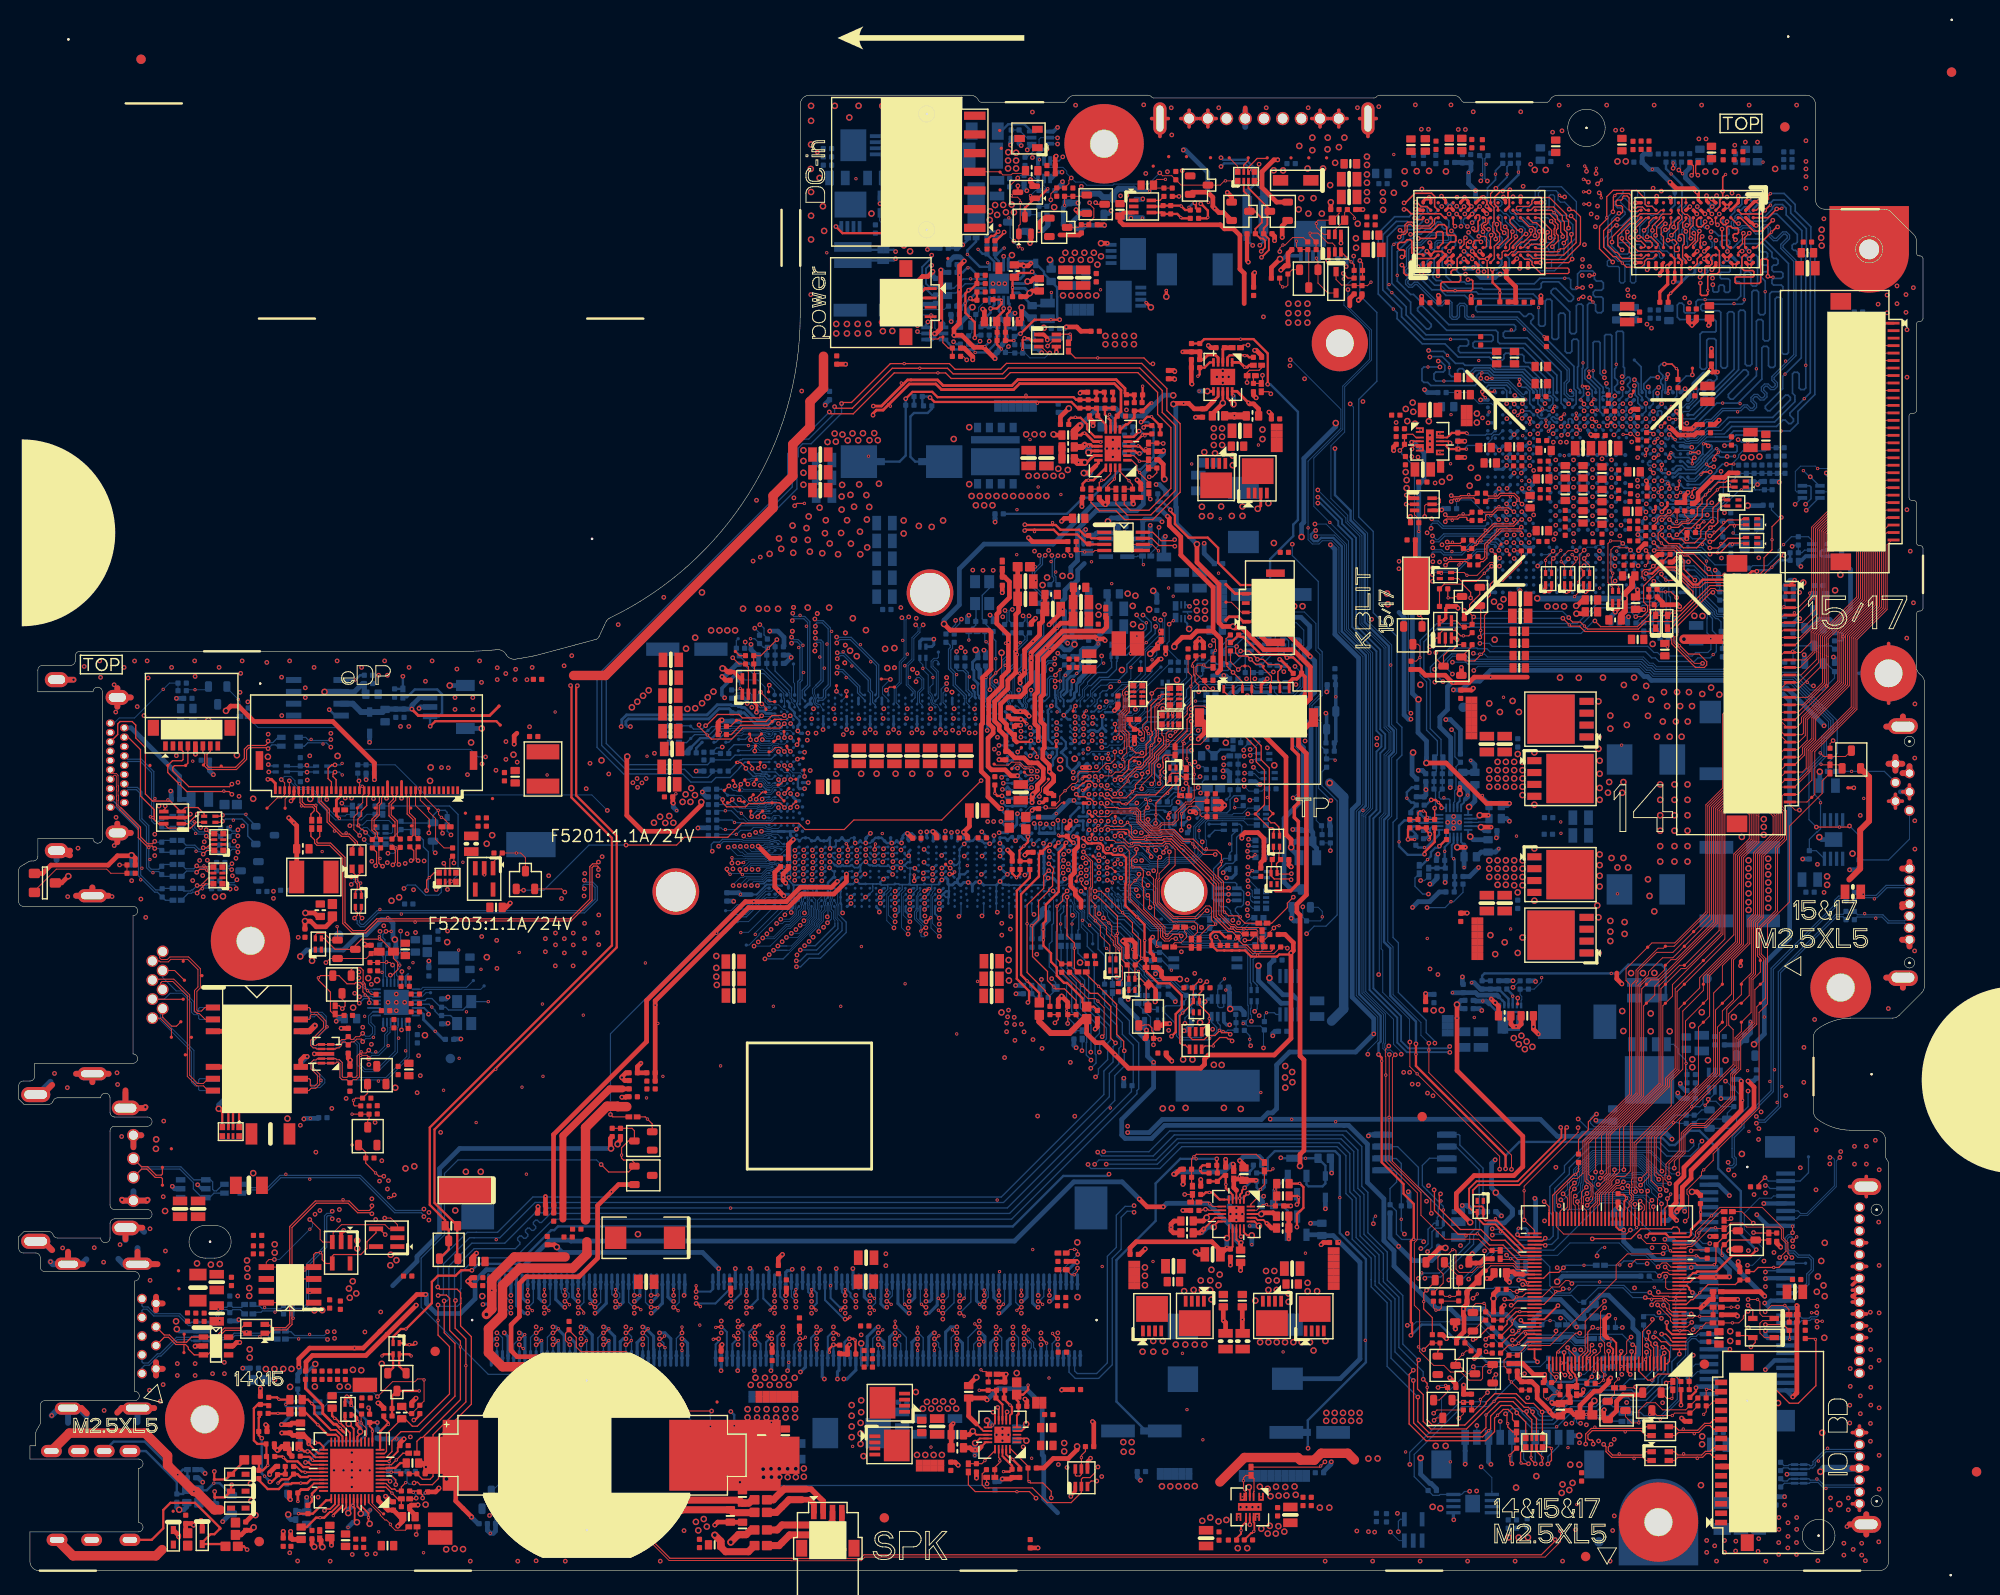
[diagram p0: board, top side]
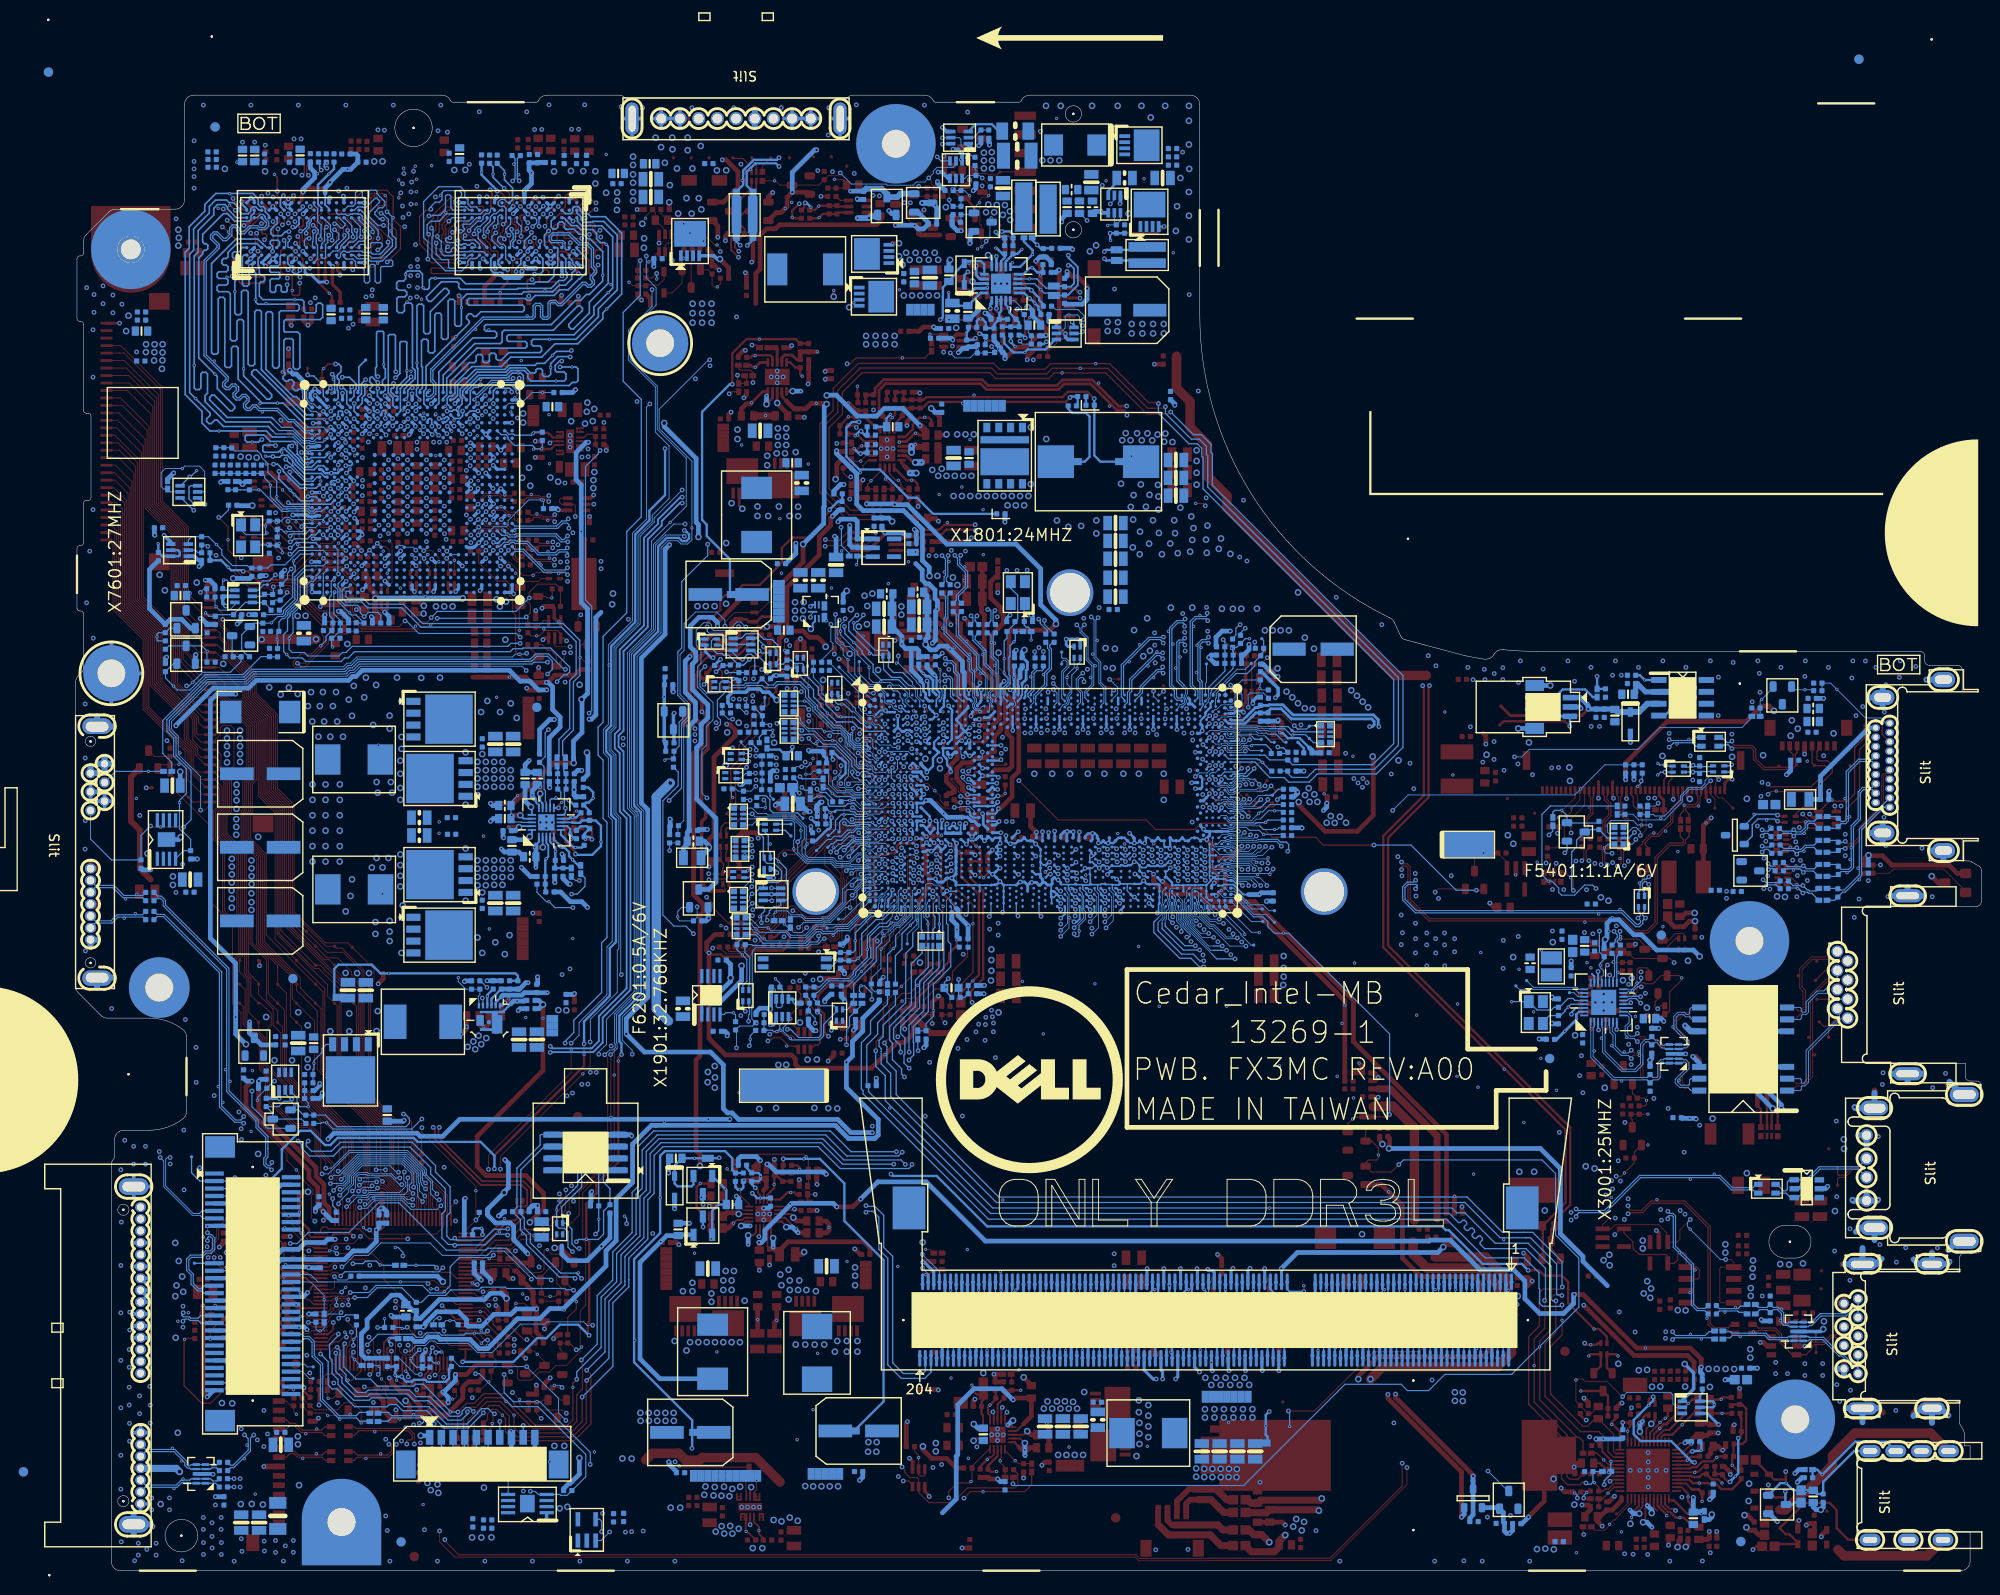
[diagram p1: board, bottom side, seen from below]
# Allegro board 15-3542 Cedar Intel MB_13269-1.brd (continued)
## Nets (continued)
HDMI_DATA0#_R_C: HDMI1.9 R5403.2 R5416.1
HDMI_DATA0_R: C5405.2 R5404.1 RN5403.8(B)
HDMI_DATA0_R_C: HDMI1.7 R5404.2 R5416.2
HDMI_DATA1: C5406.1 CPU1.C58
HDMI_DATA1#: C5409.1 CPU1.B58
HDMI_DATA1#_R: C5409.2 R5407.1 RN5402.5(B)
HDMI_DATA1#_R_C: HDMI1.6 R5407.2 R5417.1
HDMI_DATA1_R: C5406.2 R5408.1 RN5402.6(B)
HDMI_DATA1_R_C: HDMI1.4 R5408.2 R5417.2
HDMI_DATA2: C5408.1 CPU1.C55
HDMI_DATA2#: C5407.1 CPU1.C54
HDMI_DATA2#_R: C5407.2 R5405.1 RN5402.7(B)
HDMI_DATA2#_R_C: HDMI1.3 R5405.2 R5415.1
HDMI_DATA2_R: C5408.2 R5406.1 RN5402.8(B)
HDMI_DATA2_R_C: HDMI1.1 R5406.2 R5415.2
HDMI_HPD_B: Q5401.B R5411.2
HDMI_HPD_E: Q5401.E R5412.1 R5419.2
HDMI_PCH_DET: CPU1.C8 R5419.1
HDMI_PLL_GND: Q5403.D R5418.2 RN5402.1(A) RN5402.2(A) RN5402.3(A) RN5402.4(A) RN5403.1(A) RN5403.2(A) RN5403.3(A) RN5403.4(A)
HPD_HDMI_CON: HDMI1.19 R5410.1 R5411.1
HSIO_OUT: R2114.1 U2101.5 U2101.6 U2101.7
HSIOPC: CPU1.Y2 R2007.1 R2123.1
HSIOPC_R: R2123.2 U2101.9
HVM_CLK: CPU1.R20 TP620.1
HVM_CLK#: CPU1.P20 TP619.1
I2C0_SCL: CPU1.F3 RN2007.2(A)
I2C0_SDA: CPU1.F2 RN2007.1(A)
I2C1_SCL: CPU1.F1 EC6203.1 Q6204.1 RN2008.2(A) RN6203.2(A)
I2C1_SCL_R: AFTP6237.1 Q6204.6 R6204.2 RN6203.3(B) RN6204.4(B) TPAD1.6
I2C1_SDA: CPU1.G4 EC6204.1 Q6204.4 RN2008.1(A) RN6203.1(A)
I2C1_SDA_R: AFTP6240.1 Q6204.3 R6210.2 RN6203.4(B) RN6204.3(B) TPAD1.7
I2CA_SCL: GPU1.B7 RN7603.3(B)
I2CA_SDA: GPU1.A7 RN7603.4(B)
I2CB_SCL: GPU1.C9 RN7605.3(B)
I2CB_SDA: GPU1.C8 RN7605.4(B)
I2CC_SCL: GPU1.A9 RN7604.3(B)
I2CC_SDA: GPU1.B9 RN7604.4(B)
IFPAB_IOVDD: GPU1.W6 GPU1.Y6 RN7402.3(B)
IFPAB_PLLVDD: GPU1.V7 GPU1.W7 RN7402.4(B)
IFPC_IOVDD: GPU1.R6 RN7401.3(B)
IFPC_PLLVDD: GPU1.R7 GPU1.T7 RN7401.4(B)
IFPD_IOVDD: GPU1.P6 RN7404.3(B)
IFPD_PLLVDD: GPU1.M7 GPU1.N7 RN7404.4(B)
IFPEF_IOVDD: GPU1.H6 GPU1.J6 RN7403.3(B)
IFPEF_PLLVDD: GPU1.J7 GPU1.K7 RN7403.4(B)
IMVP_PWRGD: KBC24.107 PR4628.2 R713.1 R4622.2
IMVP_PWRGD_R: CPU1.C59 EC702.1 R710.2 R712.1 R713.2
INT_SERIRQ: CPU1.T4 KBC24.125 RN2002.6(B)
INT_TP#: AFTP6241.1 R1512.1 R2030.1 R2031.1 R2448.1 R2453.1 R6203.1 TPAD1.4
INT_TP#_GPIO8: CPU1.AU2 R2015.2 R2031.2
INT_TP#_GPIO46: CPU1.AG3 R2010.2 R2030.2
INT_TP#_GPIO55: CPU1.U7 R1512.2
INT_TP#_KBC: KBC24.121 R2448.2
ISOLATE#: LOM30.20 R3014.2 R3015.1
ISUM_R_C: PC4707.2 PC4708.2 PC4709.1 PC4710.1 PG4702.1 PR4704.2 PR4705.1 PR4708.2
ISUM_R_R: PC4709.2 PR4706.1
JACK_PLUG: C2902.1 HPMIC1.5 Q2901.G R2905.1 R2923.1
JACK_PLUG_DET: HPMIC1.6 R2914.2 R2916.1
JDREF: HDA27.15 R2707.1
JGND: AFTP3803.1 AFTP3806.1 DCIN1.5 DCIN1.6 DCIN1.7 EC4201.2 EC4202.2 EL4203.1
KB_BL_CTRL: KBC24.22 Q6202.G R6208.1
KB_BL_CTRL#: AFTP6247.1 KBLIT1.4 Q6202.D
KB_DET#: AFTP6202.1 CPU1.K2 KB1.30 KB2.30 RN2002.5(B)
KB_LED_BL_DET: CPU1.J1 R6206.1 R6207.1
KB_LED_DET_C: AFTP6246.1 C6203.1 KBLIT1.2 R6206.2
KBC_BEEP: KBC24.118 RN2701.1(A)
KBC_BEEP_R: D2701.1 RN2701.4(B)
KBC_DPWROK: EC1705.1 KBC24.81 R1718.2 R1725.2
KBC_ON#_GATE: C2417.1 Q2402.G Q2403.G R2433.2
KBC_ON#_GATE_L: R2431.1 R2432.2 R2433.1
KBC_PWRBTN#: R2427.1 R6102.1
KBC_PWRBTN#_C: AFTP6801.1 EC6104.1 R6102.2 SW1.4
KBC_VCORF: C2416.1 KBC24.44
KCOL0: AFTP6207.1 KB1.13 KB2.13 KBC24.53
KCOL1: AFTP6206.1 KB1.15 KB2.15 KBC24.52
KCOL2: AFTP6226.1 KB1.14 KB2.14 KBC24.51
KCOL3: AFTP6208.1 KB1.16 KB2.16 KBC24.50
KCOL4: AFTP6224.1 KB1.20 KB2.20 KBC24.49
KCOL5: AFTP6215.1 KB1.21 KB2.21 KBC24.48
KCOL6: AFTP6223.1 KB1.18 KB2.18 KBC24.47
KCOL7: AFTP6213.1 KB1.19 KB2.19 KBC24.43
KCOL8: AFTP6231.1 KB1.17 KB2.17 KBC24.42
KCOL9: AFTP6219.1 KB1.7 KB2.7 KBC24.41
KCOL10: AFTP6232.1 KB1.5 KB2.5 KBC24.40
KCOL11: AFTP6220.1 KB1.6 KB2.6 KBC24.39
KCOL12: AFTP6233.1 KB1.12 KB2.12 KBC24.38
KCOL13: AFTP6203.1 KB1.9 KB2.9 KBC24.37
KCOL14: AFTP6216.1 KB1.8 KB2.8 KBC24.36
KCOL15: AFTP6229.1 KB1.10 KB2.10 KBC24.35
KCOL16: AFTP6225.1 KB1.11 KB2.11 KBC24.34
KROW0: AFTP6228.1 KB1.22 KB2.22 KBC24.54
KROW1: AFTP6227.1 KB1.24 KB2.24 KBC24.55
KROW2: AFTP6218.1 KB1.26 KB2.26 KBC24.56
KROW3: AFTP6234.1 KB1.23 KB2.23 KBC24.57
KROW4: AFTP6230.1 KB1.27 KB2.27 KBC24.58
KROW5: AFTP6214.1 KB1.25 KB2.25 KBC24.59
KROW6: AFTP6222.1 KB1.28 KB2.28 KBC24.60
KROW7: AFTP6221.1 KB1.29 KB2.29 KBC24.61
L_BKLT_CTRL: CPU1.B8 R5206.1
L_BKLT_EN: CPU1.A9 R2444.1
L_BKLT_EN_EC: KBC24.9 R2444.2 R2447.1
LAN_ENABLE_R_C: Q3001.D R3021.2 R3022.1
LAN_MDI0N: EC3102.2 LOM30.2 U3101.2 U3101.9 XF3101.11
LAN_MDI0P: EC3101.2 LOM30.1 U3101.1 U3101.10 XF3101.12
LAN_MDI1N: EC3104.2 LOM30.5 U3101.5 U3101.6 XF3101.7
LAN_MDI1P: EC3103.2 LOM30.4 U3101.4 U3101.7 XF3101.8
LAN_MDI2N: EC3106.2 LOM30.7 U3102.2 U3102.9 XF3102.8
LAN_MDI2P: EC3105.2 LOM30.6 U3102.1 U3102.10 XF3102.7
LAN_MDI3N: EC3108.2 LOM30.10 U3102.5 U3102.6 XF3102.12
LAN_MDI3P: EC3107.2 LOM30.9 U3102.4 U3102.7 XF3102.11
LAN_TXN_C_PCH_RXN4: C3016.1 LOM30.18
LAN_TXP_C_PCH_RXP4: C3014.1 LOM30.17
LANXIN: C3001.1 LOM30.28 X3001.1
LANXOUT: C3011.1 LOM30.29 X3001.3
LCD_BRIGHTNESS: AFTP5203.1 LCD1.20 RN5201.2(A)
LCD_TST: R2417.1 RN5201.8(B)
LCD_TST_C: AFTP5207.1 LCD1.10 RN5201.1(A)
LCD_TST_EN: D5201.2 KBC24.28 R2417.2
LCDVDD: R5211.2 U5201.3
LCDVDD_EN: D5201.3 R5202.2 U5201.1
LCDVDD_LCD: AFTP5202.1 C5201.1 C5206.2 LCD1.4 LCD1.5 LCD1.6 LCD1.7 R5211.1
LDO1_CAP: C2702.2 HDA27.27 R2711.2
LDO2_CAP: C2712.2 HDA27.39
LDO3_CAP: C2718.1 HDA27.7
LED0: LOM30.27 TP3003.1
LED1: LOM30.26 TP3002.1
LED2: LOM30.25 TP3001.1
LID_CLOSE#: C6401.1 D2401.K D2402.K KBC24.17 LIDSW1.3 R2421.1 R6401.1
LINE1-L_C: C2907.2 R2922.1
LINE1-L_R: C2908.2 R2921.1
LINE1_L: C2907.1 HDA27.22
LINE1_R: C2908.1 HDA27.21
LINE1_VREFO_L: HDA27.31 R2912.1
LINE1_VREFO_R: HDA27.30 R2913.1
LOM_TCT: C3106.1 XF3101.9 XF3101.10 XF3102.9 XF3102.10
LPC_AD0: KBC24.126 RN1806.5(B) RN6501.1(A)
LPC_AD1: KBC24.127 RN1806.7(B) RN6501.2(A)
LPC_AD2: KBC24.128 RN1806.8(B) RN6501.3(A)
LPC_AD3: KBC24.1 RN1806.6(B) RN6501.4(A)
LPC_FRAME#: KBC24.3 R1801.1 R6501.1
LPC_FRAME#_DEBUG: DB1.6 R6501.2
LPC_LAD0_PCH: CPU1.AU14 RN1806.4(A)
LPC_LAD0_R: DB1.2 RN6501.8(B)
LPC_LAD1_PCH: CPU1.AW12 RN1806.2(A)
LPC_LAD1_R: DB1.3 RN6501.7(B)
LPC_LAD2_PCH: CPU1.AY12 RN1806.1(A)
LPC_LAD2_R: DB1.4 RN6501.6(B)
LPC_LAD3_PCH: CPU1.AW11 RN1806.3(A)
LPC_LAD3_R: DB1.5 RN6501.5(B)
LPC_LFRAME#_PCH: CPU1.AV12 R1801.2
LPSS_GSPI0_MOSI_BBS0_R: CPU1.L8 R2012.2
LPSS_SDIO_D0_CMNHDR: CPU1.D3 R2011.2
M_A_A0: CPU1.AU36 DM1.98
M_A_A1: CPU1.AY37 DM1.97
M_A_A2: CPU1.AR38 DM1.96
M_A_A3: CPU1.AP36 DM1.95
M_A_A4: CPU1.AU39 DM1.92
M_A_A5: CPU1.AR36 DM1.91
M_A_A6: CPU1.AV40 DM1.90
M_A_A7: CPU1.AW39 DM1.86
M_A_A8: CPU1.AY39 DM1.89
M_A_A9: CPU1.AU40 DM1.85
M_A_A10: CPU1.AP35 DM1.107
M_A_A11: CPU1.AW41 DM1.84
M_A_A12: CPU1.AU41 DM1.83
M_A_A13: CPU1.AR35 DM1.119
M_A_A14: CPU1.AV42 DM1.80
M_A_A15: CPU1.AU42 DM1.78
M_A_B_DIMM_ODT: Q1202.S R1206.1 R1207.1
M_A_BS0: CPU1.AU35 DM1.109
M_A_BS1: CPU1.AV35 DM1.108
M_A_BS2: CPU1.AY41 DM1.79
M_A_CAS#: CPU1.AU34 DM1.115
M_A_DIMA_CKE0: CPU1.AU43 DM1.73
M_A_DIMA_CKE1: CPU1.AW43 DM1.74
M_A_DIMA_CLK_DDR0: CPU1.AV37 DM1.101
M_A_DIMA_CLK_DDR1: CPU1.AY36 DM1.102
M_A_DIMA_CLK_DDR#0: CPU1.AU37 DM1.103
M_A_DIMA_CLK_DDR#1: CPU1.AW36 DM1.104
M_A_DIMA_CS#0: CPU1.AP33 DM1.114
M_A_DIMA_CS#1: CPU1.AR32 DM1.121
M_A_DIMA_ODT0: DM1.116 R1206.2
M_A_DIMA_ODT1: DM1.120 R1207.2
M_A_DQ0: CPU1.AH63 DM1.129
M_A_DQ1: CPU1.AH62 DM1.131
M_A_DQ2: CPU1.AK63 DM1.141
M_A_DQ3: CPU1.AK62 DM1.140
M_A_DQ4: CPU1.AH61 DM1.132
M_A_DQ5: CPU1.AH60 DM1.130
M_A_DQ6: CPU1.AK61 DM1.143
M_A_DQ7: CPU1.AK60 DM1.142
M_A_DQ8: CPU1.AM63 DM1.7
M_A_DQ9: CPU1.AM62 DM1.4
M_A_DQ10: CPU1.AP63 DM1.17
M_A_DQ11: CPU1.AP62 DM1.18
M_A_DQ12: CPU1.AM61 DM1.6
M_A_DQ13: CPU1.AM60 DM1.5
M_A_DQ14: CPU1.AP61 DM1.15
M_A_DQ15: CPU1.AP60 DM1.16
M_A_DQ16: CPU1.AP58 DM1.159
M_A_DQ17: CPU1.AR58 DM1.157
M_A_DQ18: CPU1.AM57 DM1.146
M_A_DQ19: CPU1.AK57 DM1.148
M_A_DQ20: CPU1.AL58 DM1.149
M_A_DQ21: CPU1.AK58 DM1.147
M_A_DQ22: CPU1.AR57 DM1.158
M_A_DQ23: CPU1.AN57 DM1.160
M_A_DQ24: CPU1.AP55 DM1.24
M_A_DQ25: CPU1.AR55 DM1.22
M_A_DQ26: CPU1.AM54 DM1.36
M_A_DQ27: CPU1.AK54 DM1.34
M_A_DQ28: CPU1.AL55 DM1.23
M_A_DQ29: CPU1.AK55 DM1.21
M_A_DQ30: CPU1.AR54 DM1.33
M_A_DQ31: CPU1.AN54 DM1.35
M_A_DQ32: CPU1.AY58 DM1.166
M_A_DQ33: CPU1.AW58 DM1.165
M_A_DQ34: CPU1.AY56 DM1.175
M_A_DQ35: CPU1.AW56 DM1.174
M_A_DQ36: CPU1.AV58 DM1.163
M_A_DQ37: CPU1.AU58 DM1.164
M_A_DQ38: CPU1.AV56 DM1.177
M_A_DQ39: CPU1.AU56 DM1.176
M_A_DQ40: CPU1.AY54 DM1.42
M_A_DQ41: CPU1.AW54 DM1.41
M_A_DQ42: CPU1.AY52 DM1.50
M_A_DQ43: CPU1.AW52 DM1.51
M_A_DQ44: CPU1.AV54 DM1.39
M_A_DQ45: CPU1.AU54 DM1.40
M_A_DQ46: CPU1.AV52 DM1.52
M_A_DQ47: CPU1.AU52 DM1.53
M_A_DQ48: CPU1.AK40 DM1.69
M_A_DQ49: CPU1.AK42 DM1.67
M_A_DQ50: CPU1.AM43 DM1.59
M_A_DQ51: CPU1.AM45 DM1.57
M_A_DQ52: CPU1.AK45 DM1.56
M_A_DQ53: CPU1.AK43 DM1.58
M_A_DQ54: CPU1.AM40 DM1.68
M_A_DQ55: CPU1.AM42 DM1.70
M_A_DQ56: CPU1.AM46 DM1.192
M_A_DQ57: CPU1.AK46 DM1.194
M_A_DQ58: CPU1.AM49 DM1.183
M_A_DQ59: CPU1.AK49 DM1.182
M_A_DQ60: CPU1.AM48 DM1.191
M_A_DQ61: CPU1.AK48 DM1.193
M_A_DQ62: CPU1.AM51 DM1.181
M_A_DQ63: CPU1.AK51 DM1.180
M_A_DQS0: CPU1.AJ62 DM1.137
M_A_DQS1: CPU1.AN61 DM1.12
M_A_DQS2: CPU1.AN58 DM1.154
M_A_DQS3: CPU1.AN55 DM1.29
M_A_DQS4: CPU1.AW57 DM1.171
M_A_DQS5: CPU1.AW53 DM1.47
M_A_DQS6: CPU1.AL42 DM1.64
M_A_DQS7: CPU1.AL49 DM1.188
M_A_DQS#0: CPU1.AJ61 DM1.135
M_A_DQS#1: CPU1.AN62 DM1.10
M_A_DQS#2: CPU1.AM58 DM1.152
M_A_DQS#3: CPU1.AM55 DM1.27
M_A_DQS#4: CPU1.AV57 DM1.169
M_A_DQS#5: CPU1.AV53 DM1.45
M_A_DQS#6: CPU1.AL43 DM1.62
M_A_DQS#7: CPU1.AL48 DM1.186
M_A_RAS#: CPU1.AY34 DM1.110
M_A_WE#: CPU1.AW34 DM1.113
M_VREF_CA_DIMMA: C1201.1 C1202.1 C1218.1 DM1.126 R3703.1 R3704.2 R3706.2 R3708.1
M_VREF_DQ_DIMMA: C1204.1 C1205.1 C1206.1 DM1.1 R3701.2 R3702.2 R3709.1 R3710.2
MCP_GPIO11: CPU1.AN2 RN1809.5(B)
MCP_GPIO12: CPU1.AM7 RN1701.4(B)
MCP_GPIO13: CPU1.AT3 R2020.2
MCP_GPIO14: CPU1.AH4 R2016.2
MCP_GPIO15: CPU1.AD6 R2014.2
MCP_GPIO26: CPU1.AN3 R2009.2
MCP_GPIO27: CPU1.AN5 RN2006.3(B)
MCP_GPIO28: CPU1.AD7 R2017.2
MCP_GPIO36: CPU1.V6 RN1902.4(A)
MCP_GPIO44: CPU1.AK4 R2002.2
MCP_GPIO56: CPU1.AG6 R2004.2
MCP_GPIO57: CPU1.AP1 R2022.2
MCP_GPIO58: CPU1.AL4 R2001.2
MCP_GPIO73: CPU1.AU4 RN1601.6(B)
MCP_GPIO76: CPU1.P1 RN1801.8(B)
MCP_R: R2001.1 R2002.1 R2004.1 R2009.1 R2013.1 R2016.1 R2017.1 R2020.1 R2022.1
MCP_TESTLOW1: CPU1.C35 RN1803.4(B)
MCP_TESTLOW2: CPU1.C34 RN1803.3(B)
MCP_TESTLOW3: CPU1.AK8 RN1804.3(B)
MCP_TESTLOW4: CPU1.AL8 RN1804.4(B)
MCT: C3101.1 RN3101.5(B) RN3101.6(B) RN3101.7(B) RN3101.8(B)
MCT0: RN3101.1(A) XF3102.3
MCT1: RN3101.2(A) XF3102.4
MCT2: RN3101.3(A) XF3101.4
MCT3: RN3101.4(A) XF3101.3
MDO0+: AFTP3107.1 RJ45.1 XF3101.1
MDO0-: AFTP3102.1 RJ45.2 XF3101.2
MDO1+: AFTP3101.1 RJ45.3 XF3101.5
MDO1-: AFTP3106.1 RJ45.6 XF3101.6
MDO2+: AFTP3103.1 RJ45.4 XF3102.6
MDO2-: AFTP3104.1 RJ45.5 XF3102.5
MDO3+: AFTP3105.1 RJ45.7 XF3102.2
MDO3-: AFTP3108.1 RJ45.8 XF3102.1
ME_UNLOCK: KBC24.23 R1909.1
MIC2_VREFO: HDA27.29 RN2901.1(A) RN2901.2(A)
MIC_CAP: C2713.1 HDA27.19
MIC_GND: LCD1.26 R5201.1
MODEL_ID_DET: C2403.2 KBC24.94 R2405.2 R2407.1 R2445.2 R2446.2
MPWROK: CPU1.AB5 R1707.2
MUTE_CTRL: C2901.1 R2917.2 R2918.2 U2901.2
N12P_JTAG_TCK: GPU1.AE5 RN7602.4(B)
N12P_JTAG_TDI: GPU1.AE6 TP7605.1
N12P_JTAG_TDO: GPU1.AF6 TP7601.1
N12P_JTAG_TMS: GPU1.AD6 TP7602.1
N12P_JTAG_TRST: GPU1.AG4 RN7602.3(B)
N12P_XTAL_OUTBUFF: GPU1.C10 R7602.1 R7617.2
NCT7718_DXN: C2606.2 C2607.2 Q2603.E THM26.3
NCT7718_DXP: C2606.1 C2607.1 Q2603.B Q2603.C THM26.2
ODD_PWR_5V: C5610.1 ODD1.2 ODD1.3 R5603.2 U5601.6 U5601.7 U5601.8
OVER_CURRENT_P8#: D7602.K KBC24.95
OVERT#: C7609.1 Q7602.4 R7613.2 R7645.2 R7652.1
OVERT_GPU#: GPU1.A6 R7652.2
P2800_VGA_DXN: GPU1.E12 TP7603.1
P2800_VGA_DXP: GPU1.F12 TP7604.1
P_H_S#: Q7602.3 R7653.1
PANEL_SIZE_ID: CPU1.J2 R5208.2 R5209.1 R5210.2
PANEL_SIZE_ID_CONN: LCD1.22 R5210.1
PBAT_PRES1#: AFTP3902.1 BAT1.5 RN4301.8(B)
PBAT_SMBCLK1: AFTP3904.1 BAT1.3 RN4301.6(B)
PBAT_SMBDAT1: AFTP3903.1 BAT1.4 RN4301.7(B)
PCB_VER_AD: C2402.2 KBC24.98 R2404.2 R2406.1
PCH_DPWROK: CPU1.AV5 R1704.1 R1718.1
PCH_HDMI_CLK: CPU1.B9 Q5402.4 RN1501.4(B)
PCH_HDMI_DATA: CPU1.C9 Q5402.1 RN1501.3(B)
PCH_INTVRMEN: CPU1.AV7 R1903.2 R1913.2
PCH_JTAG_TCK: CPU1.AE62 R1920.2
PCH_JTAG_TDI: CPU1.AD61 R1916.1
PCH_JTAG_TDO: CPU1.AE61 R1917.1
PCH_JTAG_TMS: CPU1.AD62 R1918.1
PCH_JTAG_TRST#: CPU1.AU62 TP1901.1
PCH_OPIRCOMP: CPU1.AW15 R2003.1
PCH_PWROK: EC1704.1 KBC24.100 Q2602.G Q3601.3 R1706.1
PCH_SLP_S0#: CPU1.AF3 TP1706.1
PCH_SLP_WLAN#: CPU1.AM5 TP1705.1
PCH_SMBCLK: DM1.202 EC6206.1 Q1801.4 R6204.1 RN1810.3(B) RN9601.2(A)
PCH_SMBDATA: DM1.200 EC6205.1 Q1801.1 R6210.1 RN1810.4(B) RN9601.1(A)
PCH_SPI_CLK: CPU1.AA3 R1806.2
PCH_SPI_CS0#: CPU1.Y7 R1807.2
PCH_SPI_DQ2: CPU1.Y6 R1811.2 RN1802.3(B)
PCH_SPI_DQ3: CPU1.AF1 R1812.2 RN1802.4(B)
PCH_SPI_SI: CPU1.AA2 R1808.2
PCH_SPI_SO: CPU1.AA4 R1809.2
PCH_THERMTRIP: CPU1.D60 R2018.2 R2027.1
PCH_VCCDSW_R: C2114.1 R2110.2
PCH_WAKE#: CPU1.AJ5 R1703.2 R1705.1
PCI_PLTRST#: CPU1.AG7 R1713.2
PCI_PME#: CPU1.AD4 TP1501.1
PCIE_CLK_XDP_N: CPU1.B35 TP9651.1
PCIE_CLK_XDP_P: CPU1.A35 TP9652.1
PCIE_PRX_LANTX_N4: C3016.2 CPU1.F13
PCIE_PRX_LANTX_P4: C3014.2 CPU1.G13
PCIE_PRX_WLANTX_N3: CPU1.G11 WLAN1.23
PCIE_PRX_WLANTX_P3: CPU1.F11 WLAN1.25
PCIE_PTX_LANRX_N4: C1603.2 CPU1.B29
PCIE_PTX_LANRX_N4_C: C1603.1 LOM30.14
PCIE_PTX_LANRX_P4: C1604.2 CPU1.A29
PCIE_PTX_LANRX_P4_C: C1604.1 LOM30.13
PCIE_PTX_WLANRX_N3: C1601.2 CPU1.C29
PCIE_PTX_WLANRX_N3_C: C1601.1 WLAN1.31
PCIE_PTX_WLANRX_P3: C1602.2 CPU1.B30
PCIE_PTX_WLANRX_P3_C: C1602.1 WLAN1.33
PCIE_RCOMP: CPU1.A27 R1601.2
PCIE_WAKE#: KBC24.113 LOM30.21 R1705.2 R3033.1
PD4403_A: PD4404.A PQ4409.B
PD4403_K: PD4404.K PR4468.2 PR4471.1
PECI: C2422.1 KBC24.13 R2429.1
PEG_CLKREQ#: CPU1.U5 Q7301.D R7305.1 RN1801.7(B)
PEX_TERMP: GPU1.AF25 R7301.1
PEXTSTCLK_OUT: GPU1.AF22 R7307.1
PEXTSTCLK_OUT#: GPU1.AE22 R7307.2
PHASE1G: PG4701.1 PR4702.1
PHASE_R_R: PR4703.2 PR4704.1
PIRQA#: CPU1.U6 RN2011.7(B)
PIRQB#: CPU1.P4 RN1505.5(B)
PIRQC#: CPU1.N4 RN1505.8(B)
PIRQD#: CPU1.N2 RN1505.7(B)
PLT_RST#: C1701.1 EC1703.1 Q3003.E R1713.1 R1715.1 R2416.2 R3016.1 R3606.1 R5212.2 R6502.1 R9602.2 U7301.2 WLAN1.22
PLT_RST#_DEBUG: DB1.7 R6502.2
PLT_RST#_EC: C2415.2 KBC24.7 R2416.1
PLT_RST#_LAN: LOM30.19 Q3003.C R3016.2 RN3001.3(B)
PM_CLKRUN#: CPU1.V5 R1709.1 R1714.1
PM_CLKRUN#_EC: KBC24.8 R1709.2
PM_LAN_ENABLE: KBC24.119 Q3001.G R3023.1
PM_LAN_ENABLE_R: C3015.2 Q3004.G R3022.2
PM_PCH_PWROK: CPU1.AY7 R1706.2 R1707.1 RN1703.3(B)
PM_PWRBTN#: CPU1.AL7 KBC24.117 R9603.1
PM_RSMRST#: CPU1.AW6 Q1701.3 R1702.1 R1704.2 RN1703.4(B)
PM_SLP_A#: CPU1.AL5 TP1704.1
PM_SLP_LAN#: CPU1.AJ7 TP1707.1
PM_SLP_S3#: CPU1.AT4 KBC24.64 PR4819.1 PR5110.1 Q3601.2 R3609.1 R4910.2
PM_SLP_S4#: CPU1.AJ6 KBC24.21 PR4907.1
PM_SLP_S5#: CPU1.AP5 TP1703.1
PM_SLP_SUS#: CPU1.AP4 KBC24.108 R1729.2 R3802.1
PM_SUS_STAT#: CPU1.AG4 R1724.2 TP1702.1
PM_SUSACK#: KBC24.91 RN1702.2(A)
PM_SUSACK#_R: CPU1.AK2 R1708.2 RN1702.3(B)
PM_SUSWARN#: KBC24.79 RN1702.1(A)
PM_SUSWARN#_R: CPU1.AV4 R1708.1 RN1601.5(B) RN1702.4(B)
PQ3802_1: PQ4202.B PR4202.1 PR4209.2
PQ3808D: PC4208.2 PQ4208.D
PQ3808G: PC4209.1 PQ4208.G PR4215.1
PQ3809_D: PQ4206.3 PR4214.2
PQ4008_2: PC4425.1 PQ4408.2 PR4437.2
PQ4008_6: PQ4408.6 PR4426.1
PQ4203_5: PC4210.1 PQ4203.5 PR4218.1
PQ4405_2: PQ4410.2 PR4475.2 PR4476.2
PQ4405_3: PQ4410.3 PR4466.1
PQ4405_5: PC4434.1 PQ4410.5 PR4470.2
PQ4405_6: PC4434.2 PQ4410.6 PR4473.1
PQ4406_D: PQ4414.D PR4465.2
PQ4406_G: PC4433.2 PQ4414.G PR4474.1
PQ4408_C: PQ4409.C PR4464.1 PR4475.1
PQ4408_E: PQ4409.E PR4467.1 PR4469.2
PR4601_1: PR4901.2 PR4906.1
PR4605_2: PC4919.1 PR4905.2
PROC_OPI_COMP: CPU1.AY15 R602.1
PROC_OPI_COMP3: CPU1.Y22 R606.1
PROCHOT_EC: KBC24.24 Q2401.G R2438.1 R2442.1
PS_ID: PQ4201.S PR4205.1 PR4206.2
PS_ID_R: AFTP3802.1 DCIN1.4 PR4217.1
PS_ID_R2: PD4204.1 PD4204.2 PQ4201.D PR4206.1 PR4209.1 PR4217.2
PS_S3CNTRL: Q3601.5 Q3601.6 R3607.2
PSID_DISABLE#_R_C: PQ4201.G PQ4202.C PR4203.2
PSID_EC: KBC24.99 PD4203.3 PR4204.2 PR4205.2
PSL_IN1#: KBC24.73 R2430.2
PSL_IN2#: KBC24.93 R2425.1 R2427.2
PSL_OUT#: KBC24.74 R2432.1
PU4401_4: PC4424.2 PR4410.2 PR4454.2 PU4407.4
PU4401_5: PC4424.1 PR4410.1 PR4448.2 PU4407.5
PU4401_6: PR4446.2 PU4407.6
PU5102_PG: PU5102.2 TP5101.1
PURE_HW_SHUTDOWN#: C2610.1 C7610.1 D3602.3 Q2404.B Q2602.D Q3602.C R2424.1 R2439.2 R2612.1 R7653.2
PWR_1D05V_BOOT: PR4820.1 PU4806.10
PWR_1D05V_BOOT_R: PC4822.2 PR4820.2
PWR_1D05V_CCM: PR4824.1 PU4806.5
PWR_1D05V_EN: PC4821.1 PR4819.2 PU4806.3
PWR_1D5V_EN: PR5110.2 PU5101.3
PWR_1D05V_FB: PC4823.2 PR4822.2 PR4823.1 PU4806.4
PWR_1D05V_LGATE: PU4805.4 PU4806.6
PWR_1D05V_PHASE: PC4822.1 PL4801.1 PR4837.1 PU4805.5 PU4805.6 PU4805.7 PU4805.8 PU4806.8 PU4808.1 PU4808.2 PU4808.3
PWR_1D05V_PWR: PC4823.1 PG4832.1 PR4822.1
PWR_1D05V_PWRGD: PR4821.1 PU4806.1
PWR_1D05V_SNUB: PC4838.1 PR4837.2
PWR_1D05V_TRIP: PR4817.2 PU4806.2
PWR_1D05V_UGATE: PU4806.9 PU4808.4
PWR_1D35V_DRVH: PU4901.14 PU4902.4
PWR_1D35V_DRVL: PU4901.11 PU4903.4
PWR_1D35V_EN: PC4906.1 PR4907.2 PU4901.16
PWR_1D35V_MODE: PR4908.2 PU4901.19
PWR_1D35V_REFIN: PC4902.1 PR4901.1 PR4903.2 PU4901.8
PWR_1D35V_SW: PC4919.2 PL4902.1 PR4912.1 PU4901.13 PU4902.1 PU4902.2 PU4902.3 PU4903.5 PU4903.6 PU4903.7 PU4903.8
PWR_1D35V_TRIP: PR4902.1 PU4901.18
PWR_1D35V_VBST: PR4905.1 PU4901.15
PWR_1D35V_VDDQS: PG4907.1 PU4901.9
PWR_1D35V_VREF: PC4903.1 PR4903.1 PU4901.6
PWR_1D35V_VTTREF: PC4918.1 PR4911.1 PU4901.5
PWR_3D3V_CS2: PR4517.1 PU4503.5
PWR_3D3V_DRVH2: PU4503.10 PU4504.4
PWR_3D3V_DRVL2: PU4503.11 PU4505.4
PWR_3D3V_EN2: PR4506.2 PU4503.6
PWR_3D3V_FB2: PC4523.2 PR4512.2 PR4523.1 PU4503.4
PWR_3D3V_FB2_R: PC4523.1 PR4535.2
PWR_3D3V_LL2: PC4535.2 PL4502.2 PR4533.1 PU4503.8 PU4504.1 PU4504.2 PU4504.3 PU4505.5 PU4505.6 PU4505.7 PU4505.8
PWR_3D3V_SNUB: PC4520.1 PR4533.2
PWR_3D3V_VBST2: PR4528.2 PU4503.9
PWR_3D3V_VBST2_1: PC4535.1 PR4528.1
PWR_5V_CS1: PR4531.1 PU4503.1
PWR_5V_DRVH1: PU4501.4 PU4503.16
PWR_5V_DRVL1: PU4502.4 PU4503.15
PWR_5V_EN1: PR4504.2 PU4503.20
PWR_5V_EN1_R: PR4501.2 PR4504.1 PR4507.2 PR4530.1
PWR_5V_FB1: PC4522.2 PR4526.1 PR4527.2 PU4503.2
PWR_5V_FB1_R: PC4522.1 PR4525.2
PWR_5V_LL1: PC4516.2 PL4501.1 PR4529.1 PU4501.1 PU4501.2 PU4501.3 PU4502.5 PU4502.6 PU4502.7 PU4502.8 PU4503.18
PWR_5V_SNUB: PC4536.1 PR4529.2
PWR_5V_VBST1: PR4524.1 PU4503.17
PWR_5V_VBST1_1: PC4516.1 PR4524.2
PWR_5V_VCLK: PC4514.1 PC4521.1 PC4532.1 PU4503.19
PWR_5V_VO1: PG4532.2 PR4525.1 PR4527.1 PU4503.14
PWR_CHG_ACDET: PC4412.1 PR4407.2 PR4431.1 PU4404.6
PWR_CHG_ACN: PC4402.2 PC4403.1 PG4403.2 PR4406.1 PU4404.1
PWR_CHG_ACOK: PQ4402.2 PQ4408.3 PR4419.2 PR4428.2 PR4436.1 PR4476.1
PWR_CHG_ACP: PC4402.1 PC4404.1 PG4402.2 PR4406.2 PU4404.2
PWR_CHG_AD_OFF: KBC24.11 PQ4206.5 PR4210.1
PWR_CHG_AD_OFF_R: PQ4203.6 PQ4204.B PR4210.2 PR4211.1
PWR_CHG_BAT_SCL: PG4407.1 PU4404.9
PWR_CHG_BAT_SDA: PG4408.1 PU4404.8
PWR_CHG_BTST: PR4409.1 PU4404.17
PWR_CHG_BTST_R: PC4411.1 PD4401.K PR4409.2
PWR_CHG_CMPIN: PR4411.2 PR4413.1 PR4414.2 PR4427.2 PR4429.1 PU4404.4
PWR_CHG_CMPIN_R: PQ4407.3 PR4429.2
PWR_CHG_CMPIN_RR: PQ4407.6 PR4427.1
PWR_CHG_CMPOUT: PR4414.1 PR4430.2 PR4432.1 PR4437.1 PR4438.1 PU4404.3
PWR_CHG_CSON_1: PC4421.2 PC4423.1 PG4410.1 PR4420.2
PWR_CHG_CSOP_1: PC4420.1 PC4421.1 PG4409.1 PR4421.2
PWR_CHG_HIDRV: PC4413.2 PU4404.18 PU4405.4
PWR_CHG_IFAULT: PR4418.2 PU4404.11
PWR_CHG_ILIM: PR4417.2 PR4423.1 PU4404.10
PWR_CHG_IOUT: PC4422.1 PR4411.1 PR4422.1 PR4424.1 PU4404.7
PWR_CHG_LODRV: PU4404.15 PU4406.4
PWR_CHG_PHASE: PC4411.2 PC4413.1 PL4401.1 PU4404.19 PU4405.1 PU4405.2 PU4405.3 PU4406.5 PU4406.6 PU4406.7 PU4406.8
PWR_CHG_REGN: PC4407.1 PD4401.A PR4425.1 PR4428.1 PR4430.1 PU4404.16
PWR_CHG_SRN: PR4420.1 PU4404.12
PWR_CHG_SRP: PR4421.1 PU4404.13
PWR_CHG_VCC: PC4010.1 PR4408.2 PU4404.20
PWR_DCBATOUT_1D05V: PC4814.1 PC4825.1 PC4826.1 PG4827.1 PG4834.1 PG4837.1 PG4838.1 PU4808.5 PU4808.6 PU4808.7 PU4808.8
PWR_DCBATOUT_3D3V: PC4509.1 PC4525.1 PC4528.1 PG4521.1 PG4524.1 PG4525.1 PG4531.1 PU4504.5 PU4504.6 PU4504.7 PU4504.8
PWR_DCBATOUT_5V: PC4527.1 PC4529.1 PC4530.1 PG4518.1 PG4520.1 PG4534.1 PG4536.1 PG4542.1 PG4543.1 PU4501.5 PU4501.6 PU4501.7 PU4501.8
PWR_DCBATOUT_VCCCORE: PC4701.1 PC4702.1 PC4703.1 PC4704.1 PG4703.2 PG4704.2 PG4705.2 PG4706.2 PG4707.2 PG4708.2 PU4701.2 PU4701.3 PU4701.4 PU4701.10
PWR_DCBATOUT_VGA_CORE1: PC8208.1 PC8209.1 PC8210.1 PC8214.1 PC8220.2 PG8207.2 PG8208.2 PG8209.2 PG8210.2 PG8211.2 PG8212.2 PU8202.5 PU8202.6 PU8202.7 PU8202.8 PU8204.5 PU8204.6 PU8204.7 PU8204.8
PWR_DCBATOUT_VGA_CORE2: PC8212.1 PC8213.1 PC8215.1 PC8221.2 PC8224.1 PG8201.2 PG8202.2 PG8203.2 PG8204.2 PG8205.2 PG8206.2 PU8206.5 PU8206.6 PU8206.7 PU8206.8 PU8208.5 PU8208.6 PU8208.7 PU8208.8
PWR_DCBATOUT_VRAM_PWR: PC5113.1 PC5115.1 PG5101.2 PG5102.2 PG5103.2 PU5102.8
PWR_DEBUG: CPU1.H59 R705.2 R9604.1
PWR_LEVEL: D7601.A D7602.A GPU1.D7 R7605.2
PWR_VCC_ALERT#: PR4601.2 PR4618.1 PU4601.19
PWR_VCC_BOOT: PR4701.1 PU4601.13
PWR_VCC_BOOT_RC: PC4706.1 PR4701.2
PWR_VCC_COMP: PC4610.1 PR4613.1 PU4601.6
PWR_VCC_COMP_RC: PC4611.1 PR4613.2
PWR_VCC_EN: PR4621.1 PU4601.1
PWR_VCC_FB: PR4603.1 PR4606.1 PU4601.7
PWR_VCC_FB_RC: PC4601.1 PR4606.2
PWR_VCC_IMON: PC4609.2 PR4610.2 PU4601.3
PWR_VCC_ISUMN: PR4705.2 PR4706.2 PU4601.9
PWR_VCC_ISUMP: PC4707.1 PC4708.1 PR4702.2 PR4703.1 PR4707.1 PR4708.1 PU4601.10
PWR_VCC_LG: PU4601.16 PU4701.8
PWR_VCC_NTC: PR4615.2 PU4601.5
PWR_VCC_NTC_R: PR4615.1 PR4617.1 PR4622.1
PWR_VCC_PHASE: PC4706.2 PG4701.2 PL4701.1 PU4601.15 PU4701.9
PWR_VCC_POK: PR4628.1 PU4601.2
PWR_VCC_PRGM1: PR4614.2 PU4601.17
PWR_VCC_PRGM2: PR4607.2 PU4601.11
PWR_VCC_SCLK: PR4616.1 PR4620.1 PU4601.20
PWR_VCC_SDA: PR4619.1 PR4630.1 PU4601.18
PWR_VCC_UG: PU4601.14 PU4701.1
PWR_VCC_VRHOT#: PR4624.1 PU4601.4
PWR_VGA_CORE_BOOT1: PR8210.1 PU8201.1
PWR_VGA_CORE_BOOT1_1: PC8211.1 PR8210.2
PWR_VGA_CORE_BOOT2: PR8211.1 PU8201.15
PWR_VGA_CORE_BOOT2_1: PC8216.1 PR8211.2
PWR_VGA_CORE_EN: PC8225.2 PR8256.2 PR8260.2 PU8201.3
PWR_VGA_CORE_LGATE1: PR8224.1 PU8201.19 PU8203.4 PU8205.4
PWR_VGA_CORE_LGATE2: PU8201.17 PU8207.4 PU8209.4
PWR_VGA_CORE_PHASE1: PC8211.2 PL8201.1 PR8216.1 PU8201.20 PU8202.1 PU8202.2 PU8202.3 PU8203.5 PU8203.6 PU8203.7 PU8203.8 PU8204.1 PU8204.2 PU8204.3 PU8205.5 PU8205.6 PU8205.7 PU8205.8
PWR_VGA_CORE_PHASE2: PC8216.2 PL8202.1 PR8215.1 PU8201.16 PU8206.1 PU8206.2 PU8206.3 PU8207.5 PU8207.6 PU8207.7 PU8207.8 PU8208.1 PU8208.2 PU8208.3 PU8209.5 PU8209.6 PU8209.7 PU8209.8
PWR_VGA_CORE_PSI: PC8226.2 PR8257.2 PR8258.2 PR8259.1 PU8201.4
PWR_VGA_CORE_REFADJ: PR8222.1 PU8201.6
PWR_VGA_CORE_REFIN: PC8204.1 PR8208.1 PR8209.1 PU8201.7
PWR_VGA_CORE_RGND: PC8201.1 PC8204.2 PC8217.1 PC8219.2 PC8223.2 PR8209.2 PR8213.1 PR8220.1 PU8201.10
PWR_VGA_CORE_SS: PC8205.1 PU8201.11
PWR_VGA_CORE_TON: PR8201.2 PU8201.9
PWR_VGA_CORE_TON_1: PC8202.2 PR8201.1 PR8202.2
PWR_VGA_CORE_UGATE1: PU8201.2 PU8202.4 PU8204.4
PWR_VGA_CORE_UGATE2: PU8201.14 PU8206.4 PU8208.4
PWR_VGA_CORE_VID: PC8203.2 PR8207.2 PU8201.5
PWR_VGA_CORE_VREF: PC8201.2 PR8206.1 PU8201.8
PWR_VGA_CORE_VSNS: PC8219.1 PC8222.1 PR8212.2 PR8221.1 PU8201.12
PWR_VGA_SNUB1: PC8206.1 PR8216.2
PWR_VGA_SNUB2: PC8218.1 PR8215.2
PWR_VRAM_PWR_EN: PR5104.1 PR5114.1 PU5102.1
PWR_VRAM_PWR_ILIM: PR5111.1 PU5102.3
Q402_1: Q3003.B RN3001.4(B)
Q6203_S: C6204.2 Q6203.S R6209.2 R6212.2 R6213.2
Q6204_G: Q6204.2 Q6204.5 R6216.2 R6217.2
Q7601_G: Q7601.2 Q7601.5 R7624.1
REFIN_VREF: PC8223.1 PR8206.2 PR8208.2 PR8222.2
REGOUT: C3002.1 L3001.1 LOM30.24 R3001.1
RING2: EC2905.1 HDA27.17 R2906.2 RN2901.4(B)
RING2_R: ED2903.2 HPMIC1.3 R2906.1
ROM_CS#: GPU1.D12 R7626.1
ROM_SCLK: GPU1.C12 R7608.2 R7614.1 R7616.1
ROM_SI: GPU1.B12 R7618.1 R7619.2 R7638.2 R7639.2 R7640.1 R7641.1 R7642.1
ROM_SO: GPU1.A12 R7611.2 R7620.1 R7651.1
RSET: LOM30.31 R3032.2
RSMRST#_KBC: KBC24.15 R1702.2
RSVDA51: CPU1.A51 TP606.1
RSVDAU63: CPU1.AU63 TP602.1
RSVDAV63: CPU1.AV63 TP601.1
RSVDB51: CPU1.B51 TP607.1
RSVDC62: CPU1.C62 TP604.1
RSVDC63: CPU1.C63 TP603.1
RSVDL60: CPU1.L60 TP608.1
RSVDN59: CPU1.N59 TP704.1
RSVDN61: CPU1.N61 TP705.1
RSVDP60: CPU1.P60 TP702.1
RSVDP61: CPU1.P61 TP703.1
RT8812_PVCC: PC8207.1 PR8223.2 PU8201.18
RTC_AUX_S5: C1120.1 C1121.1 C1122.1 C2503.1 CPU1.AG10 D2501.3 R1720.2 R1901.1 R1903.1 R2428.2 RN1901.1(A) RN1901.2(A)
RTC_DET#: CPU1.AD5 Q2505.D RN2012.6(B)
RTC_PWR: D2501.2 Q2505.G R2502.1 R2504.1
RTC_RST#: C1901.1 CPU1.AU7 G1901.2 Q1901.D RN1901.3(B)
RTC_X1: C1903.2 CPU1.AW5 R1915.1 X1901.1
RTC_X2: C1904.2 CPU1.AY5 R1915.2 X1901.4
RTCRST_ON: KBC24.120 Q1901.G R1902.1
S5_ENABLE: KBC24.14 Q2403.D R2436.2 R3603.2
SA0_DIMA: DM1.197 R1201.1
SA1_DIMA: DM1.201 R1202.1
SATA3_PRX_HDDTX_N0: C5616.1 CPU1.J5
SATA3_PRX_HDDTX_P0: C5615.1 CPU1.H5
SATA3_PTX_HDDRX_N0: C5603.2 CPU1.B15
SATA3_PTX_HDDRX_P0: C5602.2 CPU1.A15
SATA_IREF: CPU1.A12 R1904.1
SATA_LED#: CPU1.U3 R1905.2
SATA_ODD_DA#: CPU1.T3 R5602.2 RN2002.7(B)
SATA_ODD_DA#_C: ODD1.4 R5602.1
SATA_ODD_PRSNT#: CPU1.U1 ODD1.1 R5604.1 RN1902.1(A)
SATA_ODD_PWRGT: CPU1.N6 R5607.2 U5601.4
SATA_PRX_ODDTX_N2: C5607.2 CPU1.J8
SATA_PRX_ODDTX_P2: C5608.2 CPU1.H8
SATA_PTX_ODDRX_N2: C5611.2 CPU1.A17
SATA_PTX_ODDRX_P2: C5612.2 CPU1.B17
SATA_RCOMP: CPU1.C12 R1906.1
SATA_RXN0_R: C5616.2 HDD1.S5 U5602.4 U5602.7
SATA_RXN2_R: C5607.1 ODD1.S5
SATA_RXP0_R: C5615.2 HDD1.S6 U5602.5 U5602.6
SATA_RXP2_R: C5608.1 ODD1.S6
SATA_TXN0_R: C5603.1 HDD1.S3 U5602.2 U5602.9
SATA_TXN2_R: C5611.1 ODD1.S3
SATA_TXP0_R: C5602.1 HDD1.S2 U5602.1 U5602.10
SATA_TXP2_R: C5612.1 ODD1.S2
SLEEVE: EC2906.1 HDA27.18 R2911.2 RN2901.3(B) U2901.3
SLEEVE_CTRL: R2915.2 U2901.5 U2901.6
SLEEVE_R: ED2905.2 HPMIC1.4 R2911.1
SM_DRAMRST#: CPU1.AV15 R404.1 R410.2
SM_INTRUDER#: CPU1.AU6 R1901.2
SM_RCOMP_0: CPU1.AU60 R407.2
SM_RCOMP_1: CPU1.AV60 R408.2
SM_RCOMP_2: CPU1.AU61 R409.2
SMB_CLK: CPU1.AP2 Q1801.3 RN1811.3(B)
SMB_DATA: CPU1.AH1 Q1801.6 RN1811.4(B)
SMBC_THERM_NV: GPU1.D9 Q7601.1 RN7601.2(A)
SMBD_THERM_NV: GPU1.D8 Q7601.4 RN7601.1(A)
SML0_CLK: CPU1.AN1 RN1807.5(B)
SML0_DATA: CPU1.AK1 RN1807.6(B)
SML1_CLK: CPU1.AU3 KBC24.67 Q2601.3 Q7601.6 RN1807.8(B)
SML1_DATA: CPU1.AH3 KBC24.68 Q2601.6 Q7601.3 RN1807.7(B)
SP_PLLVDD: C7601.1 C7602.1 C7603.1 C7604.1 GPU1.M6 GPU1.N6 L7602.2
SPI_CLK_R: EC2503.1 R1806.1 R2420.1 SKT25.6 SPI25.6
SPI_CS0#_R: R1807.1 R2419.1 R2501.1 SKT25.1 SPI25.1
SPI_HOLD#: R1812.1 RN2501.2(A) SKT25.7 SPI25.7
SPI_SI_R: EC2501.1 R1808.1 R2422.1 SKT25.5 SPI25.5
SPI_SO_R: EC2502.1 R1809.1 R2423.1 SKT25.2 SPI25.2
SPI_WP#: R1811.1 RN2501.1(A) SKT25.3 SPI25.3
SRTC_RST#: C1902.1 CPU1.AV6 RN1901.4(B)
STRAP0: GPU1.D1 R7621.1 R7625.2 R7646.2
STRAP1: GPU1.D2 R7622.1 R7635.2
STRAP2: GPU1.E4 R7606.2 R7637.1
STRAP3: GPU1.E3 R7609.1 R7615.2
STRAP4: GPU1.D3 R7632.1 R7634.2
STRAP_REF0_GND_N9: GPU1.F6 R7607.2
SUS_CLK: R1710.2 R2441.2
SUS_CLK_PCH: CPU1.AE6 EC1701.2 R1710.1
SUSCLK_KBC: KBC24.77 R2441.1
SYS_PEX_RST_MON#: D7301.2 R7304.2 R7306.1 R7313.1 R7629.2 U7301.4
SYS_PEX_RST_MON_GPU#: GPU1.E9 R7629.1 R7643.1
SYS_PWROK: CPU1.AG2 EC1702.1 KBC24.84 R1717.1 R9605.1
T_CRIT#: R2601.1 R2604.2 THM26.4
TD_IREF: CPU1.B12 R603.2
TESTMODE: GPU1.AD9 R7302.1
THERM_SYS_SHDN#: Q2602.S R2601.2 R2602.1
THM_SML1_CLK: C2608.1 Q2601.4 RN2602.4(B) THM26.8
THM_SML1_DATA: C2609.1 Q2601.1 RN2602.3(B) THM26.7
TOUCH_PANEL_INTR#: D2401.A R2411.1 R2443.1 R5205.2
TOUCH_PANEL_INTR_KBC#: KBC24.124 R2411.2
TP_CL_CLK: CPU1.AF2 TP1801.1
TP_CL_DATA: CPU1.AD2 TP1802.1
TP_CL_RST#: CPU1.AF4 TP1803.1
TP_DC_TEST_A4: CPU1.A4 TP2202.1
TP_DC_TEST_A60: CPU1.A60 TP2203.1
TP_DC_TEST_A62: CPU1.A62 TP2205.1
TP_DC_TEST_AV1: CPU1.AV1 TP2206.1
TP_DC_TEST_AW1: CPU1.AW1 TP2207.1
TP_DC_TEST_AW63: CPU1.AW63 TP2208.1
TP_DC_TEST_AY60: CPU1.AY60 TP2201.1
TP_DC_TEST_B2: CPU1.B2 TP2204.1
TP_HDA_DOCK_EN#: CPU1.AW10 TP1902.1
TP_LID_CLOSE#: AFTP6242.1 D2402.A R2450.1 R6215.1 TPAD1.3
TP_LID_CLOSE#_KBC: KBC24.26 R2450.2
TP_M_A_DIMA_ODT0: CPU1.AP32 TP501.1
TP_ON#: KBC24.33 R2452.1 R6214.1
TP_ON#_GATE: C6204.1 Q6203.G R6214.2
TP_RESET: AFTP5214.1 C5214.1 LCD1.38 R5212.1
TP_RS: AFTP5209.1 C5208.1 LCD1.37 R5205.1
TP_V1.05S_APLLOPI: CPU1.AC20 TP2105.1
TP_V1.05S_AXCK_DCB: CPU1.M20 TP2104.1
TP_V1.05S_SSCF100: CPU1.K18 TP2103.1
TP_V1.05S_SSCFF: CPU1.V21 TP2101.1
TP_VCCAPLLOPI_VAL: CPU1.Y20 TP2102.1
TP_VCCIO_OUT: CPU1.A59 TP701.1
TP_VDD: AFTP6239.1 C6201.1 Q6203.D R6203.2 R6209.1 R6211.1 R6215.2 RN6201.1(A) RN6201.2(A) RN6204.1(A) RN6204.2(A) TPAD1.8
TPAN_VDD: F5203.2 LCD1.40 R5232.1
TPAN_VDD_F: F5203.1 R5230.2 R5231.2 R5232.2
TPCLK: EC6201.1 KBC24.72 RN6201.4(B) RN6202.1(A)
TPCLK_C: AFTP6238.1 RN6202.4(B) TPAD1.1
TPDATA: EC6202.1 KBC24.71 RN6201.3(B) RN6202.2(A)
TPDATA_C: AFTP6236.1 RN6202.3(B) TPAD1.2
TPS51216_PHS_SET: PC4922.1 PR4912.2
USB3_PRX_CTX_N0: CPU1.G20 R3411.2
USB3_PRX_CTX_N0_C: R3411.1 U3402.1 U3402.10 USB1.5
USB3_PRX_CTX_P0: CPU1.H20 R3410.2
USB3_PRX_CTX_P0_C: R3410.1 U3402.2 U3402.9 USB1.6
USB3_PTX_CRX_N0: C3403.1 CPU1.C33
USB3_PTX_CRX_N0_C: C3402.1 R3409.1 U3402.4 U3402.7 USB1.8
USB3_PTX_CRX_N0_R: C3403.2 R3409.2
USB3_PTX_CRX_P0: C3404.1 CPU1.B34
USB3_PTX_CRX_P0_C: C3401.1 R3408.1 U3402.5 U3402.6 USB1.9
USB3_PTX_CRX_P0_R: C3404.2 R3408.2
USB20_VCCA: AFTP6205.1 C3406.1 C3503.1 C3506.1 C3509.1 C3514.1 TC3502.1 U3401.5 U3502.6 U3503.1 USB2.1
USB20_VCCB: C3515.1 C3516.1 C3517.1 C3518.1 CON1.1 CON1.2 CON1.3 CON1.4 R3502.1 TC6301.1 U3501.6 U3501.7 U3501.8 U3505.1
USB30_VCCC: AFTP6210.1 C3405.1 C3507.1 C3508.1 C3512.1 C3513.1 R3501.1 TC3501.1 U3403.5 U3502.7 U3504.1 USB1.1
USB_CAMERA: AFTP5226.1 CCD1.7 TR5208.2
USB_CAMERA#: AFTP5225.1 CCD1.6 TR5208.3
USB_CAMERA_EDP: LCD1.31 TR5209.2
USB_CAMERA_EDP#: LCD1.30 TR5209.3
USB_COMP: CPU1.AJ10 CPU1.AJ11 R1602.1
USB_OC#0_1: CPU1.AL3 RN1809.7(B) U3502.5 U3502.8 U3503.3 U3504.3
USB_OC#2_3: CPU1.AT1 RN1601.8(B) U3501.5 U3505.3
USB_OC#4_5: CPU1.AH2 RN2012.7(B)
USB_OC#6_7: CPU1.AV3 RN1601.7(B)
USB_PN0: CPU1.AN8 TR3404.4
USB_PN0_C: AFTP6211.1 TR3404.3 U3403.1 USB1.2
USB_PN1: CPU1.AR7 TR3401.1
USB_PN1_R: AFTP6204.1 TR3401.2 U3401.1 USB2.2
USB_PN2: CPU1.AR8 TR6301.4
USB_PN2_IOBD1: CON1.8 TR6301.3
USB_PN3: CPU1.AR10 TP1601.1
USB_PN4: CPU1.AM15 RN5205.3(B) RN5206.4(B)
USB_PN4_CAM#: RN5205.2(A) TR5208.4
USB_PN4_EDP: RN5206.1(A) TR5209.4
USB_PN5: CPU1.AM13 R5802.2
USB_PN5_R: R5802.1 WLAN1.36
USB_PN6: CPU1.AP11 R5203.2
USB_PN6_TPNL: LCD1.34 R5203.1
USB_PN7: CPU1.AR13 TR6302.4
USB_PN7_IOBD1: CON1.11 TR6302.3
USB_PP0: CPU1.AM8 TR3404.1
USB_PP0_C: AFTP6212.1 TR3404.2 U3403.3 USB1.3
USB_PP1: CPU1.AT7 TR3401.4
USB_PP1_R: AFTP6209.1 TR3401.3 U3401.3 USB2.3
USB_PP2: CPU1.AP8 TR6301.1
USB_PP2_IOBD1: CON1.9 TR6301.2
USB_PP3: CPU1.AT10 TP1602.1
USB_PP4: CPU1.AL15 RN5205.4(B) RN5206.3(B)
USB_PP4_CAM: RN5205.1(A) TR5208.1
USB_PP4_EDP: RN5206.2(A) TR5209.1
USB_PP5: CPU1.AN13 R5803.2
USB_PP5_R: R5803.1 WLAN1.38
USB_PP6: CPU1.AN11 R5204.2
USB_PP6_TPNL: LCD1.35 R5204.1
USB_PP7: CPU1.AP13 TR6302.1
USB_PP7_IOBD1: CON1.12 TR6302.2
USB_PWR_EN#: KBC24.83 R2412.1 U3501.4 U3502.3 U3502.4 U3503.4 U3504.4 U3505.4
VD1_EN#: KBC24.66 R2449.2
VD_IN1: C2612.1 C2613.1 KBC24.104 R2608.2 R2609.2 R2610.1
VD_IN1_C: C2612.2 C2613.2 R2610.2 R2611.1
VD_OUT1#: KBC24.110 R2602.2 R2607.2 R2612.2
VGA_CORE: C7701.1 C7702.1 C7708.1 C7709.1 C7710.1 C7711.1 C7712.1 C7713.1 C7714.1 C7717.1 C7719.1 C7720.1 C7721.1 C7722.1 C7723.1 C7724.1 C7725.1 C7726.1 C7730.1 C7731.1 C7732.1 C7733.1 GPU1.K10 GPU1.K12 GPU1.K14 GPU1.K16 GPU1.K18 GPU1.L11 GPU1.L13 GPU1.L15 GPU1.L17 GPU1.M10 GPU1.M12 GPU1.M14 GPU1.M16 GPU1.M18 GPU1.N11 GPU1.N13 GPU1.N15 GPU1.N17 GPU1.P10 GPU1.P12 GPU1.P14 GPU1.P16 GPU1.P18 GPU1.R11 GPU1.R13 GPU1.R15 GPU1.R17 GPU1.T10 GPU1.T12 GPU1.T14 GPU1.T16 GPU1.T18 GPU1.U11 GPU1.U13 GPU1.U15 GPU1.U17 GPU1.V10 GPU1.V12 GPU1.V14 GPU1.V16 GPU1.V18 PL8201.2 PL8202.2 PR8212.1 PR8317.1 PT8206.1 PT8207.1 PT8208.1
VGA_CORE_DISCHG: PQ8307.D PR8317.2
VGA_CORE_PSI: GPU1.B4 PR8257.1
VGA_CORE_VID: GPU1.E7 PR8207.1
VGACORE_GND_SENSE_1: GPU1.F1 PR8220.2
VGACORE_VDD_SENSE_1: GPU1.F2 PR8221.2
VIDEO_CLK_XTAL_SS: GPU1.A10 R7601.1
VIDEO_THERM_OVERT#: Q7602.6 TP7606.1
VR_SVID_ALERT#: PR4618.2 R701.1 R703.2
VRAM_PWR_BS: PR5102.1 PU5102.6
VRAM_PWR_BS_R: PC5110.1 PR5102.2
VRAM_PWR_BYP: PR5112.2 PU5102.7
VRAM_PWR_FB: PC5111.2 PR5103.1 PR5113.2 PU5102.4
VRAM_PWR_FBH: PC5111.1 PG5104.1 PR5113.1
VRAM_PWR_LDO: PC5112.1 PU5102.5
VRAM_PWR_PH: PC5110.2 PL5101.1 PU5102.10
VTT_CT_3VC_1: C8305.1 U8301.10
VTT_CT_105VC_2: C8316.1 U8301.12
WHITE_LED_BAT: EC6103.1 Q6103.C R6101.2
WIFI_RF_EN: KBC24.82 WLAN1.20
WLAN_ACT: C5807.1 TP5801.1 WLAN1.3
WLAN_PLT_RST#: CPU1.AT5 RN2012.5(B)
XCLK_BIASREF: CPU1.C26 R1803.1
XDP_BPM0: CPU1.J60 TP9612.1
XDP_BPM1: CPU1.H60 TP9613.1
XDP_BPM2: CPU1.H61 TP9614.1
XDP_BPM3: CPU1.H62 TP9615.1
XDP_BPM4: CPU1.K59 TP9616.1
XDP_BPM5: CPU1.H63 TP9617.1
XDP_BPM6: CPU1.K60 TP9618.1
XDP_BPM7: CPU1.J61 TP9619.1
XDP_DBRESET#: C9602.1 CPU1.AC3 EC1706.1 R1701.2 TP9653.1
XDP_PRDY#: CPU1.J62 TP9602.1
XDP_PREQ#: CPU1.K62 TP9601.1
XDP_PWR_DEBUG: R9604.2 TP9647.1
XDP_RST: R9602.1 TP9654.1
XDP_SMBCLK: RN9601.3(B) TP9649.1
XDP_SMBDAT: RN9601.4(B) TP9646.1
XDP_SYS_PWROK: R9605.2 TP9644.1
XDP_TCK_JTAGX: CPU1.AE63 R1919.1
XDP_TCLK: CPU1.E60 R406.1 TP9650.1
XDP_TDI: CPU1.F63 RN401.2(A) TP9623.1
XDP_TDO: CPU1.F62 RN401.4(A) TP9624.1
XDP_TMS: CPU1.E61 RN401.1(A) TP9611.1
XDP_TRST#: CPU1.E59 R402.1 TP9621.1
XTAL24_IN: CPU1.A25 R1802.1 R1810.1
XTAL24_IN_R: C1801.2 R1810.2 X1801.1
XTAL24_OUT: C1802.2 CPU1.B25 R1802.2 X1801.3

Pads without a net: CCD1 2; CON1 6; CPU1 A5 A6 A8 A31 A33 A37 A41 A49 A53 AA23 AA59 AB21 AB23 AC2 AC4 AC58 AC59 AD23 AD59 AD60 AE59 AE60 AF20 AG58 AK18 AK20 AK21 AK22 AK25 AK26 AK28 AK29 AK32 AK33 AK35 AK36 AK38 AL1 AL11 AL18 AL21 AL25 AL28 AL32 AL35 AL38 AM10 AM11 AM18 AM20 AM21 AM22 AM25 AM26 AM28 AM29 AM32 AM33 AM35 AM36 AM38 AN10 AN18 AN20 AN21 AN22 AN25 AN26 AN28 AN29 AN38 AP7 AP18 AP21 AP25 AP28 AP40 AP42 AP45 AP46 AP51 AR18 AR20 AR21 AR22 AR25 AR26 AR28 AR29 AR40 AR42 AR45 AR46 AT2 AU10 AU12 AU15 AU17 AU19 AU21 AU23 AU25 AU27 AU29 AU31 AU44 AU46 AU47 AU49 AU50 AV2 AV10 AV17 AV18 AV19 AV21 AV22 AV23 AV25 AV26 AV27 AV29 AV30 AV31 AV44 AV47 AV50 AV62 AW14 AW17 AW18 AW19 AW21 AW22 AW23 AW25 AW26 AW27 AW29 AW30 AW31 AW46 AW49 AY8 AY14 AY17 AY19 AY21 AY23 AY25 AY27 AY29 AY31 AY42 AY43 AY46 AY47 AY49 B5 B6 B14 B31 B33 B37 B41 B49 B50 B53 B54 C3 C4 C5 C15 C17 C30 C31 C42 C43 C46 C47 C49 C50 C51 C53 D1 D9 D15 D17 D58 D61 E1 E2 E4 E5 E13 E15 E18 F4 F5 F15 F17 F18 F22 G1 G2 G15 G17 H6 H18 H22 J3 J6 J20 J21 J58 K4 K10 K21 L2 L4 L5 L6 L11 L59 M21 N5 N7 N23 N58 N60 R6 R7 R23 T23 T59 U10 U59 V59 W23 Y1 Y4; D3602 2; DM1 77 122 125 198; GPU1 AA1 AA2 AA3 AA4 AA5 AA6 AB1 AB2 AB3 AB4 AB5 AB6 AB13 AB15 AB16 AB18 AB19 AB21 AC3 AC4 AC13 AC14 AC15 AC16 AC17 AC18 AC19 AC20 AC21 AD1 AD2 AD3 AD4 AD5 AD7 AD10 AD14 AD17 AD20 AD23 AE1 AE2 AE3 AE4 AE10 AE12 AE13 AE15 AE16 AE18 AE19 AE21 AE23 AE24 AF2 AF3 AF4 AF10 AF12 AF13 AF15 AF16 AF18 AF19 AF21 AF24 AG3 AG12 AG13 AG15 AG16 AG18 AG19 AG21 AG22 AG24 AG25 B2 B3 B6 B19 C1 C2 C3 C7 C18 D4 D5 D6 D10 D16 D17 D18 E6 E10 F4 F5 F7 F9 F10 F11 G1 G2 G3 G4 G5 G6 G7 H3 H4 J1 J2 J3 J4 J5 K1 K2 K3 K4 K5 K6 L3 L4 M1 M2 M3 M4 M5 N1 N2 N3 N4 N5 P3 P4 R1 R2 R3 R4 R5 T1 T2 T3 T4 T5 T6 T24 U3 U4 U6 U24 V1 V2 V3 V4 V5 V6 V24 V25 W1 W2 W3 W4 W5 Y3 Y4; HDA27 14 16 23 24; HDD1 P1 P2 P3 P11 P13 P14 P15; HDMI1 13 14; KB1 2 3; KB2 2 3; KBLIT1 3; LCD1 3 33 39; PU5101 4; RN401 3 6; RN1801 5; RN1902 2; RN4301 4 5; RN5201 4 5; RN5203 4 5; SW1 3; U701 1; U3401 4 6; U3403 4 6; U3801 5; U5601 5; VRAM1 J1 J9 L1 L9 M7; VRAM2 J1 J9 L1 L9 M7; VRAM3 J1 J9 L1 L9 M7; VRAM4 J1 J9 L1 L9 M7; WLAN1 1 6 8 10 12 14 16 28 30 32 42 45 47 48; X1801 2 4; X1901 2 3; X3001 2 4

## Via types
v1: diameter 0.508, hole 0.254, TOP to BOTTOM, 3129 vias
v2: diameter 0.356, hole 0.178, TOP to BOTTOM, 1161 vias
v3: diameter 0.711, hole 0.406, TOP to BOTTOM, 978 vias

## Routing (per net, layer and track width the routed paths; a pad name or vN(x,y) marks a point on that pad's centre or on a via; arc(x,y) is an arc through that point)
3V3_AON_S0: length 63.6
  TOP w0.356: R7312.1 152.65,102.98 152.65,101.95 152.36,101.65 U7301.5
  TOP w0.508: v1(177.33,108.34) 176.93,107.94 R7606.1 ; R7617.1 179.27,114.22 179.64,114.59 179.64,115.34 v2(181.02,116.72) 181.29,116.99 182.47,116.99 182.96,117.48 183.93,117.48 ; v1(177.67,103.17) 177.47,103.37 R7605.1 175.82,103.64 R7631.1 ; v1(153.96,103) 153.77,103.19 R7312.1 ; v1(154.32,96.66) 154.32,96.2 154.32,96.19 Q7301.G
  TOP w1.016: v3(178.13,99.69) 183.92,99.69 v3(183.94,99.66)
  L3 w0.508: v1(150.95,73.47) 150.67,73.19 149.15,73.19 147.6,74.74 147.6,82.27 151.5,86.17 151.5,89.93 v1(152.65,91.08) 154.32,92.75 v1(154.32,96.66)
  BOTTOM w0.305: v1(174.06,113.3) 174.06,113.33 173.71,113.68 GPU1.G12 ; v1(174.01,112.64) 173.71,112.34 GPU1.G10
  BOTTOM w0.381: Q7602.2 188.04,104.27 R7612.2 188.11,103.54 v1(187.8,103.23)
  BOTTOM w0.508: R7643.2 181.82,106.73 v1(181.47,107.07) ; R7615.1 186.55,113.98 v3(184.95,113.98) ; v1(193.36,117.47) 194.01,116.82 R7624.2 ; PR8258.1 151.71,74.08 151.1,73.47 v1(150.95,73.47) ; v1(152.65,91.08) 153.14,91.08 154.22,90.01 PR8203.1 ; v1(186.56,101.31) 186.15,101.72 186.15,102.21 R7645.1
  vias: v1(151.51,116.4) v1(161.57,110.83) v1(161.57,110.03) v3(152.23,116.54) v3(153.07,116.98) v3(157.88,99.63)
3V5V_CT1: length 3
  TOP w0.203: C3602.1 131.83,4.02 131.93,4.02 v2(132.12,4.21) 132.17,4.27 132.17,5.12 132.09,5.21 U3601.12
3V5V_CT2: length 2.9
  TOP w0.203: U3601.10 131.29,5.23 130.75,4.7 v2(130.75,4.29) 130.75,3.95 130.28,3.48 C3601.1
3V5V_S0_ON: length 5.5
  TOP w0.127: U3601.3 132.09,8.42 132.13,8.46 132.13,9.88 R3609.2 131.26,10.19 131.02,9.95 131.02,9.64 v2(131.01,9.63) 131.02,9.62 131.02,8.64 131.29,8.37 U3601.5
3V_5V_EN: length 46.4
  TOP w0.127: PR4506.1 125.55,39.63 PR4507.1 v1(124.72,40.26) ; D3602.1 151.8,23.5 152.03,23.74 R3602.1 R3603.1 151.02,24.37 v1(150.29,23.64)
  L4 w0.127: v1(124.72,40.26) 125.63,41.17 125.63,42.18 127.97,44.52 130.68,44.52 131.14,44.06 131.14,42.74 133.94,39.94 138.78,39.94 139.41,39.31 139.82,39.31 140.91,38.22 140.91,35.59 142.78,33.71 150.29,26.21 v1(150.29,23.64)
  BOTTOM w0.127: v1(150.29,23.64) 150.04,23.64 v2(149.73,23.94)
3V_5V_POK: length 29.4
  TOP w0.127: PU4503.7 127.31,38.57 127.2,38.68 v1(126.95,38.68) 126.69,38.68 126.57,38.55 PR4534.2
  L3 w0.127: v1(126.95,38.68) 125.29,38.68 124.72,38.1 124.34,38.1 124.33,38.09 124.05,38.09 123.71,38.43 123.71,40.15 124.34,40.77 124.72,40.77 125.36,41.41 125.36,47.64 131.78,54.06 v1(131.78,56.18)
  BOTTOM w0.127: R1728.2 131.68,57.25 v2(131.68,56.86) 131.68,56.28 v1(131.78,56.18)
3V_5V_POK#: length 4.8
  BOTTOM w0.127: v2(128.98,63.34) 128.51,62.87 R1726.1 128.26,62.2 Q1701.5 128.26,60.43 128.43,60.26 128.77,60.26 128.91,60.39 Q1701.6
3V_5V_POK_C: length 5
  BOTTOM w0.127: R1727.2 130.21,59.5 R1729.1 130.22,58.63 R1728.1 129.89,57.82 129.86,57.85 129.33,57.85 129.19,57.7 v2(128.83,57.7) 128.53,58 128.53,58.36 128.26,58.63 Q1701.2
3V_FEEDBACK: length 38.6
  TOP w0.254: v1(128.15,44.07) PR4535.1 128.22,43.31 PR4512.1
  BOTTOM w0.254: v1(128.15,44.07) 125.95,44.07 ; 125.95,44.07 124.24,44.07 121.61,41.44 121.61,37.43 117.42,33.24 117.42,18.1 120.29,15.23 PG4535.2 ; 125.95,44.07 v2(125.95,44.07)
5V_HDMI_R_S0:
  vias: v2(21.94,83.43)
5V_HDMI_S0: length 11.8
  BOTTOM w0.508: HDMI1.18 12.02,90.2 17.21,85.02 v2(17.21,84.22) C5401.1 F5401.2
5V_PWR: length 25.9
  BOTTOM w0.508: PD4503.1 139.3,35.95 PC4515.1 140.61,35.86 v2(141.26,35.21) 143.47,33 143.47,22.66 141.35,20.54 PL4501.2
5V_PWR_2: length 120.8
  TOP w0.203: v1(130.76,35.12) 130.56,35.12 130.25,35.43 PU4503.13
  TOP w0.508: v1(119.87,39.77) 120.71,38.94 v1(122.43,38.94) ; v1(29.96,21.79) 29.96,22.67 31.12,23.82 v2(35.92,23.82) 36.86,23.82 38.65,25.62 42.59,29.56 v1(43.53,29.56) ; v1(130.76,35.12) 130.71,35.07 PC4524.1
  BOTTOM w0.508: v1(43.53,29.56) 43.62,29.56 43.62,28.58 44.68,27.52 47.23,27.52 48.82,29.11 48.82,31 50.02,32.2 53.62,32.2 56.79,35.37 58.97,35.37 59.07,35.27 106.52,35.27 112.86,41.61 118.04,41.61 v1(119.87,39.77) ; v1(122.43,38.94) 122.8,39.31 127.23,39.31 130.12,36.42 130.12,35.49 130.49,35.12 v1(130.76,35.12) ; v1(29.96,21.79) 30.05,21.7 30.05,21.23 29.85,21.03 R2915.1
5V_S0: length 268.9
  TOP w0.203: v1(148.99,120.76) 149.1,120.86 U8301.4
  TOP w0.305: PC4604.1 113.63,121.53 113.83,121.73 v2(114,121.73) 114.08,121.73 114.98,120.83 PU4601.12
  TOP w0.381: 196.14,31.29 HDD1.P9 196.14,30.59 ; 196.14,28.75 HDD1.P7 196.14,29.44 ; 196.14,30.02 HDD1.P8 196.14,29.32
  TOP w0.508: v1(134.21,90.59) 134.14,90.52 133.84,90.52 133.3,89.98 133.3,89.34 135.56,87.07 135.56,78.79 136.11,78.24 v3(136.11,77.41) ; R5230.1 33.55,69.61 32.84,68.91 31.82,68.91 31.21,69.51 v3(30.62,69.51) 30.62,68.68 EC9724.1 ; v1(159.46,82.11) 157.01,82.11 152.69,86.43 v3(150.57,86.43)
  TOP w0.635: Q6201.E 197.93,84.95 197.93,80.22 196.97,79.26 196.97,75.12 195.82,73.97
  TOP w0.762: v1(113.52,122.54) 112.91,121.93 PC4604.1
  L3 w0.508: v3(193.44,74.3) 194.28,75.14 194.28,79.98 193.98,80.28 193.98,87.52 193.11,88.39 v1(193.11,90.42) ; v1(153.46,94.26) 153.46,93.18 150.7,90.41 150.7,86.56 v3(150.57,86.43) ; v1(121.67,116.24) 121.67,117.29 123.63,119.25 123.63,122.34 122.41,123.57 122.41,125.05 123.13,125.78 v3(123.5,125.78) 123.5,126.03 124.91,127.45 124.91,128.89 126.5,130.47 130.67,130.47 131.26,129.89 133.9,129.89 135.47,128.31 137.69,128.31 146.75,119.24 148.1,119.24 148.4,119.54 148.4,120.3 148.85,120.76 v1(148.99,120.76) ; v3(149.73,93.24) 149.65,93.16 146.99,93.16 144.83,91 138.35,91 138.09,91.26 135.84,91.26 135.71,91.38 135,91.38 v1(134.21,90.59)
  L3 w0.762: v3(32.71,94.05) 30.93,92.27 27.66,92.27 26.9,91.51 25.93,91.51 24.65,90.23 24.65,83.06 25.08,82.63 v3(25.08,82.61)
  BOTTOM w0.381: 196.14,30.02 HDD1.P8 196.14,29.32 ; 196.14,28.75 HDD1.P7 196.14,29.44 ; 196.14,30.59 HDD1.P9 196.14,31.29
  BOTTOM w0.508: F6201.1 136.95,76.4 136.12,77.23 136.12,77.4 v3(136.11,77.41) 136.12,77.42 136.12,77.59 136.6,78.07 R6205.1 ; v1(193.11,90.42) 193.11,90.47 189.14,94.45 185.35,94.45 184.53,95.28 174.65,95.28 174.24,95.69 173.86,95.69 173.19,96.36 157.45,96.36 156.28,95.19 155.27,95.19 154.34,94.26 v1(153.46,94.26) ; v1(121.67,116.24) 122.02,116.24 122.73,115.54 R6216.1 ; v3(123.5,125.78) 123.47,125.8 122.48,125.8 120.23,123.56 118.16,123.56 117.35,124.38 115.36,124.38 v1(113.52,122.54) ; v1(148.99,120.76) 149.21,120.76 150.31,119.65 150.31,116.75 149.76,116.19 149.76,103.6 149.08,102.92 149.08,93.88 v3(149.73,93.24) 149.68,93.18 149.68,89.69 150.59,88.78 150.59,87 150.57,86.97 150.57,86.44 v3(150.57,86.43) ; EC9721.1 v1(188.89,7.91) ; v1(159.46,82.11) 159.23,81.88 PR8223.1
  BOTTOM w0.559: 34.49,94.05 35.91,94.05 36.8,94.94 C2605.1 36.97,93.96 C2611.1
  BOTTOM w0.635: v3(32.71,94.05) 34.49,94.05
  vias: v1(193.11,72.59) v3(24.71,23.69) v3(24.71,22.8) v3(45.73,2.28) v3(46.64,2.36) v3(47.53,2.31) v3(72.44,5.22) v3(72.69,4.31) v3(73.28,5.53) v3(73.61,4.72) v3(132.92,4.49) v3(133.6,3.97) v3(133.83,4.79) v3(134.47,3.97) v3(134.75,4.76) v3(135.38,4.18) v3(165.05,8.32) v3(165.14,9.24) v3(165.86,8.63) v3(166.21,9.39) v3(192.34,29.85) v3(192.45,31.48) v3(193.06,30.53) v3(193.18,29.37) v3(193.44,73.39)
5V_S5: length 265.7
  TOP w0.203: U3601.4 131.69,8.84 v3(131.59,8.94) ; PU4901.12 103.2,14.95 102.99,15.15 102.99,15.16 102.46,15.69
  TOP w0.305: 127.83,125.19 128.3,125.66 PU4806.7
  TOP w0.508: Q6104.E 173.47,18.81 171.6,18.81 170.92,18.13 170.92,17.11 Q6103.E 169.74,16.16 169.54,16.36 169.54,17.15 v1(169.59,17.21) ; R1208.1 63.29,46.26 63.29,45.25 v3(63.36,45.18) ; v3(137.06,43.31) 137.06,44.55 137.48,44.97 137.48,54.66 137.06,55.08 137.06,70.15 136.72,70.49 136.72,71.31 137.74,72.33 137.74,87.44 136.9,88.28 136.9,90.54 137.51,91.15 137.51,92.68 138.16,93.33 138.16,96.71 136.31,98.56 133.18,98.56 130.85,100.89 130.05,100.89 v3(129.9,101.04) 128.8,101.04 128.39,101.44 128.39,105.55 126.03,107.92 v3(126.03,109.85) ; v1(103.58,18.28) 103.38,18.48 PC4901.1 101.62,16.54 102.46,15.69 ; v3(123.52,124.85) 123.6,124.92 v2(124.61,124.92) 125.15,124.92 125.75,124.33 PC4815.1 126.97,124.33 127.83,125.19
  L3 w0.508: 153.95,14.34 153.95,15.38 151.14,18.18 151.14,24.7 145.95,29.89 145.95,32.72 145.19,33.48 145.19,35.76 143.25,37.7 143.25,40.64 141.07,42.82 140.59,43.31 v3(137.06,43.31) ; v1(169.59,17.21) 168.74,17.21 168.56,17.04 163.95,17.04 163.62,17.37 163.47,17.37 163.14,17.7 158.76,17.7 157.73,16.67 157.73,15.84 157.86,15.72 157.86,15.01 156.62,13.76 155.9,13.76 ; v3(129.9,101.04) 129.84,100.98 125.4,100.98 v3(125.19,100.78)
  L4 w0.508: v3(123.52,124.85) 122.52,124.85 121.66,125.7 121.66,128.42 122.08,128.83 122.08,129.19 123.3,130.41 125.31,130.41 130.5,135.59 130.5,143.06 128.8,144.75 124.25,144.75 122.31,146.69 120.36,146.69 v1(120.24,146.8)
  BOTTOM w0.203: v3(125.19,100.78) 125,100.97 125,101.36 124.75,101.61 U2101.1
  BOTTOM w0.508: v1(120.24,146.8) 120.18,146.74 PR4203.1 ; v3(126.03,109.85) 123.83,112.05 123.83,113.8 123.77,113.85 123.77,124.59 v3(123.52,124.85) ; 40,30.5 42.61,33.1 42.61,33.63 45.02,36.04 45.02,43.03 47.17,45.18 v3(63.36,45.18) ; v1(103.58,18.28) 104.78,19.48 107.74,19.48 109.49,17.73 109.49,12.4 109.65,12.24 109.65,7.67 111.12,6.2
  vias: v3(35.33,30.19) v3(35.41,29.2) v3(35.73,30.97) v3(36.11,29.67) v3(132.76,8.98) v3(133.6,8.75) v3(133.91,7.97) v3(134.49,8.98) v3(134.77,8.02) v3(135.48,8.96) v3(135.61,8.05) v3(136.47,9.01) v3(136.6,8.12) v3(151.24,6.83) v3(152.07,6.67)
15V_PWR: length 8.6
  BOTTOM w0.254: PG4530.2 136.52,44.14 v2(137.65,44.14) PC4533.1 139.77,43.35 PD4501.K 139.77,41.43 139.47,41.13 137.96,41.13 137.75,41.34 PD4502.2
15V_S5: length 171.1
  TOP w0.508: v1(143.3,135.98) 143.3,135.95 143.69,136.34 PR4471.2
  L3 w0.508: v1(177.73,52.14) 178.15,51.72 178.15,50.69 177.88,50.42 177.88,47.8 176.85,46.77 v1(176.85,46.18)
  L4 w0.508: v1(135,44.19) 135.33,44.52 135.33,46.87 v1(133.87,48.33) ; v1(143.3,135.98) 143.39,135.9 143.39,127.35 144.66,126.08 144.66,105.67 144.98,105.35 144.98,103.82 146.56,102.24 146.56,100.64 146.89,100.31 146.89,96.09 148.16,94.82 148.16,86.68 146.94,85.46 146.94,66.18 150.59,62.53 153.34,62.53 154.89,60.98 154.89,58.46 155.49,57.86 155.49,54.33 156.81,53.01 171.44,53.01 172.31,52.14 v1(177.73,52.14)
  BOTTOM w0.254: v1(135,44.19) 135.05,44.14 PG4530.1
  BOTTOM w0.457: PR8310.2 178.38,51.38 178.38,51.38 178.28,51.38 177.73,51.92 v1(177.73,52.14)
  BOTTOM w0.508: v1(133.87,48.33) 133.9,48.3 v2(136.17,48.3) 162.76,48.3 164.58,46.48 166.98,46.48 167.32,46.82 176.21,46.82 v1(176.85,46.18)
+3V_1D5V_AVDD: length 2.2
  TOP w0.203: HDA27.40 34.63,6.95 34.59,6.9
  TOP w0.254: 34.59,6.9 33.65,5.96 v2(33.65,5.89)
+3V_AVDD: length 40.3
  TOP w0.203: C2719.1 40.54,13.15 40.54,12.75 39.53,11.74 HDA27.9
  TOP w0.254: R2918.1 42.91,16.65 42.38,16.12 v1(42.26,16.12)
  TOP w0.508: C2719.1 40.78,13.65 v1(41.22,14.1) ; v1(40.55,4.76) 41.08,5.3 C2716.1 40.79,5.77 C2717.1 39.49,6.48 38.48,7.49 38.48,7.85
  L3 w0.508: v1(42.26,16.12) 41.22,15.08 v1(41.22,14.1) 38.79,11.67 38.79,9.46 40.55,7.7 v1(40.55,4.76) 40.07,4.76 36.68,8.15 32.31,8.15 v1(32.03,7.87) 30.83,7.87 v1(30.8,7.84)
  BOTTOM w0.508: v1(30.8,7.84) C2701.1 30.12,6.27 30.04,6.36 R2701.2 ; v1(41.22,14.1) v2(40.44,14.1) 38.46,14.1 R2722.1
+5V_AVDD: length 12.7
  TOP w0.203: HDA27.26 32.06,12.54 v2(31.03,13.56)
  TOP w0.508: v2(31.03,13.56) 31.03,13.97 30.52,14.48 C2711.1 29.3,14.48 C2710.1 v1(28.14,14.74)
  L4 w0.508: v1(27.41,20.42) 27.41,15.35 28.02,14.74 v1(28.14,14.74)
  BOTTOM w0.508: R2703.1 27.39,20.44 v1(27.41,20.42)
+5V_KB_BL: length 34.3
  TOP w0.305: 132.64,101.82 132.11,101.82 131.84,101.55 KBLIT1.1 131,101.55 130.47,102.08 129.47,102.08 129.13,101.74 AFTP6248.1
  TOP w0.508: v1(138.15,97.83) 135.72,100.26 134.06,100.26 133.69,100.63 133.69,101.34 133.22,101.82 132.64,101.82
  BOTTOM w0.508: F6201.2 138.83,77.31 138.43,77.72 R6205.2 138.43,79 C6202.1 138.23,79.24 138.23,90.36 137.55,91.05 137.55,92.92 138.63,94 138.63,97.35 v1(138.15,97.83)
+5V_MINI_DEBUG: length 11.1
  TOP w0.508: v1(189.77,18.6) 190.2,19.03 R5801.2 190.25,26.63 R5805.2 190.25,28.33 v2(190.19,28.39)
  BOTTOM w0.457: WLAN1.51 189.06,19.3 v1(189.77,18.6)
+5V_PVDD: length 2.1
  TOP w0.203: 37.03,7.06 HDA27.46 ; HDA27.41 35.03,6.77 34.67,6.41
  vias: v2(38.5,4.16) v2(43.3,1.92)
+V1.05A_AOSCSUS: length 1.2
  TOP w0.381: TP2109.1 114.48,82.14 v1(114.49,82.14)
  BOTTOM w0.254: CPU1.AB8 114.31,81.96 v1(114.49,82.14)
+V1.05A_SUS_PCH: length 2
  TOP w0.254: v1(114.5,81.18) 114.5,81.06 TP2106.1
  BOTTOM w0.254: v1(114.5,81.18) 114.5,81.18 114.31,80.99 CPU1.AD8 CPU1.AD10
+V1.05A_USB2SUS: length 1.1
  TOP w0.254: v1(111.22,77.91) 110.85,77.54 TP2108.1
  BOTTOM w0.254: CPU1.AH13 111.6,78.24 111.27,77.91 v1(111.22,77.91)
+V1.05A_VCCUSB3SUS: length 1.2
  TOP w0.254: TP2107.1 110.98,88.73 v1(111.01,88.76)
  BOTTOM w0.254: CPU1.J13 111.28,88.49 v1(111.01,88.76)
+V1.05DX_MODPHY_PCH:
  vias: v1(114.4,87.95) v2(113.87,87.49) v2(117.73,95.14) v3(112.95,86.9) v3(118.01,96.39)
+V1.05S_AIDLE: length 27.8
  TOP w0.508: v3(121.04,98.12) 121.67,98.75 C2105.1 121.8,99.15 R2105.2 ; v1(114.55,85.95) v2(113.77,85.95)
  L3 w0.508: v1(114.55,85.95) 114.39,86.11 112.56,86.11 112.14,86.53 112.14,87.04 111.66,87.52 111.22,87.52 110.34,88.4 110.34,91.45 111.12,92.23 111.12,93 112.45,94.32 112.78,94.32 113.5,95.04 113.5,95.62 115.05,97.17 115.05,98.16 115.44,98.55 116.35,98.55 116.63,98.26 120.89,98.26 v3(121.04,98.12)
  BOTTOM w0.254: CPU1.P9 113.86,86.06 114.23,86.42 CPU1.N8 114.55,86.18 v1(114.55,85.95)
+V1.05S_APLLOPI: length 32.7
  TOP w0.508: v1(108.4,82.21) 108.4,82.83 108.46,82.89 v1(108.46,83.06) 108.56,83.17 108.6,83.17 108.97,83.54 108.97,84.06 109.58,84.67 109.58,84.87 109.59,84.89 109.59,85.83 108.98,86.44 108.35,86.44 108.35,86.45 108.06,86.45 107.52,86.98 106.56,86.98 105.87,87.67 C1109.1 105.59,89.26 104.89,89.97 104.89,90.42 104.39,90.92 104.39,92.99 105.8,94.4 105.8,95.27 106.65,96.12 v2(106.65,98.37) 106.65,102.32 106.94,102.61 106.94,103.92 C1110.1 C1124.1 R1102.2
  BOTTOM w0.203: v1(108.46,83.06) 108.43,83.04 CPU1.W21 ; CPU1.AA21 108.38,82.22 v1(108.4,82.21)
+V1.05S_ASATA3PLL: length 16.3
  BOTTOM w0.305: CPU1.B11 112.56,93.07 112.92,93.43 112.92,93.89 113.15,94.12 113.15,94.87 113.28,95 113.28,95.04 113.46,95.22
  BOTTOM w0.508: R1906.2 R1904.2 113.66,98.46 113.88,98.68 C1105.1 ; L1102.2 116.53,104.43 C1107.1 C1106.1 115.47,99.97 v2(115.47,99.18) 115.47,99.08 115.07,98.68 C1105.1 ; 113.46,95.22 113.46,95.39 114.45,96.38 C1105.1
+V1.05S_AUSB3PLL: length 33.4
  L4 w0.508: v3(112.94,99.13) 112.94,99.01 112.48,98.56 111.85,98.56 111.27,99.13 109.13,99.13 107.6,99.13 107.59,99.14 102.98,99.14 102.93,99.09 102.92,99.09 v3(102.36,98.53)
  BOTTOM w0.203: CPU1.B27 102.71,93.41 102.71,93.64 102.59,93.76 102.59,94.81 102.62,94.84
  BOTTOM w0.254: 108.77,94.65 108.77,93.63 108.42,93.27 108.22,93.27 CPU1.B18
  BOTTOM w0.305: R1601.1 102.52,97.71 102.04,97.23 102.04,96.46 102.17,96.33 102.17,95.37 102.62,94.93 102.62,94.84
  BOTTOM w0.508: v3(102.36,98.53) 102.59,98.3 R1601.1 ; 108.77,94.65 108.77,96.06 108.81,96.1 108.81,96.13 108.97,96.29 108.97,97.28 110.29,98.6 v2(110.31,98.6) 110.66,98.95 111.46,98.95 111.86,98.54 112.39,98.54 112.84,98.99 112.84,99.02 v3(112.94,99.13) 112.9,99.13 112.9,99.67 C1103.1 112.68,101.15 C1104.1 C1123.1 112.77,104.36 L1101.2
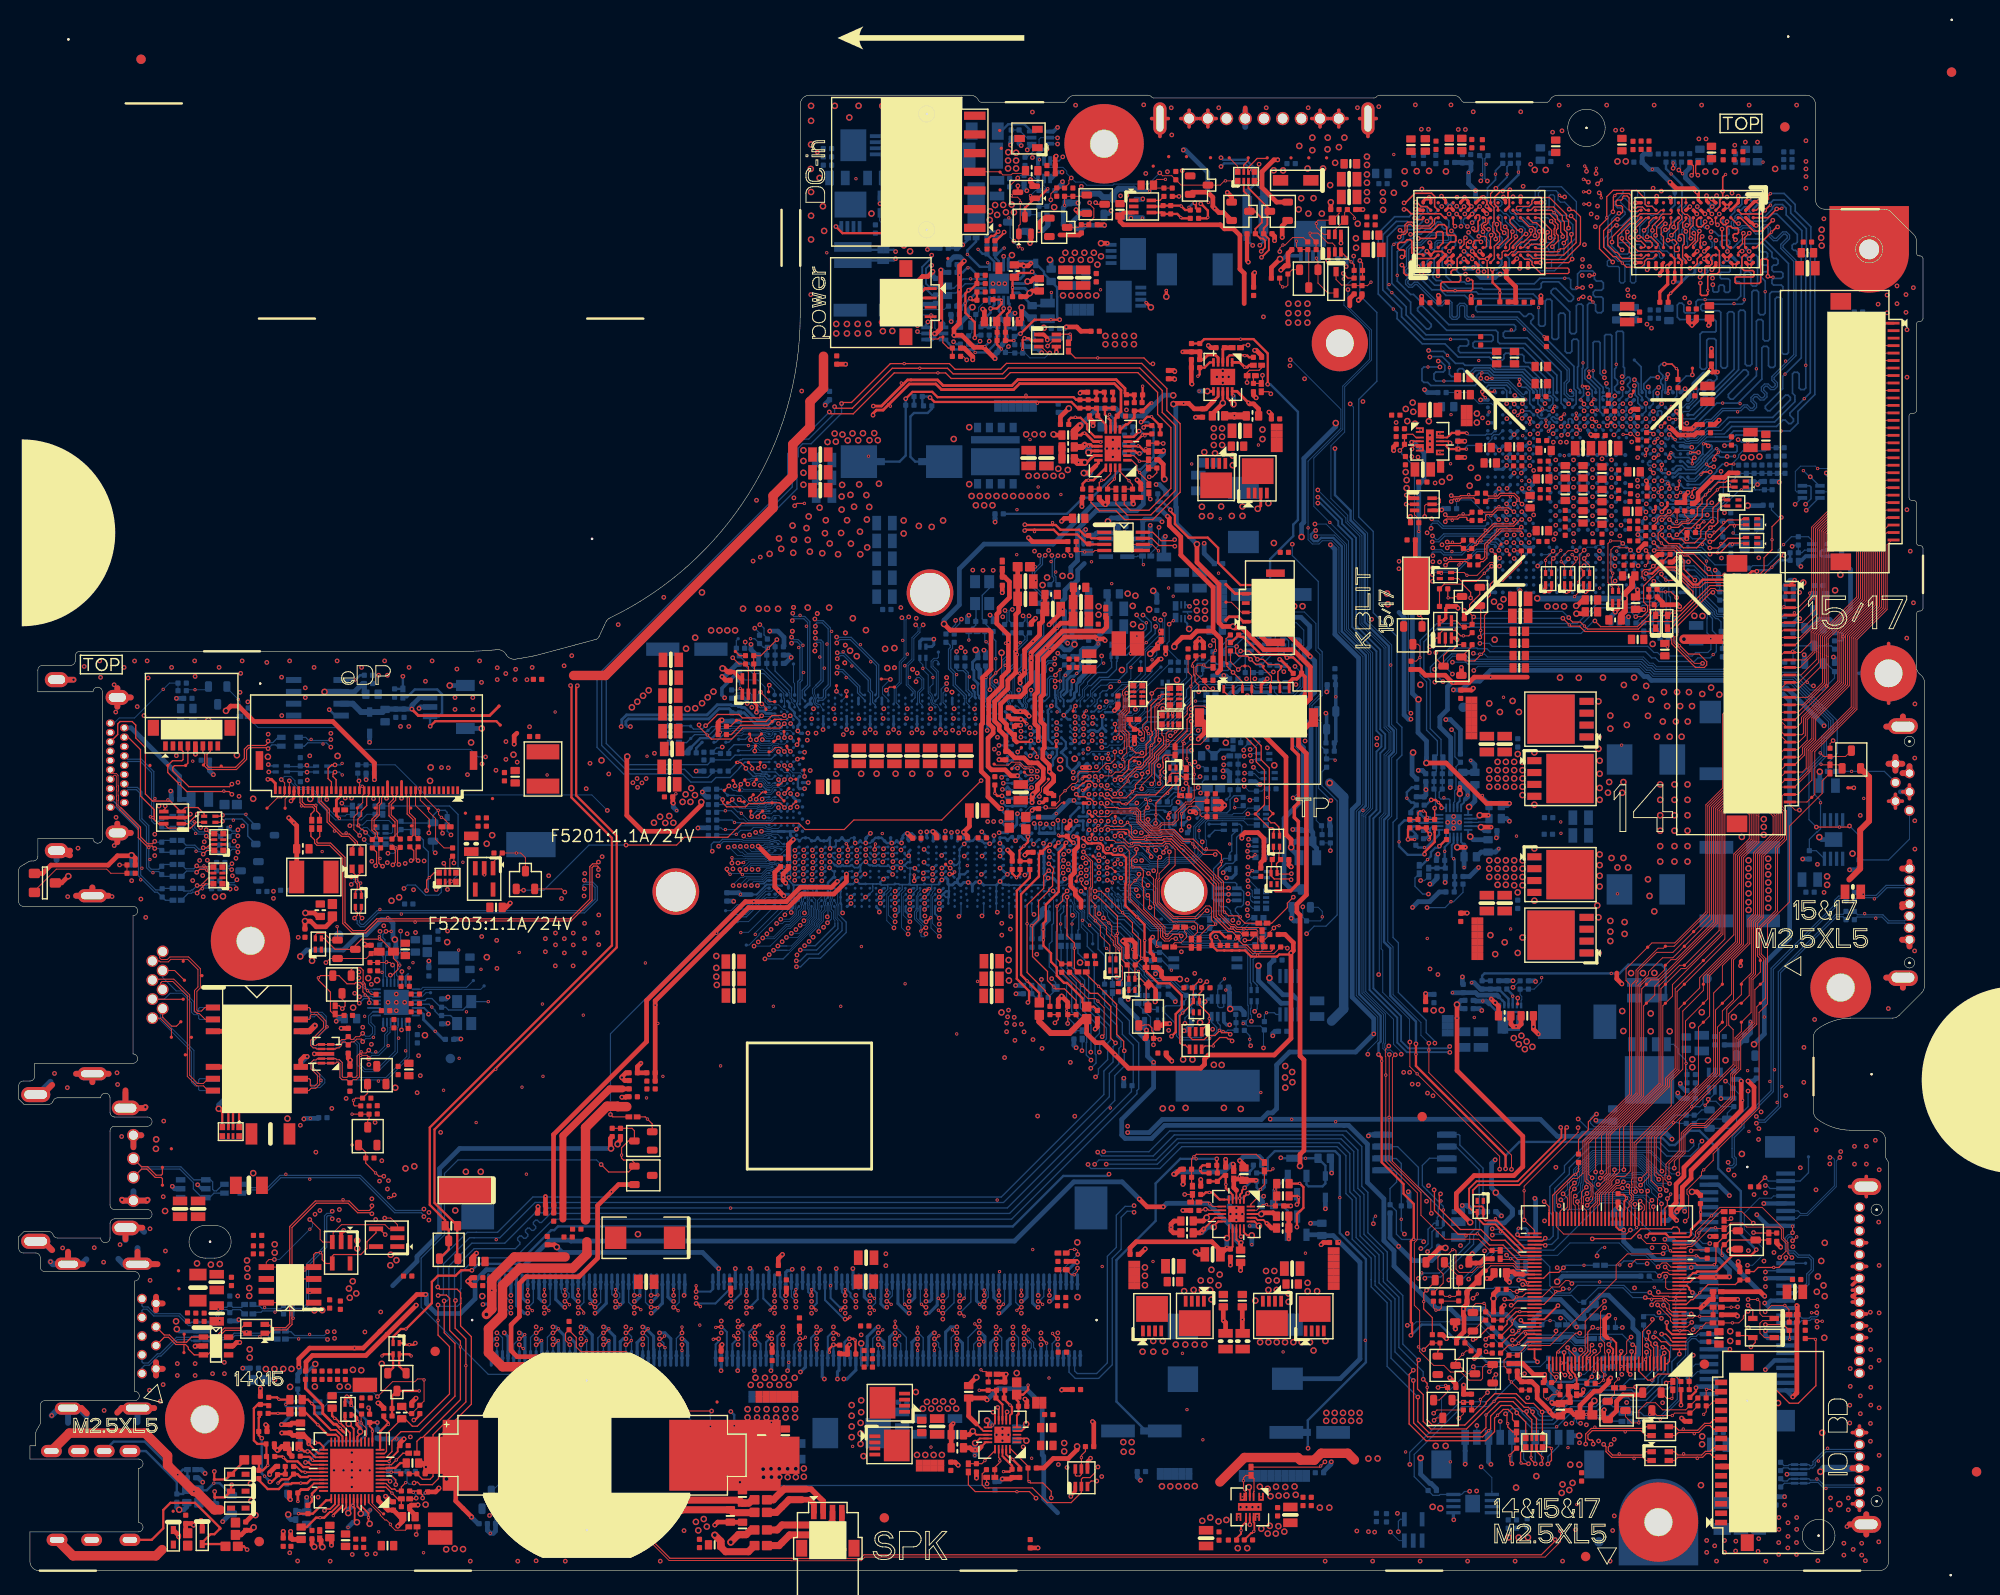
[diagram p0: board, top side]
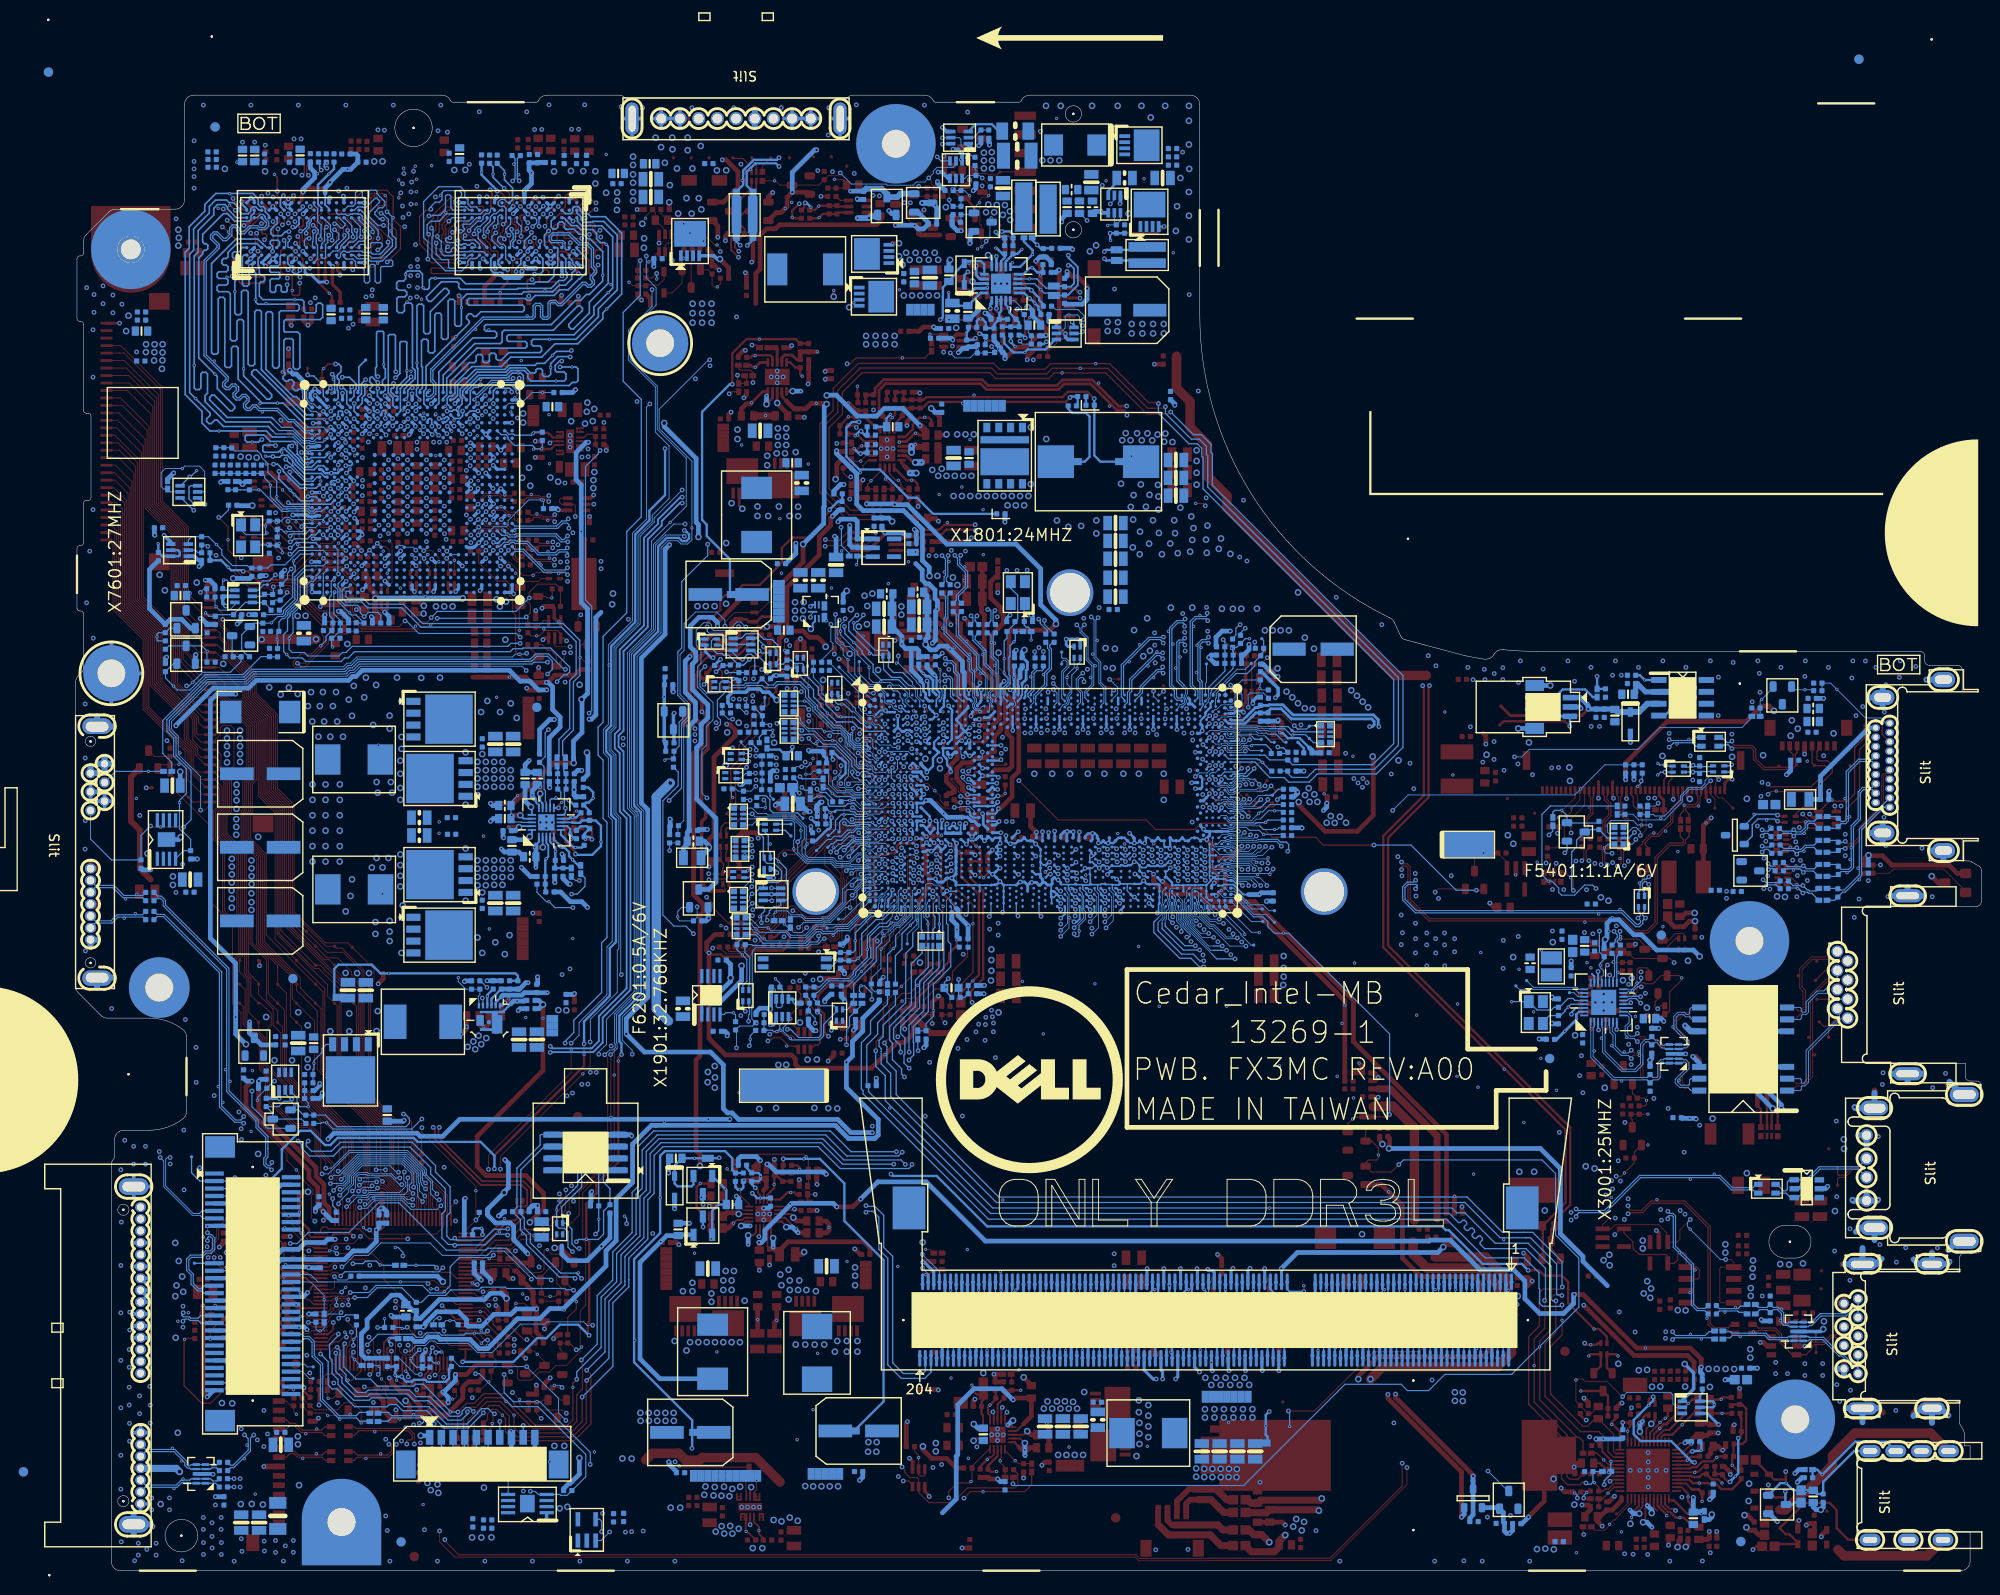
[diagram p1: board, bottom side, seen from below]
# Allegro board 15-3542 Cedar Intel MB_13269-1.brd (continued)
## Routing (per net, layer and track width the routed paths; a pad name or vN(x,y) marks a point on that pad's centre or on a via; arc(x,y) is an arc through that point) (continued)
+V1.05S_AXCK_DCB: length 24.8
  TOP w0.254: v1(108.28,88.82) 108.15,88.7 106.83,88.7 106.8,88.67 106.76,88.67
  TOP w0.508: L1103.2 112.8,105.2 C1125.1 C1112.1 112.35,101.4 111.47,101.4 108.3,98.23 v2(108.3,97.4) 108.3,95.14 107.66,94.5 107.66,94.04 107.13,93.52 105.82,93.52 105.03,92.72 105.03,91.19 105.67,90.55 105.67,90.14 106.35,89.46 C1111.1 106.51,88.92 106.76,88.67
  BOTTOM w0.305: CPU1.J18 108.61,88.49 v1(108.28,88.82) 108.2,88.74 CPU1.K19
+V1.05S_AXCK_LCPLL: length 18.2
  TOP w0.508: L1104.2 C1114.1 109.52,102.66 109.52,101.61 109.22,101.31 C1113.1 109.2,100.13 107.59,98.53 v2(107.59,96.38) 107.59,96.01 107.11,95.53 v1(107.11,95)
  L4 w0.508: v1(107.11,95) 103.61,98.51 v1(103.24,98.51)
  BOTTOM w0.229: v1(107.11,95) 107.11,94.82 107.44,94.49 107.44,94.06 107.37,93.99 CPU1.A20
  BOTTOM w0.508: v1(103.24,98.51) 103.42,98.33 R1803.2
+V1.05S_CORE_PCH: length 4.2
  BOTTOM w0.254: CPU1.H15 110.72,89.14 v1(111.02,89.45)
  BOTTOM w0.305: v1(114.53,80.24) 114.31,80.02 CPU1.AE8 ; v1(106.84,81.01) 106.76,80.93 106.76,79.85 CPU1.AF22 ; CPU1.H11 112.83,88.8 v1(112.96,88.8) 112.66,88.49 CPU1.J11
  vias: v2(111.07,91.9) v2(116.05,97.12) v3(111.4,86.74) v3(111.39,85.86)
+V1.05S_SSCF100: length 19.9
  TOP w0.508: R2117.2 116.37,102.02 C2137.1 116.37,100.97 115.95,100.55 111.65,100.55 v2(109.85,98.76) 108.99,97.89 108.99,94.03 108.69,93.73 108.69,90.62 109.06,90.25 v1(109.06,88.82)
  BOTTOM w0.254: v1(109.06,88.82) 109.3,88.82 CPU1.J17
+V1.05S_SSCFF: length 28.6
  TOP w0.508: v1(106.84,85.07) 106.15,85.07 105.52,85.7 104.06,85.7 103.69,86.07 103.69,89.09 104.23,89.63 104.23,90.18 103.76,90.66 103.76,93.25 105.17,94.66 105.17,95.62 105.87,96.32 v2(105.87,99.33) 105.87,100.13 104.62,101.37 104.62,102.34 104.87,102.59 104.87,103.02 105.98,104.13 105.98,105.82 105.46,106.34 C2138.1 105.21,106.35 R2118.2
  BOTTOM w0.254: CPU1.R21 107.21,85.44 v1(106.84,85.07) 106.85,85.07 107.21,84.71 CPU1.T21
+V3.3A_1.5A_HDA: length 19.8
  TOP w0.254: R2108.2 109.17,61.82 v2(107.86,63.12) 107.22,63.76 107.22,72.39 109.13,74.3 109.13,76.62 C2116.1 109.42,76.88 110.03,77.5 110.12,77.5 v1(110.31,77.69)
  BOTTOM w0.254: v1(110.31,77.69) 110.8,78.19 CPU1.AH14
+V3.3A_DSW_P: length 61.8
  TOP w0.254: v1(107.95,60.81) 108.07,60.94 108.07,62.02 106.76,63.33 106.76,72.76 108.16,74.16 C2101.1 ; v1(123.31,57.19) 123.76,57.64 123.76,59.57 124.41,60.21 124.41,61.57 123.12,62.86 121.9,62.86 120.59,64.17 R2101.2 120.59,65.39 C2136.1 120.42,65.6 120.42,69.15 v2(119.62,69.95) 119.6,69.95 118.38,71.17 118.38,73.52 118.45,73.59 118.45,76.28 118.13,76.6 117.04,76.6 116.86,76.78 116.27,76.78 115.99,77.06 115.99,77.56 115.71,77.84 114.81,77.84 114.78,77.82 114.35,77.82 114.04,78.12 114.04,78.13 113.9,78.27 v1(113.9,78.39)
  L4 w0.254: v1(123.31,57.19) 122.85,57.19 122.67,57.37 121.83,57.37 121.8,57.33 120.94,57.33 120.85,57.24 120.43,57.24 120.13,57.54 120.13,57.64 119.46,58.31 117.07,58.31 114.56,60.81 v1(107.95,60.81)
  BOTTOM w0.254: v1(113.9,78.39) 113.85,78.34 113.34,78.34 CPU1.AH10
+V3.3A_PSUS: length 30.5
  TOP w0.508: v1(125.29,81.22) 125.78,81.22 v2(125.93,81.07)
  L3 w0.203: 113.93,81.67 116.99,81.67 117.4,81.26 116.86,80.73 114.31,80.73 113.93,81.1 113.93,81.67
  L3 w0.508: v1(125.29,81.22) 125.19,81.32 121.99,81.32 121.7,81.03 118.23,81.03 118,81.26 117.4,81.26 ; v1(112.88,82.43) 113.17,82.43 113.93,81.67
  BOTTOM w0.254: CPU1.AC9 CPU1.AA9
  BOTTOM w0.305: v1(112.88,82.43) 113.17,82.14 CPU1.AA9
  BOTTOM w0.356: CPU1.AE21 107.31,79.79 CPU1.AE20 108.02,80.19 108.45,80.62 108.95,80.62
  BOTTOM w0.508: R1103.2 127.2,83.1 127.05,82.95 127.05,82.81 C1108.1 125.46,81.22 v1(125.29,81.22) ; v1(112.88,82.43) 112.4,82.43 110.6,80.62 108.95,80.62
+V3.3S_1.8S_LPSS_SDIO: length 14
  TOP w0.254: v1(114.52,84.98) 113.99,84.98 113.75,84.74 v2(113.75,84.73) ; R2103.1 118.84,90.55 C2104.1 119.68,90.05 119.98,89.75 v1(119.98,89.57)
  L4 w0.254: v1(119.98,89.57) 120.35,89.57 120.73,89.19 120.73,88.75 120.38,88.41 120.09,88.41 118.56,86.88 118.56,86.07 118.1,85.61 116.86,85.61 116.68,85.43 116.18,85.43 116.09,85.52 115.49,85.52 115.47,85.5 114.94,85.5 114.52,85.08 v1(114.52,84.98)
  BOTTOM w0.254: CPU1.T9 113.87,85 114.47,85 114.49,84.98 v1(114.52,84.98) 114.52,84.73 CPU1.U8
+V3.3S_PCORE: length 21.2
  TOP w0.254: v1(114.48,84.04) 113.96,83.51 v2(113.8,83.51)
  L3 w0.203: v1(114.48,84.04) 114.66,83.87 114.66,83.82 114.94,83.55 115.35,83.55 115.36,83.55 116.93,83.55
  L3 w0.254: v1(127.18,88.13) 126.95,88.36 124.25,88.36 123.93,88.04 122.17,88.04 119.95,85.83 119.59,85.83 119.04,85.27 119.04,84.51 118.26,83.73 117.11,83.73 116.93,83.55
  BOTTOM w0.254: v1(127.18,88.13) 127.18,87.89 C2123.1 128.52,87.87 129.75,87.87 R2112.2 ; v1(114.48,84.04) 114.48,83.74 CPU1.V8 114.23,83.57 113.86,83.2 CPU1.W9
+VCCIOA_OUT: length 2.8
  TOP w0.305: v1(107.2,91.12) 107.36,91.12 v2(107.84,90.64)
  TOP w0.508: v1(107.2,91.12) 107.17,91.14 106.17,91.14 R801.1
  BOTTOM w0.305: CPU1.E20 107.3,91.1 107.28,91.12 v1(107.2,91.12)
+VCCRTCEXT: length 13.9
  TOP w0.254: v2(123.14,81.12) 122.98,80.96 v1(122.98,80.59)
  L3 w0.203: 117.02,79.57 116.84,79.75 115.37,79.75 115.17,79.96 v1(115.17,80.23)
  L3 w0.254: 117.02,79.57 118.22,79.57 118.33,79.68 120.24,79.68 120.51,79.41 122.22,79.41 122.98,80.17 v1(122.98,80.59)
  BOTTOM w0.254: v1(122.98,80.59) 123.07,80.5 123.07,79.56 123.28,79.35 123.4,79.35 124.67,78.08 C2110.1 ; v1(115.17,80.23) 115.17,79.97 CPU1.AE7
GND: length 1554.7
  TOP w0.152: v1(112.8,83.72) 113.26,83.72 113.81,84.27 113.94,84.27 114.17,84.5 114.69,84.5 v1(115.15,84.04) ; v1(115.14,82.14) 114.66,82.62 114.32,82.62 114.12,82.82 113.4,82.82 v1(113.13,83.09)
  TOP w0.203: v1(105.72,16.99) 105.63,16.9 PU4901.7 ; HDA27.4 39.56,9.74 v1(39.72,9.57) ; PU4901.4 107.26,14.95 107.77,15.45 v3(107.77,15.69) ; v1(104.21,16.96) 104.43,16.74 PU4901.10 ; v1(179.04,29.76) 178.7,30.1 178.7,30.26 178.46,30.5 KBC24.18 ; v1(153.11,120.69) 152.93,120.86 U8301.11 ; v1(160.68,26.8) 160.98,26.5 KBC24.89 ; KBC24.5 176.85,25.3 176.28,25.87 v1(176.28,26.56) ; KBC24.116 171.29,23.06 171.43,23.2 171.43,23.46 v1(171.41,23.47) ; v1(160.45,31.11) 160.47,31.13 161.05,31.13 161.28,30.9 KBC24.78 ; KBC24.45 171.29,38.7 v1(171.21,38.79) ; U3601.11 v1(131.69,4.92)
  TOP w0.254: EC6103.2 179.42,19.2 v1(179.42,19.58) ; PR4617.2 120.52,122.54 120.33,122.36 v1(120.33,122.35)
  TOP w0.305: v1(78.92,91.86) 78.92,92.05 78.96,92.09 78.96,92.61 78.7,92.87 U701.3 ; SW1.1 96.95,137.2 96.57,136.82 v1(96.42,136.82) ; SW1.2 96.43,136.2 v1(96.41,136.18) ; v1(153.08,145.99) 153.04,145.99 VRAM4.D8 ; v1(29.13,82.38) 29.44,82.68 29.44,83.39 29.45,83.4 LCD1.36 ; TPAD1.5 132.9,94.79 v1(133.55,95.45) ; v1(134.87,97.53) 134.92,97.48 135.01,97.48 135.93,96.56 135.93,96.43 R6211.2 ; RN7404.2 168.04,105.07 167.74,104.77 v1(167.6,104.77) 167.39,104.98 RN7404.1 ; 40.95,84.46 LCD1.13 v1(40.95,82.66) ; v1(163.19,104.78) 163.2,104.77 163.78,104.77 163.97,104.97 RN7402.2 ; AFTP6245.1 v1(196.3,83.78) ; 121.61,62.14 121.61,62.24 G1901.1 ; v1(154.67,146.95) 155.04,146.58 VRAM4.G9 155.04,146.35 v1(155.4,145.99) 155.04,145.63 VRAM4.G8 ; KB1.1 189.46,105.46 189.97,105.97 v1(189.97,105.99) ; KB2.1 v1(199.14,133.5) ; LCD1.29 v1(32.95,82.54) ; RN7401.2 166.01,104.97 165.81,104.77 v1(165.55,104.77) 165.36,104.97 RN7401.1 ; 39.45,84.44 LCD1.16 39.45,82.76 v1(39.35,82.66) ; v1(37.95,82.62) 37.95,82.62 LCD1.19
  TOP w0.356: v1(156.28,141.19) 156.64,140.83 VRAM4.J2 ; v1(172.95,139.97) 172.95,139.96 172.93,139.94 172.91,139.94 172.96,139.99 VRAM1.T9 ; VRAM4.E1 153.42,139.99 v1(153.04,140.38) ; VRAM1.M9 176.35,139.6 v1(176.35,139.56) 176.35,139.07 176.39,139.03 176.39,137.67 175.55,136.83 R7808.1 ; VRAM4.T1 v1(162.77,139.99) ; VRAM1.T1 v1(172.95,146.39) ; v1(184.18,64.73) 184.18,65.21 AFTP6201.1 ; VRAM1.A9 185.53,139.99 v1(185.14,139.6) 184.75,139.99 VRAM1.B9 ; VRAM4.M1 159.04,139.51 v1(158.92,139.4) ; v1(153.86,99.63) 153.68,99.81 U7301.3 ; VRAM1.M1 176.74,146.83 v1(176.65,146.92) ; v1(150.93,142.12) 151.04,142.01 VRAM4.B3 ; VRAM4.P9 160.64,147.03 v1(160.65,147.04) ; VRAM4.T9 162.82,146.39 v1(162.86,146.43) ; v1(158.8,147.01) 158.8,146.91 158.92,146.79 158.92,146.77 159.04,146.65 VRAM4.M9 ; v1(153.08,145.99) 153.44,145.63 VRAM4.E8 ; VRAM1.G8 180.71,140.79 180.31,140.39 v1(180.3,140.39) 180.32,140.37 180.33,140.37 180.71,139.99 VRAM1.G9 ; v1(160.56,139.37) 160.64,139.45 VRAM4.P1 ; v1(153.04,140.38) 152.65,139.99 VRAM4.D1 ; v1(153.04,140.38) 153.44,140.78 VRAM4.E2 ; v1(179.55,141.2) 179.14,140.79 VRAM1.J8 ; VRAM1.E1 182.75,145.98 v1(182.75,145.98) ; VRAM1.P1 175.21,146.46 v1(175.21,147.09) ; VRAM4.B9 151.04,146.77 v1(150.87,146.94) 150.74,146.81 150.52,146.81 150.24,146.54 VRAM4.A9 ; VRAM1.B3 185.27,144.26 185.37,144.26 185.67,143.96 v1(185.85,143.96) ; VRAM4.F9 154.24,146.45 154.67,146.87 v1(154.67,146.95) ; v1(182.75,145.98) 182.36,145.59 VRAM1.E2 ; v1(182.75,145.98) 183.14,146.37 VRAM1.D1 ; v1(180.54,147.15) 180.54,147.06 180.55,147.06 180.55,146.58 VRAM1.G1 ; v1(157.03,145.21) 156.65,145.59 156.64,145.59 VRAM4.J8 ; VRAM1.J2 179.14,145.58 179.5,145.21 v1(179.5,145.19) ; RN7403.1 170.49,102.88 v1(170.79,102.58) 171.14,102.93 RN7403.2 ; v1(181.11,139.22) 181.11,139.22 181.54,139.65 VRAM1.F9 ; v1(163.19,104.78) 163.19,105.02 163.32,105.15 RN7402.1 ; VRAM1.P9 v1(175.14,139.39) ; THM26.5 119.03,109.18 117.27,110.94 v1(117.27,111.12) ; VRAM1.D8 183.14,140.78 v1(182.73,140.36) 182.34,140.75 VRAM1.E8 ; VRAM1.B1 184.74,146.56 v1(185.09,146.91) ; VRAM4.B1 150.84,139.79 v1(150.84,139.42) ; v1(154.6,140.39) 154.63,140.39 155.03,139.99 VRAM4.G1
  TOP w0.381: 125.2,154.51 BAT1.9 ; BAT1.9 124.31,155.4 ; BAT1.9 125.2,156.29 ; BAT1.9 126.09,155.4 ; BAT1.10 145.21,155.4 ; BAT1.10 144.32,153.48 ; BAT1.10 143.44,155.4 ; BAT1.8 127.2,156.29 ; BAT1.8 128.09,155.4 ; BAT1.8 126.31,155.4 ; BAT1.8 127.2,154.51 ; 196.14,24.94 HDD1.P4 197.66,24.94 ; HDD1.S7 197.66,14.78 ; HDD1.S7 196.14,14.78 ; HDD1.S7 196.9,15.47 ; 197.66,27.48 HDD1.P6 196.14,27.48 ; v1(112.54,7.94) 112.54,8.04 113.02,8.52 Q3601.1 ; 200.02,92.84 S1.1 200.02,99.22 ; C2128.2 109.58,82.21 v1(109.17,82.21) ; 195.85,41.11 HDD1.24 ; HDD1.24 197.63,40.03 ; HDD1.24 197.63,42.19 ; 197.66,32.56 HDD1.P10 196.14,32.56 ; 197.66,26.21 HDD1.P5 196.14,26.21 ; 196.14,7.16 HDD1.S1 196.9,6.46 ; v1(114.65,12.03) 114.32,11.7 Q3601.4 ; 121.19,155.4 BAT1.11 ; BAT1.11 122.96,155.4 ; BAT1.11 122.07,153.48 ; PQ8305.4 152.17,113.47 v1(152.22,113.53) ; C1116.2 108.59,81.54 v1(108.4,81.36) ; PQ4410.1 140.14,140.33 v1(140.03,140.23) ; v1(121.3,67.8) 121.05,67.55 121.05,66.18 121.32,65.91 121.37,65.91 121.37,65.54 C2136.2 ; v1(167.36,19.37) 167.36,19.07 167.12,18.83 R2435.1 ; 196.14,35.1 HDD1.P12 197.66,35.1
  TOP w0.406: v1(31.62,55.31) 31.63,55.31 U3102.8 ; PQ4410.4 v1(141.44,142.07) ; v1(148.43,115.11) 148.77,114.77 PQ8305.1 ; v1(111,130.41) PQ4408.4 ; PQ4408.1 109.64,132.29 110.02,131.91 v1(110.02,131.71) ; v1(34.76,36.4) 34.49,36.14 U3504.2
  TOP w0.457: EC4302.2 131.39,142.08 131.39,142.08 131.39,140.18 v1(131.53,140.04) ; C1102.2 121.99,97.56 v1(122.2,97.56) ; C2105.2 v1(122.69,98.09)
  TOP w0.508: EC3107.1 35.25,54.84 v1(35.46,54.63) 35.43,54.61 EC3106.1 ; PC4604.2 110.77,121.53 v3(110.69,121.61) ; v1(158.88,28.38) 158.65,28.14 C2418.2 ; v1(173.28,109.16) 173.28,109.25 173.9,109.87 C7728.2 ; C1113.2 108.31,101.47 v1(108.76,101.92) ; R2026.2 128.58,81.5 v1(128.99,81.92) 128.58,82.32 R1511.2 ; v1(134.34,142.33) 134.34,142.79 EC4301.2 ; v1(104.87,86.79) 104.88,86.78 C1109.2 ; v1(173.16,104.97) 173.17,104.95 173.17,104.43 C7719.2 ; 121.61,62.14 121.61,60.93 v1(121.56,60.88) ; C2109.2 115.39,58.6 115.37,58.58 115.37,58.18 v1(115.15,57.96) ; C1111.2 106.64,90.48 v1(107.17,90.48) ; v1(105.2,104.67) 105.21,104.68 C2138.2 ; PR4817.1 132.96,130.02 132.38,130.6 v1(132.2,130.6) ; R7637.2 175.39,108.76 175.19,108.57 175.13,108.57 174.92,108.36 v1(174.92,108.34) ; R3605.2 154.56,18.89 C3604.2 v1(154.56,19.86) ; C2718.2 43.13,11.52 v1(43.55,11.09) 43.55,10.71 43.48,10.63 EC2709.2 ; PQ4204.E 108.28,142.2 108.16,142.08 v1(108.19,142.05) ; v1(105.79,77.12) 106.27,76.64 C2114.2 ; C1206.2 48.43,31.36 v1(48.04,30.97) 48.51,30.51 C1204.2 ; C2116.2 107.92,76.88 v1(107.63,76.59) ; C7820.2 160.12,135.78 ; 160.12,135.78 160.12,137.41 159.11,138.41 159.11,139.18 159.02,139.27 159.02,139.3 v1(158.92,139.4) ; 160.12,135.78 R7912.1 ; v1(124.53,41.34) 124.57,41.38 PR4530.2 ; EC3108.1 v1(34.49,58.04) ; PC4815.2 125.91,123.44 v1(125.89,123.42) ; v3(166.63,102.42) 167.38,102.42 C7603.2 ; v1(132.2,138.9) 132.09,138.79 EC9701.2 ; C7501.2 172.6,124.28 172.41,124.09 v1(172.41,124.06) ; v1(83.55,25.45) 83.51,25.49 C1220.2 ; v1(125.5,126.99) 125.44,127.06 PR4824.2 PR4823.2 ; v1(117.22,92.05) 117.57,92.4 117.57,92.5 117.59,92.52 C1101.2 ; v1(107.64,18.36) 107.83,18.17 PC4918.2 ; v1(183.93,33.07) 183.93,32.71 184.11,32.52 C2422.2 ; v1(52.58,71.44) 52.12,70.98 C5204.2 ; R3709.2 64.84,52.45 v1(64.52,52.77) 64.52,52.84 64.96,53.28 R3707.2 ; C2104.2 119.35,88.5 v1(119.36,88.48) ; ED2903.1 17.12,3.77 v1(17.12,3.62) ; C2401.2 v1(183.87,29.03) ; v1(82.85,78.24) 82.33,77.71 R407.1 ; C2416.2 171.08,38.92 v1(171.21,38.79) ; v1(79.1,77.53) 80.39,76.24 R408.1 ; v1(123.34,54.53) 122.74,55.13 C1120.2 ; C8316.2 v1(154.68,120.87) ; v3(102.44,20.69) 101.62,19.87 PC4901.2 ; C702.2 75.62,95.29 v1(75.23,95.67) ; EC9714.2 149.4,105.2 SPR3.1 ; v1(177.87,16.32) 178.22,15.98 EC6105.2 ; v1(155.59,94.44) 155.59,94.43 155.4,94.24 EC9711.2 ; v1(102.45,9.91) 102.45,10.05 102.44,10.05 PC4906.2 ; v1(123.11,58.54) 122.47,58.54 122.29,58.35 Q1901.S ; LIDSW1.1 4.58,73.6 v3(5.31,74.32) ; C1115.2 101.7,79.66 v1(101.07,79.03) 101.5,78.6 C1018.2 ; C2717.2 39.84,7.37 v1(39.25,7.96) ; PC4902.2 PC4903.2 105.48,20.9 v1(105.61,21.02) PR4906.2 ; EC9709.2 111.61,19.38 v1(111.57,19.34) ; R1204.2 64.37,46.08 64.06,45.76 v3(64.06,45.64) ; C2601.2 111.86,112.62 v1(111.55,112.31) ; KBLIT1.5 133.56,99.35 132.93,99.98 v1(132.93,101.03) ; v3(112.33,124.38) 111.43,123.48 PR4607.1 ; v1(153.69,25.87) 153.65,25.92 Q2404.C ; v3(125.92,34.1) 126.17,33.85 PC4519.2 ; EC1801.2 111.2,61.13 v1(111.56,61.49) 111.68,61.37 111.68,61.36 112.21,60.83 EC1802.2 ; v1(137.59,90.11) 138.5,91.03 TPAD1.10 ; C7515.2 v1(155.37,136.41) ; v1(181.88,123.12) 181.43,122.66 R7507.1 ; C1211.2 80.59,24.14 v1(80.55,24.18) ; C2411.2 157.82,31.64 157.44,31.27 v1(157.05,31.27) ; C7829.2 v1(162.83,136.43) ; D4301.1 135.15,143.91 135.15,142.69 v1(135.15,142.69) ; C2704.1 28.97,7.7 v1(29.06,7.61) ; v3(152.61,34.54) 152,34.54 150.53,33.08 Q2403.S ; v1(181.07,130.78) 181.07,130.78 R7506.2 ; v1(48.97,33.98) 48.56,33.57 C1205.2 ; C8305.2 v1(154.68,119.14) ; v1(102.05,129.59) 102.05,129.92 101.13,130.84 EC6104.2 ; PC4606.2 120.03,116.33 v1(119.63,116.73) ; R3711.2 55.55,38.33 v1(55.55,38.96) ; EC9704.2 139.55,35.12 v1(139.32,34.89) ; v1(180.77,133.27) 180.85,133.35 C7916.2 ; C7910.2 v1(150.07,136.38) ; C1114.2 111.45,102.47 v1(110.22,101.23) ; C2421.2 188.05,35.04 v1(188.47,34.62) ; EC9710.2 119.92,33.85 v1(120.5,34.44) ; v1(152.72,24.83) 152.3,25.26 R3602.2 ; C2716.2 42.4,5.95 41.82,6.53 EC2701.2 41.98,7.02 42.68,7.02 v1(42.71,7.04) ; v1(133.74,123.98) 134,123.72 EC9713.2 ; EC9706.2 v1(88.45,129.11) ; C7921.2 151.92,136.41 v1(151.86,136.47) ; C6201.2 132.87,75.76 EC6201.2 133.2,78.35 132.56,78.99 131.16,78.99 130.83,78.66 v1(130.83,78.39) ; v1(42.5,18.46) 42.04,18 C2901.2 ; v1(113.1,145.64) 113.1,145.6 113.46,145.25 PQ4414.S ; v1(75.23,24.18) 75.13,24.08 C1222.2 ; v1(114.92,122.54) 114.92,122.95 114.54,123.33 PR4707.2 ; v1(82.05,29.46) 82.12,29.53 C1210.2 ; v3(166.6,103.26) 166.69,103.26 167.32,103.88 C7604.2 ; v1(112.06,133.1) 113.17,133.1 113.63,132.64 EC9740.2 ; PC4524.2 130.71,32.15 v1(130.7,32.15) ; C1020.2 95.58,78.39 v1(95.07,78.9) ; v1(53,88.46) 53,89.34 AFTP2803.1 ; EC9712.2 154.26,70.38 v1(154.94,70.38) ; v1(130.6,43.88) 131.06,43.43 PC4526.2 ; v1(38.43,17.94) 38.55,17.94 39.05,17.43 R2717.2 ; EC9702.2 v1(150.5,61.75) ; PC4531.2 v1(129.61,32.71) ; C1017.2 98.2,78.69 v1(97.79,79.1) ; v1(183.85,27.25) 183.72,27.38 R2447.2 ; R7628.1 178.21,114.31 R7602.2 178.21,115.04 v1(178.56,115.39) ; EC2902.2 76.14,5.18 EC2904.2 74.77,5.2 v1(74.46,4.89) ; R1509.1 126.73,99.32 v1(126.31,99.74) 125.92,99.34 EC1501.2 ; v1(112.46,80.24) 112.46,79.79 R1602.2 ; v1(136.12,75.33) 136.07,75.33 135.87,75.53 EC6202.2 ; C2723.1 44.59,8.43 44.94,8.79 v1(44.94,8.84) ; EC1703.2 37.12,66.93 v1(37,67.05) ; v1(64.52,50.67) 64.93,50.67 64.97,50.72 R3703.2 ; AFTP6235.1 170.94,63.34 v1(171.48,62.8) ; ED2902.1 19.63,5.25 v1(19.5,5.38) ; BAT1.6 131.2,156.55 ; R2442.2 v1(180.89,35.77) ; v1(100.49,11.28) 100.16,11.62 EC9703.2 ; v1(18.87,24.01) 18.89,24.01 18.92,24.05 U3403.2 ; PC4710.2 113.63,126.12 v1(113.54,126.02) ; v1(75.23,91.03) 75.08,91.03 74.81,90.76 R406.2 R402.2 ; v1(155.7,22.72) 156.24,23.27 C2610.2 ; v1(105.22,9.81) 106.1,9.81 PR4902.2 106.26,9.98 PR4908.1 ; C7913.2 179.45,133.75 v1(178.98,133.29) 178.61,133.66 C7922.2 ; R1902.2 120.64,57.09 v1(120.64,57.84) ; PR4464.2 135.77,140.97 135.77,139.67 PR4467.2 135.48,139.65 v1(135.01,139.18) ; PR4614.1 113.73,114.78 v1(113.73,113.89) ; PD4203.1 109.67,144.74 109.12,144.19 v1(109.12,143.4) ; R7601.2 178.43,111.07 v1(178.43,110.43) ; D4303.1 129.74,147.02 129.28,147.47 v1(129.28,147.48) ; PR4470.1 v1(143.79,145.67) ; v1(123.66,127.5) 123.6,127.55 EC9742.2 ; C1221.2 76.17,30.21 v1(76.17,29.46) ; EC9708.2 v1(109.03,2.44) ; C1902.2 118.56,66.92 v1(118.1,67.38) 118.22,67.49 119.06,67.49 119.43,67.12 C1901.2 ; v1(81.69,33.84) 81.26,33.4 C1213.2 ; PC4521.2 v1(136.07,39.03) ; PC4821.2 127.48,130.88 v1(127.25,131.11) ; PR4523.2 v1(129.11,44.01) ; R7306.2 v1(154.63,102.74) ; PR4517.2 v1(126.44,41.85) ; Q2401.S 183.09,34.4 182.93,34.24 v1(182.92,34.24) ; v1(126.17,88.99) 126.82,89.64 126.82,90.78 TPAD1.9
  TOP w0.61: CON1.7 v1(183.7,11.15)
  TOP w0.635: v1(13.79,39.69) 13.7,39.6 USB2.4 11.15,39.6 v1(11.05,39.7) ; 200.75,85.61 ODD1.6 ; ODD1.6 200.01,86.35 ; ODD1.6 200.75,87.09 ; ODD1.6 201.49,86.35 ; 196.14,10.97 HDD1.S4 197.66,10.97 ; RJ45.9 9.62,53.18 ; RJ45.9 7.88,52.29 ; RJ45.9 6.14,53.18 ; HDMI1.20 11.99,78.95 ; HDMI1.20 10.55,77.96 ; HDMI1.20 10.55,79.94 ; 6.14,72.23 RJ45.10 ; RJ45.10 9.62,72.23 ; RJ45.10 7.88,73.11 ; HDMI1.21 10.55,94.44 ; HDMI1.21 11.99,93.45 ; HDMI1.21 10.55,92.46 ; 202.25,66.81 ODD1.S1 201.46,67.52 ; 14.69,20.89 USB1.4 ; USB1.4 14.69,22.31 ; USB1.4 15.4,21.6 ; 5.49,77.05 HDMI1.22 5.49,76.55 ; 202.25,86.09 ODD1.5 201.51,85.35 ; 197.63,3.88 HDD1.23 ; HDD1.23 197.63,6.04 ; HDD1.23 195.85,4.96 ; USB2.7 2.64,35.25 3.58,34.31 ; 6.87,32.8 USB1.12 5.28,34.13 ; 11.42,51.39 USB2.6 13.44,49.5 v1(13.55,49.61) ; USB1.13 6.72,17.4 7.29,16.83 ; 201.55,62.39 ODD1.15 199.77,63.47 ; 202.25,75.85 ODD1.S7 201.46,75.14 ; 10.54,16.91 11.03,17.4 USB1.11 14.49,17.4 ; 201.46,70.97 ODD1.S4 201.46,71.33 ; 199.77,90.33 ODD1.14 201.55,91.41 ; 11.42,35.47 USB2.5 13.23,36.7 ; USB2.8 2.54,50.95 3.58,51.99 ; HDMI1.23 v1(5.87,95.35) ; 12.71,34.14 USB1.10 14.85,32.8
  L3 w0.127: v1(170.74,122.49) 170.52,122.49 170.04,122.01 167.96,122.01 v1(167.5,122.47) ; v1(83.99,76.47) 84.41,76.9 84.41,77.62 84.39,77.64
  L3 w0.203: v1(82.85,78.24) 83.79,78.24 84.39,77.64
  L3 w0.305: v1(167.5,122.47) 167.5,121.77 165.81,120.08 163.4,120.08 162.77,120.72 161.64,120.72 v1(161.62,120.69)
  L3 w0.381: BAT1.10 145.21,155.4 ; BAT1.10 144.32,153.48 ; BAT1.10 143.44,155.4 ; HDD1.S7 197.66,14.78 ; HDD1.S7 196.9,15.47 ; HDD1.S7 196.14,14.78 ; BAT1.8 127.2,156.29 ; BAT1.8 127.2,154.51 ; BAT1.8 128.09,155.4 ; BAT1.8 126.31,155.4 ; 124.31,155.4 BAT1.9 ; BAT1.9 125.2,156.29 ; BAT1.9 125.2,154.51 ; BAT1.9 126.09,155.4 ; 122.96,155.4 BAT1.11 121.19,155.4 ; 197.66,32.56 HDD1.P10 196.14,32.56 ; S1.1 201.89,96.03 ; S1.1 198.15,96.03 ; S1.1 200.02,94.16 ; S1.1 200.02,97.9 ; 195.89,41.11 HDD1.24 ; HDD1.24 197.63,42.15 ; HDD1.24 197.63,40.06 ; S2.1 143.19,131.36 ; S2.1 141.32,129.49 ; S2.1 139.45,131.36 ; S2.1 141.32,133.23 ; 196.14,7.16 HDD1.S1 196.9,6.46 ; 197.66,24.94 HDD1.P4 196.14,24.94 ; 197.66,27.48 HDD1.P6 196.14,27.48 ; 197.66,26.21 HDD1.P5 196.14,26.21 ; 197.66,35.1 HDD1.P12 196.14,35.1
  L3 w0.635: RJ45.10 7.88,73.11 ; RJ45.10 9.62,72.23 ; RJ45.10 6.14,72.23 ; HDMI1.11 10.47,86.7 ; 201.46,71.33 ODD1.S4 201.46,70.97 ; 10.36,33.44 11,32.8 USB1.10 ; 199.81,90.33 ODD1.14 201.55,91.41 ; 201.51,85.35 ODD1.5 ; ODD1.5 202.25,84.61 ; ODD1.5 202.25,86.09 ; USB1.12 5.28,33.9 ; USB1.12 3.66,32.8 v1(3.4,33.06) ; USB1.12 6.69,32.8 7.41,33.52 ; 5.64,16.24 5.28,16.6 USB1.13 6.64,17.4 7.41,16.63 ; USB2.4 12.27,40.76 ; USB2.4 13.7,39.6 v1(13.79,39.69) ; USB2.4 11.15,39.6 v1(11.05,39.7) ; HDMI1.17 10.49,89.7 ; 201.46,75.14 ODD1.S7 202.25,75.85 ; 13.41,36.16 12.87,36.7 USB2.5 11.42,35.42 ; 3.73,52.14 2.54,50.95 USB2.8 ; 201.55,62.39 ODD1.15 199.81,63.47 ; USB1.11 11.11,17.4 10.69,16.98 ; USB1.11 14.8,17.4 ; USB1.11 12.71,16.06 ; USB1.10 14.85,32.8 ; USB1.10 12.71,34.83 ; HDMI1.5 10.5,83.7 ; USB1.4 14.69,22.31 ; USB1.4 14.69,20.89 ; USB1.4 15.4,21.6 ; 4.05,76.06 HDMI1.22 5.49,77.05 ; USB1.7 14.18,25.1 ; ODD1.6 200.75,87.09 ; ODD1.6 200.01,86.35 ; ODD1.6 200.75,85.61 ; ODD1.6 201.49,86.35 ; 10.55,92.46 HDMI1.21 ; HDMI1.21 11.99,93.45 ; HDMI1.21 10.55,94.44 ; HDMI1.20 10.55,79.94 ; HDMI1.20 10.55,77.96 ; HDMI1.20 11.99,78.95 ; 131.2,154.51 BAT1.6 131.2,156.29 ; 195.89,4.96 HDD1.23 ; HDD1.23 197.63,3.91 ; HDD1.23 197.63,6 ; 201.46,67.52 ODD1.S1 202.25,66.81 ; 7.88,52.29 RJ45.9 ; RJ45.9 6.14,53.18 ; RJ45.9 9.62,53.18 ; 10.65,85.2 HDMI1.8 11.95,85.2 ; HDMI1.2 11.95,82.2 ; HDMI1.2 11.3,81.63 ; HDMI1.2 10.65,82.2 ; 11.42,51.34 USB2.6 13.44,49.5 v1(13.55,49.61) ; USB2.7 2.43,35.25 3.5,34.18 ; 196.14,10.97 HDD1.S4 197.66,10.97 ; HDMI1.23 v1(5.87,95.35)
  L4 w0.152: v1(115.14,82.14) 115.13,82.14 114.68,82.6 113.62,82.6 v1(113.13,83.09)
  L4 w0.203: v1(83.99,76.47) 84.4,76.06 84.4,74.97 83.95,74.52 v1(83.92,74.52)
  L4 w0.381: 197.66,35.1 HDD1.P12 196.14,35.1 ; 197.66,26.21 HDD1.P5 196.14,26.21 ; 144.32,153.48 BAT1.10 ; BAT1.10 145.21,155.4 ; BAT1.10 143.44,155.4 ; 196.14,7.16 HDD1.S1 196.9,6.46 ; 196.14,24.94 HDD1.P4 197.66,24.94 ; HDD1.S7 196.9,15.47 ; HDD1.S7 196.14,14.78 ; HDD1.S7 197.66,14.78 ; 122.07,153.48 BAT1.11 ; BAT1.11 122.96,155.4 ; BAT1.11 121.19,155.4 ; 126.31,155.4 BAT1.8 ; BAT1.8 127.2,154.51 ; BAT1.8 127.2,156.29 ; BAT1.8 128.09,155.4 ; 196.14,27.48 HDD1.P6 197.66,27.48 ; 196.14,32.56 HDD1.P10 197.66,32.56 ; BAT1.9 125.2,156.29 ; BAT1.9 126.09,155.4 ; BAT1.9 125.2,154.51 ; BAT1.9 124.31,155.4 ; 197.63,40.06 HDD1.24 ; HDD1.24 195.89,41.11 ; HDD1.24 197.63,42.15
  L4 w0.635: 14.88,33.34 14.34,32.8 USB1.10 ; HDMI1.17 10.48,89.7 ; 10.65,85.2 HDMI1.8 11.95,85.2 ; 5.28,33.65 USB1.12 6.77,32.8 7.34,33.37 ; 5.49,77.05 HDMI1.22 4.05,76.06 ; 10.55,92.46 HDMI1.21 ; HDMI1.21 11.99,93.45 ; HDMI1.21 10.55,94.44 ; USB1.11 12.71,16.03 ; USB1.11 10.85,17.4 ; USB1.11 14.52,17.4 ; HDMI1.20 11.99,78.95 ; HDMI1.20 10.55,79.94 ; HDMI1.20 10.55,77.96 ; 7.29,16.58 6.47,17.4 USB1.13 5.28,16.2 ; RJ45.10 7.88,73.11 ; RJ45.10 9.62,72.23 ; RJ45.10 6.14,72.23 ; 10.61,33.42 11.23,32.8 USB1.10 ; 3.68,34.15 2.59,35.25 USB2.7 ; HDMI1.5 10.45,83.7 ; USB2.4 11.15,39.6 v1(11.05,39.7) ; USB2.4 12.27,40.81 ; USB2.4 13.7,39.6 v1(13.79,39.69) ; HDMI1.23 v1(5.87,95.35) ; USB2.8 2.09,50.95 3.48,52.34 ; 196.14,10.97 HDD1.S4 197.66,10.97 ; 13.18,36.49 12.97,36.7 USB2.5 11.42,35.48 ; 7.88,52.29 RJ45.9 ; RJ45.9 6.14,53.18 ; RJ45.9 9.62,53.18 ; 131.2,154.51 BAT1.6 131.2,156.29 ; HDMI1.2 11.95,82.2 ; HDMI1.2 10.65,82.2 ; HDMI1.2 11.3,81.63 ; 14.69,20.89 USB1.4 ; USB1.4 14.69,22.31 ; USB1.4 15.4,21.6 ; USB1.7 14.26,25.1 ; v1(13.55,49.61) 13.44,49.5 USB2.6 11.42,51.37 11.58,51.53 ; USB1.10 12.71,34.3 ; HDD1.23 197.63,6 ; HDD1.23 197.63,3.91 ; HDD1.23 195.89,4.96 ; HDMI1.11 10.44,86.7
  BOTTOM w0.102: CPU1.AN63 80.56,75.3 79.35,75.3 v1(79.09,75.04) ; CPU1.AJ63 79.77,77.76 79.63,77.61 79.18,77.61 v1(79.1,77.53)
  BOTTOM w0.127: v1(103.04,70.07) 103.23,70.26 CPU1.AY26 ; 91.35,73.5 91.35,73.19 91.36,73.17 91.36,72.75 CPU1.AV46 ; 94.54,73.42 94.51,73.39 94.51,72.89 94.2,72.58 94.2,72.44 CPU1.AV41 ; CPU1.AY18 108.36,70.47 v1(108.6,70.23) ; CPU1.AR39 CPU1.AP39 95.35,75.18 95.08,75.18 CPU1.AN40 ; CPU1.AV39 95.72,72.54 96.09,72.91 96.09,72.92 96.1,72.93 96.1,73.17 96.11,73.18 96.11,73.41 ; v1(112.72,70.13) 112.52,70.34 CPU1.AY11 ; v1(110.65,72.74) 110.63,72.72 109.68,72.72 CPU1.AV16 ; CPU1.AY22 105.93,71.41 105.93,70.2 v1(106.12,70.01) ; 97.66,73.43 97.66,73.43 97.66,72.87 97.42,72.62 97.42,72.51 CPU1.AV36 ; CPU1.AH49 89.36,78.43 89.05,78.43 CPU1.AJ50 ; CPU1.AY57 84.13,70.47 v1(84.05,70.39) ; CPU1.AY30 100.79,70.25 v1(100.57,70.03) ; CPU1.AV43 92.57,72.54 92.94,72.91 92.94,72.93 92.95,72.94 92.95,73.17 92.96,73.18 92.96,73.43 ; v1(104.68,70.46) 104.58,70.57 CPU1.AY24 ; CPU1.AY53 86.56,71.26 86.57,71.26 86.57,70.05 v1(86.49,69.97)
  BOTTOM w0.152: v1(79.45,79.13) 79.46,79.11 CPU1.AG63
  BOTTOM w0.178: v1(93.74,72.08) 93.39,71.74 CPU1.AW42 ; CPU1.AL36 97.23,76.8 v1(96.84,77.19) ; v1(79.52,82.57) 79.52,82.58 79.7,82.76 80.23,82.76 80.26,82.79 CPU1.Y63 ; CPU1.AU22 106.34,73.36 106.35,73.38 106.64,73.38 106.66,73.36 CPU1.AU20 ; CPU1.AT46 90.59,73.5 91.38,73.5 91.39,73.49 91.76,73.49 91.76,73.5 92.15,73.5 CPU1.AT43 92.27,73.39 92.92,73.39 92.96,73.43 93.67,73.43 CPU1.AT42 93.74,73.5 94.12,73.5 94.2,73.42 95.23,73.42 CPU1.AT40 ; CPU1.AN39 95.35,76.34 95.22,76.47 95.22,76.48 v1(95.2,76.51) 95.17,76.48 ; v1(108.56,77.75) 108.56,77.78 108.36,77.97 CPU1.AH19 108.27,78.24 108.14,78.11 107.77,78.11 107.65,78.24 CPU1.AH20 ; v1(89.59,74.5) 89.6,74.52 89.65,74.52 89.97,74.85 CPU1.AP48 ; v1(101.14,77.77) 100.63,77.27 CPU1.AL31 CPU1.AM31 CPU1.AN31 ; v1(116.46,72.84) 116.57,72.73 116.57,72.2 116.92,71.85 CPU1.AW4 ; CPU1.AU59 82.48,73.77 82.48,73.78 82.4,73.86 82.4,74.17 82.39,74.17 v1(82.39,74.18) 82.56,74.34 82.56,74.8 82.54,74.81 CPU1.AN60 82.54,75.74 82.56,75.76 82.56,76.04 82.54,76.06 CPU1.AL60 ; CPU1.AU59 CPU1.AV59 CPU1.AW59 82.57,71.74 82.57,71.74 ; CPU1.AU59 82.9,73.37 83.3,73.37 83.31,73.38 84.11,73.38 CPU1.AU57 84.14,73.37 84.54,73.37 84.56,73.38 84.84,73.38 84.86,73.37 85.34,73.37 CPU1.AU55 ; CPU1.D8 115.04,91.93 115.48,92.38 ; v1(86.74,76.52) 86.84,76.52 87.13,76.81 87.3,76.81 CPU1.AL52 ; CPU1.AY24 CPU1.AW24 CPU1.AV24 CPU1.AU24 104.56,73.38 103.24,73.38 CPU1.AU26 ; CPU1.AU55 85.83,73.36 85.85,73.38 86.14,73.38 86.15,73.36 CPU1.AU53 ; CPU1.AU55 CPU1.AV55 ; v1(82.85,78.24) 82.89,78.27 83.34,78.27 CPU1.AJ58 83.52,78.1 83.85,78.43 84.16,78.43 CPU1.AH57 84.17,78.43 84.49,78.43 CPU1.AJ56 ; CPU1.AL33 98.99,76.8 v1(98.73,76.54) ; CPU1.AM23 105.28,76.15 104.96,76.46 v1(104.96,76.47) ; CPU1.AT40 95.31,74.48 CPU1.AR39 ; CPU1.AT40 95.42,73.38 96.08,73.38 96.11,73.41 96.8,73.41 CPU1.AT37 96.95,73.43 98.39,73.43 CPU1.AT35 ; CPU1.AN31 100.31,75.5 CPU1.AN32 ; CPU1.AN31 CPU1.AP31 CPU1.AR31 ; CPU1.AJ25 104.32,78.09 104.03,77.8 v1(103.86,77.8) ; CPU1.AJ47 90.02,78.1 ; 90.02,78.1 90.02,78.1 ; 90.02,78.1 90.02,78.09 90.24,77.87 v1(90.6,77.87) 91.09,77.87 CPU1.AJ45 ; CPU1.AN49 89.4,75.24 89.78,75.24 CPU1.AN48 90.4,75.86 v1(90.62,75.86) ; CPU1.AL60 CPU1.AL61 ; CPU1.AL60 82.57,76.57 82.57,77.73 CPU1.AJ60 ; v1(86.73,75.21) 87.1,74.85 CPU1.AP52 87.23,74.77 87.23,74.29 87.31,74.22 CPU1.AR52 ; v1(86.79,77.28) 86.95,77.45 CPU1.AK52 87.42,77.56 CPU1.AJ52 ; CPU1.AV20 CPU1.AU20 ; CPU1.AU20 107.14,73.37 107.63,73.37 107.65,73.38 108.34,73.38 CPU1.AU18 108.38,73.38 109.65,73.38 CPU1.AU16 ; v1(90.59,72.08) 90.57,72.07 90.57,72.06 90.25,71.74 90.18,71.74 CPU1.AW47 ; v1(79.71,80.66) 79.77,80.6 80.2,80.6 CPU1.AD63 ; CPU1.AT61 81.84,74.02 CPU1.AT62 80.87,74.02 80.72,73.87 CPU1.AT63 80.06,73.87 79.72,73.53 79.23,73.53 v1(79.02,73.32) ; v1(82.54,86.18) 82.87,85.86 CPU1.P59 ; v1(94.35,75.18) 94.35,75.19 94.05,75.5 CPU1.AN42 93.8,75.5 v1(93.52,75.22) 93.28,75.22 CPU1.AN43 92.88,75.38 92.13,75.38 CPU1.AN45 ; CPU1.AV39 95.42,72.09 95.31,72.09 v1(95.3,72.09) ; CPU1.AU33 99.49,73.36 CPU1.AV33 ; CPU1.AV36 97,72.09 96.93,72.09 96.91,72.07 v1(96.9,72.07) ; CPU1.AN36 97.18,75.5 96.86,75.82 v1(96.84,75.82) ; CPU1.AV34 99.2,72.06 CPU1.AW33 CPU1.AY33 ; v1(88.13,70.39) 88,70.52 88,71.32 CPU1.AY51 CPU1.AW51 CPU1.AV51 CPU1.AU51
  BOTTOM w0.203: v1(117.9,83.12) 117.59,83.43 CPU1.V3 ; v1(117.22,92.05) 117.26,92.05 117.27,92.06 117.79,92.06 118.21,91.64 CPU1.D2 ; v1(85.87,74.54) 85.9,74.54 85.94,74.58 85.95,74.58 86.22,74.85 CPU1.AP54 ; CPU1.AL57 84.31,76.8 v1(83.99,76.47) ; CPU1.AW60 82.33,71.74 82.57,71.74 ; CPU1.AE5 116.26,79.85 116.54,80.13 v1(116.54,80.21) ; 95.17,76.48 94.96,76.48 94.76,76.68 CPU1.AL40 ; v1(119.55,85.06) 119.48,85 118.9,85 CPU1.T1 ; v1(79.54,88.94) 79.55,88.94 79.71,88.78 CPU1.J63 ; v1(94.35,75.18) 94.38,75.18 94.7,75.5 CPU1.AN40 95.09,75.82 CPU1.AN39 ; CPU1.AY4 116.92,71.13 CPU1.AW4 ; v1(117.89,77.13) 117.59,77.43 CPU1.AK3 ; CPU1.AT43 92.16,73.7 92.47,74.01 v1(92.5,74.01) 92.69,74.2 CPU1.AR43 ; CPU1.AP48 CPU1.AN48 ; 115.48,92.38 115.53,92.43 v1(115.62,92.43) ; v1(85.89,76.47) 86.22,76.8 CPU1.AL54 ; v1(105.14,84.9) 105.22,84.9 105.39,85.07 106.28,85.07 CPU1.R22 ; CPU1.AL46 91.36,76.53 v1(91.55,76.53) 91.75,76.53 CPU1.AL45 ; v1(82.63,70.44) 82.63,70.71 82.81,70.89 CPU1.AY59 ; CPU1.AP3 117.9,74.24 v1(117.9,74.13) ; CPU1.AN45 91.82,75.5 91.74,75.42 91.36,75.42 91.29,75.5 CPU1.AN46 90.97,75.5 90.62,75.85 v1(90.62,75.86) ; GPU1.AF8 158.19,110.43 158.64,109.98 159.09,109.98 v1(159.16,110.05) ; v1(105.32,84.27) 106.27,84.27 CPU1.U22 ; v1(86.76,75.85) 86.78,75.84 86.97,75.84 CPU1.AN52 87.42,75.5 87.55,75.37 87.93,75.37 88.06,75.5 CPU1.AN51 88.15,75.5 88.25,75.39 88.5,75.39 88.51,75.39 88.88,75.39 88.99,75.5 CPU1.AN49 ; v1(95.86,75.17) 95.87,75.17 96.19,74.85 CPU1.AP38 ; v1(119.55,72.87) 119.36,73.06 CPU1.AU1 ; CPU1.D62 80.87,91.73 80.51,91.73 80.5,91.74 CPU1.D63 ; CPU1.F58 83.52,90.98 83.2,91.29 82.99,91.5 CPU1.D59 82.99,91.77 ; CPU1.AP57 84.31,74.85 83.99,74.53 83.92,74.53 v1(83.92,74.52) ; U2101.8 125.08,103.36 v1(125.24,103.2) ; v1(86.74,76.52) 86.79,76.47 86.99,76.47 CPU1.AM52 ; v1(87.74,76.47) 88.07,76.8 CPU1.AL51
  BOTTOM w0.229: CPU1.J22 105.48,88.32 105.48,88.32 v1(104.86,88.32) ; CPU1.AU51 88.02,73.47 CPU1.AT49 89.23,73.47 v1(89.6,73.84) 89.94,73.49 CPU1.AT46 ; CPU1.M22 106.28,86.7 105.95,86.7 105.95,86.7 105.61,86.7 105.61,86.7 104.96,86.7 v1(104.87,86.79) ; v1(89.59,74.5) 89.28,74.2 CPU1.AR49 ; v1(102.11,94.58) 102.11,94.19 102.26,94.03 102.26,93.49 CPU1.A28 ; CPU1.AD21 107.89,80.6 108.19,80.9 108.19,81.14 v1(108.4,81.36) ; CPU1.H13 112.01,88.67 CPU1.K12 ; CPU1.AB20 CPU1.AB22 105.61,81.82 105.37,82.06 105.37,82.08 v1(105.2,82.25)
  BOTTOM w0.254: 88.57,91.44 CPU1.D50 CPU1.F50 88.57,90.01 v1(88.57,90.01) ; VRAM3.B3 151.02,144.79 v1(150.64,144.41) ; CPU1.G3 117.89,89.23 117.89,89.12 v1(117.9,89.12) ; v1(105.76,74.52) 105.56,74.72 105.5,74.72 CPU1.AP23 105.03,75.18 v1(104.97,75.18) 104.98,75.19 104.98,75.2 105.28,75.5 CPU1.AN23 ; v1(105.76,74.52) 105.86,74.52 CPU1.AP22 ; v1(105.76,74.52) 105.69,74.52 CPU1.AR23 104.97,73.8 v1(104.97,73.76) ; CPU1.AJ52 87.42,78.1 87.75,78.1 CPU1.AH51 88.39,78.1 88.71,78.1 CPU1.AJ50 ; CPU1.AH17 109.08,78.24 108.6,77.75 108.56,77.75 v1(108.56,77.75) ; v1(101.1,90.01) 101.11,90.01 CPU1.F30 CPU1.D30 101.11,91.44 ; CPU1.AH16 109.62,77.86 v1(109.62,77.84) ; v1(117.22,92.05) 117.21,92.05 117.03,91.87 CPU1.D5 ; v1(81.27,87.66) 81.27,87.54 CPU1.L61 ; CPU1.AG61 CPU1.AG60 ; 86.11,78.1 CPU1.AJ54 ; 86.11,78.1 85.79,78.1 CPU1.AH55 85.15,78.1 84.82,78.1 CPU1.AJ56 ; 86.11,78.1 86.45,78.1 CPU1.AH53 86.77,77.3 v1(86.79,77.28) ; CPU1.AV46 90.7,72.09 90.59,72.09 v1(90.59,72.08) ; 82.99,91.77 82.99,91.84 82.43,92.4 82.43,92.85 CPU1.B60 ; v1(84.06,83.69) 83.52,83.69 CPU1.V58 83.35,83.85 83.35,84.82 CPU1.T58 ; 98.6,91.44 CPU1.D34 CPU1.F34 98.6,90.01 v1(98.6,90.01) ; 86.06,91.44 CPU1.D54 CPU1.F54 86.06,90.04 v1(86.04,90.01) ; CPU1.AM1 119.45,76 v1(119.48,75.98) ; CPU1.AU22 105.9,73.39 105.57,73.39 105.54,73.42 105.31,73.42 v1(104.97,73.76) ; v1(111.87,74.04) 112.58,74.04 112.61,74.01 CPU1.AR11 ; v1(115.14,82.14) 114.96,81.96 CPU1.AB7 ; CPU1.P22 106.83,85.88 v1(106.83,85.89) 107.21,86.26 CPU1.N21 ; v1(112.8,83.72) 113.12,84.05 113.86,84.05 CPU1.U9 ; GPU1.B17 177.56,117.87 177.14,117.45 v1(176.5,117.45) 175.83,117.45 175.41,117.87 GPU1.E17 ; v1(91.08,90.01) 91.08,90.01 CPU1.F46 CPU1.D46 91.08,91.44 ; v1(95.07,78.9) 95.55,78.9 95.87,78.58 CPU1.AH38 ; v1(95.07,78.9) 94.82,78.9 94.57,78.65 CPU1.AH40 94.43,78.29 v1(94.43,77.88) 94.14,77.88 CPU1.AJ41 93.69,77.87 v1(93.39,77.87) ; v1(95.07,78.9) 95.07,78.25 CPU1.AJ39 ; v1(99.68,75.82) 99.75,75.82 100.07,75.5 CPU1.AN32 ; CPU1.AV41 93.85,72.09 93.75,72.09 v1(93.74,72.08) ; v1(104.97,73.76) 104.58,73.37 CPU1.AU24 ; v1(182.75,145.98) 182.75,145.98 VRAM2.D8 ; CPU1.J59 82.87,88.86 v1(82.56,89.16) ; v1(178.44,122.8) 178.42,122.82 177.86,122.82 177.84,122.84 GPU1.B23 ; CPU1.AY6 115.52,70.36 v1(115.57,70.31) ; CPU1.AH42 93.27,77.98 v1(93.39,77.87) ; CPU1.Y59 82.57,83.05 82.57,83.16 v1(82.57,83.16) ; 110.39,79.43 v1(109.92,79.91) ; 93.59,91.44 CPU1.D42 CPU1.F42 93.59,90.01 v1(93.58,90.01) ; CPU1.G8 114.48,89.8 114.65,89.97 115.05,89.97 115.23,89.8 CPU1.G6 115.43,89.8 115.9,90.26 v1(115.9,91.45) ; CPU1.AP39 95.86,75.17 v1(95.86,75.17) ; CPU1.AA1 119.44,82 v1(119.6,82.15) ; CPU1.G18 109.12,90.24 109.12,90.49 109.62,91 CPU1.E17 ; CPU1.G18 108.25,90.21 v1(108.2,90.21) ; CPU1.G18 108.8,89.8 109.45,89.14 CPU1.H17 ; CPU1.G18 108.36,89.49 v1(108.27,89.49) ; CPU1.AN35 98.13,75.5 97.81,75.17 v1(97.76,75.17) ; CPU1.L13 112.13,86.97 112.13,86.12 v1(112.8,85.45) ; v1(107.63,76.59) 107.84,76.8 CPU1.AL20 ; CPU1.C11 112.54,92.31 CPU1.D12 112.16,91.92 v1(111.78,91.54) 112.23,91.1 CPU1.E11 ; CPU1.AH49 89.37,77.98 v1(89.48,77.87) 89.79,77.87 90.02,78.1 ; v1(84.06,87.59) 83.52,87.59 CPU1.L58 ; CPU1.AC61 81.27,81.55 v1(81.27,81.67) ; v1(95.3,72.09) 95.24,72.09 CPU1.AW40 ; CPU1.AF11 112.84,79.33 CPU1.AG11 112.02,79.33 CPU1.AF12 ; CPU1.AF11 112.46,79.81 v1(112.46,80.24) 112.48,80.26 112.48,80.73 CPU1.AB10 ; CPU1.AF11 113.16,79.75 113.33,79.75 113.33,79.76 CPU1.AE10 ; CPU1.AL39 95.35,77.1 95.2,76.94 v1(95.2,76.51) ; v1(106.97,94.26) 106.98,94.25 106.98,93.14 CPU1.B20 107.04,92.97 107.38,92.62 CPU1.C20 ; CPU1.R10 113.42,85.29 112.95,84.82 112.87,84.82 112.86,84.82 v1(112.81,84.82) ; CPU1.AL29 101.21,76.47 v1(101.14,76.47) ; CPU1.AR31 101.17,74.52 101.5,74.85 CPU1.AP29 ; v1(119.36,88.48) 119.32,88.43 119.32,88.43 118.89,88.01 CPU1.K1 ; CPU1.AH30 v1(101.07,79.03) ; v1(104.53,95.19) 104.92,94.8 104.92,93.44 CPU1.A24 ; CPU1.AR33 99.16,74.2 98.88,73.92 v1(98.74,73.92) 98.46,73.63 CPU1.AT35 ; CPU1.AG1 119.4,79 v1(119.45,79.05) ; CPU1.Y10 113.42,82.8 v1(113.13,83.09) 113.42,83.39 CPU1.V10 ; v1(93.39,77.87) 92.85,77.87 CPU1.AJ43 92.29,78.43 CPU1.AH44 91.64,78.43 CPU1.AJ45 ; CPU1.AH22 106.19,78.57 CPU1.AJ23 105.51,78.43 104.98,78.43 CPU1.AH24 104.95,78.4 v1(104.95,77.84) 104.97,77.84 CPU1.AK23 105.03,77.12 ; v1(96.9,72.07) 96.8,72.07 CPU1.AW37 ; v1(103.86,77.8) 103.81,77.84 103.28,77.84 CPU1.AJ27 102.7,78.1 CPU1.AH28 102.05,78.1 CPU1.AJ29 101.47,78.1 v1(101.14,77.77) ; v1(102.97,74.52) 103.11,74.52 CPU1.AP26 ; v1(116.43,74.6) 116.42,74.6 116.15,74.34 CPU1.AR5 ; VRAM1.B1 184.74,146.62 185.02,146.91 v1(185.09,146.91) 185.09,146.84 VRAM2.A9 ; CPU1.AG62 CPU1.AG63 ; v1(111.16,80.3) 111.16,80.27 111.21,80.22 CPU1.AF14 ; v1(108.29,94.24) 108.29,94.23 CPU1.A18 ; CPU1.L7 115.26,87.08 v1(115.26,86.96) ; v1(112.77,95.21) 112.64,95.08 112.64,94.33 112.53,94.22 CPU1.A11 ; v1(107.62,74.44) 107.67,74.49 107.74,74.49 CPU1.AP20 ; CPU1.AW35 98.39,72.09 v1(98.46,72.09) 98.48,72.11 98.59,72.11 CPU1.AV34 99.2,72.71 CPU1.AV33 99.49,72.11 CPU1.AW33 ; 103.62,91.44 CPU1.D26 CPU1.F26 103.62,90.01 103.6,89.99 v1(103.6,89.91) ; v1(91.11,78.91) 90.67,78.47 CPU1.AH46 ; v1(115.15,84.04) 115.14,84.03 115.14,83.75 CPU1.V7 ; CPU1.AV43 92.29,72.11 92.23,72.11 92.18,72.06 v1(92.16,72.06) 92.01,71.9 91.97,71.9 91.8,71.74 CPU1.AW44 ; v1(108.34,83.81) 108.31,83.81 108.08,83.58 107.85,83.58 CPU1.W20 ; v1(110.86,94.57) CPU1.A14 110.89,93.69 110.89,93.41 110.97,93.33 110.97,92.81 110.97,92.81 CPU1.C14 111.37,92.11 CPU1.D14 ; v1(104.95,77.12) 105.03,77.12 ; 105.03,77.12 105.05,77.12 CPU1.AL23 ; v1(104.32,78.66) CPU1.AJ25 ; v1(103.05,76.47) 103.37,76.8 CPU1.AL26 ; CPU1.AJ14 110.8,77.45 CPU1.AL13 111.32,77.29 CPU1.AJ13 111.62,77.57 112.08,77.1 112.17,77.1 112.26,77 v1(112.32,77) ; CPU1.AR52 87.13,74.2 86.56,73.63 CPU1.AU53 ; CPU1.AP10 113.37,75.12 113.37,75.13 113.56,75.32 v1(113.63,75.32) ; CPU1.AW50 88.65,71.74 88.82,71.91 88.84,71.91 v1(89.01,72.08) 89.19,72.26 89.22,72.26 89.35,72.39 CPU1.AV49 ; v1(96.09,90.01) 96.09,90.01 CPU1.F38 CPU1.D38 96.09,91.44 ; CPU1.L18 108.3,87.2 v1(108.21,87.2) 108.03,87.2 CPU1.L20
  BOTTOM w0.279: CPU1.B56 84.66,92.89 84.66,93.23 CPU1.A56 ; CPU1.B24 CPU1.A24 ; CPU1.B48 CPU1.A48 ; CPU1.A32 CPU1.B32 ; CPU1.A44 CPU1.B44
  BOTTOM w0.305: GPU1.E22 175.35,121.99 175.74,121.6 v1(175.74,121.6) ; CPU1.Y59 83.23,82.38 CPU1.AA58 ; v1(109.92,79.91) 109.92,79.74 109.61,79.43 CPU1.AF17 ; v1(175.74,114.97) 175.74,114.98 175.35,115.37 GPU1.E14 ; v1(158.8,147.01) 158.8,146.91 159.04,146.67 VRAM4.M9 ; 100.4,73.64 100.68,73.36 CPU1.AU30 101.09,73.65 v1(101.57,73.65) 101.72,73.65 CPU1.AU28 ; 100.4,73.64 100.4,73.96 100.63,74.19 CPU1.AR31 ; 100.4,73.64 100.15,73.64 99.89,73.38 CPU1.AU33 99.39,73.52 99.39,73.98 CPU1.AR33 ; VRAM1.T9 172.97,139.99 v1(172.95,139.97) ; CPU1.C25 103.86,92.74 CPU1.B26 ; CPU1.U61 81.56,84.25 81.27,84.53 v1(81.27,84.66) ; CPU1.AV8 113.96,72.39 v1(113.63,72.72) ; v1(97.79,79.1) 97.82,79.07 CPU1.AJ35 ; v1(97.79,79.1) 98.09,79.1 98.47,78.72 CPU1.AH34 ; v1(97.79,79.1) 97.76,79.08 v1(97.13,79.08) 97.13,78.47 CPU1.AH36 ; GPU1.AC8 160.35,110.38 v1(160.73,110) ; CPU1.AG61 CPU1.AG62 ; v1(105.36,140.66) 105.35,140.65 PU4404.14 ; VRAM1.T1 v1(172.95,146.39) ; CPU1.AH20 107.2,78.59 CPU1.AG21 106.94,78.42 v1(106.63,78.11) 106.29,78.45 CPU1.AH22 ; CPU1.AN17 109.67,75.83 109.67,75.19 109.67,75.18 CPU1.AP17 CPU1.AR17 109.71,74.53 v1(110.12,74.11) ; EC6206.2 135.49,96.91 v1(134.87,97.53) ; v1(160.56,139.37) 160.65,139.46 160.65,139.98 VRAM4.P1 ; RN1803.2 97.68,98.89 97.89,99.09 v1(97.89,99.69) ; DM1.133 92.25,29.1 92.23,29.08 92.23,28.54 92.58,28.19 v1(92.85,28.19) ; GPU1.B14 v1(178.56,115.39) ; CPU1.W22 106.19,83.44 CPU1.V23 105.52,83.59 105.24,83.59 v1(105.22,83.61) ; v1(116.33,93.01) 116.39,93.06 CPU1.B4 ; CPU1.AU26 102.89,73.7 v1(102.79,73.7) 102.35,73.7 CPU1.AU28 ; CPU1.AL22 106.09,76.8 105.79,77.1 v1(105.79,77.12) ; 115.9,90.26 116.29,89.87 CPU1.G5 ; v1(110.65,72.74) 111,72.39 CPU1.AV14 ; CPU1.AE58 83.52,79.68 v1(83.18,79.35) 82.95,79.11 CPU1.AG60 82.54,78.69 82.85,78.38 v1(82.85,78.24) ; v1(163.27,124.9) 162.89,125.28 GPU1.Y26 ; CPU1.F61 81.57,90.26 81.26,90.56 v1(81.26,90.66) ; GPU1.U23 165.37,122.87 164.99,122.49 164.99,122.44 v1(164.99,122.44) ; CPU1.AG23 105.78,78.98 104.88,78.98 v1(104.88,78.98) ; CPU1.AU16 109.67,73.66 v1(110.12,74.11) ; GPU1.AF17 GPU1.AE17 ; v1(82.39,74.18) 82.39,74.18 81.99,74.18 CPU1.AT61 ; 136.6,61.28 136.87,61.01 U3801.1 ; v1(110.12,74.11) 110.65,74.11 CPU1.AR15 111.08,73.69 111.31,73.69 CPU1.AT13 111.62,73.69 111.87,73.94 v1(111.87,74.04) ; v1(115.56,75.31) 115.48,75.31 CPU1.AN7 ; VRAM4.G1 155.01,139.99 154.61,140.39 v1(154.6,140.39) ; CPU1.D21 106.15,91.29 CPU1.D23 ; v1(78.92,91.86) 79.05,92 79.68,92 79.94,91.74 CPU1.D63 ; v1(108.32,84.71) 108.18,84.71 108.02,84.54 108,84.54 107.72,84.26 CPU1.U20 ; R603.1 111.5,97.83 v1(111.14,98.18) ; CPU1.AU28 CPU1.AV28 ; VRAM3.G8 155.04,140.83 154.7,141.17 154.62,141.17 v1(154.6,141.19) ; v1(150.84,139.42) 151.04,139.62 VRAM4.B1 ; EC6205.2 133.11,95.45 v1(133.55,95.45) ; CPU1.B56 84.45,92.74 CPU1.C57 ; v1(153.04,140.38) 153.04,140.39 VRAM4.E2 ; v1(159.2,115.81) 159.55,116.16 GPU1.AD15 ; v1(109.62,77.84) 109.62,77.82 109.67,77.76 109.67,77.14 ; v1(155.4,145.99) 155.04,146.35 VRAM4.G9 ; CPU1.AH46 90.6,78.36 v1(90.6,77.87) ; CPU1.E17 108.79,91.93 CPU1.D18 108.39,92.34 CPU1.C18 ; v1(108.62,79.97) 108.77,79.81 CPU1.AF18 ; v1(117.91,80.12) 117.91,80.21 117.59,80.53 CPU1.AD3 ; CPU1.AL23 105.04,76.47 v1(104.96,76.47) ; GPU1.AE20 158.75,120.29 v1(158.37,119.91) 157.95,120.32 GPU1.AF20 ; CPU1.AL10 112.92,76.94 112.76,77.1 112.41,77.1 v1(112.32,77) ; CPU1.K12 111.97,88.01 CPU1.L13 ; v1(117.89,86.12) 117.75,86.27 117.75,86.37 CPU1.N3 ; GPU1.A2 v1(178.55,104.73) ; CPU1.F58 83.34,90.41 v1(83.34,89.87) 83.59,89.61 CPU1.H57 ; CPU1.AH32 v1(99.77,79) ; v1(162.77,139.99) VRAM4.T1 ; CPU1.AF15 110.39,79.43 ; v1(113.89,88.72) 113.66,88.72 CPU1.J10
  BOTTOM w0.33: v1(66.75,26.09) 66.92,26.09 67.91,25.09 67.91,23.71 67.95,23.67 DM1.60 ; DM1.172 103.95,24.38 104.39,24.82 v1(104.55,24.82) ; v1(71.17,29.46) 71.25,29.54 DM1.71 ; DM1.127 90.45,29.29 90.91,28.82 v1(91.05,28.82) ; DM1.38 61.35,25.24 60.5,26.09 v1(60.15,26.09) ; DM1.161 v1(100.65,29.46) ; DM1.170 103.35,25.05 102.95,25.45 v1(102.75,25.45) ; DM1.13 53.85,29.22 54.24,28.82 v1(54.45,28.82) ; DM1.25 57.45,29.03 58.29,28.19 v1(58.42,28.19) ; v1(97.05,28.82) 97.46,28.82 97.67,29.03 97.67,29.69 97.65,29.7 DM1.151 ; DM1.179 106.05,28.55 105.06,27.55 v1(104.85,27.55) ; v1(100.35,26.09) 99.7,26.09 99.15,25.53 DM1.156 ; DM1.65 69.45,29.29 69.91,28.82 v1(70.05,28.82) ; v1(63.85,28.19) 64.11,28.19 64.65,28.73 DM1.49 ; DM1.128 90.75,24.01 90.76,24.01 90.76,24.11 90.76,24.12 90.76,25.04 91.81,26.09 v1(91.95,26.09) ; DM1.134 92.55,24.45 92.18,24.82 v1(91.95,24.82) ; CPU1.AN17 CPU1.AM17 CPU1.AL17 109.67,77.14 ; v1(51.15,24.82) 50.92,24.82 50.55,24.45 DM1.2 ; DM1.153 98.25,28.42 97.39,27.55 v1(97.05,27.55) ; DM1.32 59.55,24.36 59.55,24.36 59.1,24.82 v1(58.95,24.82) ; DM1.3 50.85,29.15 50.23,28.54 49.7,28.54 v1(49.66,28.49) ; v1(62.55,24.82) 62.74,24.82 63.15,24.4 DM1.44 ; DM1.46 63.75,25.06 62.73,26.09 v1(62.55,26.09) ; DM1.48 64.35,24.5 64.67,24.82 v1(64.95,24.82) ; DM1.61 68.25,29.29 67.79,28.82 v1(67.65,28.82) ; DM1.9 v1(52.65,29.46) ; DM1.155 v1(98.85,29.46) ; DM1.136 93.15,24.99 93.61,25.45 v1(93.75,25.45) ; v1(61.65,27.55) 61.74,27.64 61.89,27.64 62.85,28.61 DM1.43 ; v1(57.15,24.82) 57.29,24.82 57.75,24.36 DM1.26 ; DM1.54 66.15,24.41 66.55,24.82 v1(66.75,24.82) ; DM1.167 102.45,28.88 103.05,28.28 103.19,28.28 v1(103.27,28.19) ; DM1.66 69.75,22.72 69.75,24.83 69.13,25.45 v1(68.55,25.45) ; v1(19.14,41.3) 19.57,40.87 U3401.2 ; v1(100.35,24.82) 100.49,24.82 100.95,24.35 DM1.162 ; v1(54.45,27.55) 54.07,27.55 53.25,28.38 DM1.11 ; v1(70.95,24.82) 71.04,24.73 71.18,24.73 71.55,24.35 DM1.72 ; v1(107.25,28.82) 107.39,28.82 107.85,29.29 DM1.185 ; DM1.195 110.85,29.29 110.39,28.82 v1(110.25,28.82) ; DM1.145 95.85,29.21 95.46,28.82 v1(95.25,28.82) ; v1(97.95,25.45) 97.8,25.45 97.35,25.01 DM1.150 ; v1(57.15,26.09) 57.44,26.09 58.35,25.18 DM1.28 ; v1(56.23,28.82) 55.98,28.82 55.65,29.15 DM1.19 ; DM1.178 105.75,24.55 106.01,24.82 v1(106.35,24.82) ; v1(107.54,24.18) 107.55,24.17 107.55,24.11 107.51,24.08 107.51,23.52 107.55,23.49 DM1.184 ; DM1.37 61.05,29.15 61.38,28.82 v1(61.65,28.82) ; DM1.8 52.35,25.04 51.94,25.44 v1(51.94,25.46) ; v1(59.85,28.82) 59.71,28.82 59.25,29.29 DM1.31 ; DM1.139 94.05,28.6 95.09,27.55 v1(95.25,27.55) ; DM1.144 95.55,24.44 95.55,24.44 95.92,24.82 v1(96.15,24.82) ; DM1.189 v1(109.05,29.46) ; DM1.190 v1(109.35,24.18) ; v1(53.55,25.45) 53.71,25.45 54.15,25.01 DM1.14 ; DM1.196 v1(111.15,24.18) ; DM1.20 55.95,24.41 55.54,24.82 v1(55.35,24.82) ; DM1.63 68.85,28.62 67.79,27.55 v1(67.65,27.55) ; DM1.55 66.45,29.29 65.99,28.82 v1(65.85,28.82) ; DM1.138 v1(93.75,24.18) ; v1(104.85,28.82) 104.76,28.91 104.62,28.91 104.3,29.23 104.3,29.93 104.25,29.98 DM1.173 ; DM1.168 v1(102.75,24.18) ; DM1.187 108.45,28.65 108.91,28.19 v1(109.05,28.19)
  BOTTOM w0.356: v1(126.91,60.9) 127.18,61.17 Q1701.4 ; v1(165.8,124.87) 165.8,124.89 165.39,125.29 GPU1.U26 ; VRAM3.A9 149.79,139.54 v1(149.67,139.54) ; GPU1.AC2 160.41,105.48 160.41,105.06 v1(160.59,104.88) ; v1(170.74,122.49) 170.74,122.5 170.5,122.74 170.48,122.74 GPU1.L23 ; GPU1.AF1 157.15,104.69 ; 157.15,104.69 GPU1.AG2 ; 157.15,104.69 v1(157,104.54) ; GPU1.AD21 159.57,121.19 v1(159.97,121.58) ; v1(161.62,120.69) 161.54,120.69 161.2,120.35 GPU1.AB20 ; v1(180.62,112.98) 180.62,112.98 179.12,112.98 178.98,112.84 178.96,112.84 178.93,112.82 178.17,112.82 178.08,112.91 GPU1.B11 ; v1(162.86,146.43) 162.82,146.39 VRAM4.T9 ; v1(181.15,145.98) 180.74,146.39 VRAM1.G1 ; v1(181.15,145.98) 181.15,146 VRAM2.F9 ; v1(181.15,145.98) 181.13,145.98 VRAM2.G8 ; GPU1.AD22 159.56,121.99 v1(159.97,121.58) ; v1(176.35,139.56) 176.74,139.95 VRAM1.M9 ; GPU1.AG26 v1(156.37,125.29) ; VRAM1.P1 175.14,147.03 v1(175.21,147.09) ; GPU1.AD18 159.52,118.71 159.15,119.07 v1(159.15,119.12) 159.15,119.2 159.47,119.51 GPU1.AD19 ; C1802.1 104.25,101.92 v1(103.9,102.27) ; GPU1.P26 167.85,125.86 167.86,125.87 v1(167.86,125.95) ; v1(159.15,112.46) 159.15,112.51 158.76,112.91 GPU1.AE11 ; v1(162.48,107.51) 162.86,107.89 GPU1.Y5 ; GPU1.AC5 160.35,107.94 v1(159.97,108.32) ; v1(178.55,104.73) 178.51,104.69 GPU1.B1 ; VRAM4.B9 151.04,146.77 v1(150.87,146.94) ; v1(176.65,146.92) 176.74,146.83 VRAM1.M1 ; CPU1.R8 CPU1.R10 ; v1(182.73,140.36) 183.1,139.99 VRAM2.D1 ; v1(182.73,140.36) 182.34,140.75 VRAM1.E8 ; v1(182.73,140.36) 182.71,140.36 VRAM2.E1 ; v1(178.96,120.22) 178.92,120.26 178.17,120.26 178.05,120.38 177.79,120.38 177.77,120.35 GPU1.B20 ; v1(165.55,104.77) 165.55,104.9 165.37,105.08 GPU1.U2 ; v1(175.73,119.96) 175.72,119.97 175.72,119.98 GPU1.E20 ; GPU1.H2 172.81,105.31 v1(173.16,104.97) ; GPU1.L2 170.34,105.49 v1(170.76,105.91) ; GPU1.AF14 157.95,115.4 158.34,115.79 v1(158.37,115.79) 158.75,115.41 GPU1.AE14 ; v1(97.89,99.69) 96.64,99.69 96.39,99.43 RN1803.1 ; GPU1.E8 174.92,110.86 v1(174.87,110.86) ; v1(174.9,105.89) 174.9,105.89 GPU1.E2 ; VRAM1.J2 179.5,145.23 v1(179.5,145.19) ; VRAM1.J8 179.55,141.2 v1(179.55,141.2) ; v1(160.8,115.82) 160.8,115.61 161.03,115.39 GPU1.AB14 ; GPU1.P2 167.85,105.02 v1(167.6,104.77) ; Q1701.1 128.91,58.72 129.21,58.42 v1(129.53,58.42) ; GPU1.AD13 159.51,114.55 159.15,114.19 v1(159.15,114.17) 159.55,113.77 GPU1.AD12 ; v1(159.97,121.58) 159.99,121.61 159.99,121.63 GPU1.AC22 ; v1(174.92,108.34) 174.97,108.34 175.3,108.01 GPU1.E5 ; v1(180.3,140.39) 180.7,139.99 VRAM1.G9 ; v1(160.65,147.04) 160.64,147.03 VRAM4.P9 ; CPU1.N10 113.42,86.28 112.8,85.66 v1(112.8,85.45) ; GPU1.U5 v1(165.76,108.28) ; v1(182.75,145.98) 182.36,145.59 VRAM1.E2 ; VRAM4.E8 153.08,145.95 v1(153.08,145.99) ; v1(170.71,124.89) 170.69,124.87 170.67,124.87 170.33,124.53 GPU1.L25 ; U3501.1 153.46,5.49 v1(153.5,5.45) ; VRAM1.B9 184.75,139.99 v1(185.14,139.6) ; v3(31.72,22.12) 30.78,21.17 30.78,19.44 31.97,18.24 U2901.1 ; v1(159.17,118.29) 158.81,117.92 158.8,117.92 GPU1.AE17 ; VRAM3.D1 152.68,146.39 v1(153.08,145.99) ; GPU1.B5 177.78,107.97 v1(178.6,107.97) ; GPU1.AA7 161.95,109.49 161.29,109.49 GPU1.AB7 161.14,109.59 v1(160.73,110) ; v1(160.03,125.76) 160.4,125.39 GPU1.AC26 ; GPU1.E25 175.34,124.49 v1(175.74,124.88) ; v1(173.23,107.54) 172.88,107.89 GPU1.H5 ; VRAM3.F9 154.26,139.99 154.6,140.33 v1(154.6,140.39) ; GPU1.E11 175.32,112.88 175.3,112.88 174.97,112.55 174.97,112.54 v1(174.91,112.48) ; VRAM2.B3 184.74,141.57 184.88,141.43 184.88,141.41 v1(185.1,141.19) ; GPU1.AB17 161.13,117.87 v1(160.73,117.47) ; v1(156.28,141.19) 156.28,141.15 VRAM4.J2 ; CPU1.L15 110.58,87.42 v1(110.27,87.12) 109.82,87.57 CPU1.L17 ; v1(153.08,145.99) 153.08,146.03 VRAM3.E1 ; v1(160.82,123.32) 161.19,123.69 GPU1.AB24 ; GPU1.AF23 v1(157.17,122.84) ; VRAM4.J8 156.64,145.59 156.65,145.59 v1(157.03,145.21) ; GPU1.P23 167.84,122.89 167.51,122.56 167.51,122.48 v1(167.5,122.47) ; v1(153.04,140.38) 152.64,140.77 VRAM3.D8 ; GPU1.Y23 162.89,122.89 v1(162.48,122.48) ; GPU1.AD16 159.55,117.05 v1(159.97,117.47) ; v1(160.78,113.33) 161.19,112.92 GPU1.AB11 ; v1(158.41,108.37) 157.98,107.94 GPU1.AF5 ; v1(173.16,122.47) 173.14,122.49 173.14,122.53 172.81,122.85 GPU1.H23 ; VRAM4.M1 159.04,139.51 v1(158.92,139.4) ; v1(158.31,112.49) 157.95,112.85 GPU1.AF11 ; GPU1.B27 177.79,126.09 178.19,126.49 v1(178.25,126.49) 178.55,126.19 178.55,126.19 178.75,125.98 178.75,125.54 178.55,125.34 GPU1.A26 ; v1(163.19,104.78) 162.89,105.08 GPU1.Y2 ; GPU1.P5 167.78,107.89 v1(167.43,107.54) ; GPU1.L5 170.36,107.89 v1(170.74,107.51) ; VRAM1.P9 v1(175.14,139.39) ; v1(172.41,124.06) 172.41,124.07 172.81,124.47 GPU1.H25 ; v1(178.43,110.43) GPU1.B8
  BOTTOM w0.381: R8305.2 182.11,50.55 v1(182.08,50.52) PQ8304.1 ; 197.66,35.1 HDD1.P12 196.14,35.1 ; 195.85,41.11 HDD1.24 ; HDD1.24 197.63,42.19 ; HDD1.24 197.63,40.03 ; BAT1.9 125.2,156.29 ; BAT1.9 126.09,155.4 ; BAT1.9 125.2,154.51 ; BAT1.9 124.31,155.4 ; HDD1.S7 197.66,14.78 ; HDD1.S7 196.9,15.47 ; HDD1.S7 196.14,14.78 ; 197.66,26.21 HDD1.P5 196.14,26.21 ; v1(166.42,23.66) 166.42,23.43 166.77,23.07 R2611.2 ; R1913.1 117.84,63.12 v1(117.45,63.52) ; 127.2,154.51 BAT1.8 ; BAT1.8 127.2,156.29 ; BAT1.8 126.31,155.4 ; BAT1.8 128.09,155.4 ; 122.07,153.48 BAT1.11 ; BAT1.11 122.96,155.4 ; BAT1.11 121.19,155.4 ; 196.83,96.03 S1.1 ; S1.1 200.02,92.84 ; S1.1 200.02,99.22 ; 197.66,32.56 HDD1.P10 196.14,32.56 ; v1(189.14,10.31) 189.18,10.36 U5602.3 U5602.8 ; 197.66,27.48 HDD1.P6 196.14,27.48 ; 197.66,24.94 HDD1.P4 196.14,24.94 ; U3402.8 U3402.3 17.17,25.6 v3(16.91,25.85) ; C2110.2 125.19,79.15 v1(125.19,79.64) ; 196.9,6.46 HDD1.S1 196.14,7.16 ; PQ4402.1 92.08,146.35 v1(92.13,146.3) ; 143.44,155.4 BAT1.10 ; BAT1.10 145.21,155.4 ; BAT1.10 144.32,153.48 ; EC1502.2 129.17,95.8 v1(128.9,95.8) 127.81,95.8 127.73,95.72 EC6204.2
  BOTTOM w0.406: PQ4203.1 109.02,151.66 109.46,152.1 109.81,152.1 109.83,152.12 v1(109.99,152.12) ; PQ4203.4 110.48,148.99 111.15,149.66 v1(111.6,149.66) ; U3101.3 31.62,55.31 v1(31.62,55.31) ; v1(94.18,145.46) 94.03,145.31 PQ4402.4 ; R7518.2 190.71,108.12 191.15,108.56 Q7603.1 ; Q7603.4 193.67,110.09 v1(194.38,110.79) ; PQ4206.1 108.35,152.57 107.88,152.1 v1(107.88,152.04) ; v1(111.12,154.45) 110.68,154.01 PQ4206.4
  BOTTOM w0.457: WLAN1.43 187.82,22.5 v1(186.83,21.52) ; v1(178.91,32.44) 178.96,32.5 WLAN1.18 ; v1(183.04,23.7) 183.04,23.7 WLAN1.40 ; v1(179.09,25.8) 179.4,26.1 WLAN1.34 ; WLAN1.15 187.11,36.9 v1(185.92,38.1) ; v1(182.99,40.14) 181.83,41.3 WLAN1.4 ; WLAN1.9 186.68,39.3 v1(186.67,39.29) ; v1(186.84,31.24) 186.9,31.3 WLAN1.21 ; WLAN1.35 186.87,25.7 v1(186.84,25.67) 186.84,25.16 187.1,24.9 WLAN1.37 ; v1(179.42,19.58) 179.54,19.7 WLAN1.50 ; WLAN1.29 187.31,28.1 v1(186.76,28.64) 187.14,28.64 187.4,28.9 WLAN1.27 ; WLAN1.26 179.49,29.3 v1(179.04,29.76)
  BOTTOM w0.508: R6207.2 140.31,79.66 C6203.2 140.24,80.42 v1(140.26,80.43) ; R1920.1 72.69,79.5 v1(72.66,79.47) ; PC4518.2 139.58,10.61 140.36,11.39 140.36,11.6 v1(140.41,11.65) ; PC4202.2 98.37,144.67 v1(98.37,144.34) ; v1(177.17,102.3) 177.22,102.25 R7632.2 ; v1(75.23,95.67) 75.48,95.67 76.82,97.02 R405.2 ; v1(124.01,82.25) 124.17,82.25 124.57,81.85 C9602.2 124.52,81.5 EC1706.2 ; v1(42.82,92.27) 42.98,92.43 FAN1.2 ; PC8207.2 159.18,80.48 v1(159.46,80.21) ; v1(75.23,91.03) 75.23,90.92 75.24,90.91 PR4604.2 R901.2 ; PU5101.2 120.17,109.47 PC5119.2 120.79,109.53 121.04,109.78 v1(121.04,111.87) ; EC2503.2 155.33,38.71 155.04,39 154.95,39 154.87,39.08 v1(154.42,39.08) 154.42,39.06 154.44,39.04 C2502.2 ; EC1705.2 126.74,60.74 v1(126.91,60.9) ; R7301.2 150.68,126.08 v1(150.38,126.38) ; v1(133.17,40.07) 132.92,39.82 PC4534.2 ; C2408.2 170.56,38.41 170.94,38.79 v1(171.21,38.79) 171.39,38.6 C2409.2 ; C3005.2 34.25,59.08 v1(33.97,58.79) ; DB1.8 157.22,11.64 v1(157.48,11.38) ; v1(109.42,130.35) 108.96,130.81 PC4425.2 108.36,130.99 107.59,130.99 PR4436.2 ; v1(76.47,71.63) 76.45,71.66 R409.1 ; R5604.2 196.68,75 v1(195.84,75) ; v1(106.58,134.57) 106.41,134.57 105.93,134.09 PR4432.2 ; C3802.2 133.79,64.88 v3(133.79,63.43) 133.79,63.08 135.23,61.63 136.25,61.63 136.6,61.28 ; R7610.2 v1(185.32,102.31) ; EC1901.1 118.2,52.69 v1(118.21,52.7) ; EC2502.2 148.78,39.44 148.72,39.51 148.72,40.48 v1(148.64,40.56) ; v1(189.97,105.99) 189.49,105.99 188.94,105.44 C7610.2 ; C2407.2 C2406.2 161.2,31.82 160.66,31.28 160.62,31.28 v1(160.45,31.11) ; DB1.10 154.72,12.83 154.72,12.82 v1(154.72,11.4) ; C5401.2 16.32,83.37 v1(16.25,83.43) ; R709.2 81.99,97.1 v1(82.62,97.73) 82.37,97.99 EC701.2 ; PC4515.2 v1(138.19,37.18) ; v1(168.7,48.2) 168.81,48.1 PC8303.2 ; v1(112.06,133.1) 111.9,132.94 PR4405.2 ; EC9737.2 23.97,21.67 v1(23.97,21.67) ; v1(151.81,76.69) 151.7,76.57 151.7,76.2 151.65,76.15 PC8226.1 ; PR8224.2 158.13,78.49 v1(158.06,78.43) ; v1(130.25,38.8) 129.7,38.8 PR4531.2 ; v1(178.91,32.44) 178.89,32.42 C2410.2 ; PR8213.2 150.15,85.65 v1(149.71,85.65) ; v1(20.83,85.18) 20.41,85.6 R5207.2 ; v3(112.33,124.38) 111.9,123.96 EC9705.2 ; EC1707.2 132.27,84.42 132.55,84.14 v1(132.79,84.14) ; FAN1.5 v3(49.53,90.13) ; v1(121.3,67.8) 121.3,67.5 121.75,67.05 C1903.1 ; v1(110.02,131.71) 110.21,131.89 EC9747.1 ; PR4216.2 110.1,145 PC4209.2 110.1,143.97 109.53,143.4 v1(109.12,143.4) ; v1(45.92,61.38) 45.72,61.19 C3001.2 ; v1(175.73,102.67) 175.5,102.67 174.64,101.81 R7621.2 ; v1(136.28,79.32) 137.22,79.32 C6202.2 ; C3011.2 45.81,58.52 45.87,58.58 v1(45.92,58.58) ; EC9749.1 150.58,61.67 v1(150.5,61.75) ; v1(111.65,148.64) 111.65,148.49 PR4218.2 ; C3801.2 134.39,57.73 134.15,57.49 v1(134.15,57.24) ; C2415.1 178.9,27.46 v1(178.91,27.47) ; EC9745.2 28.67,7.99 v1(29.06,7.61) ; v1(178.2,38.46) 178.2,38.75 C5804.2 ; C1904.1 121.61,64.04 v1(121.61,63.87) ; D2601.A 37.54,88.66 v1(37.53,88.66) ; EC9717.2 86.27,124.85 v1(86.27,124.73) ; PC4824.2 126.81,108.86 v1(126.81,109.94) ; R7609.2 170.32,102.11 v1(170.79,102.58) ; PR4526.2 132.96,44.06 132.7,44.32 131.04,44.32 v1(130.6,43.88) ; v1(144.37,46.52) 144.5,46.65 SKT25.4 ; C1108.2 128.84,82.07 v1(128.99,81.92) ; v1(172.2,102.07) 172.1,101.97 R7622.2 ; v3(110.31,140.28) 110.44,140.15 PC4407.2 ; v1(156.16,75.25) 155.19,74.29 PC8225.1 ; EC3106.1 35.43,54.61 v1(35.46,54.63) 35.25,54.84 EC3107.1 ; R6208.2 136.4,69.54 v1(136.12,69.82) 136.2,69.9 Q6202.S ; PD4501.A v1(139.77,38.73) ; PQ4202.E 116.25,145.25 116.56,145.25 v1(116.85,145.54) ; v1(140.44,42.56) 140.43,42.56 140.43,44.01 PC4533.2 ; R5209.2 v1(37.16,84.65) ; PC8202.1 150.33,82.82 PC8205.2 150.53,83.01 v1(150.53,83.58) 150.53,84.44 PC8217.2 ; C3402.2 23.4,26.73 v1(23.54,26.87) ; v1(124.66,57.79) 124.86,57.79 125.46,58.39 R1725.1 ; v1(104.44,112.22) 104.44,112.59 104.43,112.6 PR4622.2 ; PC5112.2 154.43,62.83 v1(154.43,63.54) ; PQ4208.S 108.16,142.93 108.16,142.08 v1(108.19,142.05) ; EC9733.2 104.93,9.53 v1(105.22,9.81) ; v1(107.24,152.51) 107,152.74 PR4213.2 ; v1(156.5,59.95) 156.3,60.14 PC5109.2 ; R604.2 73.43,83.63 v1(73.13,83.33) 73.13,83.22 73.54,82.81 R605.2 ; v1(94.18,145.46) 94.87,145.46 PR4208.2 ; v1(190.99,98.02) 190.99,98.01 191.04,97.95 Q8301.S ; v1(101.63,102.24) 101.48,102.09 C1801.1 ; v1(190.63,107.46) 190.37,107.73 R7518.2 ; R3032.1 46.57,56.9 v1(47.3,56.9) ; PR8259.2 152.6,73.68 v1(152.58,73.65) ; PC8222.2 153.17,83.84 v1(153.13,83.8) ; v1(159.84,63.13) PR5111.2 PR5103.2 ; R7614.2 186.32,116.56 v1(185.99,116.23) 185.68,116.55 R7616.2 ; v1(190.51,101.89) 190.37,101.89 189.78,101.31 C8311.2 189.78,101.25 C7609.2 ; R2449.1 162.27,39.76 v1(162.18,39.84) ; v1(158.61,37.97) 158.5,37.97 158.05,38.42 EC2501.2 ; R712.2 EC702.2 78.92,97.99 78.33,98.57 v1(78.33,99.13) ; PC4904.2 107.34,15.26 v3(107.77,15.69) ; EC3108.1 v1(34.49,58.04) ; EC9748.2 v1(142,139.56) ; PC4517.2 119.64,10.01 v1(119.99,9.67) ; EC9735.2 v1(16.87,93.35) ; C3002.2 v1(43.87,65.25) ; C2602.2 117.6,111.44 v1(117.27,111.12) 117.21,111.05 115.38,111.05 115.37,111.04 115.29,111.04 115.05,110.8 PC5120.2 ; R8301.2 194.23,97.65 v1(194.11,97.77) ; FAN1.4 v3(46.11,94.73) ; C2142.2 122.5,110.54 v1(122.65,110.69) ; v1(128.83,85.6) 129.3,85.6 C1701.2 129.53,84.52 R1715.2 ; v3(102.02,135.21) 101.87,135.21 101.5,134.84 101.5,134.68 101.48,134.66 PR4433.2 101.48,134.28 100.63,133.43 PC4401.2 ; v3(192.66,85.5) C5610.2 ; R7627.2 184.05,106.49 v1(183.47,106.49) ; R7302.2 152.35,113.65 v1(152.22,113.53) ; R1721.2 121.95,61.42 121.61,61.09 121.61,60.93 v1(121.56,60.88) ; v1(120.64,57.84) 120.42,58.06 EC1704.2 ; v1(162.25,63.05) 162.18,63.12 PR5104.2 ; v3(192.61,78.5) 192.86,78.24 U5601.9
  BOTTOM w0.635: USB1.10 11.23,32.8 10.67,33.37 ; USB1.10 12.71,34.52 ; USB1.10 14.64,32.8 ; 7.88,52.29 RJ45.9 ; RJ45.9 9.62,53.18 ; RJ45.9 6.14,53.18 ; 202.25,86.09 ODD1.5 201.51,85.35 ; 11.42,35.38 USB2.5 12.97,36.7 13.41,36.26 ; 201.55,62.39 ODD1.15 199.77,63.47 ; ODD1.6 201.49,86.35 ; ODD1.6 200.75,87.09 ; ODD1.6 200.01,86.35 ; ODD1.6 200.75,85.61 ; USB2.4 13.7,39.6 v1(13.79,39.69) ; USB2.4 12.27,40.6 ; USB2.4 11.15,39.6 v1(11.05,39.7) ; 10.55,92.46 HDMI1.21 ; HDMI1.21 10.55,94.44 ; HDMI1.21 11.99,93.45 ; 195.85,4.96 HDD1.23 ; HDD1.23 197.63,3.88 ; HDD1.23 197.63,6.04 ; 3.5,34.31 2.56,35.25 USB2.7 ; 4.05,76.06 HDMI1.22 5.49,77.05 ; USB1.12 3.66,32.8 v1(3.4,33.06) ; USB1.12 6.72,32.8 7.24,33.32 ; USB1.12 5.28,33.98 ; USB1.11 12.71,15.88 ; USB1.11 14.47,17.4 ; USB1.11 10.93,17.4 ; 15.4,21.6 USB1.4 14.69,20.89 ; 7.26,16.55 6.41,17.4 USB1.13 ; USB1.13 5.28,15.82 ; USB1.13 4.32,17.4 v1(3.53,16.6) ; HDMI1.20 11.99,78.95 ; HDMI1.20 10.55,77.96 ; HDMI1.20 10.55,79.94 ; RJ45.10 9.62,72.23 ; RJ45.10 7.88,73.11 ; RJ45.10 6.14,72.23 ; 201.55,91.41 ODD1.14 199.77,90.33 ; 201.46,67.52 ODD1.S1 202.25,66.81 ; 3.4,52.32 2.04,50.95 USB2.8 ; 131.2,156.29 BAT1.6 131.2,154.51 ; HDMI1.23 v1(5.87,95.35) ; 11.42,51.14 USB2.6 13.44,49.5 v1(13.55,49.61)
  BOTTOM w0.762: v3(192.72,10.59) 193.08,10.95 196.88,10.95 HDD1.S4
  vias: v1(3.83,53.22) v1(4.7,34.54) v1(5.24,72.13) v1(5.2,51.69) v1(6.34,77.32) v1(7.01,96.77) v1(8.08,34.56) v1(8.66,97.36) v1(8.76,95.6) v1(9.08,33.02) v1(9.14,17.14) v1(9.99,72.14) v1(10.21,94.81) v1(10.22,77.6) v1(10.38,91.89) v1(10.41,80.62) v1(10.51,53.28) v1(10.58,52.03) v1(10.84,34.89) v1(11.01,46.46) v1(11.28,96.66) v1(12.08,73.84) v1(12.39,97.35) v1(12.68,92.46) v1(13.07,71.88) v1(13.4,91.51) v1(13.59,69.91) v1(13.74,97.36) v1(13.85,95.53) v1(14.04,36.59) v1(13.99,19.31) v1(14.05,31.07) v1(14.55,78.81) v1(14.55,76.52) v1(15.01,81.83) v1(15.14,18.12) v1(15.51,48.12) v1(15.46,40.02) v1(15.45,19.91) v1(15.69,34.21) v1(16.36,96.66) v1(16.86,87.22) v1(16.97,22.16) v1(16.97,20.89) v1(18.61,73.85) v1(18.82,97.36) v1(18.87,95.7) v1(18.87,22.16) v1(18.87,20.89) v1(19.35,76.01) v1(19.46,79.53) v1(19.68,74.39) v1(19.74,72.13) v1(19.85,78) v1(20.18,76.03) v1(20.73,21.08) v1(21.44,96.66) v1(21.99,22.29) v1(22,21.08) v1(22.61,72.94) v1(22.86,74.36) v1(23.04,78.07) v1(23.24,76.24) v1(23.43,29.39) v1(23.45,84.36) v1(23.57,82.87) v1(23.75,96.03) v1(23.67,94) v1(23.9,97.36) v1(23.95,79.7) v1(24.51,92.98) v1(26.54,97.2) v1(26.68,89.52) v1(27.25,72.71) v1(27.25,71.95) v1(28.12,95.62) v1(28.14,91.51) v1(28.98,97.36) v1(28.99,1.92) v1(29.83,1.04) v1(29.9,67.78) v1(30.66,94.48) v1(30.66,93.44) v1(30.87,84.61) v1(31.13,87.2) v1(31.6,96.66) v1(33.32,1.02) v1(33.39,89.61) v1(33.5,49.47) v1(33.73,10.74) v1(33.76,25.57) v1(33.79,24.86) v1(34.06,97.36) v1(34.22,37.5) v1(34.3,38.65) v1(34.74,10.74) v1(34.93,82.68) v1(35.02,50.54) v1(35.6,82.68) v1(35.63,12.64) v1(35.63,11.63) v1(35.63,10.74) v1(35.63,9.97) v1(35.63,8.96) v1(35.68,1.73) v1(35.94,61.79) v1(36.4,64.08) v1(36.52,10.74) v1(36.68,96.66) v1(36.8,58.16) v1(37.03,25.54) v1(37.24,1.76) v1(37.46,54.16) v1(37.54,10.74) v1(37.73,56.33) v1(37.77,75.92) v1(37.78,39.8) v1(38.12,47.97) v1(38.18,37.58) v1(38.15,1.81) v1(38.5,95.83) v1(38.84,43.88) v1(39.05,69.02) v1(39.14,97.36) v1(39.44,95.83) v1(39.43,75.77) v1(39.5,60.82) v1(40.39,61.71) v1(40.39,60.82) v1(40.39,59.93) v1(40.84,90.35) v1(41.34,75.69) v1(41.28,60.82) v1(41.55,68.16) v1(41.73,90.35) v1(41.76,96.66) v1(41.9,14.31) v1(42.23,72.87) v1(42.44,68.3) v1(42.62,51.15) v1(42.77,55.11) v1(42.96,52.98) v1(43.37,75.95) v1(43.51,95.18) v1(43.88,38.34) v1(43.87,37.53) v1(44.22,97.36) v1(44.67,72.89) v1(45.86,72.91) v1(45.87,68.45) v1(46.67,93.44) v1(46.67,92.17) v1(46.87,96.49) v1(48.01,85.18) v1(48.31,1.02) v1(48.58,93.44) v1(48.58,92.17) v1(49.3,97.36) v1(49.5,95.06) v1(49.53,67.86) v1(50.37,5.91) v1(51.05,85.66) v1(51.13,67.45) v1(51.19,96.63) v1(51.19,95.36) v1(51.15,64.46) v1(52.1,96) v1(52.12,88.73) v1(52.11,86.82) v1(52.65,28.19) v1(52.83,5.73) v1(53.09,95.36) v1(53.16,96.46) v1(53.32,86.53) v1(53.39,1.02) v1(54.37,95.35) v1(54.64,90.31) v1(54.92,96.66) v1(55.35,26.09) v1(55.34,1.06) v1(56.23,27.55) v1(56.33,67.63) v1(56.33,66.24) v1(57.42,68.24) v1(57.42,66.97) v1(57.4,64.73) v1(58.34,96.84) v1(58.37,67.63) v1(58.37,66.11) v1(58.47,1.02) v1(59.16,97.92) v1(59.32,68.24) v1(59.32,66.97) v1(59.3,64.73) v1(59.85,27.55) v1(60.15,24.82) v1(60.47,72.2) v1(60.53,69.28) v1(60.53,67.63) v1(60.53,66.11) v1(60.55,74.61) v1(60.7,83.68) v1(61.11,86.4) v1(61.92,68.27) v1(61.97,74.37) v1(62.05,70.17) v1(62.05,67) v1(62.41,76.41) v1(63.12,85.26) v1(64.13,101.24) v1(64.95,26.09) v1(65.7,84.32) v1(65.85,27.55) v1(66.14,84.77) v1(66.2,83.83) v1(66.67,84.31) v1(67.12,84.77) v1(68.63,1.02) v1(69,104.17) v1(71.17,4.28) v1(72.46,29.23) v1(75.15,26.72) v1(75.15,25.45) v1(76.17,28.19) v1(76.4,75.1) v1(76.95,26.72) v1(76.95,25.45) v1(76.95,24.18) v1(77.15,9.47) v1(77.85,28.82) v1(77.85,27.55) v1(78.75,25.45) v1(78.75,24.18) v1(78.92,114.56) v1(79.11,67.28) v1(79.76,86.07) v1(80.28,65.93) v1(80.48,68.63) v1(80.55,25.45) v1(80.85,28.82) v1(80.85,27.55) v1(81.66,67.31) v1(81.75,26.09) v1(81.75,24.82) v1(82.05,28.19) v1(82.75,100.54) v1(82.89,103.09) v1(83.14,68.61) v1(83.13,28.19) v1(83.25,65.89) v1(83.75,126.24) v1(84.54,67.34) v1(84.73,136.56) v1(84.81,28.82) v1(84.81,27.55) v1(84.86,2.28) v1(85.02,92.24) v1(85.21,100.43) v1(85.16,98.43) v1(85.43,151.81) v1(85.42,102.43) v1(85.35,26.09) v1(85.35,24.82) v1(86.1,68.86) v1(87.17,92.22) v1(87.15,26.09) v1(87.15,24.82) v1(88.31,2.23) v1(88.43,100.36) v1(88.42,99.04) v1(88.36,97.15) v1(88.41,28.82) v1(88.41,27.55) v1(89.55,29.46) v1(89.55,28.19) v1(90.12,25.24) v1(91.05,27.55) v1(92.54,92.24) v1(92.76,33.91) v1(92.76,32.64) v1(93.67,96.63) v1(93.72,70.74) v1(94.36,103.07) v1(95.04,92.24) v1(95.15,68.76) v1(95.62,96.47) v1(96.01,101.92) v1(96.93,70.06) v1(97.55,92.24) v1(98.47,69.19) v1(98.85,28.19) v1(98.85,26.92) v1(99.26,95.57) v1(99.83,94.02) v1(100.06,92.24) v1(100.65,28.19) v1(100.8,98.79) v1(102.05,107.08) v1(102.25,92.22) v1(102.75,26.72) v1(103.15,107.05) v1(104.24,107.05) v1(104.55,26.09) v1(104.59,14.55) v1(105.16,69.28) v1(105.16,68.01) v1(105.23,15.18) v1(105.23,14.55) v1(105.23,13.91) v1(105.26,102.08) v1(105.46,54.91) v1(105.67,58.61) v1(105.67,57.68) v1(105.78,59.27) v1(105.88,59.98) v1(105.86,14.55) v1(106.07,68.66) v1(106.35,26.09) v1(106.49,59.22) v1(106.53,58.45) v1(106.56,56.76) v1(107.25,58.49) v1(107.25,27.55) v1(107.54,57.66) v1(107.54,26.09) v1(108.44,156.09) v1(108.5,56.84) v1(108.66,109.11) v1(108.9,65.96) v1(108.99,48.65) v1(109.35,25.45) v1(109.46,55.89) v1(110.18,109.19) v1(111.15,25.45) v1(111.8,108.61) v1(112.49,54.4) v1(113.05,156.83) v1(113.67,148.14) v1(116.41,120.08) v1(117.04,121.02) v1(117.04,120.08) v1(117.04,119.19) v1(117.68,120.08) v1(117.86,147.13) v1(118.53,147.17) v1(118.49,124.22) v1(120.34,156.87) v1(120.56,149.52) v1(122.87,149.71) v1(123.01,57.83) v1(123.28,156.55) v1(123.34,153.65) v1(124.37,66.23) v1(124.46,149.83) v1(124.97,63.21) v1(125.81,86.54) v1(125.8,63.93) v1(127.45,99) v1(128.17,127.75) v1(128.36,156.55) v1(128.8,128.39) v1(128.8,127.75) v1(128.8,127.12) v1(129.44,127.75) v1(129.61,38.17) v1(130.25,38.17) v1(130.25,37.53) v1(130.7,6.8) v1(130.88,38.17) v1(131.33,6.8) v1(131.97,6.8) v1(132.08,90.39) v1(132.6,6.8) v1(133.44,156.55) v1(137.93,156.55) v1(139.75,1.02) v1(143.2,156.56) v1(144.83,1.02) v1(145.48,156.67) v1(147.34,122.88) v1(147.64,107.22) v1(147.66,108.02) v1(149.4,156.86) v1(149.91,1.02) v1(150.03,154.25) v1(150.65,111.07) v1(150.8,154.25) v1(150.95,121.5) v1(150.95,120.86) v1(150.95,120.23) v1(151.23,105.88) v1(151.26,107.98) v1(151.98,107.95) v1(152.25,109.79) v1(152.85,80.08) v1(153.21,156.86) v1(153.49,80.71) v1(153.49,80.08) v1(153.49,79.44) v1(153.99,154.23) v1(154.12,80.08) v1(154.75,154.23) v1(154.99,1.02) v1(155.59,156.12) v1(155.95,8.53) v1(160.07,1.02) v1(160.67,156.12) v1(164.08,153.94) v1(164.22,110.36) v1(164.41,118.87) v1(164.42,116.96) v1(164.4,112.91) v1(164.78,156.84) v1(165.08,154.09) v1(165.15,1.02) v1(165.5,15.71) v1(166.32,118.87) v1(166.32,116.83) v1(166.32,114.8) v1(166.32,112.9) v1(166.32,110.99) v1(166.32,110.13) v1(166.53,4.39) v1(166.96,13.68) v1(167.69,15.61) v1(168.35,118.87) v1(168.35,116.96) v1(168.35,114.93) v1(168.35,112.9) v1(168.35,110.99) v1(168.99,13.88) v1(169.86,156.84) v1(170.23,1.02) v1(170.38,118.87) v1(170.38,116.96) v1(170.38,114.93) v1(170.38,112.9) v1(170.38,110.99) v1(170.5,4.3) v1(170.67,14.06) v1(170.67,5.86) v1(170.81,154.15) v1(171.4,111.88) v1(171.51,154.19) v1(174.1,114.17) v1(174.17,133.39) v1(174.66,132.97) v1(174.94,156.84) v1(179.72,153.22) v1(180.02,156.84) v1(180.49,153.22) v1(180.56,3.23) v1(180.56,1.96) v1(181.41,2.66) v1(181.61,1.03) v1(182.14,108.37) v1(182.46,113.21) v1(182.47,3.23) v1(182.47,1.96) v1(183.32,14.63) v1(183.49,42.33) v1(183.56,152.55) v1(183.7,17.15) v1(183.71,13.28) v1(183.68,3.16) v1(183.65,2.11) v1(184.41,13.99) v1(184.69,152.88) v1(185.1,156.84) v1(185.62,40.25) v1(185.99,152.88) v1(186.13,108.39) v1(186.14,47.3) v1(186.1,46.14) v1(186.13,15.18) v1(186.12,3.42) v1(186.05,2.07) v1(186.25,9.85) v1(186.25,8.95) v1(186.38,49.1) v1(186.84,30.4) v1(186.89,1.02) v1(188.28,5.69) v1(188.28,4.42) v1(188.26,3.01) v1(188.26,1.74) v1(188.89,7.03) v1(189.24,2.43) v1(189.26,5.13) v1(189.26,3.67) v1(189.78,34.67) v1(190.18,156.84) v1(190.19,5.69) v1(190.19,4.42) v1(190.17,3.01) v1(190.17,1.74) v1(190.57,43.12) v1(190.95,52.26) v1(190.96,56) v1(191.17,153.03) v1(191.18,150.82) v1(191.18,150.01) v1(191.18,149.19) v1(191.17,147.95) v1(192.1,58.98) v1(192.27,47.16) v1(192.25,40.76) v1(192.41,75.59) v1(192.35,28.3) v1(192.36,26.06) v1(192.45,1.07) v1(193.1,144.67) v1(193.73,43.53) v1(193.81,7.78) v1(193.81,6.51) v1(194.9,44.85) v1(195.23,2.94) v1(195.23,1.67) v1(195.57,4.72) v1(195.71,7.78) v1(195.71,6.51) v1(195.92,21.63) v1(195.92,19.73) v1(195.86,17.71) v1(195.86,15.81) v1(196.23,2.28) v1(196.37,45.41) v1(196.37,43.51) v1(196.99,80.83) v1(197,18.7) v1(197,16.8) v1(197.14,2.94) v1(197.14,1.67) v1(197.32,130.43) v1(197.53,1.07) v1(197.64,45.41) v1(197.64,43.51) v1(198.06,27.66) v1(198.06,25.76) v1(198.11,23.67) v1(198.11,21.77) v1(198.11,19.63) v1(198.11,17.72) v1(198.08,15.76) v1(198.08,13.85) v1(198.6,46.06) v1(198.89,135.53) v1(199.01,42.9) v1(198.96,37.3) v1(199,32.67) v1(199,27.59) v1(199,22.51) v1(199,17.43) v1(199,12.35) v1(199.01,8.73) v1(198.96,3.09) v1(199.85,136.51) v1(199.85,134.61) v1(199.99,60.16) v1(200.92,137.49) v1(200.92,135.59) v1(201.88,136.57) v1(201.88,134.66) v1(201.98,132.8) v1(201.98,127.72) v1(201.98,113.54) v1(201.96,99.8) v1(202.34,109.1) v1(202.66,137.3) v1(202.68,103.58) v1(202.83,92.75) v1(202.82,86.96) v1(202.82,80.26) v1(202.83,77.22) v1(202.8,66.33) v2(35.67,45.56) v2(45.44,51.41) v2(47.9,59.81) v2(48.93,47.96) v2(49.82,74.46) v2(51.03,53.66) v2(53.54,66.16) v2(53.84,51.74) v2(54.31,42.43) v2(56.03,60.64) v2(56.08,52.9) v2(56.52,85.16) v2(57.38,91.89) v2(60.39,59.45) v2(67.04,65.03) v2(68.37,58.56) v2(68.91,52.9) v2(80.72,60.4) v2(87.93,60.4) v2(94.82,62.81) v2(102.56,63.06) v2(104.92,32) v2(106.78,113.55) v2(108.47,34.37) v2(109.06,115.97) v2(111.48,115.17) v2(115.73,120.76) v2(123.3,64.27) v2(129.12,62.14) v2(130.98,58.56) v2(148.35,12.71) v2(153.14,11.65) v2(160.21,78.61) v2(164.51,15.4) v2(165.72,13.17) v2(185.08,47) v3(15.66,38.49) v3(16.83,26.68) v3(19.07,32.88) v3(19.63,90.11) v3(20.27,91) v3(20.39,89.35) v3(20.56,32.75) v3(21.51,32.81) v3(24.84,9.31) v3(24.89,7.46) v3(25.08,42.54) v3(26.66,87.1) v3(27.38,34.93) v3(27.38,34.04) v3(28.75,48.39) v3(31.63,27.86) v3(32.47,27.88) v3(34.11,87.19) v3(35.75,21.49) v3(36.64,21.45) v3(43.53,7.07) v3(44,84.52) v3(44.07,85.96) v3(45.76,9.82) v3(46.7,38.55) v3(47.83,42.69) v3(48.39,88.63) v3(49.42,42.69) v3(50.06,77.79) v3(50.65,78.71) v3(52.92,87.32) v3(65.59,92.39) v3(66.17,93) v3(66.24,36.01) v3(66.78,93.63) v3(67.39,94.21) v3(67.95,80.04) v3(68.61,80.69) v3(69.17,80.02) v3(69.59,80.76) v3(70.02,80.04) v3(74.62,65.78) v3(74.62,64.51) v3(74.62,63.57) v3(74.67,62.68) v3(79.63,10.86) v3(79.67,10) v3(80.47,10.9) v3(80.52,10.02) v3(81.36,10.9) v3(81.36,10.01) v3(82.25,10.9) v3(82.25,10.01) v3(83.12,10.91) v3(83.12,10.02) v3(83.94,119.9) v3(83.94,118.76) v3(83.94,117.49) v3(83.94,116.22) v3(83.99,10.94) v3(83.99,10.05) v3(84.73,150.01) v3(84.76,156.76) v3(84.76,155.16) v3(84.76,152.62) v3(84.76,147.54) v3(84.76,145) v3(84.76,142.46) v3(85.67,149.04) v3(86.03,146.02) v3(86.15,143.37) v3(87.3,156.76) v3(87.45,85.29) v3(87.45,82.49) v3(88.85,155.52) v3(89.84,156.76) v3(90.12,85.29) v3(91.77,85.29) v3(92.38,156.76) v3(92.35,133.61) v3(92.44,132.65) v3(93.47,133.64) v3(93.45,132.66) v3(93.8,85.29) v3(94.69,141.83) v3(94.66,112.39) v3(94.66,110.99) v3(95.12,156.76) v3(95.35,141.19) v3(95.58,85.29) v3(96.29,111.8) v3(96.72,17.34) v3(97.15,18.07) v3(97.48,85.29) v3(97.61,17.34) v3(97.66,111.7) v3(98.03,18.13) v3(98.47,156.76) v3(98.5,17.34) v3(98.63,150.92) v3(98.88,112.39) v3(98.88,18.11) v3(99.39,85.29) v3(99.39,17.34) v3(99.56,150.92) v3(99.89,18.11) v3(100.05,156.76) v3(100.28,17.34) v3(100.44,150.93) v3(101.29,85.29) v3(101.93,115) v3(102.39,114.01) v3(102.82,115) v3(103.27,114.01) v3(103.71,115) v3(104.16,114.01) v3(104.59,115) v3(105.12,59.74) v3(105.48,115) v3(105.89,66.49) v3(105.89,65.35) v3(105.89,64.2) v3(105.93,63.16) v3(106.37,115) v3(107.26,115) v3(108.02,117.16) v3(108.15,115) v3(108.91,117.16) v3(109.04,115) v3(109.52,105.48) v3(109.8,117.16) v3(109.93,115) v3(110.01,106.29) v3(110.69,117.16) v3(111.2,117.92) v3(111.58,140.28) v3(111.58,117.16) v3(111.83,13.66) v3(111.83,12.77) v3(111.96,141.04) v3(112.21,117.8) v3(112.6,140.28) v3(112.98,141.04) v3(113.24,35.14) v3(113.53,65.08) v3(113.61,140.28) v3(113.99,141.04) v3(114.63,140.28) v3(115.01,141.04) v3(115.39,139.77) v3(115.52,103.19) v3(115.52,102.3) v3(115.77,140.66) v3(118.16,13.76) v3(118.19,12.73) v3(119.05,13.76) v3(119.08,12.73) v3(119.16,103.24) v3(120.92,102.87) v3(122.38,49.46) v3(123.34,49.5) v3(124.82,49.52) v3(125.68,30.04) v3(126.44,31.06) v3(126.57,30.04) v3(127.45,31.06) v3(127.45,30.04) v3(127.58,32.2) v3(127.58,29.02) v3(127.84,122.24) v3(127.84,121.35) v3(127.84,120.46) v3(127.84,54.14) v3(127.96,119.58) v3(128.34,30.55) v3(128.47,31.69) v3(128.72,122.24) v3(128.72,121.35) v3(128.72,120.46) v3(128.68,54.12) v3(128.85,119.58) v3(128.92,49.52) v3(129.87,119.32) v3(129.87,118.31) v3(130.4,2.41) v3(131.41,2.41) v3(133.42,32.07) v3(133.68,31.06) v3(133.68,30.04) v3(134.25,149.86) v3(134.26,109.97) v3(134.27,103.48) v3(134.31,32.07) v3(134.57,31.06) v3(134.57,30.04) v3(135.25,149.85) v3(135.5,103.21) v3(135.84,29.66) v3(135.84,28.77) v3(136.44,103.21) v3(137.33,103.21) v3(139.18,6.74) v3(139.88,16.88) v3(139.86,16.04) v3(140.19,6.74) v3(140.75,16.04) v3(140.77,16.88) v3(141.63,16.04) v3(141.66,16.88) v3(142.55,16.88) v3(142.52,16.04) v3(143.04,142.59) v3(143.06,141.57) v3(143.23,144.14) v3(143.44,16.88) v3(143.41,16.04) v3(144.22,151.33) v3(144.22,150.44) v3(144.22,149.42) v3(144.22,148.53) v3(144.22,147.52) v3(144.22,146.63) v3(148.37,124.32) v3(148.36,117.57) v3(148.46,116.71) v3(148.46,115.85) v3(149.11,125) v3(149.17,124.02) v3(150.84,123.01) v3(151.57,13.35) v3(152.64,13.35) v3(155.21,116.11) v3(157.3,85.67) v3(157.3,84.78) v3(157.3,83.89) v3(157.3,76.01) v3(157.3,75.13) v3(157.3,74.24) v3(157.81,103.7) v3(158.19,86.56) v3(158.19,85.67) v3(158.19,84.78) v3(158.19,83.89) v3(158.19,76.01) v3(158.19,75.13) v3(158.19,74.24) v3(158.19,73.4) v3(158.46,103.18) v3(158.82,103.95) v3(159.08,86.56) v3(159.08,85.67) v3(159.08,84.78) v3(159.08,83.89) v3(159.08,76.01) v3(159.08,75.13) v3(159.08,74.24) v3(159.08,73.4) v3(159.37,3.56) v3(159.92,56.99) v3(159.97,86.56) v3(159.97,85.67) v3(159.97,84.78) v3(159.97,83.89) v3(159.97,76.01) v3(159.97,75.13) v3(159.97,74.24) v3(159.97,73.35) v3(160.17,8.89) v3(160.35,87.39) v3(160.35,72.59) v3(160.45,3.55) v3(160.46,56.34) v3(160.74,57.25) v3(160.86,86.56) v3(160.86,85.67) v3(160.86,84.78) v3(160.86,83.89) v3(160.86,83) v3(160.86,76.01) v3(160.86,75.13) v3(160.86,74.24) v3(160.86,73.35) v3(161.11,55.81) v3(161.3,56.63) v3(161.44,3.55) v3(161.92,56.06) v3(162.34,10.12) v3(165.97,11.35) v3(166.94,11.34) v3(172.47,63.95) v3(173.74,63.95) v3(174.78,99.17) v3(174.97,63.96) v3(179.02,54.72) v3(179.02,53.88) v3(180.69,54.63) v3(182.57,54.63) v3(183.07,25.62) v3(184.32,78.52) v3(184.32,44.6) v3(184.49,119.12) v3(184.46,19.98) v3(185.04,76.01) v3(185.03,75.16) v3(185.03,74.32) v3(185.01,73.47) v3(185.04,72.49) v3(185.04,71.54) v3(185.04,70.71) v3(185.33,119.15) v3(186.2,119.22) v3(186.26,89.91) v3(186.26,89.07) v3(186.26,88.23) v3(186.26,87.39) v3(186.26,86.56) v3(186.64,84.12) v3(186.64,83.28) v3(186.64,82.44) v3(186.64,81.53) v3(186.67,80.43) v3(186.67,79.59) v3(186.67,78.75) v3(187.13,76.19) v3(187.13,75.35) v3(187.13,74.51) v3(187.14,73.65) v3(187.14,71.92) v3(187.14,70.96) v3(187.1,17.91) v3(187.17,72.79) v3(187.65,89.91) v3(187.65,89.07) v3(187.65,88.23) v3(187.65,87.39) v3(187.65,86.5) v3(187.88,150.01) v3(188.19,17.94) v3(192.8,142.64) v3(192.81,33.14) v3(192.86,143.5) v3(192.86,141.8) v3(192.92,14.76) v3(193.14,24.93) v3(193.19,35.09) v3(194.3,104.91) v3(194.75,7.13) v3(194.86,106.58) v3(196.16,76.74) v3(198.19,134.31) v3(198.45,132.66)
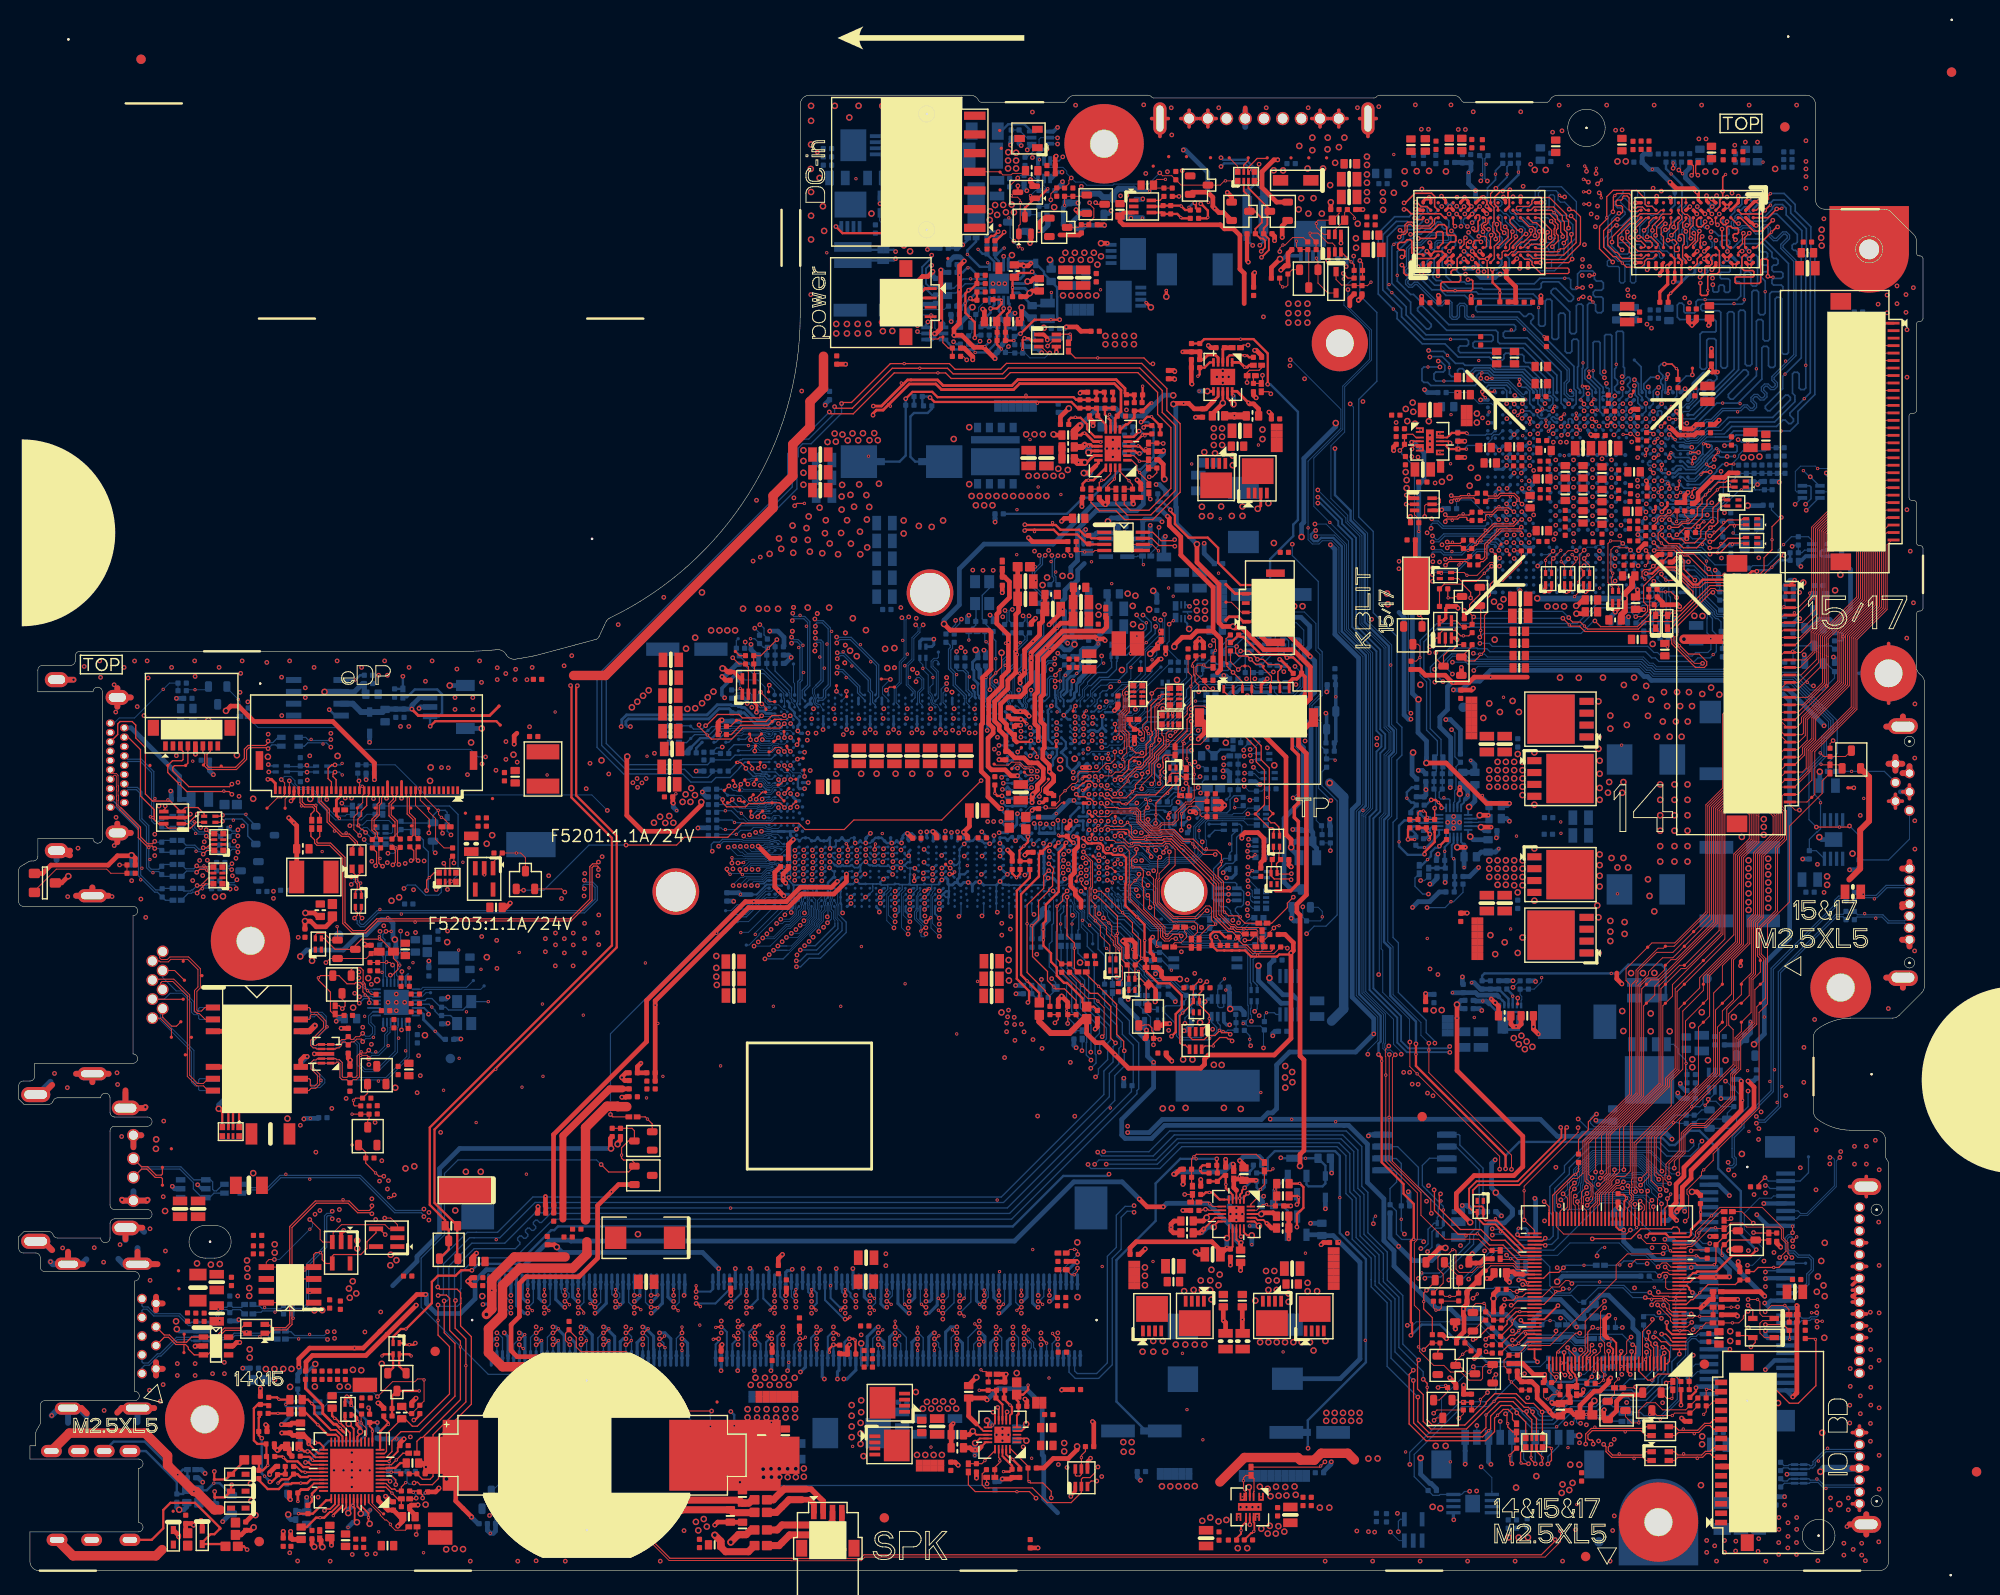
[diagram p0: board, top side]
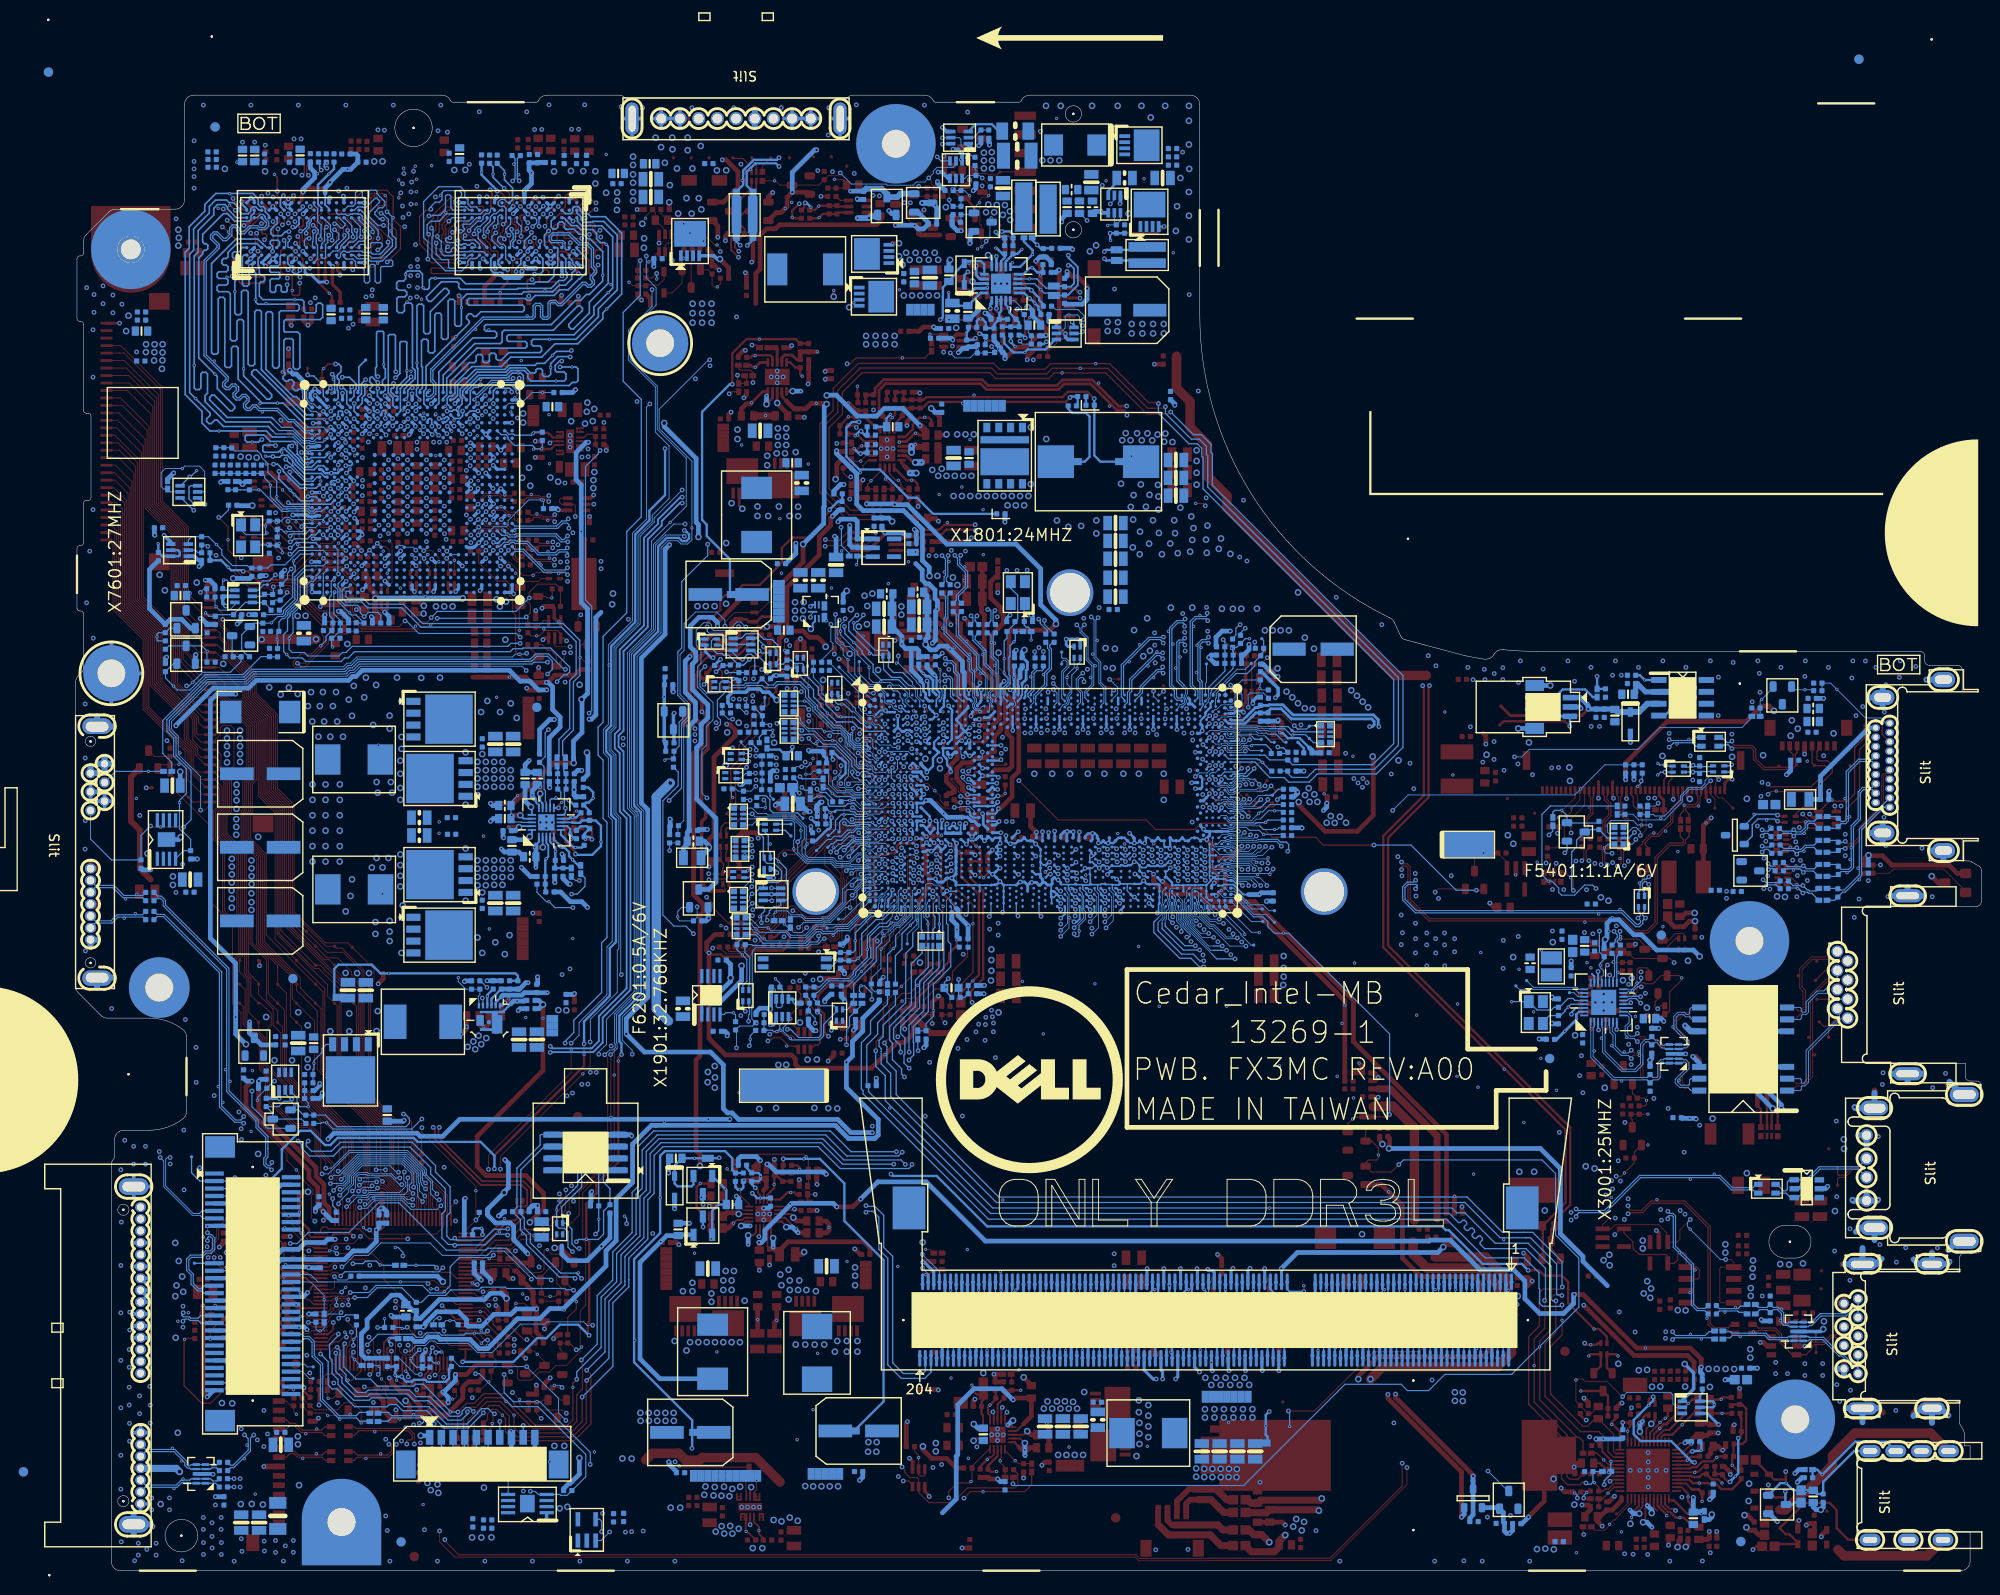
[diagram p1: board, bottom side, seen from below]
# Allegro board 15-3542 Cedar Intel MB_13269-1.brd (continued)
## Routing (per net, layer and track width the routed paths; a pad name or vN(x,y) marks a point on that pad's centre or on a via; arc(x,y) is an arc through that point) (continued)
V3D3_STB: length 8.7
  TOP w0.203: 34.77,14.85 35.03,14.59 HDA27.20
  TOP w0.305: R2712.1 30.67,19.51 32.52,17.66 32.52,16.85 33.7,15.67 33.95,15.67 v2(34.4,15.23) 34.77,14.85
VBAT: length 22.8
  TOP w0.203: v1(166.01,20.72) 166.01,20.98 165.83,21.16 165.83,21.19 165.69,21.33 KBC24.102
  TOP w0.508: R2445.1 160.29,20.7 R2405.1 R2446.1 161.86,20.22 162.43,19.65 R2404.1 162.43,18.43 163.77,17.1 v2(163.77,16.98) 164.19,16.56 C2405.1 165.48,17.13 C2404.1 166.41,16.68 R2402.1 167.01,17.69 168.55,19.22 169.15,19.22 170.09,20.16 170.09,20.42 v1(170.29,20.62)
  L3 w0.508: v1(166.01,20.72) 166.36,20.37 167.24,20.37 167.64,20.77 167.64,21.01 168.05,21.42 169.49,21.42 v1(170.29,20.62)
VCC1R05VIDEO_PEX_PLLVDD: length 1.8
  BOTTOM w0.356: 161.98,116.23 161.97,116.23 v1(161.57,116.63) ; 161.98,116.23 v1(161.57,115.82) 161.99,115.39 GPU1.AA14 ; 161.98,116.23 GPU1.AA15
  vias: v2(160.78,116.65)
VCC_CORE: length 2.4
  BOTTOM w0.254: CPU1.F59 82.87,90.36 82.57,90.66 v1(82.57,90.66)
  BOTTOM w0.305: v1(84.46,84.32) 84.45,84.34 CPU1.U57
  BOTTOM w0.381: v1(77.92,92.8) 77.92,93.05 77.49,93.48 R702.1
  vias: v1(83.28,83.06) v1(83.26,81.73) v1(84.43,89.63) v1(84.35,88.88) v1(84.41,80.11) v1(84.66,85.63) v1(84.83,91.16) v1(85.29,89.63) v1(87.3,91.15) v1(88.21,89.47) v1(89.14,89.66) v1(89.86,91.18) v1(90.52,89.66) v1(91.64,89.66) v1(92.47,91.19) v1(93.02,89.66) v1(94.15,89.66) v1(94.98,91.19) v1(95.53,89.66) v1(96.66,89.66) v1(97.48,91.19) v1(98.04,89.66) v1(99.17,89.66) v1(99.9,89.95) v1(99.99,91.19) v1(100.55,89.66) v1(101.67,89.66) v1(102.32,91.17) v1(102.31,89.66) v1(104.36,87.92) v1(104.7,89.19) v1(104.83,87.47) v2(70.3,83.14) v2(83.89,99.03) v2(90.9,119.27) v3(71.01,82.27) v3(71.34,83.08) v3(71.38,98.68) v3(71.52,92.23) v3(71.94,83.74) v3(71.85,82.27) v3(72.34,83) v3(72.36,99.85) v3(72.36,92.29) v3(73.09,92.83) v3(73.7,93.46) v3(74.07,100.63) v3(74.32,94.07) v3(74.96,100.63) v3(75.79,100.63) v3(76.63,100.63) v3(77.48,102.95) v3(79.16,102.94) v3(80.06,102.94) v3(80.33,108.81) v3(81.23,102.94) v3(81.33,110.46) v3(81.56,109.35) v3(82.78,111.84) v3(82.85,108.92) v3(82.93,110.34) v3(84.27,111.57) v3(84.4,110.3) v3(84.4,103.07) v3(84.5,112.82) v3(84.63,109.05) v3(85.67,113.76) v3(85.95,108.89) v3(86.24,111.03) v3(86.33,112.41) v3(86.52,120.78) v3(86.69,103.07) v3(86.76,109.93) v3(87.28,121.69) v3(87.41,120.82) v3(87.65,108.77) v3(88.03,114.95) v3(88.03,113.55) v3(87.97,111.05) v3(88.11,121.59) v3(88.08,116.2) v3(88.6,112.41) v3(88.68,120.95) v3(88.93,98.45) v3(88.97,115.13) v3(89.02,109.91) v3(89.19,121.71) v3(89.23,101.92) v3(89.35,113.86) v3(89.64,97.86) v3(89.8,120.96) v3(89.9,116.25) v3(89.99,111.19) v3(90.02,108.77) v3(90.31,121.72) v3(90.62,100.65) v3(90.68,115.1) v3(90.73,112.49) v3(90.76,109.51) v3(91.01,120.97) v3(90.98,113.83) v3(91.51,121.73) v3(91.89,120.97) v3(92.02,116.32) v3(92.68,98.65) v3(92.91,96.59) v3(93.67,98.73)
VCC_SENSE: length 98.2
  TOP w0.305: 94.58,126.93 v2(94.41,127.09) ; 94.58,126.93 95.08,127.43 95.44,127.43 98.28,127.43 98.88,126.83 106.24,126.83 106.87,127.46 117.39,127.46 118.34,126.51 118.34,126.01 PC4613.2 118.53,125.83 PC4601.2 119.33,125.83 PR4603.2 ; 94.58,126.93 92.28,124.63 v1(91.41,124.63)
  L3 w0.305: v1(91.41,124.63) 90.3,124.63 88.74,123.07 84.36,123.07 82.3,121.01 82.3,116.4 64.42,98.52 64.42,90.35 v1(64.44,90.33)
  BOTTOM w0.254: CPU1.E63 80.2,91.01 79,91.01 78.61,91.4
  BOTTOM w0.305: 78.61,91.4 77.64,92.37 77.34,92.37 R702.2 76.26,92.59 76.18,92.67 74.72,92.67 73.63,91.58 65.02,91.58 64.51,91.07 64.51,90.4 v1(64.44,90.33)
VCCST_PWRGD_XDP: length 1.3
  TOP w0.14: R9601.2 77.1,97.92 TP9648.1
VDD10: length 4.7
  BOTTOM w0.203: LOM30.3 40.99,58 40.94,57.96 v1(40.94,57.87) ; v1(43.85,59.55) 43.85,59.73 43.36,60.22 LOM30.30 ; v1(40.99,64.12) LOM30.22 ; v1(39.01,57.91) 39.01,58.02 38.99,58.03 LOM30.8
  vias: v2(41.76,64.51) v2(42.85,58.26) v3(50.08,65.66)
VDDREG: length 1.1
  BOTTOM w0.203: 41.66,63.87 41.39,63.6 LOM30.23
  vias: v2(42.17,65.07)
VSS_SENSE: length 100.6
  TOP w0.305: 93.07,124.8 95.26,127 98.1,127 98.7,126.4 106.42,126.4 107.05,127.03 117.21,127.03 117.91,126.33 117.91,124.07 117.51,123.67 PC4612.1 117.29,123.33 PU4601.8 ; 93.07,124.8 v2(93.24,124.63) ; 93.07,124.8 92.46,124.2 91.74,124.2 91.38,123.84 v1(91.38,123.66)
  L3 w0.305: v1(91.38,123.66) 91.38,123.91 91.09,124.2 90.48,124.2 88.92,122.64 88.69,122.64 84.54,122.64 82.73,120.83 82.73,116.22 64.86,98.34 64.86,90.68 65.21,90.33 v1(65.43,90.33)
  BOTTOM w0.254: CPU1.E62 80.55,90.66 80.36,90.66 80.35,90.65 78.75,90.65 78.05,91.35
  BOTTOM w0.305: v1(65.43,90.33) 65.14,90.33 64.94,90.52 64.94,90.89 65.2,91.15 73.81,91.15 74.9,92.24 76,92.24 76.29,91.95 PR4604.1 R901.1 77.6,91.8 78.05,91.35
0D675V_S0:
  vias: v2(110.21,20.62) v3(112.37,24.29) v3(113.26,29.28)
1D05S_VCCST: length 145.2
  TOP w0.508: v3(65.1,87.13) 65.05,87.08 65.05,80.83 66.75,79.12 70.19,79.12 73.01,81.94 v3(73.01,82.26) ; v3(98.98,101.31) 99.64,100.65 103.78,100.65 104.01,100.43 104.01,96.46 103.11,95.56 103.11,90.67 102.96,90.52 102.96,85.54 103.68,84.83 103.68,82.83 104.96,81.56 v1(105.14,81.56) ; PR4630.2 115.58,114.66 116.04,114.21 116.11,114.21 v1(116.24,114.09) 116.47,114.32 PR4601.1 ; PC4606.1 PR4620.2 119.18,114.82 119.18,114.22 v1(119.24,114.16)
  L3 w0.508: v1(80.34,100.55) 80.13,100.34 80.13,98.03 v1(75.51,93.41) ; v1(105.14,81.56) 104.95,81.56 103.15,83.36 96.93,83.36 94.99,81.41 84.49,81.41 83.52,82.38 81.15,82.38 80.28,83.25 75.03,83.25 74.04,82.26 v3(73.01,82.26) ; v1(68,87.48) 70.07,87.48 71.3,86.25 71.78,86.25 v1(72.46,85.57)
  L4 w0.508: v1(75.51,93.41) 75.51,92.98 75.32,92.78 75.32,92.3 74.33,91.31 74.33,90.38 73.74,89.79 70.46,89.79 68.18,87.51 68.04,87.51 v1(68,87.48)
  BOTTOM w0.203: CPU1.AC22 105.46,81.01 105.26,81.21 105.26,81.39 105.14,81.51 v1(105.14,81.56) ; v1(105.06,80.18) 105.08,80.21 106.27,80.21 CPU1.AE22
  BOTTOM w0.305: CPU1.AE23 105.45,79.79 v1(105.06,80.18)
  BOTTOM w0.381: v1(75.51,93.41) 75.22,93.71 75.22,94.43 77,96.21 R2018.1
  BOTTOM w0.508: v3(98.98,101.31) 98.98,101.73 100.62,103.36 100.62,107.21 103.26,109.86 110.65,109.86 114.88,114.09 v1(116.24,114.09) 116.29,114.09 116.37,114.16 v1(119.24,114.16) ; v1(80.34,100.55) 81.2,100.55 81.86,99.89 81.86,98.94 R706.1 ; R703.1 v1(72.46,85.57)
  vias: v2(67.21,87.16)
1D05V_HSIO:
  vias: v2(120.62,101.44) v3(118.62,104.56) v3(119.2,101.29) v3(119.45,104.34) v3(120.07,101.03)
1D05V_PWR:
  vias: v2(128.34,106.75)
1D5V_PWR:
  vias: v2(114.75,107.97)
1D05V_S0: length 179.1
  TOP w0.508: v1(122.46,119.85) 122.38,119.78 PR4602.1 ; R2401.1 186.29,29.86 v1(186.76,29.38) ; R3608.1 153.73,19.98 v1(153.08,20.63)
  L3 w0.508: v1(176.09,35.47) 176.09,35.83 173.93,37.98 172.9,37.98 172.03,38.85 172.03,38.86 169.95,40.94 169.95,45.73 167.44,48.23 167.44,48.6 166.88,49.17 166.41,49.17 164.61,50.98 160.16,50.98 155.81,55.32 155.81,56.82 154.76,57.88 154.76,60.72 152.83,62.64 151.38,62.64 148.08,65.94 148.08,70.84 144.15,74.78 144.15,85.21 148.79,89.86 148.79,91 v1(148.92,91.13) ; v1(186.76,29.38) 187.04,29.38 187.53,28.9 187.53,23.21 185.46,21.14 185.46,19.93 184.82,19.29 184.79,19.29 184.58,19.25 184.57,19.24 184.31,19.24 183.55,18.48 178.73,18.48 178.6,18.61 172.67,18.61 172.16,19.12 169.42,19.12 169.26,19.27 168.51,19.27 168.16,19.27 167.62,18.74 165.38,18.74 164.61,19.5 159.16,19.5 158.73,19.93 156.47,19.93 155.77,20.63 v1(153.08,20.63)
  BOTTOM w0.203: v1(111.83,80.24) 111.62,80.03 CPU1.AG13 ; v1(110.64,79.92) 110.8,79.76 CPU1.AG14 ; CPU1.AG17 109.18,79.86 v1(109.28,79.95)
  BOTTOM w0.381: CPU1.AG14 CPU1.AG16 CPU1.AG17
  BOTTOM w0.508: v3(112.5,106.45) 112.54,106.49 112.54,107.38 113.26,108.09 113.26,111.44 113.87,112.05 113.88,112.05 115.28,113.45 119.61,113.45 120.3,114.14 120.3,117.31 120.34,117.36 120.34,117.45 122.45,119.55 122.45,119.84 v1(122.46,119.85) ; v1(176.09,35.47) 176.88,35.47 177.23,35.12 179.27,35.12 180.01,34.38 181.71,34.38 186.71,29.38 v1(186.76,29.38) ; v1(148.92,91.13) 148.65,91.13 148.19,91.59 148.19,102.01 147.65,102.56 ; v3(121.36,104.86) 121.75,104.47 C2135.1
  vias: v1(110.44,96.45) v2(106.75,108.73) v2(116.91,105.63) v2(123.49,104.28) v3(111.66,106.46) v3(125.96,103.65) v3(126.02,102.76) v3(126.05,101.9) v3(126.9,103.64) v3(126.9,102.72) v3(126.9,101.89) v3(146.37,104.57) v3(146.45,103.42) v3(148.53,123.02) v3(149.36,122.75)
1D5V_S0: length 198.7
  TOP w0.508: R2705.1 32.35,3.26 32.35,2.67 v3(32.49,2.52)
  L3 w0.508: v3(73.09,104.69) 69.44,101.04 69.44,92.51 64.36,87.43 64.36,85.52 56.69,77.85 v1(56.69,74.37) ; v1(110.46,92.55) 110.46,93.24 112.12,94.89 112.12,99.16 v1(112.2,99.25)
  L4 w0.508: v3(32.49,2.52) 32.49,2.78 33.63,3.92 33.63,6.84 34.58,7.79 35.58,7.79 36.22,8.43 36.43,8.43 39.1,11.09 39.1,20.58 36.77,22.91 32.07,22.91 30.1,24.88 30.1,24.89 30,24.99 30,37.35 30.48,37.83 33.88,41.23 33.88,42.05 39.66,47.84 40.46,47.84 52.24,59.62 52.24,69.92 v1(56.69,74.37) ; v3(73.09,104.69) 74.09,104.69 75.41,106.01 93.58,106.01 96.02,108.45 99.92,108.45 100.73,109.26 107.67,109.26 108.28,109.87 112.53,109.87 114.08,111.42 v1(114.13,111.42)
  BOTTOM w0.254: v1(110.46,92.55) 110.33,92.41 110.33,92.33 110.08,92.09 110.08,91.77 110.13,91.73 110.13,88.95 CPU1.J15
  BOTTOM w0.508: 113.91,109.84 113.91,111.2 v1(114.13,111.42) ; 113.99,107.78 113.28,107.08 113.28,106.02 112.86,105.61 112.58,105.61 111.91,104.94 111.91,104.03 111.66,103.78 v2(111.66,102.89) 111.86,102.68 111.86,99.59 v1(112.2,99.25)
1D05V_VGA_EN: length 104.9
  TOP w0.127: U8301.3 149.47,121.26 149.12,121.61 148.48,121.61 C8309.2 148.23,120.54 PR8301.2 148.23,120.38 v1(147.74,119.88)
  L3 w0.127: v1(148.92,91.76) 148.66,91.76 147.85,90.95 147.85,89.81 143.7,85.66 143.7,74.41 145.59,72.52 145.59,64.89 146.15,64.33 146.15,62.31 149.24,59.21 150.36,59.21 150.88,58.7 152.87,58.7 155.37,56.2 155.37,55.13 159.97,50.53 164.35,50.53 166.54,48.34 v1(166.81,48.34)
  BOTTOM w0.127: v1(148.92,91.76) 148.64,92.04 148.64,103.21 149.31,103.88 149.31,118.15 147.93,119.53 147.93,119.69 v1(147.74,119.88) ; R8313.2 177.62,47.87 177.53,47.95 v2(177,47.95) 176.3,47.26 167.89,47.26 v1(166.81,48.34)
1D05V_VGA_OUT2:
  vias: v2(153.21,123.72)
1D05V_VGA_S0: length 28
  TOP w0.508: PR8316.1 148.86,112.16 v1(148.86,112.81)
  TOP w0.635: L7601.1 172.58,106.15 172.58,105.34 171.78,104.54 v3(171.78,104.03) 171.8,104 171.8,102.68 171.42,102.3 L7602.1
  L4 w0.508: v3(155.34,118.03) 155.34,119.45 154.99,119.8 152.93,119.8 149.64,116.51 149.64,114.81 149.55,114.72 149.55,113.5 v1(148.86,112.81)
  BOTTOM w0.635: v3(162.43,104.06) 162.46,104.03 v3(171.78,104.03)
  vias: v1(156.58,123.36) v1(159.17,124.9) v1(159.16,124.09) v1(159.18,123.28) v1(159.99,124.05) v1(160.83,122.42) v1(161.62,120.01) v1(161.59,119.09) v1(161.64,118.25) v1(161.62,112.52) v1(161.67,121.63) v1(162.05,117.75) v1(162.05,112.98) v2(156.18,129.51) v2(157.29,124) v2(160.88,121.45) v3(155.98,123.84) v3(155.98,122.86) v3(156.08,116.96)
1D05V_VGA_S0_DISCHG: length 2.4
  TOP w0.102: v2(149.77,111.22) PR8316.2 149.75,112.16 149.75,112.57 149.31,113.01 PQ8305.3
1D05V_VTT_PWRGD: length 137.9
  TOP w0.127: U701.2 78.05,96.72 R707.1 77.04,97.03 v1(76.38,97.7) ; v1(83,113.96) 83.26,114.22 v2(84.05,114.22) ; PR4821.2 132.95,128.73 132.68,128.46 131.66,128.46 131.4,128.21 R3611.1 131.39,127.87 v1(131.39,127.14)
  L3 w0.127: v1(76.38,97.7) 76.15,97.7 73.46,100.39 73.46,101.54 76.27,104.36 76.27,107.41 82.83,113.96 v1(83,113.96)
  L4 w0.127: v1(83,113.96) 83.49,114.45 83.49,115.05 83.32,115.21 83.32,121.06 85.66,123.4 85.66,135.03 87.03,136.4 92.95,136.4 93.17,136.62 93.17,138.61 91.77,140.01 91.77,146.03 91.69,146.11 91.69,148.73 96.08,153.13 97.35,153.13 98.69,154.47 102.07,154.47 103.42,153.13 109.86,153.13 110.89,152.09 111.86,152.09 114.96,148.99 120.8,148.99 124.58,145.2 129.18,145.2 130.94,143.45 130.94,132.74 132.7,130.98 132.7,129.76 131.62,128.68 131.62,127.37 v1(131.39,127.14)
1D35V_ENABLE: length 5.8
  BOTTOM w0.127: R8314.2 179.34,52.2 PR8310.1 179.35,51.37 PR8312.1 179.35,50.44 178.95,50.04 v2(178.95,49.65) 179.83,49.65 180.16,49.98 180.16,50.61 180.78,51.23 PQ8304.3
1D35V_ENABLE_RC: length 5.4
  BOTTOM w0.127: PQ8308.4 177.02,56.33 177.49,55.86 177.49,55.44 178.36,54.58 v2(178.36,54.29) 178.36,53.71 178.46,53.61 PC8302.1 R8314.1
1D35V_PWR: length 37.4
  TOP w0.203: PU4901.2 107.55,14.15 v3(107.79,13.91)
  L4 w1.524: 83.46,17.28 85.02,18.85 85.02,21.52 86.05,22.55 107.39,22.55 109.04,20.9 109.04,14.93 108.79,14.67
  vias: v1(107.45,13.25) v2(80.52,15.87) v3(77.97,17.28) v3(77.97,16.39) v3(78.98,17.28) v3(78.98,16.39) v3(80,17.28) v3(80,16.39) v3(81.01,17.28) v3(81.01,16.39) v3(82.03,17.28) v3(82.03,16.39) v3(83.05,17.28) v3(83.05,16.39)
1D35V_S3: length 59.4
  TOP w0.508: R3701.1 57.31,34.88 v3(57.56,34.64)
  BOTTOM w0.203: CPU1.AY35 98.04,70.96 98.01,70.93 98.01,70.29 v1(98.47,69.84) ; v1(95.32,70.08) 94.86,70.55 94.86,71.05 CPU1.AY40
  BOTTOM w0.254: CPU1.AR48 90.39,74.55 v1(90.53,74.55) ; v1(103.02,79.08) 103.02,79.08 CPU1.AH26 ; v1(92.06,70.48) 92.06,70.7 91.75,71.01 CPU1.AY44 ; CPU1.AY50 88.66,71.09 88.98,71.4 v1(89.02,71.4) ; v1(98.74,75.2) 98.87,75.2 CPU1.AN33 ; v1(96.47,79.05) 96.52,79 CPU1.AJ37 ; CPU1.AJ33 v1(99.12,79.14) ; v1(100.42,79.08) CPU1.AJ31
  BOTTOM w0.305: v1(93.48,74.51) 93.15,74.85 CPU1.AP43
  BOTTOM w0.33: v1(78.22,32.36) 78.45,32.13 DM1.87 ; DM1.81 76.65,32.32 v1(76.65,32.33) ; v1(78.69,21.4) 78.75,21.47 DM1.88 ; DM1.111 85.65,32.3 v1(85.67,32.33) ; DM1.117 v1(87.45,32.33) ; DM1.112 85.95,20.74 v1(86.18,20.52) ; DM1.106 84.15,21.79 v1(83.62,21.26) ; v1(74.88,32.33) 74.85,32.3 DM1.75 ; v1(87.58,20.52) 87.58,21.28 87.75,21.45 DM1.118 ; v1(82.74,32.25) 82.73,32.25 82.59,32.11 82.23,32.11 82.05,31.93 DM1.99 ; v1(75.13,21.4) 75.15,21.42 75.15,22.06 75.15,22.07 DM1.76 ; v1(80.46,21.4) 80.55,21.49 DM1.94 ; v1(83.89,32.33) 83.85,32.28 DM1.105 ; v1(89.23,32.33) 89.25,32.3 DM1.123 ; DM1.82 76.95,21.45 v1(76.91,21.4) ; DM1.93 80.25,32.13 v1(80.04,32.34) ; v1(82.24,21.4) 82.35,21.51 DM1.100 ; DM1.124 89.55,21.47 88.59,20.52 v1(88.26,20.52)
  BOTTOM w0.508: v1(113.11,55.97) 113.11,55.99 112.87,56.22 R410.1 ; v1(74.88,32.33) 73.15,34.05 58.14,34.05 v3(57.56,34.64)
  vias: v2(72.85,26.28) v2(75.08,54.02) v2(76.15,38.8) v2(82.37,22.29) v2(86.84,30.5) v2(90.14,66.79) v2(92.38,78.88) v2(100.34,57.44) v2(101.47,75.46) v2(104.67,39.67) v2(116.76,49.52) v2(132.87,51.17) v3(78.31,19.88) v3(78.81,20.64) v3(79.32,19.88) v3(79.83,20.64) v3(80.34,19.88) v3(80.85,20.64) v3(81.35,19.88) v3(81.86,20.64) v3(82.37,19.88) v3(83,20.64) v3(135.48,54) v3(135.45,52.78) v3(135.48,51.69) v3(136.22,53.37) v3(136.24,52.27)
1D35V_VGA_EN: length 52.9
  TOP w0.127: v1(180.72,50.44) 180.72,50.14 v2(180.39,49.8)
  L3 w0.127: v1(180.72,50.44) 180.72,49.4 176.86,45.53 172.27,45.53 171.09,46.71 171.09,47.8 168.47,50.42 166.8,50.42 165.09,52.13 164.89,52.13 164.89,52.13 160.64,52.13 156.97,55.8 156.97,57.3 155.91,58.35 155.91,60.8 157.53,62.43 v1(159.84,62.43)
  BOTTOM w0.127: PR5114.2 160.54,63.12 v1(159.84,62.43) ; R8312.2 179.69,48.33 D8301.3 182.76,48.96 R8305.1 182.13,49.66 181.56,50.23 180.93,50.23 v1(180.72,50.44) 180.8,50.44 181.43,51.07 PQ8304.2
1D35V_VGA_EN#:
  vias: v2(184.94,53.51)
1D35V_VGA_S0: length 58
  TOP w0.152: 157.13,138.36 157.18,138.42 157.18,139.26 157.07,139.37 v1(157.07,140.39)
  TOP w0.203: VRAM4.B2 151.43,141.18 152.25,141.18 VRAM4.D2 ; v1(157.07,140.39) 156.24,140.39 VRAM4.H2 ; v1(156.67,146.97) 157.05,146.59 v1(157.05,146)
  TOP w0.305: v1(152.19,147.1) 152.64,146.65 VRAM4.D9 ; v1(155.48,141.19) 155.84,140.82 VRAM4.H2 ; VRAM1.C9 183.9,139.99 v1(183.53,139.62) ; VRAM1.C1 VRAM1.D2
  TOP w0.356: VRAM1.F1 181.51,146.39 v1(181.09,146.8) ; v1(156.67,146.97) 156.45,146.97 155.87,146.39 VRAM4.H9 ; VRAM1.B2 VRAM1.A1 185.67,146.52 v1(186.12,146.52) ; VRAM4.N1 159.84,139.99 v1(160.26,140.4) ; VRAM4.K2 157.44,140.76 v1(157.07,140.39) ; v1(151.82,138.57) 151.82,139.14 151.84,139.15 VRAM4.C1 152.21,140.36 152.21,140.4 152.25,140.4 VRAM4.D2 ; v1(178.72,140.4) 178.72,140.41 VRAM1.K8 ; VRAM4.G7 155.43,145.18 v1(155.47,145.18) ; VRAM4.K8 157.44,145.61 v1(157.05,146) ; v1(183.53,139.62) 183.16,139.99 VRAM1.D9 ; VRAM1.N9 175.79,139.84 175.79,139.11 175.56,138.88 v1(175.56,138.65) ; VRAM1.K2 178.35,145.59 178.73,145.97 v1(178.76,145.97) ; VRAM1.G7 180.34,141.19 v1(180.3,141.19) ; VRAM1.R9 174.34,139.37 v1(174.19,139.22) ; VRAM1.H2 180.34,145.19 v1(180.38,145.19) ; VRAM4.B2 v1(150.63,141.2) ; v1(150.06,138.8) 150.24,138.98 VRAM4.A1 ; v1(161.44,139.46) VRAM4.R1 ; VRAM1.A8 185.51,140.79 v1(185.11,140.39) ; v1(149.41,145.69) 149.78,145.69 149.88,145.59 VRAM4.A8 ; v1(183.94,147.09) VRAM1.C1
  L3 w0.356: v1(178.72,140.4) 178.98,140.67 179.78,140.67 v1(180.3,141.19)
  L3 w0.381: v1(155.48,141.19) 155.48,141.18 155.49,141.18 156.02,140.66 156.02,140.61 156.02,140.61 156.02,140.16 156.02,140.15 156.02,139.86 ; 156.02,139.86 v1(155.61,139.44) ; 156.02,139.86 156.54,139.86 v1(157.07,140.39)
  L4 w0.356: v1(157.05,146) 156.5,145.46 155.75,145.46 v1(155.47,145.18)
  L4 w0.508: v1(150.63,141.2) 150.1,140.67 149.52,140.67 148.86,140.01 148.86,139.29 149.34,138.8 v1(150.06,138.8)
  BOTTOM w0.254: VRAM2.A8 185.54,145.72 186.11,146.29 186.11,146.52 v1(186.12,146.52)
  BOTTOM w0.305: 183.92,139.99 183.9,139.99 v1(183.53,139.62) ; 183.92,139.99 VRAM1.C9 ; 183.92,139.99 183.55,140.36 ; GPU1.E26 175.3,126 v1(175.3,126) ; v1(169.95,123.3) 169.95,123.33 170.31,123.69 GPU1.L24 ; VRAM3.G7 155.23,141.59 155.46,141.36 155.46,141.2 v1(155.48,141.19) ; VRAM3.H9 155.84,139.68 v1(155.61,139.44) ; v1(157.07,140.39) 157.07,140.42 VRAM4.K2 ; v1(160.26,140.4) 160.25,140.4 VRAM4.N1
  BOTTOM w0.356: v1(150.63,141.2) 150.63,141.14 150.28,140.79 VRAM3.A8 ; v1(157.05,146) 157.05,145.98 VRAM4.K8 ; v1(155.47,145.18) 155.47,145.22 VRAM3.H2 ; GPU1.E23 174.9,122.44 v1(174.9,122.37) ; VRAM2.A1 185.14,140.39 v1(185.11,140.39) 184.74,140.76 VRAM2.B2 ; GPU1.H24 172.81,123.64 172.44,123.27 v1(172.42,123.27) ; 183.55,140.36 183.14,140.77 VRAM2.D2 ; GPU1.H26 172.78,125.29 v1(172.4,124.91) ; VRAM3.D9 152.65,139.99 v1(153.04,139.59) VRAM3.E9 ; GPU1.L26 170.33,125.31 170.48,125.46 170.48,125.48 170.72,125.72 v1(170.73,125.72) ; v1(178.22,125.76) 177.75,125.29 GPU1.B26 GPU1.C25 ; VRAM4.C1 151.84,139.15 151.82,139.14 v1(151.82,138.57) ; v1(161.44,139.46) VRAM4.R1
  BOTTOM w0.508: v1(154.64,139.39) 155.55,139.39 v1(155.61,139.44) ; EC9727.1 195.42,110.86 v1(195.37,110.81)
  vias: v1(150.1,147.87) v1(152.22,145.99) v1(153.85,146.97) v1(159.84,147.03) v1(160.92,148.15) v1(161.73,150.51) v1(164.16,120.77) v1(164.92,120.77) v1(165.55,120.77) v1(167.33,120.77) v1(170.25,120.77) v1(172.11,137.08) v1(172.16,136.44) v1(172.54,120.8) v1(172.78,136.31) v1(173.17,119.12) v1(173.15,116.69) v1(173.18,116.03) v1(173.17,115.06) v1(174.83,147.95) v1(175.71,147.64) v1(178.22,136.21) v1(178.73,135.7) v1(181.18,138.32) v1(182.72,147) v1(183.27,147.42) v2(146.58,137.63) v2(147.09,151.55) v2(159.66,132.78) v2(165.76,150.36) v2(165.99,126.31) v2(183.48,135.6) v2(184.13,124.9) v2(186.59,150.74) v3(145.92,147.49) v3(145.93,146.6) v3(145.94,145.62) v3(147.1,147.45) v3(148.24,148.45) v3(148.26,149.76) v3(149.54,149.77) v3(150.86,149.8) v3(152.67,149.74) v3(162.17,149.91) v3(163.34,149.9) v3(171.02,150.82) v3(171.52,59.89) v3(171.64,57.75) v3(171.9,150.82) v3(174.57,59.63) v3(174.57,57.73) v3(176.6,57.73) v3(179.02,58.36) v3(180.03,59.76) v3(180.41,149.73) v3(181.49,149.72) v3(183.46,59.25) v3(183.58,149.75) v3(194.55,131.25) v3(194.55,130.37) v3(194.56,129.53) v3(194.61,128.62) v3(195.4,131.24) v3(195.43,130.4) v3(195.45,129.51) v3(196.31,131.25) v3(196.33,130.41)
1D35V_VTT_PWRGD: length 217.9
  TOP w0.127: R3610.1 133.71,126.17 v1(133.94,125.94) ; PU4901.20 106.15,13 107.96,11.18 PR4904.2 107.96,9.66 v2(108.08,9.54) 108.23,9.39 109.55,9.39 110.45,8.49 v1(110.45,7.79)
  L3 w0.127: v1(148.78,53.33) 148.78,52.51 148.61,52.34 148.61,48.75 153.26,44.1 153.26,42.68 158.42,37.53 159.41,37.53 162.41,34.53 162.41,34.45 163.39,33.48 165.14,33.48 166.43,32.19 166.7,31.92 171.18,31.92 v1(172.84,30.26)
  L4 w0.127: v1(148.78,53.33) 149.9,54.45 149.9,56.57 144.6,61.87 144.6,86.33 146.1,87.83 146.1,94.09 144.92,95.27 144.92,99.5 144.59,99.83 144.59,100.67 142.94,102.32 142.94,104.55 139.18,108.31 139.18,110.26 139.71,110.78 139.71,112.67 137.2,115.18 137.2,122.69 v1(133.94,125.94) ; v1(110.45,7.79) 110.45,7.47 111.79,6.13 125.34,6.13 125.83,6.62 126.58,6.62 127.21,7.25 132.8,7.25 133.49,6.56 138.21,6.56 138.56,6.2 143.28,6.2 144.86,7.78 148.1,7.78 152.34,7.78 154.17,5.95 154.96,5.95 164.72,5.95 164.98,6.21 166.86,8.08 170.07,8.08 175.1,13.11 175.1,21.53 176.46,22.89 176.46,25.32 175.19,26.59 175.19,27.07 174.69,27.58 174.58,27.58 172.98,29.17 172.98,30.12 v1(172.84,30.26)
3D3V_AUX_KBC: length 384.7
  TOP w0.305: R2453.2 v1(177.81,17.72)
  TOP w0.508: R2418.2 157.76,27.92 157.75,27.93 v3(157.75,29.13) 157.75,29.62 R2414.2 ; v3(168.55,18.18) 168.55,18.18 168.13,17.75 168.13,16.88 R2402.2 ; D4302.2 125.53,147.52 v1(127.19,147.52) 127.74,146.97 127.74,145.99 v2(127.94,145.79) 128.39,145.33 128.9,145.33 D4303.2 ; v1(155.49,33.92) 155.12,33.55 Q2402.D 155.19,32.92 155.85,32.92 155.86,32.92 156.33,32.92 156.79,33.38 R2413.2 ; v1(97.79,139.03) 97.25,138.5 96.69,138.5 95.65,137.46 v1(95.65,137.2) ; D4301.2 134.56,146.46 133,148.02 133,149.71 134.26,150.98 v1(134.67,150.98) ; v1(184.99,52.39) 185.62,51.76 185.62,49.58 178.89,42.85 178.89,41.98 177.95,41.04 177.95,39.11 177.37,38.53 v1(177.37,38.42)
  L3 w0.305: v3(168.55,18.18) 170.68,18.18 171.77,17.1 177.19,17.1 v1(177.81,17.72)
  L3 w0.508: v1(155.49,33.92) 155.31,33.74 155.31,32.99 156.12,32.17 156.12,31.15 157.39,29.89 157.75,29.52 v3(157.75,29.13) ; v3(168.55,18.18) 168.17,17.8 165.1,17.8 164.26,18.64 161.55,18.64 v1(161.41,18.51) ; v1(157.93,43.97) 157.29,43.97 152.78,48.48 152.78,51.17 150.31,53.64 150.31,53.96 146.82,57.45 v1(144.95,57.45) ; v1(97.79,139.03) 97.31,139.03 97.02,139.31 97.02,141.21 v1(97.2,141.39) 99.5,143.69 99.5,143.73 103.75,147.98 106.21,147.98 107.27,146.92 108.15,146.92 108.5,147.26 108.5,147.81 111.18,150.49 116.2,150.49 116.37,150.67 118.17,150.67 119.26,151.76 124.31,151.76 v1(124.58,152.04) 125.45,152.04 125.65,152.24 133.42,152.24 v1(134.67,150.98)
  L4 w0.508: v1(157.93,43.97) 161.02,43.97 163.4,41.6 164.83,41.6 165.83,40.59 165.83,39.5 166.86,38.47 170.34,38.47 170.84,37.96 176.92,37.96 v1(177.37,38.42) ; v1(134.67,150.98) 133.98,150.98 133.28,150.28 133.28,148.06 138.35,142.98 138.35,136.15 138.93,135.58 138.93,133.59 138.18,132.84 138.18,129.46 140.06,127.58 140.06,122.14 141.42,120.77 141.42,120.36 141.43,120.35 141.43,119.82 141.42,119.82 141.42,110.9 v1(140.31,109.79) ; v3(157.75,29.13) 157.75,26.84 158.65,25.95 158.65,21.28 v1(161.41,18.51) ; v1(118.62,46.88) 118.18,46.88 117.84,47.23 112.19,47.23 110.44,48.98 110.44,56.38 106,60.83 106,61.99 106.63,62.63 v1(106.64,62.63)
  BOTTOM w0.508: v3(157.75,29.13) 158.31,29.69 159.45,29.69 160.12,29.02 164.92,29.02 166.96,26.99 R2434.1 167.41,27 R2436.1 167.76,27.84 168.4,28.47 R2403.2 168.52,28.81 169.19,29.48 170.05,29.48 172.67,26.87 172.67,25.98 173.28,25.37 173.28,23.16 172.86,22.74 R2607.1 ; v1(155.49,33.92) 155.6,34.03 155.6,34.04 156.99,35.43 156.99,36.85 157.36,37.22 158.18,37.22 158.19,37.21 158.92,37.21 159.78,38.06 R2426.2 159.78,38.69 v3(158,40.46) 158,40.53 157.55,40.98 157.55,43.59 v1(157.93,43.97) ; v1(127.19,147.52) 127.19,149.64 124.79,152.04 124.59,152.04 v1(124.58,152.04) ; v1(177.37,38.42) 176.42,37.47 R2452.2 ; PR4415.1 97.79,138.57 v1(97.79,139.03) ; PR8314.1 185.56,52.39 v1(184.99,52.39) ; v1(118.62,46.88) 120.92,46.88 122.33,48.29 132.93,48.29 133.63,48.99 134.11,48.99 134.56,49.44 134.56,54.12 135.94,55.5 143,55.5 v1(144.95,57.45) 144.95,59.07 142.64,61.38 142.64,81.45 143.33,82.13 143.33,97.67 140.79,100.21 140.79,109.31 v1(140.31,109.79) ; R2608.1 v1(106.64,62.63) ; v1(95.65,137.2) 95.65,136.04 95.76,135.94 96.17,135.53 97.96,135.53 PR4412.1 ; PR4439.1 97.33,141.52 v1(97.2,141.39)
3D3V_AUX_KBC_VCC: length 64.1
  TOP w0.203: v1(164.65,28.37) 163.18,26.9 KBC24.88 ; KBC24.19 178.79,30.9 179.24,31.35 179.84,31.35 179.89,31.39 ; KBC24.46 170.89,36.77 171.21,36.45 v1(171.68,36.45) ; 160.93,31.7 KBC24.76 ; 169.92,24.93 170.05,24.81 170.46,24.81 170.88,24.38 170.88,22.99 170.89,22.98 KBC24.115
  TOP w0.508: 169.92,24.93 169.64,25.22 169.64,26.86 v1(170.1,27.32) ; 179.89,31.39 181.51,31.39 v2(181.56,31.44) v1(182.99,31.44) ; 160.93,31.7 160.89,31.74 160.11,31.74 159.86,31.99 159.26,31.99 C2411.1 159.14,31.2 v1(159.46,30.88)
  L3 w0.508: v1(170.1,27.32) 170.05,27.37 169.31,27.37 168.32,28.37 v1(164.65,28.37) 161.17,31.84 160.03,31.84 159.46,31.27 v1(159.46,30.88)
  L4 w0.508: v1(170.1,27.32) 170.36,27.58 170.36,35.13 v1(171.68,36.45)
  BOTTOM w0.508: v1(159.46,30.88) 159.46,31.19 160.31,32.04 C2406.1 C2407.1 ; C2408.1 171.39,37.19 C2409.1 171.39,36.74 v1(171.68,36.45) 171.68,35.23 172.68,34.23 174.15,34.23 175.09,33.29 177.63,33.29 C2410.1 177.65,33.31 181.86,33.31 182.99,32.17 v1(182.99,31.44) ; v1(170.1,27.32) 169.93,27.15 R2403.1
3D3V_AUX_S5: length 461.1
  TOP w0.102: 156.92,32.09 157.46,32.63 159.85,32.63 160.26,32.22 161.16,32.22 161.29,32.1 KBC24.75
  TOP w0.508: PR4532.2 129.97,43.43 v1(129.89,43.5) ; v1(63.48,18.86) 63.47,18.85 63.47,18.45 55.6,10.57 v1(55.6,5.73) ; R2439.1 153.81,24.77 154.6,25.56 154.6,27.28 154.53,27.35 v1(154.53,28.01) 154.53,28.16 154.92,28.55 R2431.2 154.92,29.7 C2417.2 154.91,29.89 Q2402.S 156.1,31.47 156.73,32.09 156.92,32.09 ; v1(104.43,129.71) 103.23,130.91 102.18,130.91 100.88,132.21 v1(100.05,132.21) 100.05,132.91 100.63,133.49 100.63,136.95 100.64,136.96 v2(100.64,138.65) 100.64,139.65 v1(101.14,140.15) ; PR4501.1 124.25,42.97 123.72,42.43 v1(123.55,42.43) ; v1(184.25,52.39) 184.25,49.27 178.13,43.15 178.13,42.2 177.29,41.36 177.29,39.38 176.74,38.83 176.74,38.1 v1(177.34,37.49) ; v1(114.87,15.95) 115,15.82 R3607.1
  L3 w0.508: v1(114.87,15.95) 114.87,19.24 116.7,21.07 116.7,37.6 121.53,42.43 v1(123.55,42.43) 123.41,42.58 123.41,47.57 ; v1(104.43,129.71) 105.04,129.1 111.51,129.1 111.6,129.19 115.21,129.19 116.3,128.1 121.35,128.1 125.67,132.43 132.03,132.43 132.48,131.97 133.61,131.97 134.76,130.83 138.12,130.83 143.79,125.16 v1(143.79,125.12) ; 123.41,47.57 v1(118.62,47.57) ; 123.41,47.57 123.41,47.92 124.08,48.59 124.08,50.11 126.92,52.95 126.92,55.75 128.34,57.18 128.34,58.41 129.59,59.65 v3(129.59,60.11)
  L4 w0.508: v1(184.25,52.39) 183.26,51.4 179.01,51.4 177.87,50.26 171.87,50.26 170.64,51.48 156.18,51.48 153.96,53.7 153.96,56.31 147.25,63.02 147.25,64.27 146.28,65.24 146.28,85.95 147.52,87.19 147.52,94.56 146.25,95.83 146.25,100.05 145.92,100.38 145.92,101.98 144.34,103.56 144.34,105.09 143.79,105.64 v1(143.79,125.12) ; v1(154.53,28.01) 149.12,28.01 141.35,35.77 141.35,38.49 140.05,39.8 139.55,39.8 138.86,40.49 134.02,40.49 131.58,42.92 131.58,44.24 130.86,44.96 126.25,44.96 123.72,42.43 v1(123.55,42.43) ; v1(63.48,18.86) 66.89,18.86 69.76,15.99 72.82,15.99 78.79,10.02 78.79,9.52 79.78,8.54 103.92,8.54 104.57,9.19 104.57,10.43 106.17,12.03 113.39,12.03 114.87,13.51 v1(114.87,15.95) ; v1(118.62,47.57) 118.24,47.95 112.38,47.95 111.08,49.25 111.08,56.65 106.68,61.05 v1(106.68,61.74) ; v1(166.64,26.08) 167.55,26.99 167.55,32.36 166.95,32.96 166.95,35.63 168.65,37.33 177.18,37.33 v1(177.34,37.49)
  BOTTOM w0.508: R1726.2 129.49,62.37 129.49,61.87 129.52,61.84 129.52,60.19 v3(129.59,60.11) 129.68,60.11 129.76,60.19 130.66,60.19 131.07,59.77 R1727.1 ; v1(123.55,42.43) 123.79,42.67 128.91,42.67 129.74,43.5 v1(129.89,43.5) ; R2434.2 166.66,26.1 v1(166.64,26.08) 166.46,26.26 166.46,26.46 165.21,27.71 162.87,27.71 162.04,26.87 R2425.2 161.87,26.16 160.37,26.16 159.1,27.43 157.29,27.43 156.72,28.01 v1(154.53,28.01) ; D2501.1 55.31,6.02 v1(55.6,5.73) ; v1(100.05,132.21) 100.11,132.15 PR4434.1 ; PR4417.1 99.49,140.07 100.02,140.59 PR4435.1 100.7,140.59 v1(101.14,140.15) ; PR8313.1 184.29,52.35 v1(184.25,52.39) 184.06,52.58 PR8311.1 ; R2609.1 v1(106.68,61.74) ; PR4438.2 105.61,131.64 105.24,131.27 105.24,131.17 104.87,130.81 104.87,130.59 PR4419.1 104.43,130.14 104.43,129.79 v1(104.43,129.71)
3D3V_CAMERA_S0: length 33.3
  TOP w0.305: LCD1.32 31.45,82.8 31.24,82.59 v3(31.18,82.59)
  L3 w1.016: v3(23.34,87.27) 23.34,92.5 22.07,93.77 18.97,93.77 15.81,90.6 v3(15.81,89.6)
  L4 w0.762: v3(31.18,82.59) 31.16,82.61 30.47,82.61 29.8,83.29 27.57,83.29 25.68,81.4 22.57,81.4 21.69,82.29 21.69,84.85 23.34,86.5 v3(23.34,87.27)
3D3V_LAN_S5: length 1
  BOTTOM w0.203: 37.35,60.22 LOM30.11
  vias: v2(37.01,59.33) v2(47.06,66.41) v2(47.11,54.83) v3(31.38,65.27) v3(35.77,60.25) v3(43.45,57.3) v3(45.84,67.26)
3D3V_PWR:
  vias: v2(126.67,14.01)
3D3V_PWR_2: length 4.8
  TOP w0.203: 130.25,40.71 PU4503.3
  TOP w0.508: v2(132.35,41.77) PC4526.1 130.92,41.91 PR4532.1 129.97,41 130.25,40.72 130.25,40.71
3D3V_S0: length 267.9
  TOP w0.305: Q5402.5 Q5402.2 17.98,80.59 v1(18.36,80.97)
  TOP w0.508: PR4904.1 109.65,10.99 110.67,12.01 112.27,12.01 113.21,12.95 v3(113.21,13.3) ; R2710.1 31.37,2.79 v3(31.61,2.55) ; R4622.1 121.94,118.89 122.43,118.4 122.43,116.94 v3(122.56,116.81) ; v3(123.61,98.87) 123.61,99.05 124.45,99.89 125.37,99.89 126.03,100.55 127.76,100.55 ; R5231.1 31.98,70.02 31.61,70.39 v3(30.67,70.39) ; R2012.1 110.46,83.19 110.09,83.19 C2128.1 109.88,83.65 110.7,84.47 110.7,85.06 v1(110.25,85.51) 110.25,85.51 110.25,86.21 109.55,86.91 109.55,87.89 109.71,88.05 109.71,90.5 109.32,90.89 109.32,93.47 109.62,93.77 109.62,97.63 111.91,99.92 115.16,99.92 v2(115.36,99.71) 116.04,99.71 v1(116.21,99.55) ; v1(108.02,110.53) 108.43,110.13 R2604.1 ; v3(22.17,92.02) 22.68,92.52 23.52,92.52 25.17,90.87 33.6,90.87 38.05,86.43 v1(38.05,84.65) ; C1203.1 113.14,33.1 v1(113.23,33.01) ; 128.22,96.08 128.57,96.44 128.57,99.74 127.76,100.55 ; v3(178.98,40.54) 179.52,40.54 R2415.2 ; 127.76,100.55 127.76,105.23 124.31,108.69 124.31,110.63 123.07,111.86 123.07,112.65 v1(122.89,112.83) ; R3601.1 132.08,125.8 v1(132.36,125.52)
  L3 w0.508: v1(116.21,99.55) 122.94,99.55 v3(123.61,98.87) ; v1(149.02,119.22) 148.33,118.53 146.53,118.53 140.09,124.97 134,124.97 133.45,125.52 v1(132.36,125.52) ; v3(22.17,92.02) 19.38,92.02 18.9,91.53 18.9,89.81 19.61,89.09 19.61,86.53 18.36,85.29 v1(18.36,80.97) ; v3(122.56,116.81) 122.33,116.58 122.33,115.65 123.81,114.17 123.81,113.81 123.83,113.8 123.83,113.27 123.46,112.9 122.96,112.9 v1(122.89,112.83) 122.67,113.05 121.11,113.05 120.01,111.96 117.96,111.96 117.63,112.29 v3(116.51,112.29) 113.61,112.29 112.96,111.64 109.13,111.64 v1(108.02,110.53)
  L3 w1.27: 128.34,6.67 128.34,9.31 126.13,11.52 117.01,11.52 115.36,13.17 113.34,13.17 v3(113.21,13.3)
  L4 w0.508: v1(19.68,9.47) 21.13,9.47 22.38,8.22 26.62,8.22 v3(28.83,6.01)
  L4 w0.762: 38.94,72.33 38.64,72.62 31.45,72.62 30.78,71.95 30.78,70.5 v3(30.67,70.39) ; v3(38.83,22.14) 39.9,21.07 39.9,10.82 36.75,7.67 36.53,7.67 35.89,7.03 34.9,7.03 34.39,6.52 34.39,2.48 33.69,1.78 32.97,1.78 32.85,1.66 32.13,1.66 31.61,2.18 v3(31.61,2.55) 31.61,3.23 v3(28.83,6.01)
  BOTTOM w0.254: v1(110.25,85.51) 110.25,85.83 110.63,86.21 110.63,86.79 110.75,86.92 110.75,86.96 111.05,87.26 CPU1.K14 111.05,88.02 110.1,88.02 CPU1.K16 ; v1(125.17,80.52) 125.17,80.46 124.79,80.08 124.65,80.08 R1701.1
  BOTTOM w0.33: DM1.199 112.05,31.98 113.08,33.01 v1(113.23,33.01)
  BOTTOM w0.356: Q1801.5 v1(129.41,72.38) Q1801.2 ; RN1810.1 130.19,74.57 129.77,74.14 v1(129.19,74.14) ; RN1810.2 129.24,75.1 v1(128.84,74.7)
  BOTTOM w0.381: R2005.1 123.52,86.94 123.84,87.25 R2006.1 ; v3(128.85,93.17) 129.7,94.02 130.33,94.02 130.66,94.35 131.82,94.35 132.16,94.02 133.58,94.02 134.07,93.52 134.07,92.88 R2023.1
  BOTTOM w0.508: v1(139.91,94.05) 139.96,94.1 R6212.1 ; v3(166.93,14.44) 166.15,14.44 DB1.1 ; R7650.2 195.94,107.13 195.94,102.95 C8301.1 193.71,101.81 192.5,101.81 191.55,100.86 Q8302.S ; v3(28.83,6.01) 28.83,5.75 29.11,5.47 R2701.1 ; R5208.1 v1(38.05,84.65) ; R2006.1 123.96,87.7 125.35,87.7 v1(125.45,87.8) ; R2603.1 C2602.1 116.88,112.65 v3(116.51,112.29) ; R2914.1 19.2,9.95 v1(19.68,9.47) ; R5607.1 v1(190.83,76.16) ; v1(122.89,112.83) 122.19,113.53 R6217.1
  vias: v1(37.72,62.75) v1(128.84,90.67) v1(149.68,119.17) v3(26.44,21.58) v3(27.35,21.58) v3(28.3,21.59) v3(29.18,21.59) v3(37.39,63.41) v3(38.33,63.19) v3(39.88,71.7) v3(40.69,72.06) v3(123.9,95.32) v3(124.55,54.71) v3(125.56,54.7) v3(126.36,58.67) v3(126.61,5.34) v3(127.45,5.68) v3(128.34,5.28) v3(129.13,88.61) v3(129.18,5.43) v3(149.93,94.81) v3(179.95,9.15) v3(180.08,14.37) v3(180.07,13.53) v3(183.07,24.58) v3(188.06,97.05)
3D3V_S5: length 504.1
  TOP w0.406: C702.1 76.49,96.18 77.22,95.45 U701.5
  TOP w0.508: PR4473.2 140.35,146.44 v3(140.35,146.44) ; v3(124.2,63.31) 124.15,63.36 122.49,63.36 122.24,63.62 122.24,64.13 121.81,64.56 R2101.1 ; R2712.2 30.68,21.37 30.73,21.42 30.73,22.34 31.42,23.03 37.14,23.03 39.41,25.3 39.41,25.3 42.52,28.4 v1(42.52,28.41) ; v3(153.85,60.58) v2(153.85,59.12) 153.85,53.52 160.89,46.48 160.89,43.24 159.94,42.29 155.69,42.29 153.78,40.38 153.78,38.75 v3(155.26,37.28) ; PR4204.1 113.45,142.94 111.38,142.94 ; v3(75.28,96.56) 75.44,96.56 75.82,96.18 C702.1 ; R6401.2 12.47,76.25 12.16,76.56 v3(12.06,76.56) 12.01,76.5 10.57,76.5 9.57,75.51 3.45,75.51 2.56,74.62 LIDSW1.2 ; PR4534.1 v1(124.53,38.55)
  TOP w1.016: 142.87,11.85 142.16,12.56 139.32,12.56 138.59,11.83 137.1,11.83 136.82,12.11 131.11,12.11 128.5,9.49
  L3 w0.508: v1(122.6,85.46) 122.8,85.26 122.8,83.83 122.03,83.05 118.95,83.05 118.23,82.34 117.42,82.34 117.27,82.49 ; v3(155.26,37.28) 155.26,37.03 157.26,35.03 158.93,35.03 163.03,30.92 v3(164.57,30.92) ; v3(62.34,86.72) 62.34,86.24 46.73,70.63 41.95,70.63 40.15,68.83 40.15,67.62 v3(40.24,67.54) 40.24,67.31 42.91,64.64 42.91,57.84 40.24,55.18 40.24,51.73 v3(40.28,51.68) ; v3(130.72,49.41) 129.88,50.26 128.61,50.26 127.12,48.77 127.12,41.63 124.53,39.05 v1(124.53,38.55)
  L3 w0.762: v3(110.76,145.92) 111.77,145.92 113.13,147.28 114.14,147.28 115.19,148.33 117.09,148.33 117.27,148.51 120.62,148.51 121.16,147.97 123.13,147.97 124.2,149.04 133.38,149.04 134.01,148.4 138.03,148.4 138.27,148.4 140.23,146.44 v3(140.35,146.44)
  L3 w1.016: v3(140.23,84.29) 138.34,86.19 v3(134.31,86.19) ; v3(130.72,49.41) 131.95,48.19 131.95,45.72 136.27,41.4 138.36,41.4 140.68,39.08 140.68,37.52 v1(142.11,36.09) 143.39,34.82 143.39,32.73 144.15,31.97 144.15,22.91 144.55,22.51 145.51,21.55 145.51,12.16 v3(145.36,12.01)
  L4 w0.508: v1(107.84,147.68) 109.6,145.92 v3(110.76,145.92) ; v3(75.28,96.56) 75.06,96.34 74.46,96.34 71.99,93.87 70.94,93.87 65.83,88.76 64.38,88.76 v3(62.34,86.72) ; v3(124.2,63.31) 122.78,63.31 122.24,63.85 122.24,64.13 122.24,64.13 122.24,66.24 122.86,66.87 124.85,66.87 124.9,66.82 131.34,66.82 131.75,66.41 131.75,65.6 v3(132.61,64.74) ; v1(122.3,112.25) 122.43,112.13 123.51,112.13 125.26,110.38 125.26,109.38 125.52,109.11 134.54,109.11 136.05,110.62 v3(137.22,110.62) ; v1(142.11,36.09) 142.35,35.86 146.45,35.86 v1(147.6,34.7) ; v1(122.6,85.46) 123.29,85.46 124.99,87.16 125.71,87.16 125.89,87.34 127.28,87.34 127.81,87.87 127.81,89.7 128.06,89.96 128.06,90.79 128.58,91.31 129.83,91.31 130.01,91.13 132.53,91.13 v3(132.92,90.75) ; v3(12.06,76.56) 12.08,76.57 13.19,76.57 18.71,71.06 24.5,71.06 29.83,65.73 v3(30.12,65.73) ; v3(145.36,12.01) 146.41,12.01 146.66,12.26 149.76,12.26 v3(149.96,12.06)
  L4 w0.762: v3(140.88,122.81) 140.89,122.82 140.89,127.83 138.94,129.78 138.94,132.53 140.32,133.91 140.32,135.26 139.11,136.47 139.11,140.86 140.35,142.1 v3(140.35,146.44)
  L4 w2.032: 51.45,20.32 44.9,26.87 44.07,26.87 v1(42.52,28.41) 41.95,28.98 41.95,41.34
  BOTTOM w0.254: CPU1.Y8 114.48,82.79 114.48,83.09 v1(114.49,83.09)
  BOTTOM w0.508: R2421.2 165.16,31.52 v3(164.57,30.92) ; v3(30.12,65.73) 30.81,66.42 34.72,66.42 36.35,68.05 37.16,68.05 38.78,69.67 39.65,69.67 40.04,69.28 40.04,67.74 v3(40.24,67.54) 40.34,67.43 R3033.2 ; R2412.2 151.65,8.77 151.08,9.34 150.95,9.34 149.96,10.33 v3(149.96,12.06) ; v3(12.06,76.56) 12.08,76.55 C6402.1 ; PR5112.1 154.3,61.03 v3(153.85,60.58) 154.29,60.14 PC5109.1 ; R2501.2 146.69,35.62 v1(147.6,34.7) 149.13,33.18 151.13,33.18 151.84,33.9 151.84,34.76 ; v3(137.22,110.62) 137.22,111.94 137.47,112.18 137.47,119.02 140.88,122.44 v3(140.88,122.81) ; v1(107.84,147.68) 107.54,147.98 PR4211.2 ; v3(132.61,64.74) 132.61,63.14 135.03,60.72 136.05,60.72 ; v1(122.3,112.25) 122.03,112.53 120.48,112.53 120.23,112.28 PC5119.1 120.23,110.42 PU5101.1
  BOTTOM w1.016: v3(140.23,84.29) 141.73,82.8 141.73,60.11 140.43,58.82
  vias: v3(41.37,43.04) v3(42.31,43.27) v3(55.47,19.07) v3(55.47,18.15) v3(56.31,19.1) v3(56.31,18.18) v3(122.29,9.03) v3(123.18,9.03) v3(124.07,9.03) v3(124.96,9.03) v3(125.8,9.05) v3(144.37,11.99)
3D3V_S5_PCH: length 67.8
  TOP w0.254: v1(136.09,66.11) 135.92,65.94 134.83,65.94 134.61,65.72 131.84,65.72 131.18,66.38 130.58,66.38 130.58,66.37 129.81,66.37 129.81,66.38 129.72,66.38 129.72,66.37 128.95,66.37 128.94,66.38 128.17,66.38 R2015.1 127.63,67.51 127.46,67.68 127.46,68.06 127.76,68.36 128.47,68.36 129.03,67.8 R2010.1
  TOP w0.508: R2013.2 135.46,68.09 136.34,67.2 136.34,66.36 v1(136.09,66.11) 136.09,56.96 134.31,55.19 127.27,55.19 126.85,54.76 126.85,54.18 126.43,53.77 118.71,53.77 v2(117.27,55.21) 115.98,56.51 115.22,56.51 114.23,57.49 114.23,59.02 R2102.2
  TOP w0.635: R2108.1 109.17,58.75 110.38,57.54 112.4,57.54 113.9,59.03 R2102.2
  L4 w0.508: v1(128.85,84.93) 129.32,84.93 129.97,85.58 129.97,88.78 130.91,89.72 v3(134.15,89.72)
3D3V_VGA_OUT1:
  vias: v2(153.16,118.46)
3D3V_VGA_S0: length 167.5
  TOP w0.508: v1(147.09,119.88) 147.06,119.91 147.06,120.25 PR8301.1
  L3 w0.508: v1(186.72,93.81) 186.72,95.55 180.82,101.45 180.82,102.34
  L4 w0.508: v1(147.09,119.88) 147.05,119.85 146.73,119.85 145.34,118.46 145.34,106.65 147.19,104.79 147.19,100.91 147.52,100.58 147.52,96.35 148.79,95.08 148.79,92.9 149.89,91.81 149.89,87.25 147.57,84.93 147.57,72.51 v1(149.1,70.99) 149.1,64.94 150.87,63.16 153.6,63.16 155.52,61.24 155.52,58.72 156.12,58.12 156.12,54.6 157.08,53.64 171.7,53.64 172.45,52.9 182.19,52.9 v3(185.62,56.33)
  BOTTOM w0.356: GPU1.G8 173.63,110.43 v1(173.19,110.87) 173.19,111.01 173.45,111.27 GPU1.G9
  BOTTOM w0.508: R7608.1 188.24,116.57 v1(188.33,116.48) ; v3(185.62,56.33) 186.72,57.43 v2(186.72,59.25) 186.72,64.98 189.43,67.68 189.43,93.12 188.73,93.81 v1(186.72,93.81) ; v3(186.99,106.18) 185.22,106.18 R7647.2 ; PR8256.1 151.96,72.63 150.92,71.59 149.7,71.59 v1(149.1,70.99)
  vias: v3(179.25,102.18) v3(180.11,102.17) v3(190.89,105.75)
27MHZ_IN: length 11.8
  BOTTOM w0.102: GPU1.C11 177.39,112.47 180.74,112.47 180.99,112.72 181.47,112.72 181.86,112.32 R7603.1 C7607.2 183.27,112.32 183.51,112.09 183.51,111.05 ; X7601.1 186.15,111.39 185.62,110.86 183.59,110.86 183.51,110.94 183.51,111.05 ; 183.51,111.05 v2(183.38,111.05)
27MHZ_OUT: length 5.8
  BOTTOM w0.102: R7604.2 182.27,110.64 R7603.2 181.82,111.44 181.53,111.14 v2(181.35,111.14) 181.3,111.19 179.62,111.19 179.16,111.65 178.17,111.65 GPU1.B10
27MHZ_OUT_R: length 3.5
  BOTTOM w0.14: X7601.3 184.43,109.77 C7608.2 183.09,109.73 R7604.1 181.73,109.17 v2(181.73,108.93)
+0D675V_DDR_P:
  vias: v2(108.35,12.03)
+1.05M_ASW: length 2.3
  BOTTOM w0.254: CPU1.AF9 CPU1.AE9
  BOTTOM w0.305: v1(113.1,80.24) 113.11,80.23 CPU1.AE9 ; v1(114.5,79.28) 114.31,79.08 CPU1.AG8
  vias: v1(103.65,80.17) v1(104.29,80.17) v2(110.99,81.02)
+3.3A_DSW_PRTCSUS: length 22.5
  TOP w0.254: v1(112.02,77.89) 111.87,77.74 111.87,77.48 111.24,76.86 111.24,72.65 109.86,71.27 109.86,69.52 109.61,69.27 v2(109.61,67.51) 109.61,66.88 110.42,66.07 110.42,65.17 111.04,64.56 111.04,63.67 111.8,62.9 112.14,62.9 113.09,61.95 113.09,61.95 113.79,61.25 113.79,60.81 R2102.1 114.98,60.36 C2109.1
  BOTTOM w0.254: v1(112.02,77.89) 112.03,77.91 112.1,77.91 CPU1.AH11
+DC_IN: length 14.9
  TOP w0.508: PQ4205.E 108.23,148.61 v1(108.23,148.85)
  L3 w0.508: v1(100.66,154.03) 102.12,152.57 v1(106.09,152.57) 106.09,152.61 106.79,153.31 107.68,153.31 109.07,151.92 109.07,150.98 109.06,150.97 109.06,150.58 108.23,149.75 v1(108.23,148.85)
  BOTTOM w0.508: PR4212.1 106.17,152.87 106.09,152.79 v1(106.09,152.57)
  vias: v2(98.91,155.41)
+DC_IN_C:
  vias: v2(105.92,144.77) v2(106.18,147.16) v3(103.91,145.47) v3(103.87,144.55) v3(104.44,146.14) v3(104.66,145.09) v3(105.31,146.16) v3(105.6,145.37) v3(106.22,146.19) v3(106.46,145.37)
+PCH_VCCDSW: length 5.2
  TOP w0.254: v1(107.96,78.55) 107.96,77.98 v2(107.52,77.55) 107.05,77.07 107.05,75.99 R2110.1 108.15,75.93 C2101.2
  BOTTOM w0.254: CPU1.AG19 108,78.55 v1(107.96,78.55) 107.92,78.55 CPU1.AG20
+PWR_SRC_1D35V:
  vias: v2(97.58,13.23) v3(96.09,12.39) v3(96.97,12.39) v3(97.86,12.39) v3(98.75,12.39)
+RTC_VCC: length 8.6
  TOP w0.508: RTC1.1 46.25,11.04 46.75,10.54 46.75,7.45 AFTP2502.1 48.44,5.77 v1(48.44,5.73)
  BOTTOM w0.508: R2502.2 49.14,5.03 v1(48.44,5.73)
+V_SM_VREF_CNT: length 35.9
  TOP w0.508: v1(88.54,74.54) 88.54,73.76 87.19,72.41 83.74,72.41 82.29,70.96 78.06,70.96 68.08,60.98 v2(68.08,60.52) C3701.1 R3708.2
  BOTTOM w0.127: v1(88.54,74.54) 88.54,74.54 88.54,74.58 88.81,74.85 CPU1.AP49
+V_VREF_PATH1: length 1.8
  TOP w0.508: v2(56.35,40.05) C3702.2 56.37,39.11 R3711.1
+V_VREF_PATH3: length 2.2
  TOP w0.508: v2(66.56,54.31) 66.18,53.93 R3707.1 C3701.2
+VCHGR_R: length 13.3
  TOP w0.254: v1(126.44,146.28) 126.57,146.15 126.6,146.15 127.2,145.56 v2(127.2,144.82) 127.1,144.72 PR4454.1
  L3 w0.254: v1(126.44,146.28) 126.6,146.28 127.01,145.87 131.1,145.87 132.52,144.45 132.52,142.08 v1(132.76,141.84)
  BOTTOM w0.254: v1(132.76,141.84) 133.17,142.25 PG4405.1
AC_IN#: length 160
  TOP w0.102: v1(146.62,55.23) 146.6,55.22 146.6,48.53 v2(146.59,48.51) 146.59,43.88 149.99,40.48 149.99,38.05 152.57,35.47 156.17,35.47 157.37,34.27 R2413.1 158.47,34.27 R2430.1 ; v1(110.06,131.06) 110.64,131.64 PQ4408.5
  L3 w0.102: v1(102.83,131.58) 102.83,131.66 103.16,131.99 103.32,131.99 103.55,132.22 104.08,132.22 104.3,131.99 105.86,131.99 106.79,131.06 v1(110.06,131.06) 111.13,132.14 113.17,132.14 116.22,129.09 120.1,129.09 125.19,134.18 v1(133.14,134.18)
  L4 w0.102: v1(133.14,134.18) 133.11,134.14 133.11,131.78 133.55,131.34 133.55,129.31 132.58,128.34 132.58,127.28 133.51,126.36 133.51,125.76 133.83,125.44 133.91,125.44 136.95,122.39 136.95,115.08 139.46,112.57 139.46,111.41 v1(138.74,110.69)
  BOTTOM w0.102: v1(102.83,131.58) 102.83,131.53 102.56,131.26 PR4425.2 PR4434.2 101.95,132.49 PC4401.1 102.37,133.71 PR4433.1 102.69,134.75 102.69,135.18 103.44,135.94 PU4404.5 ; v1(146.62,55.23) 146.58,55.23 145.92,55.89 145.92,56.44 145.99,56.51 145.99,59.51 143.69,61.81 143.69,80.81 143.69,81.02 144.4,81.73 144.4,98.08 141.83,100.64 141.83,109.74 140.74,110.83 138.88,110.83 v1(138.74,110.69)
AC_IN#_G: length 2.5
  BOTTOM w0.127: PQ4206.2 107.83,153.36 PR4213.1 PR4212.2
AC_IN_KBC#: length 158.3
  TOP w0.102: KBC24.65 162.15,36.42 v1(161.03,37.53) v2(161.03,40.66) 161.03,41.14 166.8,46.91 v1(166.8,47.41)
  L3 w0.102: v1(145.47,63.79) 145.47,62.35 149.06,58.77 150.18,58.77 150.69,58.26 152.68,58.26 154.93,56.01 154.93,54.95 159.79,50.09 164.16,50.09 166.57,47.68 166.57,47.64 v1(166.8,47.41)
  L4 w0.102: v1(138.97,115.65) 138.97,117.37 138.43,117.91 138.43,125.11 134.77,128.76 134.77,131.84 134.57,132.05 134.57,136.64 134.25,136.96 134.25,139.96 134.16,140.05 134.16,141.32 133.3,142.18 133.3,144.68 130.01,147.97 127.88,147.97 127.53,148.33 126.85,148.33 126.5,147.97 125.23,147.97 123.05,150.15 114.25,150.15 111.72,152.67 v1(111.12,152.67)
  BOTTOM w0.102: v1(138.97,115.65) 141.96,112.65 141.96,112.19 143.46,110.7 143.46,101.31 146.05,98.73 146.05,90.22 146.58,89.69 146.58,87.85 146.05,87.32 146.05,81.08 145.54,80.57 145.54,63.86 v1(145.47,63.79) ; PQ4206.6 111.09,152.71 v1(111.12,152.67) ; v1(161.03,37.53) 160.67,37.9 R2426.1
AC_PRESENT: length 176.1
  TOP w0.102: v1(180.12,97.1) 179.26,97.1 177.06,99.3 177.06,99.95 176.73,100.28 175.68,100.28 D7601.K ; v1(169.64,28.14) 169.21,27.7 169.21,24.81 169.64,24.38 169.64,24.06 169.64,24.05 169.64,23.32 169.69,23.26 KBC24.112
  L3 w0.102: v1(169.64,28.14) 166.01,31.77 164.3,31.77 163.34,32.73 162.19,32.73 156.81,38.11 156.49,38.11 152.54,42.06 152.54,43.8 142.4,53.94 142.4,70.74 137.71,75.43 137.71,79.31 134.21,82.81 133.06,82.81 131.77,84.09 131.77,84.7 v1(131.12,85.35) ; v1(155.6,98.18) 154.93,98.18 153.54,96.79 153.15,96.79 152.85,97.1 150.66,97.1 149.49,95.93 143.72,95.93 143.11,95.32 136.47,95.32 135.78,94.62 134.89,94.62 133.55,93.29 v1(133.5,93.29)
  L4 w0.102: v1(113.89,77.56) 114.14,77.81 116.05,77.81 116.12,77.74 118.22,77.74 118.81,78.33 120.29,78.33 121.3,79.35 122.51,79.35 125.07,81.91 127.1,81.91 127.63,82.44 129.48,82.44 130.43,83.39 131.15,83.39 131.52,83.76 131.52,84.95 v1(131.12,85.35) 131.54,85.77 131.54,86.33 131.29,86.58 131.07,86.58 130.4,87.25 130.4,88.08 131.51,89.18 134.37,89.18 134.68,89.49 134.68,91.17 133.5,92.35 v1(133.5,93.29)
  BOTTOM w0.102: CPU1.AJ8 114.18,77.85 v1(113.89,77.56) ; RN1701.3 132.73,84.76 132.17,85.31 EC1707.1 131.24,85.31 131.2,85.35 v1(131.12,85.35) ; v1(180.12,97.1) 179.75,96.73 175.21,96.73 174.83,97.12 174.45,97.12 173.78,97.78 157.11,97.78 156.8,98.09 v2(156.28,98.09) 155.84,98.09 155.75,98.18 v1(155.6,98.18)
AD+: length 93.2
  TOP w0.508: PR4469.1 134,139.44 v3(134.92,140.37)
  L3 w0.762: v3(91.22,145.23) 91.22,140.42 93.14,138.5 95.85,138.5 98.07,136.29 98.07,136.26 99.75,134.58 v1(99.75,133.67) 100.01,133.41 108.13,133.41 108.37,133.16 109.49,133.16 v3(109.65,133)
  L4 w0.508: v3(91.22,145.23) 91.06,145.39 91.06,148.94 95.82,153.7 97.11,153.7 98.46,155.04 102.31,155.04 103.65,153.7 108.52,153.7 109.9,155.08 111.39,155.08 111.73,154.74 118.07,154.74 121.9,150.91 124.12,150.91 124.41,150.62 125.68,150.62 127.21,149.09 127.84,149.09 128.2,148.73 130.99,148.73 135.79,143.93 135.79,141.16 135.16,140.53 135.08,140.53 v3(134.92,140.37)
  BOTTOM w0.381: v3(134.92,140.37) 135.21,140.37 135.56,140.72 PU4403.4
  BOTTOM w0.508: v1(99.75,133.67) 99.75,134.39 PR4407.1
  vias: v2(89.56,148.96)
AD+_G_1: length 3.8
  BOTTOM w0.102: PR4401.1 92.73,144.23 PQ4402.5 ; PR4401.1 92.08,144.47 PQ4402.6 ; PR4401.1 93.38,144.02 v2(93.44,143.96)
AD+_G_2: length 9
  TOP w0.254: v1(93.19,143.13) 88.12,143.13 v1(87.41,143.84)
  BOTTOM w0.254: PR4403.2 PR4401.2 v1(93.19,143.13) 93.19,142.42 v2(93.14,142.37) ; PU4402.4 v1(87.41,143.84)
AD+_TO_SYS: length 3.1
  BOTTOM w0.254: PG4402.1 89.53,141.36 PR4402.1
  vias: v2(86.43,141.04)
AD_IA: length 228.3
  TOP w0.102: KBC24.97 163.69,21.32 164.3,20.71 v1(164.48,20.71) 164.48,20.34 164.26,20.13 C2414.2
  L3 w0.102: v1(147.88,55.26) 148.59,54.56 149.1,54.56 149.88,53.79 149.88,53.46 152.35,50.99 152.35,48.09 162.36,38.08 162.36,38.07 162.99,37.43 v1(163.21,37.43) ; v1(96.04,133.88) 95.21,133.88 89.28,139.81 89.28,145.38 89.28,145.84 95.03,151.59 96.01,151.59 99.77,155.35 108.42,155.35 108.89,154.88 112.72,154.88 113.61,155.77 117.4,155.77 119.96,153.21 123.78,153.21 124.15,153.59 125.3,153.59 125.3,153.59 134.16,153.59 135.08,152.67 136.01,152.67 138.83,149.85 138.87,149.85 139.34,149.38 140.74,149.38 142.06,148.06 142.06,145.69 142.06,145.69 142.06,143.91 142.5,143.47 142.5,141.08 142.8,140.78 v1(142.8,140.68)
  L4 w0.102: v1(164.48,20.71) 164.53,20.77 164.53,24.45 165.22,25.13 165.22,25.63 164.48,26.36 164.48,27.52 165.07,28.11 165.07,28.22 165.67,28.82 165.67,32.66 165.09,33.23 165.09,35.55 v1(163.21,37.43)
  BOTTOM w0.102: v1(147.88,55.26) 147.88,55.51 147.06,56.34 147.06,59.01 144.09,61.98 144.09,80.59 144.09,80.85 144.83,81.58 144.83,98.22 142.24,100.81 142.24,110.19 v2(140.25,112.18) 138.53,113.9 138.53,119.06 141.63,122.15 141.63,126.76 144.51,129.64 144.51,132.68 141.76,135.43 141.76,137.31 142.8,138.36 v1(142.8,140.68) ; PR4422.2 99.36,135.32 99,134.96 96.62,134.96 95.98,134.32 95.98,133.93 v1(96.04,133.88)
AD_IA_HW: length 177
  TOP w0.102: KBC24.105 166.89,22.87 167.12,23.09 167.14,23.09 167.56,23.51 167.56,26.68 169.62,28.74 v1(169.62,28.85)
  L3 w0.102: v1(144.31,55.26) 144.31,52.71 153.02,44 153.02,42.58 162.39,33.22 165.05,33.22 169.37,28.9 169.56,28.9 v1(169.62,28.85) ; v1(136.01,129.58) 135.57,129.58 134.96,130.19 134.49,130.19 133.35,131.34 132.22,131.34 131.76,131.79 125.94,131.79 121.62,127.47 121.54,127.47 121.01,127.47 115.96,127.47 114.88,128.56 111.93,128.56 111.71,128.34 99.08,128.34 96.14,131.28 v1(96.14,132.61)
  BOTTOM w0.102: v1(144.31,55.26) 144.31,55.69 145.38,56.76 145.38,59.25 143.08,61.56 143.08,81.27 143.79,81.98 143.79,97.82 141.22,100.39 141.22,109.49 140.49,110.22 139.44,110.22 139.09,109.87 138.38,109.87 137.92,110.33 v2(137.92,111.6) 137.92,118.73 141.43,122.24 141.43,124.28 136.23,129.48 136.12,129.48 v1(136.01,129.58) ; PQ4407.5 96.34,132.4 v1(96.14,132.61)
AD_IA_HW2: length 176.1
  TOP w0.102: KBC24.25 177.64,33.29 172.98,33.29 v1(172.37,32.69)
  L3 w0.102: v1(96.14,133.24) 95.7,132.81 95.7,131.43 99,128.13 111.8,128.13 112.02,128.35 114.79,128.35 115.88,127.27 120.92,127.27 120.93,127.27 121.28,127.27 121.28,127.27 121.45,127.27 121.62,127.27 121.7,127.27 126.02,131.59 131.68,131.59 132.14,131.13 133.27,131.13 134.41,129.99 134.87,129.99 135.81,129.05 135.88,129.05 v1(135.98,128.95) ; v1(172.37,32.69) 166.6,32.69 165.37,33.92 163.57,33.92 162.86,34.64 162.86,34.71 158.51,39.06 157.97,39.06 153.98,43.04 153.98,44.37 149.94,48.41 149.94,51.8 v1(149.69,52.05)
  L4 w0.102: v1(135.98,128.95) 135.98,128.13 138.83,125.28 138.83,118.07 140.1,116.8 140.1,116.62 140.17,116.56 140.17,110.62 139.62,110.07 139.62,108.49 143.38,104.74 143.38,102.51 145.03,100.86 145.03,100.01 145.36,99.68 145.36,95.46 146.56,94.27 146.56,87.66 145.04,86.14 145.04,62.06 150.35,56.75 150.35,53.07 150.34,53.06 150.34,52.7 v1(149.69,52.05)
  BOTTOM w0.102: v1(96.14,133.24) 96.24,133.24 96.47,133.47 96.47,134.18 96.67,134.38 v2(97.59,134.38) 97.84,134.38 98,134.22 98,132.98 98.58,132.4 PQ4407.2
AD_OFF_L: length 4.3
  TOP w0.254: PQ4204.C 107.63,145.82 PQ4205.B 109.06,146.86 v2(110.08,147.89)
AD_OFF_R: length 14.2
  TOP w0.254: v1(106.88,148.2) 106.87,148.19 PQ4205.C
  L3 w0.254: v1(106.88,148.2) 106.47,148.61 106.39,148.61 105.93,149.07 94.85,149.07 v1(94.03,148.25)
  vias: v2(93.62,148.73)
ALERT#: length 5.4
  TOP w0.102: v1(118.26,111.12) 118.26,110.76 119.19,109.83 THM26.6 121.23,109.83 v2(121.92,109.14)
  BOTTOM w0.102: R2603.2 118.44,111.29 v1(118.26,111.12)
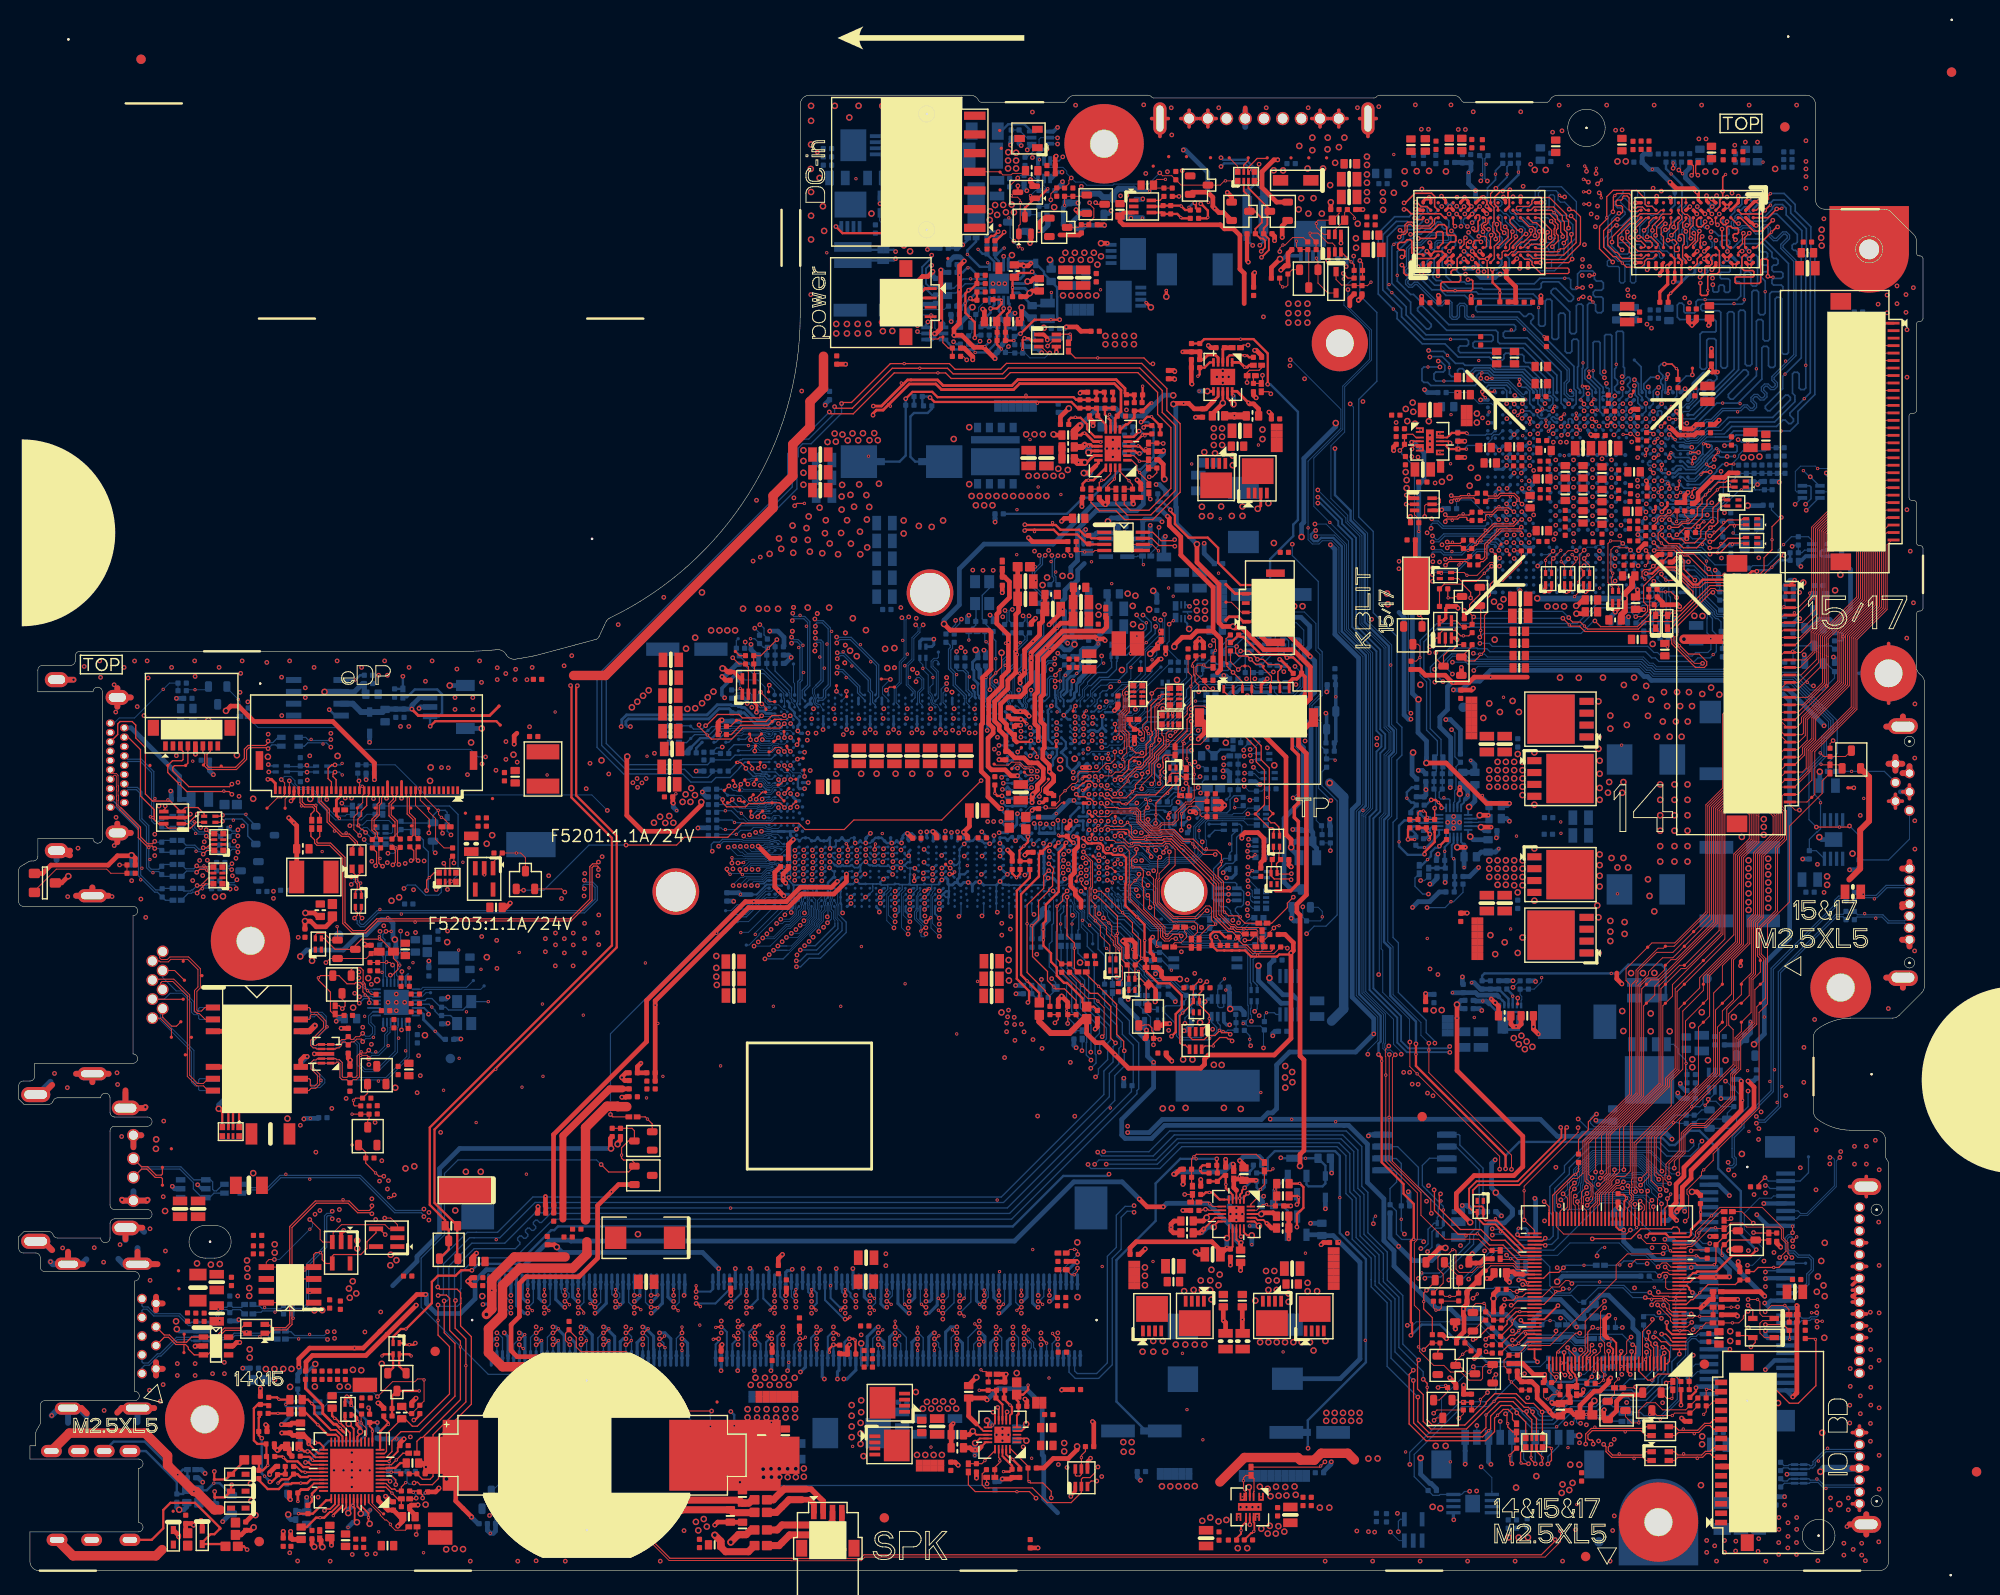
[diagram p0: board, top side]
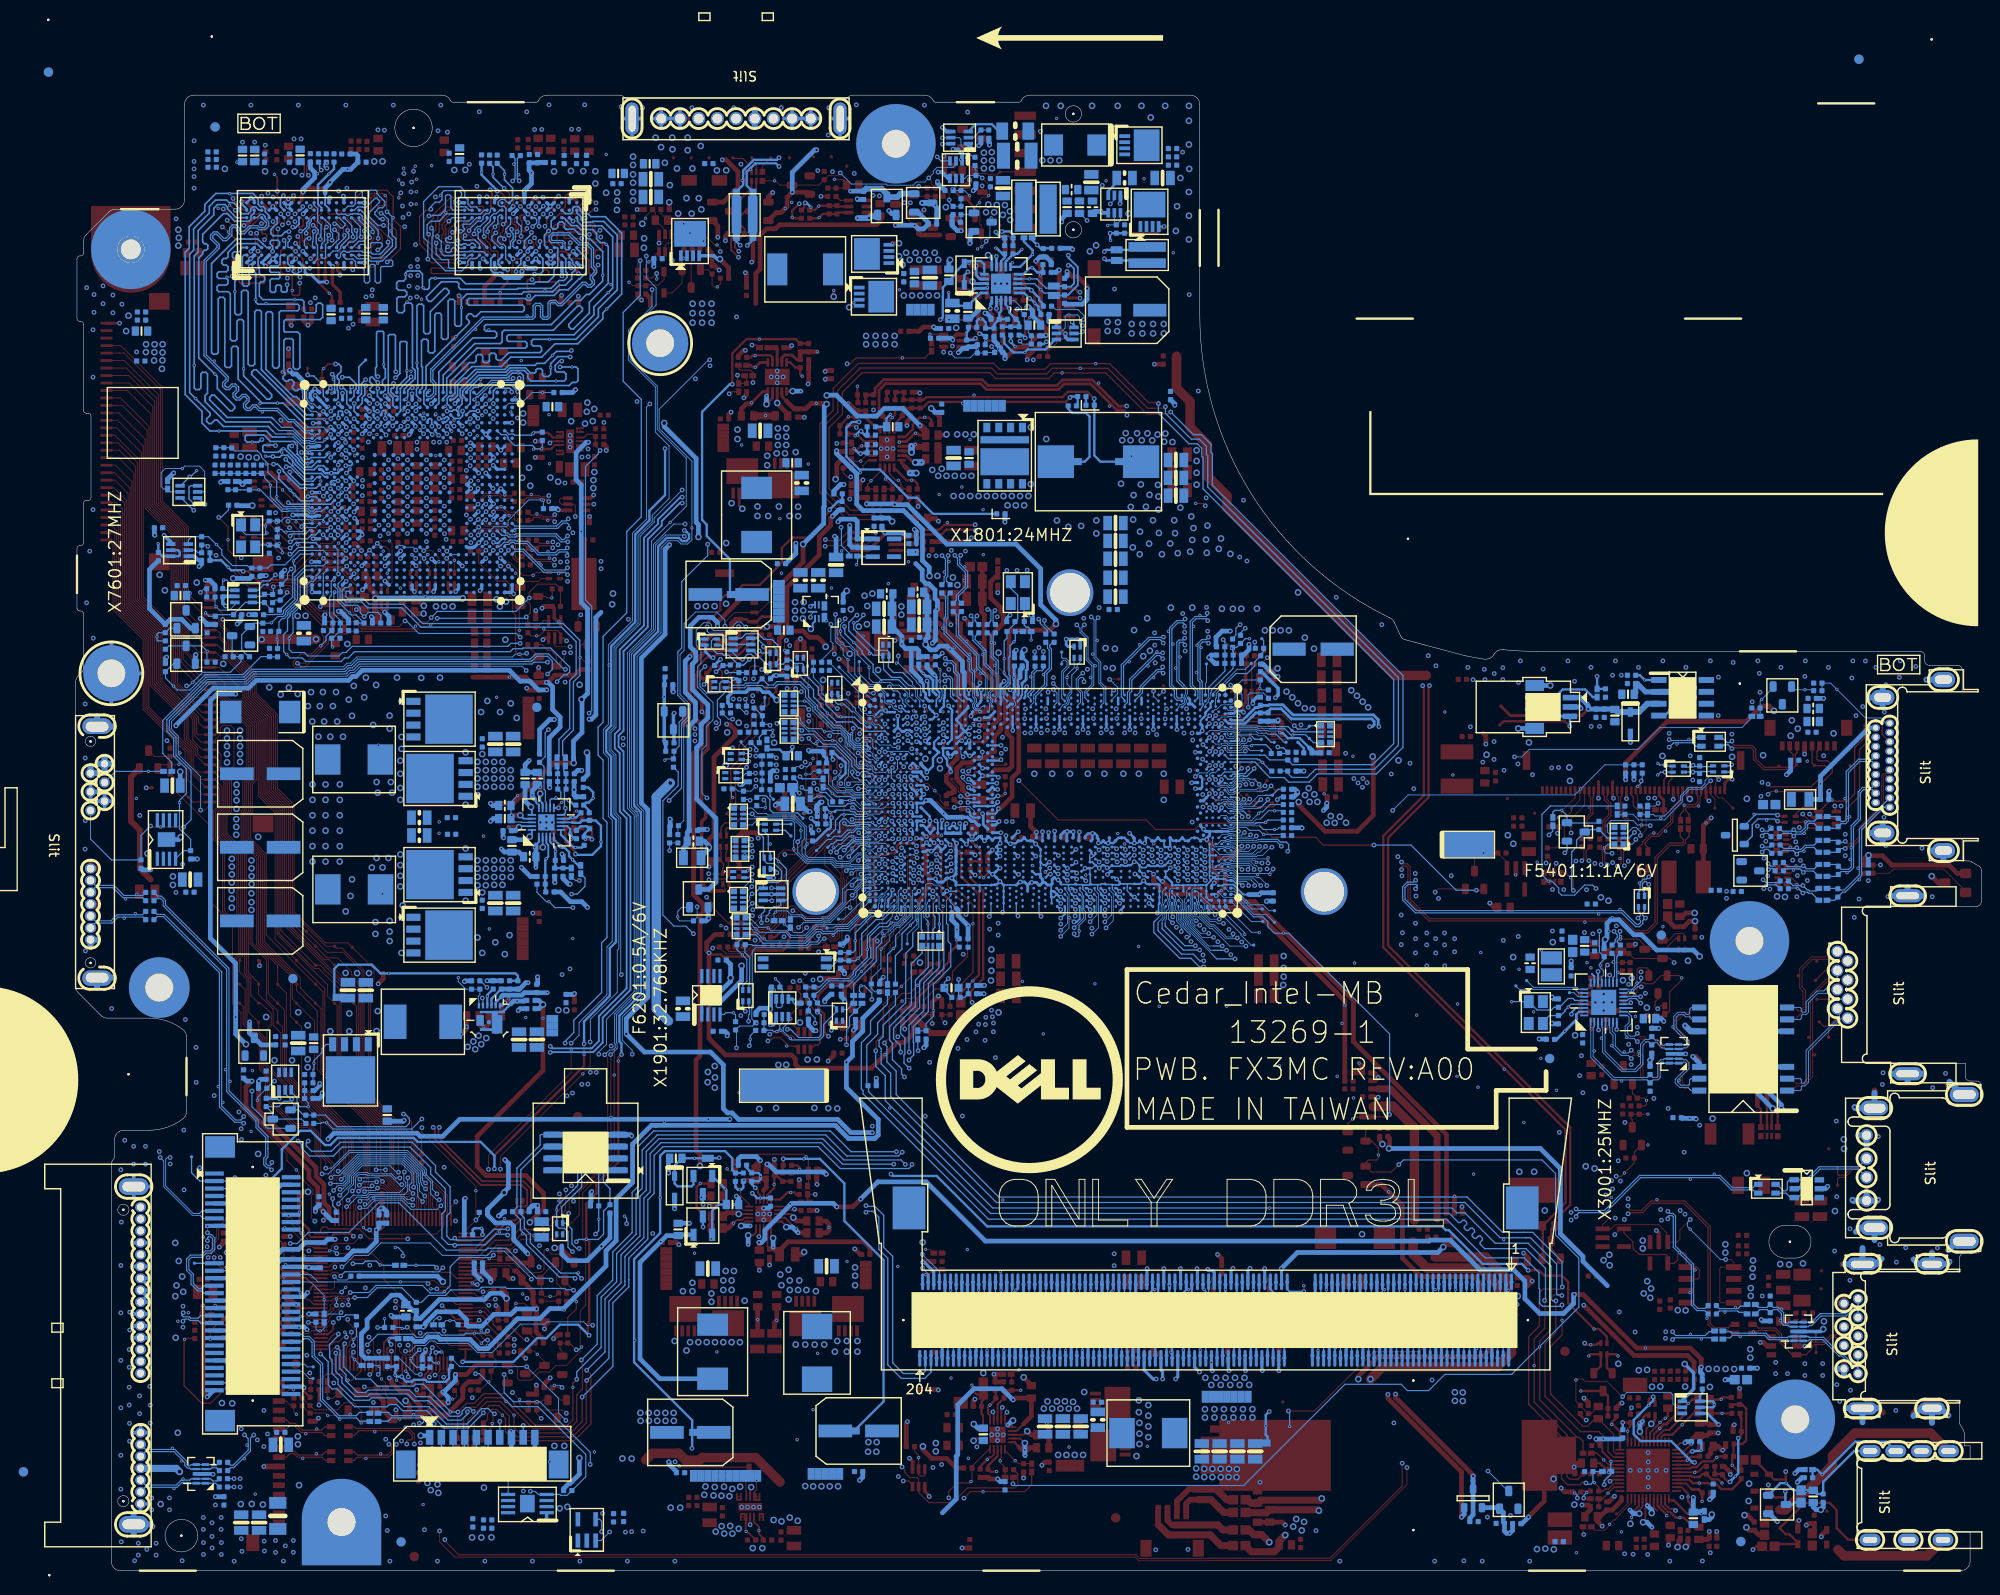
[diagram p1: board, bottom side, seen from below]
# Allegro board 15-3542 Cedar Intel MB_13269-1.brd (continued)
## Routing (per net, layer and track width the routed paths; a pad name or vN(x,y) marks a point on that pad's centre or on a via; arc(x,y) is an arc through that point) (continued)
ALL_SYS_PWRGD: length 131.8
  TOP w0.127: v1(175.94,28.41) 176.31,28.04 176.31,27.87 176.87,27.3 KBC24.10 ; v1(133.04,127.93) 133.04,127.18 R3610.2 R3601.2 132.08,127.66 R3611.2
  L3 w0.127: v1(137.55,127.55) 135.48,127.55 135.1,127.93 v1(133.04,127.93) ; v1(151.28,50.82) 151.28,50.54 151.62,50.2 151.62,47.9 161.71,37.81 161.71,37.7 162.86,36.54 163.77,36.54 165.89,34.43 170.39,34.43 171.45,33.36 172.65,33.36 173.13,32.88 173.13,32.67 175.14,30.67 175.48,30.67 176.06,30.09 176.06,28.56 175.94,28.43 v1(175.94,28.41)
  L4 w0.127: v1(151.28,50.82) 152.37,51.91 152.37,56.52 146.81,62.08 146.81,64.08 145.83,65.06 145.83,86.26 147.01,87.44 147.01,94.44 145.81,95.64 145.81,99.87 145.48,100.2 145.48,101.8 143.9,103.38 143.9,104.91 139.87,108.94 139.87,109.97 140.41,110.52 140.41,116.66 140.35,116.72 140.35,116.9 139.08,118.17 139.08,125.42 137.55,126.94 v1(137.55,127.55)
  BOTTOM w0.127: v1(175.94,28.41) v2(175.94,29.09)
AMBER_LED_BAT: length 5.6
  TOP w0.102: Q6104.C 175.25,16.6 v2(176.88,16.6) 177.15,16.87 EC6105.1 178.84,16.87 R6103.2
AMP_MUTE#: length 190.7
  TOP w0.102: KBC24.30 177.88,35.3 177.88,35.29 178.82,35.29 178.83,35.3 178.86,35.3 179.37,35.81 179.37,36.28 v2(181.06,37.97) 181.97,38.88 186.49,38.88 188.76,36.62 188.76,35.6 189.25,35.11 189.25,33.93 v1(189.67,33.51) ; R2708.1 42.61,3.96 v1(42.52,3.87)
  L4 w0.102: v1(42.52,3.87) 44.88,1.52 169.98,1.52 170.05,1.45 170.4,1.45 170.41,1.45 170.42,1.45 176.55,1.45 179.72,4.61 179.72,4.63 187.91,12.82 187.91,15.4 189.34,16.83 189.34,18.94 189.59,19.19 189.59,33.43 v1(189.67,33.51)
AUD_AGND: length 24.5
  TOP w0.203: v1(31.69,13.69) 32.17,13.69 32.61,13.25 HDA27.25 ; HDA27.38 33.83,7.13 33.32,6.61 32.94,6.61 32.77,6.44 v1(32.7,6.44)
  TOP w0.508: EC2704.1 v1(28.29,4.19) ; v1(33.46,2.73) 33.46,3.35 C2715.2 ; v1(28.11,15.63) C2710.2 29.2,15.79 30.13,15.79 C2711.2 ; v1(26.85,10.29) 26.85,10.5 27.51,11.17 EC2907.2 ; v1(29.09,4.2) 29.09,3.52 EC2706.1 29.26,3.35 C2712.1 ; R2920.2 v1(25.85,19.5) ; v3(25.33,5.94) 25.01,5.94 EC2906.2 ; v1(26.43,15.61) 26.56,15.48 R2919.2 ; EC2908.2 27.34,13.2 v1(27.65,12.9) 27.66,12.91 27.77,12.91 28.17,13.31 C2702.1 28.93,13.04 28.93,12.55 C2705.1
  BOTTOM w0.305: v1(28.11,15.63) 29.31,16.83 U2901.4
  BOTTOM w0.508: R2905.2 16.91,6.77 v3(17.17,6.52) 17.68,6.52 17.98,6.82 C2902.2 ; R2711.1 31.57,13.81 v1(31.69,13.69) ; Q2901.S 22.66,6.09 v1(21.82,5.25) ; R2916.2 19.53,10.81 v1(19.94,10.41)
  vias: v3(29.03,19.67) v3(31.68,19.7) v3(34.33,19.7) v3(35.22,19.69)
AUD_HP1_JACK_L: length 5.5
  TOP w0.203: HDA27.32 31.01,10.14 30.9,10.02
  TOP w0.254: 30.9,10.02 30.16,10.02 30.06,10.12 30.05,10.12 29.83,10.34 R2908.1 28.85,9.78 28.14,9.78 v2(27.73,9.37)
AUD_HP1_JACK_L1: length 21.4
  TOP w0.254: R2912.2 28.51,10.34 R2908.2 27.75,10.34 EC2907.1 27.69,10.13 27.06,9.51 v1(26.87,9.51) ; v1(26,14.18) 25.67,14.5 R2919.1 25.67,16.36 25.79,16.48 R2922.2 ; R2907.2 24.07,2.61 v1(24.43,2.25)
  L3 w0.254: v1(24.43,2.25) 24.44,2.27 26.02,2.27 27.3,3.55 27.3,7.79 26.87,8.22 v1(26.87,9.51)
  BOTTOM w0.254: v1(26,14.18) 26,10.42 v2(26.3,10.12) 26.34,10.08 26.34,10.08 26.64,9.78 26.64,9.78 26.87,9.55 v1(26.87,9.51)
AUD_HP1_JACK_R: length 7.9
  TOP w0.203: HDA27.33 31.22,9.74
  TOP w0.254: 31.22,9.74 30.86,9.37 v2(30.17,9.37) 29.23,9.37 29.13,9.27 28.36,9.27 27.82,8.73 26.64,8.73 25.69,9.68 R2910.1
AUD_HP1_JACK_R1: length 11.5
  TOP w0.254: R2909.2 25.69,11.61 R2910.2 26.12,10.74 v2(26.65,11.27) 26.65,12.07 R2913.2 26.5,13.52 EC2908.1 25.53,13.57 25.15,13.94 25.15,17.36 25.58,17.78 R2920.1 26.62,17.78 R2921.2
AUD_PC_BEEP: length 4.3
  TOP w0.203: HDA27.12 38.66,13.25
  TOP w0.254: C2720.2 39.05,16.33 39.54,15.84 v2(39.54,15.65) 39.4,15.65 38.66,14.9 38.66,13.25
AUD_PC_BEEP_C: length 5.3
  TOP w0.254: C2720.1 R2717.1 39.94,18.71 D2701.3 40.46,19.24 v2(42.84,19.24)
AUD_PORTA_L_R_B: length 18.9
  TOP w0.254: R2907.1 21.88,2.85 ED2902.2 19.63,3.01 20.52,3.9 20.93,3.9 AFTP2906.1 21.54,4.59 18.87,7.26 16.23,7.26 15.47,6.49 15.47,4.54 14.23,3.3 HPMIC1.1
AUD_PORTA_R_R_B: length 21.4
  TOP w0.254: v1(20.92,10.62) AFTP2907.1 22.16,9.76 ED2901.2 24.13,11.73 R2909.1
  L3 w0.254: HPMIC1.2 7.54,13.94 13.23,13.94 16.25,10.91 20.63,10.91 v1(20.92,10.62)
AUD_SENSE: length 26.8
  TOP w0.254: v1(22.78,9.19) 22.71,9.12 ED2904.2 22.05,7.84 AFTP2909.1 20.96,7.88 v1(20.96,8.48) ; R2709.2 37.54,17.32 v1(37.42,17.43)
  L3 w0.254: v1(22.78,9.19) 22.78,9.16 22.78,9.16 22.78,11.73 25.9,14.85 26.4,14.85 27.84,16.29 34.52,16.29 35.66,17.43 v1(37.42,17.43)
  BOTTOM w0.254: v1(20.96,8.48) 20.96,7.15 Q2901.D 20.22,7.08 20.01,7.28 R2923.2
AUD_SENSE_A: length 3.8
  TOP w0.203: HDA27.13 v2(37.83,14.93) 37.83,15.17 37.54,15.46 R2709.1
  TOP w0.254: R2709.1 v1(38.36,15.85)
  BOTTOM w0.254: v1(38.36,15.85) 38.35,15.84 R2722.2
AUD_SPK_L+: length 52.3
  TOP w0.203: v3(35.25,6.16) 35.43,6.35 HDA27.42
  TOP w0.762: v3(76.16,3.05) 76.98,3.86 EC2902.1 77.83,3.86 78.32,4.35 78.32,4.36 R2902.2
  L3 w1.016: v3(76.16,3.05) 75.49,3.05 74.41,1.97 67.25,1.97 66.88,1.61 59.14,1.61 57.23,3.51 45.43,3.51 43.62,1.7 39.83,1.7 38.8,2.74 36.45,2.74 36.37,2.81 36.35,2.81 34.88,4.28 34.88,5.86 35.19,6.16 v3(35.25,6.16)
  BOTTOM w0.508: v2(35.74,6.98) 35.25,6.49 v3(35.25,6.16)
AUD_SPK_L+_C: length 8.3
  TOP w0.61: 86.33,4.89 86.59,4.89 87.05,5.36 SPK1.3
  TOP w0.762: R2902.1 81.13,4.36 AFTP2902.1 86.33,4.89
AUD_SPK_L-: length 50.8
  TOP w0.203: v3(36.18,5.18) 35.94,5.43 35.94,6.68 35.83,6.78 HDA27.43
  TOP w0.762: R2901.2 78.06,2.03 75.63,2.03 75.11,2.55 EC2901.1 75.11,3.17 v3(74.46,3.81)
  L3 w1.016: v3(36.18,5.18) 36.18,5.18 36.18,4.8 36.97,4.01 39.33,4.01 40.36,2.97 43.1,2.97 44.9,4.78 57.76,4.78 59.66,2.88 66.36,2.88 66.72,3.24 73.89,3.24 v3(74.46,3.81)
  BOTTOM w0.508: v2(35.23,4.64) 35.77,5.18 v3(36.18,5.18)
AUD_SPK_L-_C: length 10.3
  TOP w0.61: 88.05,4.94 SPK1.4
  TOP w0.762: R2901.1 81.33,2.68 AFTP2901.1 82.47,3.83 86.94,3.83 88.05,4.94
AUD_SPK_R+: length 46
  TOP w0.203: HDA27.45 36.63,6.93 37.41,6.15 v2(37.41,5.71) 37.41,5.15 v3(37.54,5.02)
  TOP w0.762: R2904.2 78.68,6.21 76.43,6.21 EC2904.1 70.95,6.52 v3(70.86,6.43)
  L4 w1.016: v3(37.54,5.02) 38.17,5.65 40.92,5.65 41.78,4.79 44.9,4.79 46.91,6.8 69.36,6.8 69.73,6.43 v3(70.86,6.43)
AUD_SPK_R+_C: length 6.7
  TOP w0.61: SPK1.1 85.05,6.28 85.05,7.17 84.62,7.6 83.76,7.6
  TOP w0.762: R2904.1 81.05,6.24 AFTP2904.1 82.41,7.6 83.76,7.6
AUD_SPK_R-: length 47.1
  TOP w0.203: v3(36.59,6.11) 36.59,6.49 36.23,6.85 HDA27.44
  TOP w0.762: R2903.2 78.46,7.59 78.1,7.23 EC2903.1 77.1,7.55 70.74,7.55 v3(70.56,7.73)
  L4 w1.016: v3(36.59,6.11) 36.8,6.11 37.62,6.92 41.44,6.92 42.3,6.07 44.38,6.07 46.38,8.07 69.89,8.07 70.26,7.7 70.53,7.7 v3(70.56,7.73)
  BOTTOM w0.508: v2(37.59,6.49) 37.2,6.11 v3(36.59,6.11)
AUD_SPK_R-_C: length 8.2
  TOP w0.61: SPK1.2 86.05,7.44 84.76,8.73 84.22,8.73
  TOP w0.762: 84.22,8.73 AFTP2903.1 80.72,7.59 R2903.1
AUD_VREF: length 2.7
  TOP w0.203: v2(31.44,11.83) 31.53,11.74 HDA27.28
  TOP w0.254: C2705.2 30.19,12.18 31.08,12.18 v2(31.44,11.83)
BAT_AMBER: length 2.8
  TOP w0.102: CON1.14 181.3,18.15 180.8,17.65 R6103.1 180.51,17 v2(180.24,16.73)
BAT_IN#: length 177.8
  TOP w0.102: v1(151.1,38.24) 151.05,38.3 151.05,39.71 146.94,43.82 146.94,54.9 v1(147.25,55.21) ; v1(112.59,149.04) 112.33,148.79 112.33,148.43 PC4433.1 111.04,147.97 PR4472.2 110.4,147.34 v1(110.4,146.7) ; v1(122.05,149.58) 122.35,149.28 123.34,149.28 EC4305.2 124.34,148.28 D4302.3 128.52,148.28 128.98,148.73 v2(129.08,148.73) RN4301.1 ; KBC24.80 161.09,30.1 160.85,29.86 v1(160.27,29.86) 159.81,29.86 159.58,30.09 R2414.1
  L4 w0.102: v1(122.05,149.58) 122.4,149.23 122.4,148.18 124.13,146.45 125.09,146.45 125.75,147.1 126.99,147.1 127.65,146.45 128.32,146.45 131.18,143.59 131.18,141.14 132.04,140.29 132.04,139.56 131.46,138.98 131.46,132.57 132.94,131.08 132.94,129.66 131.95,128.67 131.95,127.05 132.84,126.16 132.84,125.56 136.34,122.06 136.34,114.83 138.65,112.52 v1(138.65,112.01) ; v1(160.27,29.86) 160.02,30.11 160.02,30.99 158.57,32.44 158.57,36.25 157,37.81 155.37,37.81 155.37,37.81 154.93,37.81 153.46,37.81 153.11,38.17 151.18,38.17 v1(151.1,38.24)
  BOTTOM w0.102: v1(138.65,112.01) 139.85,112.01 142.04,109.82 142.04,100.73 144.6,98.16 144.6,81.64 143.89,80.93 143.89,80.71 143.89,80.71 143.89,61.89 146.19,59.59 146.19,56.42 146.12,56.36 146.12,55.97 146.38,55.72 146.74,55.72 147.25,55.21 v1(147.25,55.21) ; PC4210.2 PR4215.2 PR4216.1 110.4,146.43 v1(110.4,146.7) ; PQ4203.2 109.67,150.48 109.98,150.18 111.7,150.18 112.1,149.77 112.1,149.53 v1(112.59,149.04) 113.03,148.6 113.91,148.6 114.24,148.27 117.04,148.27 117.17,148.39 120.86,148.39 v1(122.05,149.58)
BAT_SCL: length 192.8
  TOP w0.203: v2(158.49,36.26) 158.62,36.39 ; 158.62,36.39 158.31,36.7 157.94,37.07 156.71,37.07 156.01,37.77 RN2401.3 155.64,38.38 155.14,38.88 155.14,40.88 155.94,41.68 160.34,41.68 165.02,46.36 165.02,47.36 v1(164.94,47.44) ; 158.62,36.39 160.51,34.5 160.92,34.1 KBC24.70 ; v1(132.94,140.56) 133.09,140.71 133.11,140.71 133.72,141.33 133.72,142.52 EC4301.1 133.17,143.65 133.56,144.04 133.56,145.21 D4301.3 133.83,145.67 131.54,147.95 RN4301.3
  L3 w0.203: v1(153.08,55.47) 153.39,55.16 153.39,54.52 160.37,47.55 164.83,47.55 v1(164.94,47.44) ; v1(97.66,139.69) 98.13,140.17 98.35,140.17 99.12,140.94 103.52,140.94 104.39,141.81 105.26,141.81 106.47,143.03 107.34,143.03 108.78,144.46 117.64,144.46 118.4,145.23 123.29,145.23 124.06,144.46 129.56,144.46 130.54,143.48 130.54,141.59 131.48,140.65 132.84,140.65 v1(132.94,140.56)
  L4 w0.203: v1(132.94,140.56) 133.12,140.37 133.12,139.63 133.44,139.31 133.44,135.26 133.63,135.07 133.63,131.84 133.96,131.5 133.96,127.8 137.61,124.14 137.61,115.36 138.68,114.3 138.91,114.3 v1(138.96,114.25)
  BOTTOM w0.203: v1(153.08,55.47) 153.07,55.46 152.86,55.46 152.83,55.49 148.48,55.49 147.46,56.51 147.46,59.18 144.5,62.15 144.5,80.68 145.23,81.41 145.23,87.65 145.77,88.19 145.77,89.35 145.23,89.88 145.23,98.39 142.65,100.98 142.65,110.36 141.15,111.86 141.15,112.31 139.21,114.25 v1(138.96,114.25) ; v1(97.66,139.69) 97.4,139.69 97.05,139.34 97.05,137.73 97.38,137.41 PR4415.2 98.13,137.48 PG4407.2
BAT_SDA: length 195.3
  TOP w0.203: KBC24.69 161.09,34.5 158.11,37.48 157.96,37.48 ; 157.96,37.48 v2(157.96,37.69) ; 157.96,37.48 156.87,37.48 156.66,37.69 RN2401.4 156.66,38.83 156.51,38.98 155.69,38.98 155.55,39.12 155.55,40.71 156.11,41.27 160.5,41.27 165.43,46.19 165.43,47.27 v1(165.59,47.44) ; v1(132.91,141.19) 133.32,141.6 133.32,142.35 133.1,142.56 132.81,142.56 132.3,143.07 EC4302.1 132.28,143.59 132.98,144.28 132.98,144.73 132.23,145.48 D4303.3 131.64,147.02 131.04,147.63 RN4301.2
  L3 w0.203: v1(165.59,47.44) 165.59,47.47 165.1,47.96 160.53,47.96 153.8,54.69 153.8,55.33 153.57,55.56 153.57,55.67 153.13,56.1 v1(153.07,56.1) ; v1(132.91,141.19) 132.77,141.06 131.65,141.06 130.94,141.76 130.94,143.65 129.72,144.87 124.23,144.87 123.46,145.64 118.24,145.64 117.47,144.87 108.61,144.87 107.17,143.43 106.31,143.43 105.09,142.22 104.22,142.22 103.35,141.34 98.96,141.34 98.18,140.57 97.86,140.57 v1(97.66,140.78)
  L4 w0.203: v1(132.91,141.19) 133.02,141.19 133.53,140.69 133.53,139.8 133.84,139.48 133.84,135.43 134.03,135.24 134.03,132 134.37,131.67 134.37,127.97 138.02,124.31 138.02,115.53 138.67,114.88 v1(138.97,114.88)
  BOTTOM w0.203: v1(138.97,114.88) 139.02,114.83 139.2,114.83 141.56,112.48 141.56,112.02 143.05,110.53 143.05,101.15 145.64,98.56 145.64,90.05 146.17,89.52 146.17,88.02 145.64,87.49 145.64,81.25 144.9,80.51 144.9,62.31 147.87,59.35 147.87,56.68 148.65,55.9 152.83,55.9 152.88,55.95 152.92,55.95 v1(153.07,56.1) ; PG4408.2 98.12,136.46 PR4412.2 97.69,136.52 96.64,137.57 96.64,139.51 97.66,140.53 v1(97.66,140.78)
BAT_WHITE: length 2.6
  TOP w0.102: CON1.15 181.23,19.15 180.98,19.4 v2(180.54,19.4) 180.5,19.36 R6101.1
BATLOW#: length 25.5
  TOP w0.102: v1(117.25,75.63) 117.25,75.79 v2(117.57,76.12)
  L4 w0.102: v1(117.25,75.63) 117.66,76.03 118.94,76.03 119.38,76.47 119.5,76.47 121.57,78.54 124.99,78.54 126.78,80.33 129.56,80.33 131.11,81.88 131.73,81.88 132.16,82.31 132.16,84.41 132.71,84.96 132.71,86.55 132.01,87.25 v1(131.72,87.25)
  BOTTOM w0.102: v1(117.25,75.63) 117.25,75.52 CPU1.AN4 ; RN2006.4 131.92,87.45 v1(131.72,87.25)
BATT_WHITE_LED#: length 31.1
  TOP w0.102: v1(172.4,36.46) 171.96,36.02 165.27,36.02 164.49,36.8 KBC24.62 ; R6105.1 172.87,19.58 v1(172.96,19.67)
  L4 w0.102: v1(172.96,19.67) 172.93,19.7 172.17,19.7 170.98,20.89 170.98,21.68 171.99,22.69 171.99,26.59 170.79,27.79 170.79,34.57 172.4,36.19 v1(172.4,36.46)
  BOTTOM w0.102: v2(173.06,36.72) 172.8,36.46 v1(172.4,36.46)
BATT_WHITE_LED_R#: length 2.9
  TOP w0.102: v2(171.13,20.53) 170.7,20.09 R6105.2 170.7,18.85 Q6103.B
BKLT_CTRL: length 13.3
  TOP w0.14: RN5203.8 44.45,74.7 v2(43.92,74.17) 43.64,73.89 v1(43.64,72.79)
  BOTTOM w0.14: v1(43.64,72.79) 43.82,72.97 43.82,76.93 43.29,77.46 43.29,78.18 D5202.3 42.16,79.31 R5222.1 40,78.41 RN5201.7
BLON_OUT: length 247.9
  TOP w0.102: v1(173.37,35.77) 174.14,35 176.16,35 176.45,34.71 176.45,34.44 176.8,34.1 KBC24.27
  L3 w0.102: v1(35.42,79.73) 34.49,78.8 34.49,77.03 36.01,75.51 36.01,73.09 32.33,69.41 32.33,65 33.86,63.47 33.86,60 34.24,59.62 34.24,59.25 35.38,58.11 35.38,55.57 36.01,54.93 36.01,43.25 38.42,40.84 v1(39.44,40.84)
  L4 w0.102: v1(39.44,40.84) 39.11,40.51 39.11,39.63 39.85,38.89 39.85,35.59 38.44,34.18 38.44,29.35 39.85,27.94 39.85,27.29 42.36,24.79 42.84,24.79 51.75,15.87 57.91,15.87 58.79,16.76 64.33,16.76 66.92,14.18 71.44,14.18 79.18,6.44 104.68,6.44 107.93,9.68 109.11,9.68 109.91,9.69 110.17,9.42 110.86,9.42 112.11,8.18 112.11,7.77 112.36,7.51 124.76,7.51 125.26,8 126,8 128.09,10.09 136.87,10.09 138.37,8.59 143.51,8.59 144.09,9.16 147.52,9.16 147.52,9.16 149.04,9.16 149.04,9.16 153.21,9.16 154.7,7.67 162.03,7.67 164.81,10.46 169.99,10.46 173.62,14.09 173.62,19.88 173.06,20.45 172.21,20.45 171.96,20.7 171.96,21.77 173.07,22.89 173.07,25.82 170.99,27.91 170.99,33.1 173.37,35.48 v1(173.37,35.77)
  BOTTOM w0.102: RN5201.6 39.87,78.91 40,79.04 40,79.88 39.6,80.29 37.26,80.29 36.77,79.8 v2(36.37,79.8) 35.49,79.8 v1(35.42,79.73)
BLON_OUT_C: length 22.1
  TOP w0.102: RN5203.7 45.62,75.56 v1(45.47,75.7) ; v1(36.47,78.68) 35.85,79.3 35.85,80.67 36.22,81.03 AFTP5205.1 36.8,82.21 36.8,82.98 36.95,83.13 LCD1.21
  L3 w0.102: v1(45.47,75.7) 44.18,74.41 38.2,74.41 37.34,75.28 37.34,76.63 36.47,77.5 v1(36.47,78.68)
  BOTTOM w0.102: RN5201.3 37.88,78.91 37.27,79.52 36.89,79.52 36.47,79.1 v1(36.47,78.68)
BLUETOOTH_EN: length 134.3
  TOP w0.102: v1(117.26,89.1) 117.7,89.54 117.7,91.74 118.15,92.19 118.15,93.67 118.08,93.73 118.08,94.11 118.68,94.71 RN2011.5 ; v1(186.81,27.71) 187.5,28.39 v2(188.92,28.39) 189.36,27.95 R5805.1 189.39,27.38 R5806.2
  L3 w0.102: v1(186.69,33.14) 186.01,33.81 180.48,33.81 179.63,34.66 178.1,34.66 176.93,33.49 175.71,33.49 175.46,33.75 175.46,35.61 173.52,37.55 170.94,37.55 170.18,38.32 167.94,38.32 167.24,39.03 167.24,47.59 166.92,47.91 166.63,47.91 164.25,50.29 159.87,50.29 155.13,55.03 155.13,56.1 152.77,58.46 150.78,58.46 150.26,58.97 149.14,58.97 145.9,62.21 145.9,64.23 145.32,64.81 145.32,71.97 141.91,75.38 141.91,85.39 139.22,88.08 135.24,88.08 134.44,88.88 133.54,88.88 132.56,89.86 132,89.86 131.32,90.54 131.32,91.03 130.05,92.3 128.78,92.3 127.45,93.62 126.05,93.62 125.95,93.72 121.84,93.72 120.88,92.76 120.88,91.78 118.56,89.46 118.56,89.17 118.07,88.68 117.68,88.68 v1(117.26,89.1)
  L4 w0.102: v1(186.81,27.71) 187.3,28.19 187.3,32.37 186.86,32.8 186.86,32.96 v1(186.69,33.14)
  BOTTOM w0.102: CPU1.J4 116.94,88.78 v1(117.26,89.1)
BOARD_ID1: length 26
  L4 w0.102: v1(133.58,91.13) 132.22,92.48 130.2,92.48 129.66,91.94 128.23,91.94 126.69,90.4 126.69,89.8 126.37,89.48 125.82,89.48 v1(125.42,89.07)
  BOTTOM w0.089: CPU1.U4 117.28,83.87 117.66,83.87 117.75,83.78 119.17,83.78 119.51,84.12 120.41,84.12 120.74,83.8 121.35,83.8 121.59,84.03 121.59,84.63 121.4,84.81
  BOTTOM w0.102: v1(125.42,89.07) 125.42,88.99 124.93,88.5 v2(124.68,88.5) 124.35,88.18 122.68,88.18 121.13,86.63 121.13,85.77 121.19,85.71 121.19,85.02 121.4,84.81 ; v1(133.58,91.13) 134.02,91.13 R2024.1 R2023.2
BOARD_ID2: length 10.4
  BOTTOM w0.089: 119.35,82.73 119.08,82.46 117.84,82.46 CPU1.Y3
  BOTTOM w0.102: v2(125.74,85.23) 125.24,85.23 124.92,85.55 R2008.1 R2005.2 123.31,85.34 123.31,84.17 122.39,83.25 121.59,83.25 121.58,83.24 121.03,83.24 120.7,82.91 119.53,82.91 119.35,82.73
BOARD_ID3: length 30.8
  TOP w0.102: R2026.1 127.11,80.69 R2025.2 126.56,80.69 126.37,80.88 126.37,81.4 125.96,81.81 125.46,81.81 125.46,81.81 125.2,81.81 v2(124.39,80.99) 124.39,79.27 v1(124.36,79.24)
  L3 w0.102: v1(124.36,79.24) 123.64,78.52 118.62,78.52 118.03,79.11 117.12,79.11 116.83,78.82 114.33,78.82 114.07,79.08 114.07,80.36 112.43,82 112.43,83.48 112.36,83.54 112.36,83.9 112.62,84.15 113.3,84.15 113.79,84.64 114.25,84.64 114.34,84.55 115.98,84.55 116.26,84.84 116.26,85.19 115.97,85.49 115.97,86.05 116.29,86.38 117,86.38 v1(117.25,86.12)
  BOTTOM w0.102: CPU1.P3 117.59,85.78 v1(117.25,86.12)
BOOST_10V: length 8
  BOTTOM w0.254: PD4502.1 v2(134.34,40.83) 134.24,40.73 PC4534.1 135.07,39.18 135.75,38.51 PD4503.2
BOOST_MODE#: length 210.8
  TOP w0.203: 179.1,31.86 178.53,31.3 KBC24.20
  TOP w0.254: 179.1,31.86 179.39,31.86 179.55,32.02 181.6,32.02 183.32,33.74 185.3,33.74 185.86,34.3 v1(185.86,34.35) ; v1(159.05,43) 159.05,44.43 149.46,54.01 v2(149.46,55.26) v1(149.46,56.38)
  L3 w0.254: v1(100.98,141.88) 100.98,142.76 101.8,143.58 101.8,144.98 104.2,147.39 106.08,147.39 107.05,146.41 108.36,146.41 109.01,147.05 109.01,147.28 109.01,147.6 110.55,149.15 111.97,149.15 112.81,149.98 116.41,149.98 116.59,150.16 118.38,150.16 119.47,151.25 124.93,151.25 125.19,151.51 126.4,151.51 126.62,151.73 131.77,151.73 132.75,150.75 132.75,150.58 v1(132.68,150.51)
  L4 w0.254: v1(132.68,150.51) 132.68,147.94 136.57,144.04 136.57,137.79 135.16,136.37 135.16,132.92 137.67,130.41 137.67,129.25 139.39,127.53 139.39,121.49 v1(140.8,120.09)
  BOTTOM w0.254: PR4418.1 101.52,142.41 v1(100.98,141.88) 100.59,141.48 PR4435.2 100.29,141.52 PR4439.2 ; v1(159.05,43) 159.05,44.41 160.52,45.89 167.25,45.89 167.67,46.31 175.83,46.31 176.59,45.55 177.17,45.55 178.7,47.08 179.79,47.08 181.79,45.08 181.79,43.02 184.21,40.61 184.21,36 v1(185.86,34.35) ; v1(140.8,120.09) 140.8,115.11 142.47,113.43 142.47,112.4 143.98,110.89 143.98,101.51 146.56,98.94 146.56,90.43 147.09,89.9 147.09,87.64 146.56,87.11 146.56,80.87 146.05,80.36 146.05,67.28 146.71,66.62 146.71,61.52 149.46,58.77 v1(149.46,56.38)
BOOST_MON: length 157.9
  TOP w0.203: v1(162.46,22.34) 162.43,22.37 162.43,22.42 162.15,22.7 KBC24.96
  TOP w0.254: v1(145.46,55.24) 145.79,54.9 145.79,54.54 v2(145.79,54.54) 145.79,54.54 145.79,43.71 148.13,41.37 148.13,40.35 149.22,39.25 149.22,35.58 148.91,35.26 148.91,26.6 149.04,26.47 149.04,25.32 v1(148.92,25.19) ; PR4452.1 v1(124.12,147.07)
  L4 w0.254: v1(138.73,111.32) 139.16,111.75 139.16,112.45 136.65,114.96 136.65,122.27 133.78,125.14 133.7,125.14 133.15,125.69 133.15,126.28 132.28,127.16 132.28,128.57 133.25,129.54 133.25,131.21 132.64,131.82 132.64,138.46 132.71,138.53 132.71,139.12 132.38,139.45 132.38,140.37 131.49,141.27 131.49,143.71 127.7,147.5 127.7,147.73 127.4,148.02 126.98,148.02 126.36,147.41 125.62,147.41 125.22,147.01 124.18,147.01 v1(124.12,147.07)
  BOTTOM w0.254: v1(138.73,111.32) 138.65,111.32 138.23,110.9 138.23,110.47 138.52,110.18 138.96,110.18 139.31,110.53 140.62,110.53 141.53,109.61 141.53,100.51 144.09,97.95 144.09,81.85 143.38,81.14 143.38,61.68 145.68,59.38 145.68,56.63 145.46,56.41 v1(145.46,55.24) ; v1(148.92,25.19) 148.94,25.19 150.09,26.33 152.04,26.33 153.49,24.88 154.48,24.88 157.02,22.34 v1(162.46,22.34)
BOOST_MON_1: length 3.8
  TOP w0.102: PR4452.2 PR4446.1 121.7,147.96 PC4427.1 121.38,148.52 121.76,148.89 v2(122.66,148.89)
BP_PWRGD_RST#: length 6.6
  BOTTOM w0.14: R9603.2 130.81,82.93 130,82.93 129.58,82.51 129.58,81.44 129.24,81.09 126.62,81.09 TP9645.1
BST15V_1: length 7.4
  TOP w0.254: v1(136.73,36.77) 136.73,38.16 137.04,38.48 137.08,38.48 137.42,38.83 137.42,41.05 v2(137.03,41.44) 137.01,41.42 PC4514.2
  BOTTOM w0.254: PD4503.3 136.75,36.8 v1(136.73,36.77)
BST15V_2: length 3
  TOP w0.254: PC4532.2 136.76,40.1 v2(136.92,39.95) 136.92,39.37 v1(136.73,39.18)
  BOTTOM w0.254: PD4502.3 136.75,39.21 v1(136.73,39.18)
BT+: length 13.3
  TOP w0.381: 140.31,155.4 BAT1.1 ; BAT1.1 141.2,156.29 ; BAT1.1 141.2,154.51 ; BAT1.1 142.09,155.4 ; BAT1.2 139.2,156.29 ; BAT1.2 140.09,155.4 ; BAT1.2 139.2,154.51 ; BAT1.2 138.31,155.4
  BOTTOM w0.381: BAT1.2 139.2,156.29 ; BAT1.2 140.09,155.4 ; BAT1.2 139.2,154.51 ; 140.31,155.4 BAT1.1 ; BAT1.1 141.2,154.51 ; BAT1.1 141.2,156.29 ; BAT1.1 142.09,155.4
  vias: v3(136.91,145.68) v3(136.98,152.47) v3(137.19,146.87) v3(137.87,150.06) v3(137.96,145.23) v3(138.38,153.36) v3(138.38,152.01) v3(138.5,146.88) v3(139.39,145.23) v3(139.52,150.06) v3(140.03,153.36) v3(140,152.11) v3(140.28,148.28) v3(140.82,150.66) v3(141.22,152.34) v3(141.81,153.36)
BT+_R:
  vias: v2(127.25,146.42)
BT_ACT: length 22
  TOP w0.14: v2(189.43,24.76) 189.43,25.67 R5806.1 188.77,26.33 v1(186.84,26.33)
  L4 w0.127: v1(186.84,41.22) 186.84,41.06 186.4,40.61 186.4,40.2 187.28,39.31 187.28,32.98 187.72,32.54 187.72,27.21 v1(186.84,26.33)
  BOTTOM w0.14: v1(186.84,41.22) 187.02,41.22 187.33,40.9 WLAN1.5
BUFRST#: length 3.8
  TOP w0.102: v1(175.77,112.47) 175.97,112.47 176.39,112.89 176.66,112.89 177.19,113.42 R7628.2 177.39,112.32 v2(177.33,112.26)
  BOTTOM w0.102: GPU1.D11 176.15,112.85 v1(175.77,112.47)
CAM1_MIC_GND: length 0.9
  TOP w0.508: CCD1.5 18.9,87.58 18.9,87.57 v1(18.9,87.38)
  vias: v2(18.62,86.63)
CAMERA_PWR_EN: length 26.6
  L4 w0.102: v1(131.72,87.89) 131.75,87.89 132.92,86.72 132.92,84.88 132.36,84.32 132.36,82.22 131.82,81.68 131.2,81.68 129.65,80.13 126.87,80.13 125.07,78.33 121.63,78.33 120.11,76.81 v1(120.11,76.01)
  BOTTOM w0.089: v1(120.11,76.01) 119.74,76.38 119.29,76.38 119.2,76.29 117.76,76.29 117.72,76.33 117.23,76.33 CPU1.AM4
  BOTTOM w0.102: TP2002.1 132.66,88.59 131.96,87.89 v1(131.72,87.89)
CAP_LED: length 53.4
  TOP w0.102: KB2.4 199.02,131.1 194.57,126.65 194.57,114.46 191.79,111.68 191.79,104.82 v2(191.58,104.61) 191.58,104.3 190.34,103.06 KB1.4 188.78,103.06 188.1,102.38 v1(188.1,101.8) ; v1(194.08,88.83) 193.75,88.5 R6201.2
  L3 w0.102: v1(188.1,101.8) 188.23,101.67 188.23,99.77 190.98,97.02 192.17,97.02 194.08,95.11 v1(194.08,88.83)
CAP_LED#: length 78.1
  TOP w0.102: KBC24.109 168.49,22.87 168.72,23.09 168.81,23.09 169.18,23.45 169.18,24.13 v1(169.18,24.14) ; v1(178.25,37.41) 178.63,37.78 178.63,40.14 178.45,40.32 178.45,40.76 180,42.31 180,42.66 v2(180.24,42.89) 181.25,43.91 181.25,44.6 186.16,49.51 186.16,59.74 187.06,60.65 187.06,69.21 189.41,71.55 189.41,79.67 192.91,83.18 192.91,84.51 R6202.1
  L4 w0.102: v1(169.18,24.14) 169.18,24.84 169.67,25.33 169.67,26.85 169.19,27.33 169.19,32.15 169.92,32.88 169.92,35.3 171.5,36.89 171.65,36.89 171.66,36.89 172.88,36.89 173.12,36.64 177.49,36.64 v1(178.25,37.41)
CAP_LED_Q: length 3.8
  TOP w0.102: Q6201.C 195.4,87.13 R6201.1 193.09,87.13 v2(192.7,87.52)
CAP_LED_R#: length 2.5
  TOP w0.102: v2(192.78,86.3) 192.85,86.24 R6202.2 194.67,86.24 Q6201.B
CARD_PWR_EN: length 19
  BOTTOM w0.089: CPU1.AL2 118.38,76.75 118.67,77.04 119.07,77.04 119.3,76.81 119.86,76.81
  BOTTOM w0.102: 119.86,76.81 120.17,76.81 121.07,75.91 122.39,75.91 122.8,76.33 125.47,76.33 125.8,76.65 v2(125.8,77.44) 125.7,77.54 125.7,79.65 126.92,80.87 129.79,80.87 129.96,81.04 130.91,81.04 131.48,81.61 RN1809.8
CARD_WLAN_OUT#: length 2.5
  BOTTOM w0.102: TP5804.1 179.07,21.81 179.36,22.1 WLAN1.44
CARD_WPAN_OUT#: length 2.6
  BOTTOM w0.102: WLAN1.46 179.57,21.3 178.84,20.57 TP5803.1
CBN: length 3
  TOP w0.203: HDA27.35 32.06,8.94 31.72,8.59
  TOP w0.254: 31.72,8.59 31.37,8.24 v2(31.37,7.89) 31.37,7.42 C2703.1
CBP: length 4.2
  TOP w0.203: HDA27.37 33.25,7.53 33.06,7.53
  TOP w0.254: 33.06,7.53 32.89,7.53 31.46,6.1 C2703.2 v2(29.93,6.1)
CEDAR/JANUS_ID: length 14.2
  TOP w0.102: v2(120.54,82.54) 120.75,82.33 120.75,81.67 v1(120.75,81.66) 120.39,81.31 120.39,80.22 120.63,79.99 120.64,79.99 121.25,79.38 121.89,79.38 122.34,79.82 123.5,79.82 124.03,80.35 124.03,81.14 124.93,82.03 125.4,82.03 125.69,82.32 R1511.1 127.11,82.32 R1510.2
  BOTTOM w0.102: v1(120.75,81.66) 120.75,81.66 120.74,81.68 120.62,81.68 120.19,81.25 CPU1.AC1
CFG0: length 1.4
  TOP w0.14: TP9626.1 82.55,81.72 v1(82.55,81.65)
  BOTTOM w0.14: v1(82.55,81.65) 82.55,81.59 CPU1.AC60
CFG1: length 3.1
  TOP w0.14: TP9627.1 79.54,81.29 79.08,80.83 79.08,80.7 v1(79.06,80.67)
  BOTTOM w0.089: 79.3,81.06 79.96,81.06 80.02,81 80.49,81 80.78,81.29 CPU1.AC62
  BOTTOM w0.14: v1(79.06,80.67) 79.08,80.7 79.08,80.84 79.3,81.06
CFG2: length 2.8
  TOP w0.14: TP9620.1 78.28,81.26 78.28,80.88 78.41,80.75 v1(78.41,80.69)
  BOTTOM w0.102: 78.95,81.3 78.98,81.27 80.05,81.27 80.06,81.27 80.08,81.29 CPU1.AC63
  BOTTOM w0.14: 78.95,81.3 78.47,80.83 78.47,80.75 v1(78.41,80.69)
CFG3: length 6.5
  BOTTOM w0.089: 76.54,82.97 77.3,82.97 77.85,82.41 77.85,82.4 78.09,82.17 78.09,82.17 78.26,82.01 78.61,82.01 78.64,81.97 78.65,81.97 79.04,81.97 79.15,81.86 79.18,81.86 79.23,81.81 79.83,81.81 79.84,81.81 79.96,81.94 79.99,81.94 80.06,82.01 80.23,82.01 CPU1.AA63
  BOTTOM w0.14: R604.1 75.19,83.63 TP9622.1 76.53,82.98 76.54,82.97
CFG4: length 8.8
  TOP w0.14: v1(81.92,81.67) 81.41,82.17 TP9630.1 79.76,82.17 79.68,82.1 78.09,82.1 77.74,81.74 75.74,81.74 75.3,82.18 v1(75.3,82.52)
  BOTTOM w0.14: R605.1 75.02,82.81 v1(75.3,82.52) ; CPU1.AA60 82.22,81.97 v1(81.92,81.67)
CFG5: length 3.8
  TOP w0.14: v1(78.89,82.55) 78.89,82.66 79.56,83.33 TP9631.1
  BOTTOM w0.089: CPU1.Y62 80.69,82.79 80.4,82.5 80.05,82.5 79.85,82.29 79.81,82.29 79.69,82.17 79.68,82.17 79.38,82.17 79.33,82.22 79.3,82.22 78.97,82.55 v1(78.89,82.55)
CFG6: length 1.6
  TOP w0.14: v1(81.27,83.16) 81.27,82.97 TP9629.1
  BOTTOM w0.102: v1(81.27,83.16) 81.27,83.16 81.57,82.87 CPU1.Y61
CFG7: length 5.1
  TOP w0.14: v1(78.25,82.57) 78.25,82.71 TP9628.1
  BOTTOM w0.089: CPU1.Y60 81.93,82.46 81.27,82.46 81.23,82.5 80.65,82.5 80.47,82.32 80.13,82.32 79.92,82.12 79.89,82.12 79.76,81.99 79.75,81.99 79.3,81.99 79.25,82.04 79.23,82.04 79.12,82.15 78.72,82.15 78.71,82.15 78.29,82.57 v1(78.25,82.57)
CFG8: length 6.3
  TOP w0.14: TP9633.1 75.96,83.98 v1(75.96,83.99)
  BOTTOM w0.089: CPU1.V62 80.76,83.38 80.76,83.36 80.47,83.07 79.97,83.07 79.87,83.17 79.86,83.17 79.83,83.2 79.47,83.2 79.24,83.43 77.44,83.43 77.37,83.36 76.91,83.36 76.84,83.43 76.82,83.43 76.77,83.48 76.63,83.48 76.61,83.5 76.45,83.5
  BOTTOM w0.14: v1(75.96,83.99) 75.96,83.98 76.45,83.5
CFG9: length 6.4
  TOP w0.14: TP9632.1 76.58,84.4 76.58,83.99 v1(76.61,83.99)
  BOTTOM w0.089: CPU1.V61 81.32,83.82 80.78,83.82 80.58,83.62 80.58,83.43 80.4,83.25 80.06,83.25 79.96,83.35 79.93,83.35 79.9,83.38 79.79,83.38 79.56,83.61 77.53,83.61 77.39,83.76 77.07,83.76 77.01,83.82 77,83.82 76.83,83.99 v1(76.61,83.99)
CFG10: length 1.3
  TOP w0.14: TP9637.1 82.38,83.63 v1(81.92,83.16)
  BOTTOM w0.102: CPU1.V60 82.22,83.47 v1(81.92,83.16)
CFG11: length 4.8
  TOP w0.14: v1(78.66,84.16) 78.66,84.42 TP9639.1
  BOTTOM w0.089: CPU1.U60 81.93,83.96 81.44,83.96 81.4,84 80.66,84 80.48,83.82 80.06,83.82 79.72,84.16 79.72,84.24 79.52,84.44 79.11,84.44 78.83,84.16 v1(78.66,84.16)
CFG12: length 3.1
  TOP w0.14: TP9640.1 78.45,86.09 78.45,85.85 v1(78.46,85.85)
  BOTTOM w0.14: v1(78.46,85.85) 78.46,85.62 78.79,85.29 79.4,85.29 79.44,85.25 79.86,85.25 79.87,85.24 80.06,85.24 CPU1.T63
CFG13: length 5.1
  TOP w0.14: TP9643.1 77.23,86.49 77.78,85.94 v1(77.78,85.86)
  BOTTOM w0.14: CPU1.T62 80.58,84.7 80.13,84.7 79.82,85.01 79.78,85.01 79.76,85.02 79.34,85.02 79.31,85.06 78.91,85.06 78.85,85.01 78.57,85.01 77.79,85.78 77.79,85.85 v1(77.78,85.86)
CFG14: length 3.5
  TOP w0.14: v1(79.11,85.86) 79.11,85.98 79.32,86.19 TP9642.1
  BOTTOM w0.114: CPU1.T61 81.36,85.07
  BOTTOM w0.14: 81.36,85.07 80.96,85.47 79.96,85.47 79.95,85.48 79.53,85.48 79.49,85.52 79.15,85.86 v1(79.11,85.86)
CFG15: length 1.5
  TOP w0.14: TP9641.1 81.38,84.09 81.91,84.62 v1(81.91,84.66)
  BOTTOM w0.114: v1(81.91,84.66) 82.22,84.97 CPU1.T60
CFG16: length 6.1
  TOP w0.14: TP9635.1 76.06,82.19 76.32,82.46 v1(76.32,82.53)
  BOTTOM w0.089: CPU1.AA62 80.92,81.92 80.57,81.57 80.1,81.57 79.98,81.46 79.98,81.46 79.08,81.46 79.03,81.51 79,81.51 78.94,81.57 77.42,81.57 77.36,81.63
  BOTTOM w0.14: 77.36,81.63 77.11,81.63 76.32,82.43 v1(76.32,82.53)
CFG17: length 6
  TOP w0.14: v1(77.07,82.51) 77.29,82.29 TP9634.1
  BOTTOM w0.089: 77.82,81.83 77.89,81.75 79.01,81.75 79.08,81.68 79.11,81.68 79.16,81.63 79.9,81.63 79.91,81.64 80.03,81.75 80.4,81.75 80.58,81.93 80.58,82.12 80.78,82.32 81.05,82.32 81.29,82.08 81.29,82.08 CPU1.AA61
  BOTTOM w0.14: v1(77.07,82.51) 77.25,82.32 77.32,82.32 77.82,81.83
CFG18: length 4.2
  TOP w0.14: v1(77.24,84.16) 77.11,84.02 TP9636.1
  BOTTOM w0.114: v1(77.24,84.16) 77.24,84.19 77.75,84.7 78.26,84.7 78.35,84.79 78.94,84.79 78.96,84.81 79.67,84.81 80.19,84.29 CPU1.U63
CFG19: length 4.1
  TOP w0.14: v1(78,84.17) 77.99,84.19 77.99,84.2 77.67,84.51 TP9638.1
  BOTTOM w0.089: CPU1.U62 80.68,84.29 80.68,84.28 80.4,84 80.13,84 79.89,84.24 79.89,84.32 79.59,84.62 79.04,84.62 79.01,84.59 78.42,84.59 v1(78,84.17)
CFG_RCOMP: length 14.4
  TOP w0.508: R601.2 69.96,82.19 v1(70.02,82.14)
  L3 w0.508: v1(70.02,82.14) 70.02,83.23 71.58,84.79 78.93,84.79 79.32,84.4 v1(79.32,84.04)
  BOTTOM w0.178: CPU1.V63 80.23,83.58 80.02,83.58 79.99,83.6 79.94,83.6 79.51,84.04 v1(79.32,84.04)
  BOTTOM w0.508: v1(70.02,82.14) 70.02,81.71 v2(70.38,81.35)
CHARGER_SRC:
  vias: v2(115.72,137.08) v3(111.71,136.47) v3(112.6,136.47) v3(113.48,136.47) v3(114.37,136.47) v3(115.26,136.47)
CHG_AGND: length 15.1
  TOP w0.508: PC4403.2 107.28,133.91 v3(107.28,135.18) ; PC4404.2 103.3,134.83 v1(103.12,135.01) ; v1(98.63,139.19) 98.63,133.78 v1(98.63,133.77) 98.62,133.76 98.62,132.9 98.09,132.38 v1(97.97,132.38)
  BOTTOM w0.381: v1(97.97,132.38) 97.97,132.01 97.71,131.75 PQ4407.4 ; PQ4407.1 98.93,133.47 v1(98.63,133.77)
  BOTTOM w0.508: PR4423.2 98.97,138.94 98.72,139.19 v1(98.63,139.19) ; v3(107.28,135.18) 107.28,134.89 108.12,134.05 PC4010.2
  vias: v1(104.21,137.74) v1(104.85,137.74) v1(105.48,137.74) v2(103.66,139.97)
CHG_AMBER_LED#: length 15.1
  TOP w0.102: KBC24.16 175.5,29.7 v1(175.39,29.81) ; v1(176.23,20.08) 176.39,20.25 R6104.1
  L4 w0.102: v1(176.23,20.08) 176.23,21.15 177.19,22.11 177.19,23.79 177.65,24.25 177.65,27.67 175.5,29.81 v1(175.39,29.81)
  BOTTOM w0.102: v2(174.95,30.32) 175.39,29.88 v1(175.39,29.81)
CHG_AMBER_LED_R#: length 2.4
  TOP w0.102: R6104.2 176.93,18.53 v2(176.83,18.43) 176.31,18.43 Q6104.B
CLK_LAN_REQ4#_R: length 14.2
  TOP w0.127: v1(37.49,60.78) 37.49,61.26 36.82,61.94 36.82,62.67 36.55,62.93 36.05,62.93 35.93,62.81 35.13,62.81 34.25,63.68 Q3002.E 32.3,63.68 v2(32.05,63.44) 32.05,63.21 33.35,61.92 33.35,59.89 33.67,59.57 R3005.2 34,59.42 R3004.2
  BOTTOM w0.127: v1(37.49,60.78) 37.66,60.62 LOM30.12
CLK_LAN_REQ#_EN: length 5.6
  TOP w0.127: R3003.2 37.7,61.68 v2(37.31,62.07) 37.07,62.31 37.07,62.77 36.84,63 36.84,64.26 36.58,64.52 35.78,64.52 35.57,64.31 Q3002.B
CLK_PCI_KBC: length 96.1
  TOP w0.14: KBC24.2 176.61,24.1 176.21,24.49 175.7,24.49 175.2,25 v1(174.88,25) ; v1(110.85,58.63) 111.2,58.98 EC1801.1 R1805.2
  L3 w0.127: v1(174.88,25) 174.24,25 172.68,26.56 169.04,26.56 168,27.6 164.97,27.6 164.25,27.6 162.43,29.42 161.34,29.42 160.45,30.31 158.95,30.31 158.7,30.56 158.7,32.33 v1(156.8,34.23)
  L4 w0.127: v1(156.8,34.23) 156.8,32.11 154.67,29.98 151.71,29.98 150.97,30.72 149.42,30.72 148.44,31.69 148.44,35.17 146.88,36.73 146.54,36.73 146.13,36.73 144.7,38.17 143.84,38.17 140.87,41.13 140.1,41.13 139.42,41.82 134.57,41.82 132.92,43.48 132.92,44.79 130.06,47.65 130.06,51.96 129.72,52.3 129.15,52.88 128.26,52.88 127.02,54.11 127.02,55.27 126.47,55.82 120.47,55.82 119.37,56.93 116.63,56.93 116.29,56.58 115.57,56.58 113.02,59.13 111.35,59.13 v1(110.85,58.63)
  BOTTOM w0.14: v1(174.88,25) 174.88,25.35 v2(175.05,25.52)
CLK_PCI_KBC_R: length 17.2
  TOP w0.14: R1805.1 110.31,61.42 109.81,61.93 109.81,62.08 107.86,64.03 v2(107.86,69.23) 107.86,71.25 109.64,73.03 109.64,74.37 v1(110.18,74.91)
  BOTTOM w0.14: CPU1.AP15 110.43,74.66 v1(110.18,74.91)
CLK_PCI_LPC: length 76
  TOP w0.14: R1804.2 EC1802.1 112.21,58.57 v1(112.2,58.56)
  L3 w0.127: v1(144.9,37.13) 145.95,36.08 145.95,33.8 146.4,33.35 146.72,33.03 146.72,30.21 151.91,25.02 151.91,20.45 155.97,16.38 v1(155.97,15.54)
  L4 w0.127: v1(112.2,58.56) 112.71,58.56 115.34,55.94 117.75,55.94 118.03,56.21 119.28,56.21 119.94,55.54 120.24,55.25 126.24,55.25 126.45,55.04 126.45,53.88 128.03,52.3 128.91,52.3 129.49,51.73 129.49,47.42 132.34,44.56 132.34,43.24 134.34,41.25 139.18,41.25 139.87,40.56 140.43,40.56 143.86,37.13 v1(144.9,37.13)
  BOTTOM w0.14: DB1.9 155.97,15.53 v1(155.97,15.54) ; v1(144.9,37.13) 144.9,37.71 v2(145.13,37.94)
CLK_PCI_LPC_R: length 19.6
  TOP w0.14: v1(110.18,75.65) 110.69,75.14 110.69,74.82 110.59,74.72 110.59,73.28 110.19,72.89 110.19,72.76 109.09,71.66 109.09,69.66 108.45,69.02 108.45,65.72 110.05,64.12 110.05,63.15 v2(110.74,62.45) 110.93,62.26 111.88,62.26 112.45,61.68 112.45,61.68 113.1,61.03 R1804.1
  BOTTOM w0.14: v1(110.18,75.65) 110.52,75.31 CPU1.AN15
CLK_PCIE_LAN_N4: length 83.4
  L4 w0.102: v1(95.98,95.14) 95.98,95.56 95.86,95.69 95.41,95.69 95.27,95.82 91.33,95.82 88.96,93.45 86.5,93.45 86.33,93.27 82.8,93.27 80.93,91.4 80.93,90.93 79.73,89.73 77.92,89.73 75.46,87.27 72.08,87.27 66.92,82.11 62.61,82.11 49.78,69.28 45.71,69.28 42.03,65.59 36.49,65.59 35.66,64.77 35.66,63.36 36.09,62.93 36.28,62.93 36.45,63.11 36.45,63.38 v1(36.4,63.44)
  BOTTOM w0.102: v1(95.98,95.14) 95.98,95.47 96.1,95.59 96.35,95.59 96.59,95.35 96.61,95.33 96.61,94.48 96.16,94.03 96.16,92.8 CPU1.B38 ; 36.75,62.8 36.4,63.15 v1(36.4,63.44) ; 36.75,62.8 v2(36.84,62.89) ; 36.75,62.8 37.33,62.22 LOM30.16
CLK_PCIE_LAN_P4: length 83.3
  L4 w0.102: v1(36.37,62.48) 36.16,62.7 36,62.7 35.44,63.27 35.44,64.86 36.4,65.82 41.93,65.82 45.62,69.5 49.68,69.5 62.52,82.34 66.83,82.34 71.99,87.5 75.37,87.5 77.83,89.96 79.63,89.96 80.7,91.03 80.7,91.49 82.71,93.5 86.23,93.5 86.41,93.68 88.87,93.68 91.24,96.05 95.37,96.05 95.5,95.91 95.97,95.91 v1(96.11,96.05)
  BOTTOM w0.102: v1(36.37,62.48) 36.78,62.48 37.24,62.02 37.72,62.02 37.92,61.82 LOM30.15 ; v1(96.11,96.05) 96.17,96.05 96.81,95.42 96.81,94.4 96.36,93.95 96.36,92.9 96.66,92.6 CPU1.C37
CLK_PCIE_LAN_REQ4#: length 288.2
  TOP w0.127: v1(120.14,87.51) 119.49,87.51 v2(119.06,87.95) 118.77,88.24 118.77,89.63 118.35,90.05 118.35,91.48 118.79,91.92 118.79,92.48 RN2011.8 119.45,92.68 v1(119.45,92.19) ; R3005.1 34.3,60.46 v1(34.62,60.14) 34.91,60.43 34.91,60.86 34.58,61.19 Q3002.C
  L3 w0.127: v1(38.6,41.69) 36.46,43.83 36.46,55.12 35.82,55.75 35.82,58.29 34.68,59.43 34.68,60.08 v1(34.62,60.14) ; v1(131.46,70.1) 131.46,69.46 133.98,66.93 133.98,66.81 135.46,65.33 135.46,60.13 135.46,60.13 135.46,59.63 132.46,56.62 132.46,50.95 136.08,47.33 136.08,42.9 136.65,42.33 138.74,42.33 141.6,39.47 141.6,38.11 144.31,35.4 144.31,33.12 145.08,32.36 145.08,29.55 145.08,23.3 147.86,20.52 147.86,8.45 144.38,4.97 v1(144.38,4.18)
  L4 w0.127: v1(119.45,92.19) 120.69,92.19 122.09,93.59 124.19,93.59 124.27,93.67 125.12,93.67 126.12,94.67 126.12,95 126.71,95.6 128.19,95.6 128.46,95.33 130.47,95.33 131.32,96.18 132.69,96.18 132.98,95.89 132.98,95.25 134.95,93.29 134.95,91.93 135.79,91.09 135.79,89.89 134.05,88.15 134.05,87.84 133.53,87.31 133.53,83.82 132.91,83.2 132.91,71.54 131.68,70.31 v1(131.46,70.1) ; v1(144.38,4.18) 143.37,3.17 132.95,3.17 132.14,3.98 129.83,3.98 129.8,3.94 129.7,3.94 128.88,3.12 110.75,3.12 109.63,4.25 106.1,4.25 105.74,3.88 78.12,3.88 70.38,11.62 65.86,11.62 63.67,13.81 50.69,13.81 37.19,27.3 37.19,40.29 v1(38.6,41.69)
  BOTTOM w0.127: v1(120.14,87.51) 119.23,86.61 119.01,86.61 CPU1.N1
CLK_PCIE_REQ#: length 18.4
  TOP w0.127: v1(116.44,83.09) 116.62,83.09 117.01,82.7 118.47,82.7 v2(119.12,83.35) 119.45,83.68 119.45,84.09 120.17,84.81 v1(120.17,85.27)
  BOTTOM w0.102: v1(116.44,83.09) 116.44,82.79 CPU1.Y5
  BOTTOM w0.127: CPU1.U2 118.24,84.34 118.46,84.55 118.46,84.78 CPU1.T2 118.36,85 118.66,85.3 118.99,85.3 119.2,85.51 119.73,85.51 119.97,85.27 v1(120.17,85.27) 120.17,85.43 120.83,86.09 120.83,86.71 122.55,88.44 123.85,88.44 124.93,89.52 125.8,89.52 125.87,89.45 126.41,89.45 126.6,89.63 RN1801.6
CLK_PCIE_VGA: length 84.9
  L3 w0.102: v1(159.18,110.84) 159.43,111.09 159.43,111.29 159.28,111.45 157.9,111.45 153.85,115.5 150.82,115.5 144.37,109.05 135.94,109.05 135.65,108.76 123.61,108.76 121.94,110.42 116.63,110.42 116.35,110.7 109.6,110.7 107.12,108.22 102.02,108.22 100.8,107.01 100.8,103.64 99.01,101.85 98.76,101.85 98.6,101.68 96.73,101.68 96.57,101.52 96.57,101.39 v1(96.75,101.22)
  BOTTOM w0.102: CPU1.B39 95.88,93.42 95.88,94.11 95.14,94.86 95.14,95.6 ; 95.14,95.6 v2(95.29,95.6) ; 95.14,95.6 95.14,96.86 95.75,97.47 95.75,99.76 96.4,100.42 96.4,100.87 v1(96.75,101.22) ; GPU1.AE8 158.77,110.43 v1(159.18,110.84)
CLK_PCIE_VGA#: length 85
  L3 w0.102: v1(95.94,101.22) 96.64,101.91 98.5,101.91 98.67,102.07 98.91,102.07 100.58,103.74 100.58,107.1 101.92,108.45 107.03,108.45 109.5,110.93 116.45,110.93 116.72,110.65 122.04,110.65 123.7,108.99 135.56,108.99 135.85,109.28 144.28,109.28 150.73,115.73 153.94,115.73 157.99,111.68 159.37,111.68 159.66,111.39 159.66,111.14 v1(159.97,110.84)
  BOTTOM w0.102: GPU1.AD8 159.96,110.84 v1(159.97,110.84) ; 94.94,96.84 94.94,96.95 95.55,97.56 95.55,99.85 96.2,100.5 96.2,100.96 v1(95.94,101.22) ; 94.94,96.84 94.94,94.77 95.66,94.05 95.66,93.85 CPU1.A39 ; 94.94,96.84 v2(94.78,96.84)
CLK_PCIE_WLAN_N3: length 179.6
  L4 w0.102: v1(193.74,44.22) 194.08,44.22 194.23,44.37 194.23,44.77 193.62,45.38 192.59,45.38 187.58,50.4 183.1,50.4 181.66,48.96 171.08,48.96 169.71,50.32 165.67,50.32 165.47,50.12 150.01,50.12 145.91,54.21 145.91,55.63 145.55,55.99 145.55,57.55 144.18,58.92 144.18,60.44 143.29,61.33 143.29,93.72 142.62,94.39 142.62,98.62 142.34,98.9 142.34,99.74 140.69,101.39 140.69,103.54 137.82,106.41 124.33,106.41 122.97,107.77 105.97,107.77 105.41,108.32 101.27,108.32 100.46,107.51 96.43,107.51 94.71,105.79 94.71,103.71 95.05,103.38 95.05,102.7 94.89,102.54 94.89,102.24 95.06,102.06 v1(95.21,102.06)
  BOTTOM w0.102: v2(95.06,98.09) 94.91,98.09 ; 94.91,98.09 94.91,101.77 v1(95.21,102.06) ; 94.91,98.09 94.91,97.67 94.39,97.15 94.39,94.98 93.86,94.44 93.86,92.89 94.15,92.6 CPU1.C41 ; v1(193.74,44.22) 194.02,44.22 194.21,44.03 194.21,41.18 191.27,38.23 190.6,38.23 190.6,38.23 190.33,38.5 WLAN1.11
CLK_PCIE_WLAN_P3: length 179.7
  L4 w0.102: v1(94.47,101.99) 94.66,102.17 94.66,102.64 94.82,102.8 94.82,103.28 94.48,103.62 94.48,105.88 96.34,107.74 100.36,107.74 101.17,108.55 105.51,108.55 106.06,107.99 123.06,107.99 124.42,106.63 137.91,106.63 140.92,103.63 140.92,101.49 142.57,99.84 142.57,98.99 142.85,98.71 142.85,94.49 143.52,93.82 143.52,61.42 144.41,60.53 144.41,59.02 145.78,57.65 145.78,56.08 146.14,55.72 146.14,54.31 150.1,50.34 165.37,50.34 165.58,50.55 169.81,50.55 171.17,49.19 181.57,49.19 183.01,50.63 187.68,50.63 192.69,45.61 193.71,45.61 194.46,44.87 194.46,44.56 v1(194.8,44.22)
  BOTTOM w0.102: WLAN1.13 190.2,37.7 190.53,38.03 191.35,38.03 194.42,41.09 194.42,43.83 v1(194.8,44.22) ; v2(94.56,99.56) 94.71,99.56 ; 94.71,99.56 94.71,101.75 v1(94.47,101.99) ; 94.71,99.56 94.71,97.76 94.19,97.24 94.19,95.06 93.65,94.53 93.65,92.8 CPU1.B42
CLK_PCIE_WLAN_REQ3#: length 136.6
  TOP w0.102: v1(120.8,80.39) 120.8,80.09 121.33,79.57 121.79,79.57 122.25,80.03 123.42,80.03 123.7,80.31 123.7,81.13 124.83,82.26 125.34,82.26 125.74,82.66 125.74,85.86 124.97,86.63 v2(124.97,86.91) 124.97,88.06 125.34,88.43 126.41,88.43 127.4,89.43 127.4,91.95 126.83,92.52 125.77,92.52 v1(125.42,92.17)
  L3 w0.102: v1(184.93,32.68) 184.88,32.63 180.81,32.63 180.5,32.95 175.18,32.95 174.67,32.43 174.01,32.43 173.58,32.86 173.58,33.07 172.84,33.81 171.64,33.81 170.57,34.87 166.07,34.87 163.95,36.99 163.04,36.99 162.15,37.88 162.15,38 152.14,48 152.14,50.91 149.67,53.38 149.67,53.7 149.02,54.36 146.88,54.36 145.89,55.35 145.89,55.42 145.56,55.74 145.45,55.74 143.09,58.11 143.09,71.22 138.39,75.92 138.39,81.23 136.34,83.29 134.26,83.29 132.97,84.58 132.87,84.58 131.65,85.8 131.65,86.22 131.43,86.44 131.19,86.68 130.97,86.68 130.15,87.5 130.15,90.52 129.55,91.11 128.26,91.11 127.23,92.14 125.46,92.14 v1(125.42,92.17)
  BOTTOM w0.102: RN1505.6 125.8,92.55 v1(125.42,92.17) ; v1(120.8,80.39) 120.78,80.41 119.33,80.41 119.24,80.5 CPU1.AD1 ; WLAN1.7 187.71,40.1 187.48,39.87 186.2,39.87 184.58,38.24 184.58,36.52 186.53,34.57 186.53,33.74 185.47,32.68 v1(184.93,32.68)
CODEC_BITCLK_R: length 2.3
  TOP w0.14: R2720.2 40.7,10.54 v2(39.85,10.54) HDA27.6
CODEC_SDOUT_R: length 5.1
  TOP w0.14: v1(40.33,9.21) 40.33,9.72 39.92,10.14 HDA27.5
  BOTTOM w0.14: v1(40.33,9.21) 40.33,9.6 39.63,10.3 R2719.2 39.63,11.66 v2(39.62,11.68)
COLOR_ENGINE: length 1.3
  TOP w0.102: TP2003.1 117.33,90.53 v1(117.27,90.59)
  BOTTOM w0.102: v1(117.27,90.59) 117.59,90.92 CPU1.E3
COMBO-GPI: length 2.2
  TOP w0.102: HDA27.48 37.83,7.19 38.95,6.08 TP2702.1
CPU_RXN_C_DGPU_TXN0: length 54
  TOP w0.127: 153.17,108.23 v1(152.62,108.23) ; 153.17,108.23 154.91,108.23 C7302.1 ; 153.17,108.23 v2(153.17,108.36)
  L3 w0.114: v1(152.62,108.23) 152.72,108.13 153.58,108.13 153.87,107.84 153.87,107.13 151.81,105.07 150.71,105.07 145.63,99.99 136.96,99.99 136.76,99.78 133.09,99.78 132.65,99.34 129.36,99.34 127.4,97.38 122.97,97.38 122.27,96.68 119.77,96.68 118.26,95.17 116.08,95.17 115.52,94.61 115.52,94.05 113.5,92.03 113.5,91.26 113,90.76 v1(113,90.76)
  BOTTOM w0.127: v1(113,90.76) 113.12,90.76 CPU1.F10
CPU_RXN_C_DGPU_TXN1: length 54.9
  TOP w0.127: 153.37,109.93 152.96,109.93 v1(152.81,110.09) ; 153.37,109.93 154.19,109.93 C7304.1 ; 153.37,109.93 v2(153.37,110.06)
  L3 w0.114: v1(113.91,90.74) 114.42,91.25 114.42,91.87 116.16,93.61 116.84,93.61 117.62,94.4 118.77,94.4 120.3,95.93 122.58,95.93 123.28,96.63 127.71,96.63 128.79,97.71 131.03,97.71 131.7,98.38 132.75,98.38 133.4,99.03 137.07,99.03 137.27,99.23 146.05,99.23 151.06,104.25 152.16,104.25 154.88,106.96 154.88,108.42 153.37,109.93 152.97,109.93 v1(152.81,110.09)
  BOTTOM w0.127: v1(113.91,90.74) 114.1,90.74 CPU1.F8
CPU_RXN_C_DGPU_TXN2: length 64
  TOP w0.127: 154.51,112.97 154.02,112.97 153.83,112.78 152.82,112.78 v1(152.59,113.01) ; 154.51,112.97 155.15,112.97 C7306.1 ; 154.51,112.97 v2(154.51,113.1)
  L3 w0.114: v1(152.59,113.01) 152.79,112.81 154.1,112.81 156.48,110.43 156.48,106.24 152.7,102.46 152.7,102.07 148.36,97.73 140.49,97.73 139.87,97.11 137.4,97.11 137.22,97.29 136.28,97.29 135.84,96.86 134.1,96.86 133.3,96.05 131.04,96.05 129.96,94.98 126.15,94.98 125.51,94.34 120.9,94.34 120.31,93.74 120.31,91.94 118.3,89.93 114.65,89.93 114.37,89.65 114.11,89.65 113.9,89.45 v1(113.9,89.44)
  BOTTOM w0.127: v1(113.9,89.44) 113.73,89.44 CPU1.H10
CPU_RXN_C_DGPU_TXN3: length 63.3
  TOP w0.127: v1(153.24,115.05) 153.36,114.92 154.1,114.92 154.22,115.04 155.11,115.04 ; 155.11,115.04 v2(155.11,115.17) ; 155.11,115.04 155.75,115.04 C7308.1
  L3 w0.114: v1(153.24,115.05) 153.03,114.84 152.59,114.84 151.55,113.8 151.55,112.99 151.75,112.79 151.75,111.99 152.45,111.29 153.92,111.29 155.45,109.76 155.45,106.8 147.36,98.71 137.48,98.71 137.28,98.51 134.22,98.51 132.75,97.05 131.13,97.05 131,97.17 128.99,97.17 127.93,96.11 123.55,96.11 122.83,95.39 120.56,95.39 119.24,94.08 119.24,93.1 117.42,91.28 116.45,91.28 116.14,90.96 115.76,90.96 115.57,91.15 115.14,91.15 114.94,91.35 v1(114.89,91.35)
  BOTTOM w0.127: v1(114.89,91.35) 115.08,91.35 CPU1.E6
CPU_RXP_C_DGPU_TXP0: length 53.5
  TOP w0.127: 154.3,107.99 153.01,107.99 v1(152.62,107.6) ; 154.3,107.99 v2(154.3,107.86) ; 154.3,107.99 154.85,107.99 C7301.1
  L3 w0.114: v1(152.62,107.6) 152.92,107.9 153.49,107.9 153.64,107.75 153.64,107.22 151.72,105.3 150.61,105.3 145.53,100.22 136.87,100.22 136.66,100.01 133,100.01 132.55,99.57 129.27,99.57 127.31,97.61 122.88,97.61 122.18,96.91 119.67,96.91 118.17,95.4 115.99,95.4 115.29,94.7 115.29,94.15 113.27,92.13 113.27,91.5 113.18,91.41 v1(113,91.41)
  BOTTOM w0.127: v1(113,91.41) 113.11,91.51 113.35,91.51 113.43,91.43 CPU1.E10
CPU_RXP_C_DGPU_TXP1: length 54.9
  TOP w0.127: C7303.1 154.24,109.69 153.04,109.69 v1(152.81,109.46) ; v2(114.2,92.02) 113.94,91.76 v1(113.94,91.42)
  L3 w0.114: v1(113.94,91.42) 114.11,91.42 114.19,91.51 114.19,91.97 116.07,93.84 116.74,93.84 117.53,94.63 118.68,94.63 120.21,96.16 122.49,96.16 123.19,96.86 127.62,96.86 128.69,97.93 130.94,97.93 131.61,98.61 132.66,98.61 133.31,99.26 136.97,99.26 137.17,99.46 145.96,99.46 150.97,104.48 152.07,104.48 154.65,107.06 154.65,108.32 153.28,109.7 153.05,109.7 v1(152.81,109.46)
  BOTTOM w0.127: v1(113.94,91.42) 114.06,91.54 114.33,91.54 114.46,91.41 114.46,91.16 CPU1.E8
CPU_RXP_C_DGPU_TXP2: length 64
  TOP w0.127: 153.34,112.54 153.93,112.54 154.12,112.73 154.83,112.73 154.92,112.64 154.92,112.47 155,112.39 C7305.1 ; 153.34,112.54 v2(153.34,112.41) ; 153.34,112.54 152.7,112.54 152.6,112.44 v1(152.6,112.26)
  L3 w0.114: v1(113.91,90.09) 113.91,89.95 113.98,89.88 114.28,89.88 114.55,90.16 118.2,90.16 120.08,92.03 120.08,93.84 120.81,94.57 125.42,94.57 126.05,95.2 129.87,95.2 130.95,96.28 133.2,96.28 134.01,97.09 135.75,97.09 136.18,97.52 137.32,97.52 137.5,97.34 139.77,97.34 140.39,97.96 148.26,97.96 152.47,102.17 152.47,102.56 156.25,106.33 156.25,110.34 154,112.58 152.7,112.58 152.55,112.43 152.55,112.31 v1(152.6,112.26)
  BOTTOM w0.127: CPU1.G10 113.43,90 113.6,90.17 113.83,90.17 v1(113.91,90.09)
CPU_RXP_C_DGPU_TXP3: length 63.5
  TOP w0.127: C7307.1 155.64,114.8 154.32,114.8 154.2,114.68 153.8,114.68 ; 153.8,114.68 153.5,114.68 v1(153.24,114.42) ; 153.8,114.68 v2(153.8,114.55)
  L3 w0.114: v1(153.24,114.42) 153.04,114.62 152.69,114.62 151.78,113.71 151.78,113.09 151.98,112.89 151.98,112.08 152.54,111.52 154.02,111.52 155.68,109.86 155.68,106.7 147.46,98.48 137.57,98.48 137.38,98.28 134.31,98.28 132.85,96.82 131.04,96.82 130.91,96.94 129.09,96.94 128.02,95.88 123.64,95.88 122.93,95.17 120.65,95.17 119.47,93.98 119.47,93 117.52,91.05 116.55,91.05 116.23,90.73 115.67,90.73 115.48,90.92 115.12,90.92 114.88,90.68 114.86,90.68 v1(114.86,90.66)
  BOTTOM w0.127: v1(114.86,90.66) 115.12,90.66 CPU1.F6
CPVEE: length 4.1
  TOP w0.203: 31.04,8.79 31.59,9.34 HDA27.34
  TOP w0.305: v2(29.87,7.41) 29.86,7.42 C2704.2 29.86,8.33 30.21,8.68 30.93,8.68 31.04,8.79
DBC_EN: length 116.3
  TOP w0.102: v1(117.89,87.61) 118.26,87.99 118.26,88.79 118.33,88.86 118.33,89.38 117.9,89.81 117.9,91.66 118.35,92.1 118.35,93.75 v1(118.51,93.91) 118.66,94.06 RN2011.6 ; v1(45.34,78.92) 45.27,78.99 R5224.2
  L3 w0.102: v1(45.23,85.95) 45.23,79.38 45.34,79.26 v1(45.34,78.92)
  L4 w0.102: v1(45.23,85.95) 46.38,87.11 48.42,87.11 49.09,87.78 49.09,88.35 53.81,93.06 54.49,93.06 60.44,93.06 67.22,99.84 68.84,99.84 72.06,103.07 75.94,103.07 77.44,104.56 88.92,104.56 93.17,100.31 94.5,100.31 95.2,99.61 97.18,99.61 97.69,100.12 98.16,100.12 98.39,99.89 99.58,99.89 100.03,100.34 101.94,100.34 102.21,100.61 108.2,100.61 108.21,100.6 108.52,100.6 108.52,100.6 110.6,100.6 111.12,101.13 111.47,101.13 114.75,101.13 115.42,100.46 120.25,100.46 120.92,101.12 120.92,102.05 121.21,102.34 v1(122.56,102.34)
  BOTTOM w0.102: v1(118.51,93.91) 118.93,93.91 121.23,96.21 v2(121.23,97.48) 121.74,97.99 121.74,98.62 122.59,99.47 122.59,102.31 v1(122.56,102.34) ; v1(117.89,87.61) 117.59,87.91 CPU1.K3
DBC_EN_R: length 5.1
  TOP w0.102: R5224.1 46.16,79.78 45.33,80.61 v2(45.21,80.61) 44.92,80.91 44.92,81.26 43.46,82.72 43.45,82.72 LCD1.8
DC_IN_D: length 2.2
  BOTTOM w0.254: PQ4402.3 93.38,147.66 92.48,148.56 PR4404.2
DC_TEST_A3_B3: length 0.7
  BOTTOM w0.102: CPU1.A3 117.76,93.19 CPU1.B3
DC_TEST_A61_B61: length 0.7
  BOTTOM w0.102: CPU1.A61 81.58,93.64 CPU1.B61
DC_TEST_AY2_AW2: length 0.7
  BOTTOM w0.089: CPU1.AW2 118.23,71.2 CPU1.AY2
DC_TEST_AY3_AW3: length 0.7
  BOTTOM w0.089: CPU1.AW3 117.63,71.69 CPU1.AY3
DC_TEST_AY61_AW61: length 4.8
  BOTTOM w0.102: v2(78.79,68.09) 78.79,68.26 81.49,70.96 CPU1.AY61 81.49,71.66 CPU1.AW61
DC_TEST_AY62_AW62: length 5.4
  BOTTOM w0.102: CPU1.AW62 80.92,71.17 CPU1.AY62 78.06,68.31 77.27,68.31 v2(77.24,68.29)
DC_TEST_B62_B63: length 0.7
  BOTTOM w0.102: CPU1.B62 80.4,92.99 CPU1.B63
DC_TEST_C1_C2: length 0.7
  BOTTOM w0.102: CPU1.C1 118.78,92.46 118.25,92.46 CPU1.C2
DCBATOUT: length 126.1
  TOP w0.203: PC4531.1 129.85,34.66 PU4503.12
  TOP w0.406: PU4407.3 118.17,145.34 PC4431.1
  TOP w0.508: v1(123.67,128.34) 123.65,128.34 123.55,128.44 EC9742.1 ; PC4531.1 129.12,34.42 PC4519.1 128.55,34.28 127.63,35.2 119.53,35.2 118.88,34.54 EC9710.1 ; PR4468.1 142.39,136.16 142.39,135.35 ; 131.09,135.6 131.09,138.84 130.63,139.29 130.63,142.9 129.94,143.6 128.98,143.6 128.54,144.04 118.16,144.04 117.8,144.39 PC4431.1
  TOP w1.016: 59.36,95.8 62.76,95.8 80.69,113.73 80.69,115.04 82.8,117.15 82.8,120.54 84.64,122.38 84.64,125.11 86.09,126.56 86.09,129.97
  L4 w0.508: v1(177.47,51.12) 177.4,51.19 172.01,51.19 170.96,52.25 156.5,52.25 154.73,54.02 154.73,57.35 152.21,59.86 v3(152.21,59.99)
  BOTTOM w0.254: PR4402.2 89.51,140.21 PG4403.1
  BOTTOM w0.508: v1(177.47,51.12) 177.47,50.83 177.75,50.54 PR8312.2 ; PR8202.1 149.04,85.21 149.04,87.45 v3(149.15,87.55)
  vias: v2(115.9,32.55) v2(124.97,17.24) v2(140.87,48.05) v2(143.79,81.37) v2(144.04,24.66) v2(146.76,96.92) v2(150.67,67.66) v3(87.45,133.42) v3(87.45,132.4) v3(88.59,133.42) v3(88.59,132.4) v3(89.74,133.42) v3(89.74,132.4) v3(90.88,133.42) v3(90.88,132.4) v3(116.24,132.14) v3(116.24,131.25) v3(117.26,132.14) v3(117.26,131.25) v3(118.28,132.14) v3(118.28,131.25) v3(119.29,132.14) v3(119.29,131.25) v3(135.82,135.59) v3(135.82,134.57) v3(135.82,133.56) v3(136.83,135.59) v3(136.83,134.57) v3(136.83,133.56) v3(137.85,135.59) v3(137.85,134.57) v3(137.85,133.56) v3(151.35,59.96)
DCBATOUT_R: length 12.8
  TOP w0.254: PR4448.1 126.13,145.61 125.93,145.81 125.93,146.25 v1(125.8,146.37)
  L3 w0.254: v1(132,141.83) 132.14,141.97 132.14,144.29 130.94,145.49 126.23,145.49 126.21,145.51 126.2,145.51 125.93,145.79 125.93,146.25 v1(125.8,146.37)
  BOTTOM w0.254: v1(132,141.83) 131.39,142.43 PG4404.1 ; v1(125.8,146.37) 125.65,146.37 v2(125.18,145.9)
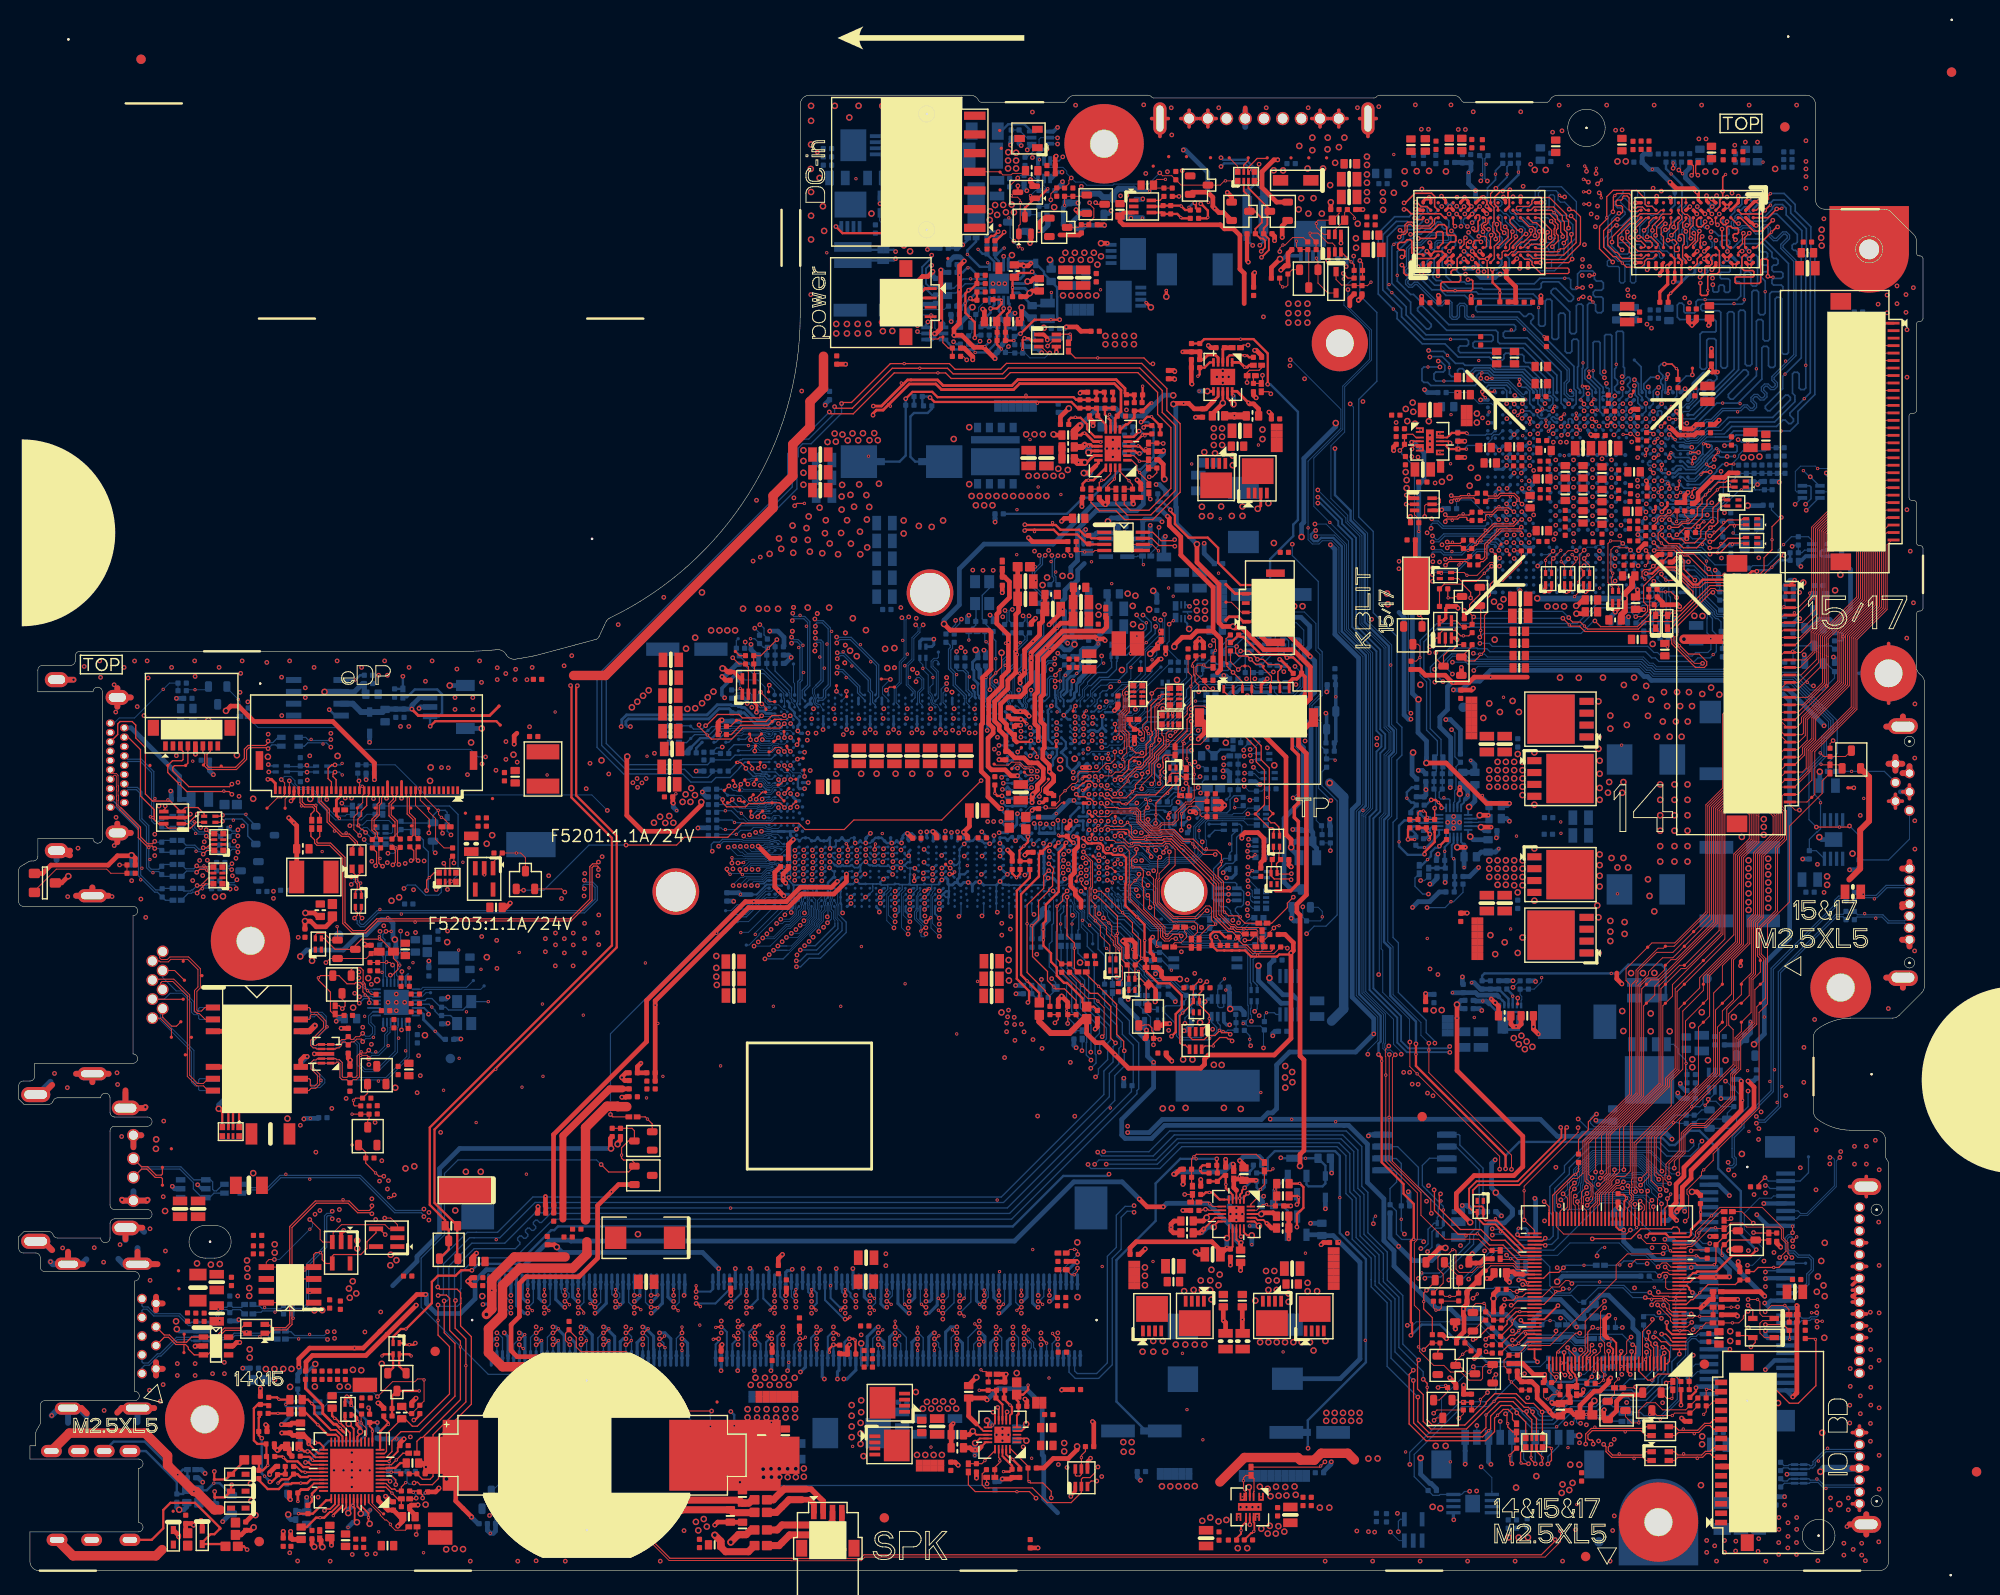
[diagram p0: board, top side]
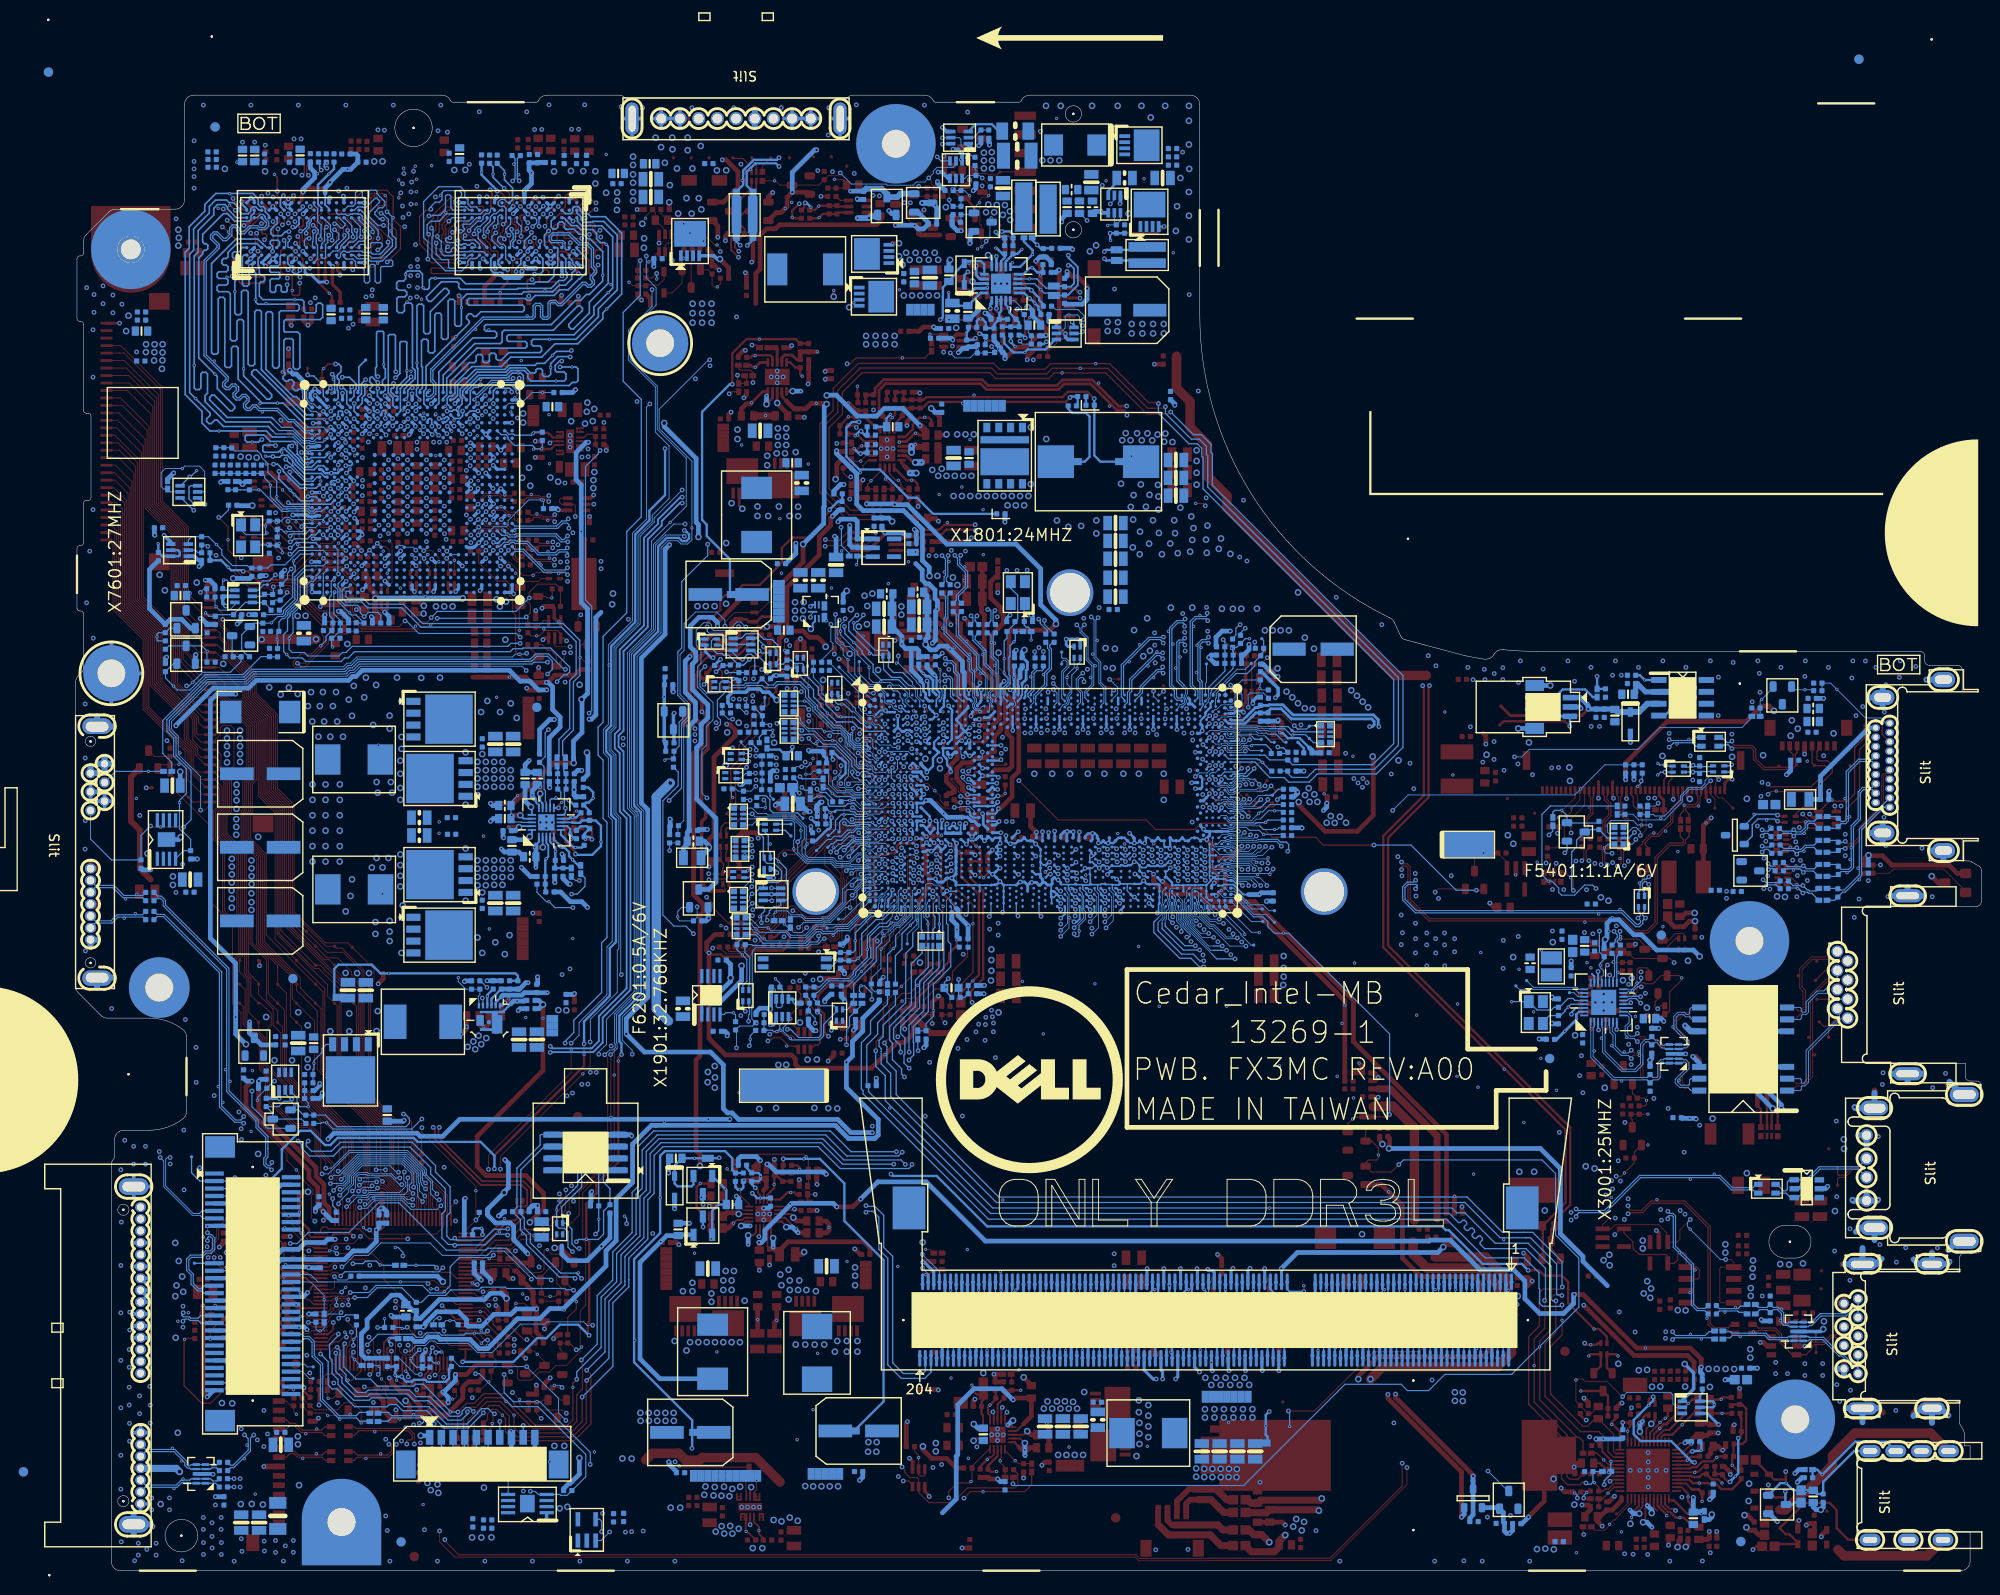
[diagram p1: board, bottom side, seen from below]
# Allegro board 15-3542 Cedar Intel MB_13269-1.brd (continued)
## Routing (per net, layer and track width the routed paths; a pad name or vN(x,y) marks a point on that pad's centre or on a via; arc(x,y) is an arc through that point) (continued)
DDC_CLK_HDMI: length 20.1
  TOP w0.14: 15.96,82.36 v2(15.96,82.49) ; 15.96,82.36 16.2,82.36 17.33,81.24 Q5402.3 17.83,81.67 19.17,81.67 19.84,80.99 RN5401.1 ; 15.96,82.36 14.31,82.36 13.55,83.13 13.55,88.09 12.52,89.12 12.52,90.49 12.14,90.87 10.85,90.87 10.6,90.62 10.6,89.5 HDMI1.15
DDC_CLK_PH1: length 5.1
  TOP w0.14: RN5401.4 21.68,80.74 v1(21.79,80.85)
  BOTTOM w0.127: v2(24.31,80.94) 24.22,80.85
  BOTTOM w0.14: D5401.2 25.36,79.71 24.11,80.96 21.9,80.96 v1(21.79,80.85)
DDC_DATA_HDMI: length 16.5
  TOP w0.14: RN5401.2 19.01,80.09 18.39,79.47 15.98,79.47 Q5402.6 14.95,79.94 14.49,80.4 14.49,80.61 ; v2(14.36,80.61) 14.49,80.61 ; 14.49,80.61 14.49,81.45 13.03,82.91 13.03,87.87 11.7,89.2 HDMI1.16
DDC_DATA_PH2: length 6.4
  TOP w0.14: RN5401.3 21.67,80.09 v1(21.79,80.21)
  BOTTOM w0.127: 22.96,80.44 v2(22.96,80.32)
  BOTTOM w0.14: v1(21.79,80.21) 21.88,80.21 22.12,80.44 23.89,80.44 24.5,79.83 24.5,78.61 D5401.1
DDPC_CTRLDATA: length 1.2
  TOP w0.102: TP1502.1 112.8,92.29 v1(113.04,92.53)
  BOTTOM w0.102: CPU1.D11 v1(113.04,92.53)
DDR3_DRAMRST#: length 112.6
  TOP w0.127: v1(74.11,17.09) 71.32,17.09 64.97,23.44 60.14,23.44 59.64,23.94 59.64,24.96 58.87,25.72 C1217.1 58.49,25.4 58.49,24.64 v1(58.95,24.18)
  L3 w0.127: v1(74.11,17.09) 74.11,16.83 78.15,12.8 83.71,12.8 88.17,8.34 99.56,8.34 102.12,10.9 102.13,10.9 102.46,11.23 108.45,11.23 110.19,12.98 110.19,15.92 114.06,19.79 114.06,28.22 114.47,28.62 114.47,36.34 113.46,37.35 113.46,55.37 v1(113.73,55.65)
  BOTTOM w0.127: DM1.30 v1(58.95,24.18) ; R404.2 113.76,55.66 113.75,55.65 v1(113.73,55.65) ; v2(73.99,15.44) 73.99,16.96 v1(74.11,17.09)
DDR_PG_CTRL: length 35.7
  TOP w0.127: R1205.1 63.54,48.57 v1(63.3,48.81)
  BOTTOM w0.089: CPU1.AV61 81.59,72.59 81.08,72.07 80.78,72.07 80.76,72.06 80,72.06 79.89,71.94
  BOTTOM w0.127: v1(63.3,48.81) 63.3,57.45 74.06,68.22 v2(74.65,68.22) 75.61,68.22 76.32,68.93 76.32,69.45 76.85,69.97 77.83,69.97 79.81,71.94 79.89,71.94
DDR_PG_CTRL_R: length 2.8
  TOP w0.127: R1205.2 67.02,48.57 v2(67.26,48.33) 67.76,47.82 Q1201.S
DDR_VREF_S3: length 78.1
  TOP w1.016: 58.45,33.57 53.02,33.57 50.61,31.16 v2(50.61,29.99) 50.61,28 v3(50.02,27.41)
  L3 w1.016: v3(50.02,27.41) 50.13,27.31 50.13,23.95 51.32,22.75 61.73,22.75 63.78,20.71 63.78,20.25 65.72,18.31 68.49,18.31 69.37,19.19 75.22,19.19 75.57,18.84 82.83,18.84 85.39,21.4 89.04,21.4 90.06,22.42 105.48,22.42 v3(106.75,21.15)
DDR_VTT_PG_CTRL: length 115.1
  TOP w0.127: v1(62.3,43.46) 63.1,42.67 65.24,42.67 Q1202.G 65.86,43.64 65.55,43.94 64.69,43.94 64.49,44.15 v2(64.49,44.47) 64.49,45.25 65.22,45.98 Q1201.D 65.86,47.08 65.6,47.34 R1204.1 R1208.2 ; v1(103.58,9.3) 103.53,9.35 R4909.2
  BOTTOM w0.127: v1(103.58,9.3) 103.4,9.12 78.9,9.12 68.07,19.95 62.05,19.95 61.38,19.27 59.12,19.27 57.37,21.01 50.23,21.01 43.05,28.19 43.05,33.45 45.54,35.94 45.54,42.51 46.99,43.95 61.81,43.95 v1(62.3,43.46)
DDR_VTT_PG_CTRL_R: length 3.3
  TOP w0.127: R4909.1 104.42,10.8 R4910.1 104.41,11.05 104.95,11.59 v2(104.95,11.76) 104.95,11.99 104.83,12.11 PU4901.17
DDR_WR_VREF01: length 53.3
  TOP w0.508: v1(87.57,73.76) 86.94,73.13 83.61,73.13 82.09,71.61 82.08,71.61 82.07,71.6 v2(78.64,71.6) 77.74,71.6 67.16,61.02 67.16,56.61 57.21,46.66 57.21,39.16 C3702.1 57.24,38.3 R3702.1
  BOTTOM w0.305: CPU1.AR51 87.73,73.79 87.6,73.79 v1(87.57,73.76)
DEBUG: length 15.4
  TOP w0.14: v1(186.82,20.05) 187.28,20.05 189.41,17.92 190.37,17.92 192.24,19.79 192.24,24.71 v2(192.19,24.75) 192.11,24.84 R5807.2
  BOTTOM w0.14: v1(186.82,20.05) 186.88,20.1 WLAN1.49
DGPU_HOLD_RST#: length 49.9
  TOP w0.127: R7304.1 155.13,100.04 v2(154.53,100.04) 154.25,100.04 153.68,100.62 152.57,100.62 152.57,100.61 152.32,100.61 151.95,100.24 U7301.1 151.63,99.81 v1(151.33,99.51)
  L3 w0.127: v1(151.33,99.51) 150.88,99.51 148.58,97.2 143.22,97.2 142.6,96.59 136.7,96.59 v1(136.52,96.77)
  BOTTOM w0.102: 118.85,87.69 118.57,87.41 118.57,87.14 118.38,86.95 117.8,86.95 117.59,87.15 CPU1.L3
  BOTTOM w0.127: v1(136.52,96.77) 137.07,96.22 137.07,94.65 136.34,93.92 135.19,93.92 134.95,94.16 134.95,94.94 134.75,95.14 RN1503.4 133.88,95.14 133.5,94.76 132.38,94.76 132.15,94.99 130.87,94.99 EC1502.1 129.75,94.78 129.22,94.78 128.85,95.14 126.31,95.14 125.46,94.29 125.46,93.52 124.5,92.56 124.5,92.56 124.5,92.31 122.63,90.44 122,90.44 120.93,89.37 120.93,88.81 120.45,88.33 119.81,88.33 119.16,87.69 118.85,87.69
DGPU_PWR_EN: length 111.5
  TOP w0.127: v1(149.03,120.04) 149.03,120.12 149.37,120.46 U8301.5 ; v1(148.42,114.13) 148.43,114.12 PQ8305.2
  L3 w0.127: v1(150.65,70.96) 150.46,70.96 149.95,71.47 148.62,71.47 144.59,75.49 144.59,84.81 149.36,89.59 149.36,90.96 151.65,93.25 151.65,94.92 v1(151.48,95.09) 151,94.61 151,93.21 150.06,92.27 147.09,92.27 145.12,90.3 138.06,90.3 137.8,90.56 135.77,90.56 v1(135.33,90.11)
  L4 w0.127: v1(151.48,95.09) 151.48,95.48 149.95,97.02 149.95,101.53 149.3,102.18 149.3,104.14 149.83,104.67 149.83,108.86 147.38,111.31 147.38,113.06 148.42,114.09 v1(148.42,114.13) 148.46,114.17 148.46,114.26 149.19,114.99 149.19,116.79 150.44,118.04 150.44,119.46 149.8,120.1 149.09,120.1 v1(149.03,120.04)
  BOTTOM w0.127: v1(135.33,90.11) 134.87,90.57 134.87,91.05 135.2,91.38 135.2,93.16 134.32,94.04 RN1503.3 132.3,94.48 132.05,94.73 130.4,94.73 130.15,94.48 129.08,94.48 128.72,94.84 126.38,94.84 125.78,94.24 125.78,93.48 124.75,92.45 124.75,92.2 122.74,90.19 122.05,90.19 121.15,89.28 121.15,88.72 120.54,88.12 119.9,88.12 119.03,87.24 CPU1.L1 ; PR8260.1 154.49,72.6 153.49,71.59 v2(153.21,71.59) 152.58,70.96 v1(150.65,70.96)
DGPU_PWR_EN#: length 107.9
  TOP w0.102: PQ8307.G 150.11,102 v1(149.82,102.29) ; PQ8305.6 151.96,114.77 152.08,114.66 152.08,114.31 151.89,114.12 PQ8305.5 150.55,114.12 150.4,113.96 v1(150.4,112.82)
  L3 w0.102: v1(151.81,63.8) 153,63.8 155.67,61.12 155.67,58.25 156.73,57.2 156.73,55.7 160.54,51.89 164.99,51.89 166.7,50.18 168.37,50.18 170.85,47.7 170.85,46.61 172.31,45.15 176.82,45.15 181.3,49.63 181.3,51.13 181.31,51.13 v1(182.57,52.39)
  L4 w0.102: v1(150.4,112.82) 150.4,111.9 150.07,111.57 150.07,102.81 149.82,102.55 v1(149.82,102.29) 150.19,101.92 150.19,97.12 151.92,95.39 151.92,94.12 151.1,93.31 151.1,86.16 148,83.06 148,73.78 149.91,71.87 149.91,64.85 150.96,63.8 v1(151.81,63.8)
  BOTTOM w0.102: v2(184.4,50.33) 184.4,50.63 PR8313.2 182.64,52.39 v1(182.57,52.39)
DGPU_PWROK: length 142
  TOP w0.127: R1509.2 EC1501.1 125.92,97.49 125.55,97.12 v2(125.55,96.82) 125.7,96.67 125.7,95.89 125.83,95.76 125.83,95.17 126.22,94.77 v1(126.22,94.06) ; R2437.1 166.85,46.13 167.9,47.19 167.9,48.03 168.73,48.86 v1(168.78,48.86)
  L3 w0.127: v1(168.78,48.86) 167.7,49.94 166.6,49.94 164.89,51.65 160.44,51.65 156.49,55.6 156.49,57.1 155.43,58.15 155.43,61 153.11,63.31 151.66,63.31 151.37,63.61 151.37,64.11 151.46,64.2 151.46,73.65 149.45,75.66 149.45,83.14 152.2,85.88 152.2,88.93 v1(153.27,90) ; v1(150.9,98.24) 150.66,98 150.43,98 149.13,96.7 143.43,96.7 142.8,96.07 136.16,96.07 135.46,95.37 134.55,95.37 133.69,94.51 132.28,94.51 v1(131.34,95.45)
  L4 w0.127: v1(131.34,95.45) 130.68,94.78 128.5,94.78 127.94,95.34 126.82,95.34 126.37,94.9 126.37,94.21 v1(126.22,94.06) 125.58,93.41 124.37,93.41 123.4,92.44 123.4,91.49 123.22,91.31 120.41,91.31 118.34,89.24 118.34,88.93 117.48,88.07 117.02,88.07 v1(115.91,86.96) ; v1(150.9,98.24) 152.73,96.41 152.73,95.83 153.02,95.53 153.02,93.66 153.27,93.41 v1(153.27,90)
  BOTTOM w0.102: v1(115.91,86.96) 115.94,86.93 115.94,85.79 CPU1.R5
  BOTTOM w0.127: D8301.2 180.03,49.31 179.47,48.75 R8312.1 178.38,48.75 R8313.1 177.11,48.75 175.87,47.52 168.51,47.52 168.13,47.89 168.13,48.41 168.59,48.86 v1(168.78,48.86) ; v1(153.27,90) 153.62,89.65 153.62,87.1 PR8203.2 153.74,86.04 153.74,83.61 153.6,83.47 153.6,82.3 153.49,82.19 PU8201.13
DGPU_PWROK_KBC: length 7.3
  TOP w0.127: R2437.2 166.85,42.74 v2(166.52,42.41) 166.33,42.41 164.09,40.17 KBC24.63
DGPU_RXN_C_CPU_TXN0: length 57.8
  L3 w0.114: v1(107.43,102.18) 107.67,102.42 107.67,106.65 108.29,107.27 121.19,107.27 122.46,106 137.69,106 137.8,106.11 147.28,106.11 148.23,107.06 150.96,107.06 v1(151.23,107.33)
  BOTTOM w0.127: v2(154.05,107.63) 154.14,107.54 ; 154.14,107.54 155.92,109.31 156.87,109.31 GPU1.AG7 ; 154.14,107.54 153.69,107.09 151.47,107.09 v1(151.23,107.33) ; C1606.1 107.63,101.65 107.63,101.99 107.45,102.18 v1(107.43,102.18)
DGPU_RXN_C_CPU_TXN1: length 61.6
  L3 w0.114: v1(151.26,109.46) 151.04,109.24 147.72,109.24 145.34,106.86 137.49,106.86 137.38,106.75 122.77,106.75 121.5,108.02 107.98,108.02 107.85,107.88 105.66,105.69 105.66,102.91 v1(105.5,102.76)
  BOTTOM w0.127: C1608.1 105.71,101.51 105.71,102.56 v1(105.5,102.76) ; v1(151.26,109.46) 151.46,109.26 152.21,109.26 152.53,108.94 153.31,108.94 ; 153.31,108.94 154.27,108.94 155.49,110.16 156.7,110.16 156.82,110.29 157.38,110.29 157.59,110.07 158.02,110.07 158.5,109.59 GPU1.AE7 ; 153.31,108.94 v2(153.31,109.07)
DGPU_RXN_C_CPU_TXN2: length 54.2
  L3 w0.114: v1(151.23,110.74) 151.22,110.74 150.81,110.33 147.67,110.33 145.06,107.72 137.29,107.72 137.07,107.5 123.08,107.5 121.46,109.12 116.15,109.12 115.85,109.41 111.07,109.41 110.84,109.19 110.84,108.97 v1(110.51,108.64)
  BOTTOM w0.127: v2(110.43,107.99) 110.56,107.99 ; 110.56,107.99 110.56,108.6 v1(110.51,108.64) ; 110.56,107.99 110.56,106.42 110.71,106.27 110.71,105.93 C1610.1 ; v1(151.23,110.74) 151.62,110.34 151.82,110.34 152.44,110.96 156.79,110.96 156.9,110.85 157.4,110.85 157.6,111.05 157.87,111.05 157.95,111.13 GPU1.AF9
DGPU_RXN_C_CPU_TXN3: length 58.1
  L3 w0.114: v1(151.15,112.57) 150.93,112.34 150.16,112.34 149.37,111.56 147.8,111.56 144.71,108.47 136.08,108.47 135.86,108.25 123.39,108.25 121.77,109.87 116.46,109.87 116.15,110.17 110.18,110.17 109.26,109.26 109.26,108.75 v1(109.17,108.66)
  BOTTOM w0.127: GPU1.AG10 156.87,111.79 152.39,111.79 151.84,112.34 151.38,112.34 v1(151.15,112.57) ; C1612.1 109.4,103.84 109.4,104.29 108.43,105.26 108.43,106.93 108.84,107.33 ; v2(108.75,107.42) 108.84,107.33 ; 108.84,107.33 109.27,107.77 109.27,108.56 v1(109.17,108.66)
DGPU_RXN_CPU_TXN0: length 9.2
  BOTTOM w0.089: CPU1.C23 105.92,92.63 105.92,92.74 105.75,92.92 105.75,93.24 105.99,93.49 105.99,93.94 105.74,94.19 105.74,96.32 106.05,96.63 106.05,96.67 106.07,96.68
  BOTTOM w0.127: 106.07,96.68 106.46,97.08 106.46,98.47 107.21,99.23 ; C1606.2 107.63,99.97 107.63,99.65 107.21,99.23 ; 107.21,99.23 v2(107.12,99.32)
DGPU_RXN_CPU_TXN1: length 7.9
  BOTTOM w0.089: CPU1.B23 105.44,93.32 105.18,93.59 105.18,95.98 105.15,96.01 105.15,96.03
  BOTTOM w0.127: 105.68,99.26 105.68,97.9 105.15,97.37 105.15,96.03 ; 105.68,99.26 v2(105.56,99.26) ; 105.68,99.26 105.68,100.14 C1608.2
DGPU_RXN_CPU_TXN2: length 15.2
  BOTTOM w0.089: CPU1.B21 106.83,92.52 107.13,92.22 107.46,92.22 107.48,92.23 107.57,92.28 107.64,92.35 107.69,92.46 107.69,92.69 107.48,92.9 107.48,93.33 107.71,93.55 107.71,95.39 107.67,95.42 107.67,95.44
  BOTTOM w0.127: C1610.2 110.54,104.39 110.54,101.95 110.72,101.78 110.72,100.39 108.3,97.97 ; 108.3,97.97 108.01,97.68 108.01,96.48 107.67,96.14 107.67,95.44 ; 108.3,97.97 v2(108.21,98.06)
DGPU_RXN_CPU_TXN3: length 11.1
  BOTTOM w0.089: CPU1.B22 106.35,93.15 106.35,95.8 106.59,96.04 106.59,96.08 106.6,96.09
  BOTTOM w0.127: v2(108.51,99.46) 108.6,99.37 ; 108.6,99.37 109.41,100.18 109.41,102.34 C1612.2 ; 108.6,99.37 107.23,98 107.23,96.72 106.6,96.09
DGPU_RXP_C_CPU_TXP0: length 57.3
  L3 w0.114: v1(108.07,102.18) 107.9,102.36 107.9,106.55 108.39,107.04 121.1,107.04 122.37,105.77 137.78,105.77 137.89,105.88 147.37,105.88 148.32,106.83 150.99,106.83 v1(151.23,106.59)
  BOTTOM w0.127: v1(151.23,106.59) 151.49,106.84 152.17,106.84 ; 152.17,106.84 153.79,106.84 156.02,109.07 156.87,109.07 GPU1.AG6 ; 152.17,106.84 v2(152.17,106.72) ; C1605.1 107.87,101.5 107.87,101.98 v1(108.07,102.18)
DGPU_RXP_C_CPU_TXP1: length 61.7
  L3 w0.114: v1(151.27,108.62) 151.36,108.71 151.36,108.89 151.23,109.02 147.82,109.02 145.43,106.63 137.58,106.63 137.47,106.52 122.68,106.52 121.41,107.79 108.07,107.79 105.89,105.6 105.89,102.99 106.01,102.86 v1(106.29,102.86)
  BOTTOM w0.127: v1(106.29,102.86) 106.09,102.86 105.95,102.71 105.95,101.65 C1607.1 ; GPU1.AF7 157.95,109.74 157.86,109.83 157.49,109.83 157.28,110.04 156.93,110.04 156.8,109.92 155.59,109.92 154.94,109.27 ; v1(151.27,108.62) 151.14,108.75 151.14,108.88 151.28,109.01 152.11,109.01 152.43,108.7 154.37,108.7 154.94,109.27 ; 154.94,109.27 v2(155.03,109.18)
DGPU_RXP_C_CPU_TXP2: length 54.3
  L3 w0.114: v1(151.2,110.1) 147.77,110.1 145.16,107.49 137.38,107.49 137.16,107.27 122.99,107.27 121.37,108.89 116.05,108.89 115.76,109.18 111.16,109.18 111.07,109.09 111.07,108.72 v1(111.17,108.62)
  BOTTOM w0.127: C1609.1 110.95,105.76 110.95,106.37 110.8,106.52 110.8,106.87 ; v1(111.17,108.62) 110.8,108.25 110.8,106.87 ; 110.8,106.87 v2(110.92,106.87) ; v1(151.2,110.1) 151.92,110.1 152.54,110.72 156.69,110.72 156.8,110.61 157.5,110.61 157.7,110.81 158.29,110.81 GPU1.AE9
DGPU_RXP_C_CPU_TXP3: length 58.6
  L3 w0.114: v1(151.08,111.55) 151.08,111.94 150.9,112.12 150.25,112.12 149.46,111.33 147.89,111.33 144.8,108.24 136.18,108.24 135.96,108.02 123.3,108.02 121.68,109.64 116.36,109.64 116.06,109.94 110.27,109.94 109.49,109.16 109.49,108.97 v1(109.8,108.66)
  BOTTOM w0.127: GPU1.AG9 156.87,111.55 152.29,111.55 151.74,112.1 151.24,112.1 151.08,111.94 v1(151.08,111.55) ; v2(108.8,105.96) 108.67,105.96 ; 108.67,105.96 108.67,105.36 109.64,104.39 109.64,103.85 C1611.1 ; 108.67,105.96 108.67,106.83 109.51,107.67 109.51,108.37 v1(109.8,108.66)
DGPU_RXP_CPU_TXP0: length 9.8
  BOTTOM w0.089: 106.24,96.51 106.22,96.5 106.18,96.5 105.93,96.24 105.93,94.27 106.17,94.03 106.17,93.41 105.93,93.17 105.93,92.99 106.1,92.82 106.1,92.04 CPU1.C22
  BOTTOM w0.127: 106.7,98.04 106.7,98.37 107.87,99.55 107.87,100.12 C1605.2 ; 106.7,98.04 v2(106.83,98.04) ; 106.7,98.04 106.7,96.98 106.24,96.51
DGPU_RXP_CPU_TXP1: length 7.7
  BOTTOM w0.089: 105.4,96.03 105.4,96.01 105.37,95.98 105.37,93.65 105.45,93.57 105.56,93.57 CPU1.A23
  BOTTOM w0.127: 105.4,96.03 105.4,96.89 ; 105.4,96.89 105.4,97.27 105.92,97.8 105.92,100.05 106.24,100.37 C1607.2 ; 105.4,96.89 v2(105.52,96.89)
DGPU_RXP_CPU_TXP2: length 15.1
  BOTTOM w0.089: CPU1.C21 107,91.96 107.08,92.04 107.5,92.04 107.56,92.07 107.68,92.14 107.73,92.19 107.79,92.24 107.8,92.27 107.87,92.42 107.87,92.77 107.66,92.97 107.66,93.26 107.88,93.48 107.88,95.39 107.92,95.42 107.92,95.44
  BOTTOM w0.127: 110.96,100.84 110.96,101.88 110.79,102.05 110.79,104.23 C1609.2 ; 110.96,100.84 110.96,100.29 108.25,97.58 108.25,96.38 107.92,96.04 107.92,95.44 ; 110.96,100.84 v2(111.08,100.84)
DGPU_RXP_CPU_TXP3: length 10.5
  BOTTOM w0.089: 106.77,95.92 106.76,95.91 106.72,95.91 106.54,95.73 106.54,93.8 CPU1.A21
  BOTTOM w0.127: 106.77,95.92 106.97,96.12 ; 106.97,96.12 107.47,96.62 107.47,97.9 109.65,100.08 109.65,102.32 C1611.2 ; 106.97,96.12 v2(107.06,96.03)
DGPU_TXN_CPU_RXN0: length 7.7
  TOP w0.127: C7302.2 156.39,108.23 156.57,108.23 156.81,108.47 156.81,109.84 158.25,111.28 ; 158.25,111.28 v2(158.16,111.37) ; 158.25,111.28 158.47,111.5 160.55,111.5 v1(160.73,111.68)
  BOTTOM w0.127: GPU1.AB9 161.13,111.27 v1(160.73,111.68)
DGPU_TXN_CPU_RXN1: length 6.8
  TOP w0.127: 156.96,111.26 157.73,112.03 159.83,112.03 159.97,112.17 v1(159.97,112.46) ; 156.96,111.26 155.93,110.23 155.93,110.08 155.83,109.98 155.73,109.98 C7304.2 ; 156.96,111.26 v2(156.87,111.35)
  BOTTOM w0.127: v1(159.97,112.46) 160.22,112.46 160.35,112.33 GPU1.AC10
DGPU_TXN_CPU_RXN2: length 4.6
  TOP w0.127: C7306.2 157.59,113.28 158.06,113.75 158.34,113.75 ; 158.34,113.75 v2(158.34,113.87) ; 158.34,113.75 159.33,113.75 v1(159.94,113.33)
  BOTTOM w0.127: v1(159.94,113.33) 160.35,112.92 GPU1.AC11
DGPU_TXN_CPU_RXN3: length 5.5
  TOP w0.127: v1(160.8,114.14) 160.51,114.44 160.51,114.78 159.99,115.3 158.47,115.3 158.18,115 157.93,115 ; v2(157.93,115.13) 157.93,115 ; 157.93,115 157.21,115 C7308.2
  BOTTOM w0.127: v1(160.8,114.14) 161.19,113.75 GPU1.AB12
DGPU_TXP_CPU_RXP0: length 8
  TOP w0.127: v1(160.78,110.84) 160.84,110.9 160.84,111.1 160.69,111.26 158.57,111.26 157.05,109.74 157.05,108.37 156.67,107.99 156.44,107.99 C7301.2
  BOTTOM w0.127: GPU1.AC9 160.78,110.84 v1(160.78,110.84)
DGPU_TXP_CPU_RXP1: length 7.4
  TOP w0.127: v1(160.78,112.49) 160.63,112.49 159.93,111.79 157.83,111.79 156.34,110.3 ; 156.34,110.3 156.17,110.13 156.17,109.98 155.93,109.74 155.77,109.74 C7303.2 ; 156.34,110.3 v2(156.43,110.21)
  BOTTOM w0.127: GPU1.AB10 161.19,112.08 v1(160.78,112.49)
DGPU_TXP_CPU_RXP2: length 4.6
  TOP w0.127: v2(157.48,112.91) 157.48,113.04 ; 157.48,113.04 157.69,113.04 158.16,113.51 159.1,113.51 159.15,113.45 v1(159.15,113.3) ; 157.48,113.04 157.03,113.04 156.91,112.92 156.91,112.48 156.82,112.39 C7305.2
  BOTTOM w0.127: GPU1.AD11 159.51,112.87 159.3,112.87 159.15,113.02 v1(159.15,113.3)
DGPU_TXP_CPU_RXP3: length 5.3
  TOP w0.127: 159.56,115.06 159.89,115.06 160.26,114.68 160.26,114.44 v1(159.97,114.14) ; 159.56,115.06 v2(159.56,114.93) ; 159.56,115.06 158.57,115.06 158.28,114.76 157.25,114.76 C7307.2
  BOTTOM w0.127: v1(159.97,114.14) 160.22,114.14 160.35,114.01 GPU1.AC12
DIS_1D35V_VGA_S0: length 4.5
  BOTTOM w0.508: PR8315.2 183.97,56.27 PQ8306.D 185.24,57.54 v2(185.24,58.74)
DMIC_CLK: length 101
  TOP w0.14: v1(43.21,7.77) 43.18,7.8 43.18,8.1 C2723.2 42.75,8.53 R2716.1
  L3 w0.127: v1(30.84,85.45) 30.72,85.57 30.35,85.57 30.15,85.37 30.15,76.84 26.16,72.85 26.16,72.15 29.22,69.09 29.22,65.33 33.44,61.11 33.44,57.6 34.45,56.59 34.45,43.34 32.17,41.06 32.17,38.59 v1(32.21,38.55)
  L4 w0.127: v1(32.21,38.55) 32.21,36.85 31.08,35.72 31.08,25.43 32.24,24.27 38.55,24.27 44.72,18.11 44.72,10.23 42.97,8.49 42.97,8.01 v1(43.21,7.77)
  BOTTOM w0.14: v2(43.48,8.32) 43.21,8.05 v1(43.21,7.77) ; RN5204.3 31.79,85.48 30.86,85.48 v1(30.84,85.45) 30.79,85.5 30.31,85.5 EC5206.1 29.92,85.53 28.74,85.53 RN5202.4
DMIC_CLK_C: length 17.8
  TOP w0.14: CCD1.3 17.3,87.95 17.58,87.67 17.58,86.81 17.44,86.67 16.44,86.67 AFTP5222.1 15.95,85.41 17.98,83.38 22.51,83.38 v1(22.8,83.09)
  L4 w0.127: v1(26.75,85.48) 26.61,85.61 26.05,85.61 23.82,83.38 23.09,83.38 v1(22.8,83.09)
  BOTTOM w0.14: RN5202.1 v1(26.75,85.48)
DMIC_CLK_EDP: length 3.9
  TOP w0.14: LCD1.27 33.95,84.65 33.62,84.98 33.62,85.24 v1(33.83,85.46)
  BOTTOM w0.14: v2(34.61,85.16) 34.31,85.46 v1(33.83,85.46) RN5204.2
DMIC_CLK_R: length 3.7
  TOP w0.14: v2(41.39,9.42) 40.93,8.96 R2716.2 40.43,8.53 40.23,8.73 39.89,8.73 39.28,9.34 HDA27.3
DMIC_DATA: length 100.7
  TOP w0.14: v1(42.52,7.77) 42.45,7.69 R2714.1
  L3 w0.127: v1(30.83,86.19) 30.71,86.08 30.14,86.08 29.65,85.58 29.65,77.05 25.65,73.06 25.65,71.94 28.71,68.88 28.71,65.12 32.93,60.9 32.93,57.39 33.94,56.38 33.94,43.55 31.66,41.27 31.66,38.18 v1(31.7,38.14)
  L4 w0.127: v1(31.7,38.14) 31.7,37.05 30.57,35.93 30.57,25.22 32.03,23.76 38.34,23.76 44.21,17.9 44.21,10.44 42.47,8.7 42.47,7.82 v1(42.52,7.77)
  BOTTOM w0.14: RN5202.3 28.77,86.05 30.05,86.05 EC5205.1 30.17,86.07 30.7,86.07 v1(30.83,86.19) 31.02,86 31.7,86 RN5204.4 ; v1(42.52,7.77) 42.52,8.06 v2(42.21,8.37)
DMIC_DATA_C: length 17
  TOP w0.14: v1(22.8,84.17) 22.53,83.9 18.2,83.9 16.47,85.63 16.47,85.96 16.66,86.15 17.83,86.15 AFTP5228.1 18.1,86.42 CCD1.4
  L4 w0.127: v1(26.7,86.26) 26.56,86.12 25.84,86.12 23.6,83.88 23.09,83.88 v1(22.8,84.17)
  BOTTOM w0.14: RN5202.2 26.84,86.13 v1(26.7,86.26)
DMIC_DATA_EDP: length 5.1
  TOP w0.14: v1(33.83,86.23) 33.48,86.23 33.1,85.85 33.1,84.77 33.45,84.41 LCD1.28
  BOTTOM w0.14: RN5204.1 33.71,86.11 v1(33.83,86.23) 34.44,86.23 v2(34.59,86.39)
DMIC_DATA_R: length 3.6
  TOP w0.14: HDA27.2 39.29,8.94 v2(39.93,8.3) 40.54,7.69 R2714.2 EC2701.1
DS3_PWRCTL: length 2.6
  BOTTOM w0.127: R3802.2 133.25,59.48 v2(133.47,59.71) 134.31,59.71 134.49,59.53 U3801.4
DSWODVREN: length 14.3
  BOTTOM w0.089: 117.94,68.13 117.43,68.64 116.84,68.64 116.27,69.21 115.82,69.21 114.99,70.04 114.99,70.79 115.06,70.86 115.06,71.45 CPU1.AW7
  BOTTOM w0.102: 117.94,68.13 118.26,67.81 118.28,67.81 118.54,67.56 118.54,65.38 v2(119.78,64.13) 120.1,63.82 120.1,63.7 121.22,62.57 R1721.1 R1720.1
E51_RX: length 2.1
  BOTTOM w0.14: WLAN1.17 191.13,32.9 TP5802.1
E51_TX: length 33.7
  TOP w0.14: v1(168.27,20.74) 167.74,20.21 R5804.2
  L3 w0.127: v1(186.84,31.96) 186.09,31.21 186.09,28.21 186.32,27.99 186.32,25 186.9,24.41 186.9,23.47 183.73,20.29 179.18,20.29 178.49,19.6 174.5,19.6 173.98,20.12 169.72,20.12 169.52,20.32 168.69,20.32 v1(168.27,20.74)
  BOTTOM w0.14: v1(168.27,20.74) 168.27,21.1 168.53,21.35 v2(168.53,21.35) ; WLAN1.19 186.98,32.1 v1(186.84,31.96)
E51_TXD: length 2.9
  TOP w0.102: KBC24.111 169.29,21.35 169.53,21.11 v2(169.53,20.39) 169.45,20.39 169.1,20.04 R5804.1
EAPD#: length 6.2
  TOP w0.102: R2708.2 41.35,4.33 40.28,4.33 39.77,4.84 v2(39.77,4.96) 39.77,5 39.35,5.42 39.19,5.42 38.68,5.93 38.68,6.03 37.43,7.27 HDA27.47
EC_AGND: length 16.5
  TOP w0.203: KBC24.103 166.09,21.4 166.16,21.33 166.16,21.29 166.49,20.96 166.49,20.77 166.65,20.62 R2435.2
  TOP w0.508: R2407.2 C2403.1 160.88,22.17 162.06,20.99 v1(163.23,20.99) 163.23,20.27 C2414.1 ; 165.95,18.03 165.05,18.03 C2405.2 164.12,17.88 v1(163.99,18) ; 165.95,18.03 C2404.2 ; 165.95,18.03 165.95,18.63 C2402.1 R2406.2 166.64,19.72 R2435.2
  BOTTOM w0.508: v1(163.99,18) 163.99,18.56 v2(164.56,19.13) 164.45,19.13 163.23,20.35 v1(163.23,20.99)
EC_BRIGHTNESS: length 251.7
  TOP w0.14: v1(40.17,40.21) 39.9,39.93 39.58,39.93 v2(39.58,39.93) ; KBC24.32 177.64,36.52 177.39,36.77 176.98,36.77 176.8,36.58 173.51,36.58 172.46,35.53 168.34,35.53 v1(168.32,35.51)
  L3 w0.127: v1(44.55,76.83) 44.14,77.24 44.14,77.49 42.15,79.48 36.47,79.48 35.19,78.21 35.19,77.24 36.84,75.59 36.84,72.79 33.95,69.9 33.95,66.01 35.13,64.83 35.13,59.98 36.35,58.75 36.35,55.84 37,55.19 37,47.73 40.17,44.56 v1(40.17,40.21)
  L4 w0.127: v1(40.17,40.21) 40.17,39.57 40.53,39.21 40.53,35.32 39.12,33.91 39.12,29.63 40.53,28.22 40.53,28.05 52.03,16.55 57.63,16.55 58.51,17.43 66.9,17.43 69.48,14.85 72.53,14.85 77.79,9.59 77.79,9.04 79.72,7.11 104.4,7.11 107.65,10.36 108.83,10.36 110.19,10.36 110.45,10.1 111.14,10.1 112.28,8.96 112.83,8.96 113.61,8.18 120.46,8.18 122.05,9.77 126.8,9.77 127.79,10.76 137.14,10.76 138.52,9.38 142.82,9.38 143.27,9.84 158.45,9.84 159.94,8.34 161.75,8.34 165.41,12.01 170.59,12.01 172,13.42 172,16.76 169.4,19.35 169.4,21.72 167.56,23.56 167.56,26.03 168.32,26.79 v1(168.32,35.51)
  BOTTOM w0.14: v1(44.55,76.83) 44.32,77.06 D5202.2
EC_SCI#: length 142.5
  TOP w0.102: R2408.2 184.32,38.42 v1(185.55,37.2)
  L3 w0.102: v1(126.6,78) 129.83,78 130.65,78.83 131.61,78.83 132.3,78.14 132.3,71.04 133.42,69.92 133.42,68.9 134.06,68.27 135.14,68.27 136.73,66.68 136.73,56.82 134.47,54.56 134.47,51.36 144.68,41.14 144.68,39.32 144.68,39.15 146.97,36.86 146.97,34.22 148.45,32.74 148.45,31.1 153.26,26.28 153.26,25.69 153.51,25.44 153.96,25.44 156.6,22.8 158.08,22.8 158.31,23.03 162.67,23.03 163.46,22.24 167.6,22.24 167.67,22.31 172.08,22.31 172.75,21.63 184.21,21.63 186.39,23.81 186.39,24.34 185.9,24.82 185.9,27.81 185.67,28.04 185.67,31.41 187.2,32.94 187.2,33.57 187.04,33.72 187.04,36.16 186.01,37.2 v1(185.55,37.2)
  BOTTOM w0.089: CPU1.AM2 118.53,75.72 119.17,75.72 119.31,75.58 120.86,75.58 120.94,75.5 121.96,75.5 121.98,75.48 122.52,75.48 122.96,75.92 123.96,75.92 123.96,75.92
  BOTTOM w0.102: RN1809.6 131.1,80.46 131.09,80.47 127.09,80.47 126.26,79.64 v2(126.26,79.2) 126.26,78.39 126.6,78.05 v1(126.6,78) 126.6,76.88 125.64,75.92 123.96,75.92
EC_SMI#: length 136
  TOP w0.102: RN1902.3 123.44,90.03 123.26,89.86 122.98,89.86 122.73,89.6 122.73,88.29 121.73,87.29 121.73,86.86 121.21,86.34 121.21,85.17 120.11,84.07 v1(120.11,83.69) ; R2409.2 v2(183.31,26.52) 184,26.52 184.48,27 184.48,27.25 v1(184.99,27.75)
  L3 w0.102: v1(184.99,27.75) 185.7,27.04 185.7,24.74 185.72,24.72 185.72,23.77 184.02,22.06 172.61,22.06 172.17,22.51 167.58,22.51 167.51,22.44 163.55,22.44 162.75,23.23 158.22,23.23 157.99,23 156.68,23 154.12,25.56 154.12,26.05 153.42,26.76 153.07,26.76 148.65,31.18 148.65,32.82 147.17,34.3 147.17,36.95 144.89,39.23 144.89,41.23 134.85,51.27 134.85,54.65 136.93,56.73 136.93,66.77 132.5,71.19 132.5,78.22 131.7,79.03 128.47,79.03 126.61,80.89 126.61,82.12 125.51,83.21 124.37,83.21 124.1,83.48 124.1,86.48 123.26,87.32 122.63,87.32 122.4,87.09 122.4,85.95 122.17,85.72 121.99,85.72 120.11,83.84 v1(120.11,83.69)
  BOTTOM w0.102: CPU1.V1 119.15,83.5 119.36,83.71 120.09,83.71 v1(120.11,83.69)
EC_SPI_CLK_C: length 4.5
  TOP w0.14: R2420.2 159.35,24.12 v2(159.79,24.12) 160.17,24.12 161.35,25.3 KBC24.92
EC_SPI_CS#_C: length 4.4
  TOP w0.14: KBC24.90 160.87,26.1 v2(160.46,25.7) 159.97,25.2 159.55,25.2 158.52,24.17 R2419.2
EC_SPI_DI_C: length 4.8
  TOP w0.14: KBC24.87 160.36,27.3 160.04,26.97 159.77,26.71 v2(159.76,26.71) 159.76,26.31 R2422.2
EC_SPI_DO_C: length 4.6
  TOP w0.14: KBC24.86 161.43,27.7 161.41,27.72 v2(160.57,27.72) 160.18,27.72 159.2,26.74 159.2,26.39 158.77,25.96 R2423.2
EC_SWI#: length 104.6
  L3 w0.102: v1(131.49,73.84) 131.56,73.84 132.1,73.3 132.1,70.89 133.17,69.82 133.17,68.78 133.93,68.01 135.11,68.01 136.52,66.6 136.52,56.9 134.19,54.57 134.19,51.2 144.48,40.91 144.48,39.4 144.48,39.4 144.48,39.06 146.76,36.78 146.76,34.14 148.24,32.65 148.24,31.35 148.24,31 153.03,26.22 153.03,25.62 153.46,25.19 153.87,25.19 156.54,22.52 158.27,22.52 158.52,22.78 162.64,22.78 163.38,22.03 167.68,22.03 167.75,22.1 170.28,22.1 171.38,21.01 v1(171.48,21.01)
  L4 w0.102: v1(131.49,73.84) 130.76,73.11 130.76,72.36 129.66,71.26 127.05,71.26 126.69,70.91 126.69,70.43 126.06,69.79 120.99,69.79 118.43,72.36 118.43,75.1 v1(117.9,75.63)
  BOTTOM w0.102: R2410.2 171.5,21.96 v2(171.4,21.86) 171.3,21.76 171.3,21.19 v1(171.48,21.01) ; v1(131.49,73.84) 131.66,73.84 132.45,73.04 RN2012.8 ; v1(117.9,75.63) 117.59,75.93 CPU1.AM3
EC_VBKUP: length 4
  TOP w0.203: v1(170.09,24.21) 170.09,24.16 170.55,23.7 170.55,23.3 170.49,23.24 KBC24.114
  BOTTOM w0.254: R2428.1 169.43,24.91 170.23,24.91 v2(170.33,24.81) 170.33,24.5 170.09,24.26 v1(170.09,24.21)
EC_VTT: length 4.8
  TOP w0.203: KBC24.12 179.91,28.1
  TOP w0.508: R2401.2 181.25,29.85 C2401.1 180.87,29.03 180.28,28.44 v2(180.26,28.44) 179.91,28.1
ECRST#: length 9.2
  TOP w0.102: KBC24.85 161.6,28.1 161.58,28.12 160.02,28.12 158.71,26.81 C2418.1 R2418.1 157.42,27.15 157.42,27.27 156.99,27.7 R2424.2 156.92,28.42 v2(156.74,28.6) 155.86,28.6 155.55,28.29 Q2404.E
ECSCI#_KBC: length 6.4
  TOP w0.102: KBC24.29 178.84,34.9 179.73,35.78 v2(179.73,36.14) 179.73,36.14 182.02,38.42 R2408.1
ECSMI#_KBC: length 4.2
  TOP w0.102: R2409.1 180.47,26.52 v2(179.96,26) 179.32,25.37 178.91,25.37 178.58,25.7 KBC24.6
ECSWI#_KBC: length 3.3
  TOP w0.102: v1(174.12,23.39) 174.12,23.19 174.09,23.16 174.09,22.15 KBC24.123
  BOTTOM w0.102: v1(174.12,23.39) 174.29,23.22 174.29,22.88 v2(174.01,22.6) 173.38,21.96 R2410.1
EDP_AUX: length 5.8
  TOP w0.127: 41.79,81.62 41.79,82.8 41.95,82.95 LCD1.11 ; 41.79,81.62 41.79,81.08 42.42,80.45 42.42,78.66 C5212.2 ; 41.79,81.62 AFTP5206.1
EDP_AUX#: length 5.8
  TOP w0.127: 42.18,79.71 42.18,78.68 C5209.2 ; 42.18,79.71 AFTP5208.1 ; 42.18,79.71 42.18,80.35 41.55,80.98 41.55,82.85 41.45,82.95 LCD1.12
EDP_AUX_DN: length 67.8
  TOP w0.127: v1(41.97,75.98) 42.18,75.98 42.26,76.07 42.26,77.03 C5209.1
  L4 w0.114: v1(87.51,99.28) 87.51,99.4 87.43,99.47 86.73,99.47 85.84,98.58 85.84,98.16 84.75,97.06 80.02,97.06 79.85,96.89 76.17,96.89 75.91,97.15 74.25,97.15 71.68,94.58 70.64,94.58 65.64,89.58 64.06,89.58 61.83,87.35 61.08,87.35 48.58,74.85 42.81,74.85 42.44,75.21 42.44,75.63 42.09,75.98 v1(41.97,75.98)
  BOTTOM w0.127: 91.23,97.36 88.95,99.64 87.85,99.64 87.51,99.3 v1(87.51,99.28) ; 91.23,97.36 v2(91.14,97.27) ; 91.23,97.36 91.76,96.83 91.76,93.83 CPU1.A45
EDP_AUX_DP: length 67.9
  TOP w0.127: v1(42.72,75.98) 42.51,76.2 42.51,77.23 C5212.1
  L4 w0.114: v1(87.49,99.91) 87.28,99.7 86.64,99.7 85.61,98.68 85.61,98.25 84.65,97.29 79.93,97.29 79.76,97.12 76.26,97.12 76.01,97.38 74.15,97.38 71.59,94.81 70.55,94.81 65.55,89.81 63.97,89.81 61.74,87.58 60.98,87.58 48.48,75.07 42.91,75.07 42.67,75.31 42.67,75.93 v1(42.72,75.98)
  BOTTOM w0.127: 89.93,99 89.05,99.88 87.52,99.88 v1(87.49,99.91) ; 89.93,99 92,96.93 92,93.53 91.64,93.17 CPU1.B45 ; 89.93,99 v2(90.04,99.1)
EDP_BKLT_CTRL: length 6.7
  BOTTOM w0.14: R5222.2 41.09,80.01 44.28,80.01 D5202.1 44.32,80.81 v2(44.88,81.37) 45.62,81.37 45.83,81.16 R5206.2
EDP_BRIGHTNESS: length 1.6
  TOP w0.14: TP801.1 93.14,94.56 v1(92.81,94.23)
  BOTTOM w0.14: v1(92.81,94.23) 93.02,94.01 CPU1.A43
EDP_COMP: length 3.1
  TOP w0.508: v1(108.08,91.46) 107.61,91.93 107.13,91.93 v2(107.12,91.93) 106.63,91.93 106.23,92.33 R801.2
  BOTTOM w0.305: CPU1.D20 v1(108.08,91.46)
EDP_HPD: length 114.5
  TOP w0.102: v1(46.55,75.73) 46.55,76.32 R5233.2 46.12,76.17 RN5203.6
  L3 w0.102: v1(46.55,75.73) 47.3,76.48 47.3,83.62 49.56,85.89 v1(49.56,86.34)
  L4 w0.102: v1(122.15,101.73) 122.25,101.63 122.25,100.75 120.91,99.41 117.47,99.41 116.97,98.91 115.39,98.91 114.57,99.73 111.2,99.73 111.03,99.56 108.95,99.56 107.78,99.56 107.77,99.57 102.65,99.57 102.37,99.29 100.46,99.29 99.58,98.42 94.9,98.42 94.05,99.27 90.3,99.27 88.61,100.95 87.63,100.95 85.72,102.86 85.04,102.86 84.71,102.53 84.17,102.53 83.18,103.52 78.71,103.52 78.31,103.12 78.31,102.65 77.68,102.02 72.49,102.02 69.17,98.7 67.66,98.7 60.61,91.65 54.06,91.65 50.37,87.97 50.37,86.76 49.95,86.34 v1(49.56,86.34)
  BOTTOM w0.102: CPU1.D6 115.75,91.93 116,92.18 116.21,92.18 116.47,92.44 116.47,92.57 116.65,92.75 117.09,92.75 117.29,92.95 117.29,93.41 117.35,93.47 117.35,93.88 117.79,94.32 118.08,94.32 118.38,94.63 119.22,94.63 120.5,95.91 120.5,98.34 121.06,98.89 121.5,98.89 v2(121.87,99.26) 122.39,99.77 122.39,101.49 v1(122.15,101.73)
EDP_HPD_CONN: length 8.1
  TOP w0.102: LCD1.9 42.95,82.46 AFTP5201.1 43.84,81.24 44.6,80.49 44.6,78.25 45.5,77.35 R5233.1
EDP_SPARE: length 3.9
  TOP w0.102: TP605.1 93.2,95.42 v1(93.24,95.38)
  BOTTOM w0.102: v1(93.24,95.38) 93.23,95.38 92.4,94.56 92.4,93.82 93.02,93.2 CPU1.B43
EDP_TX0: length 6
  TOP w0.127: LCD1.15 39.95,83.02 40.08,82.89 40.08,82.56 39.61,82.09 39.61,80.78 40.26,80.13 40.26,79.71 ; 40.26,79.71 AFTP5210.1 ; 40.26,79.71 40.26,78.62 C5210.2
EDP_TX0#: length 6.1
  TOP w0.127: C5203.2 40.5,78.61 40.5,80.23 39.85,80.88 39.85,81.62 ; LCD1.14 40.45,83.04 40.32,82.91 40.32,82.46 39.85,81.99 39.85,81.62 ; AFTP5213.1 39.85,81.62
EDP_TX0_DN: length 68.1
  TOP w0.127: v1(40.67,75.57) 40.53,75.71 40.53,77.12 C5203.1
  L4 w0.114: v1(40.67,75.57) 40.49,75.39 40.49,74.88 40.7,74.67 41.83,74.67 42.18,74.32 48.79,74.32 49.23,74.76 60.09,85.63 62.42,85.63 64.76,87.97 66.06,87.97 71.24,93.15 72.29,93.15 74.36,95.22 75.44,95.22 76.59,96.36 81.06,96.36 81.24,96.54 84.96,96.54 86.48,98.06 87.39,98.06 v1(87.56,98.23)
  BOTTOM w0.127: 88.19,98.18 87.61,98.18 v1(87.56,98.23) ; 88.19,98.18 v2(88.19,98.34) ; 88.19,98.18 88.32,98.18 91.11,95.39 91.11,94.23 91.34,94 91.34,92.92 91.64,92.61 CPU1.C45
EDP_TX0_DP: length 67.9
  TOP w0.127: C5210.1 40.29,77.05 40.29,75.8 v1(40.02,75.53)
  L4 w0.114: v1(87.56,97.6) 87.56,97.64 87.37,97.83 86.58,97.83 85.06,96.32 81.33,96.32 81.15,96.13 76.68,96.13 75.54,94.99 74.45,94.99 72.38,92.92 71.33,92.92 66.15,87.74 64.85,87.74 62.51,85.4 60.19,85.4 49.46,74.67 48.89,74.1 42.08,74.1 41.74,74.44 40.61,74.44 40.26,74.79 40.26,75.39 40.12,75.53 v1(40.02,75.53)
  BOTTOM w0.127: 89.23,96.92 90.87,95.29 90.87,94.13 91.1,93.9 91.1,92.76 CPU1.B46 ; 89.23,96.92 v2(89.13,96.82) ; 89.23,96.92 88.22,97.94 87.9,97.94 v1(87.56,97.6)
EDP_TX1: length 6.1
  TOP w0.127: 38.33,81.62 38.33,82 38.58,82.25 38.58,82.82 38.45,82.95 LCD1.18 ; 38.33,81.62 AFTP5212.1 ; 38.33,81.62 38.33,80.97 37.78,80.42 37.78,79.25 38.13,78.9 38.13,78.55 C5213.2
EDP_TX1#: length 6.1
  TOP w0.127: LCD1.17 38.95,82.95 38.82,82.82 38.82,82.15 38.57,81.9 38.57,80.87 38.02,80.32 38.02,79.71 ; 38.02,79.71 38.02,79.35 38.38,79 38.38,78.57 C5211.2 ; 38.02,79.71 AFTP5211.1
EDP_TX1_DN: length 66.9
  TOP w0.127: v1(38.93,75.39) 38.85,75.39 38.52,75.72 38.52,76.22 ; C5211.1 38.52,77.16 38.52,76.22 ; 38.52,76.22 v2(38.65,76.22)
  L4 w0.114: v1(38.93,75.39) 38.71,75.39 38.58,75.26 38.58,75 39.8,73.78 41.23,73.78 41.5,73.78 41.71,73.58 49.1,73.58 49.98,74.45 60.22,84.7 60.51,84.7 60.51,84.7 63.86,84.7 70.32,91.16 72.21,91.16 75.48,94.43 75.72,94.43 76.9,95.61 81.37,95.61 81.55,95.79 85.27,95.79 85.97,96.49 87.46,96.49 87.57,96.6 v1(87.57,96.72)
  BOTTOM w0.127: v1(87.57,96.72) 87.57,96.54 87.67,96.44 88.17,96.44 89.97,94.64 89.97,94.04 90.32,93.7 90.5,93.7 CPU1.A47
EDP_TX1_DP: length 67
  TOP w0.127: C5213.1 38.28,76.89 38.28,75.54 v1(38.18,75.43)
  L4 w0.114: v1(38.18,75.43) 38.36,75.26 38.36,74.91 39.71,73.55 41.33,73.55 41.41,73.55 41.61,73.35 49.2,73.35 50.21,74.36 60.32,84.47 60.41,84.47 63.95,84.47 70.42,90.93 72.3,90.93 75.57,94.2 75.81,94.2 76.99,95.38 81.46,95.38 81.65,95.57 85.37,95.57 86.07,96.27 87.3,96.27 v1(87.52,96.05)
  BOTTOM w0.127: v1(87.52,96.05) 87.68,96.2 88.07,96.2 88.6,95.67 ; 88.6,95.67 89.73,94.54 89.73,93.94 90.52,93.15 CPU1.B47 ; 88.6,95.67 v2(88.52,95.58)
EDP_VDD_EN: length 94.3
  TOP w0.127: v1(103.88,94.28) 103.88,95.44 v2(104.52,96.07) 105.13,96.69 v3(105.13,98.23) ; D5201.1 53.36,72.82 v1(54,72.82) ; v1(102.95,84.55) 98.73,80.33 89.33,80.33 88.31,79.32 84.12,79.32 83.45,79.99 77.35,79.99 75.85,78.49 71.21,78.49 70.38,77.65 v1(64.97,77.65)
  L4 w0.127: v1(116.8,94.58) 113,94.58 112.36,93.94 110.6,93.94 110.59,93.95 110.08,93.95 105.8,98.23 v3(105.13,98.23) ; v1(103.88,94.28) 103.94,94.22 104.96,94.22 107.08,92.1 108.37,92.1 108.99,91.48 108.99,89.79 109.7,89.08 109.7,88.56 108.97,87.83 107.95,87.83 105.81,85.7 105.02,85.7 103.87,84.55 v1(102.95,84.55)
  BOTTOM w0.127: v1(116.8,94.58) 116.37,94.15 115.95,94.15 115.66,93.86 115.66,93.5 115.37,93.2 115.37,92.83 115.12,92.58 CPU1.C6 ; v1(54,72.82) 56.17,72.82 61,77.65 v1(64.97,77.65)
FAN1_DAC_1: length 244.9
  TOP w0.203: KBC24.101 165.29,23.12 165.3,23.13 165.3,23.34 v1(165.31,23.35)
  L3 w0.254: v1(33.22,92.14) 31.1,90.03 26.47,90.03 26.05,89.6 26.05,83.46 26.67,82.83 26.67,74.71 25.21,73.24 25.21,71.71 28.27,68.65 28.27,64.94 32.49,60.71 32.49,57.02 33.23,56.27 33.23,50.56 32.99,50.31 32.99,45.89 33.16,45.72 33.16,43.5 30.22,40.57 30.22,37.46 30.61,37.07 32.08,37.07 33.03,38.02 33.03,38.69 33.74,39.4 35.02,39.4 39.02,35.4 39.02,31.07 42.44,27.65 43.62,27.65 50.58,20.69 58.46,20.69 v1(58.76,20.4)
  L4 w0.254: v1(58.76,20.4) 58.85,20.4 60.99,18.26 66.78,18.26 69.69,15.34 72.73,15.34 78.29,9.79 78.29,9.31 79.57,8.03 79.99,8.03 104.3,8.03 107.38,11.11 110.5,11.11 110.76,10.85 111.41,10.85 111.73,10.53 115.59,10.53 115.64,10.58 115.69,10.58 116.33,11.22 119.68,11.22 120.88,12.42 137.77,12.42 139.06,11.13 140.91,11.13 142.71,12.93 150.42,12.93 151.37,11.98 158.56,11.98 159.34,12.76 170.64,12.76 171.43,13.55 171.43,16.59 167.49,20.54 167.49,21.22 165.32,23.39 165.31,23.38 v1(165.31,23.35)
  BOTTOM w0.254: v2(164.69,23.4) 165.28,23.4 165.31,23.37 v1(165.31,23.35) ; v1(33.22,92.14) 33.86,91.51 34.49,91.51
FAN_TACH1: length 280.9
  TOP w0.203: 176.29,35.95 176.54,35.7 KBC24.31 178.65,35.7 178.88,35.93
  TOP w0.254: 178.88,35.93 178.88,36.51 179.91,37.53 v2(179.91,38.37) 179.91,39.26 R2415.1 ; 176.29,35.95 176.17,36.07 174.41,36.07 v1(174.13,35.79)
  L3 w0.254: v1(41.09,95.71) 38.56,93.18 33.4,93.18 30.75,90.53 26.26,90.53 25.52,89.8 25.52,83.26 26.16,82.62 26.16,74.92 24.7,73.45 24.7,71.5 27.76,68.44 27.76,64.73 31.86,60.62 31.86,59.84 31.15,59.13 31.15,57.63 32.73,56.06 32.73,50.77 32.48,50.52 32.48,45.49 32.65,45.32 32.65,43.71 29.72,40.78 29.72,37.25 30.4,36.56 33.99,36.56 34.49,37.06 36.64,37.06 38.51,35.19 38.51,30.86 42.23,27.14 42.65,27.14 42.65,27.14 43.41,27.14 50.37,20.18 58.24,20.18 62.61,15.82 62.83,15.82 v1(62.84,15.81)
  L4 w0.254: v1(62.84,15.81) 62.85,15.82 63.94,15.82 66.53,13.24 71.05,13.24 78.79,5.5 105.07,5.5 108.32,8.74 109.5,8.74 109.76,8.48 110.47,8.48 110.96,8 110.96,7.59 111.97,6.57 125.15,6.57 125.65,7.06 126.39,7.06 127.02,7.69 132.98,7.69 133.32,7.36 143.61,7.36 144.48,8.22 147.91,8.22 147.91,8.22 148.65,8.22 148.65,8.22 152.53,8.22 154.36,6.39 154.78,6.39 164.54,6.39 167.66,9.52 170.88,9.52 174.65,13.28 174.65,20.36 174.42,20.58 174.42,22.31 173.56,23.17 173.56,25.94 171.42,28.08 171.42,32.92 174.13,35.63 v1(174.13,35.79)
  BOTTOM w0.254: EC2602.1 R2606.1 v1(41.09,95.71)
FAN_TACH1_C: length 17.2
  TOP w0.254: AFTP2802.1 51.1,90.91 44.56,90.91 v1(44.02,90.37)
  BOTTOM w0.254: v1(44.02,90.37) 44,90.38 FAN1.3 44.95,91.43 45.29,91.76 45.29,93.79 44.78,94.3 42.36,94.3 41.54,93.48 R2606.2
FAN_VCC1: length 20.8
  TOP w0.305: AFTP2801.1 50.37,91.51 42.75,91.51 v1(42.05,92.21)
  BOTTOM w0.508: FAN1.1 42.89,93.43 42.17,92.71 42.17,92.7 42.06,92.59 42.06,92.22 v1(42.05,92.21) EC2601.1
  BOTTOM w0.559: EC2601.1 C2603.1 39.23,92.21 C2604.1
  BOTTOM w0.635: C2604.1 38.91,91.89 D2601.K 36.62,91.89 35.74,92.78 34.49,92.78
FB_CAL_PD_VDDQ: length 4.5
  TOP w0.508: v1(176.57,122.38) 176.74,122.21 176.81,122.21 177.49,121.53 v2(178.3,121.53) 179.24,121.53 179.48,121.77 R7505.1
  BOTTOM w0.356: GPU1.D22 176.5,122.34 176.53,122.34 v1(176.57,122.38)
FB_CAL_PU_GND: length 5
  TOP w0.508: v1(177.34,124.07) 177.8,123.61 177.8,122.47 178.08,122.19 178.98,122.19 v2(179.18,122.39) 179.45,122.66 R7507.2
  BOTTOM w0.305: v1(177.34,124.07) 177.34,124.06 177.34,124.03 177,123.69 GPU1.C24
FB_CAL_TERM_GND: length 7.6
  TOP w0.508: R7506.1 181.07,128.61 180.94,128.49 v1(180.94,128.48) 181.15,128.27 v2(181.72,128.27)
  BOTTOM w0.127: 179.18,126.99 178.99,126.81 178.99,126.36 179.18,126.17 179.18,126.09 179.16,126.07 179.16,125.47 179.08,125.39 179.08,125.28 178.68,124.87 178.39,124.87 178.01,124.49 GPU1.B25
  BOTTOM w0.508: v1(180.94,128.48) 180.94,128.42 180.58,128.06 180.24,128.06 179.18,126.99
FB_CLAM: length 19.1
  TOP w0.254: v1(185.92,106.95) 185.39,106.95 184.33,105.89 183.26,105.89 183.1,106.06 180.14,106.06 179.62,105.53 179.1,105.53 177.26,107.37 175.39,107.37 174.73,106.71 v1(174.06,106.71)
  BOTTOM w0.254: R7519.1 189.48,108.13 R7518.1 188.26,108.12 v2(187.53,107.39) 187.21,107.06 186.04,107.06 v1(185.92,106.95) ; v1(174.06,106.71) 174.08,106.69 174.08,106.66 GPU1.F3
FB_CLAMP_MON_S: length 4.8
  BOTTOM w0.254: v2(195.02,109.9) 194.99,109.87 R7650.1 194.59,108.56 Q7603.6 192.82,108.56 192.71,108.67 192.71,109.03 192.89,109.21 Q7603.5
FB_VREF: length 1.2
  TOP w0.102: v1(175.68,122.44) 176.07,122.84 TP7503.1
  BOTTOM w0.102: v1(175.68,122.44) 175.75,122.44 175.77,122.46 175.77,122.46 GPU1.D23
FBA_CLK0N: length 57.1
  TOP w0.14: v2(176.78,124.59) 176.55,124.36 v1(176.55,124.08) ; VRAM1.K7 178.52,141.59 179.33,142.4 179.33,142.98 v1(179.18,143.12) ; R7810.1 179.14,150.33 179.14,149.52 v1(178.94,149.32)
  L4 w0.127: v1(176.55,124.08) 176.48,124.02 176.48,123.78 176.56,123.7 176.73,123.7 176.92,123.51 177.53,123.51 178,123.04 178,122.56 177.75,122.31 177.31,122.31 177.25,122.24 177.25,121.08 177.01,120.84 176.52,120.84 176.4,120.72 176.4,120.29 176.48,120.2 176.98,120.2 177.21,119.98 177.21,118.81 176.74,118.33 176.74,118.13 177.06,117.8 177.65,117.8 177.77,117.92 177.77,121.56 178.03,121.82 178.46,121.82 179.07,121.21 179.39,121.21 179.55,121.38 179.55,122.04 179.45,122.14 179.15,122.14 178.94,122.35 178.94,123.38 181,125.44 181.33,125.44 181.94,126.05 181.94,126.74 181.7,126.99 181.7,128.04 181.94,128.29 181.94,132.61 181.82,132.73 181.46,132.73 181.21,132.98 181.21,134.04 178.7,136.56 178.7,138.55 177.97,139.28 177.97,141.59 178.23,141.85 178.74,141.85 179.4,142.51 179.4,143.03 179.31,143.12 v1(179.18,143.12) 179.18,143.47 178.88,143.77 178.88,144.66 178.01,145.53 178.01,147.01 179.13,148.13 179.13,149.13 v1(178.94,149.32)
  BOTTOM w0.14: v1(176.55,124.08) 176.15,124.48 GPU1.D25 ; v1(179.18,143.12) 179.18,143.41 178.87,143.73 178.87,144.16 178.64,144.39 178.64,144.63 178.48,144.79 VRAM2.K7
FBA_CLK0P: length 57.2
  TOP w0.14: v1(176.55,123.28) 177.17,123.28 v2(177.25,123.21) ; v1(179.63,149.34) 179.38,149.59 179.38,150.4 R7810.2 ; VRAM1.J7 179.08,141.65 179.08,141.81 179.6,142.33 179.6,142.93 179.66,143 179.66,143.25 v1(179.78,143.36)
  L4 w0.127: v1(179.63,149.34) 179.36,149.08 179.36,148.03 178.24,146.91 178.24,145.62 179.11,144.75 179.11,143.86 179.44,143.54 179.6,143.54 v1(179.78,143.36) 179.63,143.21 179.63,142.41 178.83,141.62 178.33,141.62 178.2,141.49 178.2,139.38 178.93,138.64 178.93,136.65 181.44,134.14 181.44,133.08 181.56,132.96 181.92,132.96 182.17,132.71 182.17,128.2 181.92,127.95 181.92,127.08 182.17,126.83 182.17,125.96 181.42,125.21 181.09,125.21 179.17,123.28 179.17,122.45 179.25,122.37 179.54,122.37 179.78,122.13 179.78,121.28 179.48,120.99 178.98,120.99 178.37,121.6 178.13,121.6 178,121.47 178,117.83 177.75,117.58 176.97,117.58 176.51,118.04 176.51,118.43 176.98,118.9 176.98,119.88 176.89,119.98 176.39,119.98 176.17,120.19 176.17,120.81 176.42,121.07 176.91,121.07 177.02,121.17 177.02,122.34 177.22,122.54 177.66,122.54 177.77,122.65 177.77,122.95 177.44,123.28 v1(176.55,123.28)
  BOTTOM w0.14: v1(179.78,143.36) 179.58,143.36 179.11,143.83 179.11,144.26 178.88,144.49 178.88,144.66 179.01,144.79 VRAM2.J7 ; v1(176.55,123.28) 176.15,123.69 GPU1.D24
FBA_CLK1N: length 62.2
  TOP w0.14: v1(157.22,143.55) 157.2,143.52 156.99,143.52 156.72,143.8 156.72,143.93 156.81,144.03 156.95,144.03 157.18,144.26 157.18,144.69 157.28,144.79 VRAM4.K7
  L4 w0.127: v1(169.05,122.48) 168.95,122.58 168.95,123.27 169.25,123.57 169.25,123.87 168.95,124.17 168.95,125.42 168.7,125.67 168.25,125.67 168.1,125.52 167.67,125.52 167.54,125.65 167.17,125.65 166.77,125.25 166.77,124.66 166.69,124.57 166.12,124.57 165.89,124.34 165.89,123.74 165.81,123.66 165.52,123.66 165.36,123.82 165.36,125.38 164.09,126.65 164.09,126.83 164.34,127.08 164.52,127.08 165.8,125.8 165.89,125.71 166,125.6 166.37,125.6 166.77,125.99 166.77,126.35 166.29,126.84 166.29,127.27 165.8,127.76 165.29,127.76 165.14,127.91 165.14,128.41 164.75,128.8 164.33,128.8 161.69,131.44 161.38,131.44 161.28,131.34 161.1,131.34 160.87,131.57 160.87,131.75 160.95,131.83 160.95,132.17 160.6,132.53 160.25,132.53 160.13,132.41 160.02,132.41 159.75,132.68 159.75,132.79 159.86,132.9 159.86,133.26 159.59,133.53 159.5,133.62 159.18,133.62 159.08,133.52 158.88,133.52 158.7,133.7 158.7,133.9 158.86,134.06 158.86,134.63 158.59,134.9 158.21,134.9 158.09,135.02 158.09,135.33 158.2,135.44 158.63,135.44 158.86,135.67 158.86,136.17 158.6,136.43 158.26,136.43 158.08,136.61 158.08,136.96 158.25,137.13 158.25,137.46 158.07,137.63 158.07,137.87 158.26,138.05 158.41,138.05 159.03,137.43 159.4,137.43 159.72,137.76 159.72,138.13 159.23,138.62 159.23,138.78 159.6,139.15 159.6,139.85 159.22,140.23 158.85,140.23 158.61,139.99 158.43,139.99 158.28,140.14 158.28,140.42 159.13,141.27 159.13,141.64 158.81,141.95 158.45,141.95 157.93,141.44 157.57,141.44 157.39,141.61 157.39,141.76 157.58,141.95 157.58,142.24 157.08,142.74 157.08,143.14 157.22,143.28 v1(157.22,143.55) 157.1,143.55 156.99,143.66 156.99,144.18 158.29,145.48 158.29,146.37 156.8,147.85 156.8,148.55 156.97,148.72 v1(157.09,148.72)
  BOTTOM w0.14: VRAM3.K7 157.31,141.72 157.31,142.26 157.04,142.53 157.04,143.06 157.22,143.25 v1(157.22,143.55) ; v1(169.05,122.48) 169.48,122.05 GPU1.M22 ; v2(156.97,150.52) 156.84,150.52 ; 156.84,150.52 156.84,148.98 v1(157.09,148.72) ; 156.84,150.52 156.84,151.11 R7914.1
FBA_CLK1P: length 62.1
  TOP w0.14: v1(156.62,143.29) 156.63,143.29 156.63,143.55 156.48,143.7 156.48,144.03 156.71,144.27 156.84,144.27 156.92,144.34 156.92,144.72 156.83,144.81 156.66,144.81 VRAM4.J7
  L4 w0.127: v1(156.4,148.73) 156.58,148.55 156.58,147.76 158.06,146.28 158.06,145.57 156.76,144.27 156.76,143.43 v1(156.62,143.29) 156.63,143.29 156.85,143.06 156.85,142.65 157.35,142.15 157.35,142.04 157.16,141.86 157.16,141.52 157.47,141.21 158.03,141.21 158.54,141.72 158.72,141.72 158.9,141.54 158.9,141.36 158.06,140.52 158.06,140.05 158.34,139.76 158.71,139.76 158.94,140 159.13,140 159.37,139.76 159.37,139.24 159,138.87 159,138.53 159.49,138.03 159.49,137.85 159.3,137.66 159.12,137.66 158.5,138.28 158.16,138.28 157.84,137.96 157.84,137.54 158.02,137.36 158.02,137.22 157.85,137.06 157.85,136.51 158.16,136.2 158.51,136.2 158.63,136.07 158.63,135.76 158.54,135.66 158.11,135.66 157.86,135.42 157.86,134.93 158.12,134.67 158.5,134.67 158.64,134.53 158.64,134.16 158.47,133.99 158.47,133.61 158.79,133.29 159.17,133.29 159.27,133.39 159.41,133.39 159.43,133.37 159.63,133.17 159.63,132.99 159.53,132.89 159.53,132.59 159.93,132.18 160.23,132.18 160.34,132.3 160.5,132.3 160.72,132.08 160.72,131.92 160.64,131.84 160.64,131.47 161.01,131.11 161.38,131.11 161.48,131.21 161.6,131.21 164.23,128.57 164.66,128.57 164.91,128.31 164.91,127.81 165.2,127.53 165.71,127.53 166.06,127.18 166.06,126.74 166.54,126.26 166.54,126.09 166.28,125.83 166.1,125.83 166.05,125.87 164.62,127.31 164.43,127.31 164.34,127.31 164.25,127.31 163.86,126.93 163.86,126.56 165.13,125.28 165.13,123.73 165.43,123.43 165.91,123.43 166.12,123.65 166.12,124.25 166.21,124.34 166.78,124.34 167,124.56 167,125.16 167.26,125.42 167.45,125.42 167.58,125.29 168.2,125.29 168.35,125.44 168.61,125.44 168.72,125.33 168.72,124.07 169.02,123.77 169.02,123.66 168.72,123.36 168.72,122.77 168.43,122.48 v1(168.32,122.48)
  BOTTOM w0.14: R7914.2 156.6,151.11 156.6,149.38 ; 156.6,149.38 156.6,148.93 v1(156.4,148.73) ; 156.6,149.38 v2(156.46,149.38) ; v1(168.32,122.48) 168.32,122.42 GPU1.N22 ; VRAM3.J7 156.66,141.57 156.93,141.57 157.07,141.71 157.07,142.16 156.79,142.43 156.79,143.08 156.63,143.25 156.63,143.29 v1(156.62,143.29)
FBA_CMD0: length 45.6
  TOP w0.14: v1(176.78,142.92) 177.48,143.62 177.48,144.24 177.89,144.65 177.89,144.93 177.54,145.28 VRAM1.L2
  TOP w0.178: v2(176.43,126) 176.43,126.39 v1(176.59,126.56)
  L4 w0.165: v1(176.78,142.92) 176.9,142.92 177.13,142.68 177.13,142.36 176.71,141.93 175.68,141.93 175.55,141.81 175.55,140.36 175.91,140 176.53,140 176.79,139.74 176.79,138.71 177.42,138.08 177.42,137.72 176.8,137.1 176.8,135.64 178.66,133.77 178.66,133.61 178.41,133.37 178.41,132.78 178.58,132.62 178.86,132.62 179,132.76 179.29,132.76 179.6,132.45 179.6,132.12 179.43,131.96 178.58,131.96 178.41,131.79 178.41,131.46 178.58,131.3 179.43,131.3 179.6,131.13 179.6,130.8 179.43,130.64 178.58,130.64 178.41,130.47 178.41,130.14 178.58,129.98 179.43,129.98 179.6,129.81 179.6,129.48 179.43,129.32 178.58,129.32 178.41,129.15 178.41,128.87 178.2,128.66 178.2,127.68 178.69,127.19 178.69,124.66 178.54,124.51 178.34,124.51 177.78,125.07 177.78,126.63 177.98,126.83 177.98,127.1 177.65,127.44 177.3,127.44 177.16,127.29 177.16,126.32 176.84,126 176.84,125.78 177.16,125.46 177.16,125.22 177.03,125.09 176.53,125.09 176.05,125.58 176.05,126.25 176.35,126.56 v1(176.59,126.56)
  BOTTOM w0.14: v1(176.78,142.92) 176.88,142.82 176.88,142.15 177.11,141.92 177.11,140.53 177.2,140.43 177.41,140.43 177.54,140.56 VRAM2.L2
  BOTTOM w0.178: v1(176.59,126.56) 176.95,126.2 GPU1.C27
FBA_CMD1: length 4.6
  TOP w0.178: v1(179.03,127.97) 179.03,127.97 TP7501.1
  BOTTOM w0.152: GPU1.C26 177.36,125.7 177.36,126.84 178.37,127.86 178.92,127.86 v1(179.03,127.97)
FBA_CMD2: length 57
  TOP w0.14: VRAM1.K1 178.34,146.8 178.22,146.92 178.05,146.92 177.89,146.77 177.89,145.47 178.22,145.14 178.48,145.14 178.76,144.86 178.76,144.09 178.65,143.98 v1(178.44,143.98)
  TOP w0.178: v2(177.98,149.5) 177.97,149.5 v1(177.58,149.89)
  L4 w0.165: v1(177.58,149.89) 177.58,149.27 177.66,149.18 177.66,145.23 178.44,144.46 v1(178.44,143.98) 178.22,143.76 177.96,143.76 177.83,143.63 177.83,143.07 178,142.9 178.24,142.9 178.4,142.73 178.4,142.35 178.3,142.25 178.06,142.25 177.57,141.76 177.57,141.42 177.41,141.25 177.07,141.25 176.91,141.09 176.91,140.76 177.07,140.59 177.41,140.59 177.57,140.43 177.57,138.97 178.28,138.26 178.28,137.13 178.15,137 177.74,137 177.63,136.9 177.63,136.43 177.74,136.33 177.74,136.03 178.69,135.07 178.88,135.07 179.05,135.24 179.23,135.24 179.52,134.95 179.52,134.77 179.34,134.59 179.34,134.42 179.64,134.13 179.81,134.13 179.98,134.3 180.16,134.3 180.45,134.01 180.45,133.83 180.1,133.48 180.1,133.28 180.6,132.78 180.6,132.19 180.77,132.03 181.26,132.03 181.38,131.9 181.38,131.49 181.26,131.37 180.66,131.37 180.55,131.25 180.55,130.43 180.66,130.31 181.24,130.31 181.37,130.18 181.37,129.78 181.24,129.65 180.67,129.65 180.55,129.52 180.55,129.04 180.67,128.91 181.58,128.91 181.69,128.8 181.69,128.39 181.31,128.01 181.31,127.02 181.69,126.64 181.69,126.16 181.23,125.69 180.9,125.69 180.58,126.01 180.15,126.01 179.99,125.85 179.99,125.7 180.38,125.32 180.38,125.16 179.9,124.69 179.37,124.69 179.23,124.55 179.23,124.08 178.69,123.55 178.69,123.38 178.56,123.24 178.16,123.24 177.78,123.62 177.78,124.25 177.48,124.55 176.1,124.55 175.99,124.44 175.99,124.04 176.17,123.85 176.17,123.51 175.97,123.3 175.77,123.3 v1(175.73,123.35)
  BOTTOM w0.14: v1(178.44,143.98) 178.38,143.98 177.91,143.51 177.91,143.15 178.09,142.96 178.09,142.02 177.97,141.9 177.97,140.36 VRAM2.K1
  BOTTOM w0.178: R7511.1 177.74,150.61 177.74,150.05 v1(177.58,149.89) ; GPU1.E24 175.3,124.02 175.4,124.12 175.65,124.12 175.75,124.02 175.75,123.37 v1(175.73,123.35)
FBA_CMD3: length 59.3
  TOP w0.14: v1(177.67,142.47) 177.53,142.61 177.53,142.85 177.69,143.01 177.97,143.01 178.15,142.83 178.15,141.96 177.99,141.79 177.99,140.55 178.34,140.2 VRAM1.K9
  TOP w0.178: v1(176.97,150.08) v2(176.97,150.65)
  L4 w0.165: v1(174.85,124.06) 174.85,123.87 175.01,123.71 175.47,123.71 175.72,123.96 175.72,124.28 175.48,124.53 175.27,124.53 175.1,124.69 175.1,124.86 175.56,125.32 175.92,125.32 176.42,124.82 177.14,124.82 177.26,124.94 177.49,124.94 178.05,124.38 178.05,123.86 178.17,123.74 178.51,123.74 178.96,124.19 178.96,124.79 179.12,124.96 179.68,124.96 179.85,125.12 179.85,125.45 179.68,125.62 179.12,125.62 178.96,125.78 178.96,126.21 179.09,126.34 180.91,126.34 181.04,126.47 181.04,126.81 180.91,126.93 179.13,126.93 178.96,127.1 178.96,127.41 178.48,127.88 178.48,128.56 178.79,128.87 179.35,128.87 179.47,128.74 179.47,127.58 179.6,127.45 180.91,127.45 181.04,127.58 181.04,127.93 180.94,128.04 180.19,128.04 180.08,128.15 180.08,132.64 179.46,133.26 179.46,133.64 177.27,135.83 177.27,137.05 177.79,137.57 177.79,138.24 177.16,138.87 177.16,139.9 176.68,140.37 176.25,140.37 176.04,140.59 176.04,141.32 176.26,141.54 176.84,141.54 177.67,142.37 v1(177.67,142.47) 177.67,142.66 177.45,142.87 177.45,143.97 177.19,144.23 177.19,148.94 176.97,149.16 v1(176.97,150.08)
  BOTTOM w0.14: v1(177.67,142.47) 177.67,142.9 177.6,142.97 177.6,144.02 177.96,144.39 177.96,145.76 178.34,146.13 VRAM2.K9
  BOTTOM w0.178: v1(176.97,150.08) 177.07,150.08 177.25,150.26 177.25,150.51 R7510.1 ; v1(174.85,124.06) 174.61,124.06 174.45,123.91 GPU1.F24
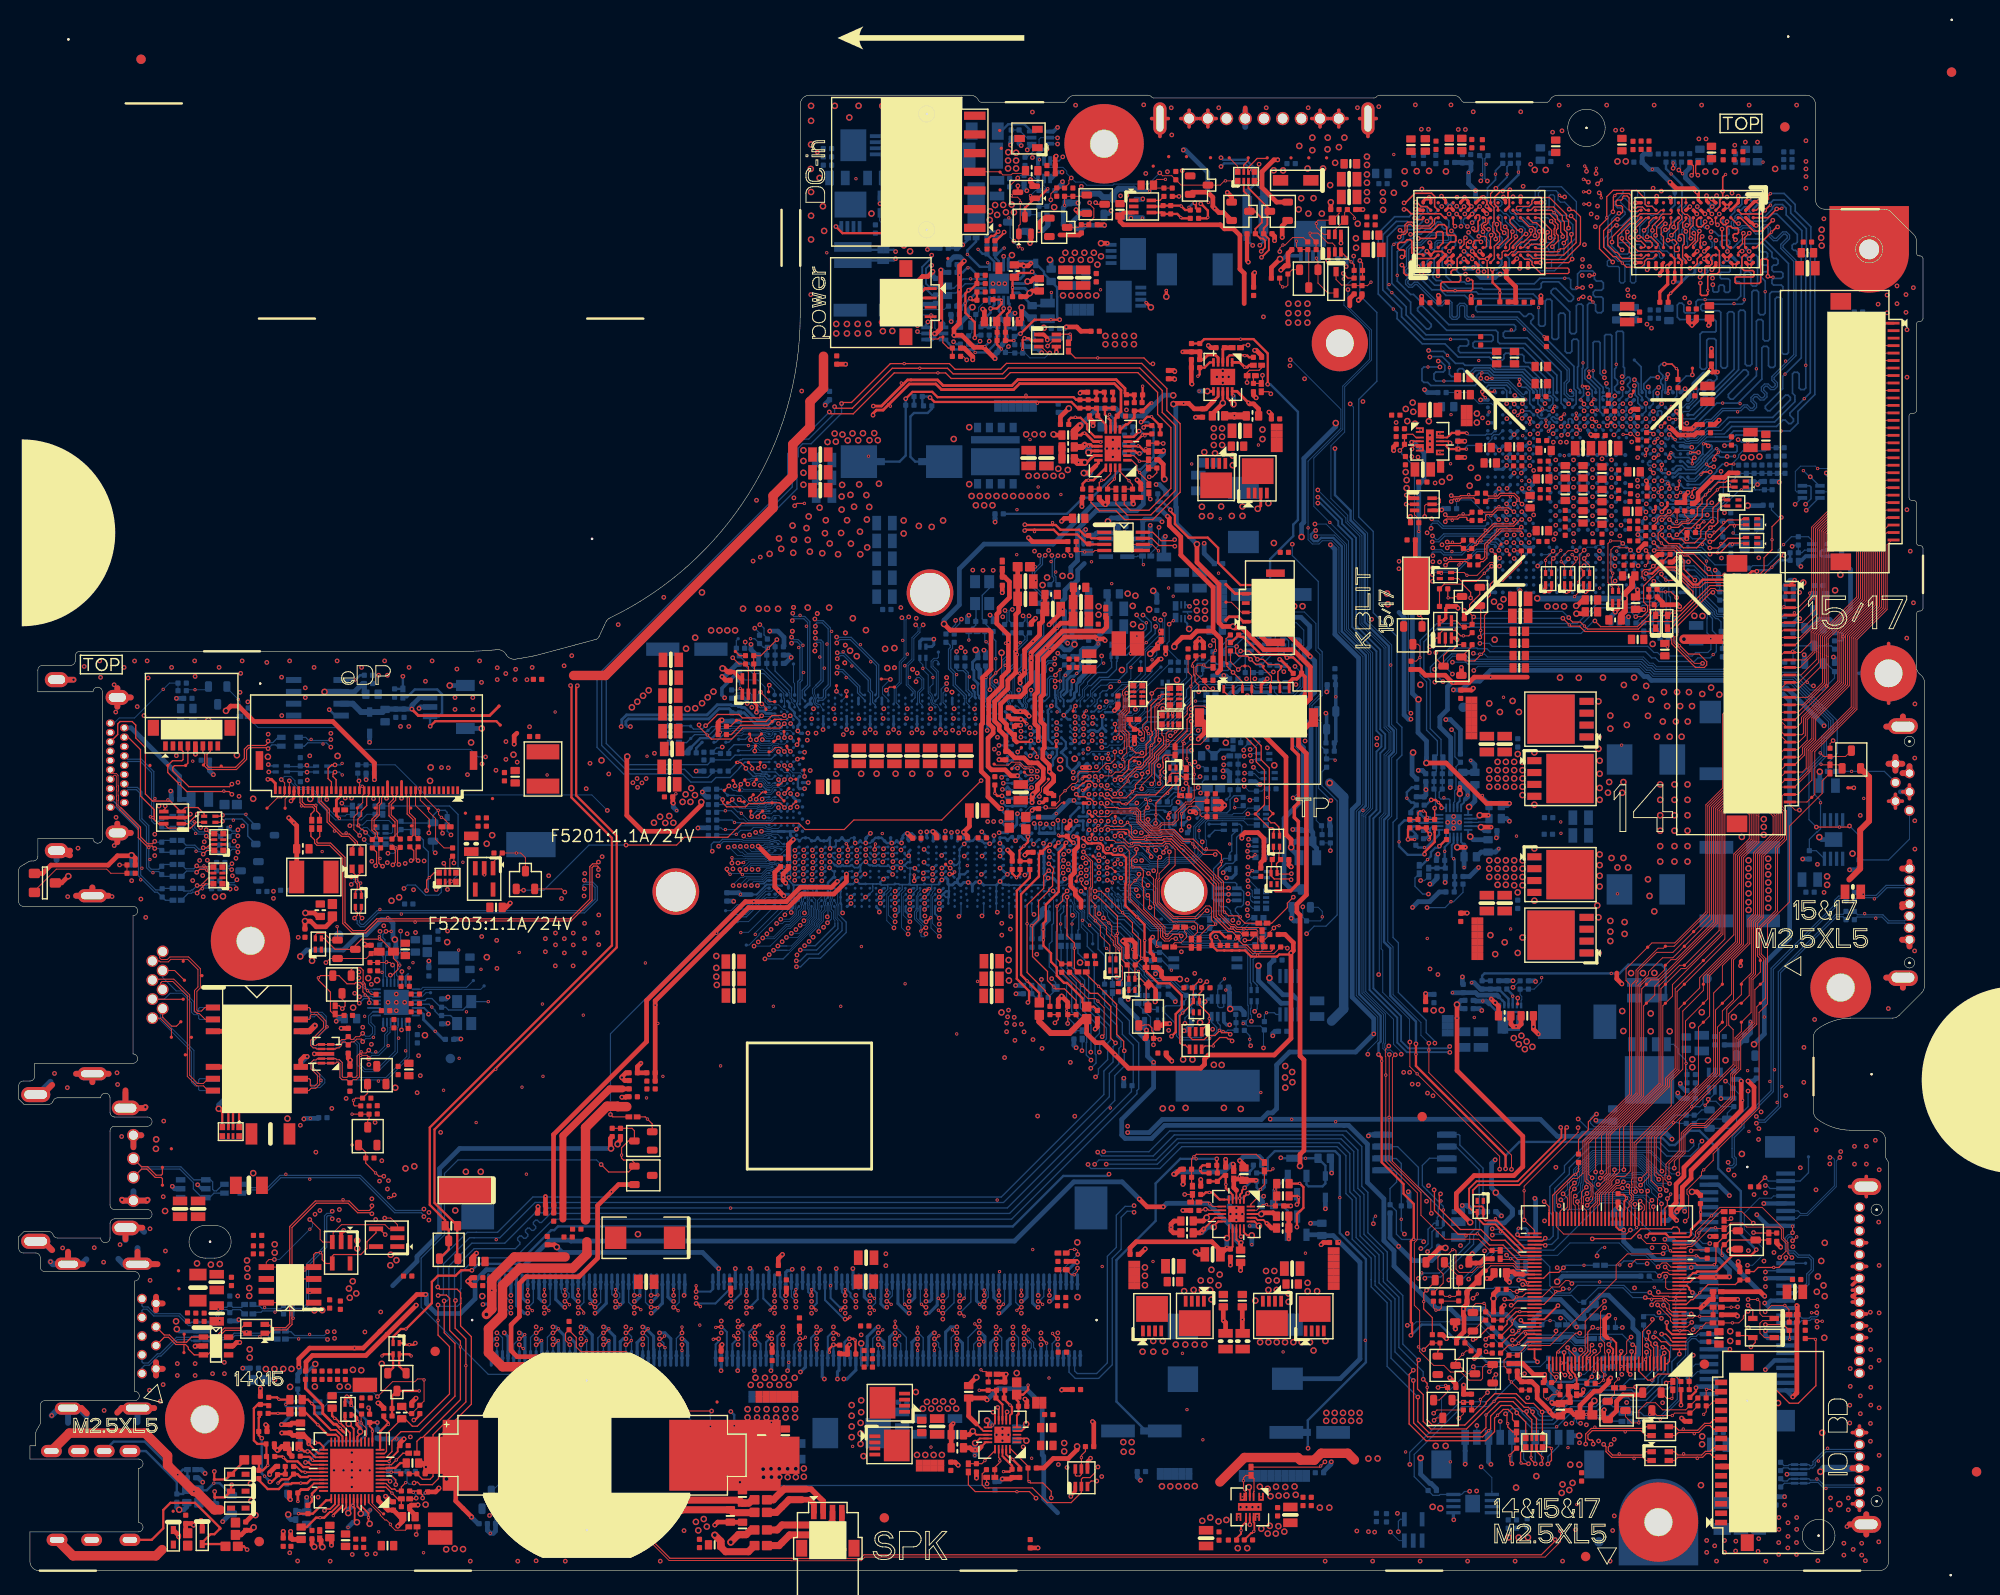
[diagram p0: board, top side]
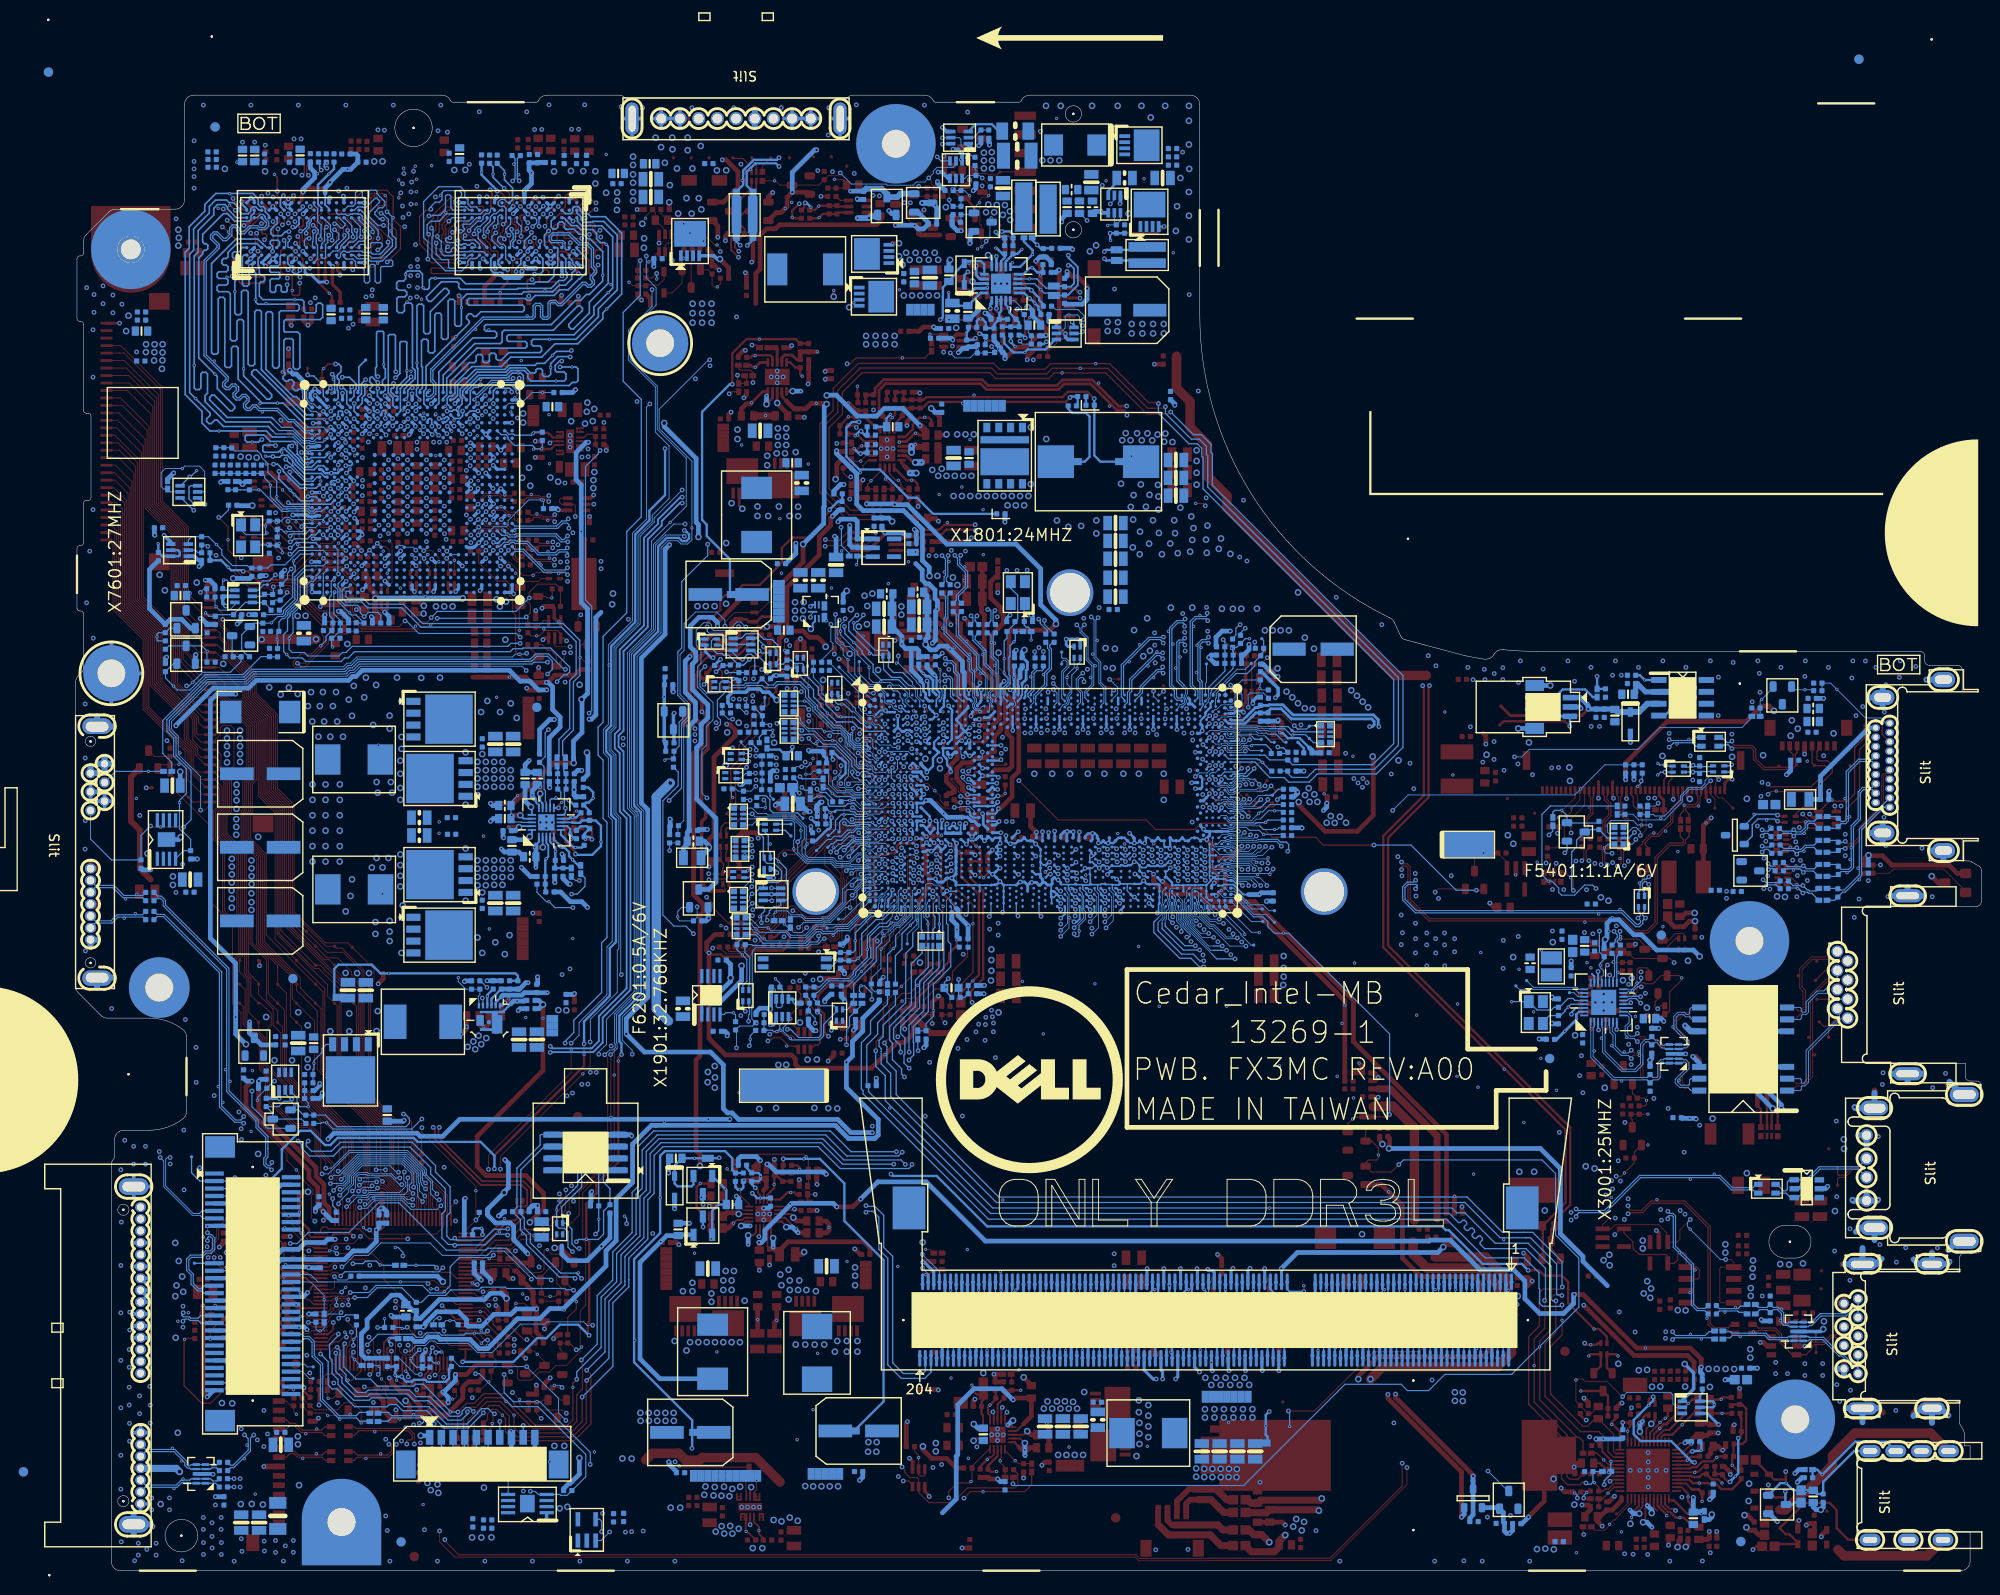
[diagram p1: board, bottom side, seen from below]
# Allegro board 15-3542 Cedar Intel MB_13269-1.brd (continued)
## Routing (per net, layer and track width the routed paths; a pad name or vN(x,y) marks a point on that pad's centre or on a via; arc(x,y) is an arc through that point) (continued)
FBA_CMD4: length 52.2
  TOP w0.14: v1(163.81,142.64) 163.97,142.8 163.97,143.43 162.61,144.79 VRAM4.T7 ; v1(172.39,142.66) 172.71,142.66 173.09,142.28 173.54,142.28 173.98,141.83 173.98,141.72 173.85,141.59 VRAM1.T7
  TOP w0.178: v2(176.26,127.49) 176.4,127.63 v1(176.4,128.03)
  L3 w0.127: v1(163.81,142.64) 163.96,142.79 163.96,143.79 163.51,144.24 163.51,144.62 163.78,144.89 164.31,144.89 165.69,146.27 166.03,146.27 166.53,145.77 168.41,145.77 168.68,146.03 v1(168.88,146.03) 169.09,146.03 169.18,145.94 171.24,145.94 172,145.18 172,143.98 172.49,143.49 172.49,142.77 v1(172.39,142.66)
  L4 w0.165: v1(176.4,128.03) 176.99,128.63 176.99,133.44 175.39,135.05 175.39,136.62 173.38,138.62 173.38,141.99 172.84,142.54 172.84,142.87 172.52,143.19 172.52,144.66 170.77,146.42 169.1,146.42 168.88,146.19 v1(168.88,146.03)
  BOTTOM w0.14: VRAM3.T7 162.31,141.59 162.38,141.53 162.79,141.53 163.4,142.13 164.13,142.13 164.27,142.27 164.27,142.51 164.13,142.64 v1(163.81,142.64) ; v1(172.39,142.66) 172.39,142.98 172.5,143.09 172.5,143.51 173.54,144.55 VRAM2.T7
  BOTTOM w0.178: GPU1.D27 176.15,126.37 176.15,126.37 176.15,127.78 v1(176.4,128.03)
FBA_CMD5: length 65.5
  TOP w0.14: v1(171.18,145.26) 171.43,145.26 171.56,145.39 171.56,145.94 171.42,146.08 170.99,146.08 170.85,146.22 170.85,146.53 170.99,146.67 171.42,146.67 171.56,146.81 171.56,146.99 171.69,147.12 172.04,147.12 172.25,146.91 172.25,145.66 172.45,145.46 173.2,145.46 173.33,145.59 VRAM1.T2 ; VRAM4.T2 165.26,140.79 166.59,142.12 166.59,144.43 166.33,144.7 166.05,144.97 v1(166.05,144.98)
  TOP w0.178: v1(176.04,129.13) 176.84,129.13 v2(177.32,128.64) 177.49,128.47 R7512.1
  L3 w0.127: v1(166.05,144.98) 166.05,144.76 166.65,144.16 168.17,144.16 v1(168.83,144.82) 170.61,144.82 171.05,145.26 v1(171.18,145.26)
  L4 w0.165: v1(176.04,129.13) 176.05,129.15 176.05,133.05 174.45,134.66 174.45,136.51 172.07,138.89 172.07,140.47 172.55,140.95 172.55,141.28 172.44,141.4 172.17,141.4 172.03,141.53 172.03,141.72 171.82,141.93 171.5,141.93 171.29,141.72 171.05,141.72 170.89,141.88 170.89,142.23 171.05,142.39 171.05,142.77 170.91,142.91 170.72,142.91 170.54,142.73 170.36,142.73 170.18,142.91 170.18,143.48 169.72,143.93 169.72,144.16 169.98,144.42 169.98,144.6 169.45,145.13 168.99,145.13 168.83,144.97 v1(168.83,144.82)
  BOTTOM w0.14: VRAM2.T2 173.49,140.74 172.42,140.74 172.16,140.48 171.21,140.48 169.95,141.74 169.95,142.39 170.38,142.82 170.38,144.59 171.05,145.26 v1(171.18,145.26) ; VRAM3.T2 163.45,145.59 163.7,145.84 163.7,147.08 163.85,147.24 164.14,147.24 164.28,147.09 164.28,145.64 164.87,145.05 165.66,145.05 165.73,144.98 v1(166.05,144.98)
  BOTTOM w0.178: v1(176.04,129.13) 175.7,129.13 175.46,128.88 175.46,128.33 175.87,127.92 175.87,127.64 175.76,127.53 175.76,127.53 175.65,127.42 175.65,127.09 175.87,126.87 175.87,126.36 175.77,126.26 175.77,125.46 175.94,125.29 GPU1.D26
FBA_CMD6: length 56.6
  TOP w0.14: v1(172.96,143.37) 172.96,143.72 174.03,144.79 VRAM1.R3 ; v1(163.54,143.23) 163.54,143.13 163.38,142.96 163.38,142.16 163.12,141.9 162.75,141.9 162.69,141.96 161.81,141.96 VRAM4.R3
  TOP w0.178: v2(167.42,146.24) 167.42,146.24 v1(167.98,146.24)
  L3 w0.127: v1(172.96,143.37) 172.96,143.49 172.33,144.12 172.33,145.32 171.38,146.27 169.88,146.27 169.49,146.66 168.83,146.66 168.41,146.24 v1(167.98,146.24) 166.52,146.24 166.17,146.6 165.53,146.6 164.15,145.22 163.65,145.22 163.18,144.75 163.18,144.11 163.54,143.74 v1(163.54,143.23)
  L4 w0.165: v1(175.42,126.64) 175.62,126.64 177.46,128.48 177.46,133.64 175.86,135.25 175.86,136.78 173.75,138.88 173.75,142.15 173.71,142.19 173.71,142.96 173.42,143.25 173.42,144.28 170.92,146.78 168.53,146.78 168.12,146.38 168.12,146.38 v1(167.98,146.24)
  BOTTOM w0.14: VRAM3.R3 161.79,144.44 163.03,144.44 163.28,144.2 163.28,143.88 163.15,143.75 163.15,143.43 163.35,143.23 v1(163.54,143.23) ; VRAM2.R3 174.22,141.59 173.54,142.27 173.1,142.27 172.83,142.54 172.83,142.88 172.96,143.01 v1(172.96,143.37)
  BOTTOM w0.178: v1(175.42,126.64) 175.26,126.64 174.84,126.21 174.84,124.88 GPU1.F25
FBA_CMD7: length 70
  TOP w0.14: VRAM4.R2 161.62,140.79 161.99,140.42 162.39,140.42 162.41,140.44 163.12,140.44 163.23,140.32 165.42,140.32 167.03,141.94 167.03,142.09 167.06,142.11 167.06,144.89 166.37,145.58 166.08,145.58 165.98,145.69 v1(165.85,145.69) ; VRAM1.R2 174.03,145.59 173.68,145.94 173.15,145.94 173.05,145.84 172.72,145.84 172.5,146.06 172.5,147.14 172.26,147.38 170.95,147.38 v2(170.73,147.16) 170.57,147 170.57,145.47 v1(170.53,145.43)
  L3 w0.127: v1(170.53,145.43) 168.44,145.43 v1(168.2,145.19) 168.11,145.19 168.01,145.09 166.61,145.09 166.01,145.69 v1(165.85,145.69)
  L4 w0.165: v1(168.2,145.19) 168.51,145.5 169.13,145.5 169.3,145.67 169.3,145.9 169.44,146.04 169.85,146.04 169.98,145.91 169.98,145.12 170.39,144.71 170.39,143.83 170.91,143.31 171.4,143.31 171.95,142.76 171.95,142.34 172.1,142.19 172.53,142.19 172.92,141.8 172.92,140.59 172.44,140.11 172.44,139.04 174.92,136.56 174.92,134.86 176.52,133.25 176.52,128.8 175.44,127.72 v1(175.32,127.72)
  BOTTOM w0.14: VRAM3.R2 161.72,145.59 162.1,145.97 163.06,145.97 163.36,146.27 163.36,146.62 163.1,146.88 162.8,146.88 162.56,147.12 162.56,147.44 162.8,147.69 164.43,147.69 164.66,147.46 164.66,146.71 164.92,146.45 165.37,146.45 165.85,145.97 v1(165.85,145.69) ; v1(170.53,145.43) 170,144.89 170,142.96 169.59,142.54 169.59,141.62 171.07,140.14 172.3,140.14 172.56,140.4 173.7,140.4 174.09,140.79 VRAM2.R2
  BOTTOM w0.178: v1(175.32,127.72) 174.55,127.72 173.83,126.99 173.83,126.5 174.07,126.25 174.07,125.67 GPU1.F26
FBA_CMD8: length 59.6
  TOP w0.14: v1(162.65,143.33) 162.64,143.32 162.64,142.71 162.37,142.44 161.77,142.44 160.92,141.59 VRAM4.P3 ; VRAM1.P3 174.86,144.79 174.38,144.31 174.38,143.95 v1(173.86,143.44)
  TOP w0.178: v1(169.06,147.45) 169.28,147.23 v2(169.28,146.92)
  L3 w0.127: v1(162.65,143.33) 162.52,143.46 162.52,143.72 162.52,143.72 162.52,145.03 164.95,147.46 166.24,147.46 166.62,147.08 168.28,147.08 168.64,147.44 169.05,147.44 v1(169.06,147.45) 169.08,147.44 169.94,147.44 170.44,146.93 171.66,146.93 172.99,145.59 172.99,144.42 173.86,143.55 v1(173.86,143.44)
  L4 w0.165: v1(169.06,147.45) 169.08,147.44 170.79,147.44 174.31,143.91 174.31,143.25 174.63,142.93 174.63,138.69 176.33,137 176.33,135.44 177.93,133.83 177.93,128.52 175.74,126.32 175.74,125.82 175.51,125.59 175.45,125.59 174.41,124.55 174.41,123.77 v1(174.89,123.29)
  BOTTOM w0.14: VRAM3.P3 160.95,144.79 161.64,144.1 162.33,144.1 162.42,144.01 162.42,143.79 162.29,143.67 162.29,143.46 162.42,143.33 v1(162.65,143.33) ; v1(173.86,143.44) 173.76,143.33 173.76,142.53 174.11,142.18 174.55,142.18 VRAM2.P3
  BOTTOM w0.178: GPU1.F23 174.49,122.89 174.88,123.29 v1(174.89,123.29)
FBA_CMD9: length 63
  TOP w0.14: VRAM4.N3 159.84,141.8 161.08,143.04 v1(161.24,143.04) ; v1(175.09,142.89) 175.2,143.01 175.2,143.81 175.94,144.55 VRAM1.N3
  TOP w0.178: v1(167.91,148.6) 167.81,148.6 167.51,148.9 v2(167.37,148.9)
  L3 w0.127: v1(175.09,142.89) 175.17,142.97 175.17,143.84 174.09,144.92 174.09,146.82 172.99,147.92 171.22,147.92 170.19,148.96 168.7,148.96 168.34,148.6 v1(167.91,148.6) 164.69,148.6 163.57,147.48 162.34,147.48 161.87,147.01 161.87,146.16 161.26,145.55 161.26,143.07 v1(161.24,143.04)
  L4 w0.127: v1(174.13,122.45) 173.27,123.31 173.27,126.56 174.11,127.4 174.11,128.66 174.16,128.7 174.16,129.34
  L4 w0.165: v1(167.91,148.6) 167.68,148.6 166.73,147.64 166.73,145.53 166.99,145.27 166.99,144.23 168.26,142.96 168.69,142.53 168.69,141.66 169.96,140.39 169.96,140.05 169.96,138.6 170.9,137.66 170.9,136.2 172.57,134.54 172.57,133.88 172.77,133.68 172.77,132.81 174.16,131.42 174.16,129.34
  BOTTOM w0.14: VRAM2.N3 175.83,141.7 175.83,141.88 175.09,142.62 v1(175.09,142.89) ; v1(161.24,143.04) 161.14,143.14 161.14,143.56 160.85,143.85 160.57,143.85 159.84,144.58 VRAM3.N3
  BOTTOM w0.178: v1(174.13,122.45) 174.05,122.45 GPU1.G22
FBA_CMD10: length 73.7
  TOP w0.14: VRAM4.P8 160.31,145.59 160.2,145.69 160.2,145.89 160.31,146 161.55,146 161.85,146.3 161.85,146.55 162.25,146.96 163.74,146.96 165.56,145.14 165.56,144.74 165.78,144.51 v1(165.78,143.68) ; VRAM1.P8 174.77,140.42 174.21,140.42 173.91,140.12 173.91,139.84 173.57,139.5 171.97,139.5 v2(171.53,139.93) 170.84,140.63 170.55,140.63 169.54,141.65 169.54,143.4 170.78,144.65 170.99,144.65 v1(171.02,144.63)
  L3 w0.127: v1(165.78,143.68) 167.7,143.68 167.86,143.52 167.86,143.05 167.99,142.91 168.52,142.91 168.65,143.04 v1(168.65,143.83) 170.13,143.83 170.93,144.63 v1(171.02,144.63)
  L4 w0.127: v1(174.06,123.28) 173.61,123.73 173.61,126.03 173.83,126.26 174.49,126.26 174.73,126.5 174.73,126.85 174.7,126.89 174.7,127.34 174.61,127.42 174.61,128.21 175.11,128.71 175.11,129.29
  L4 w0.165: 175.11,129.29 175.11,131.79 173.71,133.2 173.71,134.07 173.51,134.27 173.51,135 173.34,135.17 173.27,135.17 172.95,135.48 172.95,135.68 173.15,135.87 173.34,135.87 173.51,136.03 173.51,136.41 171.33,138.58 171.33,140.38 170.65,141.06 170.33,141.06 169.44,141.95 169.44,142.95 168.72,143.67 168.72,143.76 v1(168.65,143.83)
  BOTTOM w0.14: VRAM2.P8 174.71,146.02 174.16,146.02 173.91,146.27 173.91,147.45 173.68,147.67 173.3,147.67 173.17,147.55 173.17,146.98 173.05,146.85 172.6,146.85 172.47,146.98 172.47,147.6 172.34,147.73 171.73,147.73 171.61,147.6 171.61,147.36 170.76,146.52 170.76,146.1 171.02,145.85 171.37,145.85 171.83,145.39 171.83,145.16 171.3,144.63 v1(171.02,144.63) ; VRAM3.P8 160.99,140.44 161.61,140.44 161.89,140.16 161.89,139.75 162.53,139.11 164.29,139.11 165.73,140.55 165.73,142.72 165.61,142.83 165.61,143.51 v1(165.78,143.68)
  BOTTOM w0.178: v1(174.06,123.28) 174.04,123.28 GPU1.G23
FBA_CMD11: length 59.3
  TOP w0.14: VRAM1.P7 175.36,141.81 175.36,142 174.62,142.73 v1(174.18,142.73) ; VRAM4.P7 161.57,143.86 161.95,143.86 162.21,143.59 162.21,142.9 v1(162.19,142.88)
  TOP w0.178: v2(167.39,147.56) 167.4,147.55 v1(167.97,147.55)
  L3 w0.127: v1(162.19,142.88) 162.19,143.58 162.09,143.67 162.09,145.07 164.81,147.79 166.53,147.79 166.77,147.55 v1(167.97,147.55) 168.27,147.55 168.63,147.91 170.05,147.91 170.69,147.26 172.72,147.26 173.43,146.55 173.43,144.57 174.33,143.67 174.33,142.88 v1(174.18,142.73)
  L4 w0.127: 175.58,129.42 175.57,129.4 175.57,128.93 175.58,128.91 175.58,128.6 174.88,127.9 174.88,127.53 174.97,127.45 174.97,126.4 174.05,125.48 v1(174.05,124.91)
  L4 w0.165: v1(167.97,147.55) 167.97,147.51 167.46,147 167.46,145.84 167.73,145.57 167.73,144.65 168.03,144.35 168.79,144.35 169.81,143.32 169.81,142.1 170.48,141.43 170.8,141.43 171.15,141.09 171.7,140.53 171.7,138.74 173.98,136.46 173.98,134.47 175.58,132.86 175.58,129.42
  BOTTOM w0.14: v1(162.19,142.88) 162.37,142.7 162.37,142.49 162.24,142.36 161.71,142.36 161.66,142.41 161.14,142.41 160.64,141.9 VRAM3.P7 ; VRAM2.P7 174.31,143.96 174.31,143.22 174.18,143.1 v1(174.18,142.73)
  BOTTOM w0.178: GPU1.G24 173.65,123.69 174.06,124.1 174.06,124.9 v1(174.05,124.91)
FBA_CMD12: length 63.7
  TOP w0.14: v1(174.75,143.43) 174.75,143.91 175.49,144.65 175.49,144.83 175.83,145.18 176.7,145.18 176.84,145.32 176.84,145.49 VRAM1.M2 ; v1(161.76,143.41) 161.76,142.96 160.99,142.18 160.71,142.18 160.21,141.68 160.21,141.44 159.91,141.14 159.7,141.14 159.35,140.79 VRAM4.M2
  TOP w0.178: v2(169.3,148.83) 169.3,148.83 v1(168.88,148.41)
  L3 w0.127: v1(161.76,143.41) 161.76,145.58 162.2,146.02 162.2,146.88 162.48,147.15 163.7,147.15 164.71,148.15 168.41,148.15 168.67,148.41 v1(168.88,148.41) 170.16,148.41 170.98,147.59 172.85,147.59 173.76,146.69 173.76,144.75 174.75,143.76 v1(174.75,143.43)
  L4 w0.127: v1(174.31,126.68) 174.31,126.75 174.37,126.8 174.37,128.31 174.64,128.59 174.64,129.32
  L4 w0.165: v1(168.88,148.41) 168.59,148.12 167.85,148.12 167.09,147.36 167.09,145.68 167.36,145.42 167.36,144.38 168.41,143.33 168.41,143.33 169.06,142.68 169.06,141.81 170.17,140.69 170.5,140.69 170.97,140.23 170.97,138.12 171.37,137.71 171.37,136.4 173.04,134.73 173.04,134.08 173.24,133.88 173.24,133.01 174.64,131.6 174.64,129.32
  BOTTOM w0.14: VRAM2.M2 176.31,141.22 175.79,141.22 175.49,141.52 175.49,141.73 174.63,142.59 174.63,143.06 174.75,143.18 v1(174.75,143.43) ; VRAM3.M2 159.04,145.69 159.14,145.79 159.35,145.79 159.47,145.67 159.47,145.44 159.69,145.22 159.95,145.22 160.27,144.9 160.27,144.64 160.49,144.42 160.83,144.42 161.76,143.49 v1(161.76,143.41)
  BOTTOM w0.178: v1(174.31,126.68) 174.31,126.64 174.45,126.5 GPU1.F27
FBA_CMD13: length 63.5
  TOP w0.14: v1(159,143.81) 159.33,143.48 159.33,142.74 158.24,141.65 VRAM4.L3 ; v1(177.02,143.79) 177.02,143.9 177.08,143.97 177.08,144.33 VRAM1.L3
  TOP w0.178: v2(168.76,150.08) 168.72,150.04 v1(168.72,149.51)
  L3 w0.127: v1(177.02,143.79) 177.02,144.06 176.21,144.86 175.32,144.86 174.42,145.76 174.42,146.96 173.11,148.27 171.58,148.27 170.34,149.51 v1(168.72,149.51) 168.57,149.51 168.27,149.21 164.67,149.21 163.27,147.81 162.2,147.81 161.54,147.15 161.54,146.3 159.39,144.14 159.34,144.14 v1(159,143.81)
  L4 w0.127: v1(172.82,126.82) 172.83,126.82 173.81,127.8 173.81,128.7 173.69,128.83 173.69,129.37
  L4 w0.165: v1(168.72,149.51) 168.34,149.13 167.48,149.13 166.36,148.01 166.36,145.38 166.62,145.11 166.62,144.08 167.09,143.61 168.32,142.38 168.32,141.5 169.59,140.23 169.59,138.45 170.43,137.61 170.43,136.01 172.1,134.34 172.1,133.69 172.3,133.49 172.3,132.62 173.69,131.23 173.69,129.37
  BOTTOM w0.14: VRAM3.L3 158.24,145 158.32,145.08 158.49,145.08 158.67,144.9 158.67,144.14 v1(159,143.81) ; v1(177.02,143.79) 177.22,143.58 177.22,142.29 177.54,141.97 VRAM2.L3
  BOTTOM w0.178: v1(172.82,126.82) 172.82,126.65 172.91,126.56 172.91,125.83 173.2,125.54 173.2,124.94 GPU1.G25
FBA_CMD14: length 3.8
  BOTTOM w0.178: GPU1.G27 173.65,126.28 173.55,126.38 173.55,128.83 TP7505.1
FBA_CMD15: length 65
  TOP w0.14: v1(178.33,143.32) 178.29,143.36 178.29,143.47 178,143.77 178,144.23 178.34,144.57 VRAM1.K3 ; VRAM4.K3 157.44,142.75 157.5,142.82 v1(157.5,142.92)
  TOP w0.178: v1(167.7,149.76) 167.7,150.12 v2(167.51,150.31)
  L3 w0.127: v1(157.5,142.92) 157.6,142.92 158.49,143.81 158.49,143.91 161.21,146.63 161.21,147.29 162.06,148.14 162.95,148.14 164.46,149.64 167.59,149.64 v1(167.7,149.76) 168.17,149.76 168.38,149.96 170.52,149.96 171.86,148.62 173.23,148.62 174.75,147.1 174.75,145.94 175.23,145.46 176.2,145.46 v1(178.33,143.32)
  L4 w0.127: v1(172.83,127.46) 172.83,128.37 172.93,128.47
  L4 w0.165: 172.93,128.47 173.21,128.74 173.21,131.04 171.83,132.42 171.83,133.29 171.63,133.49 171.63,134.15 169.96,135.81 169.96,137.56 169.66,137.86 169.23,138.3 169.23,140.08 167.95,141.35 167.95,142.22 166.93,143.24 165.22,144.96 165.22,146.07 165.96,146.81 165.96,148.27 167.34,149.66 167.6,149.66 v1(167.7,149.76)
  BOTTOM w0.14: VRAM2.K3 178.51,141.76 178.51,142.18 178.44,142.26 178.44,143.22 v1(178.33,143.32) ; v1(157.5,142.92) 157.83,143.24 157.83,143.58 157.33,144.08 157.33,144.68 VRAM3.K3
  BOTTOM w0.178: v1(172.83,127.46) 173.27,127.02 173.27,125.93 173.65,125.55 GPU1.G26
FBA_CMD16: length 53.2
  TOP w0.14: VRAM4.L2 158.24,140.51 158.37,140.38 158.55,140.38 158.67,140.51 158.67,141.08 158.82,141.24 159.26,141.24 159.47,141.45 159.47,141.91 160.15,142.59 v1(160.15,142.78)
  TOP w0.178: v1(167.97,127.76) 167.97,128.36 v2(167.97,128.36)
  L4 w0.165: v1(167.97,127.76) 167.47,127.76 160.42,134.81 160.42,136.34 160.85,136.76 160.85,138.24 161.94,139.32 161.94,139.69 161.42,140.2 161.42,142.1 161.74,142.42 162.37,142.42 163.1,143.15 163.1,144.51 163.47,144.88 163.47,146.91 163.67,147.11 164.21,147.11 164.34,147.23 164.34,147.93 164.21,148.06 162.53,148.06 162.33,147.86 162.33,145.52 162.2,145.4 160.11,145.4 159.91,145.19 159.91,144.9 160.11,144.7 162.22,144.7 162.35,144.57 162.35,144.13 162.22,144 160.43,144 160.24,143.8 160.24,142.87 v1(160.15,142.78)
  BOTTOM w0.14: VRAM3.L2 158.49,145.59 158.86,145.22 159.13,145.22 159.47,144.88 159.47,144.47 160.21,143.73 160.21,142.84 v1(160.15,142.78)
  BOTTOM w0.178: v1(167.97,127.76) 167.97,127.65 169.11,126.51 169.11,124.07 GPU1.M24
FBA_CMD17: length 1.2
  TOP w0.178: v1(169.93,122.51) 170.3,122.88 TP7502.1
  BOTTOM w0.178: v1(169.93,122.51) 169.55,122.89 GPU1.M23
FBA_CMD18: length 58.1
  TOP w0.14: v1(158.11,144.09) 158.11,143.39 158.42,143.09 158.42,142.32 157.83,141.73 157.83,140.38 VRAM4.K1
  L4 w0.165: v1(170.72,123.3) 170.59,123.3 169.49,124.4 169.49,125.07 169.49,125.07 169.49,126 168.17,127.33 167.25,127.33 159.94,134.63 159.94,136.51 160.48,137.05 160.48,138.62 161,139.14 161,141.66 160.55,142.11 160.18,142.11 159.56,142.73 158.52,142.73 157.67,143.59 157.67,143.74 157.56,143.85 157.56,144.23 158.23,144.9 158.54,144.9 158.68,145.05 158.68,146.31 158.89,146.52 160.98,146.52 161.16,146.7 161.16,147.28 161.29,147.42 161.82,147.42 161.95,147.3 161.95,145.95 161.82,145.82 159.56,145.82 159.35,145.61 159.35,144.56 159.05,144.26 158.63,144.26 158.45,144.09 v1(158.11,144.09)
  BOTTOM w0.14: VRAM3.K1 157.62,146.39 157.98,146.75 158.37,146.75 158.66,146.46 158.66,146.19 158.47,146 158.01,146 157.81,145.8 157.81,144.39 v1(158.11,144.09)
  BOTTOM w0.178: VRAM3.K1 157.11,146.72 157.11,147.99 157.97,148.85 v2(157.97,149.45) 157.97,149.82 R7508.1 ; GPU1.K24 171.17,123.83 171.11,123.89 171.11,124.01 170.96,124.17 170.74,124.17 170.64,124.08 170.64,123.92 170.72,123.84 v1(170.72,123.3)
FBA_CMD19: length 58.3
  TOP w0.14: v1(158.01,147.93) 157.44,147.36 VRAM4.K9 157.44,146.25 157.81,145.88 157.81,144.38 157.69,144.26 157.69,143.34 157.99,143.03 157.99,142.51 v1(157.99,142.51)
  L4 w0.165: v1(157.99,142.51) 158.15,142.35 159.4,142.35 160.15,141.6 160.42,141.6 160.55,141.48 160.55,140.99 160.42,140.86 159.81,140.86 159.67,140.71 159.67,140.37 160.11,139.92 160.11,137.32 159.46,136.66 159.46,134.45 166.62,127.28 166.62,126.86 166.94,126.54 167.15,126.54 167.64,127.03 168.01,127.03 168.28,126.76 168.28,126.09 168.44,125.93 168.68,125.93 168.82,126.08 169.04,126.08 169.23,125.89 169.23,124.24 169.55,123.92 169.55,123.5 169.23,123.17 169.23,122.98 169.49,122.72 169.49,122.17 169.34,122.02 167.9,122.02 167.68,121.8 167.25,121.8 167.05,122 167.05,122.74 166.92,122.86 166.26,122.86 166.16,122.77 166.16,120.98 166.29,120.86 166.74,120.86 167.1,121.22 167.81,121.22 167.96,121.08 167.96,120.7 168.12,120.54 168.55,120.54 168.71,120.7 168.71,121.37 168.81,121.46 169.3,121.46 169.46,121.3 169.46,121.15 169.58,121.03 169.89,121.03 170.17,121.31 170.17,121.88 170.33,122.04 171.35,122.04 171.55,122.23 v1(171.55,122.45)
  BOTTOM w0.14: v1(157.99,142.51) 158.25,142.77 158.25,142.78 158.52,142.78 158.7,142.6 158.7,142.29 158.36,141.94 158.1,141.94 157.85,141.7 157.85,140.4 VRAM3.K9
  BOTTOM w0.178: GPU1.K23 171.19,122.87 171.19,122.59 171.33,122.45 v1(171.55,122.45) ; R7509.1 159.2,150.24 v2(159.2,149.44) 159.2,149.12 v1(158.01,147.93)
FBA_CMD20: length 64.4
  TOP w0.14: VRAM4.T3 162.35,141.48 163.24,141.48 163.97,142.22 163.99,142.22 164.33,142.56 164.33,142.9 164.23,142.99 164.23,143.57 164.33,143.67 164.33,143.94 163.93,144.34 v1(163.93,144.42) ; v1(171.52,141.34) 171.06,141.81 171.06,142.86 172.35,144.15 172.9,144.15 VRAM1.T3
  L3 w0.127: v1(171.52,141.34) 171.04,140.86 171.04,139.92 170.7,139.58 169.96,139.58 169.47,140.07 167.76,140.07 v1(167.25,139.57) 166.24,139.57 165.58,140.22 165.58,140.42 165.76,140.6 165.76,142.67 165.6,142.83 165.6,142.96 164.15,144.42 v1(163.93,144.42)
  L4 w0.165: v1(169.62,127.66) 169.15,127.66 167.9,128.91 167.66,128.91 161.42,135.15 161.42,136.17 161.59,136.34 161.59,137.91 163.22,139.54 163.22,140.21 162.93,140.5 162.49,140.5 162.3,140.69 162.3,141.2 162.49,141.39 163.49,141.39 163.66,141.22 165.2,141.22 165.7,140.72 165.7,140.06 165.86,139.9 166.92,139.9 v1(167.25,139.57)
  BOTTOM w0.14: v1(171.52,141.34) 171.46,141.4 171.38,141.4 171.05,141.73 171.05,141.97 171.19,142.12 172.16,142.12 172.29,141.99 172.29,141.67 172.42,141.55 172.76,141.55 172.89,141.67 172.89,141.85 172.97,141.93 173.38,141.93 173.54,141.77 VRAM2.T3 ; v1(163.93,144.42) 163.55,144.79 VRAM3.T3
  BOTTOM w0.178: GPU1.M27 169.49,126.62 168.41,127.7 v2(168.41,128.41) 168.41,131.41 168.54,131.54 169.03,131.54 169.16,131.41 169.16,128.12 169.62,127.66 v1(169.62,127.66)
FBA_CMD21: length 60.1
  TOP w0.14: VRAM4.T8 163.98,145.59 v2(164.24,145.33) 164.59,144.98 164.59,144.6 164.94,144.25 164.94,143.25 165.15,143.04 165.15,142.78 v1(165.16,142.77) ; v1(171.48,142.58) 171.48,142.36 172.27,141.58 172.27,141.12 172.6,140.79 VRAM1.T8
  L3 w0.127: v1(171.48,142.58) 171.64,142.42 171.64,142.35 172.36,141.63 172.36,140.91 171.7,140.25 171.7,139.65 170.85,138.79 169.13,138.79 168.89,139.04 167.83,139.04 167.4,138.6 v1(167.25,138.6) 165.79,138.6 164.44,139.96 164.44,141.29 164.54,141.39 164.54,142.04 165.16,142.66 v1(165.16,142.77)
  L4 w0.127: v1(169.83,127.06) 169.95,127.06 170.04,127.15 170.04,127.84 169.96,127.92 169.96,128.08 170.04,128.17 170.04,128.46 169.78,128.73 169.22,128.73 169.09,128.86 169.09,129.05
  L4 w0.165: v1(167.25,138.6) 167.17,138.53 166.83,138.53 166.68,138.68 166.68,138.84 166.46,139.06 164.7,139.06 164.57,139.18 164.57,139.45 164.7,139.58 164.83,139.58 164.95,139.71 164.95,140.08 164.83,140.2 164.59,140.2 164.53,140.27 164.53,140.39 164.45,140.47 164.1,140.47 163.98,140.35 163.98,139.24 162.94,138.2 162.94,137.68 162.84,137.58 162.45,137.58 162.33,137.46 162.33,137.08 162.44,136.97 163.18,136.97 163.3,136.85 163.3,136.24 163.04,135.98 162.47,135.98 162.37,135.88 162.37,135.53 162.85,135.06 162.97,135.06 163.1,135.18 163.27,135.18 163.52,134.93 163.52,134.38 166.9,130.99 167.14,130.99 167.49,130.65 167.49,130.42 167.92,129.98 168.15,129.98 169.09,129.05
  BOTTOM w0.14: v1(171.48,142.58) 171.48,143.46 172.83,144.81 172.83,145.08 173.21,145.47 173.33,145.59 VRAM2.T8 ; VRAM3.T8 163.45,140.79 163.52,140.71 164.41,140.71 164.73,141.04 164.73,142.24 165.16,142.66 v1(165.16,142.77)
  BOTTOM w0.178: GPU1.M26 169.39,125.39 169.39,125.62 169.47,125.71 169.69,125.71 170.13,126.14 170.13,126.45 170.03,126.55 169.89,126.55 169.77,126.68 169.77,126.99 v1(169.83,127.06)
FBA_CMD22: length 81
  TOP w0.14: v1(165.27,142.07) 165.28,142.08 165.28,142.13 165.62,142.47 165.62,143.2 165.33,143.49 165.33,144.35 165.11,144.57 165.11,145 164.18,145.94 162.1,145.94 161.75,145.59 VRAM4.R8 ; v1(170.92,143.98) 170.74,143.98 v2(170.13,143.37) 169.98,143.22 169.98,141.89 170.79,141.08 170.96,141.08 171.22,140.82 171.22,140.73 171.53,140.42 173.69,140.42 174.06,140.79 VRAM1.R8
  L3 w0.127: v1(165.27,142.07) 165,141.8 165,141.52 165.13,141.4 165.3,141.4 165.43,141.27 165.43,140.99 165.3,140.86 165.02,140.86 164.81,140.65 164.81,140.07 164.97,139.92 165.4,139.92 165.63,139.69 165.63,139.39 165.97,139.05 167.38,139.05 167.89,139.57 v1(168.02,139.57) 169.1,139.57 169.41,139.25 170.84,139.25 171.37,139.78 171.37,140.39 172.03,141.05 172.03,141.5 171.37,142.16 171.31,142.16 170.92,142.55 v1(170.92,143.98)
  L4 w0.165: v1(169.6,128.31) 169.17,128.31 168.04,129.43 167.8,129.43 161.89,135.34 161.89,136.12 161.96,136.18 161.96,137.74 163.61,139.39 163.61,140.7 163.76,140.85 165.02,140.85 165.33,140.53 165.33,139.86 165.66,139.53 166.53,139.53 166.96,139.1 167.55,139.1 v1(168.02,139.57)
  BOTTOM w0.14: VRAM3.R8 161.75,140.79 162.1,140.44 163.01,140.44 163.22,140.23 163.22,139.45 163.3,139.37 163.84,139.37 163.96,139.49 163.96,140.24 164.02,140.3 164.69,140.3 165.27,140.88 v1(165.27,142.07) ; v1(170.92,143.98) 171.51,143.98 172.45,144.91 172.45,145.32 171.35,146.42 171.35,146.6 171.61,146.87 171.82,146.87 172.8,145.89 173.09,145.89 173.16,145.96 173.67,145.96 174.03,145.59 VRAM2.R8
  BOTTOM w0.178: GPU1.M25 169.7,124.49 169.91,124.7 169.91,125.53 170.4,126.02 170.4,132.16 170.28,132.28 169.77,132.28 169.64,132.16 169.64,128.34 v1(169.6,128.31)
FBA_CMD23: length 59.3
  TOP w0.14: VRAM4.R7 161.97,144.26 162.35,144.26 163.08,143.53 163.08,143.15 162.98,143.05 162.98,142.39 v1(162.93,142.34) ; VRAM1.R7 174.56,141.59 174.73,141.75 174.73,142.09 174.51,142.31 174.01,142.31 173.6,142.72 v1(173.28,142.72)
  TOP w0.178: v1(165.36,147.01) 165,147.01 v2(164.83,147.19)
  L3 w0.127: v1(162.93,142.34) 162.93,141.83 163.06,141.7 163.48,141.7 163.61,141.83 163.61,142.25 163.38,142.47 163.38,142.78 163.07,143.09 163.07,143.74 162.85,143.97 162.85,144.89 163.54,145.59 163.76,145.59 163.79,145.56 163.97,145.56 164.16,145.75 164.16,145.93 164.13,145.96 164.13,146.14 164.33,146.34 164.51,146.34 164.54,146.31 164.72,146.31 164.92,146.51 164.92,146.69 164.89,146.72 164.89,146.92 165.07,147.1 165.28,147.1 v1(165.36,147.01) 165.37,147.01 166.22,147.01 166.51,146.72 168.39,146.72 168.65,146.99 169.77,146.99 170.15,146.6 171.52,146.6 172.66,145.46 172.66,144.28 173.38,143.57 173.38,142.83 v1(173.28,142.72)
  L4 w0.127: 171.93,128.18 171.94,128.18 171.94,127.57 172.15,127.36 172.15,126.73 171.94,126.52 v1(171.52,126.52)
  L4 w0.165: v1(165.36,147.01) 164.7,146.35 164.27,146.35 164.14,146.23 164.14,145.78 164.27,145.66 164.65,145.66 164.81,145.5 164.81,143.78 165.62,142.97 165.62,142.38 165.85,142.15 165.85,141.86 166.9,140.82 167.45,140.82 168.48,139.79 168.48,137.83 169.02,137.29 169.02,135.42 169.8,134.65 169.8,133.09 172.27,130.62 172.27,128.52 171.93,128.18
  BOTTOM w0.14: VRAM3.R7 161.17,141.59 161.08,141.67 161.08,141.85 161.28,142.04 161.53,142.04 161.74,141.83 161.94,141.83 162.11,142 162.39,142 162.52,141.87 162.65,141.87 162.93,142.15 v1(162.93,142.34) ; VRAM2.R7 173.4,143.85 173.4,143.56 173.41,143.55 173.41,142.85 v1(173.28,142.72)
  BOTTOM w0.178: GPU1.K26 171.57,125.69 171.57,126.46 v1(171.52,126.52)
FBA_CMD24: length 94.4
  TOP w0.14: VRAM4.P2 161.09,140.34 161.58,140.34 161.87,140.05 161.87,139.77 162.83,138.81 165.7,138.81 165.83,138.94 165.83,139.27 165.7,139.39 163.39,139.39 163.26,139.52 163.26,139.85 163.39,139.98 165.79,139.98 v1(166.17,140.36) ; v1(170.51,140.05) 169.09,141.46 169.09,143.63 169.1,143.64 169.1,143.87 169.87,144.64 v2(169.87,144.8) 169.87,147.04 170.56,147.72 173.07,147.72 173.97,146.82 173.97,146.24 174.19,146.02 174.71,146.02 VRAM1.P2
  L3 w0.127: v1(170.51,140.05) 170.05,140.5 167.46,140.5 v1(167.28,140.33) 166.2,140.33 v1(166.17,140.36)
  L4 w0.127: 170.44,123.98 170.65,123.77 170.85,123.77 171.14,123.48 171.14,123.07 171.34,122.87 171.75,122.87 171.98,122.64 171.98,122.27 171.39,121.68 170.77,121.68 v1(170.64,121.55)
  L4 w0.165: 170.44,123.98 169.84,124.59 169.84,126.3 168.51,127.62 168.51,127.87 167.88,128.5 167.4,128.5 160.95,134.95 160.95,136.22 161.22,136.49 161.22,138.08 162.32,139.19 162.32,139.93 161.92,140.33 161.92,141.35 162.44,141.87 163.18,141.87 163.43,142.13 164.43,142.13 164.96,141.6 165.59,141.6 166.86,140.33 v1(167.28,140.33)
  BOTTOM w0.14: VRAM3.P2 160.99,145.94 161.58,145.94 161.87,146.23 161.87,146.71 162.22,147.06 162.22,147.59 162.24,147.61 162.24,147.65 162.68,148.1 165.03,148.1 166.62,146.51 166.62,142.67 166.17,142.22 v1(166.17,140.36) ; v1(170.51,140.05) 170.31,140.25 170.06,140.25 169.93,140.12 169.93,139.7 170.06,139.57 171.1,139.57 171.23,139.44 171.23,137.98 171.4,137.81 171.64,137.81 171.81,137.98 171.81,139.67 171.94,139.79 172.27,139.79 172.39,139.67 172.39,137.98 172.56,137.81 172.81,137.81 172.98,137.98 172.98,139.26 173.15,139.43 173.72,139.43 173.91,139.62 173.91,140.08 174.19,140.36 174.93,140.36 175.14,140.57 VRAM2.P2
  BOTTOM w0.178: GPU1.K22 171.14,122.05 v1(170.64,121.55)
FBA_CMD25: length 65.2
  TOP w0.14: v1(166.09,143.02) 166.09,142.23 165.31,141.46 164.92,141.46 v2(164.76,141.29) 164.6,141.14 160.4,141.14 160.07,140.82 160.03,140.82 160,140.79 VRAM4.N2 ; VRAM1.N2 175.66,145.59 175.29,145.22 173.45,145.22 173.17,144.94 172.66,144.94 170.45,142.73 170.45,142.2 170.43,142.19 v1(170.43,142.18)
  L3 w0.127: v1(166.09,143.02) 166.24,143.17 167.33,143.17 167.49,143.01 v1(167.49,141.9) 170.15,141.9 v1(170.43,142.18)
  L4 w0.127: v1(172.42,122.44) 172.42,122.67 171.98,123.11 171.98,124.23 172.23,124.48 172.8,124.48 173.02,124.7 173.02,125.13 172.83,125.33 171.76,125.33 171.63,125.45 171.63,126.02 171.76,126.15 172.25,126.15 172.38,126.28 172.38,128.06 172.6,128.29 172.6,128.6
  L4 w0.165: v1(167.49,141.9) 166.86,142.53 166.62,142.53 166.29,142.2 166.29,141.95 167.06,141.18 167.6,141.18 168.86,139.93 168.86,138.45 168.86,138.14 169.49,137.51 169.49,135.62 170.84,134.27 170.84,134.09 170.27,133.52 170.27,133.28 170.5,133.05 170.74,133.05 170.92,133.23 170.96,133.28 171.17,133.28 171.22,133.23 171.36,133.09 171.36,132.74 171.2,132.58 171.2,132.35 172.74,130.81 172.74,128.74 172.6,128.6
  BOTTOM w0.14: v1(170.43,142.18) 170.38,142.12 170.38,141.8 171.28,140.9 172.09,140.9 172.28,141.09 173.11,141.09 173.23,141.2 174.47,141.2 174.6,141.08 174.88,141.08 175.03,141.22 175.23,141.22 175.51,140.94 175.51,140.6 175.65,140.46 175.81,140.46 175.94,140.59 VRAM2.N2 ; VRAM3.N2 160.12,145.59 160.52,145.19 164.19,145.19 164.96,144.42 165.86,144.42 166.24,144.03 166.24,143.17 v1(166.09,143.02)
  BOTTOM w0.178: v1(172.42,122.44) 171.98,122.89 GPU1.J23
FBA_CMD26: length 57.3
  TOP w0.14: VRAM4.M3 159.04,141.97 159.69,142.61 159.69,143.21 v1(159.78,143.3) ; VRAM1.M3 176.74,144.11 176.59,143.96 176.59,143.69 176.4,143.5 v1(176.15,143.5)
  TOP w0.178: v2(166.67,137.3) 166.67,137.3 v1(167.28,137.3)
  L3 w0.127: v1(159.78,143.3) 159.69,143.21 159.69,142.58 160.17,142.1 160.86,142.1 162.25,140.71 162.74,140.71 163.22,140.23 163.22,139.41 165.2,137.43 167.15,137.43 v1(167.28,137.3) 167.6,136.98 170.44,136.98 172.19,138.74 172.63,138.74 175.84,141.95 175.84,142.56 176.15,142.87 v1(176.15,143.5)
  L4 w0.127: 169.8,129.66 170.44,129.03 170.44,128.79 170.62,128.6 170.62,126.68 170.42,126.48 170.42,126.23 170.49,126.16 170.88,126.16 171.15,125.9 171.15,125.54 170.97,125.36 170.97,125.23 171.14,125.06 171.14,124.67 171.01,124.55 171.01,124.32 171.33,124 171.48,124 v1(171.56,124.07)
  L4 w0.165: v1(167.28,137.3) 167.19,137.21 167.06,137.21 166.21,138.06 165.94,138.06 165.72,138.28 165.36,138.28 165.1,138.02 164.84,138.02 164.58,138.29 164.19,138.29 163.93,138.02 163.93,137.55 164.06,137.42 164.3,137.42 164.41,137.31 164.41,136.81 164.33,136.72 164.24,136.72 164.11,136.59 164.11,136.19 164.33,135.97 165.03,135.97 165.15,135.84 165.15,135.39 165.07,135.31 164.59,135.31 164.46,135.18 164.46,134.77 164.59,134.65 165.25,134.65 165.38,134.52 165.38,133.85 166.23,133 166.47,133 169.8,129.66
  BOTTOM w0.14: VRAM3.M3 159.04,144.41 159.78,143.67 v1(159.78,143.3) ; v1(176.15,143.5) 175.69,143.04 175.69,142.5 176.5,141.7 176.63,141.7 VRAM2.M3
  BOTTOM w0.178: v1(171.56,124.07) 171.58,124.06 171.86,124.06 171.97,124.16 GPU1.J25
FBA_CMD27: length 67.2
  TOP w0.14: v1(164.05,141.69) 164.67,142.31 164.67,142.9 164.48,143.09 164.48,143.47 164.65,143.64 164.65,144.05 164.35,144.34 164.35,144.59 163.76,145.18 160.19,145.18 159.84,145.53 VRAM4.N8 ; VRAM1.N8 175.53,141.2 173.22,141.2 171.94,142.48 171.94,143.14 v1(172.07,143.27)
  TOP w0.178: v2(168.56,138.73) 168.42,138.59 v1(168.02,138.59)
  L3 w0.127: v1(172.07,143.27) 172.07,142.94 171.97,142.84 171.97,142.49 172.69,141.77 172.69,140.78 172.03,140.12 172.03,139.51 170.83,138.31 168.93,138.31 168.64,138.59 v1(168.02,138.59) 167.56,138.14 165.69,138.14 163.98,139.85 163.98,141.62 v1(164.05,141.69)
  L4 w0.127: 169.68,129.14 170.27,128.55 170.27,126.69 170.19,126.61 170.19,125.7 170.34,125.56 170.34,125.21 170.19,125.06 170.19,124.81 171.38,123.63 171.38,123.48 v1(171.56,123.29)
  L4 w0.165: v1(168.02,138.59) 168.1,138.5 168.1,137.98 168.02,137.89 167.84,137.89 167.69,137.74 167.43,137.74 167.24,137.93 167.24,138.05 167.14,138.15 166.68,138.15 166.17,138.66 164.56,138.66 164.37,138.85 164.14,138.85 163.33,138.04 163.33,137.38 163.68,137.03 163.68,135.47 163.99,135.16 163.99,134.57 166.11,132.45 166.36,132.45 169.66,129.14 169.68,129.14
  BOTTOM w0.14: VRAM3.N8 160.21,141.16 161.23,141.16 161.29,141.22 161.64,141.22 161.7,141.16 162.91,141.16 163.32,141.57 163.51,141.57 163.67,141.41 163.67,141.2 163.8,141.06 164.13,141.06 164.26,141.19 164.26,141.47 v1(164.05,141.69) ; v1(172.07,143.27) 172.07,143.57 173.17,144.67 173.17,144.94 173.39,145.16 173.63,145.16 173.7,145.23 174.18,145.23 174.24,145.17 174.48,145.17 174.63,145.02 174.85,145.02 174.99,145.16 175.79,145.16 175.94,145.32 VRAM2.N8
  BOTTOM w0.178: GPU1.J24 171.97,123.44 171.82,123.29 v1(171.56,123.29)
FBA_CMD28: length 58.6
  TOP w0.14: VRAM1.N7 175.94,142.74 175.69,142.99 175.69,143.68 v1(176.15,144.14) ; v1(160.68,143.43) 160.35,143.43 159.52,144.26 159.52,144.54 159.77,144.79 VRAM4.N7
  L3 w0.127: v1(160.68,143.43) 160.68,142.96 162.49,141.15 162.76,141.15 163.55,140.36 163.55,139.68 165.42,137.81 167.59,137.81 167.94,137.46 168.17,137.46 v1(168.18,137.47) 170.46,137.47 172.36,139.37 172.36,139.98 174.39,142.01 174.82,142.01 175.68,142.86 175.68,143.67 v1(176.15,144.14)
  L4 w0.165: v1(168.18,137.47) 167.94,137.47 167.75,137.28 167.75,136.78 167.87,136.66 168.42,136.66 168.55,136.53 168.55,135.23 168.77,135.01 169.33,134.45 169.33,134.28 169.16,134.11 168.74,134.11 168.55,133.92 168.55,133.63 168.72,133.45 169.16,133.45 169.33,133.29 169.33,132.85 171.8,130.38 171.8,128.46 171.4,128.06 171.4,127.88 171.5,127.78 171.5,127.79 v1(171.52,127.79)
  BOTTOM w0.14: v1(176.15,144.14) 175.92,144.14 175.48,143.7 175.3,143.7 175.02,143.97 175.02,144.15 175.66,144.79 VRAM2.N7 ; v1(160.68,143.43) 160.8,143.31 160.8,142.55 VRAM3.N7
  BOTTOM w0.178: v1(171.52,127.79) 171.67,127.79 171.77,127.88 171.77,128.71 171.65,128.83 171.65,132.5 171.52,132.63 171.01,132.63 170.89,132.5 v2(170.89,129.1) 170.89,128.77 170.72,128.6 170.72,127.66 171.02,127.35 171.02,126.98 170.72,126.67 170.72,126.36 170.99,126.09 GPU1.K27
FBA_CMD29: length 59
  TOP w0.14: v1(158.9,143.17) 158.54,143.53 158.54,144.26 158.24,144.56 VRAM4.L7 ; v1(176.43,142.38) 176.43,142.39 176.47,142.35 176.82,142.35 176.91,142.44 177.07,142.44 177.35,142.16 177.35,142.01 177.11,141.77 177.11,141.24 177.19,141.16 177.54,141.16 177.63,141.25 177.63,141.5 VRAM1.L7
  TOP w0.178: v1(167.35,136.32) 167.1,136.32 v2(166.85,136.07)
  L3 w0.127: v1(158.9,143.17) 158.9,142.59 159.82,141.67 160.34,141.67 165.68,136.32 v1(167.35,136.32) 167.68,136.65 170.57,136.65 172.33,138.41 172.77,138.41 176.3,141.94 176.3,142.26 v1(176.43,142.38)
  L4 w0.127: v1(171.59,124.88) 171.49,124.88 171.38,125 171.38,126 170.92,126.46 170.92,126.6 171.09,126.77 171.09,126.95 170.87,127.17 170.87,129.21 170.8,129.28 170.8,129.74
  L4 w0.165: v1(167.35,136.32) 167.35,136.37 166.06,137.66 165.17,137.66 164.8,137.29 164.8,136.51 164.97,136.35 165.29,136.35 165.42,136.48 165.42,136.96 165.55,137.09 165.92,137.09 166.09,136.93 166.09,136.52 166.25,136.35 166.53,136.35 166.66,136.22 166.66,135.95 166.39,135.68 165.74,135.68 165.62,135.56 165.62,135.17 165.77,135.02 166.43,135.02 166.73,134.72 166.73,134.58 166.51,134.36 165.97,134.36 165.86,134.25 165.86,134.05 166.44,133.47 166.66,133.47 170.01,130.12 170.02,130.12 170.1,130.04 170.67,130.04 170.8,129.91 170.8,129.74
  BOTTOM w0.14: v1(158.9,143.17) 159.32,142.75 159.32,142.42 158.5,141.59 VRAM3.L7 ; VRAM2.L7 177.38,144.79 176.59,144 176.59,143.33 176.36,143.09 176.36,142.45 v1(176.43,142.38)
  BOTTOM w0.178: GPU1.K25 171.17,124.77 171.28,124.88 v1(171.59,124.88)
FBA_CMD30: length 59.1
  TOP w0.14: VRAM4.J3 156.85,141.59 157,141.74 157,142.64 156.85,142.79 156.46,142.79 156.45,142.79 156.19,142.79 v1(156.18,142.8) ; v1(178.87,142.57) 178.76,142.68 178.76,143.62 179.11,143.97 179.11,144.76 VRAM1.J3
  TOP w0.178: v2(168.4,135.76) 168.04,136.12 v1(168.04,136.2)
  L3 w0.127: v1(178.87,142.57) 178.85,142.59 178.38,142.59 177.84,142.05 177.14,142.05 174.72,139.64 174.72,139.05 173.74,138.08 172.47,138.08 170.68,136.29 168.13,136.29 v1(168.04,136.2) 167.92,136.2 167.59,135.86 165.68,135.86 160.2,141.34 158.24,141.34 156.79,142.79 156.19,142.79 v1(156.18,142.8)
  L4 w0.127: 171.12,128.28 171.1,128.27 171.1,127.26 171.27,127.09 171.45,127.09 v1(171.51,127.15)
  L4 w0.165: v1(168.04,136.2) 168.08,136.15 168.08,135.72 168,135.64 167.67,135.64 167.47,135.84 167.21,135.84 167.13,135.76 167.13,135.75 166.91,135.53 166.91,135.21 167.03,135.08 168.04,135.08 168.47,134.65 168.47,134.5 168.15,134.18 167.68,134.18 167.42,134.44 167.26,134.44 166.9,134.09 166.9,133.9 167.31,133.48 167.5,133.48 167.64,133.63 167.88,133.63 168.23,133.28 168.23,133.1 168.06,132.92 168.06,132.74 168.4,132.4 168.58,132.4 168.77,132.58 168.93,132.58 169.24,132.28 169.24,132.11 169.03,131.91 169.03,131.77 169.36,131.45 169.5,131.45 169.69,131.64 169.87,131.64 170.16,131.35 170.16,131.17 169.99,131 169.99,130.81 170.21,130.59 170.21,130.59 170.27,130.53 170.45,130.53 170.63,130.7 170.81,130.7 171.32,130.19 171.32,128.96 171.53,128.75 171.53,128.57 171.43,128.46 171.2,128.46 171.12,128.38 171.12,128.28
  BOTTOM w0.14: VRAM3.J3 156.64,144.32 156.19,143.86 156.19,142.82 156.18,142.81 v1(156.18,142.8) ; v1(178.87,142.57) 178.88,142.59 179.14,142.59 179.37,142.36 179.37,141.82 VRAM2.J3
  BOTTOM w0.178: v1(171.51,127.15) 171.68,127.33 171.7,127.33 172.09,127.72 172.26,127.72 172.39,127.59 172.39,127.24 172.09,126.94 172.09,126.78 172.37,126.5 172.37,126.33 172.23,126.19 172.23,126.19 172.12,126.09 GPU1.J27
FBA_CMD31: length 1.3
  TOP w0.178: TP7504.1 172.73,126.06 v1(172.41,125.75)
  BOTTOM w0.178: GPU1.J26 172.41,125.73 v1(172.41,125.75)
FBA_D0: length 40.9
  TOP w0.178: v2(175.72,117.77) 175.72,118.3 v1(175.75,118.33) ; VRAM1.E3 182.21,144.79 182.05,144.62 182.05,144.34 182.34,144.04 182.59,144.04 182.73,144.19 v1(182.73,144.38)
  L3 w0.165: v1(182.73,144.38) 182.88,144.38 183.92,143.34 183.92,143.02 184.25,142.69 185.16,142.69 185.6,142.26 185.6,139.3 185.39,139.09 185.39,129.23 185.23,129.06 184.9,129.06 184.73,129.23 184.73,130.35 184.57,130.51 184.24,130.51 184.07,130.35 184.07,124.62 181.51,122.06 180.95,122.06 179.46,120.56 179.46,120.07 178.63,119.24 178.63,119 178.92,118.71 178.92,118.47 178.68,118.23 178.45,118.23 178.15,118.53 177.92,118.53 177.69,118.29 175.9,118.29 175.86,118.33 v1(175.75,118.33)
  BOTTOM w0.178: v1(175.75,118.33) 175.75,118.68 175.62,118.81 175.45,118.81 GPU1.E18
FBA_D1: length 42.3
  TOP w0.178: v1(180.39,144.37) 180.39,144.37 180.39,144.21 179.99,143.81 179.66,143.81 179.48,143.98 179.48,144.54 179.73,144.79 VRAM1.H3
  L3 w0.165: v1(180.39,144.37) 180.39,144.45 180.64,144.7 182.19,144.7 182.29,144.59 182.29,144.2 182.63,143.86 182.87,143.86 183.2,143.53 183.2,141.91 183.46,141.66 183.46,141.13 183.73,140.86 183.95,140.86 184.59,140.22 184.59,139.32 184.92,138.98 184.92,131.16 184.76,130.99 184.43,130.99 184.26,131.16 184.26,131.72 184.1,131.88 183.77,131.88 183.6,131.72 183.6,125.51 178.49,120.4 178.49,120.07 178.64,119.92 178.64,119.66 178.38,119.4 178.15,119.4 178.07,119.48 177.84,119.48 177.6,119.24 177.6,119 177.68,118.92 177.68,118.69 177.56,118.58 176.32,118.58 175.93,118.97 175.44,118.97 174.95,118.47 v1(174.95,118.25)
  BOTTOM w0.178: GPU1.F18 174.39,118.71 174.24,118.56 174.24,118.38 174.36,118.26 174.93,118.26 v1(174.95,118.25)
FBA_D2: length 45.5
  TOP w0.178: VRAM1.F2 181.97,146.02 181.97,146.7 182.28,147 v1(182.28,147.62) 182.28,149.12 v2(182.57,149.42)
  L3 w0.165: v1(182.28,147.62) 182.28,146.77 182.54,146.51 182.89,146.51 184.36,145.04 185.55,145.04 186.59,144.01 186.59,138.79 186.33,138.53 186.33,127.12 185.18,125.96 185.18,124.17 181.09,120.08 181.09,119.39 178.66,116.97 176.17,116.97 175.99,117.14 175.45,117.14 v1(174.94,116.63)
  BOTTOM w0.178: GPU1.E16 175.34,117.03 v1(174.94,116.63)
FBA_D3: length 43.2
  TOP w0.178: v1(181.11,145.19) 180.74,145.56 VRAM1.G2 ; v2(174.5,117.88) 174.52,117.86 174.52,117.82 v1(174.88,117.47)
  L3 w0.165: v1(181.11,145.19) 181.55,145.63 182.41,145.63 183.04,145 183.88,145 184.21,144.68 184.22,144.68 186.09,142.8 186.09,139.27 185.86,139.04 185.86,127.32 185.7,127.16 185.37,127.16 185.2,127.32 185.2,128.16 185.04,128.33 184.71,128.33 184.54,128.16 184.54,124.29 181.65,121.4 181.01,121.4 180.21,120.6 180.21,120.08 180.22,120.07 180.22,119.37 179.29,118.44 179.29,118.32 178.83,117.86 178.29,117.86 178.25,117.91 176.16,117.91 175.77,117.51 175.3,117.51 175.25,117.47 v1(174.88,117.47)
  BOTTOM w0.178: GPU1.F17 174.51,117.83 v1(174.88,117.47)
FBA_D4: length 40.1
  TOP w0.178: v1(179.88,137.79) 179.88,136.6 180.01,136.47 180.55,136.47 180.68,136.6 v2(180.68,137) 180.68,138.51 180.94,138.77 181.66,138.77 181.91,139.02 181.91,141.22 VRAM1.F7
  L3 w0.165: v1(175.75,120.72) 175.75,120.56 175.99,120.31 176.33,120.31 176.83,120.81 177.13,120.81 180.42,124.1 180.42,125.02 180.54,125.14 181.46,125.14 181.67,125.35 181.67,125.71 181.54,125.84 180.52,125.84 180.4,125.97 180.4,126.39 180.52,126.51 181.72,126.51 181.85,126.64 181.85,127.06 181.72,127.19 180.54,127.19 180.41,127.31 180.41,127.73 180.54,127.86 181.46,127.86 181.62,128.02 181.62,129.27 181.46,129.44 180.6,129.44 180.43,129.6 180.43,129.95 180.6,130.11 181.46,130.11 181.62,130.28 181.62,133.41 181.24,133.8 180.65,133.8 180.46,133.99 180.46,135.58 180.29,135.74 179.88,135.74 179.72,135.91 179.72,136.28 179.88,136.44 180.78,136.44 180.9,136.57 180.9,136.93 180.78,137.06 180.01,137.06 179.88,137.19 v1(179.88,137.79)
  BOTTOM w0.178: v1(175.75,120.72) 176.02,120.72 176.15,120.59 GPU1.D20
FBA_D5: length 38.3
  TOP w0.178: v1(176.56,121.6) 176.63,121.6 v2(177.18,121.04) ; VRAM1.H8 179.55,140.4 179.55,139.88 179.06,139.39 v1(178.79,139.39)
  L3 w0.165: v1(176.56,121.6) 177.04,122.08 177.04,122.48 178.76,124.2 178.76,124.43 178.51,124.68 178.51,124.92 178.75,125.16 178.98,125.16 179.23,124.91 179.47,124.91 179.71,125.15 179.71,128.02 179.26,128.48 178.84,128.48 178.68,128.64 178.68,129.04 178.85,129.2 179.36,129.2 179.49,129.33 179.49,129.75 179.36,129.88 177.87,129.88 177.74,130 177.74,130.42 177.87,130.55 179.22,130.55 179.39,130.72 179.39,131.06 179.22,131.22 177.71,131.22 177.58,131.35 177.58,131.8 177.71,131.93 178.95,131.93 179.08,132.05 179.08,132.6 178.95,132.73 178.37,132.73 178.05,133.04 178.05,133.96 177.85,134.16 177.02,134.16 176.89,134.29 176.89,134.7 177.02,134.83 178.18,134.83 178.31,134.96 178.31,135.38 178.18,135.5 176.88,135.5 176.75,135.63 176.75,136.09 176.88,136.22 177.47,136.22 177.62,136.37 177.62,139.58 177.95,139.92 178.66,139.92 178.79,139.79 v1(178.79,139.39)
  BOTTOM w0.178: v1(176.56,121.6) 176.56,121.16 176.45,121.05 176.29,121.05 GPU1.D21
FBA_D6: length 42.1
  TOP w0.178: VRAM1.H7 179.86,141.67 179.86,142.13 179.89,142.16 179.89,142.6 v1(180.08,142.79) ; v1(174.1,119.96) 174.1,119.43 v2(173.99,119.32)
  L3 w0.127: v1(174.1,119.96) 174.1,120.98 174.32,121.2 175.05,121.2 175.3,121.45 175.3,121.78 175.54,122.02 175.87,122.02 176.13,122.27 176.13,122.42
  L3 w0.165: v1(180.08,142.79) 176.95,139.66 176.95,139.24 176.24,138.53 176.24,133.77 176.4,133.6 177.13,133.6 177.26,133.48 177.26,133.03 177.13,132.91 175.88,132.91 175.76,132.78 175.76,132.33 175.88,132.21 176.8,132.21 176.96,132.04 176.96,131.67 176.8,131.51 175.98,131.51 175.85,131.38 175.85,130.79 175.98,130.66 176.93,130.66 177.25,130.35 177.25,129.13 177.41,128.97 177.96,128.97 178.12,128.8 178.12,128.43 177.96,128.27 177.11,128.27 176.98,128.14 176.98,127.55 177.11,127.42 179.27,127.42 179.43,127.26 179.43,126.91 179.27,126.75 178.88,126.75 178.71,126.58 178.71,126.34 178.94,126.11 178.94,125.74 178.52,125.31 177.23,125.31 177.1,125.18 177.1,124.71 177.23,124.58 178.11,124.58 178.26,124.43 178.26,124.09 177,122.82 176.39,122.82 176.13,122.56 176.13,122.42
  BOTTOM w0.178: v1(174.1,119.96) 174.49,120.35 GPU1.F20
FBA_D7: length 40.1
  TOP w0.178: VRAM1.F8 181.26,140.79 181,140.53 181,140.3 181.12,140.17 181.12,139.85 180.89,139.62 180.49,139.62 180.36,139.49 180.36,138.77 180.01,138.43 v1(179.85,138.43) ; v2(175.33,121.18) 175.33,121.11 v1(174.97,120.74)
  L3 w0.165: v1(174.97,120.74) 175.39,121.16 175.93,121.16 176.13,120.96 176.56,120.96 176.75,121.16 177.1,121.16 177.21,121.27 177.21,121.5 177.15,121.55 177.15,121.79 177.4,122.03 177.63,122.03 177.68,121.98 177.91,121.98 178.15,122.21 178.15,122.47 177.89,122.72 177.89,122.87 178.34,123.32 178.53,123.32 178.74,123.11 179.03,123.11 179.19,123.27 179.19,123.58 178.99,123.78 178.99,124.01 179.23,124.26 179.46,124.26 179.72,124 179.94,124 180.11,124.17 180.11,128.43 179.96,128.58 179.96,130.59 180.13,130.76 180.42,130.76 180.63,130.97 180.63,131.32 180.53,131.43 179.71,131.43 179.59,131.56 179.59,131.98 179.71,132.1 181,132.1 181.13,132.23 181.13,132.65 181,132.78 180.13,132.78 179.96,132.94 179.96,133.7 179.8,133.87 178.65,133.87 178.52,133.99 178.52,134.41 178.65,134.54 179.8,134.54 179.96,134.7 179.96,135.05 179.8,135.21 179.33,135.21 179.21,135.34 179.21,136.41 179.03,136.59 178.47,136.59 178.34,136.72 178.34,137.19 178.47,137.32 179.19,137.32 179.36,137.49 179.36,137.85 179.19,138.02 178.22,138.02 178.09,138.15 178.09,138.7 178.22,138.83 179.45,138.83 v1(179.85,138.43)
  BOTTOM w0.178: GPU1.E21 175.08,121.19 174.97,121.07 v1(174.97,120.74)
FBA_D8: length 48.6
  TOP w0.178: VRAM1.C8 183.94,141.05 184.1,141.21 v1(184.34,141.21) ; v2(175.38,115.41) 175.74,115.77 v1(175.74,115.85)
  L4 w0.127: v1(175.74,115.85) 175.74,116 176.54,116.8 176.87,116.8 177.12,117.06 179.11,117.06
  L4 w0.165: v1(184.34,141.21) 184.34,141.55 184.43,141.63 185.28,141.63 185.55,141.36 185.55,140.47 185.72,140.31 185.95,140.31 186.11,140.46 186.34,140.46 186.56,140.24 186.56,140.01 185.72,139.17 185.72,138.99 186.03,138.68 186.21,138.68 186.93,139.39 187.16,139.39 187.65,138.91 187.65,138.71 188.71,137.64 188.71,135.47 189.24,134.94 189.24,132.68 188.71,132.15 188.71,122.99 188.34,122.61 188.34,122.37 188.71,122 188.71,121.77 188.48,121.53 188.24,121.53 187.87,121.91 187.64,121.91 187.4,121.67 187.4,121.44 187.85,120.99 187.85,120.76 187.62,120.53 187.38,120.53 186.93,120.97 186.7,120.97 186.47,120.74 186.47,120.51 186.7,120.27 186.7,120.04 186.47,119.8 186.24,119.8 186,120.04 185.77,120.04 185.44,119.71 184.32,119.71 183.95,119.34 183.95,118.7 184.07,118.57 184.49,118.57 184.61,118.44 184.61,118.12 184.43,117.93 183.54,117.93 182.48,116.87 179.83,116.87 179.64,117.06 179.11,117.06
  BOTTOM w0.178: v1(175.74,115.85) 175.51,115.85 175.35,116.01 GPU1.E15
FBA_D9: length 51.2
  TOP w0.178: v2(187.65,138.42) 187.19,138.42 v1(187.1,138.52) 187.1,140.22 186.97,140.35 186.47,140.35 186.34,140.22 186.34,137.92 186.19,137.76 183.72,137.76 183.6,137.89 183.6,138.32 183.72,138.45 185.49,138.45 185.62,138.58 185.62,139.01 185.49,139.13 184.55,139.13 184.32,139.36 184.32,140.56 184.56,140.79 VRAM1.B8
  L4 w0.127: 179.11,117.33 176.97,117.33 176.67,117.03 176.33,117.03 176.07,117.29 175.83,117.29 175.67,117.12 175.67,116.74 v1(175.77,116.64)
  L4 w0.165: 179.11,117.33 179.75,117.33 179.94,117.14 182.34,117.14 183.58,118.37 183.58,119.35 184.2,119.98 184.73,119.98 185.21,120.46 185.51,120.46 188.24,123.19 188.24,132.77 188.41,132.94 188.6,132.94 188.77,133.1 188.77,133.43 188.6,133.6 188.41,133.6 188.24,133.76 188.24,134.09 188.41,134.26 188.6,134.26 188.77,134.42 188.77,134.75 188.6,134.92 188.41,134.92 188.24,135.08 188.24,136.08 187.78,136.54 187.78,136.77 188.18,137.16 188.18,137.4 187.94,137.63 187.71,137.63 187.32,137.24 187.08,137.24 186.89,137.43 186.89,138.31 v1(187.1,138.52)
  BOTTOM w0.178: v1(175.77,116.64) 175.78,116.65 176.44,116.65 176.58,116.51 176.58,116.33 176.48,116.23 GPU1.D15
FBA_D10: length 50.1
  TOP w0.178: VRAM1.D7 182.97,141.59 182.7,141.86 182.7,143.73 182.83,143.86 183.15,143.86 183.32,143.68 183.83,143.68 183.96,143.56 183.96,143.2 183.83,143.07 183.53,143.07 183.39,142.94 183.39,142.68 v1(183.64,142.44)
  L4 w0.127: v1(174.93,115.74) 175.24,115.43 175.92,115.43 176.17,115.68 176.17,115.97 176.77,116.57 176.96,116.57 177.18,116.79 179.11,116.79
  L4 w0.165: v1(183.64,142.44) 183.95,142.44 184.39,142 186.03,142 186.23,141.79 186.23,141.44 186.12,141.33 186.12,141.03 186.32,140.83 186.55,140.83 186.84,141.12 187.07,141.12 187.35,140.84 187.35,140.52 187.16,140.33 187.16,139.96 189.71,137.41 189.71,137.12 189.55,136.96 189.36,136.96 189.19,136.79 189.19,136.46 189.36,136.3 189.55,136.3 189.71,136.13 189.71,132.49 189.18,131.95 189.18,121.4 186.4,118.62 185.7,118.62 184.62,117.54 183.6,117.54 182.67,116.6 179.72,116.6 179.53,116.79 179.11,116.79
  BOTTOM w0.178: GPU1.F15 174.51,115.98 174.75,115.74 v1(174.93,115.74)
FBA_D11: length 51.9
  TOP w0.178: VRAM1.A7 185.84,141.59 v2(187.49,143.25) 188.05,143.8 v1(188.14,143.8)
  L4 w0.127: 178.47,114.18 176.43,114.18 176.06,114.55 175.52,114.55 175.37,114.4 175.03,114.4 174.84,114.59 174.84,114.92 v1(174.9,114.98)
  L4 w0.165: 178.47,114.18 179.22,114.18 179.43,114.39 179.43,114.79 179.61,114.97 184.1,114.97 184.38,115.26 186.5,115.26 186.67,115.42 186.67,115.57 186.81,115.7 187.27,115.7 187.37,115.6 187.37,115.42 187.53,115.26 187.76,115.26 189.45,116.95 189.45,117.18 189.33,117.3 189.33,117.48 189.65,117.8 189.83,117.8 189.95,117.68 190.18,117.68 192.31,119.8 192.31,129.11 192.56,129.36 192.56,139.39 188.47,143.47 v1(188.14,143.8)
  BOTTOM w0.178: v1(174.9,114.98) 174.51,114.59 GPU1.F13
FBA_D12: length 50.2
  TOP w0.178: v2(187.38,146.13) 187.38,146.13 187.33,146.13 186.78,145.58 v1(186.76,145.58) 186.37,145.19 184.28,145.19 183.94,145.53 VRAM1.C2
  L4 w0.127: v1(176.58,114.97) 176.98,114.57 177.89,114.57 178.14,114.81 178.14,115.56 178.38,115.81 179.13,115.81 179.36,115.58
  L4 w0.165: 179.36,115.58 183.64,115.58 184.13,116.07 185.19,116.07 185.83,116.71 187.2,116.71 191.22,120.74 191.22,129.59 191.62,129.98 191.62,139 187.73,142.89 187.73,143.03 186.17,144.59 186.17,144.99 v1(186.76,145.58)
  BOTTOM w0.178: v1(176.58,114.97) 176.58,114.72 176.76,114.55 GPU1.C13
FBA_D13: length 49.9
  TOP w0.178: v1(187.63,144.51) 186.47,143.36 185.59,143.36 184.16,144.79 VRAM1.C3 ; v2(179.29,115.81) 179.01,115.53 v1(179.01,114.94)
  L4 w0.165: v1(179.01,114.94) 179.39,115.32 183.94,115.32 184.35,115.73 186.16,115.73 186.62,116.18 187.33,116.18 189.63,118.48 189.87,118.48 190,118.35 190.18,118.35 190.49,118.67 190.49,118.85 190.36,118.98 190.36,119.21 190.62,119.47 190.86,119.47 190.99,119.34 191.17,119.34 191.48,119.65 191.48,119.83 191.35,119.97 191.35,120.2 191.78,120.63 191.78,129.32 192.09,129.62 192.09,139.19 188.28,143 187.2,144.08 187.2,144.32 187.39,144.51 v1(187.63,144.51)
  BOTTOM w0.178: v1(179.01,114.94) 179,114.93 178.13,114.93 GPU1.B13
FBA_D14: length 52.9
  TOP w0.178: v2(188.6,145.8) 188.53,145.73 v1(188.05,145.73) 187.11,144.79 VRAM1.A3
  L4 w0.127: v1(175.74,114.13) 176.03,113.84 178.91,113.84
  L4 w0.165: 178.91,113.84 181.68,113.84 182.15,114.31 184.48,114.31 184.69,114.52 185.21,114.52 185.47,114.25 188.09,114.25 193.27,119.43 193.27,128.67 193.5,128.9 193.5,139.78 189.41,143.86 189.41,144.36 v1(188.05,145.73)
  BOTTOM w0.178: GPU1.E13 175.37,114.55 175.74,114.18 175.74,114.13 v1(175.74,114.13)
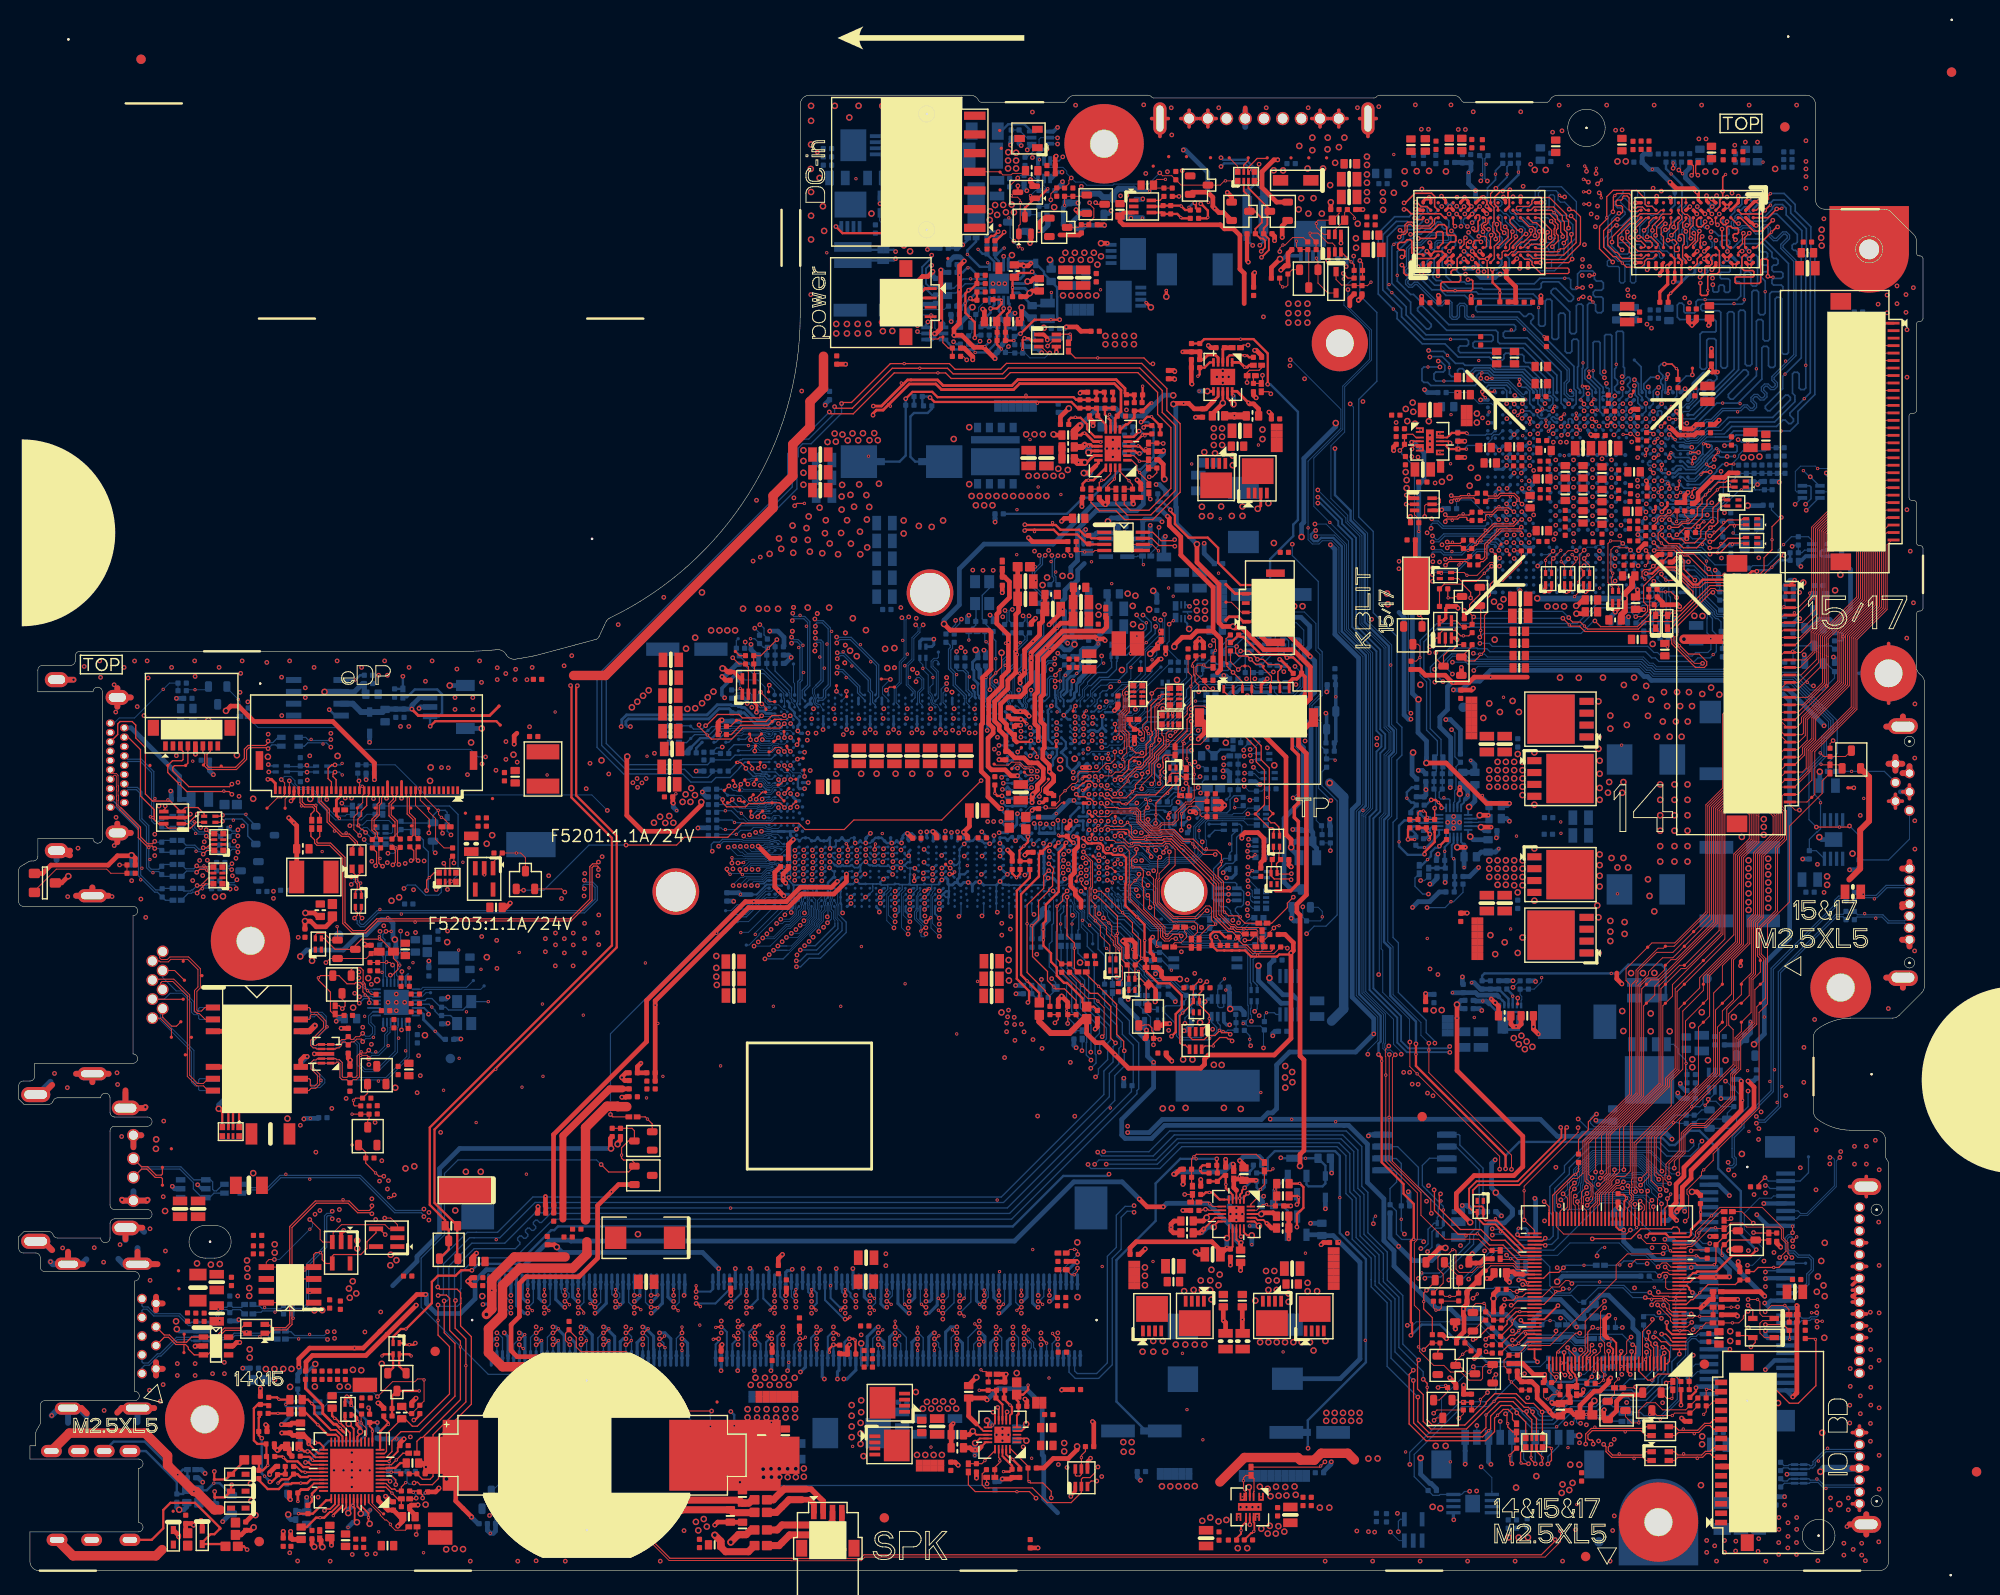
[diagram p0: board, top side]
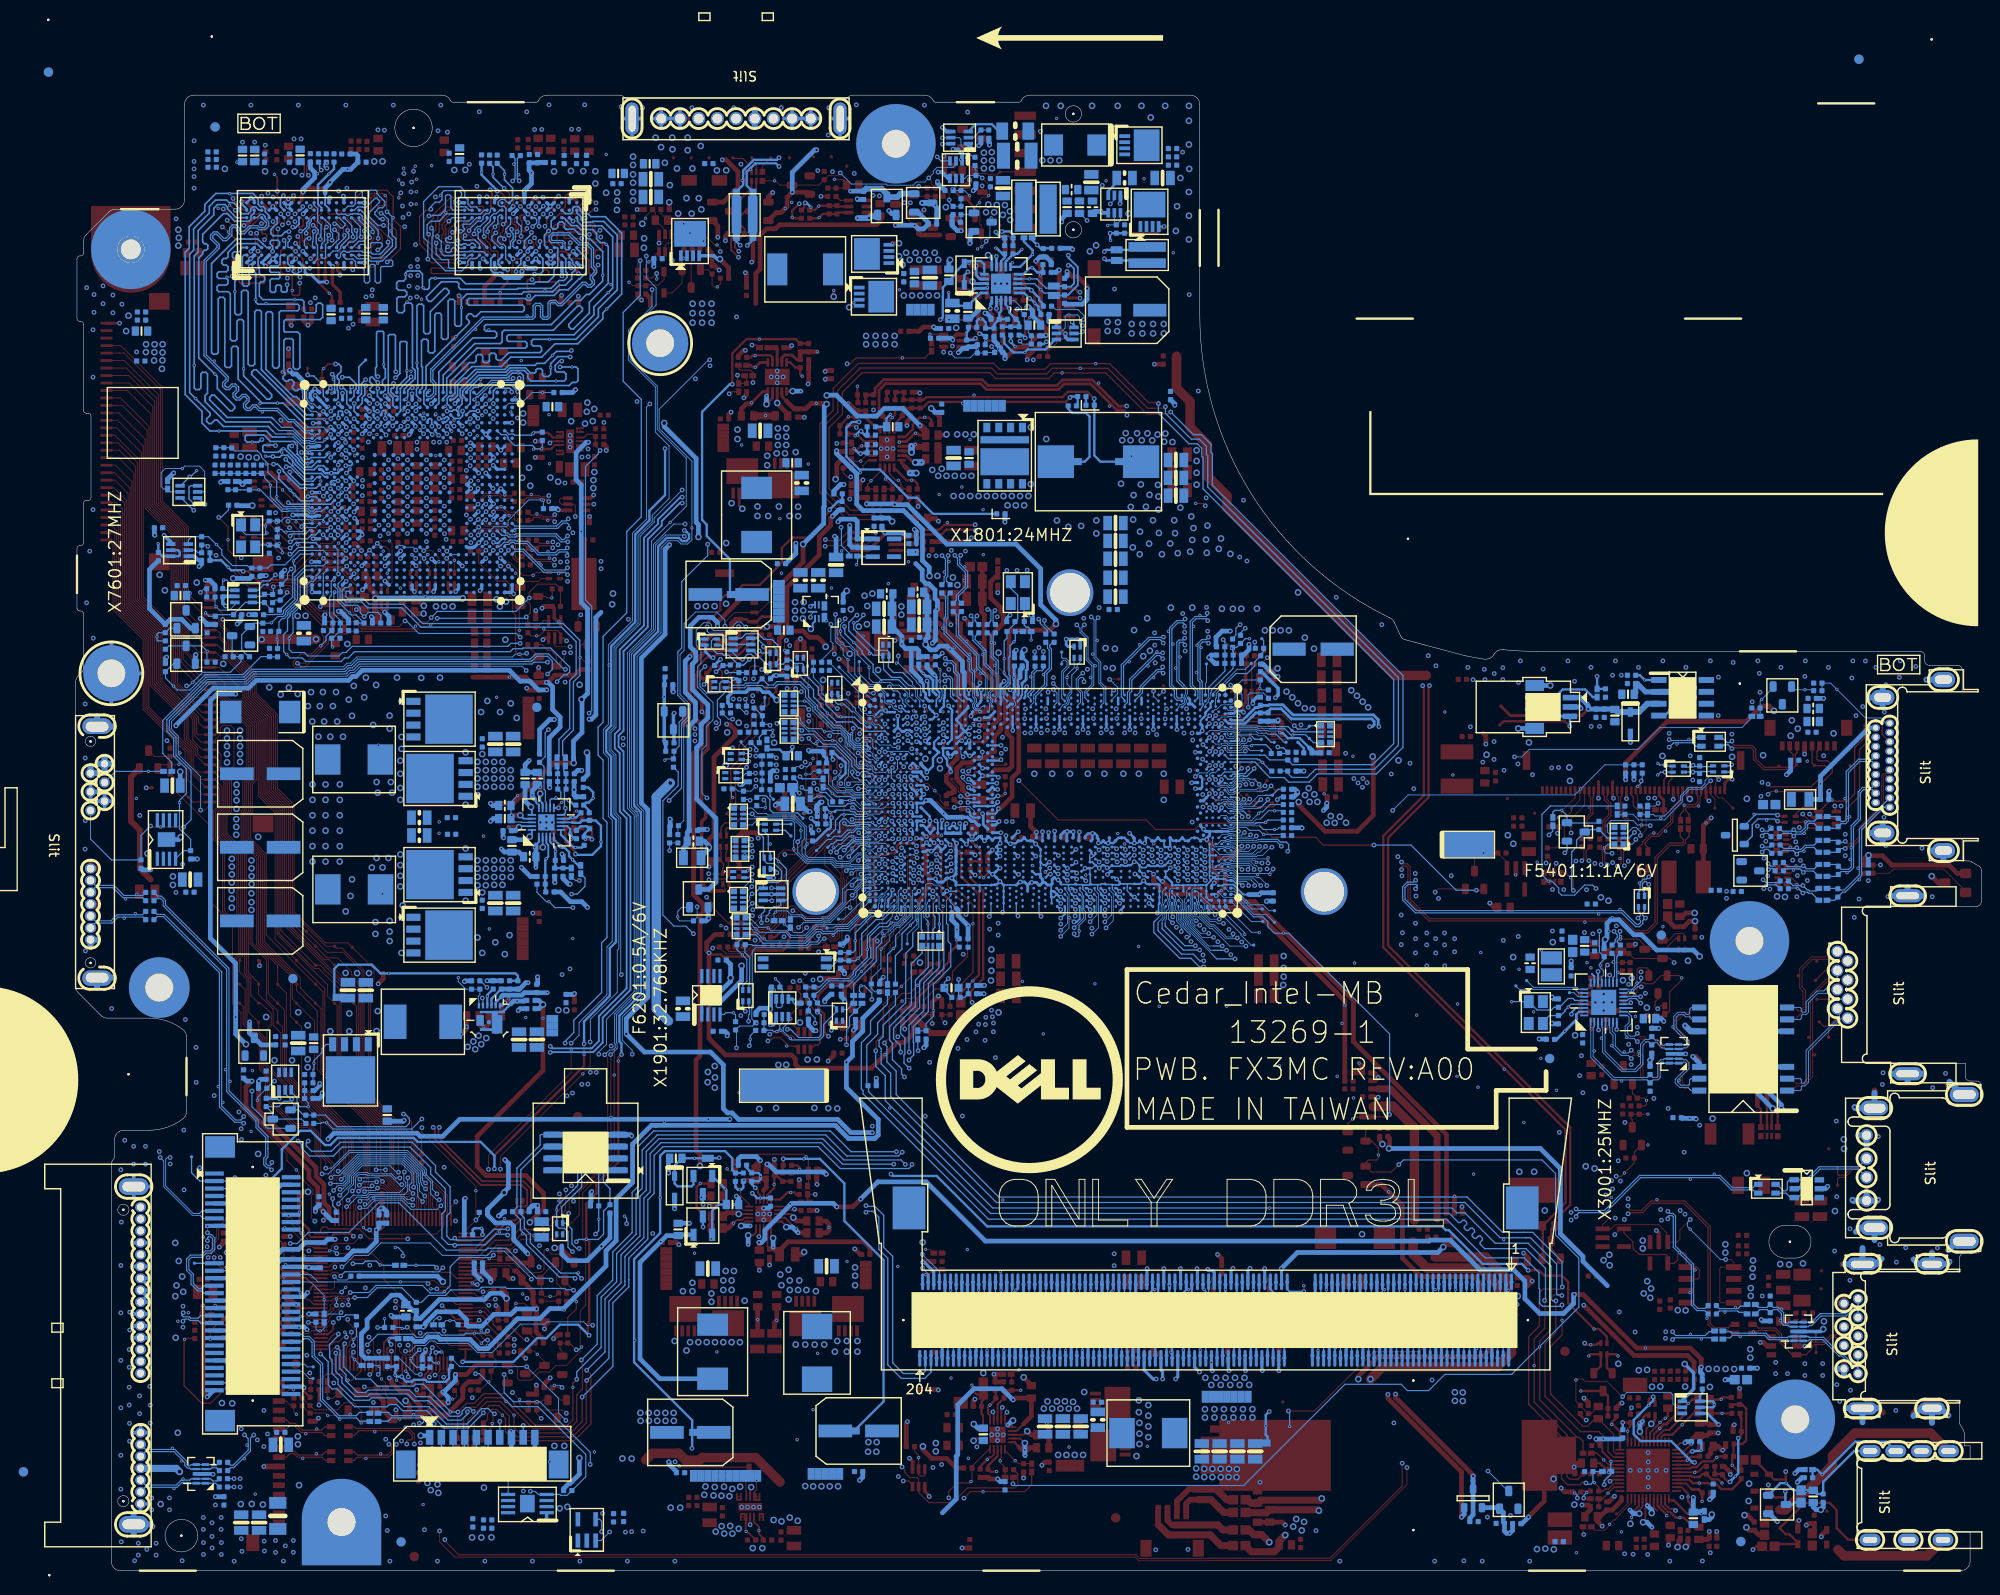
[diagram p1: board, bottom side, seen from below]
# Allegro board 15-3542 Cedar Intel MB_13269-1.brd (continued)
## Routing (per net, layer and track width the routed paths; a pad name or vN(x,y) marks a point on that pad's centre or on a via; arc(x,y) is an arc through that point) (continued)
FBA_D15: length 52.1
  TOP w0.178: v2(187.37,147.36) 187,146.99 v1(187,146.85) 187,146.72 185.87,145.59 VRAM1.A2
  L4 w0.165: v1(181.11,114.29) 181.43,114.61 184.11,114.61 184.29,114.79 187.95,114.79 192.79,119.62 192.79,128.91 193.03,129.15 193.03,139.58 188.94,143.67 188.94,144.17 188.16,144.95 187.55,144.95 187.2,145.3 187.2,145.78 187.37,145.95 187.37,146.48 v1(187,146.85)
  BOTTOM w0.178: GPU1.D13 176.15,114.55 176.56,114.13 180.95,114.13 v1(181.11,114.29)
FBA_D16: length 42.4
  TOP w0.178: v1(182.67,118.41) 183.31,118.41 183.33,118.43 v2(183.46,118.43)
  L4 w0.165: v1(182.67,118.41) 183.25,118.99 183.25,119.42 184.08,120.24 184.46,120.24 185.25,121.04 185.25,121.16 187.57,123.47 187.57,135.63 186.16,137.04 186.16,137.96 184.51,139.61 184.51,140.42 183.91,141.03 183.91,141.55 183.2,142.25 183.2,144.78 181.62,146.36 v1(181.62,147.16)
  BOTTOM w0.178: GPU1.B15 178.13,115.85 179.84,115.85 181.63,117.64 181.63,117.81 182.23,118.41 v1(182.67,118.41) ; v1(181.62,147.16) 181.92,146.85 181.92,145.97 VRAM2.F8
FBA_D17: length 38.5
  L4 w0.165: v1(182.75,119.24) 182.75,119.66 183.65,120.57 184.22,120.57 184.88,121.23 184.88,121.45 187.1,123.66 187.1,135.31 185.75,136.66 185.75,137.83 184.07,139.51 184.07,140.34 183.54,140.87 183.54,141.4 182.83,142.1 182.83,143.58 181.9,144.52 v1(181.9,145.19)
  BOTTOM w0.178: v1(181.9,145.19) 181.9,145.15 VRAM2.F7 ; GPU1.C16 177.17,117.03 177.57,117.42 179.38,117.42 180.63,118.68 180.63,118.8 180.97,119.14 181.19,119.36 181.82,119.36 182.02,119.16 182.67,119.16 v1(182.75,119.24) 183.5,119.24 v2(183.53,119.27)
FBA_D18: length 39.9
  L4 w0.165: v1(180.62,143.78) 181.35,143.78 182.45,142.68 182.45,141.88 182.11,141.54 182.11,140.36 182.7,139.77 182.7,139.28 184.12,137.86 184.44,137.86 184.65,137.65 184.65,137.32 184.49,137.16 184.22,137.16 184.12,137.05 184.12,136.7 184.45,136.36 184.72,136.36 186.16,134.92 186.16,124.05 184.43,122.33 184.43,122.13 183.81,121.52 183.62,121.52 183.47,121.66 183.23,121.66 183.07,121.5 183.07,121.1 183.33,120.84 183.33,120.63 182.66,119.96 182.33,119.96 182.17,119.79 182.17,119.57 182.3,119.44 182.3,118.65 181.87,118.23 181.87,117.87 v1(182.1,117.65)
  BOTTOM w0.178: v1(182.1,117.65) 182.1,116.84 v2(180.89,115.63) 179.75,114.49 178.61,114.49 GPU1.A13 ; v1(180.62,143.78) 180.52,143.68 180.36,143.68 179.94,144.1 179.94,144.19 179.94,144.19 179.94,144.56 179.94,144.79 VRAM2.H7
FBA_D19: length 40.5
  TOP w0.178: v1(180.94,117.58) 180.19,117.58 v2(179.94,117.33)
  L4 w0.165: v1(179.55,145.98) 179.9,146.33 180.49,146.33 180.63,146.19 180.63,145.79 180.51,145.67 180.2,145.67 179.94,145.41 179.94,144.91 179.52,144.5 179.52,144.03 179.65,143.91 180.09,143.91 180.18,143.81 180.18,143.53 180.52,143.19 180.52,142.49 180.76,142.25 180.76,140.24 180.63,140.1 180.63,139.08 180.75,138.97 180.75,136.95 183.67,134.03 183.67,128.92 184.19,128.4 184.19,126.1 184.07,125.98 183.61,125.98 180.83,123.19 180.83,121.45 181.04,121.23 181.04,120.97 180.9,120.82 180.48,120.82 180.21,120.56 180.21,120.15 180.93,119.43 180.93,118.41 180.72,118.19 180.72,117.79 v1(180.94,117.58)
  BOTTOM w0.178: VRAM2.H8 179.79,145.59 179.55,145.83 v1(179.55,145.98) ; v1(180.94,117.58) 180.94,117.34 179.83,116.23 GPU1.A15
FBA_D20: length 40.1
  TOP w0.178: v2(180.22,120.58) 180.52,120.58 v1(180.73,120.37)
  L4 w0.165: v1(180.73,120.37) 180.65,120.28 180.65,120.1 180.93,119.82 181.16,119.82 181.35,120.01 181.35,120.63 181.54,120.82 181.54,121.19 181.13,121.6 181.13,122.21 181.41,122.49 181.41,122.72 181.24,122.88 181.24,123.09 183.7,125.56 184.27,125.56 184.46,125.74 184.46,128.51 184.14,128.82 184.14,134.22 181.65,136.71 181.65,136.92 182.19,137.47 182.19,137.7 181.99,137.9 181.49,137.9 v1(181.21,137.62)
  BOTTOM w0.178: VRAM2.F2 181.83,140.79 181.97,140.65 181.97,139.83 182.18,139.62 182.95,139.62 183.07,139.49 183.07,139.07 182.95,138.94 182.13,138.94 182,138.81 182,138.38 182.13,138.25 182.88,138.25 183.04,138.09 183.04,136.97 182.88,136.8 182.58,136.8 182.45,136.93 182.45,137.43 182.3,137.57 181.99,137.57 181.84,137.43 181.84,136.96 181.72,136.83 181.34,136.83 181.21,136.96 v1(181.21,137.62) ; v1(180.73,120.37) 180.84,120.47 181.01,120.47 181.13,120.35 181.13,120.1 180.41,119.38 179.97,118.93 179.97,118.81 179.27,118.11 178.59,118.11 177.99,118.71 GPU1.B18
FBA_D21: length 38
  L4 w0.165: v1(183.92,121.04) 185.28,122.39 185.28,122.51 186.63,123.86 186.63,135.12 185.29,136.45 185.29,137.73 184.64,138.38 184.12,138.38 183.07,139.44 183.07,139.85 183.32,140.1 183.32,140.52 182.78,141.06 v1(182.78,141.18)
  BOTTOM w0.178: v1(182.78,141.18) 182.78,141.43 182.77,141.44 182.77,141.74 183.03,142 183.03,142.24 182.89,142.38 182.2,142.38 182.03,142.2 182.03,141.88 182.32,141.59 VRAM2.E3 ; GPU1.A18 178.69,118.57 179.34,118.57 179.69,118.92 179.69,119.05 180.13,119.49 180.13,120.5 180.48,120.85 183.01,120.85 183.69,121.53 185.58,121.53 185.71,121.4 185.71,120.97 185.52,120.78 v2(184.96,120.78) 184.28,120.78 184.03,121.04 v1(183.92,121.04)
FBA_D22: length 38.6
  TOP w0.178: v1(179.69,119.68) 178.84,119.68 v2(178.81,119.65)
  L4 w0.165: v1(179.69,119.68) 179.58,119.78 178.95,119.78 178.8,119.63 178.8,117.79 178.67,117.66 178.37,117.66 178.24,117.79 178.24,120.75 178.35,120.85 178.58,120.85 178.69,120.74 179.59,120.74 180.03,121.19 180.03,122.63 179.88,122.79 179.61,122.79 179.42,122.97 179.42,123.18 179.91,123.68 180.36,123.68 180.54,123.86 180.54,124.31 180.91,124.68 181.24,124.68 182.48,125.91 182.48,126.31 182.64,126.47 182.68,126.47 182.84,126.64 182.84,126.88 182.68,127.05 182.64,127.05 182.48,127.21 182.48,127.46 182.64,127.62 182.68,127.62 182.84,127.79 182.84,128.03 182.68,128.2 182.64,128.2 182.48,128.36 182.48,128.65 182.73,128.9 182.73,133.64 179.4,136.96 179.4,139 179.23,139.17 179.23,139.64 179.37,139.79 179.69,139.79 179.86,139.96 179.86,140.46 179.69,140.63 179.11,140.63 178.93,140.8 178.93,141.21 179.47,141.74 180.1,141.74 180.32,141.96 v1(180.32,142.05)
  BOTTOM w0.178: v1(179.69,119.68) 179.56,119.55 178.97,119.55 178.93,119.51 GPU1.A19 ; v1(180.32,142.05) 179.94,141.67 VRAM2.H3
FBA_D23: length 38
  TOP w0.178: v1(179.23,119.1) 179.01,118.88 v2(179.01,118.45)
  L4 w0.165: v1(179.86,139.17) 180.32,138.72 180.32,137.61 180.07,137.35 180.07,136.96 183.2,133.83 183.2,128.46 183.36,128.3 183.75,128.3 183.91,128.13 183.91,127.89 183.75,127.72 183.16,127.72 183.04,127.59 183.04,127.27 183.16,127.15 183.75,127.15 183.91,126.98 183.91,126.74 183.75,126.57 183.36,126.57 183.2,126.41 183.2,126.13 180.44,123.37 180.44,121.17 179.95,120.68 179.95,120.04 180.59,119.4 180.59,119.07 180.47,118.95 179.9,118.95 179.78,118.82 179.78,118.47 179.9,118.35 180.35,118.35 180.46,118.24 180.46,117.84 180.3,117.69 179.28,117.69 179.15,117.81 179.15,119.02 v1(179.23,119.1)
  BOTTOM w0.178: v1(179.23,119.1) 179.09,118.95 178.85,118.95 178.67,119.12 177.2,119.12 176.95,119.38 GPU1.C19 ; v1(179.86,139.17) 179.86,139.06 180.13,138.8 180.47,138.8 180.66,138.98 180.66,139.13 180.53,139.26 180.53,139.51 180.64,139.62 180.89,139.62 181.17,139.9 181.17,140.56 180.94,140.79 VRAM2.G2
FBA_D24: length 43.8
  BOTTOM w0.127: 179.21,124.61 178.65,124.05 178.11,124.05 GPU1.B24
  BOTTOM w0.178: VRAM2.A2 185.82,140.79 186,140.61 186,137.65 185.82,137.47 185.47,137.47 185.29,137.65 185.29,138.84 185.11,139.02 184.76,139.02 184.58,138.84 v2(184.58,136.01) 184.58,135.77 184.35,135.54 180.1,135.54 179.92,135.36 179.92,135.01 180.1,134.83 181.89,134.83 182.06,134.66 182.06,128.9 182.27,128.69 182.57,128.69 182.78,128.9 182.78,134.55 182.95,134.72 183.31,134.72 183.49,134.55 183.49,128.57 180.56,125.65 180.25,125.65 179.21,124.61
FBA_D25: length 46.1
  BOTTOM w0.127: 178.82,123.26 177.37,123.26 GPU1.C23
  BOTTOM w0.178: VRAM2.C3 184.01,141.59 184.43,142.01 186.6,142.01 187.54,141.07 187.54,140.61 187.72,140.43 188.01,140.43 188.19,140.25 188.19,139.89 188.01,139.72 187.72,139.72 187.54,139.54 187.54,139.18 187.72,139 188.54,139 188.71,138.83 188.71,138.47 188.54,138.29 187.72,138.29 187.54,138.12 187.54,137.76 187.72,137.58 188.54,137.58 188.71,137.4 188.71,137.05 188.54,136.87 187.52,136.87 187.3,136.65 187.3,131.79 187.12,131.61 186.77,131.61 186.59,131.79 186.59,133.71 186.41,133.89 186.05,133.89 185.88,133.71 v2(185.88,128.62) 185.88,127.87 183.38,125.37 183.09,125.37 182.88,125.59 182.88,125.87 185.01,128.01 185.01,128.26 184.76,128.51 184.51,128.51 179.26,123.26 178.82,123.26
FBA_D26: length 41.3
  BOTTOM w0.127: GPU1.A25 178.62,124.49 179.57,125.44 179.57,126.09
  BOTTOM w0.178: 179.57,126.09 179.57,126.27 179.74,126.44 179.99,126.44 180.14,126.29 180.39,126.29 180.64,126.54 180.64,126.79 180.49,126.94 180.49,127.19 180.74,127.44 180.99,127.44 181.15,127.29 181.4,127.29 181.65,127.54 181.65,127.79 181.45,127.99 181.45,128.16 181.57,128.27 181.57,131.67 181.39,131.85 180.74,131.85 180.56,131.67 180.56,128.77 180.36,128.56 180.06,128.56 179.85,128.77 179.85,132.32 180.09,132.56 181.46,132.56 181.57,132.66 181.57,133.71 181.39,133.89 177.68,133.89 177.42,134.15 177.42,135.44 177.62,135.64 177.91,135.64 178.11,135.44 178.11,134.75 178.27,134.6 179.24,134.6 179.42,134.78 179.42,135.8 179.64,136.02 v2(180.39,136.02) 183.81,136.02 184.2,136.4 184.2,137.76 184.02,137.94 183.8,137.94 183.62,138.11 183.62,138.47 183.8,138.65 184.02,138.65 184.2,138.82 184.2,139.59 184.32,139.71 184.32,140.41 VRAM2.C2
FBA_D27: length 42.5
  BOTTOM w0.178: GPU1.A24 179.14,123.69 183.97,128.52 183.97,134.71 184.15,134.89 184.51,134.89 184.68,134.71 184.68,129.13 184.86,128.95 185.22,128.95 185.39,129.13 185.39,136.83 185.57,137.01 185.93,137.01 186.11,136.83 186.11,134.59 186.28,134.41 186.64,134.41 186.82,134.59 v2(186.82,136.87) 186.82,138.01 186.39,138.43 186.39,138.78 186.61,139 186.96,139 187.14,139.18 187.14,139.54 186.96,139.71 186.56,139.71 186.38,139.89 186.38,140.25 186.56,140.42 186.89,140.42 187.07,140.6 187.07,140.96 186.89,141.14 186.37,141.14 186.19,141.31 186.19,141.47 186.07,141.59 VRAM2.A3
FBA_D28: length 45.2
  BOTTOM w0.127: 182.69,123.24 181.81,122.36 180.64,122.36 179.47,121.19 GPU1.A21
  BOTTOM w0.178: 182.69,123.24 182.86,123.41 187.62,123.41 189.51,125.3 189.51,125.55 189.26,125.8 189.01,125.8 187.34,124.13 187.09,124.13 186.83,124.38 186.83,124.64 188.69,126.49 188.69,127.81 v2(188.94,128.05) 190.68,129.79 190.68,140.48 190.26,140.9 190.26,141.12 190.08,141.3 189.88,141.3 189.7,141.48 189.7,141.83 189.88,142.01 190.08,142.01 190.26,142.19 190.26,143 188.05,145.21 187.62,145.21 186.82,144.41 185.3,144.41 185.11,144.6 185.11,144.94 184.74,145.31 VRAM2.B8
FBA_D29: length 44.9
  BOTTOM w0.127: GPU1.B21 178.05,121.19 178.4,120.83 178.7,120.83 178.8,120.94 179.55,120.94 180.63,122.01 182.11,122.01 182.76,122.66
  BOTTOM w0.178: 182.76,122.66 183.03,122.93 187.82,122.93 189.99,125.1 189.99,125.3 189.99,125.75 189.74,126.01 189.74,128.07 189.92,128.25 190.27,128.25 190.45,128.07 190.45,126.57 190.63,126.4 190.98,126.4 191.16,126.57 v2(191.16,129) 191.16,140.69 190.74,141.11 190.74,143.41 189.06,145.09 189.06,145.8 188.66,146.2 187.89,146.2 187.6,145.91 187.6,145.73 186.66,144.79 VRAM2.A7
FBA_D30: length 49
  BOTTOM w0.127: GPU1.C20 177.43,119.87 178.72,119.87 178.79,119.8 179.13,119.8 179.38,120.05 179.38,120.11 180.59,121.32 181.49,121.32
  BOTTOM w0.178: 181.49,121.32 182.79,121.32 183.44,121.96 v2(188.52,121.96) 189.48,121.96 190.32,122.81 190.32,124.06 192.13,125.87 192.13,141.09 191.7,141.51 191.7,143.81 190.03,145.49 190.03,146.2 188.84,147.39 184.87,147.39 184.32,146.83 184.32,146.23 184.06,145.97 183.78,145.97 183.56,145.75 183.56,145.41 183.14,145 VRAM2.D7
FBA_D31: length 46.6
  BOTTOM w0.127: GPU1.C21 177.37,120.77 178.15,120.77 178.31,120.61 178.79,120.61 178.87,120.69 179.63,120.69 180.58,121.64 182.43,121.64 182.73,121.94
  BOTTOM w0.178: VRAM2.C8 184.22,145.59 184.59,145.96 184.89,145.96 185.12,145.73 185.12,145.47 185.37,145.22 186.07,145.22 186.32,145.47 186.32,145.77 186.95,146.4 187.42,146.4 187.7,146.68 188.86,146.68 189.55,146 189.55,145.29 191.22,143.61 191.22,141.31 191.64,140.89 191.64,126.07 v2(191,125.42) 189.46,123.89 189.46,123.63 189.84,123.26 189.84,123.01 189.59,122.76 189.34,122.76 188.96,123.13 188.71,123.13 188.02,122.45 183.23,122.45 182.73,121.94
FBA_D32: length 43.9
  L3 w0.165: v1(153.01,145.19) 152.8,145.4 152.4,145.4 152.19,145.19 152.19,144.08 151.38,143.27 151.38,140.84 151.22,140.68 150.76,140.68 150.6,140.51 150.6,140.15 150.76,139.98 151.22,139.98 151.38,139.82 151.38,139.34 150.87,138.82 150.87,138.35 152.43,136.78 152.43,135.74 152.87,135.3 160.05,128.12 160.23,128.12 160.54,128.44 160.54,128.62 157.91,131.25 157.91,131.43 158.22,131.75 158.4,131.75 161.21,128.93 161.21,127.79 163.05,125.95 163.59,125.95 164.99,124.55 164.99,123.91 166.17,122.73 166.17,122.12 v1(166.62,121.66)
  BOTTOM w0.127: v1(153.01,145.19) 153.01,145.19 153.4,144.79 VRAM3.E3
  BOTTOM w0.178: v1(166.62,121.66) GPU1.R22
FBA_D33: length 41.5
  TOP w0.178: v1(166.61,123.31) v2(166.61,123.87)
  L3 w0.165: v1(154.68,145.19) 154.68,144.64 154.41,144.38 153.53,144.38 153.47,144.31 153.46,144.31 153.2,144.06 153.2,144.05 153.19,144.04 153.19,144.04 152.12,142.96 152.12,139.26 152.39,138.99 152.39,138.04 154.05,136.38 154.05,136.1 153.85,135.9 153.85,135.67 154.11,135.41 154.34,135.41 154.42,135.48 154.65,135.48 155.03,135.11 155.03,134.94 154.91,134.82 154.91,134.59 155.3,134.2 155.53,134.2 156.27,134.94 158.58,134.94 160.73,132.79 160.73,132.61 160.42,132.29 160.24,132.29 158.28,134.25 158.1,134.25 157.79,133.94 157.79,133.76 164.76,126.79 164.76,126.36 165.81,125.31 165.98,125.31 166.24,125.05 166.24,124.19 166.61,123.82 v1(166.61,123.31)
  BOTTOM w0.178: VRAM3.G2 154.68,145.23 v1(154.68,145.19) ; GPU1.R24 166.99,123.69 v1(166.61,123.31)
FBA_D34: length 40.7
  L3 w0.165: v1(155.47,144.26) 155.53,144.26 155.91,144.64 155.91,145.36 155.84,145.44 155.84,146.17 155.55,146.46 152.07,146.46 151.78,146.17 151.78,144.19 150.19,142.6 150.19,139.29 150.5,138.98 150.5,138.15 151.42,137.23 151.42,136.09 159.93,127.57 160.69,127.57 162.75,125.52 163.36,125.52 164.54,124.34 164.54,123.91 164.52,123.88 164.52,122.2 164.77,121.94 165.35,121.94 v1(165.71,121.59)
  BOTTOM w0.178: v1(155.47,144.26) 155.53,144.26 155.84,144.57 VRAM3.H3 ; GPU1.T22 166.17,122.05 v1(165.71,121.59)
FBA_D35: length 42.8
  TOP w0.178: v2(167.05,122.06) 166.97,122.06 v1(166.61,122.42)
  L3 w0.165: v1(153.82,146.02) 153.82,145.78 154.24,145.36 154.24,145 153.99,144.74 152.84,144.74 152.61,144.52 152.61,143.98 151.75,143.12 151.75,139.12 151.38,138.76 151.38,138.39 151.64,138.14 151.77,138.14 153.08,136.82 153.08,135.76 155.15,133.69 157.07,131.76 157.25,131.76 157.57,132.08 157.57,132.26 156,133.82 156,134 156.32,134.32 156.5,134.32 162.03,128.78 162.03,128.55 161.72,128.23 161.72,128 161.98,127.74 162.21,127.74 162.52,128.05 162.76,128.05 163.02,127.79 163.02,127.56 162.71,127.25 162.71,127.01 162.97,126.75 163.2,126.75 163.51,127.07 163.75,127.07 164.02,126.79 164.02,126.43 165.36,125.09 165.36,123.94 166.61,122.69 v1(166.61,122.42)
  BOTTOM w0.178: v1(153.82,146.02) 154.24,145.6 VRAM3.F2 ; GPU1.R23 167.01,122.83 v1(166.61,122.42)
FBA_D36: length 44.8
  TOP w0.178: v2(168.5,125.37) 168.25,125.11 v1(168.25,124.87)
  L3 w0.165: v1(168.25,124.87) 168.25,124.85 168.37,124.73 168.98,124.73 169.15,124.9 169.15,125.22 169.03,125.34 168.7,125.34 168.57,125.47 168.57,125.88 168.7,126.01 168.84,126.01 169.15,126.32 169.15,128.81 168.98,128.99 168.98,131.01 169.11,131.14 169.55,131.14 169.68,131.01 169.68,129 169.8,128.88 170.25,128.88 170.38,129 170.38,131.48 168.75,133.11 168.75,133.35 169.01,133.61 169.24,133.61 170.22,132.62 170.4,132.62 170.72,132.94 170.72,133.12 169.58,134.25 164.15,134.25 163.56,134.84 163.56,135.07 163.67,135.18 163.67,135.41 163.41,135.67 163.18,135.67 163.07,135.57 162.84,135.57 161.64,136.77 161.64,137.76 161.51,137.89 161.06,137.89 160.94,137.76 160.94,137.38 160.77,137.22 160.4,137.22 160.24,137.38 160.24,137.79 160.11,137.91 159.67,137.91 159.54,137.79 159.54,137.38 159.37,137.22 159.01,137.22 158.64,137.58 157.14,137.58 156.61,138.12 155.72,138.12 155.22,138.62 154.9,138.62 v1(154.76,138.76)
  BOTTOM w0.178: v1(168.25,124.87) 168.62,124.49 GPU1.N25 ; VRAM3.F8 153.86,140.41 153.86,139.05 154.15,138.76 v1(154.76,138.76)
FBA_D37: length 43.6
  TOP w0.178: v1(167.83,126.59) 167.65,126.77 v2(167.26,126.77)
  L3 w0.165: v1(167.83,126.59) 168.1,126.32 168.64,126.32 168.87,126.55 168.87,127.15 168.7,127.32 168.58,127.32 168.42,127.48 168.42,127.85 168.58,128.01 168.7,128.01 168.87,128.18 168.87,128.52 168.71,128.67 168.22,128.67 168.1,128.79 168.1,130.85 166.6,132.35 166.6,132.53 166.92,132.84 167.1,132.84 168.48,131.46 168.71,131.46 168.97,131.72 168.97,131.95 167.32,133.61 166.19,133.61 166.03,133.44 166.03,133.29 165.86,133.12 165.49,133.12 165.33,133.29 165.33,133.44 165.16,133.61 164.8,133.61 164.63,133.44 164.63,133.29 164.47,133.12 164.1,133.12 163.93,133.29 163.93,133.44 163.77,133.61 163.25,133.61 162.95,133.91 162.95,134.15 163.12,134.31 163.12,134.55 162.86,134.81 162.62,134.81 162.46,134.64 162.22,134.64 161.96,134.9 161.96,135.13 162.13,135.3 162.13,135.54 161.87,135.8 161.64,135.8 161.47,135.63 161.23,135.63 160.97,135.89 160.97,136.12 161.14,136.29 161.14,136.52 160.88,136.78 160.65,136.78 160.48,136.62 160.25,136.62 160.01,136.85 157.2,136.85 156.38,137.67 154.82,137.67 154.16,138.32 154.16,141.61 153.74,142.04 153.74,142.43 154.4,143.09 154.96,143.09 v1(155.09,143.22)
  BOTTOM w0.178: v1(167.83,126.59) 168.02,126.59 168.31,126.3 168.31,125.67 GPU1.N26 ; VRAM3.H7 155.84,142.29 155.09,143.04 v1(155.09,143.22)
FBA_D38: length 46.6
  TOP w0.178: v2(168.78,122.98) 168.58,122.98 v1(168.29,123.27)
  L3 w0.165: v1(156.74,139.02) 157.45,138.32 158.66,138.32 159.19,138.85 161.64,138.85 165.3,135.19 171.47,135.19 171.71,134.94 171.71,133.07 171.88,132.9 172.25,132.9 172.41,133.07 172.41,134.47 172.54,134.6 172.98,134.6 173.11,134.47 173.11,131.88 173.28,131.71 174.17,131.71 174.33,131.55 174.33,131.18 174.17,131.01 173.28,131.01 173.11,130.85 173.11,130.48 173.28,130.32 174.17,130.32 174.33,130.15 174.33,129.78 174.17,129.62 173.28,129.62 173.11,129.45 173.11,129.08 173.28,128.92 174.17,128.92 174.33,128.75 174.33,128.39 174.17,128.22 172.68,128.22 172.22,127.76 172.22,126.32 171.95,126.05 171.23,126.05 171.05,126.23 170.49,126.23 170.14,125.87 170.14,124.42 168.99,123.27 v1(168.29,123.27)
  BOTTOM w0.178: v1(156.74,139.02) 156.74,139.35 156.22,139.87 156.22,140.41 VRAM3.H8 ; v1(168.29,123.27) 168.67,122.89 GPU1.N23
FBA_D39: length 44.2
  TOP w0.178: v1(168.3,124.08) 168.42,124.2 v2(168.86,124.2)
  L3 w0.165: v1(168.3,124.08) 169,124.08 169.57,124.65 169.57,126.07 170.3,126.8 170.3,128.2 170.66,128.57 172.19,128.57 172.64,129.02 172.64,132.27 172.51,132.4 172.07,132.4 171.94,132.27 171.94,129.68 171.82,129.56 171.37,129.56 171.24,129.68 171.24,134.56 171.08,134.72 165.11,134.72 165.1,134.73 165.09,134.73 163.69,136.13 163.69,136.26 161.51,138.45 159.31,138.45 158.81,137.95 157.3,137.95 156.76,138.48 155.89,138.48 155.13,139.25 155.13,139.68 155.04,139.77 155.04,141.01 155.04,141.01 155.04,141.39 v1(154.18,142.25)
  BOTTOM w0.178: v1(154.18,142.25) 154.17,142.24 154.17,141.66 VRAM3.F7 ; GPU1.N24 168.69,123.7 v1(168.3,124.08)
FBA_D40: length 39.7
  TOP w0.178: v2(165.33,123.79) 164.96,123.43 v1(164.96,123.29) ; v1(156.42,142.2) 156.26,142.36 155.79,142.36 155.67,142.24 155.67,142.03 155.57,141.93 155.57,141.72 155.7,141.59 VRAM4.H3
  L4 w0.165: v1(164.96,123.29) 164.91,123.29 164.81,123.39 164.81,124.92 164.81,125.14 163.61,126.34 163.61,126.69 163.51,126.79 163.16,126.79 162.93,127.02 162.93,127.2 163.06,127.33 163.92,127.33 164.14,127.56 164.53,127.56 164.65,127.69 164.65,128.07 164.53,128.2 164.13,128.2 163.8,127.87 162.85,127.87 162.74,127.99 162.74,128.3 162.83,128.39 163.65,128.39 163.77,128.52 163.77,128.67 163.49,128.95 163.07,128.95 161.6,130.42 160.69,130.42 160.55,130.57 160.55,130.78 160.36,130.97 160.19,130.97 159.76,130.55 159.58,130.55 159.29,130.84 159.29,131.02 159.68,131.41 159.68,131.63 159.44,131.88 159.21,131.88 158.69,131.35 158.48,131.35 158.2,131.63 158.2,131.7 158.2,131.7 158.2,131.8 158.78,132.38 158.78,132.53 158.51,132.81 158.27,132.81 157.96,132.49 157.66,132.49 157.43,132.72 157.43,132.9 157.9,133.37 157.9,134.12 157.89,134.12 157.58,134.43 157.34,134.43 157.29,134.38 157.11,134.38 156.92,134.57 156.92,134.75 157.31,135.14 157.31,136.18 157.44,136.31 157.44,136.88 157.26,137.06 157.26,137.35 157.44,137.52 157.44,138.43 157.7,138.69 157.79,138.69 158.11,139.01 158.11,139.42 157.81,139.73 157.7,139.73 157.52,139.91 157.52,140.21 157.61,140.31 157.61,140.71 157.49,140.83 156.86,140.83 156.72,140.96 156.72,141.46 156.81,141.55 156.81,142.16 156.68,142.29 156.51,142.29 v1(156.42,142.2)
  BOTTOM w0.178: GPU1.V23 164.29,122.89 163.94,123.23 163.94,123.36 164.07,123.49 164.19,123.49 164.39,123.3 164.67,123.3 164.71,123.25 164.92,123.25 v1(164.96,123.29)
FBA_D41: length 40.2
  TOP w0.178: v1(153.03,141.2) 153.05,141.2 VRAM4.E3
  L4 w0.165: v1(153.03,141.2) 152.6,140.77 152.6,139.42 152.79,139.23 152.79,129.53 153.09,129.24 153.09,128.3 154.63,126.76 154.63,125.81 154.76,125.68 155.17,125.68 155.29,125.81 155.29,126.33 155.46,126.5 155.79,126.5 155.96,126.33 155.96,125.89 156.12,125.73 156.55,125.73 156.81,125.47 156.81,124.7 157.87,123.64 158.37,123.64 158.45,123.72 158.45,125.18 158.84,125.56 158.84,125.86 159.08,126.11 159.75,126.11 159.86,126.21 160.45,126.21 160.6,126.06 160.6,125.74 160.75,125.59 161.29,125.59 161.73,125.16 161.73,123.91 162.07,123.58 162.07,123.1 162.24,122.94 162.71,122.94 162.92,122.72 162.92,121.86 162.93,121.86 162.93,121.43 162.12,120.62 162.12,119.89 162.25,119.76 162.62,119.76 162.75,119.89 162.75,120.29 163.47,121.02 163.47,121.82 163.62,121.97 163.99,121.97 164.13,121.84 v1(164.13,121.68)
  BOTTOM w0.178: GPU1.V22 164.51,122.05 v1(164.13,121.68)
FBA_D42: length 39.2
  TOP w0.178: VRAM4.G2 155.24,140.79 155.48,140.56 v1(155.48,140.38)
  L4 w0.127: 164.54,123.66 164.54,123.1 164.78,122.86 165.15,122.86 165.49,123.2 165.8,123.2 165.92,123.08 165.92,122.67 v1(165.73,122.48)
  L4 w0.165: 164.54,123.66 164.54,125.03 162.47,127.1 162.47,127.24 162.69,127.46 162.69,127.66 162.47,127.88 162.47,128.84 161.36,129.95 159.96,129.95 159.84,130.07 159.39,130.07 158.88,130.59 158.59,130.59 158.08,130.07 157.21,130.07 156.32,130.97 156.32,131.15 156.6,131.44 156.78,131.44 157.55,130.68 157.73,130.68 158.03,130.98 158.03,131.13 157.73,131.43 157.73,131.9 157.6,132.02 157.08,132.02 156.95,132.15 156.95,132.62 156.82,132.75 155.99,132.75 155.82,132.92 155.82,133.12 156.1,133.39 156.86,133.39 156.98,133.52 156.98,133.84 156.86,133.97 156.5,133.97 156.37,134.1 156.37,134.89 156.82,135.33 156.82,136.75 156.51,137.06 156.51,137.39 156.6,137.48 156.87,137.48 157.07,137.68 157.07,137.97 156.98,138.05 156.51,138.05 156.38,138.18 156.38,138.46 156.51,138.59 157.07,138.59 157.19,138.7 157.19,139.74 157.06,139.87 156.83,139.87 156.52,139.55 156.12,139.55 155.94,139.73 155.94,140.06 156.06,140.18 156.35,140.18 156.51,140.34 156.51,140.58 156.34,140.74 156.1,140.74 156.02,140.82 155.74,140.82 155.48,140.56 v1(155.48,140.38)
  BOTTOM w0.178: GPU1.T23 166.21,123.08 166.16,123.13 166.16,123.16 166.05,123.28 165.85,123.28 165.75,123.18 165.75,122.5 v1(165.73,122.48)
FBA_D43: length 42.4
  TOP w0.178: v1(155.02,138.17) 155.41,138.17 155.53,138.04 155.53,137.16 155.36,136.98 v2(153.65,136.98) 152.29,136.98 152.11,137.16 152.11,137.73 152.29,137.91 154.06,137.91 154.23,138.09 154.23,138.5 154.06,138.68 153.37,138.68 153.22,138.82 153.22,139.03 153.42,139.23 153.74,139.23 153.87,139.36 153.87,140.42 VRAM4.F2
  L4 w0.165: v1(165.02,121.51) 164.52,122.01 164.52,122.65 164.26,122.91 164.26,123.46 164.14,123.58 163.63,123.58 163.48,123.74 163.48,124.41 163.6,124.53 163.78,124.53 163.92,124.67 163.92,124.9 162.28,126.54 161.86,126.54 161.67,126.72 161.67,127.9 161.77,128 161.77,128.37 161.19,128.95 159.63,128.95 159.45,129.13 158.26,129.13 158.1,128.97 158.1,128.8 157.99,128.7 157.34,128.7 157.25,128.79 157.25,128.98 157.1,129.13 156.76,129.13 156.62,128.99 156.62,128.64 156.5,128.52 155.43,128.52 155.16,128.79 155.16,129.33 155.29,129.46 155.97,129.46 156.06,129.55 156.06,129.88 155.8,130.14 154.88,130.14 154.74,130.28 154.74,130.8 155.13,131.19 155.13,131.76 154.74,132.15 154.74,133.44 155.43,134.14 155.43,135.31 155.83,135.7 155.83,136.57 155.48,136.91 155.48,137.71 v1(155.02,138.17)
  BOTTOM w0.178: GPU1.U22 165.37,121.89 165.02,121.54 v1(165.02,121.51)
FBA_D44: length 39.5
  TOP w0.178: v2(164.31,124.61) 164.1,124.4 v1(164.1,124.09) ; v1(155.58,143.63) 155.58,143.44 155.71,143.31 155.98,143.31 156.1,143.44 156.1,144.4 156.27,144.57 156.27,144.99 156.17,145.09 156.01,145.09 155.84,144.93 VRAM4.H7
  L4 w0.165: v1(155.58,143.63) 155.58,143.66 155.59,143.67 155.59,143.7 155.95,144.06 155.95,144.86 156.08,144.98 156.28,144.98 156.41,144.86 156.41,143.7 156.19,143.47 156.19,143.44 155.59,142.84 155.59,142.47 155.73,142.34 155.87,142.34 155.98,142.23 155.98,141.75 155.85,141.63 155.14,141.63 155.04,141.52 155.04,141.01 154.93,140.9 154.93,140.75 155.04,140.64 155.04,140.17 154.84,139.98 154.84,139.81 155.08,139.57 155.08,139.32 155.21,139.19 155.21,138.67 155.34,138.54 155.69,138.54 155.9,138.34 155.9,137.08 156.3,136.68 156.3,135.51 156.29,135.5 156.29,135.47 155.9,135.08 155.9,133.9 155.21,133.2 155.21,132.44 155.4,132.25 156.3,132.25 156.42,132.13 156.42,131.93 156.05,131.56 155.72,131.56 155.6,131.44 155.6,131 155.6,130.99 155.6,130.74 155.72,130.61 156.01,130.61 156.54,130.08 156.54,129.78 156.71,129.6 157.3,129.6 157.53,129.37 157.84,129.37 158.07,129.6 158.29,129.6 158.63,129.95 158.86,129.95 159.2,129.6 159.64,129.6 159.8,129.45 161.17,129.45 162.21,128.41 162.21,128.15 162.03,127.98 162.03,127.5 162.21,127.32 162.21,126.99 164.27,124.93 164.27,124.25 v1(164.1,124.09)
  BOTTOM w0.178: v1(164.1,124.09) 163.57,124.09 163.43,124.22 163.16,124.22 163.05,124.11 163.02,124.11 162.89,123.98 GPU1.Y24
FBA_D45: length 38.5
  TOP w0.178: v2(160.34,123.62) 160.34,123.63 v1(160.82,124.11) ; v1(153.81,145.18) 153.85,145.18 VRAM4.F7
  L4 w0.165: v1(153.81,145.18) 153.81,144.89 153.62,144.71 152.55,144.71 152.28,144.44 152.28,142.08 151.86,141.66 151.86,139.49 151.38,139.01 151.38,138.32 151.21,138.16 151.21,135.47 151.38,135.31 151.68,135.31 151.85,135.14 151.85,134.81 151.68,134.64 151.38,134.64 151.21,134.48 151.21,134.15 151.38,133.98 151.68,133.98 151.85,133.82 151.85,133.48 151.68,133.32 151.38,133.32 151.21,133.15 151.21,132.82 151.38,132.66 151.68,132.66 151.85,132.49 151.85,132.16 151.68,131.99 151.38,131.99 151.21,131.83 151.21,131.5 151.38,131.33 151.68,131.33 151.85,131.17 151.85,130.83 151.41,130.39 151.41,129.69 151.39,129.67 151.39,127.36 154.57,124.17 154.57,123.93 154.74,123.76 155.07,123.76 155.24,123.93 155.24,124.24 155.4,124.41 156.34,124.41 157.92,122.83 160.03,122.83 160.38,123.18 160.38,123.67 v1(160.82,124.11)
  BOTTOM w0.178: v1(160.82,124.11) 160.91,124.11 160.91,124.11 161.63,124.11 GPU1.AA24
FBA_D46: length 39.6
  TOP w0.178: VRAM4.H8 156.25,146 v1(156.27,146)
  L4 w0.127: 152.31,145.38 152.64,145.71 152.64,146.16 153.01,146.53 155.74,146.53 v1(156.27,146)
  L4 w0.165: v1(162.49,121.67) 162.01,122.15 161.36,122.15 161.16,121.95 160.61,121.95 160.39,122.17 155.9,122.17 150.92,127.16 150.92,129 150.35,129.57 150.35,131.12 150.65,131.42 150.65,139 150.41,139.24 150.41,139.69 151.49,140.78 151.49,141.81 151.84,142.16 151.84,144.91 152.31,145.38
  BOTTOM w0.178: GPU1.Y22 162.55,121.71 162.53,121.71 v1(162.49,121.67)
FBA_D47: length 40.6
  TOP w0.178: v1(161.63,123.28) 161.64,123.27 v2(161.64,122.7) ; VRAM4.F8 154.6,145.95 v1(154.6,145.98)
  L4 w0.165: v1(161.63,123.28) 161.4,123.28 161.25,123.43 161.25,124.25 161.43,124.42 161.43,124.99 161.09,125.33 160.67,125.33 160.66,125.33 159.36,125.33 159.35,125.34 158.99,125.34 158.72,125.07 158.72,123.61 158.48,123.37 157.76,123.37 156.45,124.69 155.95,124.69 155.78,124.86 155.78,125.15 155.62,125.32 155.28,125.32 155.12,125.15 155.12,124.86 154.95,124.69 154.72,124.69 153.97,125.44 153.97,125.67 154.31,126.02 154.31,126.25 154.08,126.49 153.84,126.49 153.5,126.14 153.27,126.14 153.03,126.38 153.03,126.61 153.46,127.04 153.46,127.22 153.17,127.51 152.99,127.51 152.56,127.08 152.33,127.08 152.07,127.34 152.07,127.67 152.62,128.23 152.62,129.04 152.32,129.34 152.32,139.17 152.23,139.27 152.23,141.51 152.81,142.09 152.81,143.66 153.47,144.33 154.05,144.33 154.24,144.52 154.24,145.82 154.41,145.98 v1(154.6,145.98)
  BOTTOM w0.178: v1(161.63,123.28) 161.66,123.28 GPU1.AA23
FBA_D48: length 39.7
  TOP w0.178: v1(156.56,126.17) 156.56,125.84 v2(156.88,125.52) ; VRAM4.B8 150.65,145.98 150.01,145.98 149.54,146.46 v1(149.44,146.46)
  L3 w0.165: v1(156.56,126.17) 156.43,126.03 156.15,126.03 156.02,126.17 155.6,126.17 155.12,125.69 154.79,125.69 154.31,126.17 151.29,126.17 150.39,127.07 149.65,127.07 145.23,131.5 145.23,142.55 147.49,144.81 148.7,144.81 148.92,145.04 148.92,145.43 148.66,145.69 148.66,146.8 148.85,146.99 149.37,146.99 149.54,146.82 149.54,146.55 v1(149.44,146.46)
  BOTTOM w0.178: v1(156.56,126.17) 156.59,126.19 156.59,126.24 157.2,126.86 159.16,126.86 159.55,126.47 GPU1.AD27
FBA_D49: length 43
  TOP w0.178: VRAM4.D7 152.51,144.79 152.08,145.21 148.94,145.21 148.48,145.67 v1(148.18,145.67) ; v1(160.85,124.89) 160.85,125.04 v2(161.16,125.35)
  L3 w0.165: v1(160.85,124.89) 160.41,125.33 159.77,125.33 159.25,125.85 158.04,125.85 157.86,125.67 157.86,125.27 157.69,125.1 157.36,125.1 157.2,125.27 157.2,125.54 157.03,125.7 156.58,125.7 156.55,125.73 156.05,125.73 155.72,125.39 154.18,125.39 153.88,125.7 153.52,125.7 153.36,125.53 153.36,125.44 153.19,125.27 152.86,125.27 152.69,125.44 152.69,125.53 152.53,125.7 152.2,125.7 152.03,125.53 152.03,125.44 151.87,125.27 151.53,125.27 151.37,125.44 151.37,125.53 151.2,125.7 150.36,125.7 144.76,131.3 144.76,142.75 147.68,145.67 v1(148.18,145.67)
  BOTTOM w0.178: v1(160.85,124.89) 160.85,124.89 GPU1.AB25
FBA_D50: length 38.4
  TOP w0.178: v2(157.86,126.25) 157.81,126.25 157.7,126.14 v1(157.2,126.14) ; v1(149.32,144.76) 149.39,144.76 149.56,144.59 150.13,144.59 150.24,144.7 VRAM4.A7
  L3 w0.165: v1(149.32,144.76) 149.68,144.76 149.93,144.51 149.93,144.17 149.67,143.91 147.25,143.91 145.7,142.36 145.7,132.43 146.86,131.26 146.86,131.03 146.74,130.91 146.74,130.67 146.97,130.44 147.21,130.44 147.33,130.56 147.56,130.56 147.8,130.33 147.8,130.09 147.67,129.97 147.67,129.73 147.91,129.5 148.14,129.5 148.27,129.62 148.5,129.62 148.74,129.39 148.74,129.15 148.61,129.03 148.61,128.8 148.85,128.56 149.08,128.56 149.21,128.69 149.44,128.69 149.67,128.45 149.67,128.22 149.55,128.09 149.55,127.86 149.79,127.62 150.02,127.62 150.14,127.75 150.38,127.75 151.46,126.67 154.4,126.67 154.7,126.96 155.23,126.96 155.63,126.57 156.3,126.57 156.4,126.67 156.9,126.67 157.2,126.36 v1(157.2,126.14)
  BOTTOM w0.178: GPU1.AD26 159.41,125.29 159.17,125.53 159.17,126.26 158.88,126.55 157.45,126.55 157.2,126.3 v1(157.2,126.14)
FBA_D51: length 42.6
  TOP w0.178: v1(159.97,124.85) 159.6,125.21 v2(159.6,125.27) ; VRAM4.C8 151.46,145.97 151.46,147.07 151.13,147.41 149.35,147.41 148.36,146.41 148.35,146.41 148.32,146.38 v1(148.19,146.38)
  L3 w0.165: v1(148.19,146.38) 147.95,146.14 147.49,146.14 144.29,142.94 144.29,131.11 150.61,124.78 158.22,124.78 158.81,125.37 159.34,125.37 159.86,124.85 v1(159.97,124.85)
  BOTTOM w0.178: GPU1.AC25 160.33,124.49 v1(159.97,124.85)
FBA_D52: length 43.1
  TOP w0.178: VRAM4.A3 149.65,141.59 v1(149.47,141.41)
  L3 w0.165: v1(152.02,128.81) 152.27,128.57 154.51,128.57 154.59,128.48 157.24,128.48 157.71,128.02 158,128.02 158.27,128.29 158.27,128.58 157.65,129.19 156.32,129.19 155.95,129.56 155.95,130.89 155.38,131.47 154.63,131.47 150.58,135.52 150.58,137.36 149.23,138.71 149.23,141.18 v1(149.47,141.41)
  BOTTOM w0.178: v1(152.02,128.81) v2(150.75,128.81) 150.31,128.81 150.11,128.61 150.11,127.36 150.31,127.16 150.72,127.16 151.05,126.83 155.78,126.83 155.95,127 155.95,127.89 156.22,128.16 157.14,128.16 157.65,127.65 160.63,127.65 162.05,126.22 GPU1.AA27
FBA_D53: length 43.5
  TOP w0.178: v1(149.71,142.57) 149.72,142.58 151.5,142.58 151.63,142.7 151.63,143.17 151.76,143.3 152.23,143.3 152.36,143.17 152.36,142.11 VRAM4.C3
  L3 w0.165: v1(149.71,142.57) 149.15,142.57 148.77,142.18 148.77,138.5 149.53,137.73 149.53,135.75 153.65,131.63 153.65,130.97 153.84,130.78 155.12,130.78 155.38,130.52 155.38,129.33 155.08,129.04 152.61,129.04 152.2,129.45 v1(151.85,129.45)
  BOTTOM w0.178: GPU1.AA26 162.05,125.38 162.43,125.77 162.43,126.25 160.75,127.93 157.77,127.93 157.26,128.44 155.84,128.44 155.47,128.06 155.47,127.64 155.14,127.31 v2(152.45,127.31) 151.59,127.31 151.39,127.52 151.39,128.08 151.59,128.28 152.38,128.28 152.55,128.45 152.55,128.97 152.08,129.45 v1(151.85,129.45)
FBA_D54: length 43.3
  TOP w0.178: v1(147.96,139.72) 148.19,139.49 148.19,138.85 148.39,138.65 148.74,138.65 148.95,138.85 148.95,140.22 149.15,140.42 151.4,140.42 151.77,140.79 VRAM4.C2
  L3 w0.165: v1(150.81,130.58) 150.28,130.58 149.93,130.93 149.93,131.55 150.14,131.76 150.14,132.16 150.34,132.36 150.62,132.36 150.94,132.04 150.94,131.51 152.01,130.45 152.38,130.45 152.62,130.69 152.62,131.33 149.52,134.43 147.81,134.43 147.68,134.55 147.68,134.96 147.81,135.09 148.35,135.09 148.56,135.29 148.56,135.58 148.35,135.79 147.83,135.79 147.67,135.95 147.67,136.41 147.83,136.58 148.41,136.58 148.58,136.74 148.58,137.11 148.41,137.28 147.83,137.28 147.67,137.44 147.67,139.43 v1(147.96,139.72)
  BOTTOM w0.178: GPU1.W26 163.68,125.34 163.42,125.34 162.99,125.77 162.99,126.93 162.3,127.62 162.01,127.62 161.08,128.55 157.94,128.55 157.72,128.77 157.71,128.77 157.49,129 154.71,129 154.5,129.2 153.69,129.2 v2(152.83,130.06) 152.4,130.49 150.91,130.49 v1(150.81,130.58)
FBA_D55: length 43.5
  TOP w0.178: VRAM4.A2 150.14,140.89 149.15,140.89 149.03,141.01 149.03,141.6 149.03,141.6 149.03,142.27 148.87,142.43 148.52,142.43 148.23,142.14 147.71,142.14 147.51,141.94 147.51,141.54 147.71,141.34 148.14,141.34 148.26,141.22 148.26,140.66 148.19,140.58 v1(147.96,140.58)
  L3 w0.165: v1(147.96,140.58) 148.4,140.15 148.4,139.54 148.11,139.25 148.11,138.08 148.34,137.85 148.81,137.85 149.03,137.63 149.03,135.58 153.1,131.52 153.1,130.44 153.22,130.31 154.71,130.31 154.84,130.18 154.84,129.64 154.71,129.51 152.8,129.51 152.4,129.92 150.98,129.92 v1(150.94,129.88)
  BOTTOM w0.178: GPU1.Y25 162.51,124.87 162.51,125.45 162.71,125.65 162.71,126.44 160.88,128.27 157.82,128.27 157.37,128.72 155.72,128.72 155.18,128.17 154.76,128.17 154.62,128.31 154.62,128.46 154.45,128.64 154.09,128.64 153.91,128.46 153.91,127.97 153.73,127.8 153.27,127.8 153.03,128.03 v2(153.03,128.74) 153.03,129.17 152.28,129.93 150.99,129.93 v1(150.94,129.88)
FBA_D56: length 42.9
  BOTTOM w0.178: VRAM3.C8 151.41,140.36 151.41,139 151.27,138.86 151.27,138.42 151.62,138.06 152.15,138.06 152.98,137.23 156.51,137.23 156.61,137.13 162.67,137.13 162.86,137.33 162.86,137.75 163.04,137.93 164.72,137.93 166.31,136.34 166.31,136.09 166.06,135.84 165.8,135.84 164.43,137.21 164.17,137.21 163.92,136.96 163.92,136.71 165.91,134.73 165.91,132.56 166.09,132.38 166.44,132.38 166.62,132.56 166.62,135.36 166.8,135.54 167.15,135.54 167.33,135.36 v2(167.33,129.25) 167.33,128.74 167.25,128.65 167.25,126.62 167.39,126.47 167.39,125.76 167.01,125.38 GPU1.R26
FBA_D57: length 42.9
  BOTTOM w0.178: VRAM3.A7 150.24,141.47 149.23,140.46 149.23,138.94 149.93,138.23 150.01,138.23 151.16,137.08 152.06,137.08 152.66,136.47 154.67,136.47 155.18,135.96 155.55,135.96 155.73,136.14 161.78,136.14 161.95,135.96 161.95,135.61 161.78,135.43 156.03,135.43 155.86,135.25 155.86,134.9 156.03,134.72 160.51,134.72 161.01,134.23 161.24,134.23 161.52,134.51 161.77,134.51 162.03,134.26 162.03,134.01 161.74,133.72 161.74,133.49 v2(163.17,132.06) 166.36,128.87 166.36,126.48 166.59,126.25 166.59,124.87 GPU1.T25
FBA_D58: length 41.8
  BOTTOM w0.178: VRAM3.D7 152.35,141.59 152.27,141.51 152.27,139.64 152.68,139.23 152.68,138.53 153.3,137.92 154.65,137.92 154.84,137.72 162.12,137.72 162.71,138.31 v2(165.38,138.31) 165.83,138.31 166.01,138.13 166.01,137.3 166.19,137.12 166.57,137.12 166.75,137.3 166.75,138.77 167.07,139.09 168.35,139.09 168.55,138.89 168.55,138.22 168.76,138.01 169.3,138.01 169.51,137.81 169.51,137.23 169.3,137.03 168.63,137.03 168.43,136.82 168.43,136.52 168.63,136.32 169.3,136.32 169.48,136.14 169.48,134.83 169.28,134.62 168.88,134.62 168.67,134.83 168.67,135.47 168.5,135.64 167.99,135.64 167.81,135.47 167.81,128.74 167.53,128.45 167.53,127.58 167.92,127.19 167.94,127.19 168.69,126.43 GPU1.N27
FBA_D59: length 43.1
  BOTTOM w0.178: VRAM3.B8 151.04,140.51 150.67,140.14 150.67,139.88 150.4,139.6 150.4,139.22 150.78,138.84 150.78,138.25 151.46,137.57 152.11,137.57 152.82,136.85 155.91,136.85 156.13,136.62 162,136.62 162.58,136.05 v2(162.58,135.17) 162.58,133.36 162.76,133.18 163.11,133.18 163.29,133.36 163.29,135.88 163.47,136.06 163.82,136.06 164,135.88 164,131.95 164.18,131.77 164.54,131.77 164.71,131.95 164.71,134.4 164.89,134.57 165.25,134.57 165.42,134.4 165.42,130.5 165.6,130.32 165.96,130.32 166.14,130.5 166.14,131.61 166.31,131.78 166.67,131.78 166.85,131.61 166.85,128.91 166.75,128.81 166.75,126.59 167.01,126.33 GPU1.R27
FBA_D60: length 39.8
  BOTTOM w0.127: GPU1.V26 164.53,125.3
  BOTTOM w0.178: 164.53,125.3 164.53,125.45 164.15,125.83 164.15,127.61 160.92,130.83 155.75,130.83 155.57,131.01 155.57,131.37 155.75,131.55 157.54,131.55 157.72,131.72 157.72,132.08 157.54,132.26 150.54,132.26 148.41,134.39 148.41,135.25 v2(146.88,136.77) 146.4,137.26 146.4,142.74 147.57,143.92 149.69,143.92 150.16,144.39 150.16,144.71 VRAM3.A3
FBA_D61: length 40.6
  BOTTOM w0.178: GPU1.V27 164.53,127.93 161.15,131.32 158.42,131.32 158.22,131.52 158.22,132.52 158.01,132.74 152.75,132.74 150.14,135.35 149.88,135.35 149.63,135.1 149.63,134.85 151.09,133.39 151.09,133.14 150.84,132.89 150.59,132.89 148.89,134.59 148.89,135.75 146.88,137.77 146.88,141.72 v2(147.1,141.94) 147.29,142.13 147.71,142.13 148.12,142.53 148.12,143.1 148.54,143.52 149.83,143.52 150.26,143.94 150.8,143.94 151.65,144.79 VRAM3.C3
FBA_D62: length 40.3
  BOTTOM w0.178: VRAM3.A2 150.24,145.33 149.77,144.86 149.77,144.58 149.49,144.3 148.61,144.3 148.51,144.39 147.36,144.39 145.91,142.94 145.91,137.05 147.92,135.04 147.92,134.19 150.34,131.77 v2(153.16,131.77) 154.9,131.77 155.08,131.6 155.08,131.24 154.9,131.06 154.19,131.06 154.01,130.89 154.01,130.53 154.19,130.35 157.5,130.35 158.31,129.55 158.7,129.55 158.87,129.73 158.87,130.11 159.05,130.28 159.41,130.28 159.59,130.11 159.59,129.46 159.76,129.28 160.12,129.28 160.3,129.46 160.3,129.97 160.48,130.15 160.83,130.15 161.01,129.97 161.01,129.46 161.19,129.28 161.71,129.28 163.73,127.27 GPU1.W27
FBA_D63: length 40.3
  BOTTOM w0.178: GPU1.W25 164.11,124.87 164.11,125.45 163.85,125.71 163.57,125.71 163.27,126.01 163.27,127.05 161.46,128.86 158.31,128.86 157.3,129.87 153.99,129.87 152.56,131.29 150.14,131.29 147.44,133.99 147.44,134.61 v2(147.04,135.02) 145.43,136.62 145.43,143.14 147.19,144.9 148.74,144.9 149.08,145.24 149.59,145.24 149.86,145.51 149.86,145.73 150.11,145.98 150.47,145.98 150.67,145.78 150.67,145.44 150.89,145.22 151.43,145.22 151.45,145.23 151.81,145.59 VRAM3.C2
FBA_DEBUG0: length 1.4
  TOP w0.102: v1(174.86,121.63) 174.7,121.8 R7501.1
  BOTTOM w0.102: v1(174.86,121.63) 174.85,121.63 174.79,121.7 174.78,121.7 174.58,121.89 174.55,121.89 GPU1.F22
FBA_DEBUG1: length 2.5
  TOP w0.102: R7503.1 172.55,121.66 v1(172.41,121.66) 172.35,121.6 v2(171.62,121.6)
  BOTTOM w0.102: v1(172.41,121.66) 172.36,121.66 GPU1.J22
FBA_DQM0: length 40.8
  TOP w0.178: VRAM1.E7 182.2,141.73 v1(182.2,143.58) ; v1(176.56,119.12) 176.56,119.48 v2(176.74,119.65)
  L3 w0.165: v1(176.56,119.12) 176.72,119.28 177.22,119.28 177.85,119.92 177.85,120.31 183.03,125.49 183.03,135.4 183.2,135.56 183.53,135.56 183.69,135.4 183.69,132.64 183.86,132.47 184.19,132.47 184.35,132.64 184.35,136.07 184.19,136.23 183.91,136.23 183.75,136.4 183.75,136.73 183.91,136.89 184.19,136.89 184.35,137.05 184.35,139.03 183.97,139.42 183.97,139.8 183.71,140.05 183.04,140.05 182.91,139.93 182.54,139.93 182.29,140.18 182.29,141.33 182.73,141.78 182.73,143.18 182.33,143.58 v1(182.2,143.58)
  BOTTOM w0.178: GPU1.D19 176.18,119.51 v1(176.56,119.12)
FBA_DQM1: length 48.5
  TOP w0.178: v1(176.58,115.8) 176.58,116.19 v2(176.4,116.37) ; VRAM1.D3 183.77,144.16 v1(183.97,144.16)
  L4 w0.127: 177.95,116.37 177.16,116.37 v1(176.58,115.8)
  L4 w0.165: v1(183.97,144.16) 183.97,145.12 184.14,145.29 184.78,145.29 184.95,145.12 184.95,143.92 184.6,143.58 184.17,143.58 183.92,143.32 183.92,142.99 184.55,142.36 186.39,142.36 187.92,140.84 187.92,140.01 190.29,137.65 190.29,132.25 189.75,131.72 189.75,121.16 186.64,118.05 185.64,118.05 184.73,117.13 183.78,117.13 182.98,116.34 179.6,116.34 179.43,116.51 178.09,116.51 177.95,116.37
  BOTTOM w0.178: GPU1.D14 176.17,115.39 176.53,115.75 176.54,115.75 v1(176.58,115.8)
FBA_DQM2: length 43.6
  L4 w0.165: v1(182.46,120.39) 182.65,120.39 182.89,120.64 182.89,120.84 182.77,120.96 182.77,121.3 182.36,121.71 182.36,121.97 182.59,122.2 182.88,122.2 183.11,121.97 183.55,121.97 185.34,123.76 185.34,125.15 185.51,125.32 185.54,125.32 185.71,125.48 185.71,125.73 185.54,125.89 185.51,125.89 185.34,126.06 185.34,126.3 185.51,126.47 185.54,126.47 185.71,126.63 185.71,126.88 185.54,127.04 185.51,127.04 185.34,127.21 185.34,127.45 185.51,127.62 185.54,127.62 185.71,127.78 185.71,128.02 185.54,128.19 185.51,128.19 185.34,128.35 185.34,128.62 185.58,128.86 185.58,134.68 183.69,136.58 183.69,137.77 182.33,139.13 182.33,139.62 181.74,140.21 181.74,141.7 182.08,142.03 182.08,142.53 181.31,143.3 181.02,143.3 181.02,143.3 v1(181.03,143.3)
  BOTTOM w0.178: v1(181.03,143.3) 181.02,143.3 181.02,143.3 181.39,143.3 181.82,142.87 182.74,142.87 182.95,143.08 182.95,143.53 182.29,144.19 182.29,144.56 182.34,144.61 VRAM2.E7 ; v1(182.46,120.39) 182.52,120.46 183.69,120.46 183.81,120.33 183.81,119.82 183.69,119.69 182.17,119.69 181.79,120.07 v2(181.63,120.07) 181.5,120.07 180.69,119.26 180.3,118.87 180.3,118.74 179.38,117.83 178.33,117.83 177.91,118.25 177.33,118.25 GPU1.C17
FBA_DQM3: length 50.5
  BOTTOM w0.127: GPU1.C22 177.33,122.37 179.06,122.37 179.82,123.13
  BOTTOM w0.178: VRAM2.D3 183.42,141.59 183.79,141.96 183.8,141.96 184.35,142.51 186.68,142.51 189.31,139.89 189.31,130.36 189.13,130.19 188.77,130.19 188.59,130.36 188.59,136.1 188.42,136.27 188.06,136.27 187.88,136.1 187.88,128.95 187.71,128.77 187.35,128.77 187.17,128.95 187.17,130.84 186.99,131.02 186.64,131.02 186.46,130.84 186.46,127.51 183.9,124.95 v2(182.27,124.95) 181.64,124.95 179.82,123.13
FBA_DQM4: length 41.8
  L3 w0.165: v1(167.46,123.28) 167.46,123.48 166.58,124.37 166.58,125.35 165.38,126.54 165.38,126.97 160.78,131.58 160.78,131.81 161.04,132.07 161.27,132.07 164.65,128.69 164.83,128.69 165.14,129.01 165.14,129.19 160.41,133.92 158.81,135.52 155.43,135.52 152.75,138.19 152.75,139.26 152.59,139.43 152.59,142.7 153.25,143.36 v1(153.25,143.38)
  BOTTOM w0.178: v1(153.25,143.38) 153.69,142.94 153.69,141.84 VRAM3.E7 ; GPU1.P24 167.85,123.66 v1(167.46,123.28)
FBA_DQM5: length 39.7
  TOP w0.178: v2(162.99,124.32) 162.76,124.1 v1(162.45,124.1) ; v1(153.64,143.87) 153.63,143.88 153.63,143.91 153.44,144.11 VRAM4.E7
  L4 w0.165: v1(162.45,124.1) 162.1,124.45 162.1,124.73 162.37,124.99 162.37,125.37 162.1,125.64 161.65,125.64 160.81,126.48 160.29,126.48 160.05,126.72 159.72,126.72 159.39,126.39 159.15,126.39 159.01,126.53 159.01,126.82 158.87,126.95 158.54,126.95 158.33,126.75 158.33,126.32 158.57,126.08 158.57,125.68 158.19,125.29 158.19,124.22 158.07,124.1 157.8,124.1 157.59,124.3 157.59,124.69 157.48,124.8 157.26,124.8 157.09,124.97 157.09,125.3 157.26,125.46 157.53,125.46 157.64,125.57 157.64,127.04 157.51,127.17 157.11,127.17 156.95,127 156.95,126.78 156.78,126.62 156.12,126.62 155.95,126.79 155.95,127.51 155.79,127.68 155.46,127.68 155.29,127.51 155.29,127.33 155.12,127.17 154.72,127.17 154.55,127.34 154.55,127.91 153.66,128.79 153.66,129.47 153.4,129.73 153.4,136.04 153.36,136.08 153.36,136.37 153.19,136.55 153.19,138.91 153.32,139.04 153.37,139.04 153.49,139.17 153.49,142.56 153.92,142.98 153.92,143.43 153.67,143.67 153.67,143.82 153.64,143.85 v1(153.64,143.87)
  BOTTOM w0.178: v1(162.45,124.1) 162.45,123.59 162.73,123.31 163.35,123.31 GPU1.W24
FBA_DQM6: length 44.5
  TOP w0.178: v1(148.89,143.01) 149.15,143.01 149.41,143.26 151.09,143.26 151.88,144.05 152.48,144.05 152.75,143.78 152.75,143.04 152.88,142.91 153.59,142.91 153.73,142.76 153.73,142.35 153.58,142.19 153.15,142.19 152.64,141.69 VRAM4.D3 ; v1(160.53,126.92) 160.53,127.48 v2(160.53,127.48)
  L3 w0.165: v1(148.89,143.01) 147.1,141.22 147.1,134.27 147.5,133.86 149.2,133.86 149.53,133.53 149.53,132 149.25,131.72 149.25,130.76 152.01,128 155.56,128 155.68,128.12 157.14,128.12 157.93,127.33 157.93,126.53 158.12,126.34 158.4,126.34 158.59,126.53 158.59,126.77 158.76,126.93 159.09,126.93 159.25,126.77 159.25,126.5 159.51,126.24 160.18,126.24 160.94,125.48 161.23,125.48 161.45,125.71 161.45,125.99 v1(160.53,126.92)
  BOTTOM w0.178: GPU1.AA25 161.63,124.91 161.63,126.25 161.24,126.64 160.81,126.64 v1(160.53,126.92)
FBA_DQM7: length 40.5
  BOTTOM w0.178: VRAM3.D3 152.98,144.45 152.98,143.78 152.77,143.58 152.47,143.58 152.27,143.78 152.27,144.13 152.06,144.34 151.76,144.34 151.55,144.13 151.55,143.73 151.38,143.55 150.52,143.55 149.98,143.02 149.53,143.02 149.07,142.56 148.86,142.56 147.46,141.16 v2(147.46,138.63) 147.46,138.01 148.9,136.57 149.2,136.57 149.83,135.94 150.38,135.94 152.97,133.35 159.94,133.35 160.12,133.17 160.12,132.81 159.94,132.64 158.98,132.64 158.81,132.46 158.81,132.1 158.98,131.93 161.36,131.93 164.99,128.3 164.99,124.94 165.37,124.55 GPU1.U25
FBA_DQS_RN0: length 39.1
  TOP w0.14: VRAM1.G3 180.94,144.79 181.15,144.58 181.15,144.3 v1(181.08,144.23)
  L3 w0.127: v1(174.94,119.88) 174.94,119.69 175.09,119.54 175.9,119.54 176.93,120.56 177.23,120.56 182.22,125.56 182.22,134.77 182.1,134.89 181.32,134.89 181.06,135.16 181.06,135.66 181.32,135.92 182.27,135.92 182.39,136.04 182.39,136.32 182.27,136.45 181.64,136.45 181.38,136.71 181.38,137.18 181.64,137.44 183.39,137.44 183.55,137.6 183.55,137.82 183.39,137.98 181.89,137.98 181.63,138.24 181.63,138.71 181.89,138.97 182.07,138.97 182.23,139.12 182.23,139.34 182.07,139.5 181.89,139.5 181.63,139.76 181.63,140.47 181.51,140.59 181.08,140.59 180.82,140.86 180.82,141.32 181.08,141.58 181.55,141.58 182.07,142.1 182.07,142.67 181.55,143.19 181.55,143.38 181.29,143.64 181.29,144.02 v1(181.08,144.23)
  BOTTOM w0.14: GPU1.F19 174.6,119.51 174.94,119.85 v1(174.94,119.88)
FBA_DQS_RN1: length 47.2
  TOP w0.14: v2(177.77,115.38) 177.73,115.38 v1(177.34,114.99) ; VRAM1.B7 184.63,141.7 184.63,142.66 185.1,143.13 v1(185.12,143.13)
  L4 w0.127: v1(177.34,114.99) 177.34,115.09 178.29,116.04 179.23,116.04 179.41,115.86 183.35,115.86 184.02,116.53 184.94,116.53 185.67,117.26 186.97,117.26 190.67,120.97 190.67,129.82 191.07,130.21 191.07,130.74 190.83,130.97 190.63,130.97 190.53,131.07 190.53,131.39 190.65,131.51 190.81,131.51 191.07,131.77 191.07,138.77 190.74,139.09 190.35,139.09 190.24,138.98 190.06,138.98 189.86,139.18 189.86,139.36 189.98,139.48 189.98,139.85 189.65,140.18 189.28,140.18 189.16,140.06 188.98,140.06 188.78,140.26 188.78,140.44 188.9,140.56 188.9,140.91 186.89,142.92 186.89,143.26 186.61,143.54 185.62,143.54 185.21,143.13 185.1,143.13 185.1,143.13 v1(185.12,143.13)
  BOTTOM w0.14: v1(177.34,114.99) 176.95,115.38 GPU1.C14
FBA_DQS_RN2: length 38.6
  TOP w0.14: v2(181.81,119.7) 181.37,119.26 v1(181.37,118.92)
  L4 w0.127: v1(181.37,118.92) 181.52,118.77 181.64,118.77 181.79,118.91 181.79,119.26 181.61,119.44 181.61,120.49 182.1,120.99 182.1,121.3 181.98,121.41 181.69,121.41 181.48,121.62 181.48,122.17 181.73,122.41 182.03,122.41 182.58,122.96 182.58,123.14 182.32,123.4 182.32,123.77 182.66,124.1 183.03,124.1 183.72,123.41 183.94,123.41 184.1,123.57 184.1,123.79 183.41,124.48 183.41,124.85 183.74,125.18 184.15,125.18 184.54,124.8 184.65,124.8 184.74,124.89 184.74,134.42 182.53,136.63 182.53,136.63 182.53,137.07 182.91,137.45 182.91,137.64 182.22,138.32 181.93,138.32 181.57,138.69 181.57,139.06 181.72,139.21 181.72,139.31 181.11,139.92 181.11,142.52 v1(180.96,142.67)
  BOTTOM w0.14: VRAM2.G3 181.05,141.59 181.14,141.69 181.14,142.14 180.96,142.32 v1(180.96,142.67) ; v1(181.37,118.92) 181.02,118.56 180.98,118.56 179.25,116.83 178.64,116.83 178.55,116.93 GPU1.A16
FBA_DQS_RN3: length 43.4
  BOTTOM w0.14: GPU1.A22 179.25,121.99 180.45,123.19 181.01,123.19 182.21,124.38 184.13,124.38 184.51,124.76 184.9,124.76 185.26,124.4 185.46,124.4 185.65,124.59 185.65,124.79 185.29,125.15 185.29,125.55 185.62,125.88 186.02,125.88 186.38,125.52 186.58,125.52 186.77,125.71 186.77,125.91 186.41,126.27 186.41,126.66 186.74,127 187.14,127 187.5,126.64 187.7,126.64 187.89,126.83 187.89,127.03 187.53,127.38 187.53,127.78 189.09,129.35 ; 189.09,129.35 v2(189,129.44) ; 189.09,129.35 189.87,130.12 189.87,140.12 188.48,141.51 188.48,141.94 189.18,142.64 189.18,142.83 188.98,143.03 188.79,143.03 188.09,142.33 187.69,142.33 187.13,142.89 187.13,143.62 186.97,143.78 186.74,143.78 186.57,143.62 186.57,143.33 186.29,143.05 185.81,143.05 185.16,143.7 184.45,143.7 184.25,143.5 183.57,143.5 183.2,143.87 183.2,144.15 183.2,144.35 183.59,144.75 183.59,144.93 183.8,145.14 184.08,145.14 184.43,144.79 VRAM2.B7
FBA_DQS_RN4: length 41.9
  TOP w0.14: v2(167.1,125.29) 167.43,124.96 v1(167.43,124.84)
  L3 w0.127: v1(167.43,124.84) 167.14,124.84 167.05,124.93 167.05,126.46 167.48,126.89 167.48,128.91 167.22,129.17 166.75,129.17 166.49,128.91 166.49,127.65 166.37,127.52 166.09,127.52 165.96,127.65 165.96,130.05 164.96,131.05 164.96,131.23 165.16,131.43 165.34,131.43 166.85,129.92 167.22,129.92 167.55,130.25 167.55,130.62 165.61,132.55 163.46,132.55 160.44,135.57 159.71,136.31 156.8,136.31 155.91,137.19 154.66,137.19 153.69,138.16 153.69,141.45 153.31,141.83 153.31,142.53 154.24,143.45 154.45,143.45 154.85,143.84 v1(154.97,143.84)
  BOTTOM w0.14: GPU1.P25 167.74,124.49 167.43,124.8 v1(167.43,124.84) ; VRAM3.G3 154.88,144.79 154.86,144.76 154.72,144.76 154.52,144.57 154.52,144.25 154.92,143.84 v1(154.97,143.84)
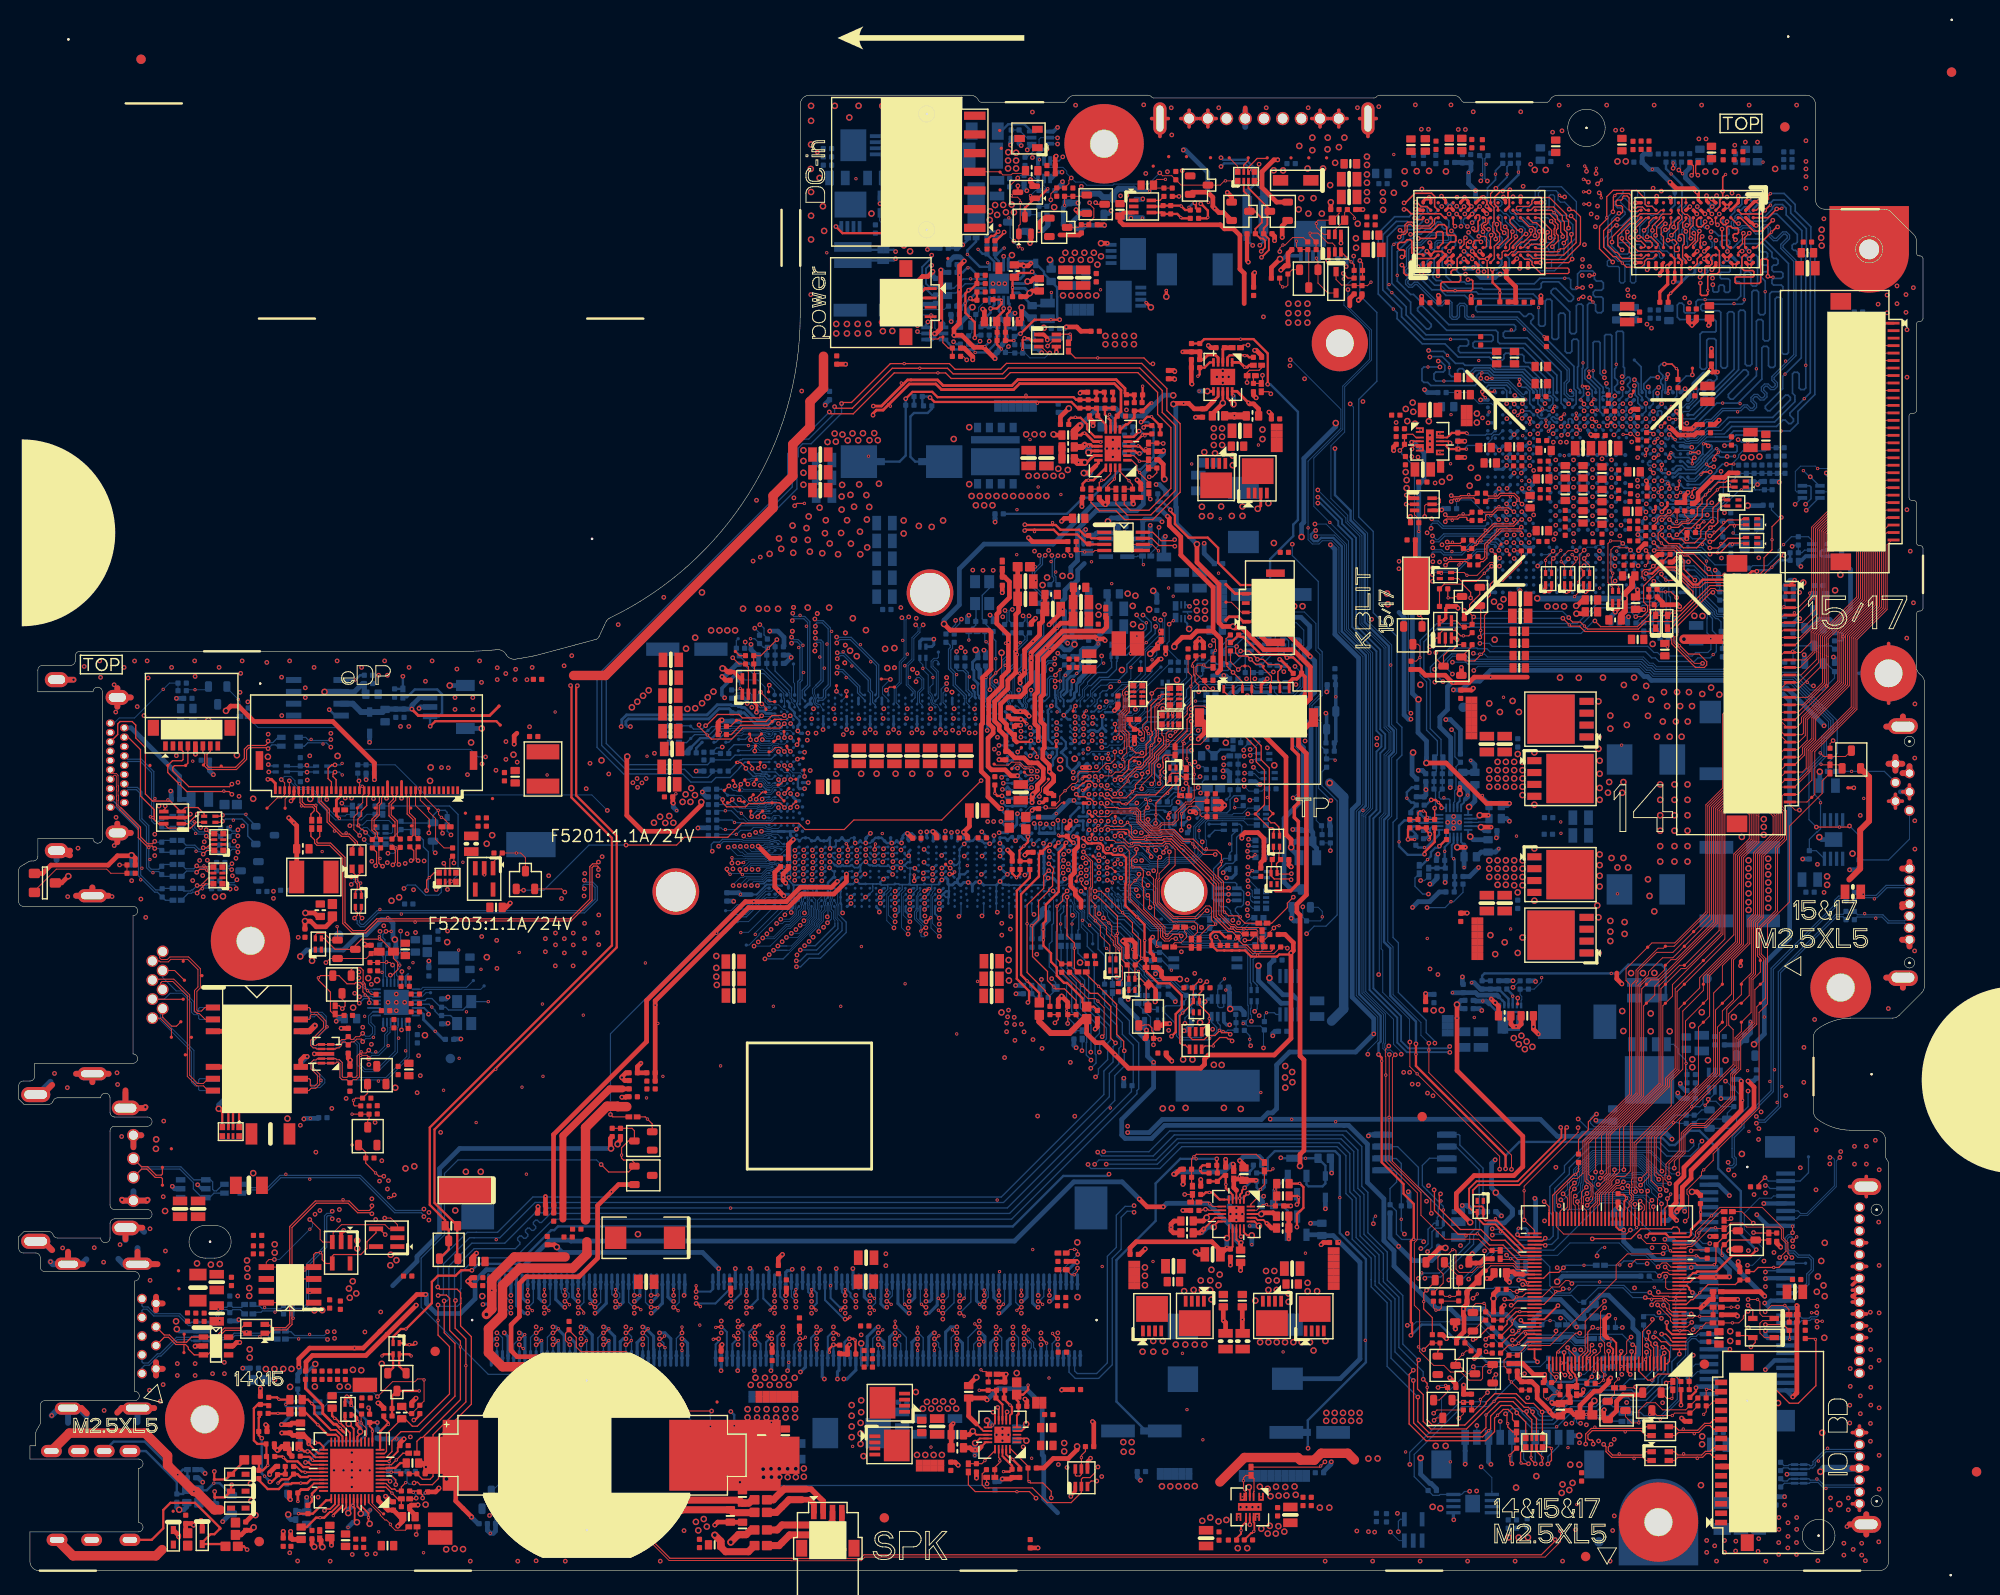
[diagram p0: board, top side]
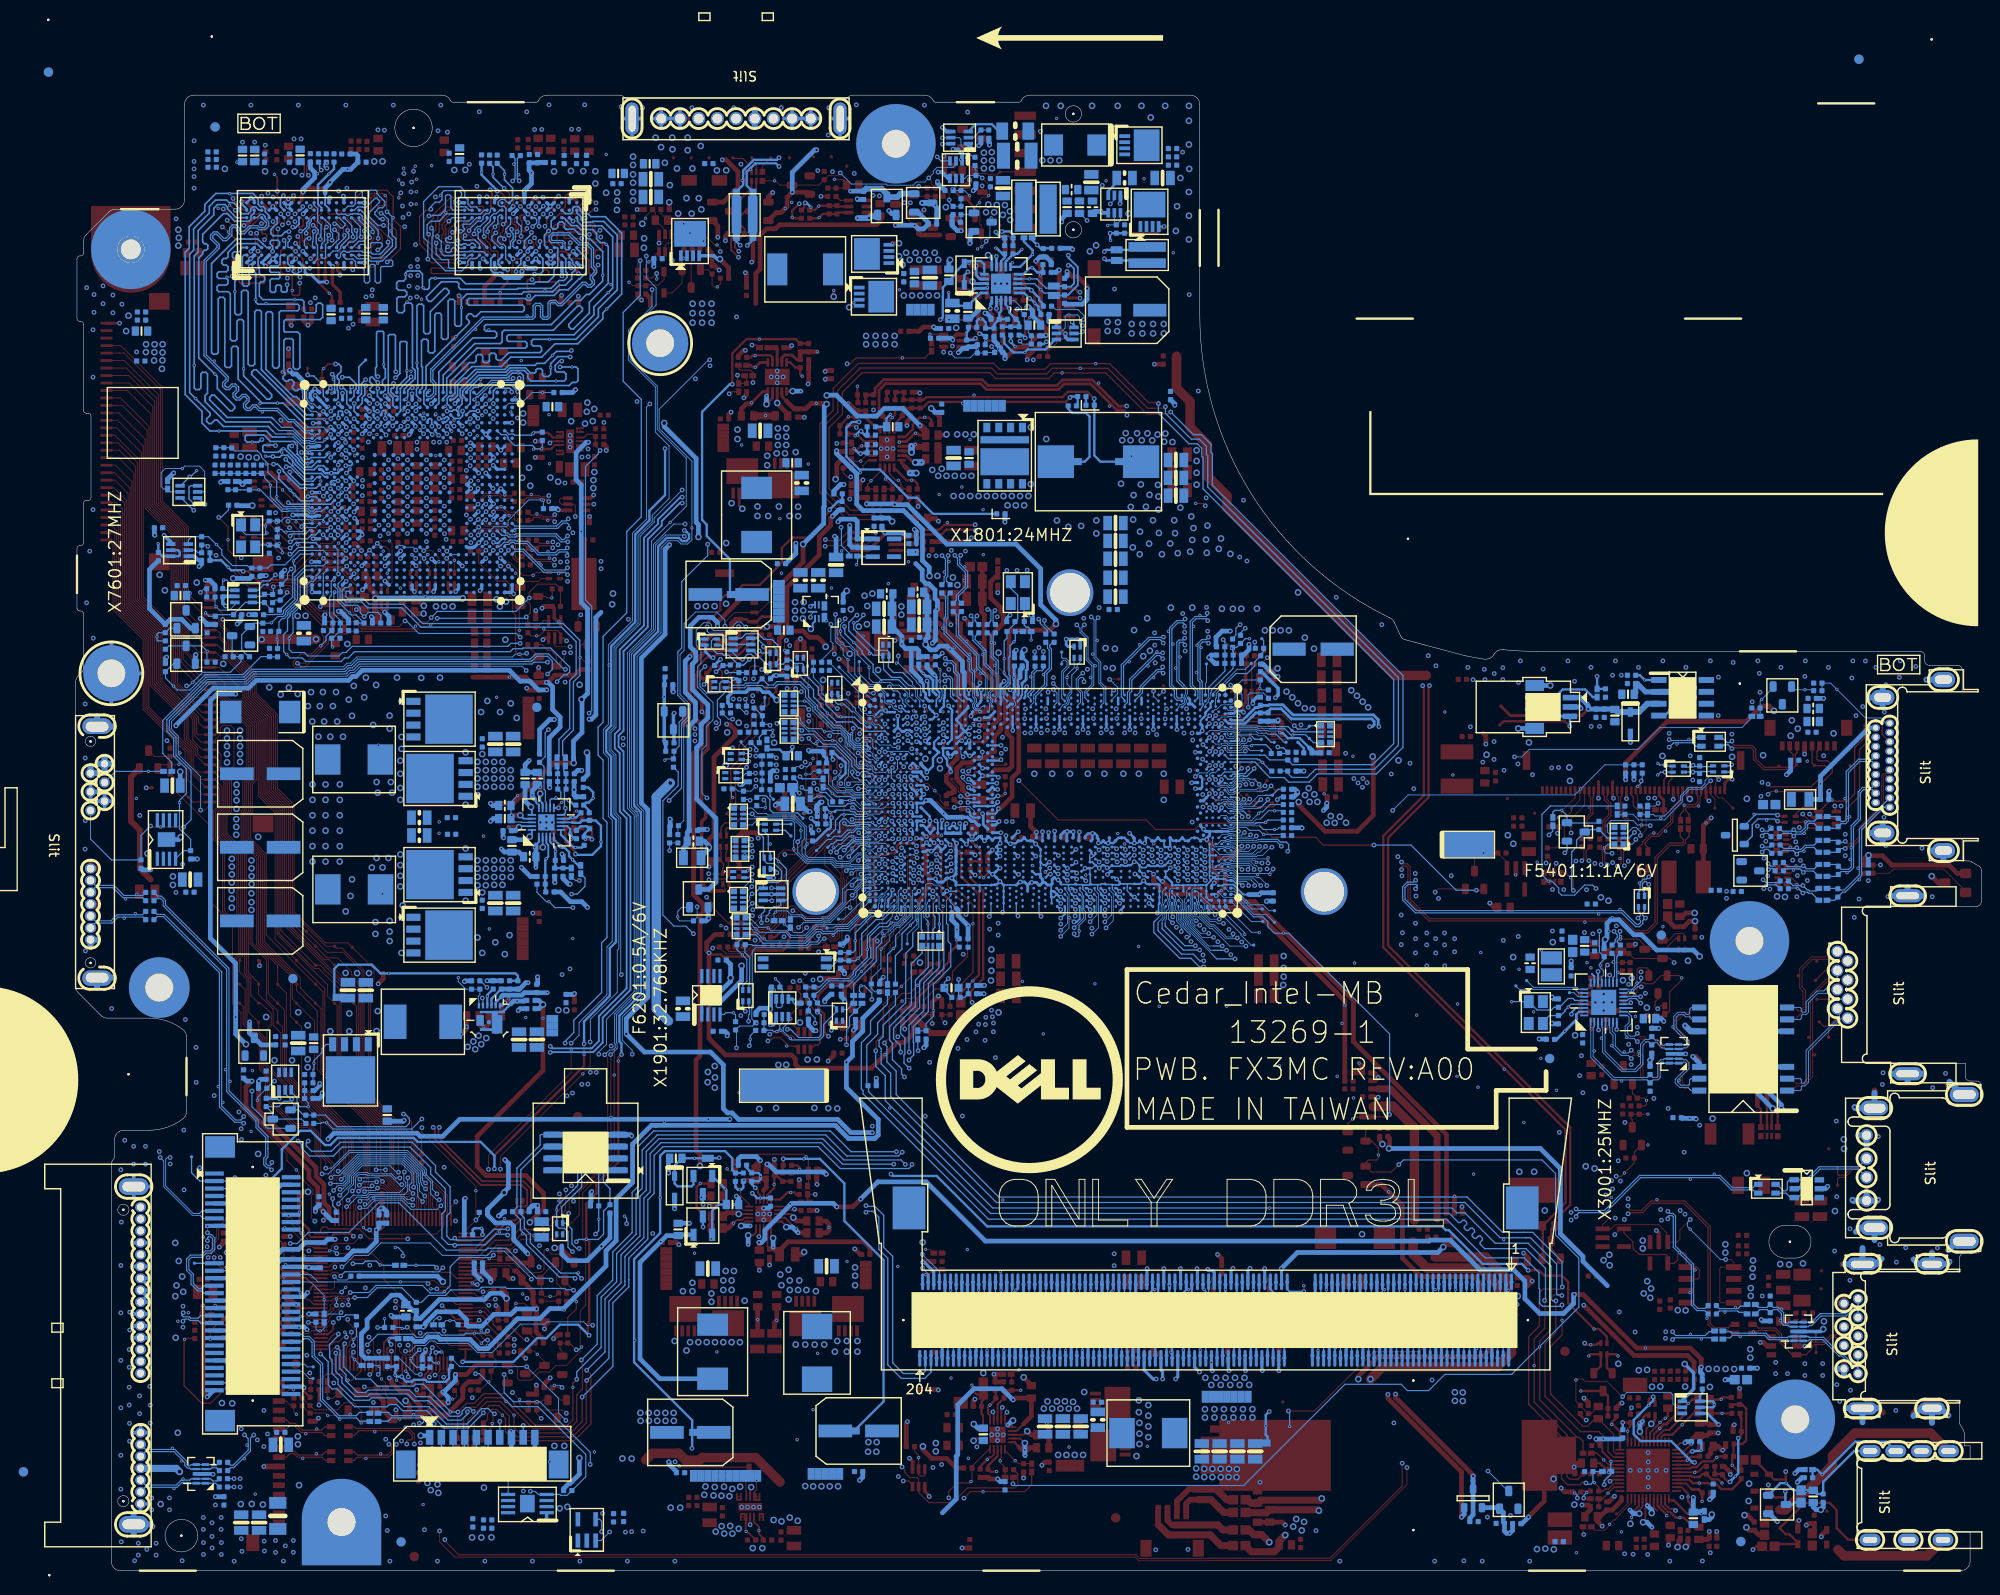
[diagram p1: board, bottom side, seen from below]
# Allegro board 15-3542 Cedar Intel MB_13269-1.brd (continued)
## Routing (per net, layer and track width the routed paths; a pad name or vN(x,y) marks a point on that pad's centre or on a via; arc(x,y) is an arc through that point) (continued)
FBA_DQS_RN5: length 40.2
  TOP w0.14: v2(163.62,121.94) 164.08,122.39 v1(164.08,122.47) ; v1(155.23,142.21) 154.99,142.21 154.92,142.15 154.91,142.15 154.85,142.09 154.85,141.67 154.93,141.59 VRAM4.G3
  L4 w0.127: v1(164.08,122.47) 163.91,122.65 163.91,122.93 163.52,123.32 163.11,123.32 163,123.43 163,123.63 163.23,123.87 163.23,124.26 162.85,124.64 162.85,125.57 162.18,126.23 161.76,126.23 161.19,126.8 161.19,127.31 161.42,127.53 161.42,128.33 161.14,128.62 160.42,128.62 160.15,128.34 160.15,127.48 159.98,127.31 159.71,127.31 159.62,127.41 159.62,128.62 159.36,128.88 158.89,128.88 158.63,128.62 158.63,127.56 158.5,127.43 158.17,127.43 158.09,127.51 158.09,128.18 157.83,128.44 157.22,128.44 157.06,128.28 155.28,128.28 154.44,129.11 154.44,129.8 154.18,130.06 154.18,133.7 154.6,134.12 154.6,134.44 154.18,134.86 154.18,135.18 154.27,135.27 154.66,135.27 154.92,135.53 154.92,136.04 154.71,136.26 154.15,136.26 153.98,136.43 153.98,136.7 154.07,136.79 154.92,136.79 155.11,136.98 155.11,137.52 154.86,137.78 153.91,137.78 153.79,137.91 153.79,138.45 153.86,138.52 154.07,138.52 154.29,138.74 154.29,139.15 154.16,139.27 154.16,140.86 154.07,140.95 154.07,141.48 154.16,141.57 154.39,141.57 154.43,141.61 154.46,141.61 154.99,142.14 155.16,142.14 v1(155.23,142.21)
  BOTTOM w0.14: GPU1.W22 163.73,122.11 164.08,122.46 v1(164.08,122.47)
FBA_DQS_RN6: length 40
  TOP w0.14: v1(147.76,143.44) 147.95,143.25 148.16,143.25 148.28,143.37 148.28,144.02 148.59,144.32 149.01,144.32 149.43,143.91 150.88,143.91 151.21,144.24 151.21,144.62 VRAM4.B7 ; v1(157.04,127.6) 157.58,127.6 157.58,127.6 v2(157.6,127.6)
  L3 w0.127: v1(157.04,127.6) 156.87,127.44 156.87,127.15 156.64,126.91 155.68,126.91 155.44,127.15 155.44,127.38 155.35,127.47 154.75,127.47 154.49,127.22 151.69,127.22 148.45,130.45 148.45,131.14 148.36,131.23 147.7,131.23 147.2,131.73 147.2,132.21 147.41,132.42 148.64,132.42 148.72,132.49 148.72,132.95 148.63,133.04 146.56,133.04 146.25,133.36 146.25,142.13 147.25,143.13 147.44,143.13 v1(147.76,143.44)
  BOTTOM w0.14: v1(157.04,127.6) 157.04,127.49 157.14,127.39 159.36,127.39 160.89,125.86 161.02,125.86 GPU1.AB27
FBA_DQS_RN7: length 41.3
  BOTTOM w0.14: VRAM3.B7 151.04,141.46 151.14,141.36 151.36,141.36 151.49,141.48 151.49,142.12 151.72,142.35 152.85,142.35 152.96,142.45 152.96,142.72 152.74,142.93 151.09,142.93 150.02,141.87 149.14,141.87 148.69,141.42 148.69,139.5 148.36,139.17 148.36,138.98 148.79,138.55 148.79,138.19 148.59,137.99 148.59,137.79 148.79,137.59 148.99,137.59 149.28,137.89 149.65,137.89 151.92,135.61 152.15,135.61 152.49,135.94 153.07,135.94 153.32,135.7 153.32,134.29 153.46,134.15 153.74,134.15 153.87,134.29 153.87,135.36 154.14,135.63 154.65,135.63 154.92,135.36 154.92,134.29 155.06,134.15 155.55,134.15 ; GPU1.T27 166.33,125.97 166.33,125.75 166.24,125.66 165.92,125.66 165.55,126.02 165.55,127.01 165.86,127.32 165.86,128.57 160.28,134.15 155.55,134.15 ; 155.55,134.15 v2(155.55,134.29)
FBA_EDC0: length 39.8
  TOP w0.14: v1(174.91,119.1) 174.92,119.09 175.13,119.09 v2(175.44,119.4) ; v1(181.72,144.03) 181.5,144.25 181.5,144.75 VRAM1.F3
  L3 w0.127: v1(181.72,144.03) 181.51,143.82 181.51,143.74 181.78,143.47 181.78,143.28 182.3,142.77 182.3,142.01 181.64,141.36 181.17,141.36 181.05,141.23 181.05,140.95 181.17,140.82 181.6,140.82 181.86,140.56 181.86,139.85 181.99,139.73 182.17,139.73 182.46,139.44 182.46,139.03 182.17,138.74 181.99,138.74 181.86,138.61 181.86,138.33 181.99,138.2 183.49,138.2 183.78,137.91 183.78,137.5 183.49,137.21 181.73,137.21 181.61,137.09 181.61,136.81 181.73,136.68 182.36,136.68 182.62,136.42 182.62,135.95 182.36,135.69 181.42,135.69 181.29,135.56 181.29,135.25 181.42,135.12 182.19,135.12 182.45,134.87 182.45,125.46 177.32,120.33 177.02,120.33 176,119.31 175.13,119.31 v1(174.91,119.1)
  BOTTOM w0.14: v1(174.91,119.1) 175.33,119.51 GPU1.E19
FBA_EDC1: length 47.5
  TOP w0.14: v1(184.48,143.13) 184.38,143.03 184.38,142.03 VRAM1.C7 ; v1(177.36,115.81) 177.62,116.07 v2(177.62,116.6)
  L4 w0.127: v1(184.48,143.13) 184.9,142.71 185.29,142.71 185.53,142.96 185.53,143.13 185.71,143.31 186.52,143.31 186.66,143.17 186.66,142.83 188.67,140.82 188.67,140.66 188.55,140.54 188.55,140.17 188.88,139.84 189.25,139.84 189.37,139.95 189.55,139.95 189.65,139.85 189.75,139.75 189.75,139.57 189.63,139.45 189.63,139.08 189.96,138.75 190.33,138.75 190.44,138.86 190.65,138.86 190.84,138.67 190.84,131.86 190.71,131.74 190.56,131.74 190.31,131.49 190.31,130.98 190.54,130.74 190.74,130.74 190.84,130.64 190.84,130.3 190.44,129.91 190.44,121.06 186.87,117.49 185.58,117.49 184.85,116.76 183.93,116.76 183.25,116.09 179.5,116.09 179.32,116.27 178.19,116.27 177.63,115.7 177.46,115.7 v1(177.36,115.81)
  BOTTOM w0.14: GPU1.C15 176.95,116.22 v1(177.36,115.81)
FBA_EDC2: length 38.7
  TOP w0.14: v2(180.54,118.41) 180.82,118.14 v1(181.31,118.14)
  L4 w0.127: v1(181.54,142.37) 181.34,142.17 181.34,140.01 181.95,139.4 181.95,139.11 181.8,138.96 181.8,138.78 182.03,138.55 182.32,138.55 183.14,137.73 183.14,137.36 182.76,136.98 182.76,136.73 182.76,136.73 184.97,134.52 184.97,124.79 184.74,124.57 184.44,124.57 184.06,124.95 183.83,124.95 183.63,124.75 183.63,124.57 184.33,123.88 184.33,123.47 184.03,123.18 183.62,123.18 182.93,123.87 182.75,123.87 182.55,123.67 182.55,123.49 182.81,123.23 182.81,122.86 182.13,122.18 181.82,122.18 181.71,122.07 181.71,121.71 181.78,121.64 182.08,121.64 182.33,121.39 182.33,120.89 181.83,120.4 181.83,119.54 182.02,119.35 182.02,118.82 181.34,118.14 v1(181.31,118.14)
  BOTTOM w0.14: v1(181.54,142.37) 181.39,142.21 181.39,141.74 VRAM2.F3 ; GPU1.B16 178.02,117.03 178.45,116.59 179.35,116.59 180.89,118.14 v1(181.31,118.14)
FBA_EDC3: length 43.5
  BOTTOM w0.14: 183.87,124.14 184.23,124.14 184.61,124.52 184.8,124.52 185.16,124.16 185.56,124.16 185.89,124.49 185.89,124.89 185.53,125.25 185.53,125.45 185.72,125.64 185.92,125.64 186.28,125.28 186.68,125.28 187.01,125.61 187.01,126.01 186.65,126.37 186.65,126.56 186.84,126.75 187.04,126.75 187.4,126.4 187.8,126.4 188.13,126.73 188.13,127.13 187.77,127.48 187.77,127.68 190.11,130.02 190.11,140.22 188.73,141.61 188.73,141.84 189.42,142.54 189.42,142.93 189.08,143.27 188.69,143.27 187.99,142.58 187.79,142.58 187.37,142.99 187.37,143.72 187.07,144.02 186.64,144.02 186.33,143.72 186.33,143.43 186.19,143.29 185.91,143.29 185.26,143.94 184.35,143.94 184.15,143.74 183.67,143.74 183.44,143.97 183.44,144.25 183.83,144.65 183.83,144.68 VRAM2.C7 ; 183.87,124.14 182.31,124.14 181.11,122.95 180.55,122.95 179.35,121.75 178.82,121.75 178.68,121.61 177.89,121.61 177.75,121.75 GPU1.B22 ; 183.87,124.14 v2(183.87,124.01)
FBA_EDC4: length 41.1
  L3 w0.127: v1(154.28,143.87) 154.28,143.81 153.09,142.62 153.09,141.74 153.46,141.36 153.46,138.06 154.56,136.96 155.82,136.96 156.7,136.08 159.61,136.08 160.28,135.41 163.36,132.32 165.52,132.32 167.32,130.52 167.32,130.34 167.12,130.15 166.94,130.15 165.43,131.66 165.06,131.66 164.73,131.33 164.73,130.96 165.73,129.96 165.73,127.55 165.99,127.29 166.46,127.29 166.72,127.55 166.72,128.82 166.85,128.95 167.13,128.95 167.25,128.82 167.25,126.98 166.83,126.55 166.83,124.74 v1(167.44,124.12)
  BOTTOM w0.14: GPU1.R25 167.19,124.49 167.44,124.24 v1(167.44,124.12) ; VRAM3.F3 154.28,144.75 v1(154.28,143.87)
FBA_EDC5: length 40.6
  TOP w0.14: v1(154.76,142.64) 154.61,142.49 154.61,141.96 VRAM4.F3 ; v1(163.37,122.48) v2(163.37,123.13)
  L4 w0.127: v1(163.37,122.48) 163.42,122.48 163.67,122.72 163.67,122.85 163.42,123.09 163.01,123.09 162.77,123.33 162.77,123.73 163,123.96 163,124.16 162.62,124.54 162.62,125.48 162.09,126 161.66,126 160.96,126.7 160.96,127.4 161.19,127.63 161.19,128.24 161.04,128.39 160.52,128.39 160.38,128.25 160.38,127.39 160.08,127.09 159.61,127.09 159.39,127.31 159.39,128.52 159.26,128.65 158.98,128.65 158.85,128.52 158.85,127.46 158.59,127.2 158.08,127.2 157.86,127.42 157.86,128.08 157.74,128.21 157.31,128.21 157.16,128.05 155.18,128.05 154.21,129.02 154.21,129.7 153.95,129.96 153.95,133.8 154.37,134.21 154.37,134.35 153.95,134.77 153.95,135.27 154.18,135.49 154.57,135.49 154.69,135.62 154.69,135.95 154.61,136.03 154.06,136.03 153.75,136.33 153.75,136.8 153.98,137.02 154.83,137.02 154.88,137.08 154.88,137.43 154.76,137.55 153.82,137.55 153.56,137.81 153.56,138.55 153.76,138.75 153.98,138.75 154.06,138.83 154.06,139.05 153.94,139.18 153.94,140.77 153.84,140.86 153.84,141.58 154.07,141.8 154.29,141.8 154.33,141.84 154.37,141.84 154.76,142.23 v1(154.76,142.64)
  BOTTOM w0.14: GPU1.W23 163.73,122.72 163.49,122.48 v1(163.37,122.48)
FBA_EDC6: length 40.4
  TOP w0.14: v1(147.67,142.72) 147.96,143 148.26,143 148.52,143.27 148.52,143.92 148.69,144.08 148.91,144.08 149.33,143.67 150.98,143.67 151.45,144.14 151.45,144.66 151.58,144.79 VRAM4.C7 ; v2(156.52,128.19) 156.4,128.06 v1(156.4,127.61)
  L3 w0.127: v1(156.4,127.61) 156.45,127.61 156.65,127.41 156.65,127.24 156.54,127.14 155.78,127.14 155.67,127.25 155.67,127.47 155.44,127.7 154.65,127.7 154.4,127.45 151.78,127.45 148.68,130.55 148.68,131.23 148.45,131.46 147.79,131.46 147.43,131.82 147.43,132.11 147.51,132.19 148.74,132.19 148.95,132.4 148.95,133.05 148.72,133.27 146.66,133.27 146.48,133.45 146.48,142.03 147.34,142.9 147.57,142.9 147.67,142.8 v1(147.67,142.72)
  BOTTOM w0.14: v1(156.4,127.61) 156.86,127.14 159.26,127.14 160.79,125.62 160.92,125.62 GPU1.AB26
FBA_EDC7: length 41.2
  BOTTOM w0.14: VRAM3.C7 151.73,141.7 151.73,142.02 151.82,142.11 152.95,142.11 153.2,142.35 153.2,142.82 152.84,143.17 150.99,143.17 149.92,142.11 149.04,142.11 148.45,141.52 148.45,139.6 148.12,139.27 148.12,138.88 148.55,138.45 148.55,138.29 148.35,138.09 148.35,137.69 148.69,137.35 149.09,137.35 149.38,137.64 149.55,137.64 151.82,135.37 152.25,135.37 152.59,135.7 152.97,135.7 153.07,135.6 153.07,134.19 153.36,133.91 153.84,133.91 154.12,134.19 154.12,135.26 154.24,135.39 154.55,135.39 154.68,135.26 154.68,134.19 154.96,133.91 160.18,133.91 161.15,132.94 ; 161.15,132.94 v2(161.05,132.85) ; 161.15,132.94 165.62,128.47 165.62,127.42 165.31,127.11 165.31,125.92 165.82,125.42 166.08,125.42 GPU1.T26
FBA_PLL_AVDD: length 3.2
  TOP w0.356: v1(174.09,116.63) 174.19,116.53 C7505.1
  TOP w0.508: C7506.1 168.26,121.48 v1(168.16,121.58)
  BOTTOM w0.356: GPU1.H22 172.81,122.02 173.17,121.66 v1(173.18,121.65) ; GPU1.F16 174.13,116.66 174.11,116.66 v1(174.09,116.63) ; v1(168.16,121.58) 167.94,121.79 167.94,121.96 GPU1.P22
  vias: v1(167.33,120.01) v2(165.33,119.32)
FBA_VREF_0: length 36.9
  TOP w0.229: VRAM1.M8 177.14,140.39 177.14,138.98
  TOP w0.356: v1(179.52,147.54) 179.66,147.41 179.66,146.67 VRAM1.H1
  TOP w0.381: v1(176.98,137.9) 177.14,138.07 177.14,138.98
  TOP w0.508: v1(179.52,147.54) 179.17,147.9 177.32,147.9 v1(176.64,148.58)
  L4 w0.305: v1(176.64,148.58) 176.64,147.65 175.97,146.98 175.97,145.02 175.39,144.44 175.39,143.79 175.62,143.55 175.62,142.62 175.08,142.08 175.08,140.18 175.84,139.41 175.84,139.09 176.32,138.62 176.32,138.57 v1(176.98,137.9)
  BOTTOM w0.203: VRAM2.M8 176.74,145.75 177.15,146.17 177.15,147.44
  BOTTOM w0.305: v1(176.98,137.9) 177.85,137.9 178.63,138.68 179.04,138.68 179.3,138.94 179.3,139.35 VRAM2.H1
  BOTTOM w0.508: R7807.1 178.74,150.11 178.28,149.65 178.28,149.06 179.52,147.81 v1(179.52,147.54) ; 177.15,147.44 177.15,147.97 176.64,148.48 v1(176.64,148.58) 175.25,149.97 v2(174.75,149.97) 174.42,149.97 R7806.2 173.66,151.43 173.84,151.61 C7803.1
FBA_VREF_1: length 35.3
  TOP w0.203: 159.44,145.99 159.44,146.8 159.3,146.93 159.3,147.58 v1(159.51,147.78)
  TOP w0.305: VRAM4.M8 159.44,145.99 ; VRAM4.H1 156.13,139.7 156.13,139.06 v1(156.11,139.04)
  L3 w0.305: v1(158.48,138.76) 158.48,139.11 157.94,139.64 157.94,140.24 156.49,141.7 156.21,141.7 155.74,142.16 155.74,142.52 155.74,142.52 155.68,142.59 155.68,143.01 155.97,143.31 155.98,143.31 156.12,143.45 156.12,143.77 156.45,144.1 157.24,144.1 159.32,146.18 159.32,147.59 v1(159.51,147.78)
  L4 w0.508: v1(155.84,147.69) 155.5,148.03 155.5,149.16 155.86,149.52 158.68,149.52 159.51,148.69 v1(159.51,147.78)
  BOTTOM w0.203: VRAM3.M8 159.44,140.39 159.44,139.21 158.98,138.76
  BOTTOM w0.356: VRAM3.H1 155.84,146.97
  BOTTOM w0.508: v1(156.11,139.04) 156.11,138.69 156.42,138.38 157.9,138.38 158.28,138.76 v1(158.48,138.76) 158.98,138.76 ; 155.84,146.97 v1(155.84,147.69) 155.09,148.44 v2(155.09,149.62) 155.34,149.87 155.34,150.64 R7904.1 C7902.1 154.39,150.7 R7903.2
FBA_ZQ0: length 5.8
  TOP w0.229: 177.86,139.19 177.86,139.76 177.93,139.83 177.93,140.15 177.54,140.55 VRAM1.L8
  TOP w0.254: R7808.2 176.44,136.44 v2(176.71,136.71) 177.86,137.86 177.86,139.19
FBA_ZQ1: length 6
  BOTTOM w0.203: 177.92,147.48 177.92,146.23 177.54,145.85 VRAM2.L8
  BOTTOM w0.254: R7809.2 176.21,150.02 v2(176.76,149.47) 177.92,148.31 177.92,147.48
FBA_ZQ2: length 6.2
  TOP w0.254: v1(157.63,139.24) 157.66,139.21 157.66,137.86 158.44,137.08 v2(158.44,136.77) R7912.2
  BOTTOM w0.229: VRAM3.L8 158.24,140.62 158.63,140.23 158.63,139.81 158.51,139.68 158.51,139.66 158.09,139.24 v1(157.63,139.24)
FBA_ZQ3: length 6.4
  TOP w0.178: v1(158.74,147.64) 158.51,147.64 157.87,147 157.87,146.24 158.24,145.87 VRAM4.L8
  BOTTOM w0.254: v1(158.74,147.64) 158.74,147.7 160.42,149.38 v2(160.42,149.67) R7913.2
FON#: length 2.7
  BOTTOM w0.254: R2605.2 36.52,95.83 v2(36.01,95.32) 34.49,95.32
GC6_FB_EN: length 211.3
  TOP w0.127: R2028.1 132.1,67.8 131.76,67.46 v1(131.16,67.46)
  L3 w0.127: v1(187.75,34.05) 187.75,33.24 187.97,33.02 187.97,19.64 184.91,16.58 182.01,16.58 181.15,17.44 179.14,17.44 178.42,18.17 177.07,18.17 176.35,17.44 172.55,17.44 v1(172,18) ; v1(131.16,67.46) 131.29,67.46 132.48,66.26 132.48,66.19 133.26,65.41 133.26,64.32 132.95,64 132.95,59.66 v1(132.69,59.4) ; v1(189.7,109.62) 189.7,107.88 189.15,107.33 189.15,103.95 187.35,102.15 187.35,99.69 190.82,96.23 191.92,96.23 192.95,95.2 192.95,92.09 191.67,90.81 191.67,85.45 192.45,84.66 192.45,80.48 193.46,79.47 193.46,75.58 192.36,74.49 192.36,63.34 189.02,60 v1(189.02,50.84) 189.02,42.03 187.42,40.43 v1(186.84,40.43) ; v1(150.81,41.2) 150.81,40.62 154.64,36.79 154.64,35.76 156.23,34.17 156.23,33.35 158.13,31.45 158.13,30.33 158.46,29.99 158.73,29.72 159.44,29.72 160.43,28.72 161.95,28.72 164.09,26.58 167.22,26.58 168.19,25.61 171.12,25.61 v1(171.54,26.03)
  L4 w0.127: v1(132.69,59.4) 132.76,59.4 134.75,57.4 134.75,55.76 136.79,53.73 136.79,49.92 140.66,46.04 141.95,46.04 144.62,43.38 145.11,43.38 147.22,41.26 150.74,41.26 v1(150.81,41.2) ; v1(189.02,50.84) 188.54,51.33 v1(184.99,51.33) ; v1(171.54,26.03) 170.73,25.22 170.73,20.81 170.74,20.8 170.74,20.2 172,18.94 v1(172,18) ; v1(187.75,34.05) 187.71,34.09 187.71,39.73 187.02,40.43 v1(186.84,40.43)
  BOTTOM w0.127: v1(189.7,109.62) 189.84,109.76 R7623.1 190.36,108.94 R7519.2 190.75,108.94 191.02,109.21 Q7603.2 ; v1(171.54,26.03) 171.54,26.03 R2451.1 170.8,26.96 v2(170.8,26.97) ; v1(184.99,51.33) 184.99,49.66 183.75,48.43 183.75,47.77 183.32,47.34 D8301.1
GC6_FB_EN_GPU: length 18.1
  BOTTOM w0.127: GPU1.C6 177.34,109.18 179.9,109.18 181.45,107.64 182.96,107.64 183.29,107.3 R7627.1 184.99,107.3 R7647.1 185.2,107.29 185.47,107.56 187.07,107.56 188.21,108.7 188.21,109.24 v2(188.78,109.81) 189.62,110.65 R7623.2 191.45,110.65 191.79,110.3 Q7603.3
GC6_FB_EN_KBC: length 6
  TOP w0.127: v1(168.38,26.05) 167.84,25.52 167.84,23.44 167.29,22.89 KBC24.106
  BOTTOM w0.127: v1(168.38,26.05) 168.51,25.92 v2(168.92,25.92) 169.03,26.03 R2451.2
GC6_FB_EN_MCP: length 22.4
  TOP w0.127: R2028.2 130.85,68.14 130.59,68.39 130.19,68.39 129.9,68.68 129.44,68.68 128.09,70.03 128.09,73.48 127.56,74.02 127.56,74.13 124.44,77.25 124.34,77.25 123.28,78.32 123.27,78.32 122.48,78.32 122.35,78.19 120.65,78.19 v2(120.56,78.28) 120.52,78.25 119.21,78.25 118.78,78.68 118.78,79.04 118.78,79.15 118.61,79.32 117.6,79.32 117.58,79.3 v1(116.51,79.3)
  BOTTOM w0.127: v1(116.51,79.3) 116.51,79.05 CPU1.AG5
GPIO5_GC6_PWR_EN: length 16.3
  BOTTOM w0.127: R7636.2 183.08,97.79 R8315.2 184.02,97.82 185.95,95.89 189.98,95.89 191.62,94.24 192.95,94.24 v2(193.37,94.66) 194.23,95.53 R8301.1 193.38,97.07 Q8301.G
GPIO5_GC6_PWR_EN#: length 6
  BOTTOM w0.127: R8302.2 189.8,98.35 v2(189.76,98.39) 190.34,98.97 Q8301.D 193.88,98.97 R8303.1
GPIO5_GC6_PWR_EN_GPU: length 10
  BOTTOM w0.127: R7636.1 182.24,99.56 v2(182.29,99.61) 182.29,100.33 R7633.2 182.09,100.54 182.09,101.54 181.75,101.88 181.53,101.88 181.14,102.27 181.14,102.54 179.82,103.87 179.82,106.09 179.47,106.43 178.69,106.43 GPU1.A3
GPIO5_GC6_PWR_EN_R#: length 4
  BOTTOM w0.127: Q8302.G 193.78,100.86 C8301.2 194.99,100.38 195.15,100.22 v2(195.15,99.94) 195.15,99.59 195.06,99.5 R8303.2
GPIO9_ALERT: length 18.1
  TOP w0.127: v1(182.48,106.56) 182.41,106.5 180.71,106.5 178.62,108.6 178.11,108.6 177.26,109.45 175.46,109.45 174.91,109.99 174.91,110.01 v1(174.9,110.02)
  BOTTOM w0.127: v1(182.48,106.56) 183.12,105.92 183.82,105.92 184.1,105.64 187.3,105.64 187.68,106.01 v2(188.01,106.01) 188.11,105.91 R7612.1 187.93,104.92 Q7602.1 ; v1(174.9,110.02) 174.88,110.04 174.86,110.04 174.51,110.39 GPU1.F8
GPIO10_FBVREF: length 10.7
  BOTTOM w0.127: R7610.1 183.73,102.32 182.57,102.32 182.54,102.34 181.72,102.34 181.6,102.46 181.6,102.73 180.4,103.93 180.4,106.33 179.19,107.54 177.35,107.54 GPU1.C5
GPU_CLKREQ#: length 19.2
  TOP w0.127: v1(159.95,109.2) 160.02,109.13 R7303.1 160.73,107.86 158.76,105.9 157.74,105.9 157.42,105.57 157.42,104.36 157.11,104.06 157.11,102.56 156.79,102.24 156.79,98.41 v2(156.44,98.06) 155.75,97.37 154.73,97.37 Q7301.S 155.47,98.93 R7305.2
  BOTTOM w0.102: GPU1.AC6 160.35,108.8 v1(159.95,109.2)
GPU_EVENT#: length 161.3
  TOP w0.127: v1(136.34,72.08) 135.7,71.44 135.7,70.97 134.03,69.3 R2029.1
  L3 w0.127: v1(152.97,31.11) 151.94,32.14 151.94,34.58 151.22,35.3 151.22,37.26 148.16,40.32 148.16,43.96 140.03,52.09 140.03,69.14 137.1,72.08 v1(136.34,72.08) ; v1(180.89,35.02) 181.91,36.04 181.91,38.32 187.42,43.83 187.42,44.59 188.26,45.43 188.26,60.14 191.73,63.61 191.73,79.99 191.82,80.08 191.82,84.4 191.03,85.18 191.03,91.23 191.98,92.17 v1(191.98,94.69)
  BOTTOM w0.127: Q7606.D 187.11,97.93 R7648.1 R7644.1 186.14,97.31 187.31,96.14 190.25,96.14 v2(191.31,95.08) 191.7,94.69 v1(191.98,94.69) ; v1(180.89,35.02) 180.13,35.02 178.95,36.2 174.6,36.2 171.44,39.36 169.26,39.36 164.2,34.3 159.95,34.3 159.74,34.51 157.77,34.51 154.55,31.29 153.16,31.29 v1(152.97,31.11)
GPU_EVENT_GPU#: length 14.7
  BOTTOM w0.127: GPU1.A4 179.26,107.09 180.11,106.24 180.11,103.9 181.37,102.64 181.37,102.37 181.62,102.11 182.23,102.11 v2(182.9,101.44) 182.94,101.4 R7649.1 184.84,101.4 Q7606.S 186.08,100.16 186.08,98.54 185.34,97.81 R7644.2
GPU_EVENT_MCP#: length 27.1
  TOP w0.127: R2029.2 132.57,69.29 131.17,69.29 130.38,70.08 129.41,70.08 128.87,70.63 128.87,73.74 128.29,74.31 128.29,75.15 128.66,75.52 v2(128.66,75.89) 128.66,76.61 128.16,77.11 126.82,77.11 125.64,78.29 124.62,78.29 123.62,79.29 122.09,79.29 121.97,79.17 121.16,79.17 120.55,79.78 120.55,79.78 120.01,80.32 120.01,81.21 119.6,81.62 118.87,81.62 118.8,81.55 117.69,81.55 117.56,81.68 116.3,81.68 115.84,82.14 v1(115.79,82.14)
  BOTTOM w0.127: CPU1.AB6 115.61,81.96 v1(115.79,82.14)
GPU_PEX_RST#: length 50.1
  TOP w0.127: v1(155.31,104.1) 155.31,104.7 154.43,105.58 152.49,105.58 R7308.1 R7312.2 ; v1(165.81,102) 165.81,101.92 166.22,101.52 167.05,101.52 v2(167.49,101.08) 167.8,100.77 173.25,100.77 174.06,101.57 177,101.57 177.31,101.88 177.35,101.88 180.89,105.42 182.57,105.42 v1(182.7,105.29)
  L3 w0.127: v1(155.31,104.1) 158.21,107 159.71,107 160.42,107.71 160.42,109.63 160.05,110.01 v1(159.94,110.01)
  BOTTOM w0.127: v1(159.94,110.01) 159.94,109.94 160.28,109.59 GPU1.AC7 ; v1(165.81,102) 165.15,102.66 156.76,102.66 v1(155.31,104.1) ; Q7602.5 183.88,104.27 R7613.1 183.64,104.47 R7313.2 182.7,104.55 v1(182.7,105.29)
GPU_PEX_RST_D#: length 2.5
  TOP w0.127: D7301.3 153.59,104.26 153.44,104.11 v2(152.91,104.11) 152.87,104.14 R7308.2
GPU_PEX_RST_HOLD: length 25.9
  TOP w0.127: D7301.1 156.39,103.18 v2(156.39,100.63) 156.39,99.99 v1(156.29,99.9) ; v1(168.6,101.64) 169.23,101.02 173.14,101.02 174.47,102.35 174.47,104.11 R7631.2 174.37,105.02 R7630.2
  BOTTOM w0.127: v1(168.6,101.64) 168.47,101.64 167.12,100.3 156.69,100.3 v1(156.29,99.9)
GPU_PEX_RST_HOLD_GPU#: length 5.6
  TOP w0.127: v1(177.35,104.13) 176.74,104.75 v2(176.15,104.75) 175.53,104.75 R7630.1
  BOTTOM w0.127: v1(177.35,104.13) 177.35,104.41 177.35,106.69 GPU1.C4
GPU_PLL_VDD: length 0.6
  BOTTOM w0.356: v1(170.76,108.32) 170.35,108.73 GPU1.L6
  vias: v2(170.94,109.11)
H_CATERR#: length 5.3
  BOTTOM w0.089: CPU1.K61 81.43,88.07 81.19,88.32 80.78,88.32 80.6,88.14 80.6,87.95 80.4,87.75 79.89,87.75 79.88,87.75
  BOTTOM w0.102: TP402.1 76.98,87.76 78.2,87.76 78.38,87.94 78.39,87.94 78.57,88.12 78.92,88.12 79.28,87.75 79.88,87.75
H_CPU_SVIDALRT#: length 5.7
  BOTTOM w0.14: CPU1.L62 80.5,86.87 77.47,86.87 77.37,86.78 77.19,86.78 v2(76.92,86.51) 75.98,85.57 R701.2
H_CPU_SVIDCLK: length 123.8
  TOP w0.14: PR4616.2 118.25,114.13 118.9,113.48 120.91,113.48 123.25,115.82 123.25,122.33 121.83,123.75 121.83,126.1 119.71,128.21 106.07,128.21 105.44,127.58 99.74,127.58 99.15,128.18 v2(98.32,128.18) 93.65,128.18 89.27,123.81 86.9,123.81 v1(86.71,124)
  BOTTOM w0.14: CPU1.N63 77.69,86.53 77.08,85.93 77.08,85.86 76.1,84.88 74.58,84.88 74.1,84.4 71.89,84.4 71.02,85.26 64.71,85.26 61.86,88.11 61.86,95.79 82.25,116.18 82.25,119.54 82.4,119.69 82.4,120.54 83.44,121.59 84.29,121.59 v1(86.71,124)
H_CPU_SVIDDAT: length 128
  TOP w0.14: v1(88.02,124.9) 88.14,125.01 89.08,125.01 93.24,129.17 v2(94.71,129.17) 99.56,129.17 100.15,128.57 105.03,128.57 105.66,129.2 120.12,129.2 122.82,126.51 122.82,124.16 124.24,122.74 124.24,115.41 121.32,112.49 118.31,112.49 117.38,113.42 115.59,113.42 114.7,114.32 PR4619.2
  BOTTOM w0.14: v1(88.02,124.9) 88.02,123.86 84.76,120.6 83.86,120.6 83.39,120.13 83.39,119.22 83.24,119.08 83.24,115.77 62.85,95.38 62.85,88.52 65.12,86.25 73.68,86.25 R704.2 74.19,86.77 76.12,86.77 76.63,87.28 77.17,87.28 77.18,87.28 CPU1.L63
H_CPUPWRGD: length 10.2
  BOTTOM w0.102: 81.58,94.14 81.84,93.88 81.84,93.39 81.91,93.32 81.91,92.5 CPU1.C61
  BOTTOM w0.127: 81.58,94.14 79.71,96.01 78.53,96.01 77.7,96.84 77.7,97.28 R405.1 77.08,98.08 76.76,98.4 R411.2 76.76,99.54 TP403.1
H_PECI: length 287.5
  TOP w0.14: R2429.2 185.63,32.01 186.07,32.45 v2(187.73,32.45) 188.29,32.45 189.03,33.19 v1(189.03,33.51)
  L3 w0.127: v1(58.06,71.93) 58.45,71.93 59.12,72.6 59.12,78.52 67.24,86.64 67.24,87.81 67.67,88.24 70.93,88.24 73.15,86.02 76.58,86.02 77.3,86.74 80.69,86.74 v1(81.27,86.15)
  L4 w0.127: v1(189.03,33.51) 189.03,19.42 188.77,19.17 188.77,17.21 187.27,15.71 187.27,12.98 179.16,4.86 179.16,4.84 176.4,2.09 132.57,2.09 131.7,2.97 130.24,2.97 130.21,2.94 130.12,2.94 129.3,2.12 110.34,2.12 109.21,3.24 106.58,3.24 106.22,2.88 77.7,2.88 70.91,9.67 49.45,9.67 46.76,12.36 46.76,16.61 34.45,28.91 34.45,34.45 36.39,36.39 36.39,41.17 38.66,43.43 39.19,43.43 41.15,45.38 41.45,45.38 54.76,58.69 54.76,68.63 v1(58.06,71.93)
  BOTTOM w0.14: v1(81.27,86.15) 80.92,86.51 CPU1.N62
H_PROCHOT#: length 342.2
  TOP w0.14: PR4426.2 113.02,129.79 v2(115.42,129.79) 120.36,129.79 121,129.15 v1(121.32,129.15) ; C2421.1 R2440.2 185.62,36.13 v1(185.57,36.18) ; 143.74,139.15 143.74,139.92 v1(143.46,140.2) ; 143.74,139.15 PR4466.2 ; 143.74,139.15 PR4465.1 ; PR4624.2 PR4602.2 122.38,120.67 v1(122.42,120.63)
  L3 w0.127: v1(82.92,114.81) 83.58,114.15 83.58,113.8 76.91,107.13 76.91,102.1 78.08,100.93 78.08,100.19 78.88,99.39 78.88,98.45 75.32,94.9 73.34,94.9 70.98,92.54 70.98,90.17 73.01,88.14 v1(75.26,88.14) ; v1(164.43,43.17) 162.67,43.17 151.64,54.2 151.64,54.52 151.48,54.68 v1(151.48,56.45) ; v1(121.32,129.15) 121.32,129.23 125.28,133.19 132.34,133.19 132.77,132.76 133.98,132.76 135.15,131.59 138.2,131.59 143.46,136.85 v1(143.46,140.2) 142.47,140.2 141.94,140.72 141.94,143.24 141.5,143.68 141.5,147.83 140.51,148.82 139.11,148.82 138.64,149.29 138.59,149.29 138.59,149.29 137.9,149.29 137.9,149.29 137.67,149.29 133.93,153.03 124.41,153.03 124.03,152.65 119.72,152.65 117.24,155.14 115.26,155.14 112.85,152.72 112.85,152.47 v1(111.68,151.3) 111.16,151.82 110.92,151.82 107.95,154.79 100,154.79 96.24,151.03 95.26,151.03 89.84,145.61 89.84,140.04 v1(92.72,137.16)
  L4 w0.127: v1(82.92,114.81) 82.75,114.98 82.75,121.3 85.09,123.63 85.09,135.27 86.98,137.16 v1(92.72,137.16) ; v1(185.57,36.18) 184.69,37.06 184.69,37.81 180.48,42.02 177.18,42.02 176.92,42.28 176.92,42.29 176.01,43.2 172.62,43.2 171.89,42.46 170.51,42.46 169.8,43.17 v1(164.43,43.17) ; v1(121.32,129.15) 120.88,128.71 120.88,125.2 123.01,123.06 123.01,121.21 v1(122.42,120.63)
  BOTTOM w0.14: R403.1 74.31,87.45 R401.2 74.65,88.05 75.17,88.05 v1(75.26,88.14) ; v1(143.46,140.2) 143.46,136.47 145.28,134.65 145.28,127.29 143.34,125.35 143.34,112.76 144.89,111.21 144.89,102.51 147.43,99.98 147.43,90.79 147.96,90.26 147.96,87.28 147.43,86.75 147.43,80.51 147.01,80.09 147.01,67.76 147.58,67.19 147.58,61.88 150.56,58.9 150.56,57.58 151.48,56.65 v1(151.48,56.45) ; v1(111.68,151.3) 111.68,151.27 111.27,150.87 PQ4203.3
H_PROCHOT#_EC: length 6.3
  TOP w0.14: v2(182.22,33.75) 182.15,33.81 182.15,34.59 R2438.2 182.95,35.39 Q2401.D 187.06,35.39 R2440.1
H_PROCHOT#_R: length 5.1
  BOTTOM w0.089: CPU1.K63 79.32,88.03 79.05,88.3 78.49,88.3 78.46,88.27 78.09,88.27 v2(78.06,88.3)
  BOTTOM w0.14: v2(78.06,88.3) 77.97,88.39 76.52,88.39 75.96,87.82 R403.2
H_RCIN#: length 126.8
  TOP w0.102: RN2002.8 122.67,92.64 122.53,92.78 122.22,92.78 121.78,92.33 121.78,90.14 121.91,90.01 121.91,89.01 v1(122.02,88.9) 122.02,88.58 121.25,87.8 121.25,87.06 120.62,86.43 120.62,86.24 120.12,85.74 119.62,85.74 118.67,84.8 v2(118.67,84.51) 117.29,83.13 v1(117.25,83.13) ; KBC24.122 173.69,23.21 173.69,23.21 173.69,23.57 173.69,23.57 173.69,25.57 174.75,26.63 v1(174.75,26.89)
  L3 w0.102: v1(174.72,34.56) 174.3,34.98 172.4,34.98 170.04,37.34 165.27,37.34 163.55,39.07 163,39.07 162.74,39.32 162.74,40.46 164.99,42.7 164.99,43.6 162.01,46.57 160.05,46.57 152.2,54.43 152.2,54.75 152.05,54.9 152.05,56.68 151.66,57.06 150.2,57.06 149.68,57.58 148.56,57.58 144.2,61.94 144.2,71.69 139.51,76.38 139.51,81.69 136.8,84.41 134.72,84.41 133.08,86.05 133.08,86.39 132.91,86.56 132.91,88.19 132.17,88.92 130.83,88.92 130.35,89.4 130.35,90.62 129.64,91.33 128.37,91.33 127.02,92.68 125.66,92.68 125.56,92.78 122.23,92.78 121.93,92.48 121.93,88.99 122.02,88.91 v1(122.02,88.9)
  L4 w0.102: v1(174.72,34.56) 173.74,33.59 173.74,32.49 172.41,31.16 172.41,29.89 172.74,29.56 172.74,28.9 v1(174.75,26.89)
  BOTTOM w0.102: v1(117.25,83.13) 117.24,83.13 116.94,83.43 CPU1.V4
H_THERMTRIP#: length 232.1
  TOP w0.102: Q3602.E 151.95,18.26 152.85,19.15 R3608.2 152.84,19.6 v1(151.82,19.6)
  L3 w0.102: v1(111.21,11.36) 111.21,11.07 110.96,10.83 102.4,10.83 102.23,10.66 102.22,10.66 99.62,8.06 88.01,8.06 83.61,12.45 77.94,12.45 73.47,16.93 63.75,16.93 62.05,18.63 62.05,20.92 60.93,22.04 51.01,22.04 47.22,25.82 47.22,27.36 48.04,28.18 48.04,29.47 40.41,37.1 38.04,37.1 37.13,38.01 37.13,39.84 37.53,40.24 38.09,40.24 39.1,39.24 40.49,39.24 46.45,45.2 46.45,50.08 53.19,56.81 53.19,67.73 57.63,72.18 57.63,77.82 65.89,86.07 65.89,87.57 67.13,88.82 71.14,88.82 73.35,86.61 75.36,86.61 77.84,89.09 77.84,89.1 78.09,89.35 78.1,89.35 78.42,89.67 v1(78.42,92.39)
  L4 w0.102: v1(151.82,19.6) 153.06,18.37 153.06,14.57 153.06,14.57 153.06,14.56 152.65,14.15 142.47,14.15 142.36,14.04 137.19,14.04 136.39,13.23 120.54,13.23 120.06,12.76 120.06,12.75 119.36,12.06 115.3,12.06 114.74,11.5 111.34,11.5 v1(111.21,11.36)
  BOTTOM w0.102: v2(152.63,19.83) 152.05,19.83 v1(151.82,19.6) ; R2027.2 76.26,93.4 76.79,93.93 78.22,93.93 78.42,93.73 v1(78.42,92.39)
H_THERMTRIP_EN: length 233.2
  TOP w0.102: Q3602.B 153.87,18.26 154.12,18.01 C3604.1 155.4,18.01 R3605.1 155.42,17.99 R3606.2 155.71,17.2 156.35,17.84 v2(156.35,18.33) 156.37,18.33 v1(157.11,19.07)
  L3 w0.102: v1(77.71,99.38) 77.71,98.18 76.64,97.11 74.71,97.11 70.41,92.8 70.41,90.81 68.65,89.06 67.03,89.06 65.64,87.67 65.64,86.17 57.39,77.92 57.39,72.28 52.94,67.83 52.94,56.91 46.21,50.18 46.21,45.3 40.39,39.48 39.2,39.48 38.23,40.45 37.45,40.45 36.92,39.92 36.92,37.93 38,36.85 40.31,36.85 47.8,29.37 47.8,28.28 46.98,27.46 46.98,25.72 50.91,21.8 60.83,21.8 61.81,20.82 61.81,18.53 63.65,16.68 71.33,16.68 73.37,16.68 77.84,12.21 83.51,12.21 87.91,7.82 99.72,7.82 102.32,10.42 111.51,10.42 v1(112.14,11.04)
  L4 w0.102: v1(157.11,19.07) 155.9,19.07 153.56,16.73 153.56,14.51 152.96,13.91 142.57,13.91 142.46,13.8 137.63,13.8 136.82,12.99 120.64,12.99 120.3,12.66 119.45,11.8 115.39,11.8 114.63,11.04 v1(112.14,11.04)
  BOTTOM w0.102: R411.1 77.71,98.77 v1(77.71,99.38)
H_VCCST_PWRGD: length 13.2
  TOP w0.127: U701.4 78.7,96.95 R707.2 R9601.1 79.39,97.92 v2(80.19,98.72) v1(81.1,99.64)
  BOTTOM w0.089: CPU1.B59 82.99,93.13 82.67,93.45 82.67,94.13
  BOTTOM w0.127: v1(81.1,99.64) 80.91,99.45 R706.2 EC701.1 R709.1 80.91,96.27 82.67,94.51 82.67,94.13
H_VR_ENABLE: length 79.1
  TOP w0.127: v1(81.9,90.64) 81.43,90.17 77.44,90.17 76.26,88.99 74.09,88.99 v2(73.65,89.43) 72.77,90.31 v1(72.77,90.51) ; PR4621.2 120.89,114.84 v1(121.05,114.68)
  L3 w0.127: v1(72.77,90.51) 72.77,91.48 74.87,93.58 74.87,93.64 79.45,98.22 79.45,100.14 v1(78.73,100.86) 78.73,101.57 78.29,102.01 78.29,105.82 78.55,106.08 v1(78.55,108.05)
  L4 w0.127: v1(121.05,114.68) 120.87,114.68 119.37,113.18 119.33,113.18 119.31,113.16 111.78,113.16 111.13,112.51 106.66,112.51 105.25,111.1 99.91,111.1 99.1,110.29 95.26,110.29 94.83,109.87 94.82,109.87 92.81,107.86 78.74,107.86 v1(78.55,108.05)
  BOTTOM w0.102: CPU1.F60 82.22,90.33 v1(81.9,90.64)
  BOTTOM w0.127: v1(78.73,100.86) 79.25,100.34 R710.1
HDA_BITCLK: length 10.1
  BOTTOM w0.089: 114.24,69.38 114.03,69.59 114.03,70.41 114.03,70.41 114.03,70.62 113.73,70.92 113.73,71.45 CPU1.AW8
  BOTTOM w0.14: R1907.2 116.15,65.82 115.46,66.52 115.46,68.17 v2(114.55,69.08) 114.24,69.38
HDA_CODEC_BITCLK: length 124.6
  TOP w0.14: R2720.1 41.78,10.37 EC2709.1 43.17,9.79 44.01,9.79 44.32,10.1 44.32,11.92 44.18,12.06 43.7,12.06 43.56,12.2 43.56,12.51 43.7,12.65 44.18,12.65 44.32,12.79 44.32,13.11 44.18,13.25 43.7,13.25 43.56,13.39 43.56,13.71 43.7,13.85 44.18,13.85 44.32,13.99 44.32,14.55 47.83,18.06 v2(47.83,21.94) 47.83,24.8 46.68,25.95 46.68,28.79 46.72,28.83 v1(46.72,28.92)
  BOTTOM w0.14: v1(46.72,28.92) 46.62,29.02 46.62,32.36 48.71,34.46 53.12,34.46 53.61,34.95 53.61,35.15 53.37,35.39 53.37,35.59 53.59,35.82 53.79,35.82 54.03,35.57 54.23,35.57 54.46,35.79 54.46,35.99 54.21,36.24 54.21,36.44 54.43,36.66 54.63,36.66 54.88,36.41 55.08,36.41 55.3,36.64 55.3,36.84 55.05,37.08 55.05,37.28 55.28,37.5 55.48,37.5 55.72,37.26 55.92,37.26 56.89,38.23 105.99,38.23 119.03,51.27 119.03,51.84 EC1901.2 119.22,52.03 119.22,56.24 118.06,57.4 118.06,58.64 116.15,60.54 R1907.1
HDA_CODEC_RST#: length 120
  TOP w0.14: v1(44.85,28.43) v2(44.85,26.79) 44.85,25.21 46.08,23.99 46.08,18.91 42.63,15.46 42.11,15.46 41.31,16.26 R2917.1 39.34,14.62 39.34,12.75 39.12,12.54 HDA27.11
  BOTTOM w0.14: R1911.1 117,60.66 118.81,58.84 118.81,57.47 119.8,56.48 119.8,51.57 119.61,51.38 119.61,51.03 106.2,37.62 57.2,37.62 53.07,33.48 48.9,33.48 47.31,31.89 47.31,30.19 47.24,30.12 47.24,28.61 46.92,28.29 45,28.29 v1(44.85,28.43)
HDA_CODEC_SDIN0: length 3.6
  TOP w0.14: R2718.2 41.1,12.57 v2(40.38,11.85) 40.38,11.85 39.86,11.34 HDA27.8
HDA_CODEC_SDOUT: length 128.1
  TOP w0.14: v1(117.32,56.48) 116.82,56.98 116.82,60.38 115.41,61.78 114.62,61.78 114.3,62.1 v2(113.75,62.65) 112.4,64 R1912.1 ; v1(44.82,30.36) 45.05,30.13 46.88,30.13 47.27,29.74 47.27,29.19 47.3,29.16 47.3,28.58 47.27,28.55 47.27,26.19 48.42,25.04 48.42,17.81 44.91,14.3 44.91,10.15 44.91,9.86 44.25,9.2 42.93,9.2 42.67,9.46 42.37,9.46 v1(42.29,9.39)
  BOTTOM w0.14: R2719.1 EC2708.1 41.54,9.48 41.77,9.25 42.16,9.25 v1(42.29,9.39) ; v1(117.32,56.48) 117.32,56.35 117.06,56.09 117.06,54.45 116.08,53.46 116.08,50.96 105.1,39.98 57.62,39.98 57.62,39.99 55,39.99 51.22,36.21 48.96,36.21 47.99,36.21 44.85,33.07 44.85,30.38 v1(44.82,30.36)
HDA_CODEC_SYNC: length 120.6
  TOP w0.14: v1(118.26,55.64) 118.2,55.7 118.2,56.66 117.44,57.41 117.44,60.6 v2(115.51,62.53) 114.19,63.85 R1908.1 ; HDA27.10 39.32,12.14 39.92,12.74 39.92,13.9 40.9,14.88 42.87,14.88 46.66,18.67 46.66,24.32 45.51,25.47 45.51,28.86 v1(45.5,28.87)
  BOTTOM w0.14: v1(118.26,55.64) 118.26,53.99 117.24,52.98 117.24,50.31 105.75,38.82 56.65,38.82 56.13,38.29 55.24,38.29 51.99,35.04 48.47,35.04 46.02,32.59 46.02,29.07 45.81,28.87 v1(45.5,28.87)
HDA_RST#: length 11.5
  BOTTOM w0.089: CPU1.AU8 114.34,72.75 114.34,72.25 114.31,72.21 114.31,69.95 114.31,69.8 116.13,67.98
  BOTTOM w0.14: R1911.2 117,65.95 v2(116.36,66.59) 116.13,66.82 116.13,67.98
HDA_SDIN0: length 125.8
  TOP w0.14: R2718.1 42.6,13.85 43.01,14.25 43.2,14.25 47.25,18.3 v2(47.25,23.94) 47.25,24.56 46.1,25.71 46.1,29.14 45.75,29.49 44.91,29.49 v1(44.87,29.45)
  BOTTOM w0.089: 114.3,68.23 113.66,68.87 113.66,70.47 113.3,70.83 113.3,71.06 CPU1.AY10
  BOTTOM w0.14: 114.3,68.23 114.3,66.81 115.05,66.06 115.05,60.79 117.47,58.37 117.47,57.16 117.9,56.72 117.9,56.11 117.68,55.88 117.68,54.24 116.66,53.22 116.66,50.72 105.34,39.4 55.74,39.4 55.73,39.41 55.24,39.41 51.46,35.63 48.71,35.63 48.23,35.63 45.43,32.83 45.43,29.64 45.32,29.53 44.94,29.53 v1(44.87,29.45)
HDA_SDOUT: length 9.8
  TOP w0.14: v1(112.15,72.74) 112.15,72.73 111.66,72.25 111.66,71.7 v2(111.07,71.11) 111.07,65.43 R1909.2 111.57,64.93 R1912.2
  BOTTOM w0.14: v1(112.15,72.74) 112.17,72.76 112.19,72.76 112.46,73.04 CPU1.AU11
HDA_SPKR: length 149.9
  TOP w0.254: v1(48.47,32.15) 47.32,32.15 46.74,31.57 44.85,31.57 44.19,30.91 44.19,28.63 v2(41.43,25.86) 40.88,25.86 40.05,25.04 RN2701.2
  L3 w0.254: v1(122.83,86.81) 122.83,86.57 123.67,85.73 123.67,83.3 124.19,82.78 124.55,82.78 125.34,82.78 126.13,81.98 126.13,81.69 126.18,81.64 126.18,79.04 124.92,77.77 121.2,77.77 120.62,77.2 120.62,75.79 119.88,75.05 119.62,75.05 119.18,74.61 119.18,73.22 119.04,73.08 119.04,72.66 119.16,72.53 119.16,64.09 119.42,63.83 119.42,57.32 120.5,56.25 120.5,51.54 117.31,48.35 117.31,43.12 v1(116.63,42.44)
  BOTTOM w0.089: 122.04,84.79 122.39,84.44 122.39,84.03 122.16,83.8 121.61,83.8 121.42,83.62 120.79,83.62 120.46,83.29 119.75,83.29 119.67,83.37 119.31,83.37 119.16,83.21 118.53,83.21 CPU1.V2
  BOTTOM w0.254: v1(48.47,32.15) 49.16,32.84 53.36,32.84 56.96,36.44 57.28,36.44 57.68,36.84 106.34,36.84 111.74,42.24 116.44,42.24 v1(116.63,42.44) ; 122.04,84.79 121.49,85.34 121.49,86.48 121.94,86.94 122.12,86.94 122.76,87.57 R2006.2 122.95,86.92 v1(122.83,86.81)
HDA_SPKR_R: length 3.5
  TOP w0.254: D2701.2 40.05,21.71 RN2701.3 39.04,23.16 v2(38.86,22.98)
HDA_SYNC: length 9.1
  TOP w0.14: R1908.2 112.92,64.46 v2(112.92,66.62) 112.92,67.17 112.14,67.96 112.14,71.19 112.14,71.2 v1(112.14,72.08)
  BOTTOM w0.14: CPU1.AV11 112.45,72.39 112.14,72.07 v1(112.14,72.08)
HDD_DEVSLP: length 2.6
  TOP w0.102: TP2001.1 119.61,86.66 119.84,86.43 v1(119.84,86.43)
  BOTTOM w0.089: v1(119.84,86.43) 119.67,86.43 119.58,86.34 119.18,86.34 119.05,86.21 118.59,86.21 118.39,86.01 118.39,85.89 CPU1.P2
HDMI_CLK: length 81.2
  L4 w0.114: v1(82.75,101.67) 82.67,101.74 82.01,101.74 81.68,102.07 79.22,102.07 78.43,101.28 72.8,101.28 69.46,97.94 68.01,97.94 60.72,90.65 59.68,90.65 52.99,83.96 47.04,83.96 46.27,83.18 34.71,83.18 32.67,81.15 31.62,81.15 29.32,78.84 23.65,78.84 v1(23.45,78.63)
  BOTTOM w0.127: 84.39,101.07 84.39,94.79 83.81,94.21 83.81,93.38 CPU1.B57 ; 84.39,101.07 84.39,101.47 83.98,101.87 82.93,101.87 82.75,101.69 v1(82.75,101.67) ; 84.39,101.07 v2(84.26,101.07) ; v1(23.45,78.63) 23.17,78.91 22.85,78.91 C5403.1
HDMI_CLK#: length 81.2
  L4 w0.114: v1(82.8,102.46) 82.8,102.31 82.6,102.11 82.57,102.11 82.44,101.97 82.11,101.97 81.78,102.3 79.13,102.3 78.33,101.51 72.7,101.51 69.37,98.17 67.92,98.17 60.62,90.88 59.58,90.88 52.89,84.19 46.95,84.19 46.18,83.41 34.61,83.41 32.58,81.37 31.53,81.37 29.22,79.07 23.67,79.07 23.46,79.28 v1(23.45,79.28)
  BOTTOM w0.127: v1(82.8,102.46) 82.8,102.23 82.92,102.11 83.58,102.11 ; v1(23.45,79.28) 23.32,79.15 22.78,79.15 C5402.1 ; 83.58,102.11 84.08,102.11 84.63,101.57 84.63,94.69 84.05,94.12 84.05,93.79 CPU1.A57 ; 83.58,102.11 v2(83.58,102.24)
HDMI_CLK#_R: length 6.6
  TOP w0.127: RN5403.5 20.48,78.88 v1(20.06,79.3)
  BOTTOM w0.127: 18.69,80.05 18.83,79.91 18.83,79.51 19.29,79.06 19.83,79.06 v1(20.06,79.3) 20.22,79.14 21.3,79.14 C5402.2 ; 18.69,80.05 v2(18.78,80.14) ; 18.69,80.05 18.52,80.22 17.86,80.22 R5401.1
HDMI_CLK#_R_C: length 11.5
  BOTTOM w0.127: HDMI1.12 11.66,86.84 13.12,86.84 14.45,85.51 14.45,82.63 ; 14.45,82.63 14.45,80.34 14.61,80.18 14.98,80.18 R5414.1 15.51,80.71 R5401.2 ; 14.45,82.63 v2(14.58,82.63)
HDMI_CLK_R: length 6.6
  TOP w0.127: RN5403.6 20.44,78.23 v1(20.06,78.61)
  BOTTOM w0.127: C5403.2 21.26,78.9 20.35,78.9 v1(20.06,78.61) 19.85,78.82 19.19,78.82 19.02,78.99 ; R5402.1 17.91,79.98 18.42,79.98 18.59,79.81 18.59,79.41 19.02,78.99 ; 19.02,78.99 v2(18.93,78.9)
HDMI_CLK_R_C: length 11.5
  BOTTOM w0.127: HDMI1.10 11.7,86.6 13.02,86.6 14.21,85.41 14.21,80.67 ; v2(14.08,80.67) 14.21,80.67 ; 14.21,80.67 14.21,80.24 14.51,79.94 14.98,79.94 R5414.2 15.48,79.44 R5402.2
HDMI_DATA0: length 84.1
  L4 w0.114: v1(23.44,76.9) 23.77,77.23 28.91,77.23 31.69,80.01 33.9,80.01 35.84,81.95 46.29,81.95 47.52,83.18 53.5,83.18 60.14,89.83 60.95,89.83 68.32,97.19 71.05,97.19 73.62,99.76 77.11,99.76 77.44,100.09 79.07,100.09 80.3,101.32 81.38,101.32 81.71,100.98 83.13,100.98 83.48,101.34 84.92,101.34 85.2,101.06 v1(85.22,101.06)
  BOTTOM w0.127: CPU1.A55 85.5,93.46 85.58,93.39 85.93,93.39 86.08,93.54 86.08,94.29 86.59,94.8 86.59,99.16 ; 86.59,99.16 v2(86.46,99.16) ; 86.59,99.16 86.59,100.79 85.95,101.43 85.35,101.43 85.22,101.29 v1(85.22,101.06) ; C5405.1 22.83,77.2 23.14,77.2 v1(23.44,76.9)
HDMI_DATA0#: length 84.1
  L4 w0.114: v1(85.16,101.85) 84.89,101.57 83.39,101.57 83.03,101.21 81.81,101.21 81.47,101.55 81.29,101.55 80.2,101.55 78.98,100.32 77.35,100.32 77.01,99.98 73.52,99.98 70.96,97.42 68.23,97.42 60.86,90.05 60.05,90.05 53.41,83.41 47.43,83.41 46.19,82.18 35.74,82.18 33.8,80.24 31.59,80.24 28.81,77.46 23.52,77.46 v1(23.44,77.54)
  BOTTOM w0.127: CPU1.B55 85.58,93.15 86.03,93.15 86.32,93.44 86.32,94.19 86.83,94.7 86.83,94.9 86.83,94.9 86.83,100.52 ; 86.83,100.52 86.83,100.89 86.05,101.67 85.34,101.67 v1(85.16,101.85) ; 86.83,100.52 v2(86.95,100.52) ; v1(23.44,77.54) 23.35,77.44 22.63,77.44 C5404.1
HDMI_DATA0#_R: length 6.2
  TOP w0.127: RN5403.7 20.45,77.73 20.09,77.37 v1(19.74,77.37)
  BOTTOM w0.127: R5403.1 17.91,77.64 18.84,77.64 19.28,77.2 19.58,77.2 v1(19.74,77.37) 19.82,77.29 20.45,77.29 ; 20.45,77.29 v2(20.45,77.42) ; 20.45,77.29 21.14,77.29 C5404.2
HDMI_DATA0#_R_C: length 12.9
  TOP w0.089: 11.01,81.59 10.99,81.61 10.96,81.61 10.63,81.93 10.63,82.41 10.67,82.45 10.67,82.94 10.63,82.98 10.63,83.43 10.68,83.47 10.68,83.95 10.63,84 10.63,85.12 10.43,85.32 9.9,85.32 9.8,85.42 HDMI1.9
  TOP w0.127: v1(14.55,78.05) 14.3,77.79 13.78,77.79 13.03,78.54 13.03,79.57 11.01,81.59
  BOTTOM w0.127: R5403.2 15.49,78.15 R5416.1 14.64,77.96 v1(14.55,78.05)
HDMI_DATA0_R: length 6.4
  TOP w0.127: RN5403.8 20.14,77.08 v1(19.74,76.68)
  BOTTOM w0.127: 19.06,77.08 18.74,77.4 17.91,77.4 R5404.1 ; 19.06,77.08 v2(18.97,76.99) ; 19.06,77.08 19.18,76.96 19.46,76.96 v1(19.74,76.68) 20.11,77.05 21.24,77.05 C5405.2
HDMI_DATA0_R_C: length 13
  TOP w0.089: 10.84,81.42 10.82,81.44 10.82,81.47 10.44,81.85 10.44,82.49 10.48,82.53 10.48,82.86 10.44,82.9 10.44,83.51 10.49,83.55 10.49,83.87 10.44,83.92 10.44,85.04 10.35,85.13 10.23,85.13 HDMI1.7
  TOP w0.127: 13.92,77.55 14.29,77.55 v1(14.55,77.28) ; 13.92,77.55 13.68,77.55 12.79,78.44 12.79,79.47 10.84,81.42 ; 13.92,77.55 v2(13.92,77.39)
  BOTTOM w0.127: R5404.2 15.49,76.88 R5416.2 15.09,77.28 v1(14.55,77.28)
HDMI_DATA1: length 80.3
  L4 w0.114: v1(82.67,99.26) 82.54,99.38 82.04,99.38 81.29,100.14 80.98,100.14 79.3,98.46 77.48,98.46 77.06,98.89 73.85,98.89 71.41,96.44 68.69,96.44 61.18,88.94 60.31,88.94 53.78,82.4 47.86,82.4 46.66,81.2 36.15,81.2 30.14,75.19 22.97,75.19 22.81,75.02 v1(22.78,75.02)
  BOTTOM w0.127: v1(22.78,75.02) 22.64,75.16 22.32,75.16 C5406.1 ; 83.56,98.79 83.56,99.12 83.29,99.39 82.81,99.39 v1(82.67,99.26) ; 83.56,98.79 83.56,95.39 83.34,95.17 83.34,93.06 83.25,92.81 83.24,92.76 83.24,92.69 83.28,92.56 CPU1.C58 ; 83.56,98.79 v2(83.44,98.79)
HDMI_DATA1#: length 80.4
  L4 w0.114: v1(82.67,99.91) 82.38,99.61 82.14,99.61 81.38,100.37 81.19,100.37 81.19,100.37 80.88,100.37 79.2,98.69 77.58,98.69 77.15,99.12 73.76,99.12 71.31,96.67 68.6,96.67 61.09,89.16 60.22,89.16 53.68,82.63 47.77,82.63 46.57,81.43 36.05,81.43 30.04,75.42 23.05,75.42 v1(22.81,75.66)
  BOTTOM w0.127: 83.81,96.12 83.81,99.22 83.39,99.64 82.94,99.64 v1(82.67,99.91) ; 83.81,96.12 83.81,95.29 83.58,95.07 83.58,92.76 CPU1.B58 ; 83.81,96.12 v2(83.96,96.12) ; v1(22.81,75.66) 22.79,75.66 22.53,75.4 22.22,75.4 22.06,75.57 C5409.1
HDMI_DATA1#_R: length 6.3
  TOP w0.127: 19.82,75.3 19.16,75.3 v1(19.04,75.43) ; 19.82,75.3 v2(19.82,75.43) ; 19.82,75.3 20.06,75.3 20.06,75.3 RN5402.5
  BOTTOM w0.127: R5407.1 17.86,75.11 18.72,75.11 v1(19.04,75.43) 19.11,75.35 20.74,75.35 C5409.2
HDMI_DATA1#_R_C: length 13.6
  BOTTOM w0.127: HDMI1.6 11.68,83.82 12.7,83.82 13.18,83.34 13.18,80.47 13.91,79.73 13.91,76.1 ; 13.91,76.1 13.91,75.33 14.18,75.06 14.98,75.06 R5417.1 15.49,75.58 R5407.2 ; 13.91,76.1 v2(14.04,76.1)
HDMI_DATA1_R: length 6.5
  TOP w0.127: v1(19.04,74.74) 19.36,75.06 19.96,75.06 20.37,74.65 RN5402.6
  BOTTOM w0.127: 20.09,75.11 19.41,75.11 v1(19.04,74.74) 18.91,74.87 17.96,74.87 R5408.1 ; 20.09,75.11 20.95,75.11 C5406.2 ; 20.09,75.11 v2(20.09,74.99)
HDMI_DATA1_R_C: length 13.6
  BOTTOM w0.127: 14.36,74.82 14.97,74.82 R5417.2 15.49,74.31 R5408.2 ; 14.36,74.82 14.08,74.82 13.67,75.23 13.67,79.63 12.94,80.37 12.94,83.24 12.6,83.58 11.68,83.58 HDMI1.4 ; 14.36,74.82 v2(14.36,74.7)
HDMI_DATA2: length 84.4
  L4 w0.114: v1(85.2,99.06) 85.2,99.17 84.81,99.56 84.42,99.56 84.4,99.54 83.07,98.21 80.11,98.21 79.61,97.71 77.14,97.71 76.71,98.14 74.16,98.14 71.36,95.33 69.68,95.33 65.4,91.05 64.47,91.05 61.54,88.12 60.62,88.12 54.16,81.65 48.17,81.65 46.92,80.4 37.54,80.4 34.76,77.63 33.66,77.63 30.29,74.26 24.88,74.26 24.17,73.55 23.57,73.55 23.26,73.25 v1(23.26,72.99)
  BOTTOM w0.089: 85.28,94.78 85.27,94.76 85.27,94.73 84.91,94.37 84.91,93.9 85.1,93.43 85.1,93.33 85.03,93.16 85.03,92.98 85.12,92.76 85.4,92.51 CPU1.C55
  BOTTOM w0.127: v1(85.2,99.06) 85.2,99.22 85.34,99.36 85.72,99.36 85.81,99.27 85.81,97.77 ; 85.28,94.78 85.81,95.31 85.81,97.77 ; 85.81,97.77 v2(85.68,97.77) ; v1(23.26,72.99) 23.26,73.25 23.12,73.39 21.93,73.39 C5408.1
HDMI_DATA2#: length 84.4
  L4 w0.114: v1(85.21,99.79) 84.33,99.79 82.98,98.44 80.02,98.44 79.51,97.94 77.23,97.94 76.81,98.37 74.07,98.37 71.26,95.56 69.58,95.56 65.3,91.28 64.38,91.28 61.44,88.35 60.53,88.35 54.06,81.88 48.08,81.88 46.83,80.63 37.44,80.63 34.67,77.85 33.56,77.85 30.2,74.49 24.79,74.49 24.08,73.78 23.5,73.78 v1(23.34,73.94)
  BOTTOM w0.089: 85.45,94.61 85.44,94.59 85.4,94.59 85.1,94.29 85.1,93.93 85.29,93.47 85.29,93.33 85.28,93.29 85.2,93.12 85.2,93.02 85.27,92.86 85.36,92.78 85.71,92.67 CPU1.C54
  BOTTOM w0.127: v1(85.21,99.79) 85.41,99.6 85.82,99.6 86.05,99.37 86.05,96.59 ; v2(86.18,96.59) 86.05,96.59 ; 86.05,96.59 86.05,95.21 85.45,94.61 ; C5407.1 21.7,73.63 23.03,73.63 v1(23.34,73.94)
HDMI_DATA2#_R: length 6
  TOP w0.127: v1(19.09,73.32) 19.09,73.32 19.47,73.32 20.3,74.15 RN5402.7
  BOTTOM w0.127: v2(19.72,73.42) 19.72,73.3 ; 19.72,73.3 19.11,73.3 v1(19.09,73.32) 18.61,72.85 18.5,72.85 18.39,72.74 17.67,72.74 R5405.1 ; 19.72,73.3 20.12,73.3 C5407.2
HDMI_DATA2#_R_C: length 13.9
  BOTTOM w0.127: v2(13.18,75.18) 13.05,75.18 ; 13.05,75.18 13.05,74.46 14.66,72.85 15.22,72.85 R5415.1 15.39,73.02 R5405.2 ; 13.05,75.18 13.05,79.37 10.55,81.87 10.55,81.95 HDMI1.3
HDMI_DATA2_R: length 6.2
  TOP w0.127: 19.56,73.07 19.09,72.6 v1(19.09,72.52) ; 19.56,73.07 19.99,73.5 RN5402.8 ; 19.56,73.07 v2(19.65,72.98)
  BOTTOM w0.127: R5406.1 18.14,72.5 18.49,72.5 18.6,72.61 18.99,72.61 v1(19.09,72.52) 19.63,73.06 20.56,73.06 C5408.2
HDMI_DATA2_R_C: length 13.8
  BOTTOM w0.127: 13.14,74.02 12.81,74.36 12.81,79.27 10.38,81.7 HDMI1.1 ; 13.14,74.02 v2(13.05,73.93) ; 13.14,74.02 14.56,72.61 14.83,72.61 R5415.2 15.69,71.75 R5406.2
HDMI_HPD_B: length 2.6
  BOTTOM w0.102: R5411.2 18.04,94.28 v2(18.86,94.28) 19.96,94.28 Q5401.B
HDMI_HPD_E: length 3.8
  BOTTOM w0.102: Q5401.E 22.27,94.46 v2(23.49,93.24) 23.66,93.07 R5412.1 R5419.2
HDMI_PCH_DET: length 126.7
  L4 w0.102: v1(49.93,87.09) 49.93,88 53.83,91.91 60.51,91.91 67.56,98.95 69.13,98.95 72.41,102.23 77.59,102.23 78.05,102.68 78.05,103.32 78.46,103.73 88.44,103.73 92.7,99.47 94.14,99.47 94.84,98.77 99.65,98.77 100.38,99.5 102.29,99.5 102.56,99.78 107.85,99.78 107.87,99.76 108.87,99.76 108.87,99.76 110.94,99.76 111.12,99.94 114.65,99.94 115.47,99.12 116.76,99.12 117.26,99.62 120.81,99.62 122.04,100.85 122.04,101.22 121.53,101.73 v1(121.53,101.88)
  BOTTOM w0.089: 114.93,94 114.82,93.89 114.82,93.51 115.11,93.22 115.11,92.98 114.65,92.52 CPU1.C8
  BOTTOM w0.102: R5419.1 24.55,91.28 25.61,90.22 34.38,90.22 36.72,87.89 48.35,87.89 49.15,87.09 v1(49.93,87.09) ; 114.93,94 115.52,94.59 115.58,94.59 115.75,94.76 116.41,94.76 116.71,95.06 118.55,95.06 118.97,95.47 v2(118.97,96.66) 118.97,96.8 120.22,98.05 120.22,98.34 122.02,100.14 v2(122.02,100.54) 122.04,100.56 122.04,101.22 121.53,101.73 v1(121.53,101.88)
HDMI_PLL_GND:
  vias: v2(22.65,79.65) v3(21,72.1) v3(21.85,72.16)
HPD_HDMI_CON: length 9.8
  BOTTOM w0.102: HDMI1.19 10.2,90.7 10.75,91.25 12.39,91.25 v2(15.46,94.32) 16.12,94.98 R5410.1 R5411.1
HSIO_OUT:
  vias: v2(123,105.16)
HSIOPC: length 28.9
  L3 w0.102: v1(121.97,86.15) 121.97,86.96 122.58,87.57 125.04,87.57 125.3,87.32 126.97,87.32 127.61,87.95 127.61,89.75 127,90.37 125.07,90.37 124.18,91.25 123.39,91.25 v1(122.37,92.27)
  BOTTOM w0.089: 119.34,83.03 118.53,83.03 CPU1.Y2
  BOTTOM w0.102: v1(121.97,86.15) 121.97,85.47 v2(122.63,84.81) 122.9,84.54 122.9,84.05 122.31,83.46 121.52,83.46 121.5,83.43 120.86,83.43 120.53,83.1 119.41,83.1 119.34,83.03 ; R2123.1 R2007.1 124.93,95.58 124.02,94.68 124.02,93.9 123.21,93.09 123.21,92.98 122.5,92.27 v1(122.37,92.27)
HSIOPC_R: length 8.5
  TOP w0.102: v2(123.52,101.67) 123.44,101.67 v1(123.06,101.29)
  L4 w0.102: v1(123.06,101.29) 123.8,102.02 v1(125.25,102.02)
  BOTTOM w0.102: v1(123.06,101.29) 123.06,99.46 122.84,99.23 122.84,98.67 124.04,97.46 R2123.2 ; U2101.9 125.01,102.45 125.25,102.22 v1(125.25,102.02)
HVM_CLK: length 6.6
  TOP w0.102: v1(108.96,85.57) 108.52,86.01 108.17,86.01 108.17,86.01 107.77,86.01 107.71,86.08 107.54,86.08 107.1,86.52 106.19,86.52 105.87,86.2 104.53,86.2 104.42,86.31 TP620.1
  BOTTOM w0.102: v1(108.96,85.57) 108.58,85.2 108.52,85.2 108.49,85.16 108.17,85.16 108.08,85.07 CPU1.R20
HVM_CLK#: length 3.4
  TOP w0.102: TP619.1 106.22,85.89 106.65,86.32 107.01,86.32 107.52,85.81 108.08,85.81 v1(108.32,85.57)
  BOTTOM w0.102: v1(108.32,85.57) 108.01,85.88 CPU1.P20
I2C0_SCL: length 6.6
  BOTTOM w0.089: CPU1.F3 117.97,90.58 118.37,90.58 118.6,90.81 119.21,90.81 120.43,92.04 120.43,92.27 120.45,92.28
  BOTTOM w0.14: RN2007.2 122.32,93.46 122.1,93.25 121.41,93.25 120.45,92.28
I2C0_SDA: length 6.5
  BOTTOM w0.089: 120.82,91.92 120.8,91.9 120.57,91.9 119.29,90.62 118.68,90.62 118.29,90.24 CPU1.F2
  BOTTOM w0.14: 120.82,91.92 121.63,92.73 v2(121.87,92.73) 122.32,92.73 122.97,93.37 RN2007.1
I2C1_SCL: length 22
  BOTTOM w0.14: CPU1.F1 119.27,90.28 119.67,90.68 119.86,90.68 120.53,91.35 121.96,91.35 v2(121.99,91.38) 122.27,91.38 123.59,92.7 123.59,92.94 124.39,93.74 124.39,94.5 125.41,95.52 126,96.11 RN2008.2 126,96.98 126.11,97.1 126.97,97.1 127.32,97.44 EC6203.1 128.18,97 RN6203.2 128.91,97.22 128.51,97.61 128.51,98.82 129.36,99.66 130.22,99.66 130.83,100.27 132.13,100.27 132.62,99.78 Q6204.1
I2C1_SCL_R: length 17.3
  TOP w0.14: TPAD1.6 133.9,95.03 134,95.13 134,95.71 133.13,96.58 AFTP6237.1 132.9,97.01 132.29,97.01 v1(131.77,97.53) 131.42,97.88 130.5,97.88 130.17,98.21 130.17,98.8 v1(130.27,98.9)
  BOTTOM w0.14: RN6204.4 135.64,99.71 135.84,99.51 135.84,98.75 135.25,98.16 134.72,98.16 134.51,97.96 133.97,97.96 R6204.2 132.38,96.92 v1(131.77,97.53) ; Q6204.6 130.95,99.78 130.27,99.1 v1(130.27,98.9) 129.18,98.9 128.91,98.63 RN6203.3
I2C1_SDA: length 19.9
  BOTTOM w0.127: 119.64,89.91 119.56,89.83 117.25,89.83 CPU1.G4
  BOTTOM w0.14: 123.42,91.79 122.46,90.83 121.83,90.83 121.83,90.83 120.74,90.83 120.07,90.16 119.88,90.16 119.64,89.91 ; 123.42,91.79 124.11,92.48 124.11,92.72 124.91,93.53 124.91,94.29 125.93,95.3 126.35,95.72 126.52,95.72 126.65,95.86 RN2008.1 126.75,96.6 EC6204.1 127.84,96.6 127.95,96.48 128.41,96.48 128.56,96.33 129.33,96.33 129.56,96.56 RN6203.1 129.95,97 131.43,98.48 Q6204.4 ; 123.42,91.79 v2(123.44,91.77)
I2C1_SDA_R: length 15.7
  TOP w0.14: TPAD1.7 134.9,95.11 134.69,95.32 134.69,96.21 135.05,96.56 AFTP6240.1 134.85,96.97 133.67,96.97 133.11,97.53 v1(132.51,97.53) 131.62,98.42 v1(130.71,98.42)
  BOTTOM w0.14: RN6204.3 134.88,99.06 134.3,98.48 Q6204.3 133.5,98.23 132.8,97.53 v1(132.51,97.53) 131.98,98.06 131.57,98.06 131.2,97.69 R6210.2 ; v1(130.71,98.42) 130.49,98.2 RN6203.4
I2CA_SCL: length 8
  TOP w0.14: 182.16,109.84 181.76,109.44 v1(180.9,109.44) ; 182.16,109.84 v2(182.07,109.93) ; 182.16,109.84 182.81,110.48 184.33,110.48 184.41,110.56 RN7603.3
  BOTTOM w0.14: v1(180.9,109.44) 180.85,109.44 180.25,110.04 178.7,110.04 178.67,110 178.16,110 GPU1.B7
I2CA_SDA: length 7.2
  TOP w0.14: 183.31,109.96 183.02,109.96 181.98,108.92 181.06,108.92 v1(180.92,108.78) ; 183.31,109.96 v2(183.31,109.84) ; 183.31,109.96 184.73,109.96 RN7603.4
  BOTTOM w0.14: v1(180.92,108.78) 180.77,108.78 180.03,109.52 178.63,109.52 GPU1.A7
I2CB_SCL: length 10.4
  TOP w0.14: RN7605.3 182.69,116.61 182.56,116.48 181.79,116.48 v2(180.43,115.12) 180.07,114.76 180.07,114.23 179.57,113.73 179.57,112.97 178.68,112.09 177.98,112.09 177.55,111.65 v1(176.55,111.65)
  BOTTOM w0.14: GPU1.C9 176.57,111.65 v1(176.55,111.65)
I2CB_SDA: length 9.6
  TOP w0.14: RN7605.4 182,115.96 v2(181.71,115.66) 180.59,114.54 180.59,114.01 180.09,113.51 180.09,112.75 178.9,111.57 178.2,111.57 177.5,110.86 v1(177.36,110.86)
  BOTTOM w0.14: GPU1.C8 176.95,110.45 v1(177.36,110.86)
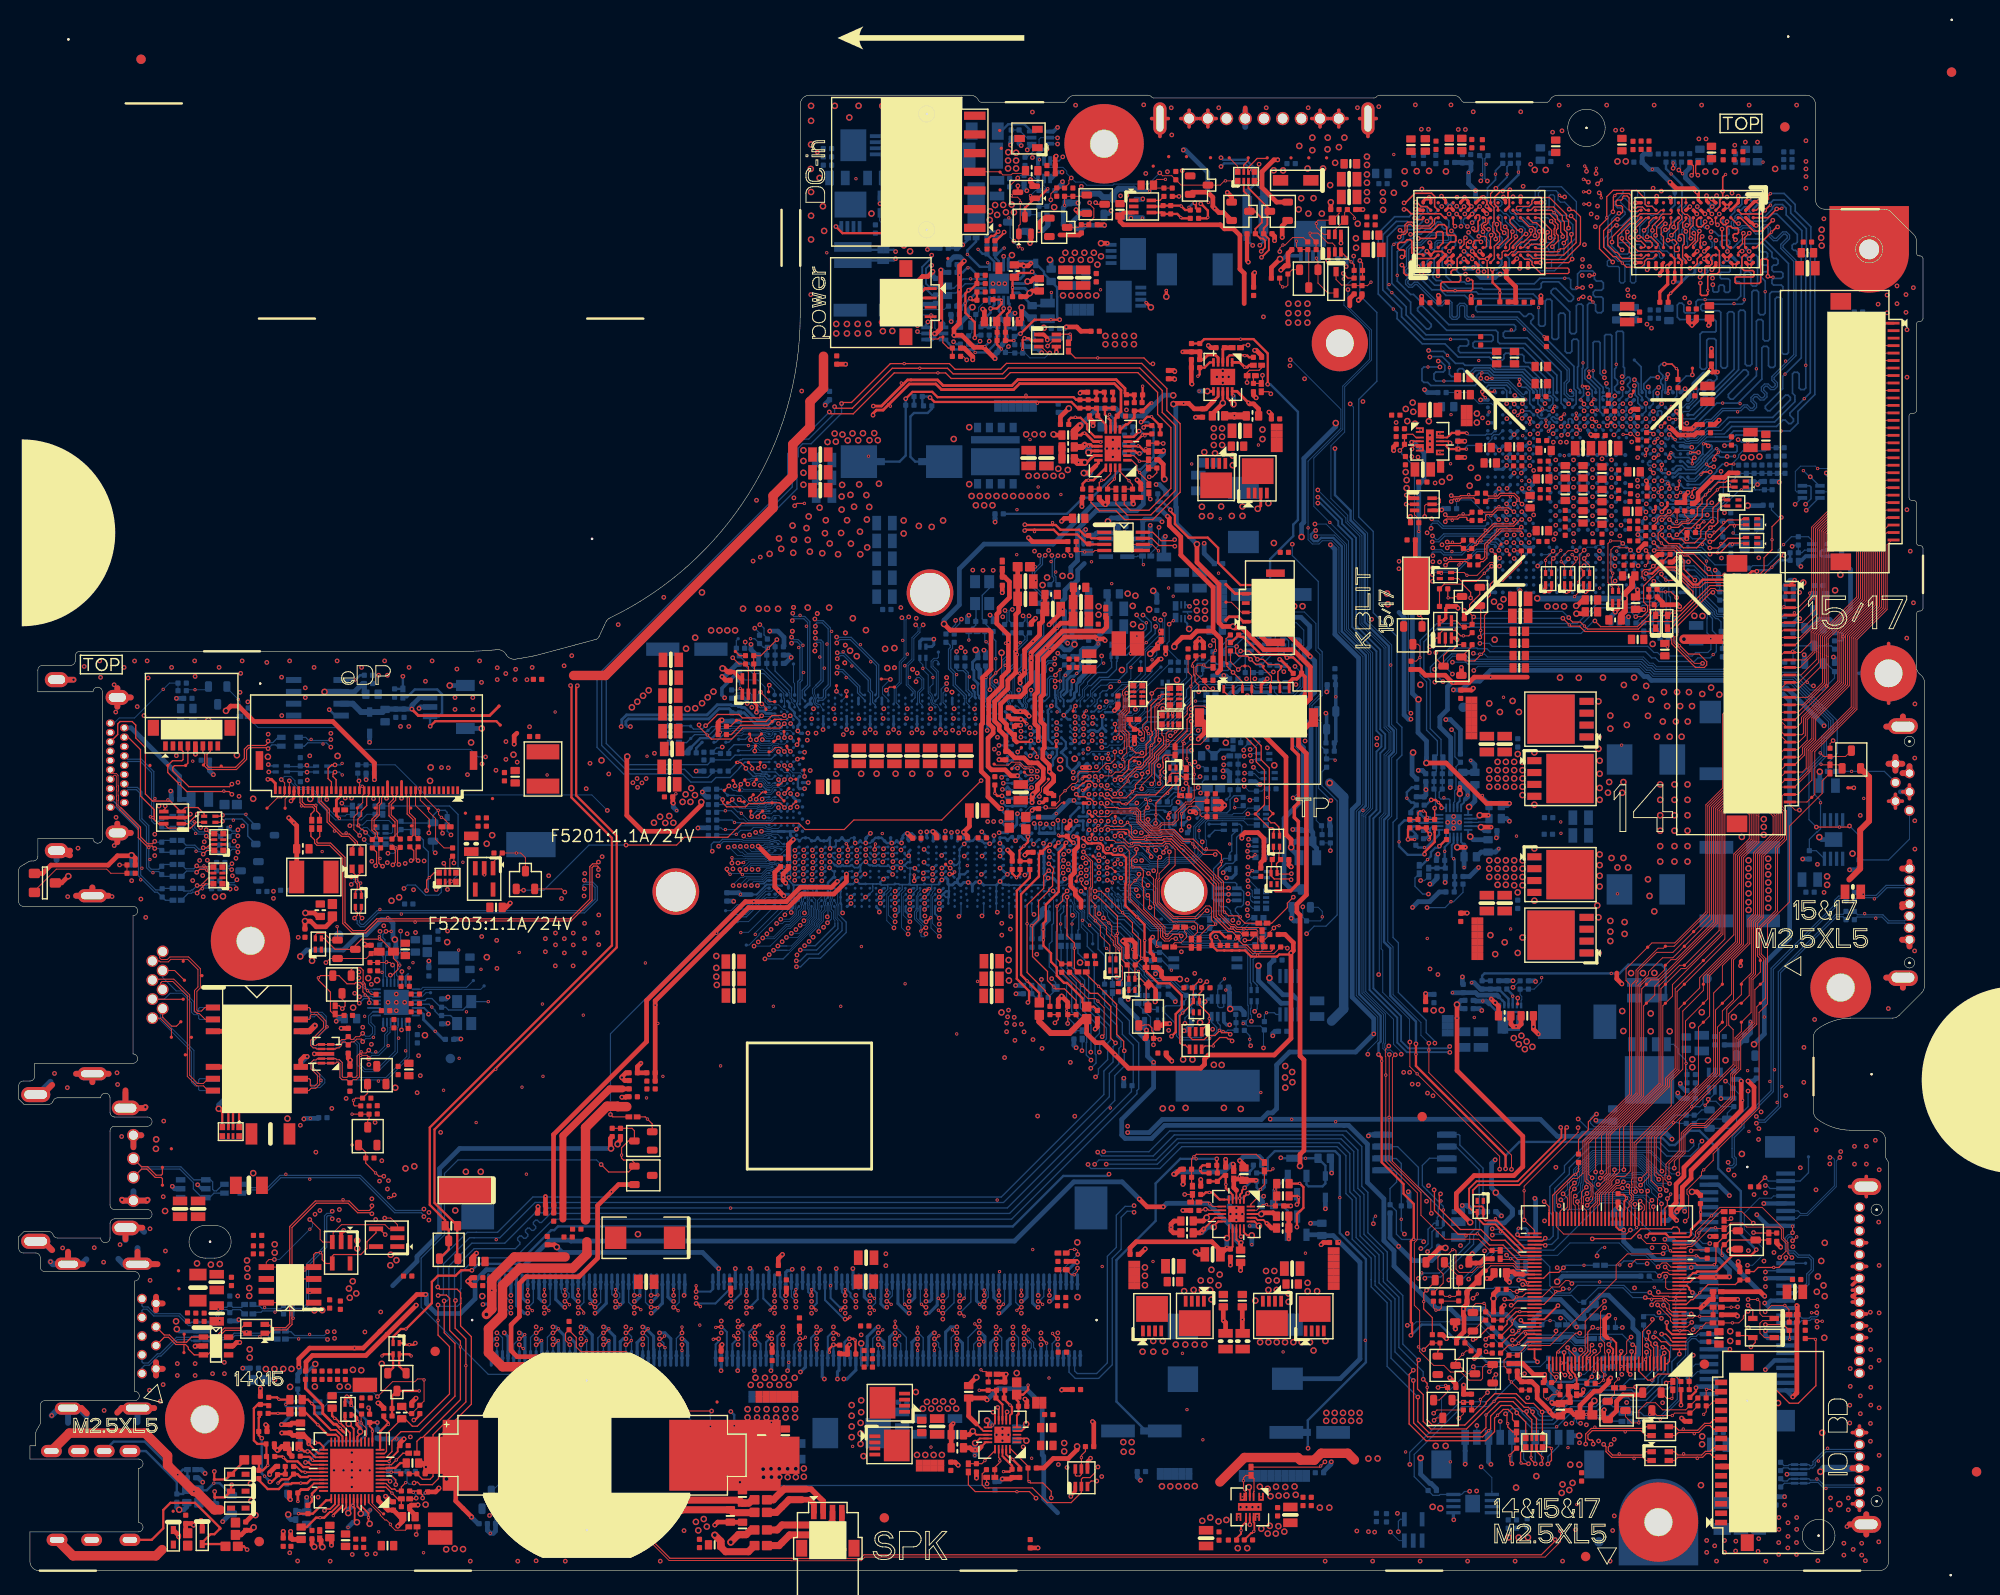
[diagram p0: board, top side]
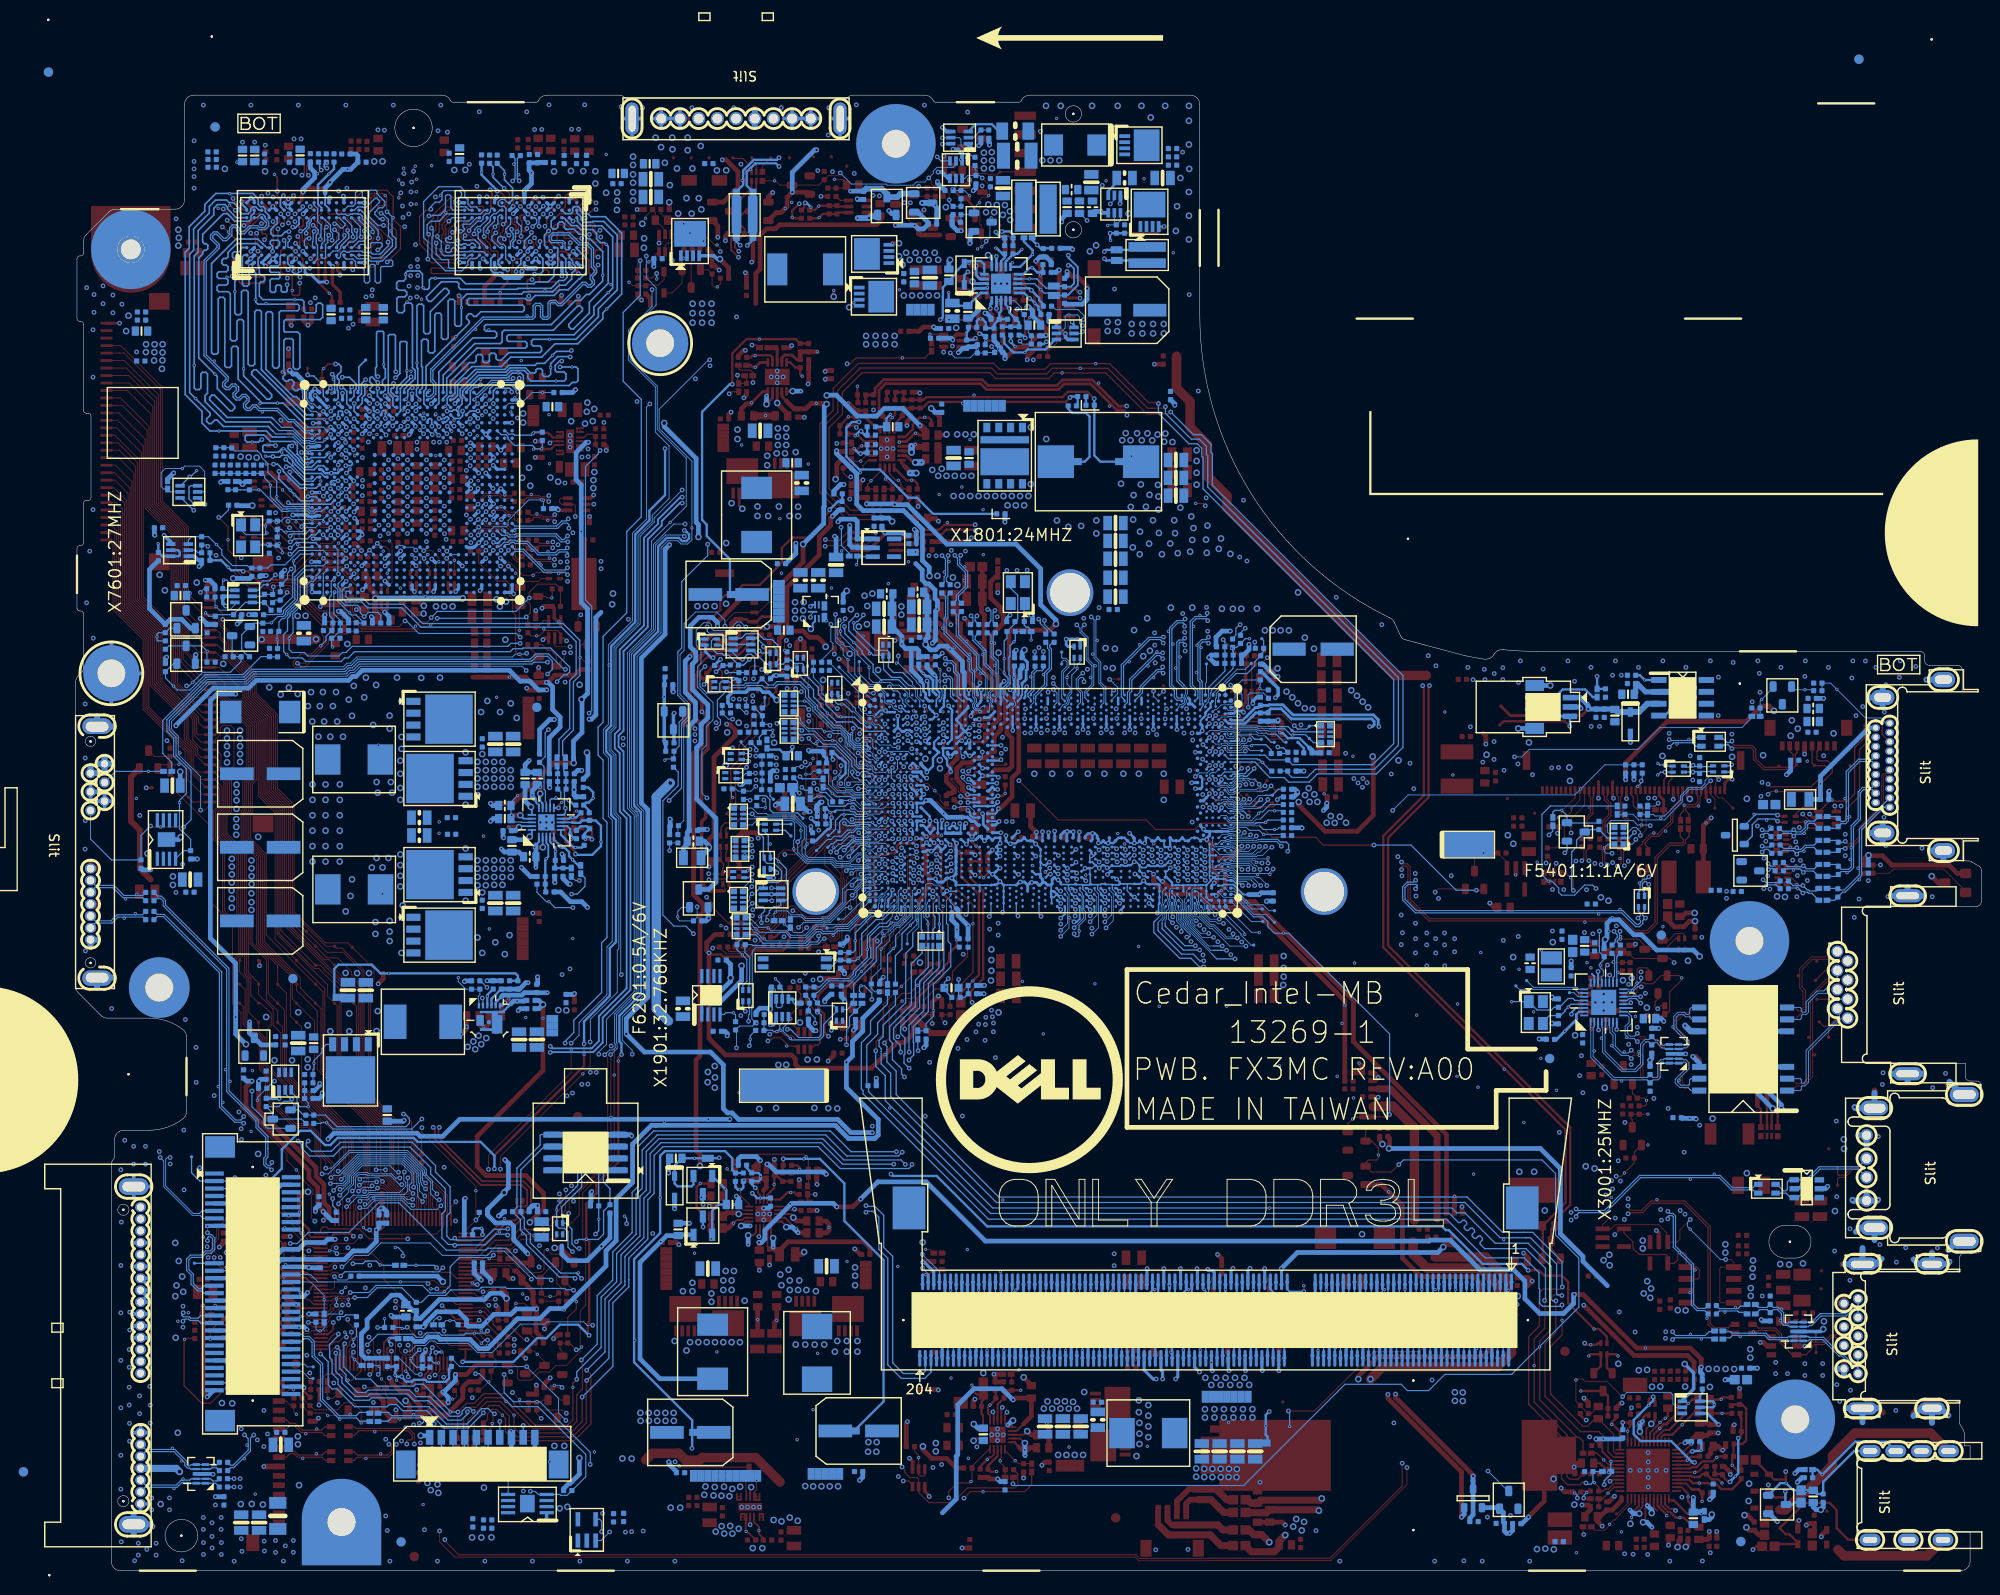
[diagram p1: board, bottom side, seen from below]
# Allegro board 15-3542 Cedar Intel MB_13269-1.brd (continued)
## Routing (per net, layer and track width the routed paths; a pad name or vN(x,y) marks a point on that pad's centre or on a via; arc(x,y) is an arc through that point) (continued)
I2CC_SCL: length 7.4
  TOP w0.14: RN7604.3 184.4,112.57 184.27,112.45 182.81,112.45 182.46,112.09 ; v1(180.9,110.74) 181.1,110.74 182.46,112.09 ; 182.46,112.09 v2(182.37,112.18)
  BOTTOM w0.14: v1(180.9,110.74) 180.69,110.95 179.26,110.95 178.83,111.38 178.66,111.38 GPU1.A9
I2CC_SDA: length 8.4
  TOP w0.14: v2(183.53,111.8) 183.53,111.92 ; 183.53,111.92 RN7604.4 ; 183.53,111.92 183.02,111.92 181.32,110.22 181.01,110.22 v1(180.9,110.1)
  BOTTOM w0.14: GPU1.B9 178.16,110.86 178.61,110.86 178.72,110.75 178.72,110.75 179.05,110.43 180.47,110.43 180.68,110.21 180.78,110.21 v1(180.9,110.1)
IFPAB_IOVDD: length 4.3
  TOP w0.102: RN7402.3 163.97,108.14 v1(164.16,108.32) 164.16,108.36 164.95,109.15 v2(164.95,109.2)
  BOTTOM w0.102: v1(164.16,108.32) 163.75,108.73 GPU1.W6 GPU1.Y6
IFPAB_PLLVDD: length 3.9
  TOP w0.102: RN7402.4 163.32,108.12 v2(163.32,108.12) 163.32,108.29 v1(164.13,109.11)
  BOTTOM w0.102: GPU1.W7 163.73,109.51 v1(164.13,109.11) 164.53,109.5 GPU1.V7
IFPC_IOVDD: length 3
  TOP w0.102: RN7401.3 166.01,107.38 166.57,107.95 v1(166.57,108.32) v2(166.16,108.73)
  BOTTOM w0.102: GPU1.R6 166.98,108.73 v1(166.57,108.32)
IFPC_PLLVDD: length 4.8
  TOP w0.102: RN7401.4 165.36,107.61 v2(165,107.97) 165,108.41 165.74,109.15 v1(166.6,109.15)
  BOTTOM w0.102: GPU1.T7 166.59,109.15 v1(166.6,109.15) 166.98,109.53 GPU1.R7
IFPD_IOVDD: length 3
  TOP w0.102: v2(167.88,108.7) 167.84,108.7 v1(167.46,108.32) 167.46,108.15 168.04,107.57 RN7404.3
  BOTTOM w0.102: GPU1.P6 167.46,108.34 v1(167.46,108.32)
IFPD_PLLVDD: length 8.1
  TOP w0.102: v2(166.42,104.24) 166.78,104.61 166.78,105.87 167.39,106.47 RN7404.4 167.39,107 166.98,107.41 166.98,108.73 v1(167.46,109.21)
  BOTTOM w0.102: v1(167.46,109.21) 167.78,109.53 GPU1.N7 168.88,109.72 169.3,109.72 GPU1.M7
IFPEF_IOVDD: length 8.8
  TOP w0.102: v1(172.41,109.21) 172.16,109.47 171.27,109.47 171.14,109.59 170.66,109.59 170.32,109.25 170.32,106.94 v2(170.51,106.75) 170.51,106.39 170.35,106.24 170.35,105.74 170.59,105.5 170.94,105.5 171.14,105.31 RN7403.3
  BOTTOM w0.102: GPU1.J6 171.97,108.77 v1(172.41,109.21) 172.81,108.82 GPU1.H6
IFPEF_PLLVDD: length 8.2
  TOP w0.102: RN7403.4 170.49,105.24 170,105.73 170,109.92 v2(170.28,110.2) 171.32,110.2 v1(171.58,109.94)
  BOTTOM w0.102: GPU1.J7 171.97,109.55 v1(171.58,109.94) 171.56,109.94 171.17,109.55 GPU1.K7
IMVP_PWRGD: length 190.5
  TOP w0.127: KBC24.107 167.69,22.88 168.12,23.31 168.12,23.97 v1(168.29,24.14) ; PR4628.2 R4622.2 121.74,117.5 121.3,117.05 v1(120.93,117.05)
  L3 w0.127: v1(79.33,108.47) 79.33,108.3 79,107.97 79,106.17 78.55,105.71 78.55,102.11 79.27,101.38 v1(79.27,101.24) ; v1(168.83,33.68) 165.95,33.68 163.57,36.06 162.63,36.06 161.81,36.89 161.03,36.89 158.61,39.3 158.07,39.3 154.22,43.14 154.22,44.47 150.19,48.51 150.19,52.24 149.23,53.2 149.23,53.52 148.97,53.78 148.59,53.78 v1(148.15,53.33)
  L4 w0.127: v1(148.15,53.33) 149.16,54.34 149.16,55.52 148.3,56.38 148.3,57.26 145.23,60.32 145.23,60.87 144.34,61.77 144.34,86.43 145.85,87.94 145.85,93.98 144.66,95.17 144.66,99.39 144.33,99.72 144.33,100.57 142.68,102.22 142.68,104.45 138.72,108.41 125.23,108.41 124.56,109.09 124.56,110.07 123.85,110.77 123.84,110.77 123.83,110.78 123.2,110.78 122.85,111.14 121.71,111.14 121.53,111.32 121.53,115.07 120.93,115.66 v1(120.93,117.05) 120.6,116.72 120.6,114.81 119.21,113.42 111.67,113.42 111.02,112.76 106.56,112.76 105.15,111.36 99.81,111.36 98.99,110.55 95.14,110.55 92.78,108.18 79.62,108.18 v1(79.33,108.47) ; v1(168.29,24.14) 168.29,25.16 168.82,25.69 168.82,33.25 168.83,33.26 v1(168.83,33.68)
  BOTTOM w0.127: v1(79.27,101.24) 79.34,101.24 79.73,100.86 79.73,100.14 80.08,99.79 R713.1 ; v2(169.65,34.59) 169.35,34.59 168.83,34.07 v1(168.83,33.68)
IMVP_PWRGD_R: length 9.8
  BOTTOM w0.089: CPU1.C59 82.99,92.64 82.7,92.94 82.7,93.17 82.49,93.38 82.49,93.9 82.45,93.94
  BOTTOM w0.102: 82.38,94.21 82.38,94.01 82.45,93.94
  BOTTOM w0.127: 82.38,94.21 80.02,96.56 R712.1 EC702.1 80.02,98.37 80.08,98.43 R713.2 79.65,98.81 R710.2 78.73,99.74 v2(78.28,99.74)
INT_SERIRQ: length 134.6
  TOP w0.14: KBC24.125 174.89,23.84 174.59,24.13 174.59,24.45 174.34,24.7 v1(174.34,25.53) ; RN2002.6 122.24,93.79 v2(121.99,93.54) 121.99,93.47 121.12,92.6 121.12,89.87 121.25,89.74 121.25,89.41 121.05,89.21 121.05,88.89 120.59,88.43 120.59,87.33 120.32,87.06 119.72,87.06 119.16,87.06 118.73,86.62 118.73,85.78 118.02,85.07 117.7,85.07 v1(117.26,84.63)
  L3 w0.127: v1(117.26,84.63) 117.26,84.75 118.64,86.13 118.64,86.76 120.65,88.76 120.65,89.54 120.22,89.96 120.22,90.33 121.25,91.35 121.25,92.61 121.99,93.35 125.8,93.35 125.89,93.26 127.27,93.26 128.61,91.91 129.89,91.91 130.93,90.87 130.93,89.83 131.27,89.49 132.41,89.49 133.39,88.52 134.29,88.52 135.1,87.7 139.08,87.7 141.54,85.24 141.54,75.23 144.96,71.81 144.96,62.35 148.91,58.4 150.03,58.4 150.54,57.89 152.01,57.89 154.56,55.34 154.56,54.8 159.63,49.72 163.94,49.72 166.04,47.62 166.04,45.84 165.95,45.75 165.95,39.65 167.89,37.71 170.27,37.71 170.79,37.18 173.37,37.18 174.9,35.65 v1(174.9,35.49)
  L4 w0.127: v1(174.9,35.49) 174.67,35.49 173.37,34.2 173.37,32.65 172.04,31.32 172.04,29.74 172.37,29.41 172.37,28.55 174.34,26.59 v1(174.34,25.53)
  BOTTOM w0.14: v1(117.26,84.63) 116.94,84.95 CPU1.T4
INT_TP#: length 133.5
  TOP w0.102: R6203.1 129.61,97.27 v1(130.45,96.44) 130.83,96.82 AFTP6241.1 131.54,96.82 131.77,96.59 131.77,95.19 131.9,95.06 TPAD1.4 131.9,93.57 v1(132.2,93.26) ; R2031.1 130.37,66.74 131.25,66.74 131.97,66.02 134.27,66.02 R2030.1 135.58,66.75 v1(135.71,66.62) ; R2453.1 178.69,19.39 R2448.1 178.69,21.05 v1(178.8,21.17)
  L3 w0.102: v1(135.71,66.62) 135.61,66.53 135.61,65.83 136.09,65.35 136.09,56.81 133.8,54.53 133.8,51.12 144.24,40.69 144.24,39.5 144.24,38.96 146.52,36.68 146.52,34.03 148,32.55 148,31.45 148,30.9 152.6,26.31 152.6,25.62 155.14,23.08 155.14,22.66 155.52,22.28 161.3,22.28 161.79,21.79 167.78,21.79 167.85,21.86 170.02,21.86 171.03,20.85 171.03,20.82 171.3,20.56 172.19,20.56 172.2,20.55 172.97,20.55 173.44,21.02 178.65,21.02 v1(178.8,21.17)
  L4 w0.102: v1(130.45,96.44) 130.73,96.72 132.99,96.72 133.17,96.89 135.74,96.89 136.09,96.54 136.09,94.56 136.6,94.05 136.6,93.21 137.74,92.07 137.74,90.94 138.28,90.39 138.28,88.34 137.18,87.24 137.18,74.98 137.79,74.38 137.79,69.33 135.71,67.25 v1(135.71,66.62)
  BOTTOM w0.102: v1(132.2,93.26) 132.09,93.15 R1512.1
INT_TP#_GPIO8: length 14.6
  TOP w0.102: v1(128.07,67.84) 128.52,67.4 R2015.2 128.53,66.91 R2031.2
  L4 w0.102: v1(128.07,67.84) 128.06,67.83 127.3,67.83 126.52,68.61 v1(126.52,68.84)
  BOTTOM w0.089: 119.5,73.34 119.33,73.34 119.29,73.38 118.55,73.38 CPU1.AU2
  BOTTOM w0.102: v1(126.52,68.84) 125.98,69.38 123.94,69.38 123.78,69.54 123.22,69.54 120.95,71.81 120.67,71.81 120.25,72.23 120.25,72.74 119.65,73.34 119.5,73.34
INT_TP#_GPIO46: length 24.7
  TOP w0.102: v1(117.89,78.62) 118.71,77.81 v2(119.03,77.81)
  TOP w0.127: R2030.2 134.1,66.42 133.95,66.27 132.07,66.27 131.34,66.99 130.99,66.99 130.39,67.59 R2010.2 129.8,68.39 129.37,68.39 127.84,69.92 127.84,73.3 127.3,73.83 127.3,73.88 123.95,77.23 123.95,77.28 123.17,78.06 122.58,78.06 122.34,77.82 120.1,77.82 120,77.93 119.15,77.93 v2(119.03,77.81)
  BOTTOM w0.102: CPU1.AG3 117.59,78.92 v1(117.89,78.62)
INT_TP#_GPIO55: length 26.7
  TOP w0.102: v2(115.49,84.52) 115.49,84.65 v1(115.15,84.99)
  L4 w0.102: v1(115.15,84.99) 114.67,84.51 114.34,84.51 114.05,84.22 114.05,83.86 114.31,83.61 117.99,83.61 118.77,84.38 119.46,84.38 119.61,84.52 119.94,84.52 120.09,84.68 121.13,84.68 122.63,86.17 123.01,86.17 123.8,86.96 123.8,87.32 125.04,88.56 126.57,88.56 127.38,89.37 127.38,89.88 127.63,90.14 127.63,90.97 128.4,91.74 129.74,91.74 129.84,91.84 v1(132.09,91.84)
  BOTTOM w0.102: v1(132.09,91.84) 132.29,91.84 R1512.2 ; v1(115.15,84.99) 114.96,84.8 CPU1.U7
INT_TP#_KBC: length 6.3
  TOP w0.127: KBC24.121 173.29,21.36 174.27,20.39 v2(174.7,20.39) 175.35,21.04 177,21.04 R2448.2
ISOLATE#: length 4.5
  TOP w0.102: R3014.2 38.39,65.08 R3015.1 v2(39.31,65.08) 39.73,65.08 v1(39.99,64.81)
  BOTTOM w0.102: LOM30.20 40.19,64.62 v1(39.99,64.81)
ISUM_R_C: length 32.8
  TOP w0.254: v1(94.88,125.42) 95.62,126.15 97.71,126.15 98.28,125.58 107.74,125.58 ; 107.74,125.58 v2(107.74,125.8) ; 107.74,125.58 112.84,125.58 113.12,125.3 PR4708.2 PC4707.2 PC4708.2 115.29,126.05 PC4710.1 PC4709.1 116.19,126.04 PR4705.1
  BOTTOM w0.254: v1(94.88,125.42) PR4704.2 94.88,119.34 94.22,118.69 PG4702.1
ISUM_R_R: length 0.9
  TOP w0.254: PC4709.2 117.08,126.04 PR4706.1
JACK_PLUG: length 14.6
  BOTTOM w0.254: HPMIC1.5 13.61,12.8 16.91,9.49 R2905.1 17.59,8.21 C2902.1 R2923.1 20.11,8.6 v2(20.88,9.36) 21.49,9.36 Q2901.G
JACK_PLUG_DET: length 11.9
  BOTTOM w0.254: R2914.2 R2916.1 17.55,10.81 v2(17.02,10.27) 13.48,13.81 10.16,13.81 HPMIC1.6
JDREF: length 3.3
  TOP w0.102: HDA27.15 37.03,14.23 37.21,14.41 37.21,15.22 36.62,15.8 v2(36.62,15.82) 36.62,16.72 R2707.1
JGND:
  vias: v3(105.82,150.91) v3(105.83,150.06) v3(105.85,151.79) v3(106.69,151.74) v3(106.69,150.91) v3(106.69,150.06)
KB_BL_CTRL: length 95.3
  TOP w0.102: v1(176.11,32.5) 176.12,32.5 176.52,32.1 KBC24.22
  L3 w0.102: v1(179.12,23.06) 178.46,23.06 177.67,22.27 172.69,22.27 172.25,22.71 167.5,22.71 167.43,22.64 163.63,22.64 162.68,23.59 159.76,23.59 155.48,27.87 155.48,28.21 154.84,28.85 154.61,28.85 151.51,31.95 151.51,34.5 150.77,35.24 150.77,37.15 147.71,40.21 147.71,42.35 139.67,50.39 139.67,68.73 v1(137.36,71.05)
  L4 w0.102: v1(179.12,23.06) 178.43,23.74 178.43,28.03 176.77,29.69 176.77,31.84 v1(176.11,32.5)
  BOTTOM w0.102: v1(137.36,71.05) 137.36,69.93 R6208.1 139.24,69.54 139.44,69.74 v2(139.44,69.97) 139.44,70.55 139,71 Q6202.G
KB_BL_CTRL#: length 44
  TOP w0.305: AFTP6247.1 130.12,104.56 131.25,104.56 KBLIT1.4 131.26,104.56 132.13,104.56
  TOP w0.508: v1(135.19,101.11) 135.19,101.5 132.13,104.56
  BOTTOM w0.508: Q6202.D 136.13,72.9 135.35,73.68 135.35,80.51 137.41,82.57 137.41,88.08 136.95,88.54 136.95,90.55 136.22,91.28 136.22,92.67 137.87,94.32 137.87,97.03 137.51,97.39 137.51,98.29 138.1,98.87 138.1,101.08 137.16,102.03 135.74,102.03 135.19,101.48 v1(135.19,101.11)
KB_DET#: length 137.8
  TOP w0.102: v1(190.48,81.39) 190.02,81.39 189.45,81.96 KB1.30 191.3,82.26 AFTP6202.1 192.12,83.09 192.12,87.66 196.63,92.17 196.63,99.63 199.86,102.86 199.86,109.79 200.37,110.3 KB2.30 ; RN2002.5 121.77,94.44 v1(121.21,93.87) 121.21,93.25 120.72,92.77 120.72,91 120.24,90.51 120.24,89.96 120.41,89.79 120.41,89.16 v1(120.2,88.94)
  L3 w0.102: v1(136.62,94.84) 136.9,95.12 143.2,95.12 143.8,95.72 149.32,95.72 149.32,95.72 149.57,95.72 150.74,96.89 152.76,96.89 153.07,96.59 153.64,96.59 154.14,97.09 154.89,97.09 v1(155.65,96.33)
  L4 w0.102: v1(136.62,94.84) 137.18,95.39 137.18,96.82 136.73,97.27 135.99,97.27 135.81,97.1 132.97,97.1 132.81,96.94 131.06,96.94 130.96,97.05 129.39,97.05 128.57,96.23 126.9,96.23 124.57,93.91 121.24,93.91 v1(121.21,93.87)
  BOTTOM w0.102: v1(155.65,96.33) 156.1,96.79 173.37,96.79 174.04,96.13 174.41,96.13 174.82,95.72 184.7,95.72 185.53,94.88 189.56,94.88 193.59,90.86 193.59,90.03 192.87,89.31 192.87,87.37 190.48,84.98 v1(190.48,81.39) ; CPU1.K2 118.37,87.99 118.58,88.2 118.58,88.94 118.8,89.17 119.71,89.17 119.93,88.94 v1(120.2,88.94)
KB_LED_BL_DET: length 40.6
  TOP w0.102: v2(120.85,89.58) 120.67,89.76 v1(120.67,90.14)
  L3 w0.102: v1(140.31,77.06) 139.82,77.54 139.82,82.67 140.92,83.76 140.92,84.58 138.56,86.94 134.07,86.94 133.11,87.9 133.11,88.27 132.26,89.13 131.11,89.13 130.55,89.69 130.55,90.72 129.74,91.53 128.47,91.53 127.11,92.89 125.74,92.89 125.65,92.98 122.14,92.98 121.73,92.56 121.73,91.2 v1(120.67,90.14)
  BOTTOM w0.102: CPU1.J1 119.09,88.93 119.48,88.93 119.88,88.54 120.37,88.54 120.73,88.9 120.73,90.08 v1(120.67,90.14) ; R6206.1 R6207.1 v1(140.31,77.06)
KB_LED_DET_C: length 36.2
  TOP w0.102: v1(134.39,101.08) 134.39,101.51 133.35,102.55 KBLIT1.2 131.25,102.56 130.79,102.56 129.71,103.64 AFTP6246.1
  BOTTOM w0.102: R6206.2 139.42,79.66 C6203.1 138.79,80.28 138.79,90.59 138.1,91.28 138.1,92.69 139.19,93.77 139.19,98.06 138.76,98.49 138.76,101.36 137.53,102.59 135.26,102.59 134.39,101.72 v1(134.39,101.08)
KBC_BEEP: length 159.9
  TOP w0.203: v1(172.39,21) 172.39,21.02 172.09,21.31 KBC24.118
  TOP w0.254: RN2701.1 41.02,24.36 41.2,24.18 v2(41.78,24.18) 42.25,24.18 v1(42.43,24.35)
  L4 w0.254: v1(42.43,24.35) 51.34,15.44 58.08,15.44 58.97,16.32 64.16,16.32 66.74,13.74 71.26,13.74 79,6.01 104.86,6.01 108.11,9.25 109.73,9.25 109.99,8.99 110.68,8.99 111.46,8.21 111.46,7.8 112.18,7.08 124.94,7.08 125.44,7.57 126.18,7.57 128.27,9.66 136.69,9.66 138.29,8.05 143.59,8.05 144.27,8.73 147.7,8.73 147.7,8.73 148.86,8.73 148.86,8.73 152.74,8.73 154.57,6.9 158.75,6.9 158.75,6.9 161.87,6.9 162.43,7.46 164.99,10.02 170.67,10.02 172.2,11.56 174.14,13.49 174.14,20.04 173.18,21 v1(172.39,21)
KBC_BEEP_R: length 3.7
  TOP w0.254: D2701.1 40.7,21.88 RN2701.4 41.8,23.16 v2(41.98,22.98)
KBC_DPWROK: length 66.8
  TOP w0.127: KBC24.81 161.22,29.7 160.83,29.3 v2(160.25,29.3) 160.22,29.3 159.87,28.95 159.06,28.95 v1(158.95,29.05)
  L4 w0.127: v1(158.95,29.05) 158.95,31.39 157.8,32.54 157.8,34.33 157.13,34.99 155.42,34.99 155.2,34.77 155.2,34.77 154.77,34.34 154.77,32.21 154.57,32 151.46,32 149.52,33.94 149.52,36.39 148.12,37.8 147.9,37.8 147.41,37.8 146.82,38.4 146.1,38.4 144.68,39.82 144.19,39.82 140.89,43.12 138.03,43.12 137.29,43.86 136.83,43.86 136.09,43.12 134.77,43.12 133.97,43.91 133.97,45.23 131.95,47.25 131.95,52.04 129.92,54.07 129.92,54.34 129.09,55.16 128.62,55.16 126.91,56.88 124.76,56.88 124.21,57.43 124.21,58.04 v1(124.75,58.58)
  BOTTOM w0.127: v1(124.75,58.58) 124.75,59.15 125.46,59.86 R1725.2 125.46,60.28 125.34,60.39 EC1705.1 125.34,61.16 R1718.2
KBC_ON#_GATE: length 6.2
  TOP w0.102: Q2403.G 154.14,31.36 Q2402.G 154.14,30.58 154.03,30.47 C2417.1 153.67,29.35 v2(153.08,29.35) 152.55,29.35 R2433.2
KBC_ON#_GATE_L: length 4.3
  TOP w0.102: R2432.2 151.33,28.15 v2(151.6,27.88) 151.95,27.88 152.17,28.1 R2433.1 154.01,28.85 R2431.1
KBC_PWRBTN#: length 158.4
  TOP w0.102: R6102.1 101.03,129.95 v1(101.41,129.58) ; v1(159.68,42.95) 159.68,44.46 150.84,53.3 v2(150.84,55.72) v1(150.84,56.45)
  L3 w0.102: v1(142.43,124.87) 142.43,124.88 136.91,130.4 134.58,130.4 133.43,131.54 132.3,131.54 131.85,132 125.85,132 121.53,127.67 121.45,127.67 121.45,127.67 121.09,127.67 121.09,127.67 116.05,127.67 114.96,128.76 111.85,128.76 111.63,128.54 101.88,128.54 101.41,129.01 v1(101.41,129.58)
  L4 w0.102: v1(164.93,27.03) 166.64,28.73 166.64,31.98 165.3,33.32 165.3,36.35 162.62,39.02 162.62,40.01 162.61,40.02 162.61,40.02 162.36,40.28 v1(159.68,42.95)
  BOTTOM w0.102: R2427.1 165.57,26.72 165.27,27.03 v1(164.93,27.03) ; v1(150.84,56.45) 149.99,57.3 149.99,58.66 147.01,61.64 147.01,66.74 146.44,67.31 146.44,80.32 146.86,80.74 146.86,86.98 147.39,87.51 147.39,90.02 146.86,90.56 146.86,99.06 144.29,101.64 144.29,111.02 142.77,112.53 142.77,124.52 v1(142.43,124.87)
KBC_PWRBTN#_C: length 6.7
  TOP w0.127: SW1.4 97.55,133.97 97.7,133.82 97.7,133 97.45,132.76 97.45,131.99 97.64,131.81 98.33,131.81 98.54,132.02 AFTP6801.1 98.85,131.42 99.43,130.84 EC6104.1 R6102.2
KBC_VCORF: length 3.5
  TOP w0.203: C2416.1 171.18,40.24 171.68,40.24 171.98,39.94 v2(171.98,39.87) 171.98,39.77 171.74,39.53 171.74,38.65 171.69,38.6 KBC24.44
KCOL0: length 102.6
  TOP w0.102: KB2.13 200.55,123.9 199.22,123.9 196.4,121.09 196.4,113.7 193.62,110.92 193.62,101.5 192.34,100.22 192.34,98.68 192.34,97.53 190.66,95.86 KB1.13 188.77,95.86 187.91,94.99 187.91,93.76 187.31,93.17 186.08,93.17 183.89,90.98 183.89,83.08 182.09,81.28 182.09,68.21 178.32,64.43 177.82,64.43 AFTP6207.1 175.66,62.28 175.66,52.05 170.23,46.61 170.23,42.37 169.8,41.94 169.8,41.55 168.69,40.44 168.69,39.4 168.09,38.8 KBC24.53
KCOL1: length 100.9
  TOP w0.102: KB2.15 200.55,122.3 199.46,122.3 196.81,119.65 196.81,104.12 192.74,100.05 192.74,98.85 192.74,96.73 190.27,94.26 KB1.15 188.63,94.26 188.31,93.94 188.31,93.6 187.48,92.76 186.25,92.76 184.3,90.81 184.3,82.91 182.5,81.11 182.5,67.59 AFTP6206.1 177.19,62.28 177.19,53.71 176.16,52.68 176.16,51.97 171.68,47.48 171.68,42.93 v1(171.7,42.9) ; KBC24.52 168.49,38.91 168.9,39.32 168.9,40.35 170.01,41.46 170.01,41.86 170.69,42.54 v1(170.69,42.91)
  BOTTOM w0.102: v1(171.7,42.9) 170.7,42.9 v1(170.69,42.91)
KCOL2: length 100.8
  TOP w0.102: KB2.14 200.55,123.1 199.34,123.1 196.61,120.37 196.61,104.21 192.54,100.14 192.54,98.77 192.54,98.77 192.54,98.26 192.54,98.26 192.54,97.2 190.4,95.06 KB1.14 189.15,95.06 188.11,94.02 188.11,93.68 187.4,92.97 186.17,92.97 184.1,90.9 184.1,82.99 182.3,81.19 182.3,68.12 176.89,62.72 176.89,61.48 AFTP6226.1 175.87,60.45 175.87,51.96 171.24,47.34 171.24,42.71 170.93,42.4 170.84,42.4 170.21,41.77 170.21,41.38 169.1,40.27 169.1,39.23 168.89,39.03 KBC24.51
KCOL3: length 100.8
  TOP w0.102: KB2.16 200.55,121.5 199.64,121.5 197.01,118.88 197.01,104.04 192.95,99.97 192.95,98.93 192.95,95.05 191.36,93.46 KB1.16 188.46,93.46 187.56,92.56 186.33,92.56 184.5,90.73 184.5,84.62 184.94,84.18 184.94,81.09 185.12,80.91 185.12,78.35 183.46,76.69 183.46,68.05 AFTP6208.1 177.39,61.98 177.39,53.63 176.36,52.6 176.36,51.88 172.39,47.91 172.39,42.76 171.82,42.19 170.92,42.19 170.41,41.69 170.41,41.29 169.3,40.18 169.3,38.65 169.29,38.64 KBC24.50
KCOL4: length 99.6
  TOP w0.102: KBC24.49 169.69,40.29 171.02,41.62 v1(171.02,41.66) ; v1(173.45,41.9) 174.17,42.61 174.17,46.51 179.68,52.02 179.68,58.17 AFTP6224.1 180.87,59.36 180.87,63.67 184.27,67.07 184.27,76.36 185.93,78.01 185.93,80.81 185.93,80.81 185.93,81.24 185.75,81.42 185.75,84.52 185.32,84.96 185.32,90.38 186.06,91.13 188.28,91.13 189.15,90.26 KB1.20 190.19,90.26 190.7,90.77 190.7,91.32 194.6,95.22 194.6,100.47 197.83,103.7 197.83,116.54 199.59,118.3 200.55,118.3 KB2.20
  BOTTOM w0.102: v1(173.45,41.9) 173.3,42.05 171.41,42.05 v1(171.02,41.66)
KCOL5: length 100.5
  TOP w0.102: KB2.21 200.55,117.5 199.68,117.5 198.03,115.85 198.03,103.62 194.8,100.39 194.8,95.13 190.9,91.23 190.9,89.62 190.74,89.46 KB1.21 188.86,89.46 188.59,89.73 188.59,90.53 188.19,90.92 186.15,90.92 185.52,90.3 185.52,85.05 185.96,84.61 185.96,81.5 186.13,81.33 186.13,80.72 186.13,80.72 186.13,77.93 184.48,76.27 184.48,66.99 182.24,64.74 AFTP6215.1 181.3,61.82 181.3,53.36 174.37,46.42 174.37,42.14 v1(173.49,41.26) ; v1(171.66,41.61) 171.6,41.61 171.2,41.21 170.91,41.21 170.09,40.4 KBC24.48
  BOTTOM w0.102: v1(173.49,41.26) 173.41,41.26 173.04,41.63 171.71,41.63 171.7,41.61 v1(171.66,41.61)
KCOL6: length 100.3
  TOP w0.102: v1(172.95,40.58) 172.95,40.83 172.79,40.98 172.79,45.79 176.77,49.76 176.77,52.43 178,53.66 178,59.89 180.2,62.09 AFTP6223.1 180.2,63.57 183.87,67.24 183.87,76.52 185.52,78.18 185.52,81.08 185.35,81.25 185.35,84.35 184.91,84.79 184.91,90.55 186.22,91.86 KB1.18 190.33,91.86 193.35,94.88 193.35,97.92 193.35,99.1 193.35,99.1 193.35,99.8 197.42,103.87 197.42,118.17 199.16,119.9 200.55,119.9 KB2.18 ; v1(171.54,40.95) 170.93,40.95 170.49,40.51 KBC24.47
  BOTTOM w0.102: v1(172.95,40.58) 172.86,40.67 171.82,40.67 v1(171.54,40.95)
KCOL7: length 99.7
  TOP w0.102: v1(172.13,41.19) 172.13,41.02 172.31,40.84 172.31,40.32 172.5,40.13 172.5,39.71 172.26,39.47 172.26,38.95 172.15,38.84 172.15,38.84 172.09,38.78 KBC24.43 ; KB2.19 200.55,119.1 199.25,119.1 197.62,117.48 197.62,103.78 193.55,99.72 193.55,99.19 193.56,99.19 193.56,97.84 193.55,97.84 193.55,94.63 189.99,91.06 KB1.19 188.69,91.06 188.42,91.33 185.98,91.33 185.11,90.47 185.11,84.87 185.55,84.43 185.55,81.34 185.73,81.16 185.73,78.09 184.07,76.44 184.07,67.15 180.67,63.75 180.67,61.19 AFTP6213.1 178.29,58.81 178.29,50.92 173,45.63 173,41.14 173.35,40.78 173.41,40.78 v1(173.58,40.62)
  BOTTOM w0.102: v1(172.13,41.19) 172.13,41.19 172.31,41.01 173.13,41.01 173.52,40.62 v1(173.58,40.62)
KCOL8: length 98.5
  TOP w0.102: KBC24.42 172.49,39 172.46,39.03 172.46,39.39 172.7,39.63 172.7,40.21 172.51,40.4 172.51,40.96 172.56,41.01 172.56,41.37 172.56,41.37 172.51,41.42 172.51,41.85 172.59,41.93 172.59,47.82 176.57,51.8 176.57,52.52 177.59,53.54 177.59,60.15 AFTP6231.1 179.81,62.37 179.81,63.47 183.67,67.32 183.67,76.61 185.32,78.26 185.32,80.99 185.14,81.17 185.14,84.27 184.71,84.7 184.71,90.64 186.42,92.36 186.97,92.36 187.65,92.36 187.95,92.66 KB1.17 190.85,92.66 193.15,94.96 193.15,98.01 193.15,98.01 193.15,99.02 193.15,99.89 197.22,103.95 197.22,118.6 199.32,120.7 200.55,120.7 KB2.17
KCOL9: length 114.4
  TOP w0.102: KBC24.41 172.89,38.53 172.9,38.53 v1(172.9,39.21) ; KB2.7 200.55,128.7 198.43,128.7 195.18,125.46 195.18,114.21 192.4,111.42 192.4,102.4 190.66,100.66 KB1.7 188.75,100.66 188.53,100.43 188.39,100.3 188.39,100 187.73,99.34 187.73,98.69 184.94,95.9 184.94,93.75 182.67,91.49 182.67,83.58 180.88,81.78 180.88,70.1 AFTP6219.1 176.95,66.17 175.21,66.17 173.2,64.17 173.2,63.1 173,62.89 173,51.11 167.74,45.85 167.74,41.89 168.4,41.23 168.4,39.99 168.35,39.94 168.35,39.67 v1(167.77,39.1)
  BOTTOM w0.102: v1(172.9,39.21) 172.64,39.21 171.99,39.86 168.83,39.86 168.28,39.31 167.99,39.31 v1(167.77,39.1)
KCOL10: length 121.1
  TOP w0.102: KB2.5 199.16,130.3 199.16,130.3 198.67,130.3 194.78,126.41 194.78,114.38 191.99,111.59 191.99,104.13 190.12,102.26 KB1.5 188.8,102.26 188.53,101.99 188.53,101.62 187.32,100.41 187.32,98.86 184.53,96.07 184.53,93.92 182.27,91.66 182.27,83.75 180.47,81.95 180.47,70.5 177.15,67.18 174.7,67.18 AFTP6232.1 171.93,64.41 171.93,63.15 172.3,62.78 172.3,50.99 167.32,46 167.32,42.54 166.75,41.98 166.24,41.98 164.51,40.25 164.51,39.31 v1(164.77,39.06) ; v1(173.46,38.85) 173.46,38.81 173.29,38.64 KBC24.40
  BOTTOM w0.102: v1(164.77,39.06) 165.16,38.67 167.96,38.67 168.95,39.66 171.81,39.66 172.69,38.78 173.38,38.78 v1(173.46,38.85)
KCOL11: length 115.4
  TOP w0.102: KB2.6 199.14,129.5 199.13,129.5 198.64,129.5 194.98,125.85 194.98,114.29 192.19,111.51 192.19,102.88 190.77,101.46 KB1.6 188.66,101.46 187.53,100.33 187.53,98.77 184.74,95.98 184.74,93.84 182.47,91.57 182.47,83.67 180.67,81.87 180.67,70.41 177.08,66.82 AFTP6220.1 175.93,66.61 175.36,66.61 173,64.25 173,63.18 172.51,62.69 172.51,50.9 167.54,45.93 167.54,41.69 167.76,41.47 167.87,41.47 168.2,41.14 168.2,40.07 167.94,39.82 167.88,39.82 v1(167.8,39.74) ; v1(173.43,39.55) 173.89,39.09 173.89,38.63 173.69,38.43 KBC24.39
  BOTTOM w0.102: v1(173.43,39.55) 173.29,39.69 172.55,39.69 172.18,40.06 168.74,40.06 168.42,39.74 v1(167.8,39.74)
KCOL12: length 109.2
  TOP w0.102: KB2.12 200.55,124.7 198.88,124.7 196.2,122.03 196.2,113.79 193.41,111 193.41,101.59 192.13,100.31 192.13,98.25 190.54,96.66 KB1.12 188.46,96.66 185.96,94.16 185.96,93.33 183.69,91.07 183.69,83.16 181.89,81.36 181.89,68.51 AFTP6233.1 177.67,64.79 175.46,62.58 175.46,52.13 170.03,46.7 170.03,42.45 169.6,42.03 169.6,41.77 169.15,41.32 v1(168.96,41.32) ; v1(174.24,40.63) 174.09,40.48 KBC24.38
  BOTTOM w0.102: v1(168.96,41.32) 169.21,41.32 170.16,42.27 172.63,42.27 172.76,42.4 173.56,42.4 173.92,42.03 173.92,40.95 v1(174.24,40.63)
KCOL13: length 111.3
  TOP w0.102: v1(168.68,42.67) 168.68,46.21 173.41,50.94 173.41,62.56 174.28,63.43 175.19,63.43 176.06,64.3 176.06,64.71 AFTP6203.1 176.74,65.39 177.24,65.39 181.28,69.43 181.28,81.62 183.08,83.41 183.08,91.32 185.35,93.59 185.35,95.73 188.68,99.06 KB1.9 190.02,99.06 192.8,101.84 192.8,111.25 195.59,114.04 195.59,124.59 198.1,127.1 200.55,127.1 KB2.9 ; KBC24.37 174.49,38.7 174.42,38.78 174.42,39.36 v1(174.7,39.64)
  BOTTOM w0.102: v1(168.68,42.67) 168.74,42.61 168.74,41.73 168.53,41.52 168.53,41.14 169.2,40.47 172.45,40.47 172.77,40.15 173.13,40.15 173.17,40.18 174.16,40.18 v1(174.7,39.64)
KCOL14: length 112.8
  TOP w0.102: v1(168.3,42.04) 167.94,42.4 167.94,45.76 173.2,51.03 173.2,62.64 174.34,63.78 174.34,64.09 175.84,65.59 176.94,65.59 AFTP6216.1 181.08,69.73 181.08,81.7 182.88,83.5 182.88,91.4 185.14,93.67 185.14,95.81 187.93,98.6 187.93,99.26 188.54,99.86 KB1.8 190.53,99.86 192.6,101.93 192.6,111.34 195.39,114.12 195.39,125.12 198.17,127.9 200.55,127.9 KB2.8 ; v1(174.85,38.96) 174.89,38.91 KBC24.36
  BOTTOM w0.102: v1(174.85,38.96) 174.77,38.96 173.75,39.98 173.25,39.98 173.22,39.95 172.65,39.95 172.33,40.27 168.65,40.27 168.32,40.59 168.32,42.02 v1(168.3,42.04)
KCOL15: length 110.8
  TOP w0.102: KB2.10 200.55,126.3 198.32,126.3 195.79,123.78 195.79,113.96 193.01,111.17 193.01,101.76 191.73,100.48 191.73,99.37 190.62,98.26 KB1.10 188.82,98.26 188.37,97.82 187.74,97.82 185.55,95.63 185.55,93.5 183.28,91.23 183.28,83.33 181.48,81.53 181.48,69.33 180.76,68.6 180.74,68.6 175.37,63.23 174.58,63.23 AFTP6229.1 173.61,62.26 173.61,50.86 169.31,46.56 v1(169.31,42.64) ; v1(175.59,40.18) 175.59,40.18 175.59,40.12 175.29,39.83 KBC24.35
  BOTTOM w0.102: v1(175.59,40.18) 175.59,40.18 175.59,40.17 174.88,40.89 174.88,40.9 174.33,41.45 174.33,42.2 173.19,43.34 170.22,43.34 169.52,42.64 v1(169.31,42.64)
KCOL16: length 110.2
  TOP w0.102: KB2.11 200.55,125.5 199.04,125.5 196,122.46 196,113.87 193.21,111.09 193.21,101.67 191.93,100.39 191.93,98.34 191.05,97.46 KB1.11 188.42,97.46 188.27,97.61 187.82,97.61 185.75,95.54 185.75,93.42 183.49,91.15 183.49,83.25 181.69,81.45 181.69,69.24 175,62.56 175,61.62 AFTP6225.1 173.81,60.43 173.81,50.77 169.82,46.78 169.82,42.54 169.31,42.02 v1(169.17,42.02) ; v1(175.73,39.26) 175.73,39.29 175.69,39.26 KBC24.34
  BOTTOM w0.102: v1(169.17,42.02) 169.62,42.02 170.07,42.47 172.5,42.47 172.63,42.6 173.64,42.6 174.12,42.12 174.12,41.36 174.67,40.81 174.67,40.45 175.73,39.4 v1(175.73,39.26)
KROW0: length 108
  TOP w0.102: KB2.22 199.64,116.7 199.64,116.7 198.23,115.3 198.23,103.53 195.01,100.31 195.01,95.05 191.11,91.15 191.11,89.37 190.4,88.66 KB1.22 189.18,88.66 188.39,89.45 188.39,90.17 188.09,90.46 187.27,90.46 186.9,90.1 186.9,86.17 187.17,85.9 187.17,81.23 187.67,80.73 187.67,78.92 185.58,76.83 185.58,70.32 184.97,69.7 184.97,67.19 183.22,65.45 183.22,61.71 AFTP6228.1 181.51,60 181.51,53.27 174.62,46.39 174.62,41.75 v1(175.56,40.81) ; KBC24.54 167.69,38.52 167.34,38.87 167.34,39.28 167.36,39.3 167.36,39.98 v1(167.76,40.37)
  BOTTOM w0.102: v1(175.56,40.81) 175.46,40.91 175.22,40.91 174.53,41.6 174.53,42.29 173.28,43.54 168.94,43.54 167.87,42.47 167.87,41.54 168.12,41.29 168.12,40.73 v1(167.76,40.37)
KROW1: length 103.4
  TOP w0.102: v1(167.69,41.04) 167.16,40.51 167.16,39.39 167.14,39.36 167.14,38.78 167.29,38.63 KBC24.55 ; v1(176.24,40.69) 176.24,40.74 175.89,41.09 175.89,42.05 175.61,42.32 175.44,42.32 175.16,42.61 175.16,46.35 181.91,53.11 181.91,57.57 182.71,58.37 182.71,60.09 184.27,61.65 AFTP6227.1 184.27,62.89 185.37,64 185.37,68.69 185.37,69.54 185.99,70.15 185.99,76.67 188.07,78.75 188.07,80.9 187.58,81.4 187.58,85.07 188.5,85.99 188.5,86.66 188.9,87.06 KB1.24 190.44,87.06 190.8,87.42 190.8,88.07 191.81,89.08 191.81,91.28 195.41,94.88 195.41,100.14 198.64,103.36 198.64,114.3 199.44,115.1 200.55,115.1 KB2.24
  BOTTOM w0.102: v1(167.69,41.04) 167.67,41.06 167.67,42.55 168.86,43.74 173.36,43.74 174.73,42.37 174.73,41.68 175.17,41.24 175.74,41.24 176.24,40.74 v1(176.24,40.69)
KROW2: length 100.9
  TOP w0.102: v1(176.59,41.42) 176.55,41.42 176.1,41.88 176.1,42.38 176.2,42.49 176.2,43.5 177.63,44.94 177.63,48.09 183.59,54.04 183.59,57.02 184.27,57.7 AFTP6218.1 185.31,59.73 185.31,63.36 185.78,63.83 185.78,68.86 185.78,69.37 186.4,69.98 186.4,76.5 188.48,78.58 188.48,81.07 187.98,81.57 187.98,84.44 189.01,85.46 KB1.26 190.8,85.46 191.21,85.87 191.21,87.9 192.22,88.91 192.22,91.11 195.82,94.71 195.82,99.97 199.04,103.19 199.04,112.93 199.61,113.5 200.55,113.5 KB2.26 ; KBC24.56 166.89,38.74 166.88,38.76 166.88,39.1 166.73,39.24 v1(166.73,39.5)
  BOTTOM w0.102: v1(166.73,39.5) 167.26,40.03 167.26,41.22 167.35,41.31 167.35,42.21 167.35,42.52 168.77,43.95 173.44,43.95 174.94,42.46 174.94,41.77 175.25,41.45 176.57,41.45 v1(176.59,41.42)
KROW3: length 102
  TOP w0.102: KBC24.57 166.49,39.06 166.29,39.26 166.29,39.88 v1(166.5,40.09) ; KB2.23 200.55,115.9 199.78,115.9 198.44,114.56 198.44,114.39 198.44,114.39 198.44,103.45 195.21,100.22 195.21,94.96 191.31,91.06 191.31,88.88 190.29,87.86 KB1.23 188.82,87.86 188.3,87.34 188.3,86.08 187.37,85.15 187.37,81.31 187.87,80.81 187.87,78.83 185.78,76.74 185.78,70.23 185.17,69.62 185.17,67.1 183.43,65.36 183.43,61.1 182.24,59.91 AFTP6234.1 181.71,58.17 181.71,53.19 174.95,46.43 174.95,42.36 v1(175.43,41.88)
  BOTTOM w0.102: v1(175.43,41.88) 175.14,42.17 175.14,42.54 173.53,44.15 168.69,44.15 167.15,42.61 167.15,42.3 167.14,41.5 167.05,41.41 167.05,40.65 v1(166.5,40.09)
KROW4: length 100.1
  TOP w0.102: v1(166.41,40.85) 166.06,40.5 166.06,38.42 166.09,38.39 KBC24.58 ; v1(176.53,42.05) 176.53,43.54 177.84,44.85 177.84,46.83 178.85,47.85 180.31,47.85 183.13,50.66 183.13,53.17 183.79,53.83 183.79,56.94 185.51,58.66 185.51,63.27 186.3,64.06 AFTP6230.1 186.3,65.47 185.98,65.79 185.98,68.95 185.98,68.95 185.98,69.28 186.6,69.9 186.6,76.41 188.68,78.49 188.68,81.15 188.19,81.65 188.19,83.87 188.98,84.66 KB1.27 190.47,84.66 191.41,85.61 191.41,87.82 196.02,92.43 196.02,99.88 199.25,103.11 199.25,112.09 199.85,112.7 KB2.27
  BOTTOM w0.102: v1(166.41,40.85) 166.85,41.29 166.85,41.5 166.94,41.59 166.94,42.38 166.94,42.38 166.94,42.69 168.61,44.35 173.61,44.35 175.34,42.62 175.34,42.57 175.6,42.31 176.27,42.31 v1(176.53,42.05)
KROW5: length 100.1
  TOP w0.102: v1(166.42,41.49) 166.42,41.48 166.22,41.28 166.21,41.28 165.96,41.02 165.96,40.89 165.86,40.79 165.86,38.68 165.69,38.51 KBC24.59 ; KB2.25 200.55,114.3 199.53,114.3 198.84,113.62 198.84,103.28 195.62,100.05 195.62,94.79 192.01,91.19 192.01,88.99 191.01,87.98 191.01,87.28 189.99,86.26 KB1.25 189.06,86.26 187.78,84.98 187.78,81.48 188.28,80.98 188.28,78.66 186.19,76.58 186.19,70.07 185.58,69.45 185.58,68.78 185.58,63.92 185.1,63.44 185.1,61.56 AFTP6214.1 184.04,60.73 182.92,59.6 182.92,58.39 183.39,57.92 183.39,54.15 175.65,46.42 175.65,42.87 v1(175.77,42.75)
  BOTTOM w0.102: v1(175.77,42.75) 175.52,42.75 173.71,44.56 168.52,44.56 166.74,42.77 166.74,42.47 166.74,41.8 166.42,41.48 v1(166.42,41.49)
KROW6: length 99.8
  TOP w0.102: v1(165.2,40.33) 165.66,39.87 165.66,38.9 165.29,38.54 KBC24.60 ; KB2.28 200.04,111.9 199.45,111.31 199.45,103.03 196.22,99.8 196.22,92.34 191.62,87.73 191.62,85.52 189.95,83.86 KB1.28 188.62,83.86 188.42,83.67 188.42,81.7 188.89,81.24 188.89,78.34 187.93,77.38 187.93,70.65 186.19,68.91 186.19,65.92 186.66,65.45 186.66,63.11 AFTP6222.1 185.71,62.17 185.71,58.57 184,56.86 184,53.75 183.33,53.09 183.33,50.55 180.43,47.64 178.93,47.64 178.04,46.75 178.04,44.77 177.09,43.82 v1(177.09,43.08)
  BOTTOM w0.102: v1(177.09,43.08) 176.48,43.08 174.59,44.96 168.35,44.96 166.33,42.94 166.33,42.64 166.33,42.36 165.66,41.69 165.66,40.79 v1(165.2,40.33)
KROW7: length 100.1
  TOP w0.102: v1(164.95,39.69) 165.22,39.41 165.22,38.8 164.89,38.47 KBC24.61 ; KB2.29 199.85,111.1 199.65,110.9 199.65,102.94 196.43,99.72 196.43,92.26 191.82,87.65 191.82,84.6 190.28,83.06 KB1.29 188.78,83.06 188.62,82.9 188.62,81.79 189.09,81.32 189.09,78.25 188.13,77.3 188.13,70.57 186.39,68.82 186.39,66 186.86,65.53 186.86,61.28 AFTP6221.1 185.92,60.34 185.92,58.49 184.2,56.77 184.2,53.66 183.54,53 183.54,50.47 180.51,47.44 179.02,47.44 178.24,46.66 178.24,44.68 177.62,44.06 177.62,42.59 v1(177.49,42.46)
  BOTTOM w0.102: v1(177.49,42.46) 176.81,42.46 174.51,44.76 168.44,44.76 166.54,42.86 166.54,42.55 166.54,42.27 165.86,41.6 165.86,40.33 165.22,39.69 v1(164.95,39.69)
L_BKLT_CTRL: length 107.8
  L3 w0.127: v1(45.96,85.92) 46.24,85.64 v1(46.24,78.74)
  L4 w0.127: v1(45.96,85.92) 46.73,86.69 48.59,86.69 48.61,86.71 48.73,86.71 49.51,87.49 49.51,88.18 53.98,92.65 60.62,92.65 67.4,99.42 68.66,99.42 69.01,99.42 72.23,102.65 76.12,102.65 77.62,104.14 88.61,104.14 92.87,99.89 94.31,99.89 95.01,99.19 99.48,99.19 100.21,99.92 102.11,99.92 102.39,100.2 108.03,100.2 108.04,100.18 110.77,100.18 111.29,100.71 114.57,100.71 115.24,100.04 119.66,100.04 120.57,100.04 121.57,101.04 v1(121.61,101.04)
  BOTTOM w0.089: CPU1.B8 114,93.09 114.15,93.09 114.64,93.58 114.64,94.18 114.8,94.34
  BOTTOM w0.14: R5206.1 45.83,79.15 v1(46.24,78.74) ; v1(121.61,101.04) 121.61,101.03 121.61,101.02 121.61,100.72 121.56,100.68 121.56,100.29 120.6,99.33 ; 120.6,99.33 119.71,98.43 119.71,98.15 118.54,96.98 118.54,96.17 117.71,95.35 115.81,95.35 114.8,94.34 ; 120.6,99.33 v2(120.61,99.33)
L_BKLT_EN: length 134.8
  TOP w0.102: R2444.1 v2(183.18,28.2) 183.83,28.2 v1(183.86,28.23)
  L3 w0.102: v1(115.84,97.89) 116,97.73 120.47,97.73 120.62,97.58 121.43,97.58 122.36,98.52 122.98,98.52 123.26,98.24 125.73,98.24 127.63,100.14 127.96,100.14 128.1,100.28 131.45,100.28 v1(132.16,100.99) ; v1(183.86,28.23) 181.67,30.42 176.6,30.42 175.97,31.06 175.09,31.06 173.37,32.77 173.37,32.98 172.75,33.6 171.55,33.6 170.49,34.67 165.99,34.67 163.87,36.79 162.95,36.79 161.95,37.8 161.95,37.91 151.94,47.92 151.94,50.82 149.47,53.3 149.47,53.62 148.93,54.15 145.93,54.15 144.85,55.23 144.85,56.05 142.88,58.02 142.88,71.14 138.19,75.83 138.19,80.82 v1(136.32,82.69)
  BOTTOM w0.102: v1(132.16,100.99) 132.68,101.52 133.1,101.52 134,100.62 135.59,100.62 135.82,100.84 135.82,101.21 136.05,101.45 136.67,101.45 137.46,100.65 137.46,99.05 136.95,98.54 136.95,97.1 137.31,96.74 137.31,94.55 135.66,92.9 135.66,91.05 136.39,90.32 136.39,88.31 136.85,87.85 136.85,83.23 v1(136.32,82.69) ; CPU1.A9 113.44,94 113.47,94.02 113.47,94.65 113.92,95.1 113.92,95.2 115.85,97.13 115.85,97.89 v1(115.84,97.89)
L_BKLT_EN_EC: length 4.6
  TOP w0.102: KBC24.9 178.36,26.9 178.5,27.04 179.09,27.04 179.27,27.22 v2(179.8,27.22) 181.09,27.22 R2447.1 R2444.2
LAN_ENABLE_R_C: length 3.3
  TOP w0.127: Q3001.D 37.34,48.24 37.48,48.38 R3021.2 R3022.1 v2(35.66,48.85)
LAN_MDI0N: length 22.8
  BOTTOM w0.102: 41.52,55.63 41.52,58.11 41.39,58.24 LOM30.2 ; 41.52,55.63 v2(41.39,55.63) ; 41.52,55.63 41.52,55.02 39.27,52.77 35.75,52.77 EC3102.2 35.11,52.77 34.7,52.77 34.59,52.88 34.59,54.37 34.29,54.67 34.03,54.67 33.91,54.79 U3101.9 U3101.2 31.98,54.79 31.87,54.68 31.59,54.68 31.27,54.35 31.27,53.71 32.49,52.49 32.49,52.32 32.12,51.95 31.34,51.95 31.2,52.09 31.2,52.53 31.08,52.65 30.17,52.65
LAN_MDI0P: length 22.7
  BOTTOM w0.102: 38.48,52.52 39.37,52.52 41.77,54.92 41.77,58.11 41.79,58.13 LOM30.1 ; 38.48,52.52 v2(38.48,52.39) ; 38.48,52.52 35.75,52.52 EC3101.2 35.11,52.52 34.59,52.52 34.34,52.77 34.34,54.26 34.18,54.42 34.03,54.42 33.91,54.31 U3101.10 U3101.1 31.99,54.31 31.87,54.42 31.7,54.42 31.52,54.25 31.52,53.81 32.74,52.59 32.74,52.21 32.23,51.7 31.35,51.7 31.03,51.38 30.17,51.38
LAN_MDI1N: length 23.1
  BOTTOM w0.102: LOM30.5 40.19,58.23 40.26,58.17 40.26,55.59 38.32,53.66 37.05,53.66 36.46,54.25 36.46,55.15 ; v2(36.58,55.15) 36.46,55.15 ; 36.46,55.15 36.46,56.35 35.95,56.86 35.55,56.86 EC3104.2 34.86,56.76 34.59,56.76 34.03,56.2 33.91,56.2 33.8,56.31 U3101.6 U3101.5 31.96,56.31 31.85,56.2 31.67,56.2 31.54,56.33 31.54,56.63 32.89,57.98 32.89,59.32 32.46,59.76 31.75,59.76 31.52,59.53 31.32,59.53 31.18,59.66 31.18,60.09 31,60.27 30.17,60.27
LAN_MDI1P: length 23.1
  BOTTOM w0.102: 30.17,59 30.88,59 31.16,59.27 31.63,59.27 31.86,59.5 32.35,59.5 32.64,59.22 32.64,58.09 31.29,56.74 31.29,56.22 31.57,55.95 31.85,55.95 31.97,55.83 U3101.4 U3101.7 33.79,55.83 33.91,55.95 34.14,55.95 34.69,56.51 35.01,56.51 EC3103.2 35.59,56.6 35.84,56.6 36.2,56.24 36.2,54.36 36.2,54.15 36.95,53.4 38.43,53.4 40.51,55.49 40.51,56.99 ; v2(40.64,56.99) 40.51,56.99 ; 40.51,56.99 40.51,58.11 40.59,58.19 LOM30.4
LAN_MDI2N: length 21
  TOP w0.102: v2(36.63,55.53) 36.63,55.4 ; 36.63,55.4 37.15,55.4 v1(37.44,55.7) ; 36.63,55.4 36.52,55.4 36.19,55.07 36.19,52.97 36.02,52.8 35.72,52.8 EC3106.2 35.14,52.8 34.69,52.8 34.62,52.87 34.62,54.37 34.31,54.68 34.03,54.68 33.91,54.79 U3102.2 U3102.9 31.94,54.79 31.8,54.65 31.54,54.65 31.27,54.38 31.27,53.7 31.95,53.01 31.95,52.16 31.67,51.87 31.25,51.87 31.18,51.93 31.18,52.54 31.08,52.65 30.17,52.65
  BOTTOM w0.102: v1(37.44,55.7) 37.74,55.4 38.2,55.4 ; v2(38.2,55.52) 38.2,55.4 ; 38.2,55.4 38.42,55.4 39.14,56.12 39.14,57.39 39.47,57.72 39.47,58.16 39.39,58.24 LOM30.7
LAN_MDI2P: length 21
  TOP w0.102: v1(37.44,54.8) 37.44,54.98 37.27,55.15 36.62,55.15 36.44,54.97 36.44,52.86 36.13,52.54 35.77,52.54 EC3105.2 35.09,52.54 34.59,52.54 34.36,52.77 34.36,54.27 34.21,54.43 34.03,54.43 33.91,54.31 U3102.1 U3102.10 31.88,54.31 31.8,54.4 31.65,54.4 31.52,54.27 31.52,53.8 32.2,53.12 32.2,52.48 ; v2(32.33,52.48) 32.2,52.48 ; 32.2,52.48 32.2,52.05 31.77,51.62 31.28,51.62 31.04,51.38 30.17,51.38
  BOTTOM w0.102: 39.4,56.19 39.4,57.29 39.73,57.61 39.73,58.13 39.79,58.2 LOM30.6 ; 39.4,56.19 v2(39.53,56.19) ; 39.4,56.19 39.4,56.02 38.52,55.14 37.78,55.14 v1(37.44,54.8)
LAN_MDI3N: length 17.5
  TOP w0.102: 32.86,58.2 32.86,58.03 31.49,56.66 31.49,56.3 31.6,56.2 31.8,56.2 31.91,56.31 U3102.6 U3102.5 33.91,56.31 34.03,56.2 34.18,56.2 34.29,56.3 34.29,56.56 34.57,56.84 34.94,56.84 EC3108.2 35.57,56.84 35.75,56.84 36.06,57.15 36.44,57.15 v1(36.79,57.51) ; 32.86,58.2 v2(32.99,58.2) ; 32.86,58.2 32.86,58.83 31.93,59.76 31.29,59.76 31.18,59.86 31.18,60.16 31.08,60.27 30.17,60.27
  BOTTOM w0.102: v1(36.79,57.51) 37.11,57.19 37.53,57.19 37.84,57.51 37.84,58.14 37.43,58.56 37.43,59.37 37.88,59.82 LOM30.10
LAN_MDI3P: length 17.5
  TOP w0.102: v1(36.79,56.61) 36.79,56.77 36.68,56.89 36.17,56.89 35.85,56.58 35.57,56.58 EC3107.2 34.93,56.59 34.67,56.59 34.54,56.46 34.54,56.2 34.29,55.95 34.03,55.95 33.91,55.83 U3102.4 U3102.7 31.84,55.83 31.72,55.95 31.49,55.95 31.24,56.2 31.24,56.77 32.61,58.13 32.61,58.72 31.82,59.5 31.29,59.5 31.18,59.4 31.18,59.1 31.08,59 30.17,59
  BOTTOM w0.102: v2(37.95,57.07) 37.86,57.16 ; 37.86,57.16 38.1,57.4 38.1,58.24 37.68,58.66 37.68,59.26 37.84,59.42 LOM30.9 ; 37.86,57.16 37.64,56.94 37.12,56.94 v1(36.79,56.61)
LAN_TXN_C_PCH_RXN4: length 3.5
  BOTTOM w0.127: v2(39.36,65.15) 39.23,65.15 ; 39.23,65.15 39.23,65.79 C3016.1 ; 39.23,65.15 39.23,63.63 39.39,63.47 LOM30.18
LAN_TXP_C_PCH_RXP4: length 3.4
  BOTTOM w0.127: C3014.1 38.99,65.69 38.99,64.03 ; 38.99,64.03 LOM30.17 ; 38.99,64.03 v2(38.86,64.03)
LANXIN: length 8.7
  BOTTOM w0.14: v2(50.23,60.9) X3001.1 47.51,60 45.98,60 45.68,60.3 C3001.1 45.13,60.3 44.19,61.23 43.68,61.23 43.46,61.02 LOM30.28
LANXOUT: length 5.4
  BOTTOM w0.14: LOM30.29 43.89,60.62 v2(44.19,60.32) 44.55,59.96 44.55,59.86 45,59.41 C3011.1 46.2,59.41 46.89,58.71 X3001.3
LCD_BRIGHTNESS: length 6.8
  TOP w0.14: v1(37.11,79) 36.79,79.32 36.68,79.32 AFTP5203.1 36.28,80.42 36.64,80.78 36.64,81.3 37.22,81.88 37.22,82.8 37.45,83.03 LCD1.20
  BOTTOM w0.14: RN5201.2 37.7,78.41 v1(37.11,79)
LCD_TST: length 262.3
  TOP w0.102: v1(183.17,37.68) 182.98,37.49 R2417.1 ; v1(61.44,11.04) 61.44,9.21 69.57,1.09 82.59,1.09 82.61,1.07 90.12,1.07 90.51,1.46 163.28,1.46 164.92,3.1 v1(164.92,4.26)
  L3 w0.102: v1(30.13,47.67) 30.13,44.16 28.8,42.83 28.8,36.87 30.19,35.49 35.15,35.49 35.56,35.9 36.51,35.9 37.59,34.81 37.59,27.46 38.6,26.45 41.95,26.45 41.95,26.45 43.13,26.45 50.14,19.44 50.14,18.79 57.88,11.04 v1(61.44,11.04)
  L4 w0.102: v1(164.92,4.26) 167.82,7.15 179.47,7.15 182.46,10.14 182.46,20.59 183.51,21.65 183.51,24.25 183.69,24.43 183.69,26.66 183.41,26.94 183.41,30.57 184.3,31.46 184.3,32.08 183.49,32.89 183.49,37.36 v1(183.17,37.68) ; v1(30.13,47.67) 30.59,47.67 31.13,48.21 31.13,49.32 32.32,50.5 32.32,53.09 32.93,53.7 32.93,55.93 32.24,56.62 32.24,58.55 30.81,59.98 30.81,65.88 29.19,67.51 29.19,71.95 33.94,76.7 39.42,76.7 v1(39.49,76.77)
  BOTTOM w0.102: RN5201.8 39.92,77.76 v2(40.34,77.35) 40.34,76.98 40.13,76.77 v1(39.49,76.77)
LCD_TST_C: length 14.1
  TOP w0.102: v1(43.87,78.95) 43.91,78.99 AFTP5207.1 43.91,80.43 42.45,81.89 LCD1.10
  L4 w0.102: v1(36.95,78.25) 38.04,78.25 38.86,79.06 43.76,79.06 v1(43.87,78.95)
  BOTTOM w0.102: RN5201.1 37.33,77.76 36.96,78.12 36.96,78.24 v1(36.95,78.25)
LCD_TST_EN: length 263.5
  TOP w0.102: v1(58.42,72.61) 58.07,72.96 D5201.2 ; v1(188.37,33.51) 189.04,34.19 189.04,35.03 188.55,35.52 188.55,36.53 188.32,36.76 184.84,36.76 184.4,37.2 183.13,37.2 182.53,36.61 R2417.2 181.57,36.61 v2(181.48,36.69) 181,36.69 179.04,34.74 178.97,34.74 178.93,34.69 178.55,34.69 178.48,34.62 177.76,34.62 KBC24.28
  L4 w0.102: v1(58.42,72.61) 58.42,72.37 58.62,72.16 58.62,71.7 55.53,68.61 55.53,58.34 46.12,48.94 45.8,48.94 41.69,44.83 41.38,44.83 39.43,42.87 38.95,42.87 36.95,40.87 36.95,27.2 47.32,16.84 47.32,12.64 49.73,10.23 53.86,10.23 54.17,10.55 54.53,10.55 54.85,10.23 71.14,10.23 77.93,3.44 105.92,3.44 106.29,3.8 109.45,3.8 110.57,2.68 129.07,2.68 129.88,3.5 129.98,3.5 130.02,3.53 131.92,3.53 132.8,2.65 176.17,2.65 178.6,5.08 178.6,5.09 186.64,13.13 186.64,16.2 187.65,17.21 187.65,18.84 188.47,19.65 188.47,33.41 v1(188.37,33.51)
LCDVDD:
  vias: v2(47.51,75.81)
LCDVDD_EN: length 6.2
  TOP w0.102: D5201.3 54.2,76.29 53.7,76.8 v2(53.24,76.8) R5202.2 50.74,75.82 U5201.1
LDO1_CAP: length 5.1
  TOP w0.203: HDA27.27 31.74,12.14 31.62,12.26 31.61,12.26 31.16,12.72 31.15,12.72
  TOP w0.254: 31.15,12.72 31.1,12.76 v1(30.9,12.76) 30.53,12.76 C2702.2
  BOTTOM w0.254: v1(30.9,12.76) 30.85,12.81 30.05,12.81 v2(29.97,12.9) 29.94,12.92 29.94,13.64 R2711.2
LDO2_CAP: length 5.7
  TOP w0.203: HDA27.39 34.23,7.05 33.46,6.28 33.29,6.28 33.11,6.1
  TOP w0.254: C2712.2 30.8,4.67 31.81,5.67 v2(32.23,5.67) 32.68,5.67 33.11,6.1
LDO3_CAP: length 3
  TOP w0.203: 39.32,10.94 HDA27.7
  TOP w0.254: 39.32,10.94 39.37,10.99 40.29,10.99 40.81,11.52 C2718.1
LED0: length 1.8
  BOTTOM w0.102: TP3003.1 43.57,61.85 43.13,61.42 LOM30.27
LED1: length 7.6
  BOTTOM w0.102: TP3002.1 49.41,62.21 43.47,62.21 43.08,61.82 LOM30.26
LED2: length 6.5
  BOTTOM w0.102: LOM30.25 43.04,62.22 43.24,62.43 47.91,62.43 TP3001.1
LID_CLOSE#: length 282.3
  TOP w0.102: D2401.K 186.74,24.94 186.26,25.43 186.26,26.48 186.54,26.76 187.55,26.76 D2402.K 187.55,27.22 186.54,27.22 186.26,27.5 186.26,28.77 v2(186,29.02) v1(184.99,29.02) ; KBC24.17 176.38,30.1 176.17,30.31 v1(176.17,31.48) ; LIDSW1.3 1.68,72.73 4.02,75.07 9.41,75.07 9.85,74.63 C6401.1 R6401.1 11.58,75.53 v1(10.79,75.53)
  L3 w0.102: v1(176.17,31.48) 176.85,30.8 183.21,30.8 v1(184.99,29.02) ; v1(10.79,75.53) 12.18,75.53 16.81,70.9 24.49,70.9 27.12,68.27 27.12,64.75 31.22,60.65 31.22,59.87 30.72,59.37 30.72,57.45 32.29,55.88 32.29,50.95 31.95,50.61 31.95,45.41 32.22,45.14 32.22,43.9 29.28,40.96 29.28,37.07 30.39,35.97 34.95,35.97 35.36,36.38 35.76,36.38 36.71,36.38 38.08,35.01 38.08,28.34 v1(38.73,27.69)
  L4 w0.102: v1(176.17,31.48) 176.17,29.71 178.07,27.8 178.07,19.95 177.17,19.05 177.17,14.48 170.05,7.36 167.16,7.36 164.04,4.24 154.05,4.24 152.96,3.16 147.07,3.16 145.29,4.94 138.14,4.94 137.53,5.56 131.43,5.56 130.64,4.77 129.64,4.77 129.51,4.64 129.41,4.64 128.59,3.82 111.15,3.82 110.03,4.95 105.81,4.95 105.45,4.58 78.41,4.58 70.67,12.32 66.15,12.32 63.94,14.53 50.96,14.53 38.73,26.76 v1(38.73,27.69)
  BOTTOM w0.102: v1(176.17,31.48) 175.79,31.11 174.83,31.11 174.42,31.52 R2421.1
LINE1-L_C: length 2.4
  TOP w0.254: R2922.1 v2(27.73,16.83) 28.84,16.83 C2907.2
LINE1-L_R: length 2.4
  TOP w0.254: C2908.2 27.87,18.31 v2(27.83,18.34) 27.63,18.55 R2921.1
LINE1_L: length 5.5
  TOP w0.203: 33.89,14.55 33.96,14.55 34.23,14.27 HDA27.22
  TOP w0.254: 33.89,14.55 33.07,14.55 v2(32,15.61) 30.61,17 C2907.1
LINE1_R: length 7
  TOP w0.203: HDA27.21 34.63,14.38 34.22,14.79 33.96,15.05 33.4,15.05
  TOP w0.254: C2908.1 30.94,18.31 v2(31.35,17.89) 31.63,17.61 31.63,16.82 33.4,15.05
LINE1_VREFO_L: length 3.5
  TOP w0.203: HDA27.31 30.66,10.54 v2(30.64,10.52) 30.56,10.6 30.25,10.6 29.7,11.15 R2912.1
LINE1_VREFO_R: length 5.8
  TOP w0.203: HDA27.30 31.14,10.94
  TOP w0.254: 31.14,10.94 31,11.08 30.45,11.08 29.84,11.69 28.73,11.69 v2(28.31,12.11) 28.21,12.22 R2913.1
LOM_TCT: length 19.3
  TOP w0.508: v1(30.85,55.02) 30.54,55.02 30.17,54.65 30.17,53.92
  TOP w0.635: v1(31.69,58.33) 31.08,57.73 30.17,57.73
  L4 w0.508: v1(31.69,58.33) 31.69,56.55 30.85,55.71 v1(30.85,55.02) 31.65,54.22 31.65,50.89 30.62,49.86 30.62,48.45 v1(30.5,48.34)
  BOTTOM w0.508: v1(30.5,48.34) 30.57,48.4 v2(31.19,48.4) 32.01,48.4 C3106.1 ; v1(30.85,55.02) 30.17,54.34 30.17,53.92
  BOTTOM w0.635: 30.17,57.73 31.08,57.73 v1(31.69,58.33)
LPC_AD0: length 122.6
  TOP w0.14: v1(175.07,24.29) 175.07,24.29 175.33,24.03 175.33,22.95 175.29,22.91 KBC24.126 ; v1(150.24,20.48) 150.66,20.06 v2(150.66,19.62) 150.66,16.14 151.22,15.58 154.69,15.58 156.97,17.86 156.97,18.02 157.89,18.93 160.19,18.93 161.22,17.9 162.03,17.9 v1(162.96,16.98) 162.99,16.95 162.99,14.2 RN6501.1
  L3 w0.127: v1(115.42,44.79) 115.25,44.95 115.25,47.98 115.27,48 115.27,49.62 115.29,49.64 115.29,50 115.27,50.02 115.27,52.75 v1(115.19,52.84)
  BOTTOM w0.14: v1(162.96,16.98) 163.69,16.98 166.67,19.96 167.47,19.96 167.68,19.75 171.55,19.75 172.31,20.51 173.86,20.51 175.16,21.8 175.16,22.93 175.15,22.93 175.15,24.21 175.07,24.29 v1(175.07,24.29) ; v1(150.24,20.48) 150.24,21.29 147.64,23.89 147.64,29.27 145.98,30.93 145.98,31.27 145.98,33.92 143.9,36 143.9,40.27 143.25,40.92 143.25,45.01 141.62,46.63 123.61,46.63 121.36,44.38 115.82,44.38 v1(115.42,44.79) ; RN1806.5 113.3,66.09 114.45,64.94 114.45,60.57 116.77,58.25 116.77,56.75 116.48,56.46 116.48,54.69 115.49,53.7 115.49,53.14 v1(115.19,52.84)
LPC_AD1: length 123.8
  TOP w0.14: KBC24.127 175.69,22.93 176.02,23.26 v1(176.02,23.29) ; RN6501.2 162.35,16.28 161.93,16.71 v1(161.93,17) 161.93,17.03 161.48,17.48 161.05,17.48 160.02,18.52 158.21,18.52 v2(157.81,18.12) 154.86,15.16 151.04,15.16 150.24,15.97 150.24,18.84 149.63,19.45 149.63,22.43 v1(149.75,22.55)
  L3 w0.127: v1(114.68,53.77) 115.03,53.77 115.67,53.13 115.67,45.21 v1(116.05,44.83)
  BOTTOM w0.14: v1(116.05,44.83) 120.9,44.83 123.12,47.05 142.01,47.05 143.67,45.39 143.67,41.13 144.32,40.48 144.32,36.17 146.39,34.09 146.39,31.1 148.05,29.44 148.05,24.25 v1(149.75,22.55) ; v1(114.68,53.77) 115.24,54.33 115.24,55.21 115.14,55.3 115.14,57.03 115.6,57.49 115.6,58.19 113.56,60.23 113.56,63.06 112.15,64.47 RN1806.7 ; v1(161.93,17) 161.96,16.97 161.96,16.75 162.6,16.11 164.01,16.11 166.07,18.17 167.58,18.17 168.32,18.91 172.37,18.91 172.62,18.66 173.92,18.66 175.36,20.1 175.36,20.65 175.99,21.29 175.99,23.23 176.02,23.26 v1(176.02,23.29)
LPC_AD2: length 126.6
  TOP w0.14: RN6501.3 161.85,16.16 161.29,16.73 v1(161.29,17.03) 160.91,17.03 159.85,18.1 158.39,18.1 v2(156.95,16.66) 156.95,15.3 156.4,14.74 150.87,14.74 149.66,15.95 v1(149.66,18.58) ; v1(175.86,23.91) 175.94,23.83 176.19,23.83 176.57,23.44 176.57,22.4 176.33,22.15 KBC24.128
  L3 w0.127: v1(114.68,55.49) 113.85,54.67 113.85,48 114.11,47.74 114.11,43.74 v1(114.38,43.47)
  BOTTOM w0.14: v1(175.86,23.91) 175.86,23.89 175.57,23.6 175.57,23.11 175.58,23.1 175.58,21.63 174.93,20.98 174.93,20.31 173.7,19.08 172.8,19.08 172.54,19.33 168.15,19.33 167.43,18.62 165.93,18.62 163.84,16.53 162.77,16.53 162.5,16.79 162.5,17.06 162.12,17.45 161.71,17.45 v1(161.29,17.03) ; v1(114.38,43.47) 114.38,43.36 114.71,43.04 122.07,43.04 124.41,45.38 141.01,45.38 141.97,44.41 141.97,40.36 142.64,39.69 142.64,35.48 144.67,33.45 144.67,31.14 144.67,31.14 144.67,30.37 146.38,28.67 146.38,21.86 v1(149.66,18.58) ; RN1806.8 111.5,64.52 113.12,62.9 113.12,59.95 114.7,58.37 114.7,55.49 114.69,55.49 v1(114.68,55.49)
LPC_AD3: length 125.7
  TOP w0.14: v1(149.18,20.36) 149.21,20.33 149.21,15.81 150.7,14.33 156.6,14.33 v2(157.25,14.98) 157.45,15.18 157.45,16.54 158.58,17.68 159.6,17.68 160.24,17.04 v1(160.24,16.89) 161.2,15.92 RN6501.4 ; KBC24.1 v1(177.64,23.19)
  L3 w0.127: v1(116.33,43.5) 116.54,43.71 116.54,45.48 116.07,45.94 116.07,53.61 115.59,54.09 v1(115.59,55.49)
  BOTTOM w0.14: v1(177.64,23.19) 176.83,22.38 176.83,19.87 176.42,19.46 175.91,19.46 173.99,17.54 170.53,17.54 170.3,17.77 169.51,17.77 168.88,17.13 166.28,17.13 164.42,15.27 161.82,15.27 160.27,16.83 160.27,16.85 v1(160.24,16.89) ; v1(116.33,43.5) 121.8,43.5 124.09,45.79 141.24,45.79 142.39,44.64 142.39,40.53 143.06,39.86 143.06,35.65 145.09,33.62 145.09,30.97 145.09,30.97 145.09,30.55 146.8,28.84 146.8,22.74 v1(149.18,20.36) ; v1(115.59,55.49) 115.63,55.53 115.63,56.21 116.35,56.93 116.35,58.07 114.02,60.4 114.02,63.19 112.65,64.56 RN1806.6
LPC_FRAME#: length 31.7
  TOP w0.14: v1(175.74,25.32) 176.19,25.32 176.68,24.83 176.68,24.71 176.9,24.5 KBC24.3 ; v1(159.04,16.79) 159.2,16.63 159.2,15.82 v2(159.28,15.74) 159.28,15.39 159.83,14.84 R1801.1 160.22,14 R6501.1
  BOTTOM w0.14: v1(159.04,16.79) 159.14,16.79 159.69,17.34 160.42,17.34 160.84,16.92 160.84,16.85 161.99,15.69 164.18,15.69 166.04,17.55 168.7,17.55 169.64,18.49 172.2,18.49 172.45,18.24 174.1,18.24 175.78,19.92 175.78,20.48 176.41,21.11 176.41,22.55 176.68,22.82 176.68,23.81 176.7,23.83 176.7,24.2 175.74,25.16 v1(175.74,25.32)
LPC_FRAME#_DEBUG: length 4.9
  TOP w0.14: v1(159.72,11.43) 159.51,11.65 v2(159.51,12.34) 159.51,12.39 R6501.2
  BOTTOM w0.14: v1(159.72,11.43) 159.72,11.69 159.72,11.69 DB1.6
LPC_LAD0_PCH: length 7.9
  BOTTOM w0.089: CPU1.AU14 111.17,73.04 111.5,73.37 112.05,73.37 112.21,73.53 112.76,73.53 112.91,73.39 112.91,71.46 112.99,71.39 112.99,70.76 113.2,70.55
  BOTTOM w0.14: RN1806.4 113.3,68.53 113.39,68.62 113.39,70.35 113.2,70.55
LPC_LAD0_R: length 6.2
  TOP w0.14: RN6501.8 163.02,13.23 163.8,13.23 v2(163.95,13.07) 163.95,11.79 v1(163.58,11.42)
  BOTTOM w0.14: v1(163.58,11.42) 163.58,12.2 164.72,13.35 DB1.2
LPC_LAD1_PCH: length 4.2
  BOTTOM w0.089: CPU1.AW12 112.09,71.42 112.09,70.17
  BOTTOM w0.14: RN1806.2 112.15,68.61 111.94,68.83 111.94,70.02 112.09,70.17
LPC_LAD1_R: length 5.2
  TOP w0.14: RN6501.7 162.35,12.77 162.99,12.13 v2(162.99,12.06) 162.99,11.54 v1(162.87,11.43)
  BOTTOM w0.14: v1(162.87,11.43) 162.91,11.46 162.91,12.64 163.47,13.2 DB1.3
LPC_LAD2_PCH: length 3.4
  BOTTOM w0.14: CPU1.AY12 111.77,70.52 111.45,70.2 v2(111.45,69.21) 111.45,68.55 111.5,68.49 111.5,67.84 RN1806.1
LPC_LAD2_R: length 4.8
  TOP w0.14: RN6501.6 161.85,12.77 161.77,12.69 v2(161.77,12.13) 161.77,11.89 v1(162.22,11.43)
  BOTTOM w0.14: v1(162.22,11.43) 162.22,11.44 DB1.4
LPC_LAD3_PCH: length 4.3
  BOTTOM w0.089: CPU1.AW11 112.73,71.53 112.73,71.39 112.81,71.31 112.81,70.62 113.12,70.3 113.12,69.97 113.1,69.94 112.78,69.63
  BOTTOM w0.14: RN1806.3 112.65,69.19 v2(112.67,69.21) 112.67,69.52 112.78,69.63
LPC_LAD3_R: length 5.8
  TOP w0.14: RN6501.5 160.65,12.66 160.65,11.57 v2(160.7,11.52) 160.78,11.44 v1(161.5,11.44)
  BOTTOM w0.14: DB1.5 160.97,11.97 v1(161.5,11.44)
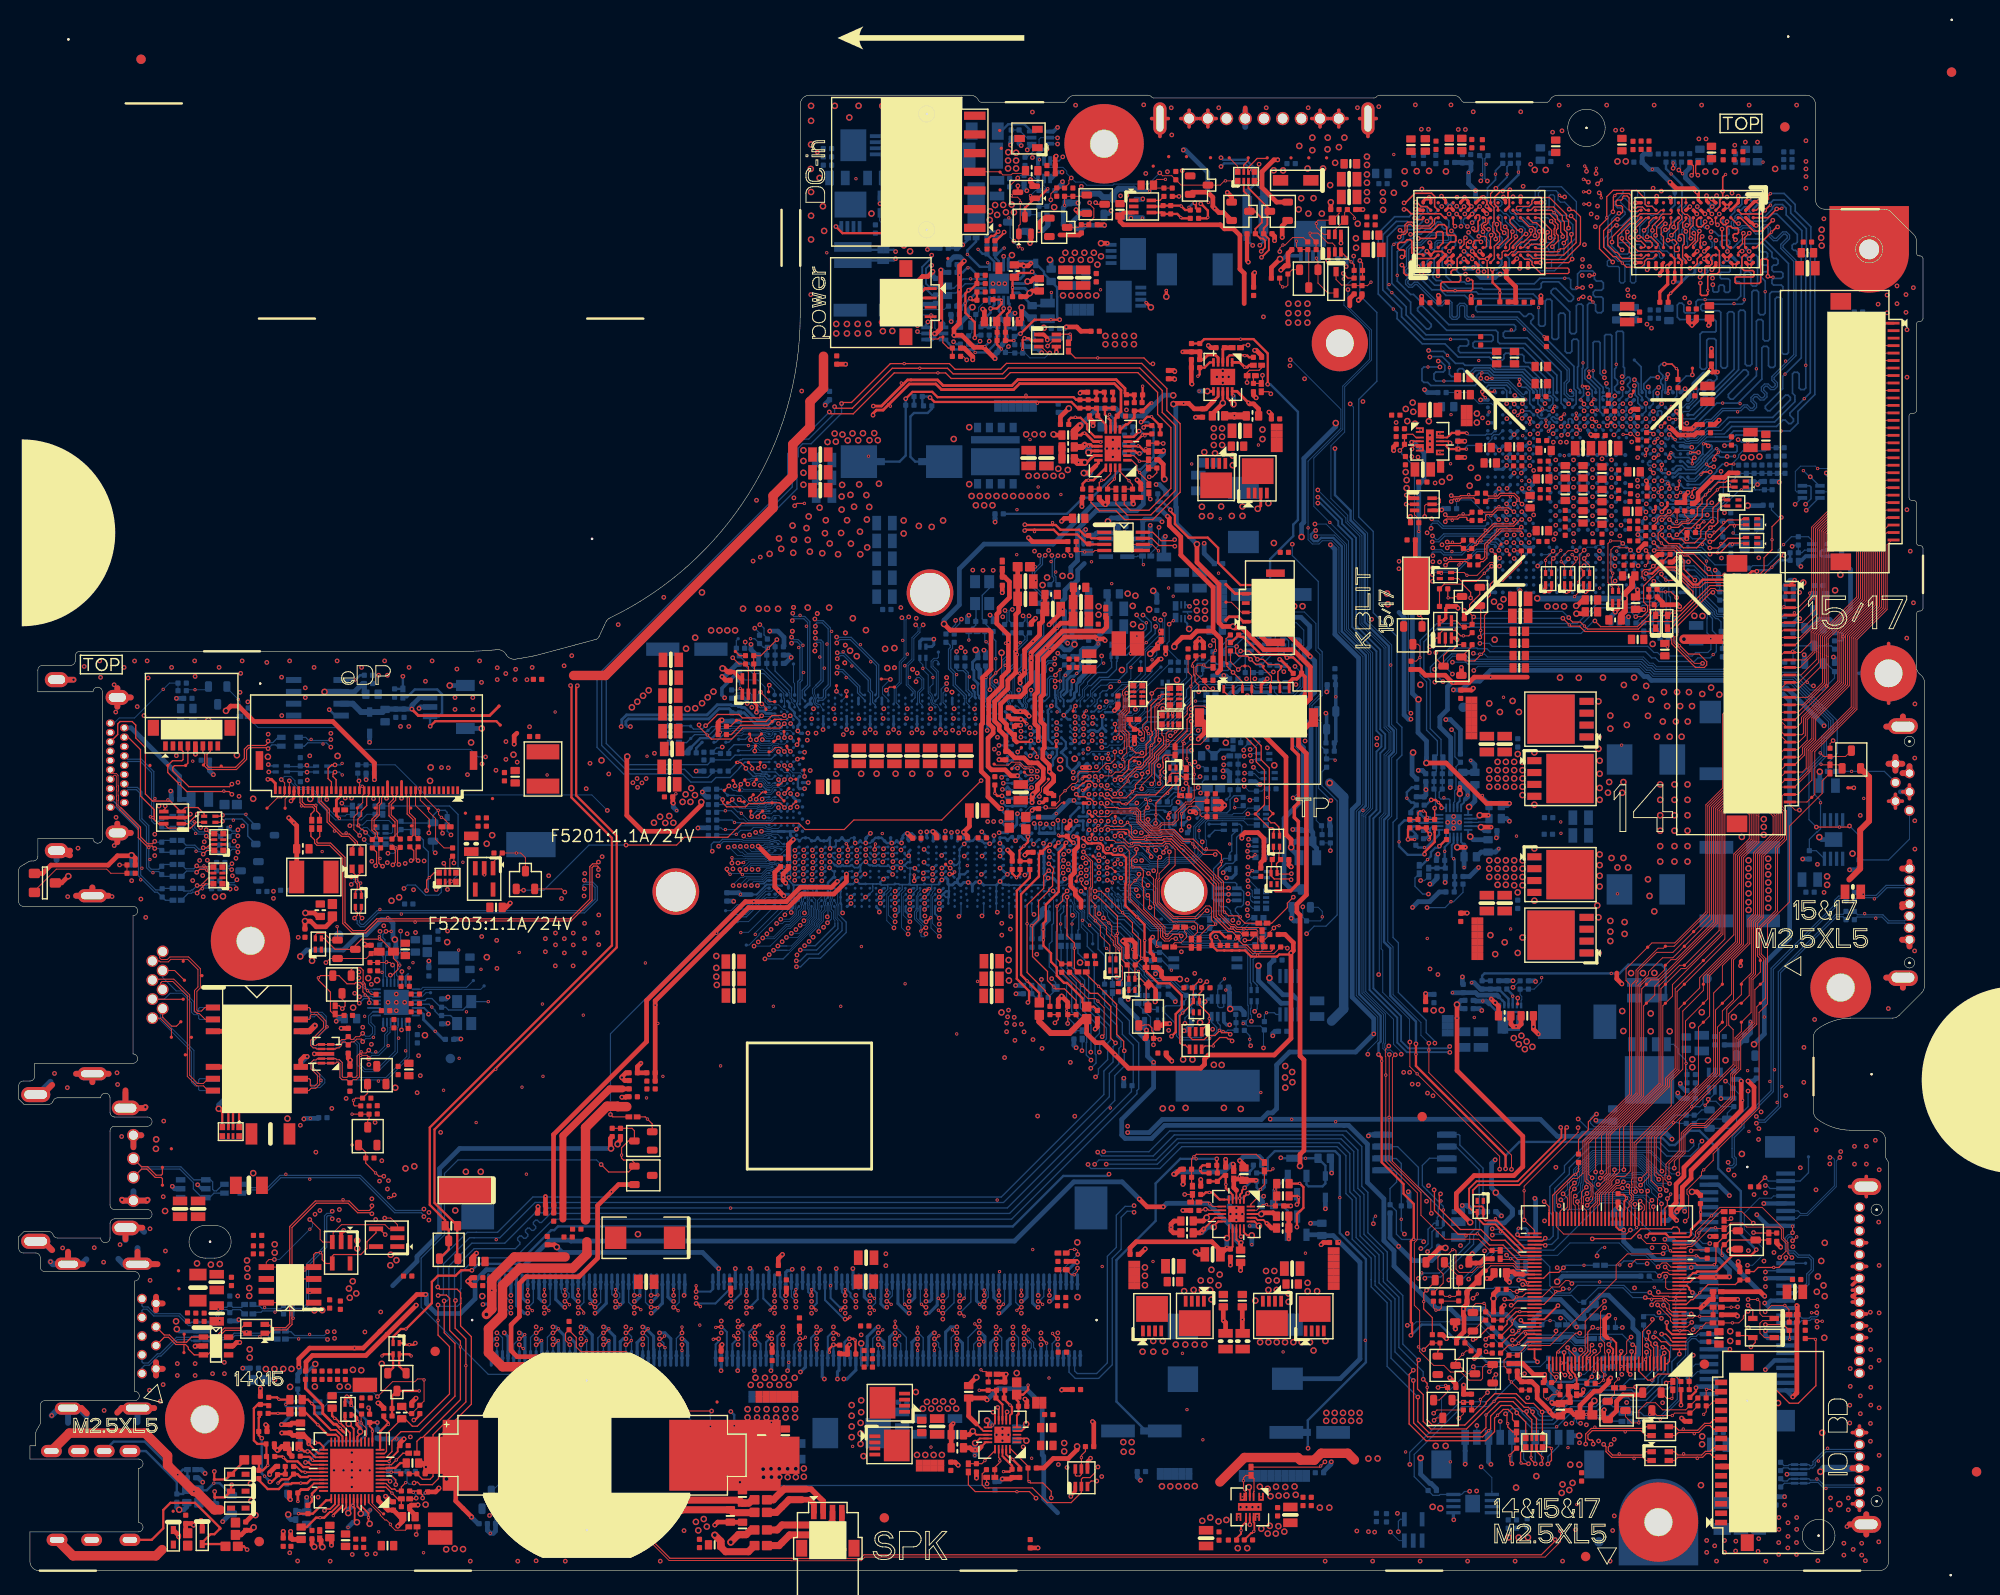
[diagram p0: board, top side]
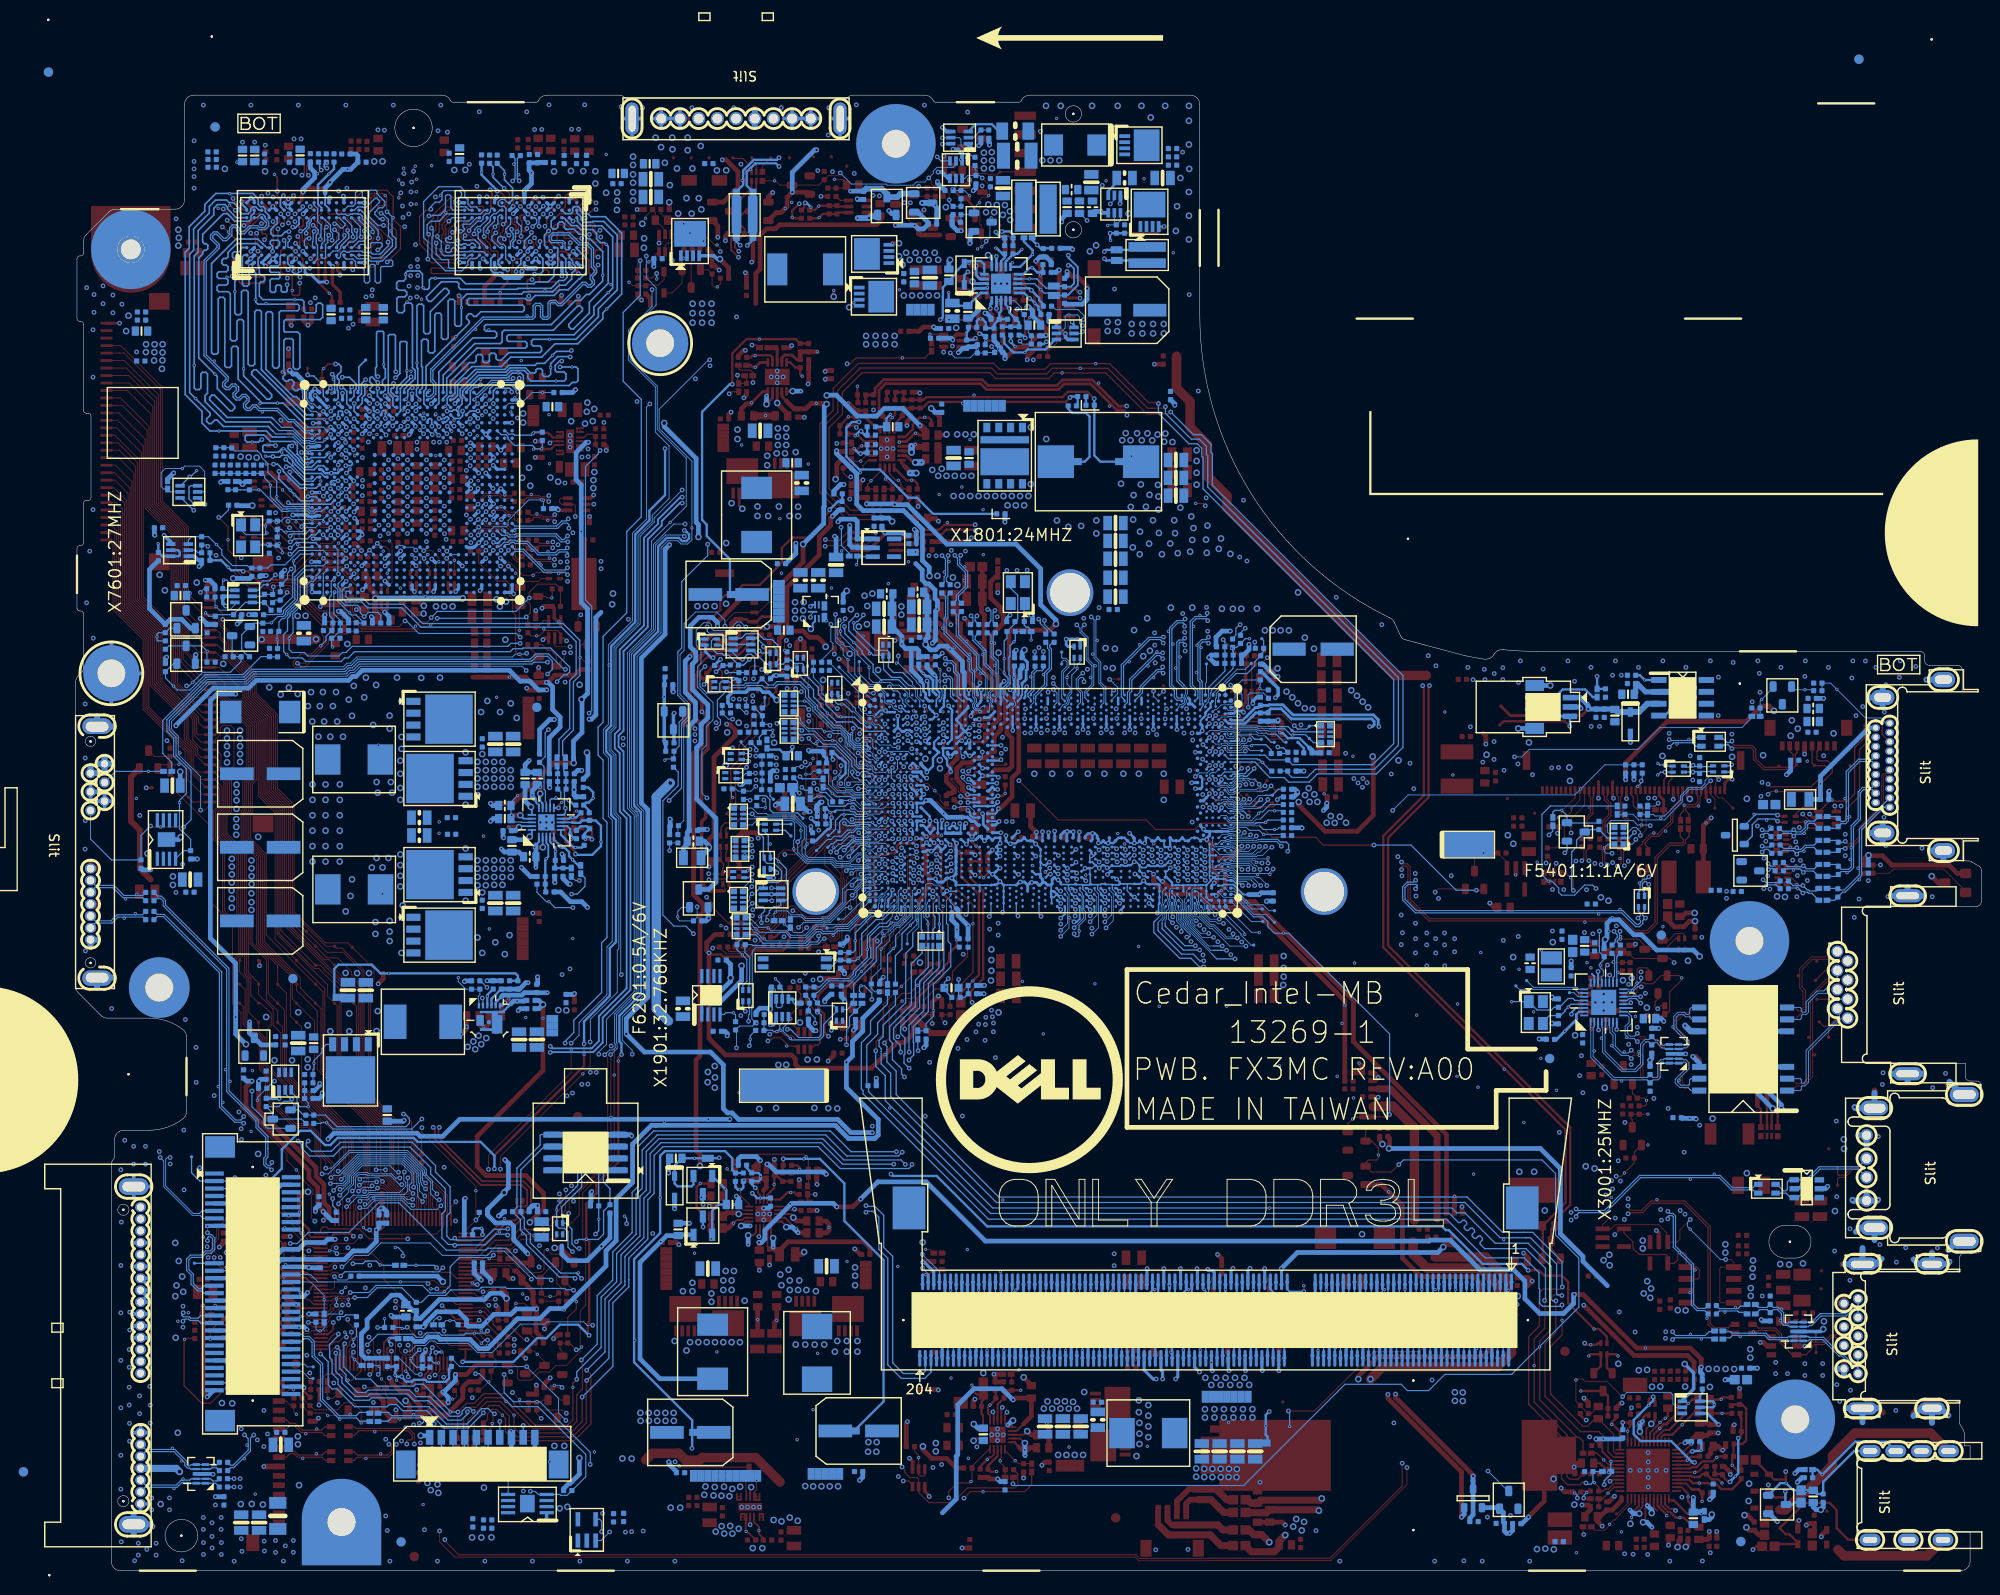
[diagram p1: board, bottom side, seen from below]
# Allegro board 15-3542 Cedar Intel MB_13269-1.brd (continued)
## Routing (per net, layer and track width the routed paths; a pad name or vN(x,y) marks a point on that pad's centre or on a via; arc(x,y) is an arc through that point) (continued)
LPC_LFRAME#_PCH: length 108.2
  TOP w0.14: R1801.2 159.79,16.17 159.79,16.79 159.31,17.26 158.81,17.26 v2(158.19,16.63) 157.87,16.31 157.87,14.87 156.9,13.91 150.52,13.91 148.73,15.7 148.73,21 v1(149.18,21.45)
  L3 w0.127: v1(114.7,54.64) 114.23,54.18 114.23,48.16 114.74,47.65 114.74,44.77 115.09,44.42 v1(115.09,43.49)
  BOTTOM w0.089: CPU1.AV12 111.49,72.14 111.49,70.87 111.09,70.47 111.09,69.02
  BOTTOM w0.14: v1(114.7,54.64) 114.7,54.68 114.2,55.19 114.2,56.5 114.24,56.55 114.24,58.21 112.63,59.82 112.63,62.8 110.97,64.46 110.97,68.35 111.09,68.48 111.09,69.02 ; v1(149.18,21.45) 147.22,23.41 147.22,29.09 145.51,30.8 145.51,33.79 144.28,35.02 143.48,35.82 143.48,40.05 142.81,40.72 142.81,44.86 141.45,46.21 123.92,46.21 121.66,43.95 115.56,43.95 v1(115.09,43.49)
LPSS_GSPI0_MOSI_BBS0_R: length 13.2
  TOP w0.102: R2012.2 111,82.06 111.36,82.42 111.36,82.89 v2(111.93,83.47) 112.7,84.24 113.04,84.24 113.31,84.5 113.31,85.31 113.5,85.5 115.41,85.5 116.29,86.38 116.81,86.38 117.25,86.82 v1(117.25,87.63)
  BOTTOM w0.102: CPU1.L8 114.47,87.38 114.78,87.68 117.2,87.68 v1(117.25,87.63)
LPSS_SDIO_D0_CMNHDR: length 9.3
  BOTTOM w0.089: CPU1.D3 117.93,91.34 118.37,91.34 118.56,91.53 119.11,91.53 119.31,91.72 119.55,91.72 119.89,92.06 119.89,92.22
  BOTTOM w0.102: 119.89,92.22 120.09,92.43 120.09,94.05 123.21,97.17 R2011.2
M_A_A0: length 58.5
  TOP w0.216: v1(96.9,72.74) 97.11,72.74 97.36,72.99 v2(97.41,72.99)
  L4 w0.089: 96.81,64.04 96.81,64.69 96.46,65.04 96.46,72.3 v1(96.9,72.74)
  L4 w0.216: 96.81,64.04 96.81,51.84 93.16,48.18 93.16,45.46 82.23,34.54 82.23,33.63 81.67,33.07 81.67,30.75 81.42,30.5 81.42,27.18 82.26,26.34 82.26,24.64 81.8,24.18 v1(81.75,24.18)
  BOTTOM w0.216: v1(96.9,72.74) 97.19,73.04 CPU1.AU36 ; v1(81.75,24.18) 81.75,24.18 81.75,22.72 DM1.98
M_A_A1: length 60.1
  TOP w0.216: v1(97.05,69.44) 97.11,69.44 v2(97.56,69.89)
  L4 w0.089: 97.38,64.36 97.38,64.65 96.64,65.4 96.64,69.02 v1(97.05,69.44)
  L4 w0.216: 97.38,64.36 97.38,51.58 96.67,50.87 96.67,50.56 97.31,49.92 97.31,49.74 96.88,49.31 96.7,49.31 96.05,49.95 95.75,49.95 95.44,49.64 95.44,49.34 96.43,48.34 96.43,48.04 96.12,47.73 95.82,47.73 94.83,48.72 94.52,48.72 94.22,48.42 94.22,48.11 95.21,47.12 95.21,46.81 94.9,46.51 94.59,46.51 94.34,46.76 94.05,46.76 93.73,46.44 93.73,46.15 93.98,45.89 93.98,45.48 82.8,34.3 82.8,33.39 82.79,33.38 82.79,33.32 82.25,32.79 82.25,32.05 82.54,31.76 82.54,29.24 82.12,28.82 v1(82.05,28.82)
  BOTTOM w0.203: CPU1.AY37 96.44,71.06 96.44,69.76 96.76,69.44 v1(97.05,69.44)
  BOTTOM w0.216: DM1.97 81.45,29.33 81.95,28.82 v1(82.05,28.82)
M_A_A2: length 60.5
  TOP w0.216: v1(95.79,73.82) v2(95.79,74.45)
  L4 w0.089: 95.1,64.81 95.1,65 95.9,65.8 95.9,73.62 95.79,73.74 v1(95.79,73.82)
  L4 w0.216: v1(81.75,25.45) 81.69,25.45 81.23,25.92 81.23,26.36 79.56,28.02 79.56,31.88 79.55,31.89 79.55,34.28 87.16,41.89 87.16,44.61 95.1,52.55 95.1,64.81
  BOTTOM w0.216: CPU1.AR38 96.16,74.2 v1(95.79,73.82) ; v1(81.75,25.45) 81.49,25.45 81.15,25.11 DM1.96
M_A_A3: length 61.4
  TOP w0.216: v1(80.85,29.46) v2(80.85,30.09)
  L4 w0.089: v1(96.76,74.66) 97.17,74.26 97.17,73.58 96.26,72.67 96.26,64.42 96.24,64.4
  L4 w0.216: v1(80.85,29.46) 80.85,31.65 81.1,31.9 81.1,34.22 90.31,43.42 90.31,43.76 89.39,44.67 89.39,44.96 89.72,45.29 90.01,45.29 90.92,44.37 91.23,44.37 91.53,44.68 91.53,44.98 90.49,46.02 90.49,46.33 90.8,46.64 91.11,46.64 91.94,45.8 92.23,45.8 92.56,46.12 92.56,46.41 91.72,47.25 91.72,47.55 96.24,52.07 96.24,64.4
  BOTTOM w0.216: DM1.95 v1(80.85,29.46) ; v1(96.76,74.66) 96.95,74.85 CPU1.AP36
M_A_A4: length 59.7
  TOP w0.216: v1(80.55,24.82) 80.41,24.96 80.26,24.96 v2(80.08,25.14)
  L4 w0.089: 94.53,64.81 94.53,64.94 95.72,66.14 95.72,72.34 v1(95.32,72.74)
  L4 w0.216: v1(80.55,24.82) 79.96,24.82 79.81,24.96 79.81,26.96 78.99,27.78 78.99,31.64 78.98,31.65 78.98,34.52 86.59,42.13 86.59,44.85 94.53,52.78 94.53,64.81
  BOTTOM w0.216: DM1.92 79.95,24.45 80.3,24.8 80.53,24.8 v1(80.55,24.82) ; CPU1.AU39 95.62,73.04 v1(95.32,72.74)
M_A_A5: length 60
  TOP w0.216: v1(80.85,28.19) 80.67,28.19 v2(80.36,27.88)
  L4 w0.089: v1(96.77,74.01) 96.77,73.58 96.08,72.89 96.08,65.41 95.67,65 95.67,64.81
  L4 w0.216: v1(80.85,28.19) 80.79,28.19 80.28,28.7 80.28,31.89 80.53,32.14 80.53,34.45 88.17,42.1 88.17,42.41 87.73,42.85 87.73,43.14 88.06,43.46 88.34,43.46 88.78,43.02 89.09,43.02 89.4,43.33 89.4,43.63 88.35,44.68 88.35,44.99 95.67,52.31 95.67,64.81
  BOTTOM w0.216: CPU1.AR36 96.95,74.2 v1(96.77,74.01) ; DM1.91 79.65,29.12 80.58,28.19 v1(80.85,28.19)
M_A_A6: length 60
  TOP w0.216: v2(78.28,25.14) 78.6,24.82 v1(78.75,24.82)
  L4 w0.089: 93.95,64.81 93.95,64.99 95.55,66.58 95.55,69.23 v1(95.32,69.45)
  L4 w0.216: 93.95,64.81 93.95,53.02 86.02,45.08 86.02,42.36 78.41,34.76 78.41,33.46 78.18,33.23 77.95,33.23 77.74,33.02 77.74,32.1 78,31.83 78.24,31.83 78.41,31.67 78.41,31.41 78.42,31.4 78.42,27.15 78.66,26.92 79.02,26.92 79.24,26.7 79.24,24.96 79.1,24.82 v1(78.75,24.82)
  BOTTOM w0.089: v1(95.32,69.45) 94.61,70.16 94.61,72.1 CPU1.AV40
  BOTTOM w0.216: DM1.90 79.35,24.27 78.81,24.82 v1(78.75,24.82)
M_A_A7: length 59.7
  TOP w0.216: v1(78.75,26.09) 78.92,26.09 79.14,26.31 v2(79.27,26.31)
  L4 w0.089: 92.24,64.81 92.24,65.16 94.56,67.47 94.56,70.67 v1(95.32,71.43)
  L4 w0.216: 92.24,64.81 92.24,53.73 79.02,40.51 79.02,37.79 75.59,34.37 75.59,31.8 76.69,30.71 76.69,28.02 78.63,26.09 v1(78.75,26.09)
  BOTTOM w0.216: CPU1.AW39 95.62,71.74 95.52,71.63 95.51,71.63 95.33,71.44 95.33,71.43 v1(95.32,71.43) ; DM1.86 78.15,25.54 78.69,26.09 v1(78.75,26.09)
M_A_A8: length 59.6
  TOP w0.216: v2(78.43,28.14) 78.38,28.19 v1(77.85,28.19)
  L4 w0.089: 92.81,64.81 92.81,65.12 94.74,67.04 94.74,70.16 v1(95.32,70.74)
  L4 w0.216: 92.81,64.81 92.81,53.49 81.33,42.01 81.33,41.71 81.81,41.23 81.81,40.94 81.48,40.62 81.19,40.62 80.72,41.09 80.41,41.09 80.1,40.79 80.1,40.48 81.14,39.44 81.14,39.14 80.83,38.83 80.53,38.83 80.2,39.16 79.92,39.16 79.59,38.83 79.59,38.55 79.92,38.22 79.92,37.88 76.17,34.13 76.17,32.04 77.28,30.93 77.28,28.7 77.79,28.19 v1(77.85,28.19)
  BOTTOM w0.216: CPU1.AY39 95.66,71.09 v1(95.32,70.74) ; v1(77.85,28.19) 78.2,28.19 79.05,29.04 DM1.89
M_A_A9: length 61
  TOP w0.216: v1(77.85,29.46) v2(77.85,30.09)
  L4 w0.089: 93.38,64.81 93.38,65.08 95.14,66.84 v1(95.14,68.13)
  L4 w0.216: 93.38,64.81 93.38,53.26 84.82,44.69 84.82,44.39 85.42,43.79 85.42,43.5 85.09,43.17 84.81,43.17 84.2,43.77 83.9,43.77 83.59,43.47 83.59,43.16 84.61,42.14 84.61,41.84 84.31,41.53 84,41.53 82.98,42.55 82.67,42.55 82.37,42.24 82.37,41.94 83.39,40.92 83.39,40.61 83.08,40.3 82.78,40.3 82.55,40.53 82.26,40.53 81.93,40.21 81.93,39.92 82.16,39.69 82.16,39.32 77.16,34.32 77.16,31.85 77.85,31.16 v1(77.85,29.46)
  BOTTOM w0.089: CPU1.AU40 94.85,72.84 94.43,72.43 94.43,68.82 95.12,68.13 v1(95.14,68.13)
  BOTTOM w0.216: DM1.85 v1(77.85,29.46)
M_A_A10: length 60
  TOP w0.216: v1(84.81,29.46) v2(84.81,30.09)
  L4 w0.091: v1(97.76,74.52) 97.36,74.13 97.36,72.46 98.07,71.75 98.07,70.91 98.07,70.91 98.07,70.57 98.07,70.57 98.07,67.61 99.09,66.59
  L4 w0.216: 99.09,66.59 99.5,66.18 99.5,46.85 94.25,41.59 94.25,41.29 94.77,40.76 94.77,40.46 94.46,40.15 94.16,40.15 93.63,40.67 93.33,40.67 93.02,40.37 93.02,40.06 93.54,39.54 93.54,39.23 93.24,38.92 92.93,38.92 92.41,39.45 92.1,39.45 91.79,39.14 91.79,38.84 92.15,38.48 92.15,38.19 91.82,37.87 91.54,37.87 91.18,38.22 90.88,38.22 85.13,32.48 85.13,31.81 84.94,31.62 84.94,29.59 v1(84.81,29.46)
  BOTTOM w0.216: CPU1.AP35 97.84,74.52 v1(97.76,74.52) ; v1(84.81,29.46) 84.45,29.82 DM1.107
M_A_A11: length 60.1
  TOP w0.216: v2(77.47,26.31) 77.34,26.31 77.12,26.09 v1(76.95,26.09)
  L4 w0.089: v1(93.74,71.43) 94.2,70.97 94.2,68.27 91.1,65.17 91.1,64.81
  L4 w0.216: 91.1,64.81 91.1,54.21 76.18,39.28 76.18,36.57 73.82,34.21 73.82,31.89 74.92,30.78 74.92,28.75 76.35,27.32 76.35,26.63 76.89,26.09 v1(76.95,26.09)
  BOTTOM w0.216: CPU1.AW41 93.84,71.43 v1(93.74,71.43) ; DM1.84 77.55,22.72 77.55,25.54 77.01,26.09 v1(76.95,26.09)
M_A_A12: length 59.6
  TOP w0.216: v2(75.66,28.54) 75.92,28.8 76.14,28.8 v1(76.17,28.82)
  L4 w0.089: 91.67,64.81 91.67,65.15 94.38,67.87 94.38,72.08 v1(93.75,72.71)
  L4 w0.216: v1(76.17,28.82) 76.12,28.82 75.68,29.26 75.68,30.83 74.39,32.12 74.39,33.97 77.79,37.37 77.79,37.7 76.75,38.74 76.75,39.05 77.05,39.35 77.36,39.35 77.81,38.9 78.1,38.9 78.42,39.23 78.42,39.52 77.97,39.97 77.97,40.27 91.67,53.97 91.67,64.81
  BOTTOM w0.216: v1(93.75,72.71) 93.87,72.71 94.19,73.04 CPU1.AU41 ; v1(76.17,28.82) 76.43,28.82 77.25,29.64 DM1.83
M_A_A13: length 59.8
  TOP w0.216: v1(88.41,29.46) v2(88.41,30.09)
  L4 w0.216: v1(97.76,73.87) 97.76,73.47 97.94,73.3 98.93,73.3 100.45,71.78 101.42,71.78 102.55,70.65 102.55,69.87 102.93,69.49 102.93,43.72 102.62,43.41 102.31,43.41 101.8,43.93 101.49,43.93 101.18,43.62 101.18,43.32 101.7,42.8 101.7,42.49 93.61,34.4 92.09,34.4 91.03,33.34 91.03,32.88 91.28,32.63 91.28,32.07 89.9,30.69 89.28,30.69 88.41,29.82 v1(88.41,29.46)
  BOTTOM w0.216: DM1.119 88.05,29.82 v1(88.41,29.46) ; v1(97.76,73.87) 97.84,73.87 CPU1.AR35
M_A_A14: length 61.3
  TOP w0.216: v1(76.95,24.82) 76.8,24.82 v2(76.48,25.14)
  L4 w0.089: v1(93.75,69.44) 94.02,69.16 94.02,68.58 90.53,65.08 90.53,64.81
  L4 w0.216: v1(76.95,24.82) 76.89,24.82 75.78,25.93 75.78,27.08 74.21,28.65 74.21,30.69 73.24,31.65 73.24,34.44 75.6,36.8 75.6,39.52 90.53,54.44 90.53,64.81
  BOTTOM w0.089: v1(93.75,69.44) 93.03,70.15 93.03,72.1 CPU1.AV42
  BOTTOM w0.216: DM1.80 76.35,24.27 76.89,24.82 v1(76.95,24.82)
M_A_A15: length 61.4
  TOP w0.216: v1(75.15,26.09) 74.62,26.09 v2(74.57,26.03)
  L4 w0.089: v1(93.62,68.79) 89.95,65.12 89.95,64.81
  L4 w0.216: 89.95,64.81 89.95,54.68 75.03,39.76 75.03,37.04 72.67,34.68 72.67,31.41 73.61,30.48 73.61,27.57 75.09,26.09 v1(75.15,26.09)
  BOTTOM w0.089: CPU1.AU42 93.27,72.85 92.86,72.44 92.86,69.56 v1(93.62,68.79)
  BOTTOM w0.216: DM1.78 75.75,22.93 75.75,25.54 75.21,26.09 v1(75.15,26.09)
M_A_B_DIMM_ODT: length 68.6
  TOP w0.508: Q1202.S 64.17,41.32 v2(63.4,40.55) 61.92,39.07 61.92,33.45 59.93,31.45 54.26,31.45 53.56,30.75 53.56,27.2 52.67,26.32 52.67,23.54 53.32,22.9 64.55,22.9 66.64,20.81 v3(66.64,20.5) ; v1(88.86,24.18) 88.66,23.98 R1207.1 87.89,23.18 R1206.1
  L3 w0.508: v3(66.64,20.5) 69.69,23.55 88.22,23.55 v1(88.86,24.18)
M_A_BS0: length 60.6
  TOP w0.216: v1(84.81,28.19) 84.99,28.19 v2(85.29,27.88)
  L4 w0.216: v1(98.47,67.88) 98.55,67.96 99.41,67.96 100.08,67.3 100.08,46.58 96.45,42.95 96.45,42.65 96.98,42.12 96.98,41.81 96.67,41.5 96.37,41.5 95.84,42.03 95.53,42.03 95.22,41.73 95.22,41.42 95.75,40.89 95.75,40.59 92.43,37.26 90.83,37.26 86.3,32.73 86.3,31.95 85.51,31.15 85.51,28.24 85.3,28.03 84.96,28.03 v1(84.81,28.19)
  BOTTOM w0.089: v1(98.47,67.88) 97.58,68.78 97.58,72.29 97.76,72.46 97.76,72.61 98,72.85 CPU1.AU35
  BOTTOM w0.216: DM1.109 85.05,30.04 85.37,29.72 85.37,28.62 84.94,28.19 v1(84.81,28.19)
M_A_BS1: length 61
  TOP w0.216: v2(85.82,25.77) 85.5,25.45 v1(85.35,25.45)
  L4 w0.216: v1(98.47,68.53) 98.61,68.67 99.51,68.67 100.65,67.54 100.65,46.34 97.55,43.25 97.55,41.57 92.66,36.69 91.07,36.69 86.87,32.5 86.87,31.71 86.09,30.93 86.09,27.79 85.87,27.58 85.66,27.58 85.44,27.36 85.44,26.93 85.66,26.71 85.87,26.71 86.09,26.5 86.09,25.75 85.79,25.45 v1(85.35,25.45)
  BOTTOM w0.089: CPU1.AV35 97.77,72.11 97.77,71.97 97.76,71.96 97.76,69.25 v1(98.47,68.53)
  BOTTOM w0.216: v1(85.35,25.45) 85.29,25.45 84.75,24.91 DM1.108
M_A_BS2: length 58.2
  TOP w0.216: v1(72.46,28.6) 72.59,28.6 72.92,28.27 v2(72.92,28.26)
  L4 w0.089: 89.38,64.81 89.38,65.16 93.34,69.12 93.34,69.68 v1(93.75,70.09)
  L4 w0.216: v1(72.46,28.6) 72.54,28.52 72.84,28.52 73.03,28.71 73.03,30.24 72.1,31.18 72.1,34.92 74.46,37.28 74.46,39.99 89.38,54.92 89.38,64.81
  BOTTOM w0.216: v1(93.75,70.09) 94.19,70.53 94.19,71.04 CPU1.AY41 ; DM1.79 76.05,30.12 74.53,28.6 v1(72.46,28.6)
M_A_CAS#: length 60.6
  TOP w0.216: v2(87.92,27.88) 88.23,28.19 v1(88.41,28.19)
  L4 w0.216: v1(88.41,28.19) 88.34,28.19 87.83,28.69 87.83,30.05 89.05,31.27 89.67,31.27 90.29,31.89 90.29,33.41 91.86,34.97 93.37,34.97 99.64,41.24 99.64,41.55 99.43,41.76 99.43,42.05 99.76,42.37 100.05,42.37 100.26,42.16 100.56,42.16 100.89,42.48 100.89,42.77 100.51,43.15 100.51,43.77 102.36,45.63 102.36,69.25 101.98,69.63 101.98,70.41 101.18,71.21 100.17,71.21 98.64,72.74 v1(98.47,72.74)
  BOTTOM w0.216: v1(88.41,28.19) 87.83,28.19 86.85,29.17 DM1.115 ; CPU1.AU34 98.62,72.74 v1(98.47,72.74)
M_A_DIMA_CKE0: length 60.3
  TOP w0.216: v1(72.46,29.87) v2(72.46,30.49)
  L4 w0.089: 88.81,64.81 88.81,65.03 93.04,69.26 93.04,72.14 92.49,72.69 v1(92.16,72.69)
  L4 w0.216: 88.81,64.81 88.81,55.19 73.08,39.46 73.08,39.16 73.86,38.38 73.86,38.09 73.53,37.76 73.25,37.76 72.48,38.53 72.19,38.53 71.87,38.21 71.87,37.92 72.8,36.99 72.8,36.7 72.47,36.37 71.84,36.37 71.53,36.07 71.53,30.68 72.34,29.87 v1(72.46,29.87)
  BOTTOM w0.216: v1(92.16,72.69) 92.16,72.71 92.48,73.04 CPU1.AU43 ; v1(72.46,29.87) 73.99,29.87 74.25,30.12 DM1.73
M_A_DIMA_CKE1: length 60.6
  TOP w0.216: v1(74.88,24.82) 74.35,24.82 v2(74.29,24.76)
  L4 w0.089: 88.24,64.81 88.24,64.97 92.46,69.19 92.46,71.13 v1(92.17,71.42)
  L4 w0.216: 88.24,64.81 88.24,55.43 70.96,38.15 70.96,30.44 71.87,29.53 71.87,28.03 74.88,25.03 v1(74.88,24.82)
  BOTTOM w0.216: DM1.74 74.55,24.22 74.88,24.54 v1(74.88,24.82) ; CPU1.AW43 92.26,71.42 v1(92.17,71.42)
M_A_DIMA_CLK_DDR0: length 63.1
  TOP w0.127: v1(97.04,68.8) 96.85,68.8 v2(96.49,68.44)
  L4 w0.089: v1(97.04,68.8) 97.44,68.4 97.44,66.97 97.37,66.9 97.37,66.43 97.39,66.41 97.39,66.39
  L4 w0.114: v1(83.13,28.82) 83.57,29.26 83.57,30.18 83.46,30.29 83.46,32.77 83.7,33.01 83.7,34.07 83.97,34.34 84.13,34.34 84.39,34.08 84.74,34.08 85.08,34.42 85.08,34.77 84.82,35.03 84.82,35.19 85.03,35.4 85.19,35.4 85.45,35.14 85.8,35.14 86.14,35.48 86.14,35.84 85.88,36.09 85.88,36.25 86.09,36.46 86.25,36.46 86.51,36.2 86.86,36.2 87.2,36.54 87.2,36.9 86.94,37.15 86.94,37.31 87.15,37.52 87.31,37.52 87.57,37.26 87.92,37.26 88.26,37.61 88.26,37.96 88.01,38.21 88.01,38.37 88.21,38.58 88.37,38.58 88.63,38.32 88.98,38.32 89.32,38.67 89.32,39.02 89.07,39.27 89.07,39.43 89.27,39.64 89.43,39.64 89.69,39.38 90.04,39.38 90.38,39.73 90.38,40.08 90.13,40.33 90.13,40.49 90.33,40.7 90.49,40.7 90.75,40.45 91.1,40.45 91.44,40.79 91.44,41.14 91.19,41.39 91.19,41.55 91.49,41.86 91.65,41.86 91.87,41.63 92.28,41.63 92.57,41.92 92.57,42.32 92.34,42.55 92.34,42.71 97,47.36 97.16,47.36 97.37,47.15 97.74,47.15 98.06,47.47 98.06,47.84 97.85,48.06 97.85,48.22 98.18,48.55 98.18,65.3 97.39,66.09 97.39,66.39
  BOTTOM w0.089: 96.2,70.87 96.2,70.89 96.18,70.9 96.18,72.1 CPU1.AV37
  BOTTOM w0.102: v1(97.04,68.8) 96.02,69.82 96.02,70.44 96.2,70.62 96.2,70.87
  BOTTOM w0.127: v1(83.13,28.82) 82.65,29.31 DM1.101
M_A_DIMA_CLK_DDR1: length 62.1
  TOP w0.127: v2(84.15,24.99) 83.92,24.76 83.61,24.76 v1(83.55,24.82)
  L4 w0.089: 98.08,66.67 98.1,66.69 98.1,66.85 97.69,67.27 97.69,69.2 97.57,69.31 97.57,70.85 97.47,70.95 97.09,70.95 v1(96.9,70.76)
  L4 w0.114: v1(83.55,24.82) 83.79,24.82 84.01,25.04 84.01,26.41 83.89,26.53 83.68,26.53 83.43,26.78 83.43,27.26 83.68,27.51 83.89,27.51 84.01,27.62 84.01,28.97 84.14,29.09 84.14,31.95 84.33,32.14 84.33,32.94 93.48,42.09 93.48,42.25 93.24,42.49 93.24,42.86 93.56,43.18 93.93,43.18 94.17,42.94 94.34,42.94 94.54,43.15 94.54,43.31 94.29,43.56 94.29,43.92 94.63,44.26 94.98,44.26 95.23,44 95.4,44 95.6,44.21 95.6,44.37 95.35,44.63 95.35,44.98 95.69,45.32 96.04,45.32 96.3,45.06 96.46,45.06 96.66,45.27 96.66,45.43 96.41,45.69 96.41,46.04 96.75,46.38 97.1,46.38 97.36,46.12 97.52,46.12 98.7,47.31 98.7,65.6 98.08,66.22 98.08,66.67
  BOTTOM w0.127: CPU1.AY36 97.22,71.09 v1(96.9,70.76) ; v1(83.55,24.82) 82.95,24.22 82.95,22.72 DM1.102
M_A_DIMA_CLK_DDR#0: length 63.4
  TOP w0.127: v1(83.13,29.46) v2(83.13,30.09)
  L4 w0.089: v1(97.04,68.15) 97.12,68.15 97.25,68.03 97.25,67.05 97.18,66.98 97.18,66.43 97.16,66.41 97.16,66.39
  L4 w0.114: 97.16,66.39 97.16,66 97.96,65.21 97.96,48.65 97.62,48.31 97.62,47.96 97.84,47.75 97.84,47.57 97.65,47.38 97.47,47.38 97.25,47.59 96.9,47.59 92.11,42.8 92.11,42.45 92.34,42.23 92.34,42.01 92.18,41.86 91.97,41.86 91.74,42.08 91.39,42.08 90.96,41.65 90.96,41.3 91.21,41.04 91.21,40.88 91.01,40.67 90.84,40.67 90.59,40.93 90.24,40.93 89.9,40.59 89.9,40.24 90.15,39.98 90.15,39.82 89.95,39.61 89.78,39.61 89.53,39.87 89.18,39.87 88.84,39.53 88.84,39.18 89.09,38.92 89.09,38.76 88.89,38.55 88.72,38.55 88.47,38.81 88.12,38.81 87.78,38.47 87.78,38.12 88.03,37.86 88.03,37.7 87.83,37.49 87.66,37.49 87.41,37.75 87.06,37.75 86.72,37.41 86.72,37.06 86.97,36.8 86.97,36.64 86.76,36.43 86.6,36.43 86.35,36.69 86,36.69 85.66,36.35 85.66,36 85.91,35.74 85.91,35.58 85.7,35.37 85.54,35.37 85.29,35.63 84.94,35.63 84.6,35.29 84.6,34.94 84.85,34.68 84.85,34.52 84.64,34.31 84.48,34.31 84.23,34.57 83.88,34.57 83.47,34.16 83.47,33.11 83.23,32.86 83.23,30.2 83.34,30.09 83.34,29.59 83.22,29.46 v1(83.13,29.46)
  BOTTOM w0.089: CPU1.AU37 96.42,72.76 96.18,72.52 96.18,72.35 96.01,72.17 96.01,70.9 95.99,70.89 95.99,70.87
  BOTTOM w0.102: 95.99,70.87 95.99,70.7 95.82,70.52 95.82,69.74 96.52,69.04 96.52,67.93 96.61,67.84 96.91,67.84 97.04,67.97 v1(97.04,68.15)
  BOTTOM w0.127: DM1.103 83.25,30.17 82.89,29.81 82.89,29.57 83,29.46 v1(83.13,29.46)
M_A_DIMA_CLK_DDR#1: length 62
  TOP w0.127: v1(83.55,24.18) v2(83.55,23.61)
  L4 w0.089: 98.31,66.67 98.29,66.69 98.29,66.93 97.88,67.35 97.88,69.28 97.76,69.39 97.76,70.93 97.55,71.14 97.17,71.14 v1(96.9,71.41)
  L4 w0.114: 98.31,66.67 98.31,66.32 98.93,65.69 98.93,47.22 97.61,45.9 97.26,45.9 97.01,46.15 96.85,46.15 96.64,45.94 96.64,45.78 96.89,45.53 96.89,45.18 96.55,44.84 96.2,44.84 95.95,45.09 95.79,45.09 95.58,44.88 95.58,44.72 95.83,44.47 95.83,44.12 95.49,43.77 95.14,43.77 94.89,44.03 94.72,44.03 94.52,43.82 94.52,43.66 94.77,43.41 94.77,43.05 94.43,42.71 94.08,42.71 93.84,42.95 93.66,42.95 93.47,42.77 93.47,42.59 93.71,42.35 93.71,41.99 84.56,32.84 84.56,32.05 84.36,31.85 84.36,29 84.24,28.87 84.24,27.53 83.99,27.28 83.78,27.28 83.66,27.16 83.66,26.87 83.78,26.76 83.99,26.76 84.24,26.51 84.24,24.94 83.99,24.69 83.99,24.62 v1(83.55,24.18)
  BOTTOM w0.127: DM1.104 v1(83.55,24.18) ; CPU1.AW36 97.22,71.74 v1(96.9,71.41)
M_A_DIMA_CS#0: length 63.7
  TOP w0.216: v1(87.15,25.45) 87.47,25.45 v2(87.7,25.21)
  L4 w0.216: v1(87.15,25.45) 87.8,25.45 88.98,26.63 88.98,29.58 89.35,29.95 89.97,29.95 92.27,32.25 92.27,32.84 92.55,33.13 93.15,33.13 103.53,43.51 103.53,70.49 101.67,72.35 101.03,72.35 98.83,74.55 v1(98.74,74.55)
  BOTTOM w0.216: CPU1.AP33 98.88,74.55 v1(98.74,74.55) ; v1(87.15,25.45) 86.96,25.45 86.55,25.04 DM1.114
M_A_DIMA_CS#1: length 62.8
  TOP w0.216: v2(100.12,74.77) 99.9,74.55 v1(99.58,74.55)
  L4 w0.216: v1(89.55,28.82) 89.65,28.82 91.22,30.39 91.52,30.39 91.97,29.94 92.28,29.94 92.59,30.25 92.59,30.55 92.14,31 92.14,31.31 92.44,31.62 92.75,31.62 93.2,31.17 93.5,31.17 93.81,31.47 93.81,31.78 93.36,32.23 93.36,32.53 93.67,32.84 93.97,32.84 94.42,32.39 94.73,32.39 95.04,32.7 95.04,33 94.59,33.45 94.59,33.76 104.1,43.28 104.1,70.73 101.91,72.92 101.27,72.92 99.73,74.46 99.66,74.46 v1(99.58,74.55)
  BOTTOM w0.216: CPU1.AR32 99.72,74.55 v1(99.58,74.55) ; DM1.121 88.65,30.02 88.98,29.7 88.98,29.34 89.49,28.82 v1(89.55,28.82)
M_A_DIMA_ODT0: length 3.1
  TOP w0.254: R1206.2 87.2,24.13 v1(87.15,24.18) 86.71,23.74 v2(86.71,23.39)
  BOTTOM w0.216: DM1.116 87.15,22.72 v1(87.15,24.18)
M_A_DIMA_ODT1: length 4.6
  TOP w0.254: v1(88.86,24.82) 89.32,24.82 v2(89.46,24.68) 89.51,24.63 89.51,23.46 89.55,23.42 R1207.2
  BOTTOM w0.254: DM1.120 88.35,22.72 88.35,24.46 88.7,24.82 v1(88.86,24.82)
M_A_DQ0: length 82
  TOP w0.14: v2(91.53,29.13) 91.2,29.46 v1(91.05,29.46)
  L3 w0.127: v1(91.05,29.46) 91.05,34.02 66.92,58.15 66.92,65.05 66.8,65.18 66.54,65.18 66.42,65.05 66.42,61.41 66.29,61.29 66.03,61.29 65.91,61.41 65.91,74.72 68.21,77.03 72.16,77.03 73.59,78.45 74.04,78.45 77.38,78.45 v1(77.55,78.62)
  BOTTOM w0.089: CPU1.AH63 80.24,78.41 80.21,78.41 80.13,78.33 77.85,78.33 v1(77.55,78.62)
  BOTTOM w0.14: DM1.129 v1(91.05,29.46)
M_A_DQ1: length 82.6
  TOP w0.14: v2(91.53,27.86) 91.2,28.19 v1(91.05,28.19)
  L3 w0.127: v1(78.17,78.75) 78.06,78.75 77.74,79.07 76.99,79.07 76.77,78.85 73.88,78.85 73.88,78.85 73.42,78.85 72,77.42 68.05,77.42 65.51,74.89 65.51,59.04 65.64,58.91 65.9,58.91 66.02,59.04 66.02,60.74 66.15,60.87 66.4,60.87 66.53,60.74 66.53,57.98 90.55,33.97 90.55,28.69 v1(91.05,28.19)
  BOTTOM w0.089: v1(78.17,78.75) 78.42,78.51 79.65,78.51 79.95,78.64 79.96,78.64 80.18,78.72 80.32,78.72 80.39,78.69 80.53,78.64 80.53,78.64 80.68,78.55 CPU1.AH62
  BOTTOM w0.14: v1(91.05,28.19) 91.2,28.19 91.65,28.64 DM1.131
M_A_DQ2: length 81
  TOP w0.14: v2(94.77,28.52) 95.1,28.19 v1(95.25,28.19)
  L3 w0.127: v1(95.25,28.19) 94.51,28.93 94.51,34.05 69.87,58.68 69.87,58.86 70.05,59.04 70.23,59.04 73.67,55.6 73.85,55.6 74.03,55.78 74.03,55.96 69.87,60.12 69.87,67.59 73.47,71.19 73.47,74.34 75.7,76.58 76.53,76.58 77.19,77.24 v1(77.19,77.5)
  BOTTOM w0.089: CPU1.AK63 80.19,77 79.82,77 79.58,76.77 77.92,76.77 v1(77.19,77.5)
  BOTTOM w0.14: DM1.141 94.65,28.71 95.04,28.32 95.12,28.32 v1(95.25,28.19)
M_A_DQ3: length 81.6
  TOP w0.14: v2(94.23,25.14) 93.9,24.82 v1(93.75,24.82)
  L3 w0.127: v1(76.56,77.51) 76.56,77.31 76.22,76.97 75.54,76.97 73.08,74.51 73.08,71.35 69.48,67.75 69.48,65.09 69.35,64.96 69.13,64.96 69.01,64.84 69.01,64.58 69.13,64.45 69.35,64.45 69.48,64.33 69.48,64.07 69.35,63.95 69.13,63.95 69.01,63.82 69.01,63.56 69.13,63.44 69.35,63.44 69.48,63.31 69.48,63.06 69.35,62.93 69.13,62.93 69.01,62.8 69.01,62.55 69.13,62.42 69.35,62.42 69.48,62.29 69.48,62.04 69.35,61.91 69.13,61.91 69.01,61.79 69.01,61.53 69.13,61.4 69.35,61.4 69.48,61.28 69.48,61.02 69.35,60.9 69.13,60.9 69.01,60.77 69.01,60.51 69.13,60.39 69.35,60.39 69.48,60.26 69.48,60.01 69.35,59.88 69.13,59.88 69.01,59.75 69.01,59.5 69.13,59.37 69.35,59.37 69.48,59.24 69.48,58.52 94.11,33.89 94.11,27.15 94.32,26.95 95.02,26.95 95.15,26.82 95.15,26.57 95.02,26.44 94.32,26.44 94.19,26.31 94.19,26.06 94.32,25.93 95.02,25.93 95.15,25.8 95.15,25.55 95.02,25.42 94.32,25.42 94.19,25.29 94.19,24.95 94.07,24.82 93.75,24.82 v1(93.75,24.82)
  BOTTOM w0.089: v1(76.56,77.51) 77.18,76.89 77.38,76.89 77.68,76.59 79.66,76.59 79.88,76.81 80.64,76.81 CPU1.AK62
  BOTTOM w0.14: DM1.140 94.35,24.29 93.82,24.82 v1(93.75,24.82)
M_A_DQ4: length 82.8
  TOP w0.14: v1(91.95,24.18) 92.1,24.18 v2(92.43,23.85)
  L3 w0.127: v1(91.95,24.18) 91.95,24.19 91.51,24.63 91.51,25.27 91.11,25.66 91.11,26.86 90.15,27.82 90.15,33.8 65.12,58.84 65.12,75.05 67.89,77.82 71.82,77.82 73.24,79.24 73.72,79.24 76.61,79.24 76.83,79.46 77.9,79.46 78.17,79.2 78.64,79.2 v1(78.83,79.01)
  BOTTOM w0.089: CPU1.AH61 81.19,78.81 80.58,78.81 80.46,78.86 80.35,78.9 80.15,78.9 79.9,78.81 79.61,78.71 79.12,78.71 v1(78.83,79.01)
  BOTTOM w0.14: DM1.132 v1(91.95,24.18)
M_A_DQ5: length 83.8
  TOP w0.14: v2(92.43,25.78) 92.1,25.45 v1(91.95,25.45)
  L3 w0.127: v1(91.95,25.45) 91.95,25.46 91.51,25.9 91.51,26.54 91.63,26.67 92,26.67 92.12,26.8 92.12,27.05 92,27.18 91.63,27.18 91.51,27.3 91.51,27.56 91.63,27.69 91.91,27.69 92.04,27.81 92.04,28.07 91.91,28.19 91.63,28.19 91.51,28.32 91.51,34.12 67.32,58.31 67.32,65.32 66.3,66.33 66.3,74.56 68.38,76.64 72.32,76.64 73.74,78.05 77.94,78.05 v1(78.46,77.52)
  BOTTOM w0.089: CPU1.AH60 82.22,77.66 82.02,77.46 81.81,77.46 81.79,77.48 81.34,77.48 81.34,77.47 81.19,77.47 81.14,77.5 81.01,77.55 80.81,77.55 80.77,77.53 80.65,77.47 80.54,77.47 80.48,77.5 80.36,77.55 80.11,77.55 79.87,77.48 79.68,77.37 79.44,77.13 78.86,77.13 v1(78.46,77.52)
  BOTTOM w0.14: DM1.130 91.35,24.85 91.83,25.33 91.83,25.33 v1(91.95,25.45)
M_A_DQ6: length 81.9
  TOP w0.14: v1(95.25,29.46) v2(95.25,30.02)
  L3 w0.127: v1(77.83,77.52) 77.83,77.32 76.69,76.18 75.87,76.18 73.86,74.17 73.86,71.01 70.26,67.41 70.26,60.29 79.41,51.14 79.41,50.97 79.23,50.79 79.05,50.79 74.5,55.33 74.32,55.33 74.14,55.15 74.14,54.97 94.9,34.21 94.9,29.81 v1(95.25,29.46)
  BOTTOM w0.089: v1(77.83,77.52) 78.39,76.95 79.52,76.95 79.79,77.23 79.87,77.27 arc(79.94,77.31) 80.02,77.33 80.07,77.35 arc(80.1,77.36) 80.13,77.36 80.35,77.36 80.42,77.33 80.48,77.31 arc(80.5,77.3) 80.53,77.3 80.7,77.3 80.76,77.33 arc(80.77,77.33) 80.78,77.34 80.82,77.36 arc(80.85,77.37) 80.88,77.37 80.95,77.37 arc(80.97,77.37) 80.99,77.36 81.07,77.33 81.13,77.31 arc(81.15,77.3) 81.18,77.3 81.39,77.3 arc(81.46,77.28) 81.51,77.24 CPU1.AK61
  BOTTOM w0.14: DM1.143 v1(95.25,29.46)
M_A_DQ7: length 83.3
  TOP w0.14: v1(93.75,26.09) v2(93.75,26.69)
  L3 w0.127: v1(93.75,26.09) 93.67,26.17 93.67,26.91 93.54,27.03 93.29,27.03 93.16,26.91 93.16,26.29 93.03,26.17 92.78,26.17 92.65,26.29 92.65,27.19 93.67,28.21 93.67,33.77 68.6,58.84 68.6,65.14 69.08,65.62 69.08,69.81 67.58,71.31 67.58,74.03 68.88,75.32 73.34,75.32 75.44,77.42 v1(75.89,77.42)
  BOTTOM w0.089: CPU1.AK60 82.03,77.19 81.47,76.63 79.95,76.63 79.73,76.42 77.53,76.42 77.41,76.53 76.88,76.53 75.99,77.42 v1(75.89,77.42)
  BOTTOM w0.14: DM1.142 94.95,24.96 93.82,26.09 v1(93.75,26.09)
M_A_DQ8: length 73.2
  TOP w0.14: v1(77.14,75.04) 77.14,74.77 v2(77.42,74.49)
  L4 w0.127: v1(77.14,75.04) 76.7,74.6 74.98,74.6 73.4,73.02 73.4,71.96 69.41,67.97 69.41,67.14 52.91,50.63 52.91,50.46 53.09,50.28 53.27,50.28 56.13,53.14 56.31,53.14 56.49,52.96 56.49,52.78 52.55,48.84 52.55,29.99 52.21,29.64 52.21,29.27 v1(52.65,28.82)
  BOTTOM w0.089: v1(77.14,75.04) 77.57,75.47 77.72,75.47 78.11,75.86 79.93,75.86 79.96,75.88 79.96,75.88 80.08,76.01 CPU1.AM63
  BOTTOM w0.14: v1(52.65,28.82) 52.58,28.82 52.05,29.35 DM1.7
M_A_DQ9: length 74.4
  TOP w0.14: v2(77.54,75.79) 77.49,75.73 v1(76.94,75.73)
  L4 w0.127: v1(51.15,24.18) 50.68,24.65 50.68,30.36 51.37,31.05 51.37,50.87 66.6,66.09 66.6,73.35 66.6,73.35 66.6,74.01 66.6,74.01 66.6,74.06 68.74,76.2 76.49,76.2 76.94,75.75 v1(76.94,75.73)
  BOTTOM w0.089: CPU1.AM62 80.42,76.28 80.1,76.28 79.88,76.06 78.01,76.06 v1(76.94,75.73)
  BOTTOM w0.14: DM1.4 v1(51.15,24.18)
M_A_DQ10: length 72.3
  TOP w0.14: v2(54.94,27.83) 54.58,28.19 v1(54.45,28.19)
  L4 w0.127: v1(54.45,28.19) 54.6,28.34 54.6,28.35 54.89,28.64 54.89,29.75 54.23,30.41 54.23,48.14 68.28,62.19 68.28,62.37 68.1,62.55 67.92,62.55 64.94,59.57 64.76,59.57 64.58,59.75 64.58,59.93 71.09,66.44 71.09,67.28 75.08,71.27 75.08,72.31 75.64,72.88 76.61,72.88 77.05,73.32 v1(77.07,73.32)
  BOTTOM w0.089: v1(77.07,73.32) 77.88,74.13 79.5,74.13 80.03,74.65 CPU1.AP63
  BOTTOM w0.14: DM1.17 55.05,28.71 54.52,28.19 v1(54.45,28.19)
M_A_DQ11: length 73.5
  TOP w0.14: v1(55.35,24.18) 55.48,24.18 v2(55.93,24.63)
  L4 w0.127: v1(77.72,73.32) 77.7,73.32 76.86,72.48 75.93,72.48 75.47,72.02 75.47,71.11 71.48,67.12 71.48,66.28 68.36,63.16 68.36,62.98 68.54,62.8 68.72,62.8 71.08,65.15 71.26,65.15 71.44,64.97 71.44,64.8 54.62,47.98 54.62,30.57 55.29,29.91 55.29,26.68 54.81,26.2 54.81,24.72 v1(55.35,24.18)
  BOTTOM w0.089: CPU1.AP62 80.78,74.65 80.49,74.37 79.99,74.37 79.78,74.16 79.55,73.93 78.11,73.93 77.72,73.54 v1(77.72,73.32)
  BOTTOM w0.14: DM1.18 v1(55.35,24.18)
M_A_DQ12: length 74.7
  TOP w0.14: v1(76.29,75.73) v2(76.29,76.3)
  L4 w0.127: v1(51.15,25.45) 51.25,25.45 51.41,25.61 51.41,29.96 51.77,30.32 51.77,50.7 66.99,65.93 66.99,73.52 66.99,73.84 68.93,75.78 76.24,75.78 v1(76.29,75.73)
  BOTTOM w0.089: CPU1.AM61 81.01,76.46 80.02,76.46 79.81,76.24 77.76,76.24 77.7,76.18 76.49,76.18 76.29,75.98 v1(76.29,75.73)
  BOTTOM w0.14: v1(51.15,25.45) 51.22,25.45 51.75,24.93 DM1.6
M_A_DQ13: length 75.8
  TOP w0.14: v1(75.75,75.09) 75.75,74.86 v2(76.1,74.52)
  L4 w0.127: v1(52.65,27.55) 51.8,28.4 51.8,29.8 52.16,30.15 52.16,50.54 67.38,65.77 67.38,66.68 67.51,66.8 68.12,66.8 68.24,66.93 68.24,67.19 68.12,67.31 67.51,67.31 67.38,67.44 67.38,73.68 69.09,75.39 75.46,75.39 v1(75.75,75.09)
  BOTTOM w0.089: CPU1.AM60 82.22,75.23 82.02,75.03 81.77,75.03 81.75,75.04 81.19,75.04 81.14,75.06 81.01,75.12 80.81,75.12 80.77,75.1 80.65,75.04 80.54,75.04 80.48,75.07 80.36,75.12 79.99,75.12 79.48,74.61 76.23,74.61 v1(75.75,75.09)
  BOTTOM w0.14: v1(52.65,27.55) 52.47,27.74 52.46,27.74 51.45,28.75 DM1.5
M_A_DQ14: length 73.3
  TOP w0.14: v1(54.45,29.46) v2(54.45,30.09)
  L4 w0.127: v1(54.45,29.46) 54.45,29.63 53.84,30.25 53.84,48.31 64.53,59 64.53,59.18 64.35,59.36 64.17,59.36 60.49,55.68 60.31,55.68 60.13,55.86 60.13,56.04 70.7,66.61 70.7,67.44 74.69,71.43 74.69,72.49 75.51,73.32 v1(76.42,73.32)
  BOTTOM w0.089: CPU1.AP61 81.46,74.76 arc(81.34,74.84) 81.2,74.87 81.18,74.87 arc(81.15,74.87) 81.13,74.88 81.07,74.9 80.99,74.93 arc(80.97,74.94) 80.95,74.94 80.88,74.94 arc(80.85,74.94) 80.82,74.93 80.78,74.91 arc(80.77,74.9) 80.76,74.9 80.7,74.87 80.53,74.87 arc(80.5,74.87) 80.48,74.88 80.42,74.9 80.34,74.93 arc(80.32,74.94) 80.3,74.94 80.06,74.94 79.43,74.31 77.65,74.31 77.54,74.19 77.21,74.19 76.42,73.41 v1(76.42,73.32)
  BOTTOM w0.14: DM1.15 v1(54.45,29.46)
M_A_DQ15: length 74.5
  TOP w0.14: v1(55.35,25.45) 55.48,25.45 v2(55.93,25.9)
  L4 w0.127: v1(55.35,25.45) 55.72,25.82 55.72,25.83 55.79,25.9 55.79,26.27 55.72,26.34 55.72,30.03 55.02,30.74 55.02,46.38 58.23,49.59 58.23,49.77 58.05,49.95 57.87,49.95 55.46,47.55 55.28,47.55 55.11,47.73 55.11,47.9 71.88,64.68 71.88,66.89 75.96,70.97 75.96,71.75 76.3,72.09 77.03,72.09 77.78,72.84 77.89,72.84 v1(78.37,73.32)
  BOTTOM w0.089: v1(78.37,73.32) 78.37,73.51 78.62,73.75 79.63,73.75 79.65,73.77 80.07,74.19 80.57,74.19 80.74,74.36 81.7,74.36 81.99,74.65 CPU1.AP60
  BOTTOM w0.14: v1(55.35,25.45) 55.25,25.45 54.75,24.95 DM1.16
M_A_DQ16: length 74.1
  TOP w0.14: v1(98.85,27.55) 98.7,27.55 v2(98.37,27.88)
  L3 w0.127: v1(98.85,27.55) 99.29,28 99.29,29.96 99.17,30.09 98.94,30.09 98.81,30.21 98.81,30.47 98.94,30.59 99.17,30.59 99.29,30.72 99.29,30.98 99.17,31.1 98.94,31.1 98.81,31.23 98.81,31.48 98.94,31.61 99.17,31.61 99.29,31.74 99.29,31.99 99.17,32.12 98.94,32.12 98.81,32.25 98.81,32.5 98.94,32.63 99.17,32.63 99.29,32.75 99.29,33.01 99.17,33.14 98.94,33.14 98.81,33.26 98.81,35.5 96.79,37.52 96.79,37.7 96.97,37.87 97.15,37.87 98.55,36.48 98.73,36.48 98.91,36.66 98.91,36.84 75.24,60.51 75.24,67.59 78.75,71.11 79.83,71.11 81.39,72.67 82.55,72.67 83.49,73.6 83.49,74.09 83.06,74.52 v1(83,74.52)
  BOTTOM w0.14: DM1.159 100.05,28.67 98.93,27.55 v1(98.85,27.55) ; v1(83,74.52) 83.04,74.52 83.36,74.85 CPU1.AP58
M_A_DQ17: length 73.2
  TOP w0.14: v1(98.85,28.82) 98.7,28.82 v2(98.37,29.15)
  L3 w0.127: v1(98.85,28.82) 98.41,29.27 98.41,35.34 93.05,40.7 93.05,40.88 93.23,41.06 93.41,41.06 96.4,38.07 96.58,38.07 96.76,38.25 96.76,38.43 73.95,61.23 73.95,66.87 78.58,71.5 79.67,71.5 81.23,73.06 82.19,73.06 v1(83.01,73.88)
  BOTTOM w0.14: CPU1.AR58 83.31,74.2 83.01,73.89 v1(83.01,73.88) ; DM1.157 99.45,29.35 98.92,28.82 v1(98.85,28.82)
M_A_DQ18: length 76.2
  TOP w0.14: v1(96.15,24.18) v2(96.15,23.58)
  L3 w0.089: v1(83.92,75.83) 83.52,76.22 83.52,77.23 83.21,77.54 81.98,77.54
  L3 w0.127: v1(96.15,24.18) 96.59,24.63 96.59,27.38 96.18,27.8 96.18,34.64 81.6,49.22 81.6,50.66 71.66,60.6 71.66,67.51 75.07,70.92 75.07,73.22 76.04,74.19 79.43,74.19 79.44,74.2 79.44,74.2 79.93,74.69 79.93,75.8 81.67,77.54 81.98,77.54
  BOTTOM w0.14: CPU1.AM57 84.27,76.15 83.94,75.83 v1(83.92,75.83) ; DM1.146 v1(96.15,24.18)
M_A_DQ19: length 77.8
  TOP w0.14: v1(96.15,25.45) v2(96.15,26.06)
  L3 w0.089: v1(83.97,77.13) 83.97,77.36 83.5,77.83 82.37,77.83 82.24,77.96 81.92,77.96
  L3 w0.127: 81.92,77.96 81.53,77.96 79.54,75.97 79.54,74.86 79.28,74.6 79.27,74.6 79.26,74.58 75.88,74.58 74.68,73.38 74.68,71.08 71.27,67.67 71.27,60.43 81.05,50.66 81.05,50.48 80.87,50.3 80.69,50.3 80.41,50.58 80.23,50.58 80.05,50.4 80.05,50.22 95.79,34.48 95.79,27.63 96.15,27.27 v1(96.15,25.45)
  BOTTOM w0.14: DM1.148 96.75,24.92 96.22,25.45 v1(96.15,25.45) ; CPU1.AK57 84.26,77.45 83.97,77.15 v1(83.97,77.13)
M_A_DQ20: length 75.7
  TOP w0.14: v1(97.05,29.46) v2(97.05,30.02)
  L3 w0.127: v1(97.05,29.46) 97.05,34.89 84.72,47.21 84.72,47.39 84.9,47.57 85.08,47.57 88.04,44.62 88.22,44.62 88.4,44.8 88.4,44.98 72.51,60.86 72.51,67.24 75.88,70.62 75.88,72.25 76.51,72.88 79.23,72.88 80.72,74.37 80.72,75.46 81.7,76.45 v1(83.05,76.45)
  BOTTOM w0.14: DM1.149 v1(97.05,29.46) ; v1(83.05,76.45) 83.4,76.8 CPU1.AL58
M_A_DQ21: length 77.1
  TOP w0.14: v1(97.05,28.19) 96.9,28.19 v2(96.57,28.52)
  L3 w0.127: v1(83.03,77.09) 81.79,77.09 80.33,75.63 80.33,74.53 79.59,73.8 79.27,73.8 79.27,73.79 76.2,73.79 75.46,73.06 75.46,70.75 72.08,67.37 72.08,60.74 84.67,48.14 84.67,47.96 84.49,47.78 84.31,47.78 82.36,49.74 82.18,49.74 82,49.56 82,49.38 96.58,34.8 96.58,28.66 v1(97.05,28.19)
  BOTTOM w0.14: v1(83.03,77.09) 83.38,77.45 CPU1.AK58 ; DM1.147 96.45,28.62 96.88,28.19 v1(97.05,28.19)
M_A_DQ22: length 74.3
  TOP w0.14: v1(100.35,25.45) 100.2,25.45 v2(99.87,25.78)
  L3 w0.127: v1(100.35,25.45) 99.73,24.83 98.9,24.83 98.67,25.06 98.67,26.28 98.8,26.41 99.05,26.41 99.18,26.28 99.18,25.65 99.31,25.52 99.56,25.52 99.69,25.65 99.69,33.56 99.56,33.69 99.33,33.69 99.21,33.82 99.21,34.07 99.33,34.2 99.56,34.2 99.69,34.33 99.69,34.58 99.56,34.71 99.33,34.71 99.21,34.83 99.21,35.09 99.33,35.21 99.56,35.21 99.69,35.34 99.69,35.6 99.56,35.72 99.33,35.72 99.21,35.85 99.21,36.1 99.33,36.23 99.56,36.23 99.69,36.36 99.69,36.61 75.63,60.67 75.63,67.43 78.91,70.71 79.99,70.71 80.85,71.57 82.16,71.57 83.96,73.37 v1(83.96,73.84)
  BOTTOM w0.14: CPU1.AR57 84.32,74.2 83.97,73.84 v1(83.96,73.84) ; DM1.158 99.75,24.93 100.28,25.45 v1(100.35,25.45)
M_A_DQ23: length 75.6
  TOP w0.14: v1(100.35,24.18) v2(100.35,23.58)
  L3 w0.127: v1(83.94,75.16) 83.96,75.16 84.41,74.71 84.41,73.16 84.03,72.78 84.03,72.6 84.29,72.34 84.29,72.16 84.11,71.98 83.93,71.98 83.67,72.24 83.49,72.24 83.31,72.06 83.31,71.88 83.57,71.62 83.57,71.44 83.39,71.26 83.21,71.26 82.95,71.52 82.77,71.52 82.36,71.11 80.95,71.11 80.16,70.32 79.07,70.32 76.02,67.27 76.02,60.84 76.15,60.72 76.4,60.72 76.53,60.84 76.53,62.67 76.66,62.8 76.91,62.8 77.04,62.67 77.04,59.82 100.1,36.76 100.1,26.97 100.79,26.27 100.79,24.63 v1(100.35,24.18)
  BOTTOM w0.14: CPU1.AN57 84.31,75.5 83.97,75.16 v1(83.94,75.16) ; DM1.160 v1(100.35,24.18)
M_A_DQ24: length 67.4
  TOP w0.14: v1(57.15,24.18) 57.28,24.18 v2(57.73,24.63)
  L4 w0.127: v1(57.15,24.18) 56.7,24.63 56.7,26.27 57.07,26.63 57.07,32.61 56.62,33.06 56.62,37.21 57.03,37.62 57.03,45.4 60.78,49.16 60.78,51.32 73.48,64.01 73.48,66.12 80.52,73.17 83.95,73.17 84.42,73.64 84.42,74.08 v1(84.86,74.53)
  BOTTOM w0.14: CPU1.AP55 85.33,74.85 85.02,74.53 84.86,74.53 v1(84.86,74.53) ; v1(57.15,24.18) 57.15,24.12 57.15,24.12 DM1.24
M_A_DQ25: length 66.8
  TOP w0.14: v2(57.73,25.9) 57.28,25.45 v1(57.15,25.45)
  L4 w0.127: v1(84.86,73.89) 84.86,73.89 84.69,73.72 84.69,73.38 84.13,72.82 80.73,72.82 73.87,65.96 73.87,63.85 61.18,51.15 61.18,48.99 57.42,45.24 57.42,37.46 57.01,37.04 57.01,33.28 57.46,32.83 57.46,26.68 57.59,26.54 57.59,25.9 v1(57.15,25.45)
  BOTTOM w0.14: v1(57.15,25.45) 57.03,25.45 56.55,24.97 DM1.22 ; CPU1.AR55 85.27,74.2 84.96,73.89 84.87,73.89 v1(84.86,73.89)
M_A_DQ26: length 69.8
  TOP w0.14: v1(60.15,25.45) 60.28,25.45 v2(60.73,25.9)
  L4 w0.089: 81.62,70.48 81.72,70.59
  L4 w0.091: v1(85.89,75.82) 86.31,75.4 86.31,75.04 86.54,74.81 86.54,73.15 84.59,71.2 83.6,71.2 83.25,70.84 81.98,70.84 81.72,70.59
  L4 w0.127: v1(60.15,25.45) 60.69,25.99 60.69,29.81 59.98,30.52 59.98,35.18 59.53,35.63 59.53,44.42 63.87,48.75 63.87,48.93 63.37,49.44 63.37,49.61 63.55,49.79 63.73,49.79 64.23,49.29 64.41,49.29 76.99,61.88 76.99,65.86 81.62,70.48
  BOTTOM w0.14: DM1.36 60.75,24.91 60.21,25.45 v1(60.15,25.45) ; v1(85.89,75.82) 86.22,76.15 CPU1.AM54
M_A_DQ27: length 70.8
  TOP w0.14: v1(60.15,24.18) 60.28,24.18 v2(60.73,24.63)
  L4 w0.127: v1(60.15,24.18) 61.08,25.11 61.08,29.97 60.37,30.68 60.37,35.34 59.92,35.79 59.92,44.24 77.38,61.7 77.38,64.93 79.7,67.25 80.32,67.25 83.94,70.87 84.7,70.87 86.91,73.08 86.91,74.8 87.21,75.1 87.21,77.46 86.96,77.7 86.42,77.7 v1(85.84,77.12)
  BOTTOM w0.14: DM1.34 v1(60.15,24.18) ; CPU1.AK54 85.96,77.12 v1(85.84,77.12)
M_A_DQ28: length 69.7
  TOP w0.14: v1(56.23,28.19) 56.36,28.19 v2(56.72,27.83)
  L4 w0.089: 82.42,77.14 82.84,77.56 84.15,77.56 84.42,77.29 84.42,77 84.94,76.47 v1(84.94,76.47)
  L4 w0.127: v1(56.23,28.19) 56.67,28.63 56.67,32.24 56.22,32.69 56.22,37.37 56.64,37.78 56.64,45.57 60.39,49.32 60.39,51.48 73.08,64.18 73.08,66.39 78.75,72.06 78.93,72.06 80.41,73.53 80.41,74.39 80.54,74.52 80.79,74.52 80.92,74.39 80.92,73.9 81.04,73.78 81.3,73.78 81.42,73.9 81.42,76.14 82.42,77.14
  BOTTOM w0.14: DM1.23 56.85,28.51 56.53,28.19 v1(56.23,28.19) ; CPU1.AL55 85.27,76.8 v1(84.94,76.47)
M_A_DQ29: length 69.9
  TOP w0.14: v1(56.23,29.46) v2(56.23,30.09)
  L4 w0.089: 81.74,77.66 81.91,77.84 84.28,77.84 84.89,77.23 v1(84.89,77.12)
  L4 w0.127: 81.74,77.66 80.95,76.87 80.95,75.2 80.82,75.08 80.57,75.08 80.44,75.2 80.44,77.01 80.31,77.14 80.06,77.14 79.93,77.01 79.93,73.5 79.24,72.81 78.94,72.81 72.69,66.55 72.69,64.34 59.99,51.64 59.99,49.48 56.24,45.73 56.24,37.95 55.83,37.53 55.83,32.42 56.23,32.02 v1(56.23,29.46)
  BOTTOM w0.14: CPU1.AK55 85.22,77.45 v1(84.89,77.12) ; DM1.21 56.25,29.48 v1(56.23,29.46)
M_A_DQ30: length 67.5
  TOP w0.14: v1(59.85,29.46) v2(59.85,30.09)
  L4 w0.091: v1(85.91,73.82) 85.91,73.3 84.45,71.84 83.38,71.84 82.92,71.39 81.4,71.39 80.66,70.64
  L4 w0.127: 80.66,70.64 76.2,66.18 76.2,62.21 66.62,52.63 66.44,52.63 66.26,52.81 66.26,52.99 68.2,54.93 68.2,55.11 68.02,55.29 67.84,55.29 64.2,51.65 64.02,51.65 62.46,50.08 62.46,48.46 58.74,44.74 58.74,35.3 59.19,34.85 59.19,30.12 v1(59.85,29.46)
  BOTTOM w0.14: v1(59.85,29.46) DM1.33 ; v1(85.91,73.82) 86.28,74.2 CPU1.AR54
M_A_DQ31: length 69.5
  TOP w0.14: v2(60.43,27.57) 60.43,27.74 59.98,28.19 v1(59.85,28.19)
  L4 w0.091: v1(85.89,75.17) 85.89,75.13 86.33,74.7 86.33,73.31 84.56,71.55 83.5,71.55 83.08,71.13 81.71,71.13 80.9,70.32
  L4 w0.127: v1(59.85,28.19) 60.07,28.41 60.07,28.41 60.29,28.64 60.29,29.64 59.59,30.35 59.59,35.02 59.14,35.47 59.14,44.58 62.85,48.3 62.85,49.88 64.13,51.16 64.28,51.16 65.69,52.58 65.87,52.58 66.05,52.4 66.05,52.22 65.12,51.28 65.12,51.1 65.3,50.92 65.48,50.92 76.59,62.04 76.59,66.02 80.9,70.32
  BOTTOM w0.14: v1(59.85,28.19) 59.92,28.19 60.45,28.71 DM1.35 ; v1(85.89,75.17) 86.21,75.17 86.31,75.27 86.31,75.48 CPU1.AN54
M_A_DQ32: length 64.2
  TOP w0.14: v2(103.23,24.49) 102.9,24.82 v1(102.75,24.82)
  L3 w0.127: v1(81.07,69.26) 80.89,69.07 80.11,69.07 77.63,66.59 77.63,64.31 79.46,62.47 79.46,61.11 88.71,51.86 88.71,50.41 101.91,37.2 101.91,27.45 101.78,27.31 101.4,27.31 101.28,27.19 101.28,26.91 101.4,26.78 101.78,26.78 101.91,26.65 101.91,25.65 v1(102.75,24.82)
  BOTTOM w0.089: CPU1.AY58 83.31,70.94 83.31,70.84 83.22,70.76 83.22,70.21 82.48,69.47 81.89,69.47 81.68,69.26 v1(81.07,69.26)
  BOTTOM w0.14: v1(102.75,24.82) 102.57,24.63 102.56,24.63 102.15,24.22 DM1.166
M_A_DQ33: length 65.4
  TOP w0.14: v1(100.65,27.55) 100.8,27.55 v2(101.13,27.23)
  L3 w0.127: v1(81.51,69.72) 80.88,69.72 80.64,69.47 79.95,69.47 77.23,66.76 77.23,63.99 79.04,62.18 79.04,60.91 86.33,53.62 86.33,53.44 86.19,53.3 86.19,53.12 86.39,52.92 86.57,52.92 86.71,53.06 86.89,53.06 87.09,52.86 87.09,52.68 86.57,52.17 86.57,51.99 86.77,51.79 86.95,51.79 87.34,52.18 87.52,52.18 87.72,51.99 87.72,51.81 87.32,51.41 87.32,51.23 101.52,37.04 101.52,28.42 v1(100.65,27.55)
  BOTTOM w0.089: v1(81.51,69.72) 82.48,69.72 83.04,70.28 83.04,70.82 83.13,70.91 83.13,71.41 CPU1.AW58
  BOTTOM w0.14: DM1.165 101.85,28.75 100.84,27.74 100.83,27.74 v1(100.65,27.55)
M_A_DQ34: length 65
  TOP w0.14: v1(104.85,29.46) v2(104.85,30.02)
  L3 w0.127: v1(104.85,29.46) 104.85,30.15 104.43,30.57 104.43,38.34 100.08,42.69 100.08,42.87 100.28,43.07 100.46,43.07 103.87,39.66 104.05,39.66 104.24,39.86 104.24,40.04 82.13,62.15 82.13,66.34 83.59,67.79 v1(83.59,69.07)
  BOTTOM w0.089: CPU1.AY56 84.82,71.08 84.82,70.05 84.42,69.65 84.42,69.38 84.11,69.07 v1(83.59,69.07)
  BOTTOM w0.14: DM1.175 v1(104.85,29.46)
M_A_DQ35: length 65.9
  TOP w0.14: v1(104.55,24.18) v2(104.55,23.58)
  L3 w0.127: v1(104.55,24.18) 105.1,24.73 105.1,26.48 104.19,27.39 104.19,30.25 104.04,30.41 104.04,38.06 97.98,44.12 97.98,44.3 98.18,44.5 98.35,44.5 99.6,43.25 99.78,43.25 99.98,43.45 99.98,43.63 81.7,61.9 81.7,66.52 82.66,67.48 82.66,68.19 v1(82.65,68.21)
  BOTTOM w0.089: CPU1.AW56 85.08,71.46 85.08,70.93 85,70.85 85,69.97 84.6,69.58 84.6,69.3 83.5,68.21 v1(82.65,68.21)
  BOTTOM w0.14: v1(104.55,24.18) DM1.174
M_A_DQ36: length 65.7
  TOP w0.14: v2(101.13,29.15) 100.8,28.82 v1(100.65,28.82)
  L3 w0.127: v1(81.96,70.19) 80.8,70.19 80.47,69.87 79.66,69.87 76.82,67.02 76.82,63.75 78.23,62.34 78.23,61.05 83.22,56.07 83.22,55.89 83.09,55.76 83.09,55.58 83.29,55.38 83.47,55.38 83.59,55.51 83.77,55.51 84.04,55.24 84.04,55.02 83.6,54.58 83.6,54.4 83.8,54.2 83.98,54.2 84.47,54.7 84.65,54.7 84.85,54.5 84.85,54.32 84.36,53.82 84.36,53.64 84.55,53.45 84.73,53.45 85.23,53.95 85.41,53.95 85.61,53.75 85.61,53.57 85.11,53.07 85.11,52.89 85.31,52.69 85.49,52.69 85.68,52.88 85.86,52.88 86.05,52.68 86.05,52.5 85.86,52.32 85.86,52.14 101.12,36.88 101.12,29.3 v1(100.65,28.82)
  BOTTOM w0.089: v1(81.96,70.19) 81.96,70.37 82.48,70.89 82.48,71.24 82.8,71.57 82.84,71.57 83.46,72.18 CPU1.AV58
  BOTTOM w0.14: v1(100.65,28.82) 100.72,28.82 101.25,29.35 DM1.163
M_A_DQ37: length 66.9
  TOP w0.14: v1(102.75,26.09) 102.6,26.09 v2(102.27,26.41)
  L3 w0.127: v1(102.75,26.09) 102.44,26.09 102.31,26.22 102.31,37.37 89.59,50.08 89.59,51.56 79.88,61.27 79.88,62.66 78.02,64.52 78.02,66.2 78.66,66.84 v1(78.66,66.84)
  BOTTOM w0.089: CPU1.AU58 84.23,73.04 84.43,72.84 84.43,72.63 84.42,72.61 84.42,72.13 84.42,72.12 84.42,72.01 84.4,71.96 84.34,71.83 84.34,71.63 84.42,71.47 84.42,71.36 84.4,71.3 84.36,71.21 84.36,70.84 84.46,70.74 84.46,70.23 84.22,69.99 83.79,69.99 82.54,68.74 82.29,68.74 80.39,66.84 v1(78.66,66.84)
  BOTTOM w0.14: v1(102.75,26.09) 102.68,26.09 101.55,24.96 DM1.164
M_A_DQ38: length 66.4
  TOP w0.14: v2(105.33,28.52) 105,28.19 v1(104.85,28.19)
  L3 w0.127: v1(104.85,28.19) 105.36,28.7 105.36,30.2 104.82,30.74 104.82,40.05 87.61,57.26 87.61,58.77 85.41,60.97 85.23,60.97 85.03,60.77 85.03,60.59 87.05,58.57 87.05,58.39 86.85,58.19 86.68,58.19 82.56,62.31 82.56,66.18 84.58,68.19 84.58,69 84.08,69.51 84.05,69.51 v1(84,69.56)
  BOTTOM w0.089: CPU1.AV56 84.6,71.97 84.56,71.89 84.52,71.79 84.52,71.67 84.6,71.51 84.6,71.32 84.53,71.17 84.53,70.93 84.64,70.82 84.64,70.13 84.07,69.56 v1(84,69.56)
  BOTTOM w0.14: v1(104.85,28.19) 104.92,28.19 105.45,28.72 DM1.177
M_A_DQ39: length 67.5
  TOP w0.14: v2(105.03,25.78) 104.7,25.45 v1(104.55,25.45)
  L3 w0.127: v1(82.12,67.77) 81.49,67.77 81.22,67.5 79.36,65.64 79.36,65.21 81.23,63.33 81.23,61.77 97.86,45.15 97.86,44.97 97.66,44.77 97.48,44.77 97.09,45.16 96.91,45.16 96.71,44.96 96.71,44.78 103.59,37.9 103.59,30.22 103.8,30.01 103.8,25.89 104.24,25.45 v1(104.55,25.45)
  BOTTOM w0.089: CPU1.AU56 84.99,72.75 84.99,72.05 85.26,71.78 85.26,70.86 85.17,70.78 85.17,69.9 84.78,69.5 84.78,69.23 83.32,67.77 v1(82.12,67.77)
  BOTTOM w0.14: DM1.176 105.15,24.92 104.62,25.45 v1(104.55,25.45)
M_A_DQ40: length 62.1
  TOP w0.14: v2(63.13,24.63) 62.68,24.18 v1(62.55,24.18)
  L4 w0.127: v1(62.55,24.18) 62.04,24.69 62.04,26.46 62.49,26.91 62.49,31.32 62,31.81 62,42.47 69.67,50.14 69.67,50.32 69.49,50.5 69.31,50.5 69.16,50.35 68.98,50.35 68.8,50.53 68.8,50.71 78.98,60.89 78.98,64.84 79.62,65.47 v1(79.82,65.47)
  BOTTOM w0.089: CPU1.AY54 85.89,70.74 85.71,70.56 85.71,69.66 85.31,69.26 85.31,69.01 82.29,65.99
  BOTTOM w0.14: v1(79.82,65.47) 81.78,65.47 82.29,65.99 ; DM1.42 v1(62.55,24.18)
M_A_DQ41: length 62.9
  TOP w0.14: v2(61.12,28.58) 61.25,28.58 61.46,28.37 61.46,28.37 v1(61.65,28.19)
  L4 w0.127: v1(61.65,28.19) 62.09,28.63 62.09,31.16 61.61,31.64 61.61,44.21 63.73,46.34 65.31,46.34 68.77,49.8 68.77,49.98 68.59,50.16 68.41,50.16 67.71,49.45 67.53,49.45 67.35,49.63 67.35,49.81 78.59,61.05 78.59,65 79.98,66.39 v1(80.74,66.39)
  BOTTOM w0.089: CPU1.AW54 85.61,71.46 85.61,70.71 85.53,70.63 85.53,69.73 85.13,69.34 85.13,69.08 82.44,66.39 82.18,66.39
  BOTTOM w0.14: 82.18,66.39 v1(80.74,66.39) ; DM1.41 62.25,28.72 61.86,28.32 61.78,28.32 v1(61.65,28.19)
M_A_DQ42: length 62.6
  TOP w0.14: v1(64.95,24.18) 65.08,24.18 v2(65.53,24.63)
  L4 w0.127: v1(64.95,24.18) 65.39,24.63 65.39,26.45 64.81,27.03 64.81,29.91 64.56,30.17 64.56,32.35 64.07,32.83 64.07,38.96 64.79,39.68 64.79,42.33 76.35,53.89 76.35,54.07 76.17,54.25 75.99,54.25 75.75,54.01 75.57,54.01 75.39,54.19 75.39,54.37 81.12,60.1 81.12,64.06 82.74,65.68 82.74,66 83.16,66.42 v1(83.61,66.42)
  BOTTOM w0.089: 87.63,69.31 87.63,69.55 87.33,69.85 87.33,71 CPU1.AY52
  BOTTOM w0.14: DM1.50 v1(64.95,24.18) ; 87.63,69.31 87.63,68.7 85.35,66.42 v1(83.61,66.42)
M_A_DQ43: length 63.5
  TOP w0.14: v1(65.85,28.19) 66.29,28.19 v2(66.55,27.93)
  L4 w0.127: v1(65.85,28.19) 65.3,28.74 65.3,29.98 64.95,30.33 64.95,32.51 64.46,33 64.46,38.8 65.19,39.52 65.19,42.17 78.47,55.45 78.47,55.63 78.29,55.81 78.11,55.81 76.79,54.49 76.61,54.49 76.43,54.67 76.43,54.85 81.51,59.93 81.51,63.59 v1(83.18,65.26)
  BOTTOM w0.089: CPU1.AW52 87.4,71.46 87.48,71.26 87.51,71.19 87.54,71.13 87.54,69.89 88.07,69.36 88.07,69.24
  BOTTOM w0.14: v1(65.85,28.19) 65.78,28.19 65.25,28.71 DM1.51 ; 88.07,69.24 88.07,68.5 85.55,65.98 84.3,65.98 83.58,65.26 v1(83.18,65.26)
M_A_DQ44: length 63.2
  TOP w0.14: v1(61.65,29.46) v2(61.65,30.09)
  L4 w0.127: v1(81.2,66.85) 79.85,66.85 78.19,65.19 78.19,61.22 64.99,48.01 64.99,47.84 65.17,47.66 65.35,47.66 66.9,49.2 67.08,49.2 67.26,49.02 67.26,48.84 65.15,46.73 63.56,46.73 61.21,44.38 61.21,31.48 61.65,31.04 v1(61.65,29.46)
  BOTTOM w0.089: 82.14,66.85 82.65,66.85 84.96,69.16 84.96,69.42 85.35,69.82 85.35,70.7 85.44,70.79 85.44,71.71 85.99,72.27 CPU1.AV54
  BOTTOM w0.14: 82.14,66.85 v1(81.2,66.85) ; DM1.39 61.65,29.46 v1(61.65,29.46)
M_A_DQ45: length 64.3
  TOP w0.14: v2(63.13,25.9) 62.68,25.45 v1(62.55,25.45)
  L4 w0.089: 79.82,65.03 80.02,65.03 82.83,67.84 83.06,67.84 84.56,69.34 86.51,69.34 v1(86.51,69.34)
  L4 w0.127: v1(62.55,25.45) 62.99,25.9 62.99,26.29 62.88,26.4 62.88,31.48 62.39,31.97 62.39,42.3 70.15,50.06 70.15,51.5 79.38,60.73 79.38,64.59 79.82,65.03
  BOTTOM w0.089: CPU1.AU54 86.66,73.04 86.86,72.84 86.86,72.63 86.85,72.61 86.85,72.13 86.85,72.12 86.85,72.01 86.83,71.96 86.77,71.83 86.77,71.63 86.78,71.63 86.85,71.47 86.85,71.36 86.83,71.3 86.77,71.17 86.77,70.61 86.94,70.44 86.94,69.73 86.84,69.64
  BOTTOM w0.14: v1(86.51,69.34) 86.54,69.34 86.84,69.64 ; DM1.40 61.95,24.91 62.49,25.45 v1(62.55,25.45)
M_A_DQ46: length 63.9
  TOP w0.14: v2(65.53,25.9) 65.08,25.45 v1(64.95,25.45)
  L4 w0.127: v1(64.95,25.45) 64.6,25.45 64.42,25.63 64.42,29.74 64.16,30 64.16,32.18 63.68,32.67 63.68,40.25 63.8,40.38 64.25,40.38 64.38,40.51 64.38,40.76 64.25,40.89 63.8,40.89 63.68,41.02 63.68,41.77 74.99,53.09 74.99,54.53 80.73,60.26 80.73,64.42 83.19,66.88 v1(84.07,66.88)
  BOTTOM w0.089: CPU1.AV52 87.03,72.17 87.03,71.97 86.99,71.89 86.95,71.79 86.95,71.67 87.03,71.51 87.03,71.32 86.95,71.14 86.95,70.79 87.15,70.59 87.15,69.75 87.3,69.6 87.3,69.26
  BOTTOM w0.14: v1(84.07,66.88) 85.2,66.88 87.3,68.98 87.3,69.26 ; DM1.52 65.55,25.06 65.16,25.45 v1(64.95,25.45)
M_A_DQ47: length 64.6
  TOP w0.14: v2(66.42,29.47) 66.41,29.46 v1(65.85,29.46)
  L4 w0.127: v1(83.19,64.63) 81.91,63.34 81.91,59.77 78.57,56.43 78.57,56.25 78.75,56.07 78.93,56.07 81.25,58.4 81.43,58.4 81.61,58.22 81.61,58.04 65.58,42.01 65.58,39.36 64.88,38.66 64.88,33.14 65.34,32.67 65.34,30.49 65.85,29.99 v1(65.85,29.46)
  BOTTOM w0.089: CPU1.AU52 87.61,72.67 87.61,71.49 87.64,71.33 87.66,71.27 87.73,71.15 87.73,70.19 88.03,69.89
  BOTTOM w0.14: DM1.53 v1(65.85,29.46) ; v1(83.19,64.63) 83.64,64.63 84.54,65.54 85.75,65.54 88.51,68.3 88.51,69.4 88.03,69.89
M_A_DQ48: length 72.9
  TOP w0.14: v2(70.54,27.83) 70.18,28.19 v1(70.05,28.19)
  L4 w0.089: 91.73,72.09 91.73,72.9 91.97,73.14 93.49,73.14 95.07,74.73 95.07,76.07 94.37,76.77 v1(94.37,77.13)
  L4 w0.127: 91.73,72.09 91.73,71.1 91.45,70.83 91.45,68.99 87.38,64.92 87.38,57.44 84.14,54.19 84.14,54.02 84.32,53.84 84.5,53.84 87,56.34 87.18,56.34 87.36,56.16 87.36,55.98 70.09,38.71 70.09,30.05 70.5,29.64 70.5,28.63 v1(70.05,28.19)
  BOTTOM w0.14: v1(70.05,28.19) 70.13,28.19 70.65,28.71 DM1.69 ; CPU1.AK40 94.69,77.45 v1(94.37,77.13)
M_A_DQ49: length 72.3
  TOP w0.14: v1(70.05,29.46) v2(70.05,30.09)
  L4 w0.089: v1(93.47,77.22) 93.54,77.22 94.76,76 94.76,74.85 93.28,73.37 91.87,73.37 91.39,72.89 91.39,72.05
  L4 w0.127: 91.39,72.05 91.39,71.4 91.01,71.02 91.01,69.06 86.99,65.04 86.99,57.6 80.17,50.78 80.17,50.6 80.35,50.42 80.53,50.42 83.76,53.65 83.94,53.65 84.12,53.47 84.12,53.29 69.69,38.87 69.69,29.82 v1(70.05,29.46)
  BOTTOM w0.14: DM1.67 v1(70.05,29.46) ; CPU1.AK42 93.69,77.45 v1(93.47,77.22)
M_A_DQ50: length 69.9
  TOP w0.14: v2(68.38,29.5) 68.36,29.5 68.32,29.46 v1(67.65,29.46)
  L4 w0.089: 88.59,71.98 88.59,72.26 90.1,73.76 90.1,74.73 90.35,74.99 91.3,74.99 92.16,75.85 v1(92.43,75.85)
  L4 w0.127: 88.59,71.98 88.59,69.36 84.92,65.68 84.92,58.46 68.36,41.91 68.36,41.73 68.54,41.55 68.72,41.55 71.86,44.68 72.03,44.68 72.21,44.5 72.21,44.32 67.62,39.73 67.62,29.49 v1(67.65,29.46)
  BOTTOM w0.14: v1(92.43,75.85) 92.45,75.86 92.73,76.15 CPU1.AM43 ; v1(67.65,29.46) DM1.59
M_A_DQ51: length 69.8
  TOP w0.14: v2(68.35,28.14) 68.29,28.19 v1(67.65,28.19)
  L4 w0.089: 89.41,75 89.62,75.21 90.89,75.21 v1(91.55,75.88)
  L4 w0.127: v1(67.65,28.19) 67.18,28.66 67.18,39.9 68.29,41.02 68.29,41.2 68.11,41.38 67.93,41.38 67.56,41.01 67.38,41.01 67.2,41.19 67.2,41.37 83.51,57.67 83.51,60.66 83.64,60.79 83.89,60.79 84.02,60.66 84.02,58.63 84.14,58.5 84.4,58.5 84.53,58.63 84.53,65.75 87.66,68.89 87.66,71.81 89.17,73.31 89.17,74.76 89.41,75
  BOTTOM w0.14: DM1.57 67.05,28.72 67.58,28.19 v1(67.65,28.19) ; CPU1.AM45 91.82,76.15 v1(91.55,75.88)
M_A_DQ52: length 69.9
  TOP w0.14: v1(91.57,77.18) 91.57,77.69 v2(91.64,77.77)
  L4 w0.091: v1(91.57,77.18) 91.06,76.68 91.06,75.74 90.73,75.4 89,75.4
  L4 w0.127: 89,75.4 88.66,75.4 88.09,74.83 88.09,74.36 88.44,74 88.44,73.27 87.33,72.16 87.33,69 84.13,65.8 84.13,61.32 84,61.19 83.75,61.19 83.62,61.32 83.62,61.99 83.5,62.11 83.24,62.11 83.11,61.99 83.11,57.83 66.79,41.51 66.79,26.98 67.21,26.56 67.21,24.64 v1(66.75,24.18)
  BOTTOM w0.14: v1(91.57,77.18) 91.83,77.45 CPU1.AK45 ; DM1.56 v1(66.75,24.18)
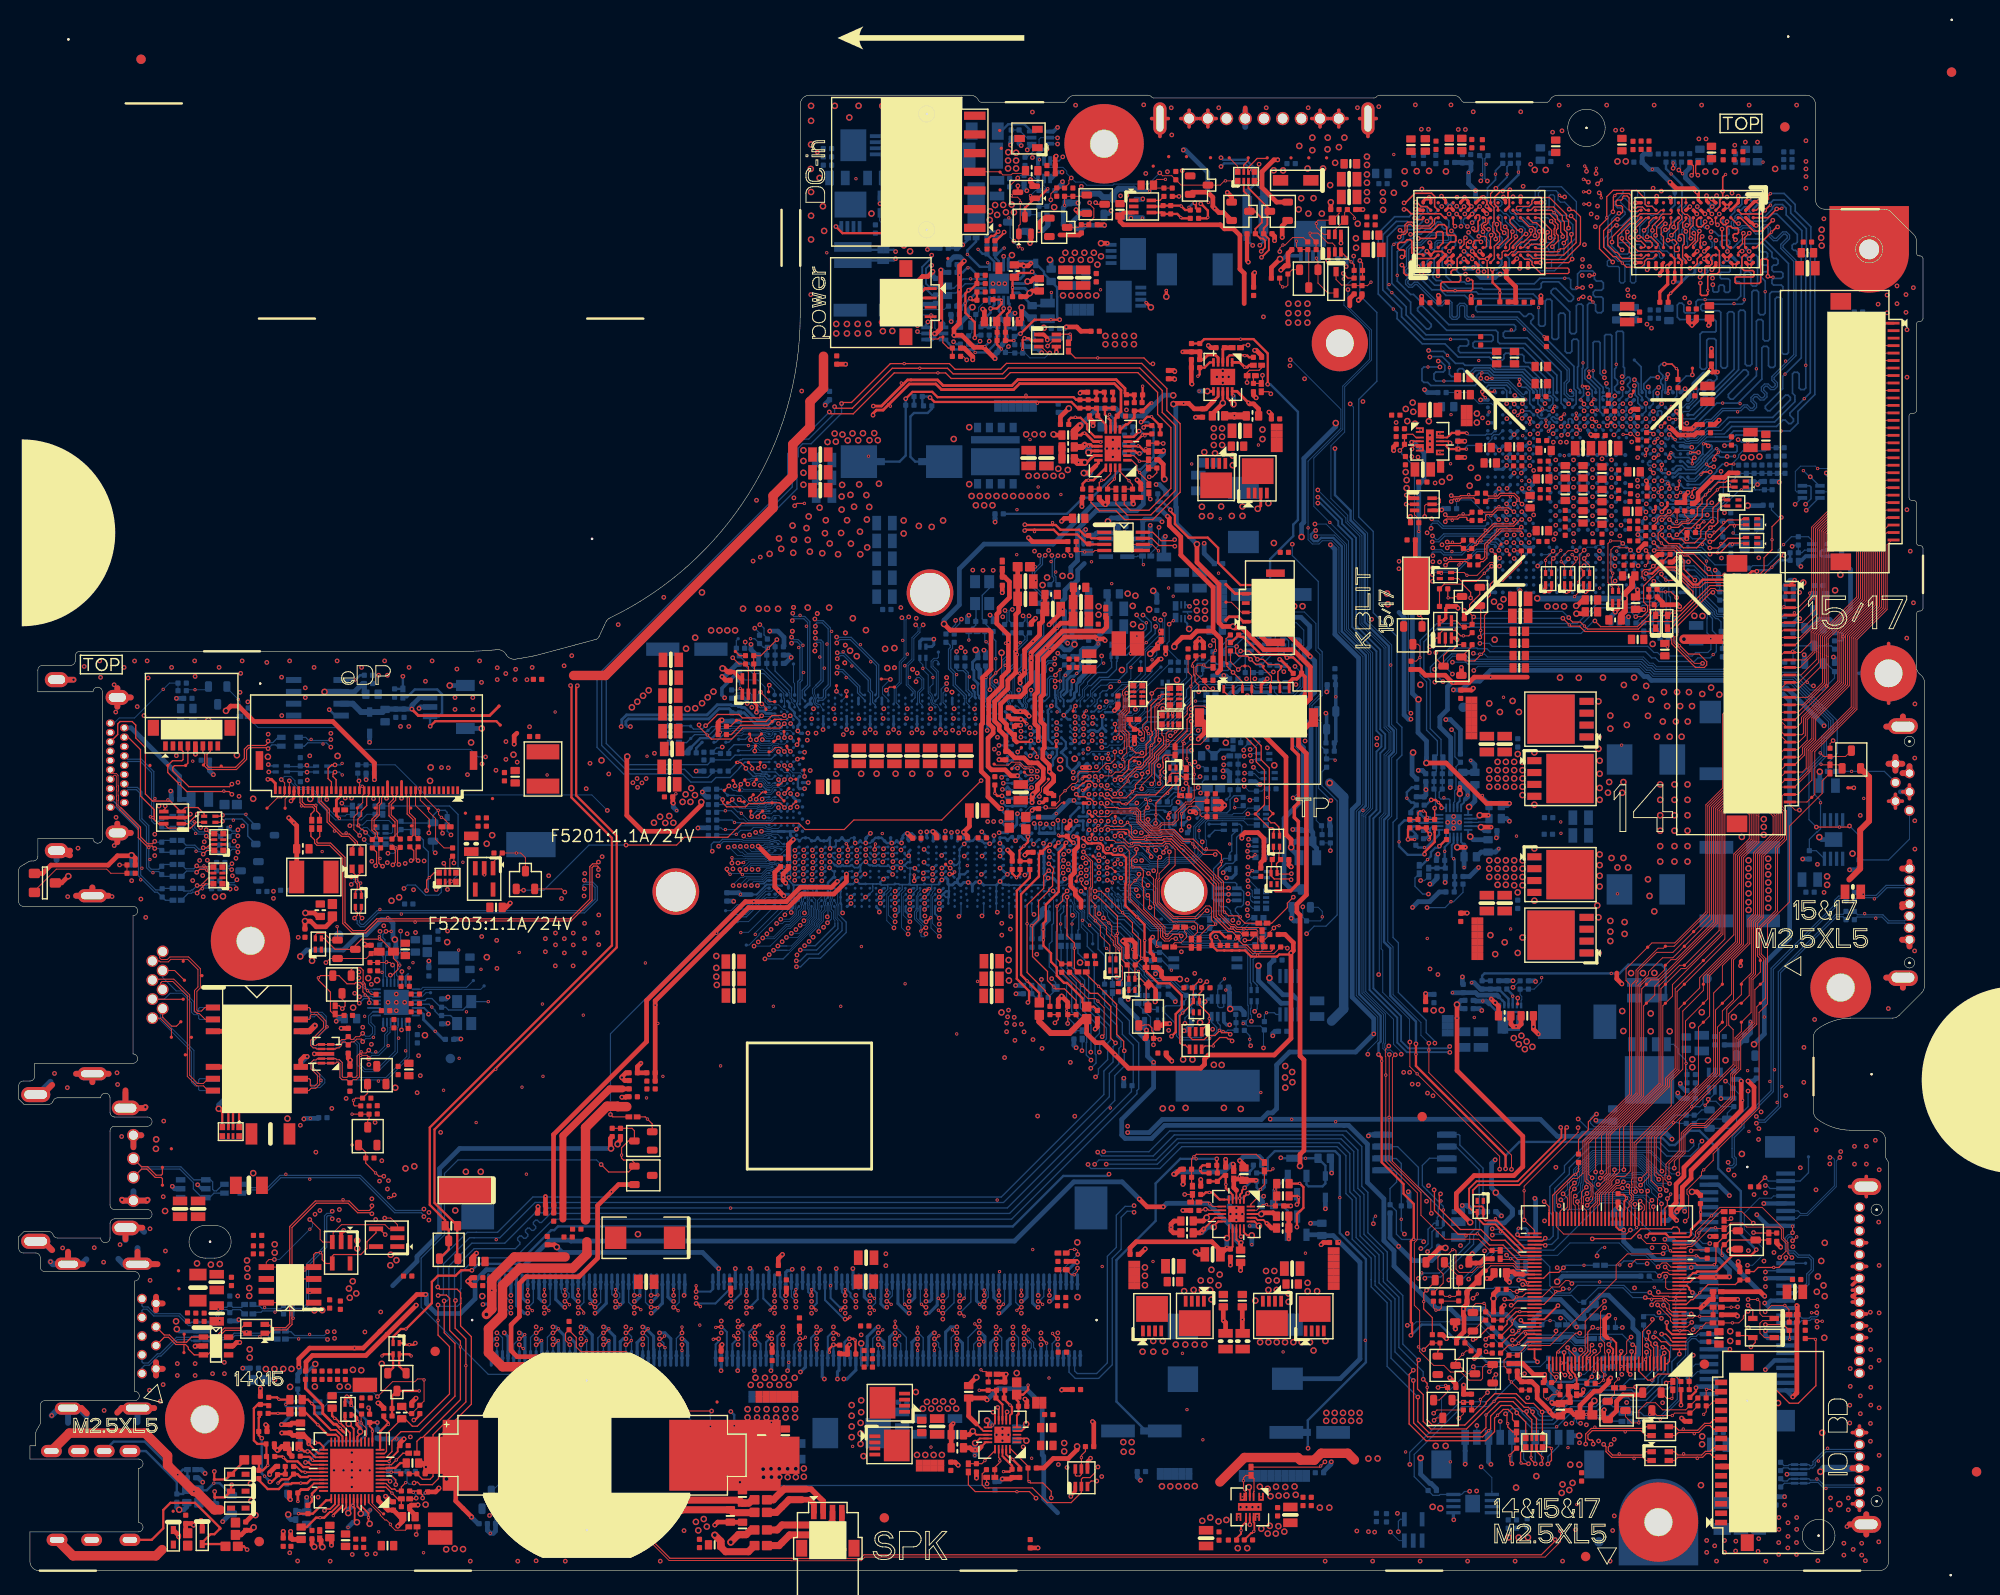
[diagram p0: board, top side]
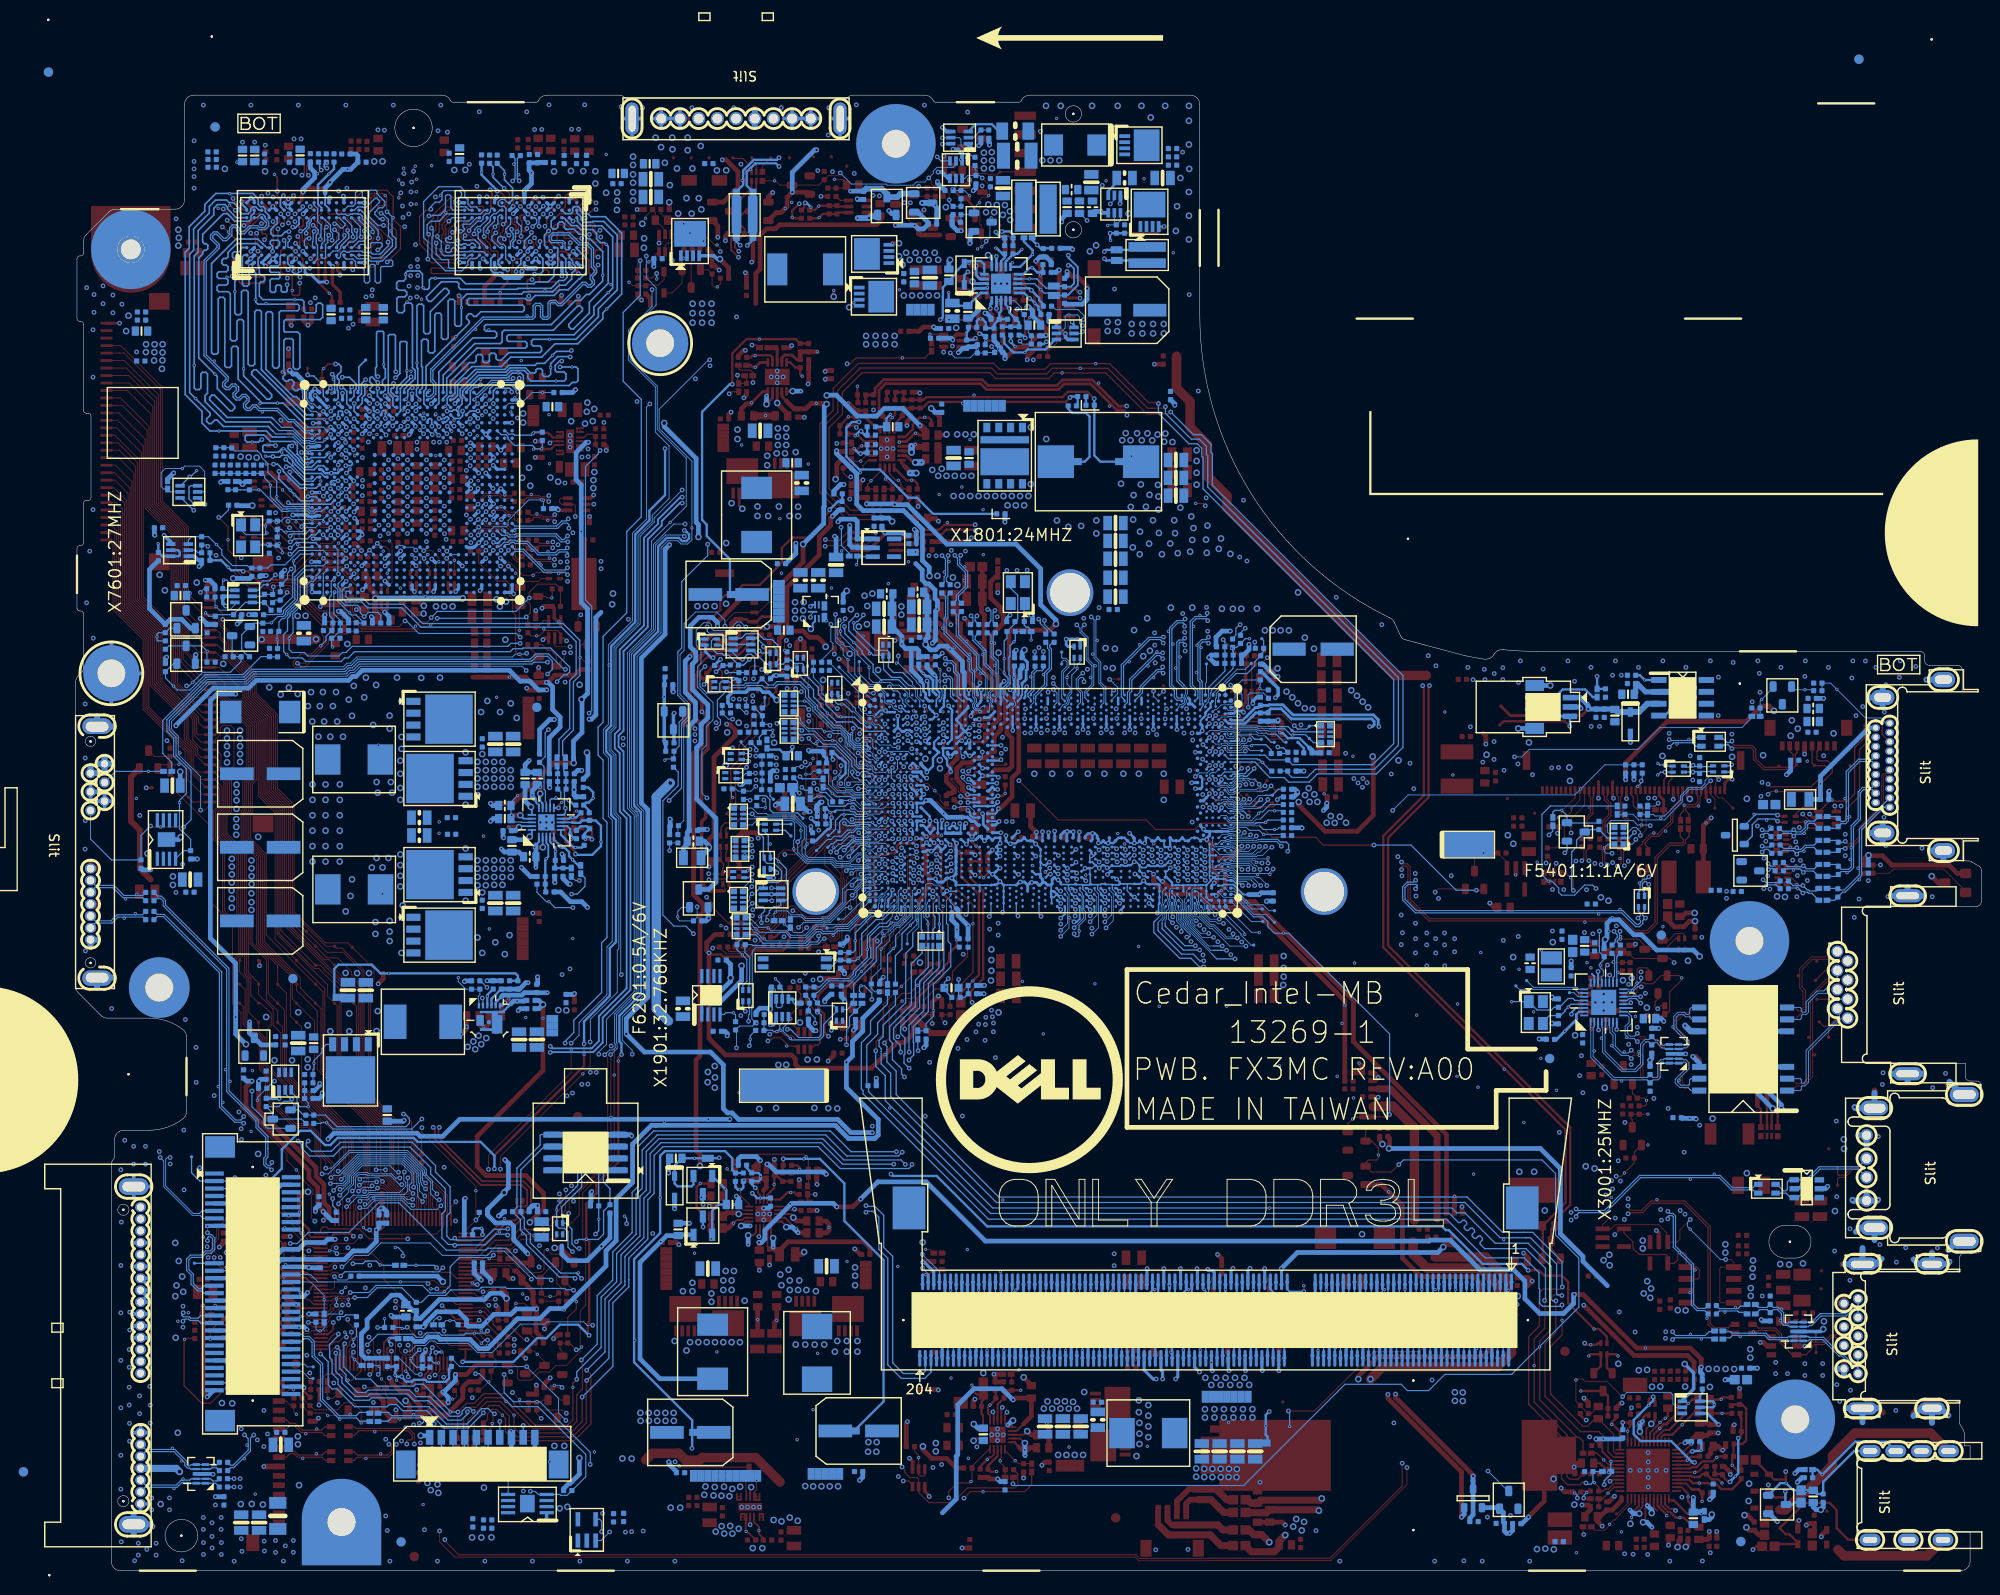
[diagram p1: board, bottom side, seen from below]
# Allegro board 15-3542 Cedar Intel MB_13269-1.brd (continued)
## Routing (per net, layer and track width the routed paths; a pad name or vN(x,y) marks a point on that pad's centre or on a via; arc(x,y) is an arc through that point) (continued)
M_A_DQ53: length 71.4
  TOP w0.14: v1(66.75,25.45) 66.88,25.45 v2(67.33,25.9)
  L4 w0.127: v1(66.75,25.45) 66.31,25.9 66.31,26.27 66.39,26.36 66.39,35.08 65.69,35.78 65.69,36.37 66.39,37.07 66.39,41.67 82.72,58 82.72,62.15 83.74,63.17 83.74,65.89 86.94,69.1 86.94,72.31 88.02,73.38 88.02,73.97 87.7,74.28 87.7,75 88.16,75.46 88.16,77.26 89.19,78.29 91.46,78.29 v1(92.51,77.25)
  BOTTOM w0.14: CPU1.AK43 92.7,77.45 v1(92.51,77.25) ; v1(66.75,25.45) 66.82,25.45 67.35,24.92 DM1.58
M_A_DQ54: length 71.7
  TOP w0.14: v1(70.95,25.45) v2(70.95,26.07)
  L4 w0.089: 91.03,72.06 91.03,72.86 91.77,73.61 93.2,73.61 93.95,74.37 93.95,75.43 v1(94.36,75.83)
  L4 w0.127: 91.03,72.06 91.03,71.75 90.56,71.27 90.56,69.14 86.6,65.18 86.6,57.77 79.03,50.2 79.03,50.02 79.21,49.84 79.39,49.84 79.77,50.22 79.95,50.22 80.13,50.04 80.13,49.86 69.3,39.04 69.3,28.25 70.95,26.61 70.95,26.43 70.77,26.25 70.59,26.25 69.72,27.11 69.54,27.11 69.36,26.93 69.36,26.75 70.67,25.45 v1(70.95,25.45)
  BOTTOM w0.14: v1(70.95,25.45) 70.77,25.27 70.76,25.27 70.35,24.85 DM1.68 ; CPU1.AM40 94.68,76.15 v1(94.36,75.83)
M_A_DQ55: length 70.9
  TOP w0.14: v1(70.95,24.18) v2(70.95,23.56)
  L4 w0.089: v1(93.51,75.89) 93.51,75.78 92.72,75 92.32,75 92.02,74.7 92.02,74.25 90.9,73.12
  L4 w0.127: v1(70.95,24.18) 70.4,24.73 70.4,25.16 70.25,25.31 70.07,25.31 69.95,25.19 69.77,25.19 69.59,25.37 69.59,25.55 69.71,25.67 69.71,25.85 68.91,26.65 68.91,39.2 79,49.29 79,49.47 78.82,49.65 78.64,49.65 77.25,48.26 77.07,48.26 76.89,48.44 76.89,48.62 86.2,57.93 86.2,65.34 90.15,69.29 90.15,72.37 90.9,73.12
  BOTTOM w0.14: DM1.70 v1(70.95,24.18) ; v1(93.51,75.89) 93.77,76.15 CPU1.AM42
M_A_DQ56: length 72.2
  TOP w0.14: v2(109.95,24.35) 109.49,24.82 v1(109.35,24.82)
  L3 w0.127: v1(90.6,76.55) 91.11,76.04 91.11,75.7 91.69,75.11 91.69,73.96 92.76,72.89 92.76,70.48 92,69.72 92,59.07 95.15,55.92 95.33,55.92 95.53,56.12 95.53,56.3 93.63,58.2 93.63,58.38 93.82,58.57 94,58.57 109.65,42.93 109.65,31.3 110.69,30.26 110.69,28.64 110.31,28.26 110.31,25.78 v1(109.35,24.82)
  BOTTOM w0.14: CPU1.AM46 91.09,76.21 90.75,76.55 v1(90.6,76.55) ; v1(109.35,24.82) 109.42,24.82 109.95,24.29 DM1.192
M_A_DQ57: length 71.8
  TOP w0.14: v2(110.59,25.39) 110.59,25.32 111.09,24.82 v1(111.15,24.82)
  L3 w0.127: v1(111.15,24.82) 110.71,25.26 110.71,26.53 110.83,26.66 111.16,26.66 111.29,26.79 111.29,27.04 111.16,27.17 110.83,27.17 110.71,27.3 110.71,28.09 111.15,28.54 111.15,30.36 110.05,31.46 110.05,43.09 93.36,59.78 93.18,59.78 92.98,59.58 92.98,59.4 93.44,58.94 93.44,58.76 93.24,58.56 93.06,58.56 92.4,59.23 92.4,69.56 93.16,70.32 93.16,74.06 93.01,74.21 93.01,77.46 92.54,77.93 91.34,77.93 v1(90.6,77.19)
  BOTTOM w0.14: DM1.194 110.55,24.29 111.08,24.82 v1(111.15,24.82) ; CPU1.AK46 90.86,77.45 v1(90.6,77.19)
M_A_DQ58: length 69.4
  TOP w0.14: v1(107.25,29.46) v2(107.25,30.02)
  L3 w0.127: v1(88.58,75.85) 88.1,75.36 88.1,73.27 88.57,72.8 88.57,71.16 89.53,70.2 89.53,69.51 88.73,68.71 88.73,68.23 88.86,68.11 89.14,68.11 89.27,68.23 89.27,68.56 89.39,68.68 89.67,68.68 89.8,68.56 89.8,58.19 106.59,41.4 106.77,41.4 106.97,41.59 106.97,41.77 105.51,43.24 105.51,43.42 105.71,43.62 105.89,43.62 107.55,41.95 107.55,40.75 107.42,40.62 107.33,40.62 107.21,40.49 107.21,40.21 107.33,40.09 107.42,40.09 107.55,39.96 107.55,39.68 107.42,39.55 107.33,39.55 107.21,39.43 107.21,39.15 107.33,39.02 107.42,39.02 107.55,38.89 107.55,38.61 107.42,38.49 107.33,38.49 107.21,38.36 107.21,38.08 107.33,37.95 107.42,37.95 107.55,37.83 107.55,37.55 107.42,37.42 107.33,37.42 107.21,37.29 107.21,37.01 107.33,36.89 107.42,36.89 107.55,36.76 107.55,36.48 107.42,36.35 107.33,36.35 107.21,36.23 107.21,35.95 107.33,35.82 107.42,35.82 107.55,35.69 107.55,35.41 107.42,35.29 107.33,35.29 107.21,35.16 107.21,34.88 107.33,34.75 107.42,34.75 107.55,34.63 107.55,34.35 107.42,34.22 107.33,34.22 107.21,34.09 107.21,33.81 107.33,33.69 107.42,33.69 107.55,33.56 107.55,33.28 107.42,33.15 107.33,33.15 107.21,33.03 107.21,32.75 107.33,32.62 107.42,32.62 107.55,32.49 107.55,32.21 107.42,32.09 107.33,32.09 107.21,31.96 107.21,31.68 107.33,31.55 107.42,31.55 107.55,31.43 107.55,31.15 107.42,31.02 107.33,31.02 107.21,30.89 107.21,30.61 107.33,30.49 107.42,30.49 107.55,30.36 107.55,29.76 v1(107.25,29.46)
  BOTTOM w0.14: v1(88.58,75.85) 88.84,75.85 CPU1.AM49 ; DM1.183 v1(107.25,29.46)
M_A_DQ59: length 68.6
  TOP w0.14: v1(88.7,77.15) 88.7,77.61 v2(88.52,77.79)
  L3 w0.127: v1(88.7,77.15) 88.12,77.73 85.71,77.73 85.4,77.42 85.4,71.88 86.97,70.31 86.97,69.29 87.53,68.73 87.53,62.49 88.54,61.48 88.54,57.49 105.91,40.12 105.91,25.9 106.01,25.79 106.01,25.79 v1(106.35,25.45)
  BOTTOM w0.14: DM1.182 106.95,24.93 106.42,25.45 v1(106.35,25.45) ; CPU1.AK49 88.99,77.45 v1(88.7,77.15)
M_A_DQ60: length 71
  TOP w0.14: v1(109.05,28.82) 109.2,28.82 v2(109.53,28.5)
  L3 w0.127: v1(109.05,28.82) 109.05,28.83 109.49,29.28 109.49,29.98 108.86,30.62 108.86,42.53 99.74,51.65 99.56,51.65 99.37,51.46 99.37,51.28 103.03,47.61 103.03,47.43 102.84,47.23 102.66,47.23 91.08,58.81 91.08,72.43 90.05,73.47 90.05,75.05 89.65,75.45 v1(89.65,75.82)
  BOTTOM w0.14: CPU1.AM48 89.97,76.15 v1(89.65,75.82) ; DM1.191 109.65,29.35 109.12,28.82 v1(109.05,28.82)
M_A_DQ61: length 70.3
  TOP w0.14: v1(110.25,29.46) v2(110.25,30.02)
  L3 w0.127: v1(89.65,77.12) 90.15,76.62 90.15,75.69 91.03,74.81 91.03,73.22 91.61,72.64 91.61,58.86 98.81,51.67 98.98,51.67 99.18,51.86 99.18,52.04 95.71,55.51 95.71,55.69 95.91,55.89 96.09,55.89 109.26,42.72 109.26,31.01 110.25,30.02 v1(110.25,29.46)
  BOTTOM w0.14: CPU1.AK48 89.97,77.45 v1(89.65,77.12) ; DM1.193 v1(110.25,29.46)
M_A_DQ62: length 68.2
  TOP w0.14: v1(107.25,28.19) 107.1,28.19 v2(106.77,27.86)
  L3 w0.127: v1(107.25,28.19) 107.03,28.19 106.8,28.42 106.8,40.39 89.4,57.78 89.4,67.49 89.28,67.61 89,67.61 88.87,67.49 88.87,64.22 88.74,64.09 88.47,64.09 88.34,64.22 88.34,68.93 88.63,69.22 88.63,70.53 88.08,71.08 88.08,71.96 87.07,72.97 87.07,74.36 87.69,74.99 87.69,75.77 v1(87.74,75.82)
  BOTTOM w0.14: CPU1.AM51 88.07,76.15 v1(87.74,75.82) ; v1(107.25,28.19) 107.18,28.19 106.65,28.71 DM1.181
M_A_DQ63: length 67.6
  TOP w0.14: v1(106.35,24.18) v2(106.35,23.58)
  L3 w0.127: v1(87.74,77.12) 87.74,77.1 87.3,76.66 87.3,75.15 86.37,74.22 86.37,71.95 87.36,70.95 87.36,69.63 87.93,69.06 87.93,62.66 88.06,62.53 88.34,62.53 88.47,62.66 88.47,63.51 88.59,63.63 88.87,63.63 89,63.51 89,57.58 106.3,40.28 106.3,27.61 106.97,26.93 106.97,24.64 106.51,24.18 v1(106.35,24.18)
  BOTTOM w0.14: DM1.180 v1(106.35,24.18) ; v1(87.74,77.12) 88.07,77.45 CPU1.AK51
M_A_DQS0: length 82.3
  TOP w0.127: v1(92.85,28.82) 93,28.82 v2(93.33,28.5)
  L3 w0.114: v1(74.87,77.53) 73.96,77.53 72.52,76.08 68.57,76.08 66.83,74.34 66.83,66.56 67.09,66.3 67.55,66.3 67.81,66.56 67.81,69.11 67.93,69.24 68.2,69.24 68.33,69.11 68.33,66.19 67.85,65.71 67.85,58.53 92.07,34.3 92.07,29.2 92.3,28.98 92.7,28.98 v1(92.85,28.82)
  BOTTOM w0.089: CPU1.AJ62 81.03,77.97 80.83,77.97 80.74,78.01 80.65,78.05 80.53,78.05 80.37,77.97 80.34,77.96 77.42,77.96 77.32,78.06 77.07,78.06 77.04,78.03 77.02,78.03
  BOTTOM w0.127: 77.02,78.03 75.38,78.03 v1(74.87,77.53) ; DM1.137 93.45,29.42 v1(92.85,28.82)
M_A_DQS1: length 73.4
  TOP w0.127: v1(53.55,24.18) 53.55,24.14 53.92,23.77 v2(53.97,23.77)
  L4 w0.114: v1(77.79,75.04) 77.79,74.44 77.43,74.08 75.2,74.08 73.93,72.81 73.93,71.75 69.94,67.76 69.94,66.92 59.38,56.36 59.38,54.92 59.22,54.77 59.06,54.77 58.6,55.23 58.25,55.23 57.91,54.89 57.91,54.54 58.37,54.07 58.37,53.91 58.16,53.7 58,53.7 57.54,54.17 57.19,54.17 56.85,53.83 56.85,53.48 57.31,53.01 57.31,52.85 53.08,48.62 53.08,29.93 53.27,29.75 53.27,27.3 52.62,26.65 52.62,24.59 52.88,24.32 53.41,24.32 v1(53.55,24.18)
  BOTTOM w0.089: v1(77.79,75.04) 77.79,75.18 78.29,75.68 80.15,75.68 80.33,75.72 80.36,75.73 80.48,75.79 80.68,75.79 80.81,75.74 80.86,75.72 81.29,75.72 81.54,75.48 81.75,75.48 CPU1.AN61
  BOTTOM w0.127: DM1.12 v1(53.55,24.18)
M_A_DQS2: length 74.9
  TOP w0.127: v1(97.95,24.82) 98.1,24.82 v2(98.43,25.14)
  L3 w0.114: v1(83.03,75.16) 82.83,75.35 81.92,75.35 81.53,74.96 81.53,74.11 79.45,72.03 78.36,72.03 73.32,66.98 73.32,61.12 89.15,45.29 89.15,43.85 89.29,43.72 89.45,43.72 89.91,44.18 90.26,44.18 90.6,43.84 90.6,43.49 90.14,43.02 90.14,42.86 90.35,42.66 90.51,42.66 90.97,43.12 91.32,43.12 91.66,42.78 91.66,42.43 91.2,41.96 91.2,41.8 91.41,41.6 91.57,41.6 92.03,42.06 92.38,42.06 92.72,41.72 92.72,41.36 92.26,40.9 92.26,40.74 97.85,35.15 97.85,27.05 97.47,26.67 97.47,25.12 97.78,24.82 v1(97.95,24.82)
  BOTTOM w0.127: v1(83.03,75.16) 83.37,75.5 CPU1.AN58 ; v1(97.95,24.82) 98.41,24.35 98.41,23.94 98.55,23.8 DM1.154
M_A_DQS3: length 68.3
  TOP w0.127: v1(58.42,28.82) 58.55,28.82 v2(58.91,28.47)
  L4 w0.089: 81.12,71.83 81.14,71.83 81.16,71.81 82.51,71.81 83.1,72.39 84.2,72.39 85.28,73.47 85.28,74.84 v1(84.94,75.17)
  L4 w0.114: 81.12,71.83 80.78,71.83 75.39,66.44 75.39,62.51 71.2,58.31 71.04,58.31 70.68,58.68 70.31,58.68 69.99,58.35 69.99,57.98 70.35,57.62 70.35,57.46 70.14,57.25 69.98,57.25 69.34,57.9 68.97,57.9 68.64,57.57 68.64,57.2 69.29,56.56 69.29,56.4 68.94,56.06 66.82,56.06 61.7,50.94 61.7,48.77 57.99,45.06 57.99,34.99 58.44,34.54 58.44,32.57 57.99,32.12 57.99,29.26 v1(58.42,28.82)
  BOTTOM w0.127: v1(84.94,75.17) 85.01,75.17 CPU1.AN55 ; DM1.29 58.65,29.86 58.87,29.64 58.87,29.28 58.62,29.03 58.62,29.02 v1(58.42,28.82)
M_A_DQS4: length 65.6
  TOP w0.127: v1(103.27,28.82) 103.12,28.82 v2(102.8,28.5)
  L3 w0.114: v1(103.27,28.82) 102.84,29.26 102.84,37.58 94.57,45.85 94.57,46.2 94.77,46.41 94.77,46.59 94.58,46.78 94.4,46.78 94.2,46.57 93.85,46.57 93.55,46.86 93.55,47.33 93.99,47.77 93.99,47.93 93.78,48.13 93.62,48.13 93.18,47.7 92.83,47.7 92.49,48.04 92.49,48.39 92.92,48.83 92.92,48.99 92.72,49.2 92.56,49.2 92.12,48.76 91.77,48.76 91.43,49.1 91.43,49.45 91.86,49.89 91.86,50.05 91.66,50.26 91.5,50.26 91.06,49.82 90.71,49.82 90.37,50.16 90.37,50.51 90.8,50.95 90.8,51.11 90.66,51.25 89.56,52.35 80.42,61.49 80.42,62.86 78.6,64.68 78.6,65.95 79.58,66.93 v1(79.58,67.71)
  BOTTOM w0.089: v1(79.58,67.71) 79.66,67.63 80.83,67.63 82.18,68.98 82.37,68.98 82.53,68.98 83.6,70.05 83.6,70.5 83.93,70.84 83.93,71.17 83.85,71.35 83.85,71.47 83.89,71.56 83.92,71.65 83.92,71.85 CPU1.AW57
  BOTTOM w0.127: v1(103.27,28.82) 103.72,29.27 103.72,29.28 103.72,29.94 103.65,30 DM1.171
M_A_DQS5: length 62.6
  TOP w0.127: v1(63.85,28.82) 63.97,28.82 v2(64.33,28.47)
  L4 w0.114: v1(63.85,28.82) 63.41,29.26 63.41,31.87 62.92,32.36 62.92,42.09 71.14,50.31 71.14,50.47 70.68,50.93 70.68,51.28 71.02,51.63 71.37,51.63 71.84,51.16 72,51.16 72.2,51.37 72.2,51.53 71.74,51.99 71.74,52.35 72.08,52.69 72.43,52.69 72.9,52.22 73.06,52.22 73.27,52.43 73.27,52.59 72.8,53.06 72.8,53.41 73.14,53.75 73.49,53.75 73.96,53.28 74.12,53.28 74.24,53.4 74.24,54.84 79.9,60.51 79.9,64.43 82.94,67.46 83.21,67.46 84.51,68.75 85.13,68.75 85.48,68.4 v1(85.58,68.4)
  BOTTOM w0.089: CPU1.AW53 86.35,71.85 86.35,71.65 86.32,71.56 86.28,71.47 86.28,71.35 86.36,71.17 86.36,70.63 86.09,70.36 86.09,69.52 85.68,69.11 85.68,68.86 85.58,68.75 v1(85.58,68.4)
  BOTTOM w0.127: DM1.47 64.05,29.88 64.29,29.64 64.29,29.27 v1(63.85,28.82)
M_A_DQS6: length 71
  TOP w0.127: v1(68.55,24.82) 68.79,24.82 v2(69.09,25.11)
  L4 w0.089: 91.1,73.89 91.12,73.89 91.14,73.91 91.31,73.91 91.77,74.37 91.77,74.8 92.17,75.2 92.66,75.2 93.06,75.6 93.06,76.18 v1(93.45,76.57)
  L4 w0.114: v1(68.55,24.82) 68.11,25.25 68.11,25.87 68.38,26.14 68.38,39.42 73.21,44.24 73.21,44.6 72.85,44.96 72.85,45.14 73.04,45.33 73.21,45.33 73.58,44.96 73.93,44.96 74.27,45.3 74.27,45.66 73.81,46.12 73.81,46.28 74.02,46.49 74.18,46.49 74.64,46.03 74.99,46.03 75.33,46.37 75.33,46.72 74.87,47.18 74.87,47.34 75.08,47.55 75.24,47.55 75.7,47.09 76.05,47.09 76.36,47.4 76.36,48.84 85.67,58.15 85.67,65.45 89.72,69.49 89.72,72.61 91,73.89 91.1,73.89
  BOTTOM w0.127: CPU1.AL42 93.68,76.8 v1(93.45,76.57) ; DM1.64 69.15,23.66 69.01,23.8 69.01,24.35 v1(68.55,24.82)
M_A_DQS7: length 69.3
  TOP w0.127: v1(107.54,25.45) 107.69,25.45 v2(108.02,25.78)
  L3 w0.089: v1(88.7,76.5) 89.03,76.16 89.03,74.79 88.99,74.75 88.99,73.46 89.67,72.77 89.67,71.28 89.65,71.26 89.65,71.24
  L3 w0.114: v1(107.54,25.45) 107.78,25.45 108.1,25.77 108.1,26.32 108.35,26.57 108.61,26.57 108.74,26.7 108.74,26.96 108.61,27.09 108.35,27.09 108.1,27.34 108.1,42.17 105.73,44.55 105.57,44.55 105.09,44.07 104.74,44.07 104.4,44.41 104.4,44.76 104.87,45.24 104.87,45.4 104.67,45.61 104.5,45.61 104.03,45.13 103.68,45.13 103.34,45.47 103.34,45.82 103.81,46.3 103.81,46.46 103.61,46.67 103.44,46.67 102.97,46.19 102.62,46.19 90.33,58.48 90.33,70.14 89.65,70.82 89.65,71.24
  BOTTOM w0.127: v1(88.7,76.5) 88.99,76.8 CPU1.AL49 ; DM1.188 108.75,23.71 108.56,23.9 108.56,24.43 v1(107.54,25.45)
M_A_DQS#0: length 82.6
  TOP w0.127: v1(92.85,29.46) v2(92.85,30.02)
  L3 w0.114: v1(92.85,29.46) 92.59,29.2 92.39,29.2 92.3,29.3 92.3,34.4 68.07,58.62 68.07,65.61 68.56,66.09 68.56,69.21 68.3,69.47 67.84,69.47 67.58,69.21 67.58,66.65 67.45,66.53 67.18,66.53 67.06,66.65 67.06,74.25 68.66,75.85 72.61,75.85 73.75,76.99 v1(74.19,76.99)
  BOTTOM w0.089: 77.02,78.27 77.04,78.27 77.07,78.25 77.4,78.25 77.5,78.15 80.33,78.15 80.48,78.22 80.68,78.22 80.81,78.17 80.86,78.15 81.29,78.15 81.68,77.76 CPU1.AJ61
  BOTTOM w0.127: DM1.135 92.85,30.17 93.21,29.81 93.21,29.62 93.05,29.46 v1(92.85,29.46) ; v1(74.19,76.99) 74.08,77.1 74.08,77.71 74.34,77.97 74.98,77.97 75.28,78.27 77.02,78.27
M_A_DQS#1: length 73.8
  TOP w0.127: v1(53.55,24.82) 53.68,24.82 v2(54.13,25.26)
  L4 w0.114: v1(78.44,75.04) 78.75,74.73 78.75,74.54 78.67,74.46 78.14,74.46 77.52,73.85 75.3,73.85 74.16,72.71 74.16,71.65 70.17,67.66 70.17,66.82 59.61,56.26 59.61,54.82 59.32,54.54 58.97,54.54 58.5,55 58.34,55 58.13,54.79 58.13,54.63 58.6,54.17 58.6,53.82 58.26,53.48 57.91,53.48 57.44,53.94 57.28,53.94 57.07,53.73 57.07,53.57 57.54,53.11 57.54,52.76 53.31,48.52 53.31,30.03 53.5,29.84 53.5,27.2 52.85,26.56 52.85,24.68 52.98,24.55 53.29,24.55 v1(53.55,24.82)
  BOTTOM w0.089: v1(78.44,75.04) 78.26,75.22 78.26,75.38 78.36,75.49 80.22,75.49 80.37,75.54 80.4,75.55 80.53,75.62 80.65,75.62 80.74,75.58 80.83,75.54 81.03,75.54 CPU1.AN62
  BOTTOM w0.127: DM1.10 52.95,24.22 v1(53.55,24.82)
M_A_DQS#2: length 75.1
  TOP w0.127: v1(97.95,24.18) v2(97.95,23.58)
  L3 w0.114: v1(83.03,75.81) 83.02,75.81 82.8,75.58 81.83,75.58 81.3,75.06 81.3,74.2 79.35,72.25 78.27,72.25 73.09,67.07 73.09,61.03 88.92,45.19 88.92,43.76 89.19,43.49 89.54,43.49 90.01,43.95 90.17,43.95 90.37,43.74 90.37,43.58 89.91,43.12 89.91,42.77 90.25,42.43 90.6,42.43 91.07,42.89 91.23,42.89 91.44,42.68 91.44,42.52 90.97,42.06 90.97,41.71 91.31,41.37 91.67,41.37 92.13,41.83 92.29,41.83 92.5,41.62 92.5,41.46 92.03,41 92.03,40.65 97.62,35.06 97.62,27.14 97.24,26.76 97.24,25.03 97.51,24.76 97.51,24.62 v1(97.95,24.18)
  BOTTOM w0.127: DM1.152 97.95,24.18 v1(97.95,24.18) ; CPU1.AM58 83.15,75.81 v1(83.03,75.81)
M_A_DQS#3: length 68.4
  TOP w0.127: v1(58.42,29.46) v2(58.42,30.09)
  L4 w0.089: 81.12,71.6 81.14,71.6 81.16,71.62 82.59,71.62 83.17,72.2 83.9,72.2 84.28,72.2 85.47,73.4 85.47,76.07 85.37,76.17 85.22,76.17 84.94,75.89 v1(84.94,75.82)
  L4 w0.114: v1(58.42,29.46) 58.21,29.67 58.21,32.02 58.67,32.47 58.67,34.63 58.21,35.08 58.21,44.96 61.93,48.68 61.93,50.84 66.92,55.83 69.04,55.83 69.52,56.3 69.52,56.66 68.87,57.3 68.87,57.48 69.06,57.67 69.24,57.67 69.89,57.02 70.24,57.02 70.58,57.37 70.58,57.72 70.22,58.08 70.22,58.26 70.41,58.45 70.59,58.45 70.95,58.09 71.3,58.09 75.62,62.41 75.62,66.35 80.87,71.6 81.12,71.6
  BOTTOM w0.127: v1(58.42,29.46) 58.35,29.46 58.05,29.76 DM1.27 ; v1(84.94,75.82) 84.99,75.77 85.16,75.77 85.33,75.95 CPU1.AM55
M_A_DQS#4: length 65.8
  TOP w0.127: v1(103.27,29.46) v2(103.27,30.02)
  L3 w0.114: v1(80.03,68.16) 80.3,68.16 80.43,68.03 80.43,67.73 80.3,67.61 80.11,67.61 79.81,67.31 79.81,66.84 78.83,65.86 78.83,64.78 80.65,62.96 80.65,61.59 91.03,51.2 91.03,50.85 90.6,50.42 90.6,50.26 90.81,50.05 90.97,50.05 91.4,50.48 91.75,50.48 92.09,50.14 92.09,49.79 91.66,49.36 91.66,49.2 91.87,48.99 92.03,48.99 92.46,49.42 92.81,49.42 93.15,49.08 93.15,48.73 92.72,48.3 92.72,48.14 92.93,47.93 93.09,47.93 93.52,48.36 93.87,48.36 94.21,48.02 94.21,47.67 93.78,47.24 93.78,46.96 93.94,46.8 94.1,46.8 94.31,47 94.68,47 95,46.68 95,46.31 94.79,46.11 94.79,45.95 103.06,37.68 103.06,29.67 v1(103.27,29.46)
  BOTTOM w0.089: CPU1.AV57 84.11,72.74 83.92,72.74 83.74,72.56 83.74,71.68 83.72,71.63 83.67,71.5 83.67,71.3 83.74,71.15 83.74,70.91 83.41,70.58 83.41,70.13 82.45,69.17 82.1,69.17 80.75,67.82 80.08,67.82 79.96,67.95 79.96,68.08 v1(80.03,68.16)
  BOTTOM w0.127: DM1.169 103.05,30.26 103.48,29.84 103.48,29.66 v1(103.27,29.46)
M_A_DQS#5: length 63
  TOP w0.127: v1(63.85,29.46) v2(63.85,30.09)
  L4 w0.114: v1(63.85,29.46) 63.64,29.67 63.64,31.97 63.15,32.45 63.15,41.99 71.37,50.21 71.37,50.57 70.91,51.03 70.91,51.19 71.12,51.4 71.28,51.4 71.74,50.93 72.09,50.93 72.43,51.28 72.43,51.63 71.97,52.09 71.97,52.25 72.18,52.46 72.34,52.46 72.8,52 73.15,52 73.49,52.34 73.49,52.69 73.03,53.15 73.03,53.31 73.24,53.52 73.4,53.52 73.86,53.06 74.21,53.06 74.47,53.31 74.47,54.75 80.13,60.41 80.13,64.33 83.03,67.23 83.31,67.23 84.6,68.52 85.03,68.52 85.16,68.39 85.16,67.98 v1(84.99,67.8)
  BOTTOM w0.089: v1(84.99,67.8) 84.75,67.8 84.63,67.92 84.63,68.07 85.49,68.93 85.49,69.19 85.9,69.6 85.9,70.44 86.17,70.71 86.17,71.15 86.1,71.3 86.1,71.5 86.15,71.63 86.17,71.68 86.17,72.11 86.56,72.5 CPU1.AV53
  BOTTOM w0.127: v1(63.85,29.46) 63.54,29.46 63.45,29.55 DM1.45
M_A_DQS#6: length 71.2
  TOP w0.127: v1(68.55,24.18) 68.82,24.18 v2(69.14,23.87)
  L4 w0.089: v1(92.48,76.55) 92.81,76.55 92.87,76.49 92.87,75.68 92.58,75.39 92.09,75.39 91.58,74.88 91.58,74.45 91.23,74.1 91.14,74.1 91.12,74.12 91.1,74.12
  L4 w0.114: 91.1,74.12 90.91,74.12 89.49,72.7 89.49,69.59 85.45,65.55 85.45,58.24 76.14,48.93 76.14,47.5 75.95,47.31 75.79,47.31 75.33,47.77 74.98,47.77 74.64,47.43 74.64,47.08 75.1,46.62 75.1,46.46 74.89,46.25 74.73,46.25 74.27,46.71 73.92,46.71 73.58,46.37 73.58,46.02 74.04,45.56 74.04,45.4 73.83,45.19 73.67,45.19 73.31,45.55 72.94,45.55 72.62,45.23 72.62,44.86 72.98,44.5 72.98,44.34 68.15,39.51 68.15,26.24 67.88,25.97 67.88,25.16 68.11,24.93 68.11,24.62 v1(68.55,24.18)
  BOTTOM w0.127: v1(92.48,76.55) 92.73,76.8 CPU1.AL43 ; DM1.62 v1(68.55,24.18)
M_A_DQS#7: length 69.6
  TOP w0.127: v2(108.02,24.49) 107.69,24.82 v1(107.54,24.82)
  L3 w0.089: 89.88,71.24 89.88,71.26 89.86,71.28 89.86,72.85 89.18,73.54 89.18,74.67 89.22,74.71 89.22,76.47 89.32,76.57 89.55,76.57 v1(89.65,76.47)
  L3 w0.114: v1(107.54,24.82) 107.54,24.83 107.98,25.27 107.98,25.33 108.33,25.68 108.33,26.23 108.44,26.34 108.71,26.34 108.97,26.6 108.97,27.06 108.71,27.32 108.44,27.32 108.33,27.43 108.33,42.27 105.82,44.77 105.47,44.77 105,44.3 104.83,44.3 104.63,44.51 104.63,44.67 105.1,45.14 105.1,45.49 104.76,45.83 104.41,45.83 103.94,45.36 103.77,45.36 103.57,45.57 103.57,45.73 104.04,46.2 104.04,46.55 103.7,46.9 103.35,46.9 102.88,46.42 102.71,46.42 90.56,58.58 90.56,70.24 89.88,70.91 89.88,71.24
  BOTTOM w0.127: DM1.186 108.15,23.69 108.32,23.85 108.32,24.33 107.83,24.82 v1(107.54,24.82) ; v1(89.65,76.47) 89.97,76.8 CPU1.AL48
M_A_RAS#: length 59
  TOP w0.216: v1(85.35,24.18) 85.37,24.16 v2(85.37,23.61)
  L4 w0.216: v1(98.47,70.74) 99.02,70.74 101.22,68.54 101.22,46.1 98.14,43.03 98.14,41.36 92.9,36.12 91.38,36.12 88.32,33.06 88.32,32.16 86.66,30.5 86.66,27.73 86.88,27.52 87.12,27.52 87.32,27.31 87.32,26.85 87.12,26.65 86.88,26.65 86.66,26.43 86.66,25.29 85.55,24.18 v1(85.35,24.18)
  BOTTOM w0.216: v1(98.47,70.74) 98.82,71.09 CPU1.AY34 ; DM1.110 v1(85.35,24.18)
M_A_WE#: length 60.6
  TOP w0.216: v1(88.41,26.92) 88.67,26.92 v2(88.92,27.17)
  L4 w0.216: v1(98.47,71.41) 99.16,71.41 100.06,70.51 100.78,70.51 101.06,70.23 101.06,69.67 101.79,68.94 101.79,45.87 98.71,42.79 98.71,41.12 93.14,35.54 91.62,35.54 89.72,33.64 89.72,32.12 89.43,31.84 88.81,31.84 87.26,30.29 87.26,28.45 87.92,27.8 87.92,27.35 88.35,26.92 v1(88.41,26.92)
  BOTTOM w0.216: v1(88.41,26.92) 88.28,26.92 86.25,28.95 DM1.113 ; v1(98.47,71.41) 98.8,71.74 CPU1.AW34
M_VREF_CA_DIMMA: length 80.2
  TOP w1.016: 65.05,49.65 64.1,49.65 64.05,49.7 62.93,49.7 60.63,47.41 60.63,37.54 ; 60.78,35.2 60.78,33.87 59.29,32.38 53.61,32.38 51.75,30.52 51.75,27.39 50.25,25.88 50.25,23.33 51.76,21.82 64.02,21.82 v3(65.34,20.5)
  L3 w1.016: v3(90.12,24.33) 90.12,24.07 89.61,23.56 89.58,23.56 88.68,22.66 70.59,22.66 67.39,19.45 66.2,19.45 65.34,20.31 v3(65.34,20.5)
  BOTTOM w0.33: v3(90.12,24.33) 90.15,24.29 DM1.126
  vias: v2(67.16,50.59)
M_VREF_DQ_DIMMA: length 18.1
  TOP w0.508: 64.56,51.56 R3709.1
  TOP w0.762: 64.56,51.56 63.23,51.56 58.21,46.54 58.21,37.63
  vias: v2(51.08,35.42) v3(49.58,29.38)
MCP_GPIO11: length 18.6
  BOTTOM w0.089: 119.37,75.39 119.24,75.39 119.21,75.43 119.1,75.54 118.53,75.54 CPU1.AN2
  BOTTOM w0.102: 119.37,75.39 120.79,75.39 120.86,75.32 121.88,75.32 121.91,75.28 122.6,75.28 123.04,75.72 125.73,75.72 127.03,77.03 v2(127.03,77.26) 127.03,78.18 126.93,78.28 126.93,80.02 126.95,80.04 127.17,80.26 128.74,80.26 131.01,80.26 131.47,79.81 RN1809.5
MCP_GPIO12: length 24.4
  TOP w0.102: v1(115.55,76.62) 115.82,76.34 v2(116.13,76.34)
  L4 w0.102: v1(132.08,85.97) 132.08,85.04 131.75,84.71 131.75,83.7 130.82,82.78 130.82,82.46 129.22,80.85 126.34,80.85 125.58,80.09 123.96,80.09 122.81,78.94 121.44,78.94 120.45,77.95 120.13,77.95 119.46,77.95 118.49,76.98 118.49,76.88 118.14,76.53 116.22,76.53 116.13,76.62 v1(115.55,76.62)
  BOTTOM w0.102: v1(132.08,85.97) 132.65,85.41 RN1701.4 ; CPU1.AM7 115.48,76.62 v1(115.55,76.62)
MCP_GPIO13: length 13.1
  BOTTOM w0.089: CPU1.AT3 117.85,73.46 118.37,73.46 118.54,73.63 118.54,73.96 118.63,74.04 119.17,74.04 119.29,73.92
  BOTTOM w0.102: R2020.2 127.12,69.98 126.21,69.98 125.81,69.58 124.03,69.58 123.87,69.75 123.31,69.75 121.53,71.53 121.53,72.6 121.24,72.89 120.64,72.89 119.81,73.72 119.49,73.72 119.29,73.92
MCP_GPIO14: length 26.3
  TOP w0.102: v1(116.45,78.33) 116.64,78.15 117.15,78.15 117.34,77.96 118.21,77.96 118.71,77.45 119.17,77.45 119.37,77.65 119.85,77.65 119.99,77.51 121.39,77.51 121.42,77.55 122.41,77.55 122.67,77.81 123.07,77.81 123.7,77.18 123.7,75.49 121.99,73.78 121.99,71.56 123.56,69.99 125.85,69.99 126.74,70.88 126.74,70.88 127,71.14 127.38,71.14 127.58,70.93 127.58,69.65 v2(128.04,69.19) 127.88,69.04 127.41,69.04 126.26,67.89 R2016.2
  BOTTOM w0.102: v1(116.45,78.33) 116.57,78.21 CPU1.AH4
MCP_GPIO15: length 15
  L4 w0.102: v1(115.8,81.19) 116.29,81.68 117.6,81.68 119.15,83.23 119.96,83.23 119.99,83.25 122.05,83.25 124.72,85.92 125.18,85.92 125.69,85.92 125.8,86.03 v1(126.19,86.03)
  BOTTOM w0.102: v2(125.26,86.36) 125.58,86.03 v1(126.19,86.03) 126.74,86.03 R2014.2 ; v1(115.8,81.19) 115.61,80.99 CPU1.AD6
MCP_GPIO26: length 12.3
  TOP w0.102: v1(120.84,74.62) 121.38,74.08 121.38,71.31 121.49,71.2 121.49,69.99 122.62,68.86 122.62,68.19 v2(122.82,67.99) 123.7,68.87 R2009.2
  BOTTOM w0.089: CPU1.AN3 117.84,74.97 119.02,74.97 119.02,74.97 119.53,74.97 119.53,74.96 120.37,74.96 120.64,74.69 120.77,74.69 v1(120.84,74.62)
MCP_GPIO27: length 24.6
  L4 w0.102: v1(131.86,86.62) 132.36,86.62 132.51,86.47 132.51,85.11 131.95,84.56 131.95,83.62 131.03,82.69 131.03,82.37 129.3,80.65 126.81,80.65 125.28,79.11 125.12,79.11 125.02,79.21 125.01,79.21 124.76,79.47 124.76,79.47 124.53,79.7 124.13,79.7 123.17,78.74 121.5,78.74 120.52,77.76 120.05,77.76 119.54,77.76 119.13,77.35 119.13,77.25 118.22,76.34 116.92,76.34 v1(116.46,75.88)
  BOTTOM w0.102: v1(131.86,86.62) 132.04,86.8 RN2006.3 ; CPU1.AN5 116.23,75.87 116.46,75.87 v1(116.46,75.88)
MCP_GPIO28: length 26.8
  TOP w0.102: R2017.2 132.65,68.83 130.37,68.83 130.07,69.14 129.73,69.14 128.63,70.24 128.63,73.64 128.05,74.21 128.05,74.4 124.61,77.84 124.44,77.84 123.44,78.85 122.31,78.85 122.18,78.72 120.99,78.72 119.61,80.09 119.61,80.85 v2(119.38,81.08) 117.93,81.08 117.92,81.08 116.96,81.08 116.58,80.7 115.44,80.7 115.16,80.98 v1(115.16,81.19)
  BOTTOM w0.102: CPU1.AD7 114.96,80.99 v1(115.16,81.19)
MCP_GPIO36: length 13.6
  TOP w0.102: v2(116.81,83.58) 116.25,83.58 v1(115.79,84.04) ; RN1902.4 124.09,90.02 123.42,89.35 v1(123.19,89.35)
  L4 w0.102: v1(115.79,84.04) 115.79,84.13 116.78,85.13 116.81,85.13 116.98,85.3 118.22,85.3 118.87,85.94 118.87,86.6 119.44,87.17 119.87,87.17 119.96,87.08 120.92,87.08 v1(123.19,89.35)
  BOTTOM w0.102: CPU1.V6 115.79,83.75 v1(115.79,84.04)
MCP_GPIO44: length 18.3
  TOP w0.102: v1(122.07,76.35) 121.84,76.12 121.84,74.73 121.73,74.62 121.73,74.1 121.58,73.95 121.58,71.39 121.73,71.24 121.73,71.18 123.47,69.44 125.76,69.44 126.09,69.11 126.09,68.33 125.44,67.68 R2002.2
  BOTTOM w0.089: v1(122.07,76.35) 121.77,76.35 120.81,77.31 v2(120.8,77.31) 120.8,77.32 120.35,77.77 120.13,77.77 120.07,77.83 119.27,77.83 119.24,77.79 117.94,77.79 117.91,77.83 117.23,77.83 CPU1.AK4
MCP_GPIO56: length 27.1
  TOP w0.102: R2004.2 132.54,66.97 132.54,68.44 132.36,68.63 130.29,68.63 129.99,68.93 129.64,68.93 128.37,70.2 128.37,73.55 127.81,74.11 127.81,74.3 124.51,77.6 124.34,77.6 123.36,78.58 122.34,78.58 122.23,78.46 120.9,78.46 120.71,78.65 120.4,78.65 120.24,78.49 119.33,78.49 119.05,78.77 119.05,78.84 119.02,78.87 119.02,79.67 v2(118.6,80.09) 118.16,79.65 116.76,79.65 116.69,79.73 116.25,79.73 v1(115.8,79.28)
  BOTTOM w0.102: v1(115.8,79.28) 115.61,79.09 CPU1.AG6
MCP_GPIO57: length 14.2
  BOTTOM w0.102: CPU1.AP1 119.3,74.5 119.67,74.14 120.6,74.14 121.8,72.94 121.8,71.54 123.39,69.95 123.95,69.95 124.11,69.79 125.73,69.79 126.13,70.19 127.32,70.19 127.75,70.61 128.84,70.61 v2(128.98,70.47) 129.14,70.31 R2022.2
MCP_GPIO58: length 15.1
  TOP w0.102: R2001.2 121.83,66.75 v2(121.75,66.82) 121.7,66.87 121.7,67.35 121.89,67.53 121.89,68.62 118.69,71.82 118.69,73.4 118.79,73.5 118.79,77 118.21,77.59 117.7,77.59 v1(117.24,77.13)
  BOTTOM w0.102: v1(117.24,77.13) 117.24,77.01 CPU1.AL4
MCP_GPIO73: length 19.2
  BOTTOM w0.089: 117.99,70.81 117.95,70.85 117.95,71.35 117.9,71.4 117.9,71.91 117.71,72.1 117.46,72.1 117.27,72.28 117.27,72.54 116.92,72.9 CPU1.AU4
  BOTTOM w0.102: 117.99,70.81 118.18,70.62 119.28,70.62 121.17,68.73 122.42,68.73 122.72,68.42 123.89,68.42 124.08,68.62 124.65,68.62 125.87,67.39 129.96,67.39 v2(130.18,67.61) 130.32,67.61 131.02,68.32 131.21,68.32 131.61,68.72 RN1601.6
MCP_GPIO76: length 10.5
  BOTTOM w0.102: CPU1.P1 119.12,85.74 119.21,85.84 119.59,85.84 119.59,85.83 120.09,85.83 120.51,86.25 120.51,86.77 122.58,88.84 v2(122.91,88.84) 123.77,88.84 124.79,89.86 125.5,89.86 126.42,90.78 RN1801.8
MCP_R: length 23.7
  TOP w0.102: R2004.1 133.23,67.02 133,67.25 R2017.1 133.35,67.6 R2013.1 133.84,68.35 v1(134.26,68.78) 134.52,69.03 v2(134.82,69.03) ; R2016.1 R2002.1 125.39,66.75 R2001.1 123.54,67.08 123.66,67.2 124.33,67.2 124.9,67.77 124.9,68.2 124.71,68.4 R2009.1 125.6,68.87 v1(125.65,68.82)
  L4 w0.102: v1(134.26,68.78) 133.4,67.91 129.15,67.91 128.56,67.32 127.15,67.32 v1(125.65,68.82)
  BOTTOM w0.102: R2022.1 128.25,69.45 127.62,68.82 R2020.1 127.05,68.29 126.18,68.29 v1(125.65,68.82)
MCP_TESTLOW1: length 6
  BOTTOM w0.089: CPU1.C35 97.76,92.67 97.68,92.73 97.59,92.92 97.56,93.08 97.58,93.17 97.58,93.19 97.58,93.19 97.64,93.33 97.64,93.43 97.57,93.6 97.29,93.88 97.29,94.05 97.29,94.05
  BOTTOM w0.102: RN1803.4 96.39,97.26 96.72,96.94 v2(96.72,96.56) 96.72,96.42 97.29,95.85 97.29,94.05
MCP_TESTLOW2: length 6.6
  BOTTOM w0.089: CPU1.C34 98.25,92.67 97.92,92.77 97.87,92.81 97.82,92.85 97.76,92.97 97.75,93.01 97.75,93.15 97.82,93.29 97.82,93.47 97.68,93.8 97.48,94
  BOTTOM w0.102: 97.48,94 97.48,94.56 97.8,94.88 v2(97.8,95.59) 97.8,95.87 97.04,96.62 RN1803.3
MCP_TESTLOW3: length 13.9
  TOP w0.102: RN1804.3 117.37,66.68 117.09,66.96 117.09,67.4 116.35,68.14 116.35,68.89 115.14,70.11 v2(115.14,71.07) 115.14,71.25 114.7,71.68 114.7,72.94 114.87,73.11 114.87,75.9 114.17,76.61 114.17,76.65 v1(113.89,76.92)
  BOTTOM w0.102: CPU1.AK8 114.23,77.26 v1(113.89,76.92)
MCP_TESTLOW4: length 13.3
  TOP w0.102: v1(113.84,76.29) 114.19,76.29 114.67,75.82 114.67,73.24 114.5,73.07 114.5,70.36 115.16,69.7 v2(115.16,69.55) 115.7,69.01 115.7,67.96 116.72,66.94 RN1804.4
  BOTTOM w0.102: CPU1.AL8 114.16,76.61 v1(113.84,76.29)
MCT0: length 12.8
  TOP w0.254: RN3101.1 23.58,49.39 23.96,49.78
  TOP w0.508: XF3102.3 22.61,57.73 23.96,56.37 23.96,49.78
MCT1: length 8.3
  TOP w0.254: 22.93,49.89 RN3101.2
  TOP w0.508: 22.93,49.89 22.93,53.48 22.49,53.92 XF3102.4
MCT2: length 13.4
  TOP w0.254: v3(22.3,49.45) 22.43,49.33 RN3101.3
  BOTTOM w0.508: XF3101.4 22.82,57.73 23.88,56.67 23.88,51.03 v3(22.3,49.45)
MCT3: length 9.1
  TOP w0.254: v3(21.4,49.44) 21.78,49.06 RN3101.4
  BOTTOM w0.508: XF3101.3 22.5,53.92 22.92,53.5 22.92,51.38 21.4,49.86 v3(21.4,49.44)
MDO0+: length 15.2
  TOP w0.102: AFTP3107.1 16.33,57.94 15.14,59.13 RJ45.1
  BOTTOM w0.102: RJ45.1 14.93,59.13 18.49,55.57 18.49,52.27 18.87,51.88 19.15,51.88 19.26,51.78 19.26,51.48 19.36,51.38 XF3101.1
MDO0-: length 15.3
  TOP w0.102: AFTP3102.1 16.88,58.28 16.36,58.28 15.43,59.2 15.4,59.23 RJ45.2
  BOTTOM w0.102: RJ45.2 15.15,59.9 15.15,59.26 18.74,55.67 18.74,52.37 18.98,52.14 19.15,52.14 19.26,52.24 19.26,52.54 19.36,52.65 XF3101.2
MDO1+: length 12
  TOP w0.102: RJ45.3 14.31,61.16 AFTP3101.1
  BOTTOM w0.102: XF3101.5 19.36,59 19.26,59.1 19.26,59.4 19.15,59.5 18.74,59.5 18.49,59.76 18.49,60.77 17.47,61.79 16.2,61.79 15.58,61.17 RJ45.3
MDO1-: length 11.4
  TOP w0.102: AFTP3106.1 16.68,64.23 RJ45.6
  BOTTOM w0.102: RJ45.6 15.4,63.48 16.84,62.04 17.58,62.04 18.74,60.88 18.74,59.86 18.85,59.76 19.15,59.76 19.26,59.86 19.26,60.16 19.36,60.27 XF3101.6
MDO2+: length 16.5
  TOP w0.102: 18.04,55.21 18.04,61.5 16.49,63.05 15.34,63.05 15.17,62.88 15.17,62.42 RJ45.4 ; 18.04,55.21 18.04,52.89 19.05,51.88 19.76,51.88 20.27,51.38 XF3102.6 ; 18.04,55.21 AFTP3103.1
MDO2-: length 16.6
  TOP w0.102: 18.29,57.08 18.29,61.61 16.6,63.3 14.39,63.3 RJ45.5 ; 18.29,57.08 18.29,53 19.15,52.14 19.76,52.14 20.27,52.65 XF3102.5 ; 18.29,57.08 AFTP3104.1
MDO3+: length 12.6
  TOP w0.102: 17.6,65.42 18.07,65.42 19.17,64.32 19.17,62.47 18.81,62.1 18.81,59.9 19.07,59.63 19.31,59.63 19.95,59 XF3102.2 ; 17.6,65.42 16.27,65.42 16,65.15 15.15,65.15 15.05,65.25 RJ45.7 ; 17.6,65.42 AFTP3105.1
MDO3-: length 12.5
  TOP w0.102: 19.43,63.68 19.43,64.43 18.18,65.68 16.17,65.68 15.9,65.41 15.25,65.41 15.08,65.58 15.08,65.95 RJ45.8 ; 19.43,63.68 AFTP3108.1 ; 19.43,63.68 19.43,62.36 19.06,62 19.06,60 19.18,59.89 19.54,59.89 19.93,60.27 XF3102.1
ME_UNLOCK: length 91.5
  TOP w0.102: v1(175.36,32.51) 175.78,32.93 176.29,32.93 176.73,32.5 KBC24.23 ; v1(115.9,57.14) 116.11,57.35 116.11,60.25 115.44,60.91 v2(115.44,60.95) 115.17,61.22 114.39,61.22 111.57,64.04 R1909.1
  L4 w0.102: v1(115.9,57.14) 116.24,57.48 119.6,57.48 120.63,56.46 120.95,56.46 121.21,56.71 121.56,56.71 121.89,56.38 126.7,56.38 128.42,54.67 128.88,54.67 129.42,54.13 129.42,53.39 129.96,52.86 131.26,51.55 131.26,47.24 133.47,45.03 133.47,43.71 134.81,42.38 139.65,42.38 139.75,42.27 140.34,41.69 141.61,41.69 144.12,39.18 144.47,39.18 145.76,37.9 146.61,37.9 147.22,37.29 147.77,37.29 149.03,36.04 149.03,33.47 151.95,30.54 154.44,30.54 v1(155.1,31.2)
  BOTTOM w0.102: v1(175.36,32.51) 175.26,32.51 174.05,33.72 172.54,33.72 171.19,35.07 165.94,35.07 164.61,33.74 159.78,33.74 159.33,34.2 158,34.2 155.1,31.29 v1(155.1,31.2)
MIC2_VREFO: length 16.5
  TOP w0.203: HDA27.29 31.26,11.34 31.01,11.59 v1(30.68,11.59)
  TOP w0.254: RN2901.1 35.55,18.34 35.28,18.61 v1(35.1,18.61) 34.9,18.41 RN2901.2
  BOTTOM w0.254: v1(35.1,18.61) 35.1,18.2 35.58,17.72 v2(35.58,17.7) 35.6,17.7 37.18,16.12 37.18,14.61 36.44,13.87 33.17,13.87 30.89,11.59 v1(30.68,11.59)
MIC_CAP: length 4.5
  TOP w0.203: v2(33.81,16.3) 33.91,16.3 34.72,15.49 34.72,15.47 35.43,14.76 HDA27.19
  TOP w0.254: v2(33.81,16.3) 33.53,16.58 C2713.1
MIC_GND: length 3.3
  TOP w0.305: LCD1.26 34.45,82.95 33.98,82.48 R5201.1 33.98,80.82 v2(34.3,80.51)
MODEL_ID_DET: length 9.3
  TOP w0.102: R2446.2 R2405.2 160.53,19.33 v2(159.66,20.2) 159.41,20.46 R2445.2 158.88,21.88 158.88,22.52 R2407.1 C2403.2 161.1,23.85 161.1,24.24 161.36,24.5 KBC24.94
MPWROK: length 40.4
  L3 w0.127: v1(116.44,82.14) 116.64,81.94 117.2,81.94 117.24,81.89 118.17,81.89 118.36,81.71 119.94,81.71 120.77,82.54 123.01,82.54 123.75,81.81 125.39,81.81 125.73,81.46 125.73,79.22 124.73,78.22 119.94,78.22 118.55,76.82 118.55,64.08 118.68,63.95 v1(118.68,61.13)
  BOTTOM w0.102: CPU1.AB5 116.26,81.96 v1(116.44,82.14)
  BOTTOM w0.127: R1707.2 119.74,61.76 120.01,62.03 120.01,62.42 v2(119.84,62.59) 119.46,62.59 118.68,61.81 v1(118.68,61.13)
MUTE_CTRL: length 19.2
  TOP w0.102: v1(38.37,18.63) 38.4,18.63 40,20.23 42.38,20.23 42.67,20.52 43.26,20.52 v2(43.36,20.42) 43.36,18.15 R2918.2 42.91,17.67 C2901.1 41.74,16.81 R2917.2
  BOTTOM w0.102: v1(38.37,18.63) 37.91,19.08 33.26,19.08 32.99,18.81 32.99,17.85 32.62,17.48 U2901.2
N12P_JTAG_TCK: length 6.6
  TOP w0.102: RN7602.4 154.61,106.82 v2(154.91,106.52) 156,106.52 157.38,107.9 157.72,107.9 158.12,107.5 v1(158.39,107.5)
  BOTTOM w0.102: v1(158.39,107.5) 158.75,107.86 GPU1.AE5
N12P_JTAG_TDI: length 1.3
  TOP w0.102: TP7605.1 158.34,109.62 158.34,109.21 158.33,109.2 v1(158.33,109.2)
  BOTTOM w0.102: v1(158.33,109.2) 158.33,109.2 158.74,108.79 GPU1.AE6
N12P_JTAG_TDO: length 1.2
  TOP w0.102: v1(157.55,109.19) 157.55,109.14 TP7601.1
  BOTTOM w0.102: v1(157.55,109.19) 157.55,109.19 GPU1.AF6
N12P_JTAG_TMS: length 1.2
  TOP w0.102: v1(159.17,109.19) 159.46,108.9 TP7602.1
  BOTTOM w0.102: v1(159.17,109.19) 159.17,109.18 159.55,108.8 GPU1.AD6
N12P_JTAG_TRST: length 5.7
  TOP w0.102: v1(157.55,107.49) 157.54,107.49 156.78,106.74 v2(156.77,106.74) 156.77,106.73 155.91,105.86 154.33,105.86 154.02,106.17 RN7602.3
  BOTTOM w0.102: v1(157.55,107.49) GPU1.AG4
N12P_XTAL_OUTBUFF: length 5
  TOP w0.102: v1(176.58,112.48) 177.13,111.93 177.51,111.93 177.89,112.31 178.4,112.31 v2(178.56,112.47) 178.56,112.62 178.21,112.98 R7602.1 178.94,113.42 R7617.2
  BOTTOM w0.102: GPU1.C10 176.95,112.07 176.58,112.44 v1(176.58,112.48)
NCT7718_DXN: length 136.8
  TOP w0.254: Q2603.E 46.91,33.45 46.91,36.88 C2606.2 46.93,36.91 44.48,39.36 44.48,47.21 63.97,66.7 63.97,78.62 59.63,82.96 59.63,94.58 v1(59.76,94.7) ; 108.66,111.4 110.72,111.4 111.22,110.89 113.22,110.89 114.23,109.88 C2607.2 114.51,109.83 THM26.3 ; 108.66,111.4 107.7,111.4 v1(107.61,111.3) ; 108.66,111.4 v2(108.66,111.19)
  L4 w0.254: v1(107.61,111.3) 106.98,111.3 105.7,110.02 100.39,110.02 99.57,109.21 95.7,109.21 93.26,106.77 74.86,106.77 74.32,106.24 72.84,106.24 67.96,101.36 66.38,101.36 60.77,95.75 60.22,95.75 59.68,95.2 59.68,94.79 v1(59.76,94.7)
NCT7718_DXP: length 137.9
  TOP w0.254: 110.59,111.9 110.93,111.9 111.43,111.4 113.43,111.4 114.06,110.77 C2607.1 114.75,110.48 THM26.2 ; 110.59,111.9 v2(110.59,112.16) ; 110.59,111.9 107.65,111.9 v1(107.62,111.94) ; Q2603.B 46,34.37 Q2603.C 46,36.53 C2606.1 45.62,37.5 43.97,39.14 43.97,47.42 63.46,66.91 63.46,78.41 59.13,82.75 59.13,94.62 v1(59.03,94.72)
  L4 w0.254: v1(107.62,111.94) 107.49,111.81 106.77,111.81 105.49,110.53 100.17,110.53 99.36,109.72 95.49,109.72 93.05,107.28 74.65,107.28 74.11,106.74 72.63,106.74 67.75,101.86 66.17,101.86 60.56,96.25 60.01,96.25 59.17,95.41 59.17,94.86 v1(59.03,94.72)
ODD_PWR_5V: length 10.6
  TOP w0.381: ODD1.2 200.75,83.09 ; ODD1.2 201.49,82.35 ; ODD1.2 200.75,81.61 ; ODD1.2 200.01,82.35 ; 201.51,83.35 ODD1.3 ; ODD1.3 202.25,84.09 ; ODD1.3 202.25,82.61
  BOTTOM w0.381: ODD1.2 200.75,83.09 ; ODD1.2 200.01,82.35 ; ODD1.2 200.75,81.61 ; ODD1.2 201.49,82.35 ; 202.25,84.09 ODD1.3 202.25,82.61
  BOTTOM w0.508: 201.27,83.35 ODD1.3
  vias: v2(197.36,82.64)
OVER_CURRENT_P8#: length 126
  TOP w0.102: v1(188.83,108.66) 188.71,108.66 185.22,105.17 183.19,105.17 182.88,104.86 181.67,104.86 181.43,105.1 180.98,105.1 177.14,101.26 177.14,101.18 176.82,100.87 D7602.K ; KBC24.95 163.81,24.1 165.99,26.28 165.99,26.3 170.87,31.18 170.87,32.7 172.06,33.9 174.74,33.9 174.77,33.93 v1(175.89,33.93)
  L3 w0.102: v1(188.83,108.66) 188.83,104.87 187.03,103.08 187.03,99.56 190.68,95.91 191.38,95.91 192.63,94.66 192.63,92.22 191.35,90.94 191.35,85.32 192.14,84.53 192.14,80.35 193.14,79.34 193.14,75.71 192.59,75.16 192.55,75.16 192.05,74.65 192.05,63.47 188.58,60.01 188.58,45.25 187.74,44.41 187.74,43.7 182.55,38.51 182.55,35.37 181.53,34.36 180.54,34.36 179.78,35.12 178.13,35.12 176.81,33.8 176.02,33.8 v1(175.89,33.93)
  BOTTOM w0.102: v1(175.89,33.93) 176.1,34.13 176.17,34.13 176.27,34.23 v2(176.68,34.23)
OVERT#: length 8.2
  BOTTOM w0.127: v2(189.94,102.51) 189.57,102.14 C7609.1 188.73,102.3 R7645.2 186.95,102.35 185.69,103.62 Q7602.4 184.91,103.6 R7613.2 182.94,102.88 R7652.1
OVERT_GPU#: length 8.3
  BOTTOM w0.127: GPU1.A6 179.79,108.79 v2(180.54,108.04) 180.54,107.67 180.35,107.48 180.35,106.99 180.63,106.71 180.63,104.21 R7652.2
P2800_VGA_DXN: length 1.9
  TOP w0.254: v1(175.76,113.31) 175.77,113.31 175.77,113.36 176.36,113.95 TP7603.1
  BOTTOM w0.254: GPU1.E12 175.37,113.75 175.76,113.35 v1(175.76,113.31)
P2800_VGA_DXP: length 1.2
  TOP w0.254: v1(174.9,113.35) 175.09,113.54 TP7604.1
  BOTTOM w0.254: GPU1.F12 174.51,113.74 v1(174.9,113.35)
P_H_S#: length 3.7
  BOTTOM w0.102: Q7602.3 186.81,103.37 187.4,102.79 188.44,102.79 v2(188.82,103.17) 188.94,103.28 R7653.1
PANEL_SIZE_ID: length 105.2
  L3 w0.102: v1(115.86,88.1) 115.78,88.1 114.83,87.14 114.83,86.78 115.08,86.53 115.38,86.53 115.71,86.21 115.71,85.85 115.38,85.52 114.25,85.52 113.09,84.36 112.53,84.36 112.16,83.99 112.16,83.46 112.23,83.39 112.23,81.92 113.87,80.28 113.87,79.07 113.46,78.67 113.46,76.77 113.4,76.71 113.4,75.78 113.17,75.55 113.17,73.64 112.74,73.21 106.32,73.21 103.73,75.81 103.73,76.43 101.78,78.39 101.78,78.94 99.78,80.93 81.39,80.93 80.42,81.9 77.65,81.9 77.29,81.54 71.69,81.54 71.45,81.3 63.03,81.3 v1(62.96,81.36)
  BOTTOM w0.102: CPU1.J2 117.85,88.35 116.69,88.35 116.44,88.1 v1(115.86,88.1) ; v1(62.96,81.36) 61.3,83.02 43.49,83.02 v2(42.85,83.66) 40.27,86.24 R5208.2 R5209.1 R5210.2
PANEL_SIZE_ID_CONN: length 2.6
  TOP w0.102: v1(36.4,84.52) 36.45,84.47 LCD1.22
  BOTTOM w0.102: v2(36.75,83.94) 36.4,84.29 v1(36.4,84.52) 36.27,84.65 R5210.1
PBAT_PRES1#: length 1.9
  TOP w0.102: RN4301.8 130.39,150.3 AFTP3902.1
PBAT_SMBCLK1: length 2.9
  TOP w0.14: RN4301.6 131.54,150.19 132.48,151.13 133.49,151.13 AFTP3904.1
PBAT_SMBDAT1: length 1.7
  TOP w0.14: AFTP3903.1 131.52,150.91 131.04,150.43 RN4301.7
PCB_VER_AD: length 6.8
  TOP w0.102: R2404.2 163.12,19.08 163.12,18.57 163.33,18.37 v2(163.54,18.37) 164.01,18.83 C2402.2 R2406.1 164.97,19.83 164.97,20.84 164.64,21.18 164.21,21.18 164.09,21.3 KBC24.98
PCH_DPWROK: length 16.7
  BOTTOM w0.089: 116.66,69.78 116.59,69.85 116.59,69.94 116.48,70.05 116.48,70.41 115.98,70.9 115.98,72.14 CPU1.AV5
  BOTTOM w0.127: R1718.1 124.87,62.47 R1704.1 124.25,62.47 123.34,63.37 121.12,63.37 120.65,63.84 120.65,64.14 119.16,65.64 v2(119.16,66.49) 119.16,67.97 117.84,69.29 117.15,69.29 116.66,69.78
PCH_HDMI_CLK: length 143.4
  TOP w0.14: Q5402.4 15.52,81.39 15.67,81.54 v1(15.67,81.83)
  L4 w0.127: v1(119.59,102.28) 119.71,102.4 119.71,103.36 120.3,103.95 120.3,105.01 119.52,105.78 115.74,105.78 112.9,102.93 111.29,102.93 109.33,100.97 108.37,100.97 108.35,100.98 103.23,100.98 103.23,100.98 101.84,100.98 101.56,100.71 99.88,100.71 99.43,100.26 98.54,100.26 98.32,100.49 97.53,100.49 97.03,99.98 95.35,99.98 94.38,100.95 93.05,100.95 89.31,104.69 89.31,104.69 89.07,104.93 77.08,104.93 75.6,103.45 71.92,103.45 68.69,100.21 67.07,100.21 60.55,93.69 51.86,93.69 45.24,87.07 37.34,87.07 34.26,90.15 24.97,90.15 19.77,84.95 19.77,80.87 19.35,80.45 16.85,80.45 15.67,81.62 v1(15.67,81.83)
  BOTTOM w0.089: 114.34,95.08 114.32,95.07 114.32,94.83 113.79,94.3 113.79,93.6 113.26,93.07 CPU1.B9
  BOTTOM w0.14: 119.72,99.9 118.32,98.49 117.04,98.49 116.84,98.29 RN1501.4 116.84,97.33 116.91,97.27 116.91,96.67 116.35,96.12 115.37,96.12 114.34,95.08 ; 119.72,99.9 v2(119.61,100.02) ; 119.72,99.9 120.63,100.8 120.63,101.26 120.3,101.58 120.19,101.58 119.59,102.19 v1(119.59,102.28)
PCH_HDMI_DATA: length 141.9
  TOP w0.14: Q5402.1 18.08,79.94 v1(19.11,80.97)
  L4 w0.127: v1(120.26,102.26) 120.22,102.31 120.22,103.15 120.8,103.74 120.8,105.22 119.73,106.29 115.53,106.29 112.68,103.44 111.08,103.44 109.12,101.48 108.58,101.48 108.56,101.49 101.63,101.49 101.35,101.22 99.67,101.22 99.22,100.77 98.76,100.77 98.53,100.99 97.32,100.99 96.81,100.49 95.56,100.49 94.59,101.46 93.26,101.46 89.82,104.9 89.28,105.44 76.87,105.44 75.38,103.95 71.71,103.95 68.48,100.72 66.86,100.72 60.34,94.2 51.65,94.2 45.03,87.58 37.55,87.58 34.47,90.65 24.76,90.65 19.27,85.16 19.27,81.13 v1(19.11,80.97)
  BOTTOM w0.089: 114.71,94.71 114.69,94.7 114.46,94.7 113.98,94.22 113.98,93.52 113.54,93.08 113.54,93.07 113.54,93.07 CPU1.C9
  BOTTOM w0.14: v2(118.92,98.14) 118.81,98.25 ; 118.81,98.25 118.53,97.97 117.57,97.97 RN1501.3 117.49,97.33 117.43,97.27 117.43,96.46 116.57,95.59 115.59,95.59 114.71,94.71 ; 118.81,98.25 121.15,100.58 121.15,101.47 120.36,102.26 v1(120.26,102.26)
PCH_INTVRMEN: length 13.1
  BOTTOM w0.089: 117.54,66.67 116.77,67.43 116.77,68.07 115.99,68.85 115.67,68.85 114.48,70.04 114.48,72.14 CPU1.AV7
  BOTTOM w0.102: R1903.2 118.36,61.95 118.73,62.32 R1913.2 118.73,63.4 117.7,64.43 117.7,66.5 v2(117.69,66.52) 117.54,66.67
PCH_JTAG_TCK: length 6.6
  BOTTOM w0.089: CPU1.AE62 80.72,79.74 80.43,79.55 80.34,79.51 80.3,79.5 80.24,79.5 80.19,79.51 80,79.59 79.96,79.62 79.96,79.62 79.86,79.71 77.21,79.71
  BOTTOM w0.114: 77.21,79.71 76.81,79.32 v2(75.59,79.32) 75.31,79.32 75.12,79.5 R1920.2
PCH_JTAG_TDI: length 8.1
  BOTTOM w0.089: CPU1.AD61 81.32,80.83 80.78,80.83 80.59,80.63 80.59,80.44 80.4,80.25 80,80.25 80,80.25 78.1,80.25 77.57,80.78
  BOTTOM w0.114: 77.57,80.78 v2(77.3,81.05) 77.14,81.2 76.89,81.2 76.11,81.98 R1916.1
PCH_JTAG_TDO: length 7.4
  BOTTOM w0.089: CPU1.AE61 81.23,79.42 80.65,79.42 80.51,79.39 80.39,79.34 80.33,79.33 80.21,79.33 80.18,79.33 80.09,79.35 79.95,79.39 79.57,79.54 78.6,79.54 78.58,79.52
  BOTTOM w0.114: R1917.1 74.79,78.8 v2(76.76,78.8) 76.79,78.8 77.22,79.23 78.29,79.23 78.58,79.52
PCH_JTAG_TMS: length 7
  BOTTOM w0.089: 77.12,80.44 77.54,80.44 77.91,80.07 80.03,80.07 80.04,80.08 80.47,80.08 80.92,80.52 CPU1.AD62
  BOTTOM w0.114: R1918.1 74.83,81.32 v2(75.59,81.32) 76.24,81.32 77.12,80.44
PCH_JTAG_TRST#: length 4.9
  BOTTOM w0.089: 79.92,72.71 80.54,72.71 80.88,73.05 CPU1.AU62
  BOTTOM w0.114: TP1901.1 78.01,70.81 79.92,72.71
PCH_OPIRCOMP: length 4.9
  BOTTOM w0.102: CPU1.AW15 110.27,71.53 109.63,70.89
  BOTTOM w0.508: 109.63,70.89 109.46,70.72 109.46,70.11 v2(108.37,69.02) 108.38,69 R2003.1
PCH_PWROK: length 122.6
  TOP w0.127: v1(158.01,21) 157.67,20.65 Q2602.G ; Q3601.3 114.32,9.2 114.72,9.6 v1(115.32,9.6) ; KBC24.100 164.89,21.35 165.31,20.93 v1(165.4,20.93)
  L3 w0.127: v1(165.4,20.93) 164.89,20.93 164.66,21.16 164.29,21.16 163.47,20.33 159.5,20.33 158.83,21 v1(158.01,21) ; v1(115.32,9.6) 115.32,10.15 113.76,11.7 111.55,11.7 110.58,12.67 110.58,15.95 114.32,19.69 114.32,28.11 114.73,28.53 114.73,39.91 117.75,42.93 117.75,48.17 122.2,52.62 122.2,55.46 v1(121.38,56.28)
  L4 w0.127: v1(115.32,9.6) 118.83,9.6 121.1,11.87 137.54,11.87 138.83,10.58 141.17,10.58 141.66,11.07 147.03,11.07 147.33,11.37 v1(148.81,11.37)
  BOTTOM w0.127: v1(121.38,56.28) 121.38,57.9 121.07,58.22 121.07,59.23 EC1704.1 119.73,60.56 R1706.1 ; v1(158.01,21) 158.01,19.09 157.01,18.08 v2(154.48,18.08) 154.21,18.08 148.79,12.67 148.79,11.39 v1(148.81,11.37)
PCH_SLP_S0#: length 8.3
  BOTTOM w0.089: 120.98,79.27 120.68,79.27 120.34,79.6 119.79,79.6 119.73,79.67 119.25,79.67 119.05,79.46 118.02,79.46 117.77,79.71 CPU1.AF3
  BOTTOM w0.127: TP1706.1 123.43,78.25 123.05,78.25 122.7,78.6 121.94,78.6 121.27,79.27 120.98,79.27
PCH_SLP_WLAN#: length 1.4
  TOP w0.127: v1(115.55,75.97) 115.41,75.97 TP1705.1
  BOTTOM w0.102: CPU1.AM5 115.87,76.29 v1(115.55,75.97)
PCH_SMBCLK: length 113
  L3 w0.127: v1(119.31,39.07) 119.4,38.97 120.82,38.97 124.14,42.3 124.14,47.69 130.82,54.38 130.82,56.57 134.35,60.09 134.35,64.87 132.86,66.35 132.86,66.47 131.14,68.2 130.76,68.2 129.87,69.08 v1(129.87,69.61)
  L4 w0.127: v1(135.33,96.21) 135.06,95.94 135.06,94.44 135.84,93.67 135.84,92.3 136.68,91.45 136.68,89.41 135.36,88.09 135.36,84.35 134.29,83.27 134.29,69.9 132.69,68.3 130.04,68.3 129.63,68.72 129.63,69.36 v1(129.87,69.61)
  BOTTOM w0.14: RN9601.2 130.11,79.05 129.75,78.69 129.75,77.77 ; DM1.202 112.95,21.38 113.23,21.1 115.3,21.1 116.45,22.25 116.45,33.64 117.41,34.6 117.41,38.04 118.35,38.99 119.23,38.99 v1(119.31,39.07) ; 129.75,77.77 129.75,77 129.54,76.79 RN1810.3 129.46,76.22 128.91,76.22 127.81,75.12 127.81,73.52 127.68,73.39 127.68,71.92 127.88,71.73 Q1801.4 128.42,71.21 128.57,71.06 129.18,71.06 129.63,70.62 129.63,70.36 129.96,70.02 129.96,69.7 v1(129.87,69.61) ; 129.75,77.77 v2(129.54,77.77) ; R6204.1 133.87,96.87 EC6206.1 135.27,96.21 v1(135.33,96.21)
PCH_SMBDATA: length 115.9
  L3 w0.127: v1(130.49,69.33) 130.49,69.19 130.97,68.7 131.35,68.7 133.37,66.68 133.37,66.56 134.85,65.08 134.85,59.88 131.33,56.36 131.33,54.17 124.65,47.48 124.65,42.09 121.03,38.47 119.42,38.47 v1(119.31,38.35)
  L4 w0.127: v1(130.49,69.33) 130.33,69.33 130.13,69.14 130.13,68.93 130.25,68.81 132.48,68.81 133.78,70.11 133.78,83.48 134.86,84.56 134.86,88.3 136.18,89.62 136.18,91.24 135.33,92.09 135.33,93.46 134.55,94.23 134.55,95.84 v1(134.21,96.18)
  BOTTOM w0.14: R6210.1 132.1,96.12 EC6205.1 134.15,96.12 v1(134.21,96.18) ; 130.49,69.97 130.49,70.24 130.15,70.58 130.15,70.85 130.35,71.05 130.77,71.05 131.01,71.29 131.01,71.67 131.04,71.7 131.04,72.66 130.67,73.03 Q1801.1 130.3,73.47 130.13,73.64 128.66,73.64 128.34,73.97 128.34,74.91 129.11,75.68 129.86,75.68 130.19,76.02 RN1810.4 130.19,76.56 130.27,76.64 130.27,78.47 130.83,79.03 130.83,79.66 130.61,79.88 RN9601.1 ; 130.49,69.97 v1(130.49,69.33) ; 130.49,69.97 v2(130.68,69.97) ; DM1.200 112.35,21.24 113.02,20.58 115.52,20.58 116.97,22.03 116.97,33.43 117.93,34.38 117.93,37.82 118.57,38.47 119.19,38.47 v1(119.31,38.35)
PCH_SPI_CLK: length 4.9
  BOTTOM w0.089: 120.66,82.43 120.44,82.43 119.72,81.71 117.92,81.71 CPU1.AA3
  BOTTOM w0.14: 120.66,82.43 121.04,82.43 v2(121.04,82.43) 121.04,82.43 121.84,82.43 R1806.2
PCH_SPI_CS0#: length 13
  TOP w0.14: v1(121.99,84.23) 122.1,84.34 v2(122.1,85.02) 122.1,85.62 122.43,85.95 122.43,86.45 122.37,86.5 122.37,87.04 122.62,87.28 R1807.2
  L4 w0.127: v1(115.14,83.09) 115.58,82.65 118.05,82.65 119.29,83.89 119.5,83.89 119.75,84.13 120.35,84.13 120.73,83.75 121.51,83.75 v1(121.99,84.23)
  BOTTOM w0.14: CPU1.Y7 114.96,82.91 v1(115.14,83.09)
PCH_SPI_DQ2: length 12
  TOP w0.14: v1(115.79,83.09) 116.26,82.61 116.62,82.61 116.98,82.25 117.81,82.25 118.01,82.06 v2(118.44,82.06) 118.6,82.06 119.57,83.02 121.61,83.02 123.14,84.56 RN1802.3 123.14,85.16 123.31,85.34 124.09,85.34 124.49,84.94 R1811.2
  BOTTOM w0.14: v1(115.79,83.09) 115.61,82.91 CPU1.Y6
PCH_SPI_DQ3: length 11
  TOP w0.14: v1(121.61,79.97) 121.65,80.01 v2(121.65,80.89) 121.65,82.14 123.79,84.29 RN1802.4 124.05,84.74 124.28,84.51 124.28,84.14 124.03,83.89 124.03,83.19 R1812.2
  BOTTOM w0.14: CPU1.AF1 119.01,79.87 119.95,79.87 120.01,79.8 120.43,79.8 120.5,79.73 121.37,79.73 v1(121.61,79.97)
PCH_SPI_SI: length 6.4
  BOTTOM w0.089: CPU1.AA2 118.38,82 118.67,82.28 119.16,82.28 119.58,82.7 120.01,82.7
  BOTTOM w0.14: 120.01,82.7 120.79,82.7 120.93,82.84 122.55,82.84 v2(122.91,83.2) 123.41,83.71 123.74,83.71 R1808.2
PCH_SPI_SO: length 9.7
  BOTTOM w0.089: 120.36,81.93 119.97,81.53 117.45,81.53 CPU1.AA4
  BOTTOM w0.14: 120.36,81.93 120.57,82.14 120.83,82.14 120.89,82.08 121.27,82.08 121.54,81.81 123.17,81.81 123.36,81.99 123.36,82.47 123.76,82.87 v2(124.33,82.87) 124.6,82.87 124.84,82.62 R1809.2
PCH_THERMTRIP: length 9.4
  BOTTOM w0.089: 79.87,92.96 80.1,92.72 80.53,92.72 80.6,92.65 81.29,92.65 81.77,92.18 81.95,92.18 CPU1.D60
  BOTTOM w0.102: R2027.1 77.02,94.25 v2(77.18,94.41) 77.18,94.73 77.11,94.8 R2018.2 79.06,95.32 79.83,94.55 79.83,92.99 79.87,92.96
PCH_VCCDSW_R: length 2.1
  TOP w0.254: C2114.1 106.27,74.62 v2(106.73,74.16) 107.11,74.55 R2110.2
PCH_WAKE#: length 22.8
  L4 w0.102: v1(115.81,78.32) 116.2,77.93 117.87,77.93 118.46,78.52 120.21,78.52 121.23,79.54 121.94,79.54 122.08,79.69 122.08,80.3 122.8,81.02 123.9,81.02 124.99,82.11 126.88,82.11 127.55,82.78 129.18,82.78 130.34,83.94 v1(131.09,83.94)
  BOTTOM w0.102: CPU1.AJ5 116.26,77.87 115.81,78.32 v1(115.81,78.32) ; v2(133.57,82.74) 133.69,82.86 133.69,83.59 R1703.2 133.23,83.67 132.99,83.43 R1705.1 131.6,83.43 v1(131.09,83.94)
PCI_PLTRST#: length 19.3
  TOP w0.127: v2(115.47,79.74) 115.15,79.42 v1(115.15,79.28)
  L4 w0.127: v1(115.15,79.28) 115.61,79.74 116.99,79.74 117.06,79.68 118.09,79.68 118.35,79.94 118.35,80.07 120.03,81.74 120.17,81.74 120.55,82.12 122.52,82.12 122.83,82.43 123.6,83.2 124.41,83.2 124.41,83.2 125.04,83.2 125.47,83.63 125.47,84.11 125.88,84.52 126.54,84.52 128.89,86.88 v1(128.89,86.97)
  BOTTOM w0.127: v1(115.15,79.28) 114.96,79.09 CPU1.AG7 ; R1713.2 129.11,87.2 v1(128.89,86.97)
PCI_PME#: length 1.1
  TOP w0.102: v1(117.24,80.12) 117.29,80.18 TP1501.1
  BOTTOM w0.102: v1(117.24,80.12) 116.94,80.42 CPU1.AD4
PCIE_CLK_XDP_N: length 5.5
  BOTTOM w0.102: TP9651.1 98.37,97.25 98.2,97.43 97.98,97.43 97.8,97.25 97.8,96.8 98.36,96.23 98.36,93.38 CPU1.B35
PCIE_CLK_XDP_P: length 5.4
  BOTTOM w0.102: CPU1.A35 98.16,93.83 98.16,96.15 97.59,96.71 97.59,97.33 97.9,97.63 98.26,97.63 98.37,97.74 TP9652.1
PCIE_PRX_LANTX_N4: length 93.2
  TOP w0.127: v2(39.84,68.42) v1(39.28,68.42)
  L4 w0.114: v1(39.28,68.42) 38.94,68.07 38.94,67.5 39.72,66.72 41.74,66.72 45.28,70.26 49.35,70.26 62.29,83.2 66.58,83.2 71.71,88.33 74.42,88.33 76.86,90.77 79.38,90.77 79.92,91.32 79.92,91.81 82.41,94.3 85.93,94.3 86.43,94.8 88.65,94.8 91.21,97.36 94.08,97.36 94.3,97.13 103.67,97.13 106.53,94.27 106.53,94.08 107.56,93.05 108.76,93.05 110.06,91.75 110.06,90.77 110.41,90.42 110.68,90.42 v1(111.03,90.76)
  BOTTOM w0.127: v1(39.28,68.42) 38.95,68.09 38.95,67.75 39.17,67.53 39.17,67.28 C3016.2 ; CPU1.F13 111.34,90.45 v1(111.03,90.76)
PCIE_PRX_LANTX_P4: length 92.8
  L4 w0.114: v1(111.02,90.1) 110.94,90.19 110.32,90.19 109.83,90.68 109.83,91.07 109.83,91.65 108.66,92.82 107.47,92.82 106.3,93.98 106.3,94.18 103.58,96.91 94.2,96.91 93.98,97.13 91.3,97.13 88.75,94.57 86.53,94.57 86.02,94.07 82.5,94.07 80.15,91.72 80.15,91.22 79.47,90.54 76.96,90.54 74.51,88.1 71.8,88.1 66.67,82.97 62.38,82.97 49.45,70.03 45.38,70.03 41.83,66.49 39.81,66.49 39.62,66.49 38.71,67.4 38.71,68.36 v1(38.65,68.42)
  BOTTOM w0.127: C3014.2 38.93,67.27 38.93,67.43 38.71,67.65 38.71,67.86 ; v1(111.02,90.1) 111.33,89.8 CPU1.G13 ; 38.71,67.86 v2(38.58,67.86) ; 38.71,67.86 38.71,68.36 v1(38.65,68.42)
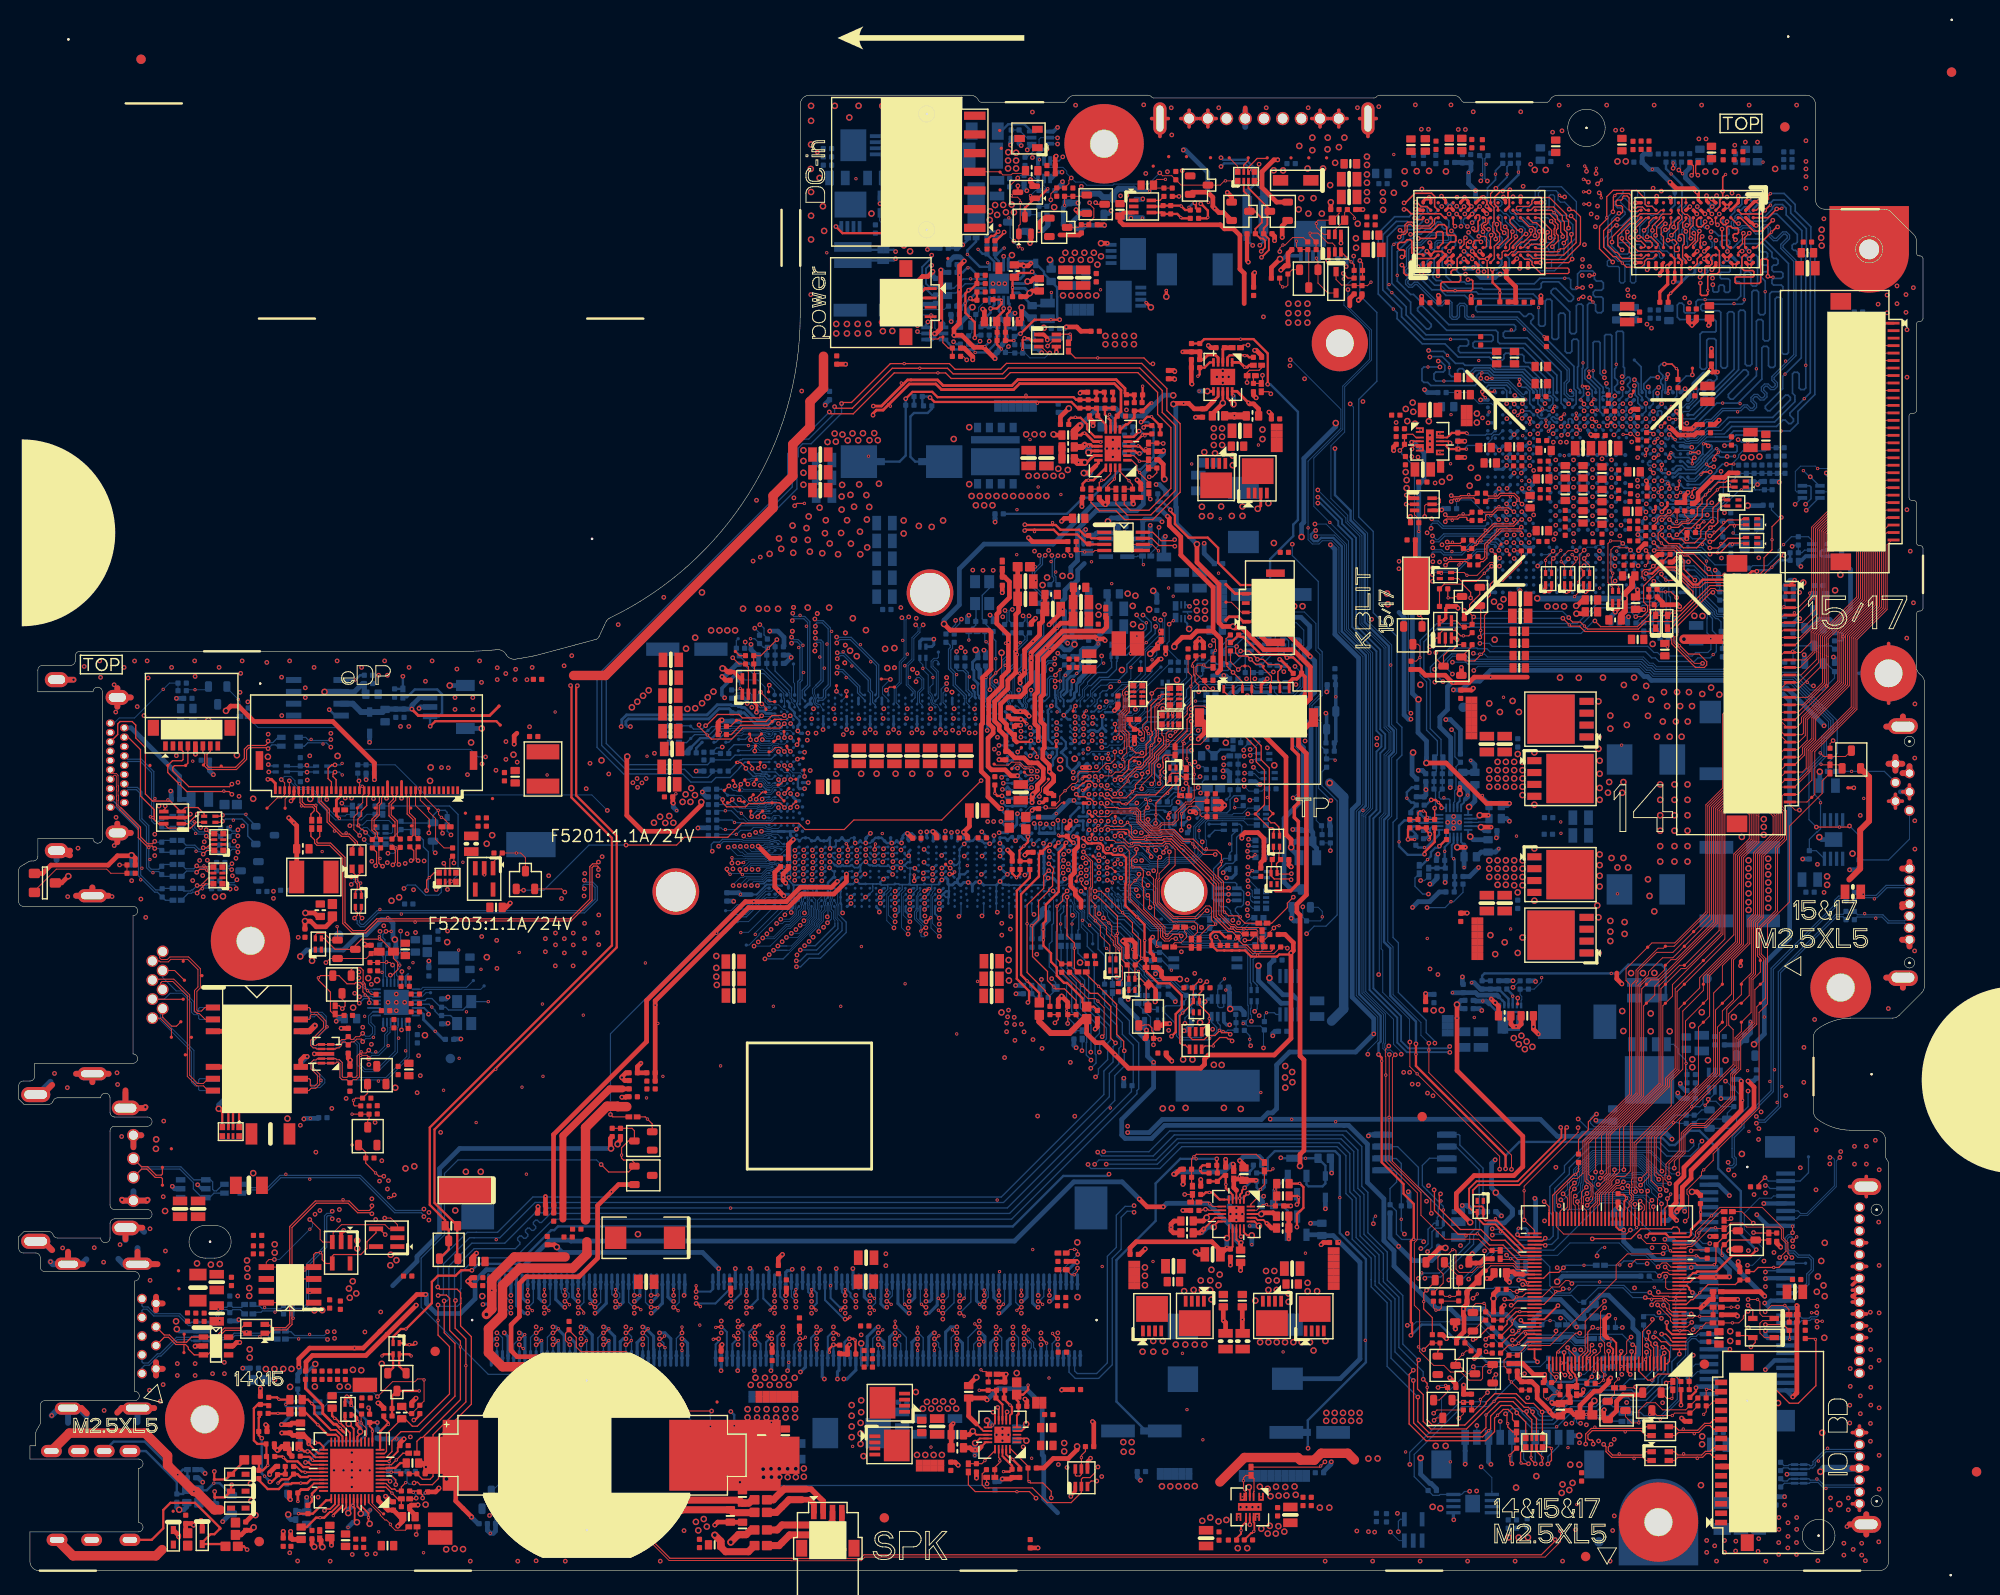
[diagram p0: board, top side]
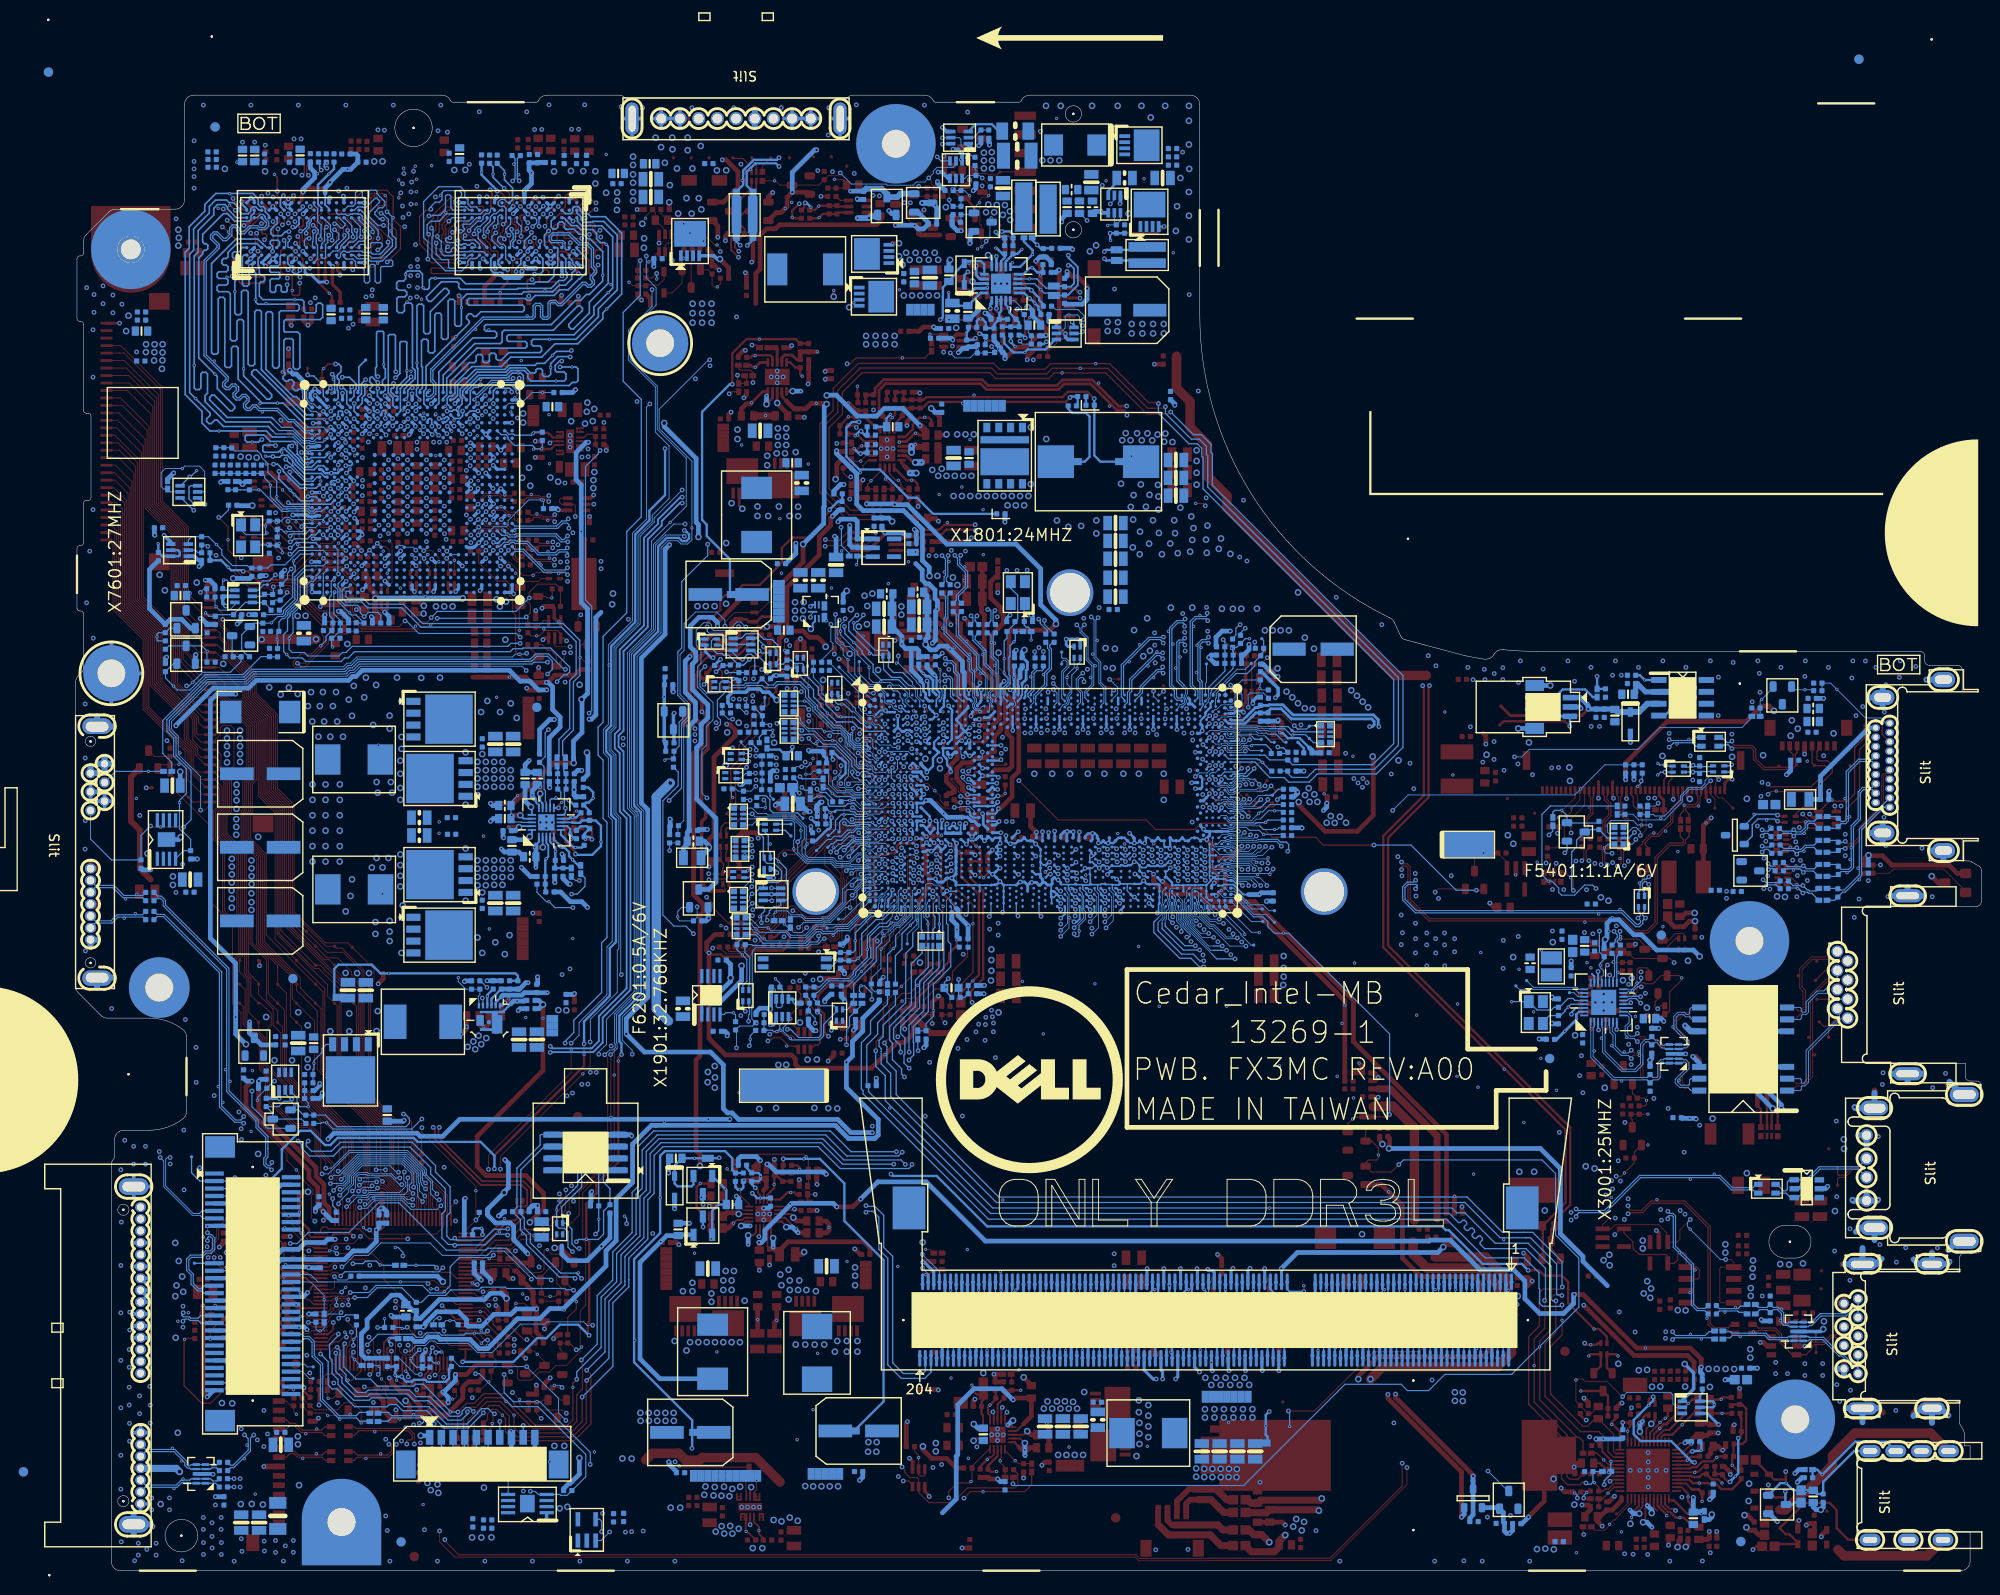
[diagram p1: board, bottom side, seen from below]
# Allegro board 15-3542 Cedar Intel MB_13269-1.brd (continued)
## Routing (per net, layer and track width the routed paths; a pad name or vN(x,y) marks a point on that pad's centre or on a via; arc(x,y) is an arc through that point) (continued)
PCIE_PRX_WLANTX_N3: length 152.1
  TOP w0.127: v1(189.74,36.17) v2(189.74,36.87)
  L4 w0.114: v1(113,89.44) 112.84,89.6 112.56,89.6 112.24,89.92 112.24,92.76 113.33,93.86 117.12,93.86 119.78,96.52 122.34,96.52 124.34,98.52 127.66,98.52 129.56,100.42 137.75,100.42 139.58,98.6 139.58,94.51 139.44,94.37 139.44,93.67 140.53,92.58 140.53,87.42 139.42,86.31 139.42,75.91 140.53,74.81 140.53,60.18 140.99,59.72 140.99,57.58 141.42,57.15 142.28,56.29 142.28,53.88 149.06,47.1 163.32,47.1 164.95,45.47 184.61,45.47 188.47,41.61 188.47,36.45 188.97,35.95 189.53,35.95 v1(189.74,36.17)
  BOTTOM w0.127: CPU1.G11 112.84,89.44 v1(113,89.44) ; WLAN1.23 190.08,30.5 190.4,30.18 190.67,30.18 191.26,30.76 191.26,31.75 191.74,32.23 191.74,33.26 191.46,33.53 190.31,33.53 189.86,33.98 189.35,33.98 188.95,34.38 188.95,35.62 189.3,35.97 189.54,35.97 v1(189.74,36.17)
PCIE_PRX_WLANTX_P3: length 152.1
  TOP w0.127: v2(190.19,35.72) 189.78,35.31 v1(189.74,35.31)
  L4 w0.114: v1(113.02,90.1) 112.75,89.83 112.65,89.83 112.46,90.01 112.46,92.67 113.43,93.63 117.22,93.63 119.88,96.29 122.43,96.29 124.43,98.29 127.75,98.29 129.66,100.19 137.66,100.19 139.35,98.5 139.35,94.61 139.21,94.47 139.21,93.57 140.3,92.48 140.3,87.51 139.19,86.41 139.19,75.82 140.3,74.71 140.3,60.09 140.76,59.62 140.76,57.48 141.2,57.05 142.05,56.19 142.05,53.79 148.96,46.88 163.22,46.88 164.86,45.24 184.51,45.24 188.24,41.52 188.24,36.36 188.87,35.72 189.63,35.72 189.74,35.62 v1(189.74,35.31)
  BOTTOM w0.127: v1(189.74,35.31) 189.74,35.62 189.64,35.73 189.4,35.73 189.2,35.52 189.2,34.48 189.45,34.23 189.96,34.23 190.41,33.78 191.56,33.78 191.98,33.36 191.98,32.13 191.5,31.65 191.5,30.66 190.77,29.94 190.36,29.94 190.12,29.7 WLAN1.25 ; CPU1.F11 112.48,90.24 112.74,89.98 112.91,89.98 v1(113.02,90.1)
PCIE_PTX_LANRX_N4: length 4.3
  BOTTOM w0.127: v2(101.7,95.65) 101.57,95.65 ; 101.57,95.65 101.57,96.12 101.22,96.47 C1603.2 ; 101.57,95.65 101.57,94.27 101.98,93.87 101.98,93.57 101.67,93.26 CPU1.B29
PCIE_PTX_LANRX_N4_C: length 89.5
  L4 w0.114: v1(101.25,98.33) 101,98.33 100.62,97.95 100.51,97.95 100.22,97.66 94.51,97.66 94.29,97.88 90.96,97.88 88.42,95.33 86.23,95.33 85.71,94.82 81.97,94.82 80.47,93.31 77.49,93.31 76.64,92.45 76.64,91.3 74.18,88.85 70.85,88.85 68,86 66.56,86 64.28,83.72 61.7,83.72 49.58,71.59 43.9,71.59 42.08,69.77 38.36,69.77 34.86,66.27 34.86,62.19 35.96,61.09 36.13,61.09 v1(36.46,61.42)
  BOTTOM w0.127: 37.06,61.47 37.78,61.47 37.83,61.42 LOM30.14 ; 37.06,61.47 36.51,61.47 v1(36.46,61.42) ; 37.06,61.47 v2(37.06,61.6) ; C1603.1 101.22,98.23 101.25,98.26 v1(101.25,98.33)
PCIE_PTX_LANRX_P4: length 4
  BOTTOM w0.127: CPU1.A29 101.67,93.83 101.33,94.17 101.33,96.02 101.04,96.31 100.46,96.31 100.33,96.45 C1604.2
PCIE_PTX_LANRX_P4_C: length 89.4
  L4 w0.114: v1(36.44,60.73) 36.31,60.86 35.87,60.86 34.63,62.09 34.63,66.36 38.27,70 41.98,70 43.81,71.82 49.48,71.82 61.61,83.95 64.19,83.95 66.47,86.22 67.9,86.22 70.76,89.08 74.09,89.08 76.41,91.4 76.41,92.55 77.4,93.54 80.37,93.54 81.88,95.05 85.62,95.05 86.13,95.56 88.32,95.56 90.86,98.11 94.39,98.11 94.61,97.88 100.13,97.88 100.33,98.09 v1(100.33,98.37)
  BOTTOM w0.127: LOM30.13 37.88,61.02 37.68,61.23 36.93,61.23 v1(36.44,60.73) ; C1604.1 v1(100.33,98.37)
PCIE_PTX_WLANRX_N3: length 8
  BOTTOM w0.089: CPU1.C29 101.67,92.6 101.34,92.93 101.34,93.33 101.36,93.35 101.36,93.37
  BOTTOM w0.127: 100.2,95.89 100.2,96.1 99.7,96.6 99.7,98.52 99.89,98.7 99.89,99.17 C1601.2 ; 100.2,95.89 100.2,94.85 101.36,93.69 101.36,93.37 ; 100.2,95.89 v2(100.32,95.89)
PCIE_PTX_WLANRX_N3_C: length 177
  TOP w0.127: v2(191.78,27.61) v1(192.33,27.61)
  L4 w0.114: v1(192.33,27.61) 192.33,27.37 192.55,27.16 193.92,27.16 194.33,27.56 194.33,41.42 192.56,43.19 192.56,43.85 186.82,49.58 185.89,49.58 184.97,48.66 182.48,48.66 182.03,48.2 170.21,48.2 168.85,49.57 165.98,49.57 165.78,49.37 149.7,49.37 144.75,54.32 144.75,56.68 143.44,57.99 143.44,60.13 142.55,61.02 142.55,93.42 141.88,94.09 141.88,98.31 141.6,98.59 141.6,99.43 140.26,100.77 139.95,101.09 139.95,103.22 137.51,105.66 124.03,105.66 122.66,107.02 105.66,107.02 105.11,107.57 101.63,107.57 100.55,106.49 100.55,102.02 100.73,101.83 v1(100.84,101.83)
  BOTTOM w0.127: C1601.1 99.94,100.37 99.94,100.66 100.66,101.38 100.66,101.66 v1(100.84,101.83) ; v1(192.33,27.61) 192.49,27.45 192.49,27.32 192.33,27.17 191.66,27.17 191.51,27.02 190.76,27.02 190.47,27.3 WLAN1.31
PCIE_PTX_WLANRX_P3: length 7.7
  BOTTOM w0.089: 101.12,93.37 101.12,93.36 101.15,93.33 101.15,92.78 CPU1.B30
  BOTTOM w0.127: C1602.2 99.31,99.35 99.65,99.01 99.65,98.8 99.46,98.62 99.46,96.5 99.96,96 99.96,94.75 101.12,93.59 101.12,93.37
PCIE_PTX_WLANRX_P3_C: length 177.3
  TOP w0.127: v1(192.36,26.69) v2(192.92,26.69)
  L4 w0.114: v1(192.36,26.69) 192.6,26.93 194.02,26.93 194.55,27.47 194.55,41.51 192.78,43.28 192.78,43.94 186.91,49.81 185.8,49.81 184.87,48.89 182.39,48.89 181.93,48.43 170.31,48.43 168.94,49.8 165.89,49.8 165.69,49.6 149.8,49.6 144.98,54.41 144.98,56.77 143.67,58.09 143.67,60.22 142.77,61.12 142.77,93.51 142.1,94.18 142.1,98.4 141.82,98.68 141.82,99.53 140.49,100.86 140.17,101.18 140.17,103.32 137.61,105.88 124.12,105.88 122.75,107.25 105.75,107.25 105.21,107.8 101.53,107.8 100.32,106.59 100.32,101.8 v1(100.21,101.7)
  BOTTOM w0.127: C1602.1 100.21,101.27 v1(100.21,101.7) ; WLAN1.33 190.46,26.5 190.73,26.78 191.61,26.78 191.76,26.93 192.13,26.93 v1(192.36,26.69)
PCIE_RCOMP: length 3.4
  BOTTOM w0.254: 102.81,95.57 103.05,95.33 103.05,94.72 102.98,94.65 102.98,93.9 103.05,93.83 CPU1.A27
  BOTTOM w0.508: 102.81,95.57 102.81,96.39 102.59,96.61 R1601.2
PCIE_WAKE#: length 298.6
  TOP w0.127: KBC24.113 170.09,22.9 170.06,22.93 170.06,23.22 170.07,23.23 v1(170.07,23.5)
  L3 w0.127: v1(40.85,68.45) 40.85,67.32 43.35,64.82 43.35,58.2 44.78,56.77 44.78,47.26 v1(45.13,46.91) ; v1(131.69,82.45) 132.03,82.45 135.16,79.32 135.16,73.58 135.93,72.81 137.12,72.81 140.39,69.54 140.39,52.21 149.44,43.16 149.44,39.64 150.39,38.69 151.29,38.69 153.17,36.81 153.17,32.08 153.64,31.61 153.64,30.2 154.74,29.1 154.94,29.1 155.72,28.31 155.72,27.97 159.86,23.83 162.79,23.83 163.73,22.88 167.33,22.88 167.4,22.95 169.75,22.95 170.07,23.28 v1(170.07,23.5)
  L4 w0.127: v1(170.07,23.5) 169.83,23.26 169.83,21.82 169.84,21.82 169.84,19.53 172.75,16.62 172.75,13.56 169.89,10.7 164.71,10.7 161.93,7.91 157.77,7.91 156.28,9.4 149.14,9.4 143.99,9.4 143.41,8.83 138.47,8.83 136.97,10.33 127.99,10.33 125.9,8.25 125.16,8.25 124.66,7.75 113.43,7.75 112.65,8.53 112.1,8.53 110.96,9.67 110.27,9.67 110.01,9.93 109.01,9.93 107.83,9.93 104.58,6.68 79.28,6.68 71.54,14.42 67.02,14.42 64.43,17 58.69,17 57.81,16.11 51.85,16.11 42.94,25.03 42.46,25.03 40.09,27.39 40.09,28.04 38.68,29.45 38.68,34.08 40.09,35.49 40.09,38.99 39.35,39.73 39.35,40.11 40.45,41.22 40.45,43.02 44.34,46.91 v1(45.13,46.91)
  BOTTOM w0.102: 40.57,64.34 40.43,64.2 40.43,63.72 40.59,63.56 LOM30.21
  BOTTOM w0.127: 40.57,64.34 40.76,64.53 v2(40.76,64.8) 40.76,65.02 40.34,65.44 R3033.1 40.85,66.21 v1(40.85,68.45) ; R1705.2 131.78,82.54 v1(131.69,82.45)
PD4403_A: length 5.1
  TOP w0.102: PD4404.A 140.04,136.73 138.98,137.79 PQ4409.B 138.98,140.11 138.81,140.29 v2(138.81,140.46)
PD4403_K: length 5
  TOP w0.102: v2(144.65,137.89) 144.28,137.52 PR4471.1 PR4468.2 142.79,137.58 141.5,137.58 140.91,138.17 PD4404.K
PECI: length 8.4
  TOP w0.14: R2429.1 184.12,31.12 C2422.1 183.63,30.62 181.83,30.62 181.83,30.62 180.7,30.62 v2(179.82,29.74) 179.09,29.01 178.89,29.01 178.38,28.5 KBC24.13
PEG_CLKREQ#: length 53.2
  TOP w0.127: R7305.1 153.97,99.1 153.36,98.49 152.98,98.49 152.41,97.92 Q7301.D 151.58,97.62 v1(151.58,98.24) ; v2(116.81,85.49) 116.81,85.6 v1(116.47,85.94)
  L3 w0.127: v1(151.58,98.24) 151.09,97.74 150.54,97.74 149.24,96.45 149.03,96.45 143.54,96.45 142.91,95.81 136.27,95.81 135.57,95.12 134.66,95.12 133.79,94.25 131.32,94.25 130.93,93.87 130.93,93.49 v1(131.42,93.01) ; v1(116.47,85.94) 116.47,85.33 116.5,85.29 116.5,84.9 116.81,84.59 116.81,84.45 117.07,84.19 117.7,84.19 117.71,84.18 118.08,84.18 118.09,84.19 118.11,84.19 118.58,84.66 118.58,85.53 119.02,85.97 119.02,86.4 119.67,87.05 120.6,87.05 121.91,88.36 123.6,88.36 124.76,89.52 125.77,89.52 v1(126.17,89.92)
  L4 w0.127: v1(131.42,93.01) 130.22,93.01 129.4,92.18 128.13,92.18 126.17,90.22 v1(126.17,89.92)
  BOTTOM w0.127: RN1801.7 126.38,90.13 v1(126.17,89.92) ; v1(116.47,85.94) 116.59,85.82 116.59,84.85 CPU1.U5
PEX_TERMP: length 5.9
  BOTTOM w0.102: GPU1.AF25 157.52,124.92 156.58,124.92 156.54,124.88 156.2,124.88 155.01,126.08 v2(153.9,126.08) R7301.1
PEXTSTCLK_OUT: length 4.4
  BOTTOM w0.14: GPU1.AF22 157.9,121.99 157.53,121.63 157.01,121.63 156.9,121.52 155.1,121.52 v2(154.94,121.68) 154.77,121.85 R7307.1
PEXTSTCLK_OUT#: length 6.6
  BOTTOM w0.14: GPU1.AE22 158.34,121.58 157.82,121.58 157.59,121.34 157.59,121.12 156.89,120.42 154.98,120.42 154.62,120.06 v2(154,120.06) 153.92,120.13 R7307.2
PHASE1G: length 8.6
  BOTTOM w0.254: PG4701.1 95.9,118.69 95.39,119.19 95.39,123.51 95.77,123.89 97.23,123.89 97.67,124.34 PR4702.1
PHASE_R_R: length 0.9
  BOTTOM w0.254: PR4704.1 PR4703.2
PIRQA#: length 12.3
  TOP w0.102: RN2011.7 118.8,93.56 118.55,93.31 118.55,92.02 118.11,91.58 118.11,89.91 118.53,89.49 118.53,87.54 118.09,87.1 v2(118.09,86.83) 118.33,86.59 118.33,85.94 117.86,85.47 117.33,85.47 116.91,85.06 115.87,85.06 v1(115.83,85.02)
  BOTTOM w0.102: CPU1.U6 115.61,84.79 v1(115.83,85.02)
PIRQB#: length 14.3
  BOTTOM w0.089: 119.17,86.07 119.13,86.03 118.67,86.03 118.58,85.94 118.58,85.57 118.43,85.41 117.24,85.41 CPU1.P4
  BOTTOM w0.102: 119.17,86.07 119.26,86.16 119.54,86.16 119.66,86.03 119.67,86.03 119.67,86.02 120.01,86.02 120.31,86.33 120.31,87.01 121.54,88.24 121.54,89.12 122.01,89.59 122.82,89.59 123.02,89.79 v2(123.72,89.79) 124.04,90.11 125.46,90.11 126.31,90.96 126.31,91.25 126.96,91.9 RN1505.5
PIRQC#: length 17
  TOP w0.102: v1(116.55,86.89) v2(116.55,87.46)
  L4 w0.102: v1(116.55,86.89) 117.77,86.89 118.58,87.69 118.58,89.14 120.51,91.07 123.32,91.07 123.64,91.39 123.64,92.34 124.42,93.12 126.02,93.12 126.83,93.93 v1(126.83,94.39)
  BOTTOM w0.102: v1(116.55,86.89) 116.59,86.89 CPU1.N4 ; RN1505.8 127.04,94.17 v1(126.83,94.39)
PIRQD#: length 12.1
  BOTTOM w0.089: CPU1.N2 118.24,86.5 118.58,86.83 118.96,86.83 119.74,87.62 119.74,87.68 119.98,87.91 120.45,87.91
  BOTTOM w0.102: 120.45,87.91 120.64,87.91 121.35,88.63 121.35,89.2 122.05,89.9 122.84,89.9 124.99,92.05 124.99,92.35 125.69,93.05 v2(125.88,93.05) RN1505.7
PLT_RST#: length 387.8
  TOP w0.102: U7301.2 152.6,99 152.47,98.87 v1(150.95,98.87) ; v1(154.05,16.3) 154.53,16.78 R3606.1 151.7,17.2 v1(151.35,16.85) ; v1(32.86,65.08) 33.29,65.51 Q3003.E 37.17,65.51 EC1703.1 37.9,66.24 R3016.1
  L3 w0.102: v1(154.05,16.3) 155.46,14.89 156.52,14.89 157.01,15.39 157.01,17.19 158.9,19.07 164.44,19.07 165.2,18.31 167.8,18.31 168.33,18.84 168.96,18.84 169.19,18.61 172.06,18.61 172.69,17.98 v1(175.84,17.98) ; v1(147.47,6.14) 148.36,7.02 148.36,13.85 v1(151.35,16.85) ; v1(132.23,95.45) 132.92,94.76 133.58,94.76 134.44,95.62 135.38,95.62 136.06,96.31 142.7,96.31 143.33,96.94 148.77,96.94 150.7,98.87 v1(150.95,98.87) ; v1(150.97,64.4) 150.97,63.67 151.56,63.07 153.01,63.07 155.19,60.9 155.19,58.05 156.25,57 156.25,55.5 160.34,51.41 164.79,51.41 166.5,49.7 166.96,49.7 167.9,48.76 167.9,48.39 172.56,43.73 172.56,40.81 172.46,40.71 172.46,39.03 173.08,38.42 174.11,38.42 176.73,35.8 176.73,35.31 v1(175.98,34.56) ; v1(39.55,41.74) 38.85,41.05 38.5,41.05 36.22,43.33 36.22,55.02 35.58,55.65 35.58,58.19 34.44,59.33 34.44,59.71 34.11,60.04 34.11,63.83 v1(32.86,65.08) 32.86,69.65 36.22,73.01 36.22,75.59 34.76,77.05 34.76,78.44 35.85,79.53 35.85,80.85 v1(34.56,82.13)
  L4 w0.102: v1(131.09,87.17) 131.07,87.17 130.6,87.63 130.6,87.99 131.59,88.98 134.45,88.98 134.88,89.41 134.88,91.25 134.44,91.7 134.44,93.03 132.23,95.24 v1(132.23,95.45) ; v1(147.47,6.14) 147.15,5.81 138.61,5.81 138.12,6.3 129.96,6.3 129.75,6.51 126.81,6.51 126.68,6.38 125.93,6.38 125.44,5.89 111.37,5.89 108.95,8.3 108.48,8.3 105.25,5.07 78.61,5.07 70.87,12.8 66.35,12.8 64.14,15.01 51.16,15.01 39.65,26.52 39.65,27.86 38.24,29.27 38.24,34.27 39.64,35.67 39.64,38.81 38.91,39.55 38.91,40.94 39.55,41.58 v1(39.55,41.74) ; v1(150.95,98.87) 150.92,98.87 150.47,98.42 150.47,98.06 150.72,97.81 150.99,97.81 152.49,96.31 152.49,95.73 152.78,95.43 152.78,94.53 151.51,93.26 151.51,86.28 148.21,82.98 148.21,80.09 149.27,79.02 149.27,72.8 150.11,71.96 150.11,65.25 v1(150.97,64.4) ; v1(175.98,34.56) 175.53,34.56 175.16,34.19 175.16,33.04 173.56,31.44 173.56,28.95 174.49,28.01 175.07,28.01 175.45,27.63 v1(175.46,27.63) 175.85,27.63 176.86,26.62 176.86,24.45 176.71,24.3 176.71,22.68 175.54,21.52 175.54,18.27 v1(175.84,17.98)
  BOTTOM w0.102: v1(131.09,87.17) 131.07,87.2 R1713.1 R6502.1 130.44,85.38 C1701.1 130.41,85.35 R1715.1 130.41,83.63 R9602.2 ; v1(34.56,82.13) 34.87,81.82 R5212.2 ; v1(175.46,27.63) 175.62,27.46 R2416.2 v2(177.25,29) 177.25,29.45 178.7,30.9 WLAN1.22
PLT_RST#_DEBUG: length 89.4
  TOP w0.127: v1(155.56,29.15) 156.03,29.61 v2(156.03,29.61)
  L3 w0.127: v1(128.89,86.24) 129.49,85.64 129.49,82.6 130.05,82.03 130.42,82.03 131.28,82.9 131.94,82.9 135.41,79.43 135.41,73.68 136.03,73.06 137.23,73.06 140.65,69.64 140.65,52.31 149.69,43.27 149.69,39.75 150.5,38.94 151.39,38.94 153.42,36.91 153.42,32.18 153.89,31.72 153.89,30.3 154.85,29.35 155.36,29.35 v1(155.56,29.15)
  L4 w0.127: v1(158.47,15.97) 158.47,19.22 156.56,21.13 156.56,23.18 156.11,23.64 156.11,28.6 v1(155.56,29.15)
  BOTTOM w0.127: R6502.2 128.96,86.31 v1(128.89,86.24) ; DB1.7 v1(158.47,15.97)
PLT_RST#_EC: length 4.7
  TOP w0.102: v1(178.96,26.57) 178.49,26.1 KBC24.7
  BOTTOM w0.102: R2416.1 177.25,25.96 177.54,25.67 v2(177.7,25.67) 177.92,25.67 178.14,25.89 C2415.2 178.96,26.57 v1(178.96,26.57)
PLT_RST#_LAN: length 13.4
  TOP w0.127: RN3001.3 32.67,67.66 33.84,66.49 Q3003.C 36.01,66.91 36.68,67.58 v2(38.61,67.58) 38.7,67.58 38.78,67.5 38.83,67.5 R3016.2 40.09,65.53 40.54,65.08 40.54,64.31 39.96,63.74 v1(39.75,63.74)
  BOTTOM w0.102: v1(39.75,63.74) 39.79,63.7 LOM30.19
PM_CLKRUN#: length 23.8
  TOP w0.102: v1(127.73,94.4) 127.43,94.4 126.86,94.97 R1714.1 126.65,95.28 125.94,95.99 125.94,96.75 126.1,96.92 v2(126.77,96.92) 127.01,96.68 R1709.1
  L4 w0.102: v1(127.73,94.4) 127.73,93.84 126.51,92.63 124.61,92.63 124.13,92.14 124.13,89.68 122.77,88.32 122.55,88.32 121.1,86.88 119.65,86.88 119.07,86.3 119.07,85.86 118.3,85.09 117.06,85.09 116.45,84.48 116.45,84.05 v1(116.44,84.04)
  BOTTOM w0.102: v1(116.44,84.04) 116.44,83.75 CPU1.V5
PM_CLKRUN#_EC: length 116.9
  TOP w0.102: KBC24.8 176.93,26.5 176.68,26.74 176.68,27.06 175.51,28.23 175.51,28.23 v1(175.3,28.43) ; R1709.2 127.76,98.24 v2(128.01,98.49) 128.01,99.36 v1(127.81,99.56)
  L3 w0.102: v1(127.81,99.56) 128.33,100.08 132.34,100.08 132.79,100.53 136.45,100.53 136.7,100.78 143.69,100.78 v1(144.72,101.81) ; v1(175.3,28.43) 175.82,28.95 175.82,29.99 175.55,30.26 175.21,30.26 172.89,32.57 172.89,32.78 172.55,33.12 171.35,33.12 170.29,34.19 165.79,34.19 163.67,36.3 162.76,36.3 161.47,37.6 161.47,37.71 159.64,39.54 158.64,39.54 158.17,39.54 154.46,43.24 154.46,44.57 151.38,47.66 151.38,49.79 150.76,50.41 150.76,51.05 v1(150.69,51.11)
  L4 w0.102: v1(144.72,101.81) 145.23,101.3 145.23,100.1 145.57,99.77 145.57,95.54 146.76,94.35 146.76,87.57 145.59,86.4 145.59,64.96 146.57,63.98 146.57,61.98 152.12,56.42 152.12,52.54 v1(150.69,51.11)
PM_LAN_ENABLE: length 215.3
  TOP w0.127: v1(39.06,42.21) 38.53,42.21 v2(38.17,42.56) 37.12,43.62 R3023.1 37.12,44.78 Q3001.G ; v1(172.52,23.46) 172.52,22.91 172.49,22.88 KBC24.119
  L3 w0.127: v1(172.52,23.46) 173.19,22.79 176.62,22.79 177.46,23.63 179.33,23.63 180.18,22.78 183.92,22.78 184.81,23.67 184.81,25.8 v1(185.01,26)
  L4 w0.127: v1(185.01,26) 185.01,24.57 184.83,24.38 184.83,21.11 183.92,20.21 183.92,19.1 182.7,17.88 182.7,9.89 178.04,5.23 178.04,5.22 176.17,3.35 173.43,3.35 173.01,3.77 163.83,3.77 162.98,2.92 146.97,2.92 145.19,4.7 144.22,4.7 142.94,3.42 133.83,3.42 133.38,3.42 133.37,3.42 133.05,3.42 132.24,4.23 129.73,4.23 129.69,4.2 129.59,4.2 128.78,3.38 110.86,3.38 109.74,4.5 106,4.5 105.63,4.14 78.22,4.14 70.48,11.88 65.96,11.88 63.78,14.06 50.8,14.06 37.52,27.34 37.52,35.95 38.66,37.1 38.66,41.11 39.06,41.5 v1(39.06,42.21)
PM_LAN_ENABLE_R: length 4.1
  TOP w0.127: R3022.2 35.95,49.74 35.81,49.88 v2(35.81,50.33) 36.05,50.57 C3015.2 37.32,51.1 Q3004.G
PM_PCH_PWROK: length 14.7
  BOTTOM w0.089: CPU1.AY7 114.66,70.98 114.66,70.11 115.74,69.03 116.17,69.03 116.76,68.44 116.91,68.44 v2(117.39,67.96)
  BOTTOM w0.127: v2(117.39,67.96) 117.66,67.69 117.66,67.19 118.21,66.65 118.21,65.19 120.62,62.77 R1707.1 120.62,60.72 R1706.2 121.28,60.06 RN1703.3
PM_PWRBTN#: length 108.2
  TOP w0.102: KBC24.117 171.69,22.96 172.01,23.27 172.01,24.56 172.45,25 v1(172.47,25)
  L3 w0.102: v1(130.23,82.48) 130.9,83.14 132.04,83.14 135.65,79.53 135.65,78.62 136.64,77.63 136.64,77.19 135.65,76.2 135.65,73.78 136.13,73.3 137.33,73.3 140.89,69.74 140.89,52.79 149.98,43.7 149.98,41.11 154.39,36.69 154.39,35.65 155.93,34.11 155.93,33.19 157.79,31.32 157.79,30.32 158.45,29.66 158.45,28.11 159.09,27.47 162.26,27.47 163.51,26.23 164.76,26.23 165.99,25 166.79,25 166.8,24.99 167.16,24.99 167.17,25 v1(172.47,25)
  L4 w0.102: v1(130.23,82.48) 129.24,81.48 125.69,81.48 125.51,81.66 125.11,81.66 122.6,79.15 121.37,79.15 120.37,78.14 119.38,78.14 118.3,77.06 118.3,76.96 118.06,76.72 116.29,76.72 115.66,77.35 115.51,77.35 115.51,77.36 v1(115.49,77.36)
  BOTTOM w0.102: R9603.1 130.77,81.65 v2(130.07,81.65) 130.01,81.71 130.01,82.26 v1(130.23,82.48) ; CPU1.AL7 115.15,77.12 115.39,77.36 v1(115.49,77.36)
PM_RSMRST#: length 30.1
  BOTTOM w0.089: 116.71,69.19 116.51,69.39 115.92,69.39 115.17,70.14 115.17,70.72 115.23,70.79 115.23,71.45 CPU1.AW6
  BOTTOM w0.127: 116.71,69.19 116.99,68.91 117.86,68.91 118.9,67.87 118.9,66.76 118.79,66.64 118.79,65.65 120.4,64.03 120.4,63.74 121.02,63.12 121.23,63.12 123.24,63.12 124.47,61.88 124.56,61.88 R1704.2 124.86,61.13 R1702.1 124.18,60.45 122.72,60.45 122.46,60.18 RN1703.4 122.46,59.83 123.83,58.46 123.83,57.24 124.27,56.8 127.23,56.8 v2(127.39,56.96) 128.15,57.72 128.15,58.13 127.61,58.67 Q1701.3
PM_SLP_A#: length 1.2
  TOP w0.102: TP1704.1 116.57,77.26 v1(116.47,77.26)
  BOTTOM w0.102: v1(116.47,77.26) 116.28,77.26 115.99,76.97 CPU1.AL5
PM_SLP_LAN#: length 1.2
  TOP w0.127: v1(114.54,78.32) 114.81,78.58 TP1707.1
  BOTTOM w0.127: v1(114.54,78.32) 114.54,78.27 CPU1.AJ7
PM_SLP_S3#: length 300
  TOP w0.127: R4910.2 103.06,10.35 103.06,9.19 103.4,8.85 103.76,8.85 103.77,8.86 108.44,8.86 110.02,7.28 112.57,7.28 113.67,8.38 Q3601.2 113.67,9.79 113.84,9.96 114.6,9.96 115.16,10.52 115.16,10.82 v1(115.44,11.1) ; v1(163.18,39.5) 163.18,39.48 163.69,38.96 163.69,38.58 163.71,38.56 163.71,38.19 163.69,38.17 KBC24.64 ; R3609.1 139.16,11.08 v2(139.28,11.2) v1(139.72,11.65) ; v1(131.5,131.16) 130.97,131.16 PR4819.1
  L3 w0.127: v1(133.56,88.05) 133.56,87.97 134.26,87.27 138.97,87.27 141.16,85.08 141.16,83.21 v1(140.36,82.41) 140.36,81.33 141.11,80.58 141.11,75.12 144.58,71.66 144.58,62.19 148.75,58.02 149.87,58.02 150.38,57.51 151.85,57.51 152.49,56.86 152.49,55.08 152.64,54.93 152.64,54.61 160.44,46.81 162.11,46.81 165.23,43.7 165.23,41.55 v1(163.18,39.5)
  L4 w0.127: v1(117.24,74.13) 117.24,73.2 120.89,69.55 127.14,69.55 128.41,70.82 129.85,70.82 130.96,71.93 131.85,71.93 132.19,72.26 132.19,79.06 131.03,80.21 131.03,81.18 131.3,81.44 131.92,81.44 132.6,82.12 132.6,83.25 133.27,83.92 133.27,87.72 133.56,88.01 v1(133.56,88.05) ; v1(136.23,109.85) 135.05,108.67 125.34,108.67 124.81,109.19 124.81,110.17 123.96,111.03 123.95,111.03 123.94,111.04 123.67,111.04 123.05,111.66 121.98,111.66 v1(121.98,111.65) 121.78,111.85 121.78,113.39 123.16,114.77 123.16,119.68 123.58,120.1 123.58,123.14 124.12,123.67 124.12,127.5 127.28,130.66 127.44,130.66 127.78,131.01 131.35,131.01 v1(131.5,131.16) ; v1(115.44,11.1) 115.88,11.54 119.54,11.54 120.74,12.74 136.93,12.74 137.74,13.54 138.1,13.54 139.67,11.98 139.67,11.71 v1(139.72,11.65) 140.17,12.09 141.11,12.09 142.44,13.42 150.46,13.42 151.59,12.29 158.43,12.29 159.21,13.07 170.51,13.07 171.12,13.68 171.12,16.39 167.69,19.82 167.54,19.82 166.46,20.9 166.46,20.9 164.86,22.5 164.86,24.36 165.5,25.01 165.5,26.49 166.88,27.87 166.88,32.08 165.54,33.42 165.54,36.45 163.18,38.81 v1(163.18,39.5)
  BOTTOM w0.102: v1(117.24,74.13) 116.94,73.83 CPU1.AT4
  BOTTOM w0.127: PR5110.1 121.1,108.89 121.93,109.72 121.93,111.6 v1(121.98,111.65) ; v1(140.36,82.41) 139.03,83.74 139.03,90.69 138.35,91.38 138.35,92.59 139.43,93.67 139.43,98.33 139.01,98.75 139.01,105.86 136.23,108.64 v1(136.23,109.85)
PM_SLP_S4#: length 205.7
  TOP w0.127: v1(175.49,31.54) 175.88,31.93 176.35,31.93 176.58,31.7 KBC24.21 ; v1(108.82,7.76) 108.12,8.46 106.79,8.46 v2(106.78,8.45) 106.77,8.46 102.32,8.46 101.58,9.2 PR4907.1
  L3 w0.127: v1(164.57,32.43) 164.02,32.97 162.29,32.97 152.78,42.48 152.78,43.9 142.64,54.04 142.64,71.04 137.95,75.73 137.95,79.41 134.31,83.05 133.16,83.05 132.01,84.19 132.01,85.09 131.4,85.7 131.4,85.85 v1(131.11,86.15)
  L4 w0.127: v1(131.11,86.15) 131.05,86.08 131.05,86.03 129.29,84.28 126.65,84.28 126.64,84.27 125.98,84.27 125.72,84.01 125.72,83.83 125.72,83.52 125.15,82.94 124.31,82.94 124.3,82.95 123.7,82.95 122.53,81.77 121.82,81.77 121.27,81.22 120.23,81.22 118.37,79.35 117.21,79.35 116.66,78.81 115.64,78.81 v1(115.17,78.34) ; v1(108.82,7.76) 110.96,5.62 125.51,5.62 126.03,6.14 126.78,6.14 126.91,6.27 129.65,6.27 129.86,6.06 138.02,6.06 138.51,5.57 152.02,5.57 152.87,4.71 164.17,4.71 167.06,7.6 169.95,7.6 176.73,14.38 176.73,17.87 175.78,18.81 175.78,21.28 176.95,22.44 176.95,24.02 177.32,24.39 177.32,27.66 175.93,29.05 175.53,29.05 174.94,29.63 174.94,30.99 v1(175.49,31.54)
  BOTTOM w0.102: CPU1.AJ6 115.61,77.9 v1(115.17,78.34)
  BOTTOM w0.127: v1(175.49,31.54) 175.04,31.99 165.62,31.99 165.61,31.98 165.02,31.98 v1(164.57,32.43)
PM_SLP_S5#: length 1.6
  TOP w0.127: v1(116.43,75.24) 116.86,75.24 TP1703.1
  BOTTOM w0.102: CPU1.AP5 116.18,74.99 v1(116.43,75.24)
PM_SLP_SUS#: length 95.5
  TOP w0.102: v1(119.83,74.54) 119.83,74.25 v2(119.42,73.84) 118.89,73.31 118.89,71.91 122.13,68.66 122.13,67.81 122.56,67.38 123.07,67.38 123.33,67.64 v1(123.76,67.64) ; KBC24.108 168.09,22.9 168.57,23.37 v1(168.57,23.49)
  L3 w0.102: v1(133.15,55.94) 133.15,50.88 136.53,47.51 136.53,43.09 136.84,42.78 139.01,42.78 142.82,38.96 142.82,37.52 144.76,35.58 144.76,33.3 145.52,32.54 145.52,29.52 148.54,26.5 v1(148.54,26.26)
  BOTTOM w0.089: v1(119.83,74.54) 119.59,74.78 119.46,74.78 119.45,74.79 118.95,74.79 118.94,74.79 117.77,74.79 117.73,74.83 117.23,74.83 CPU1.AP4
  BOTTOM w0.102: v1(168.57,23.49) 168.04,23.49 167.43,24.1 166.44,24.1 165.96,24.58 165.43,24.58 165.16,24.31 161.84,24.31 160.86,23.33 159.31,23.33 156.26,26.38 153.67,26.38 153.41,26.64 149.5,26.64 149.12,26.26 v1(148.54,26.26) ; v1(133.15,55.94) 133.15,57.78 R3802.1 132.84,58.28 131.46,58.28 R1729.2 131.52,59.06 131.52,60.47 131.47,60.52 131.47,66.31 131.13,66.65 125.57,66.65 125.18,67.04 124.45,67.04 123.86,67.64 v1(123.76,67.64)
PM_SUS_STAT#: length 14.9
  TOP w0.127: v1(117.26,78.61) 117.71,79.07 118.23,79.07 TP1702.1
  L4 w0.127: v1(117.26,78.61) 117.7,79.06 118.44,79.06 120.34,80.96 121.37,80.96 121.92,81.52 122.63,81.52 123.81,82.69 124.19,82.69 124.2,82.69 125.88,82.69 v1(126.42,83.22)
  BOTTOM w0.102: v1(117.26,78.61) 116.94,78.93 CPU1.AG4
  BOTTOM w0.127: R1724.2 126.61,84.43 126.61,83.42 v1(126.42,83.22)
PM_SUSACK#: length 55.4
  TOP w0.127: KBC24.91 161.05,25.7 160.03,24.68 v1(159.78,24.68)
  L3 w0.127: v1(150.59,39.54) 150.94,39.2 151.5,39.2 153.68,37.02 153.68,36.43 153.68,36.42 153.68,32.29 154.14,31.82 154.14,30.41 154.95,29.6 155.73,29.6 156.02,29.32 156.02,28.24 159.44,24.82 159.64,24.82 v1(159.78,24.68)
  L4 w0.127: v1(131.86,58.8) 131.77,58.7 131.77,58.41 133.85,56.33 133.85,54.14 134.31,53.68 134.31,50.87 134.57,50.61 135.25,50.61 140.44,45.43 141.85,45.43 144.54,42.74 145.02,42.74 147.06,40.71 147.77,40.71 148.37,40.11 149.22,40.11 149.79,39.54 v1(150.59,39.54)
  BOTTOM w0.127: v1(131.86,58.8) 131.86,59.47 131.76,59.57 131.76,60.14 131.83,60.21 RN1702.2 ; v1(159.78,24.68) 160.09,24.68 v2(160.45,24.33)
PM_SUSACK#_R: length 29
  TOP w0.127: v1(119.56,77.21) 119.56,76.69 119.03,76.16 119.03,75.45 v2(119.19,75.3) 119.94,75.3 120.3,74.94 120.3,74.26 120.2,74.16 120.2,73.62 120.19,73.62 120.19,73.25 120.33,73.11 120.33,70.81 122.37,68.76 122.37,67.91 122.66,67.62 122.97,67.62 123.46,68.11 124.18,68.11 v1(124.36,67.93)
  BOTTOM w0.089: CPU1.AK2 118.24,77.47 118.5,77.22 119.56,77.22 v1(119.56,77.21)
  BOTTOM w0.127: RN1702.3 131.83,62.86 131.74,62.94 131.74,65.65 132.25,66.16 132.25,66.96 R1708.2 131.52,67 131.41,66.9 125.67,66.9 125.28,67.28 124.56,67.28 124.32,67.51 124.32,67.89 v1(124.36,67.93)
PM_SUSWARN#: length 49.8
  TOP w0.127: v1(160.88,30.62) 161,30.5 KBC24.79
  L4 w0.127: v1(132.2,59.86) 132.2,59.08 132.31,58.98 132.31,58.23 134.11,56.43 134.11,54.25 134.69,53.66 134.69,51.25 135.07,50.87 135.36,50.87 140.54,45.68 141.95,45.68 144.51,43.12 145,43.12 147.11,41.01 149.01,41.01 149.82,40.2 150.81,40.2 151.47,39.55 155.97,39.55 160.01,35.5 160.01,32.61 160.89,31.73 160.89,30.63 v1(160.88,30.62)
  BOTTOM w0.127: RN1702.1 132.48,60.13 v1(132.2,59.86) ; v1(160.88,30.62) 161.18,30.62 161.35,30.79 v2(161.41,30.79)
PM_SUSWARN#_R: length 25.7
  BOTTOM w0.089: CPU1.AV4 116.92,72.28 117.25,71.95 117.25,71.48 117.3,71.43 117.3,70.74 117.54,70.5
  BOTTOM w0.127: 117.54,70.5 117.71,70.34 118.74,70.34 119.95,69.12 120.4,69.12 121.04,68.49 122.32,68.49 122.62,68.18 123.99,68.18 124.18,68.37 124.55,68.37 125.77,67.15 130.31,67.15 130.67,67.5 130.67,67.62 131.11,68.07 RN1601.5 133.11,67.13 R1708.1 133.11,66.47 v2(132.52,65.89) 132.04,65.41 132.04,63.07 132.48,62.64 RN1702.4
PQ3802_1: length 17.6
  TOP w0.508: v1(110.97,151.38) 110.88,151.28 PR4209.2 PR4202.1
  L4 w0.635: v1(110.97,151.38) 110,150.4 110,149.29 111.92,147.36 116.29,147.36 118.91,144.75 v1(118.97,144.75)
  BOTTOM w0.635: PQ4202.B 118.19,144.95 118.77,144.95 v1(118.97,144.75) v2(120.19,144.75)
PQ3808D: length 17.3
  L4 w0.102: v1(106.45,142.28) 106.4,142.23 101.24,142.23 101.16,142.31 100.8,142.31 100.73,142.23 96.01,142.23 95.48,142.77 95.48,144.31 v1(95.65,144.49)
  BOTTOM w0.102: PQ4208.D 106.04,144.12 106.04,142.69 v1(106.45,142.28) 106.45,142.16 v2(106.93,141.67) ; v1(95.65,144.49) 96.42,145.25 PC4208.2
PQ3808G: length 3.7
  BOTTOM w0.102: PC4209.1 109.14,144.37 PR4215.1 107.94,145.11 PQ4208.G 107.76,145.83 v2(107.16,146.42)
PQ3809_D: length 4.3
  BOTTOM w0.254: PQ4206.3 107.57,154.8 105.85,154.8 105.1,154.05 PR4214.2
PQ4008_2: length 5.4
  TOP w0.254: PQ4408.2 108.3,131.64 108.05,131.89 v1(107.59,131.89) 107.39,131.69 v2(107.39,130.7)
  BOTTOM w0.254: PR4437.2 108.34,132.72 108.53,132.53 PC4425.1 107.78,131.7 v1(107.59,131.89)
PQ4008_6: length 2.6
  TOP w0.14: PQ4408.6 111.03,132.33 v2(112.47,132.33) 112.6,132.2 112.6,131.7 PR4426.1
PQ4203_5: length 3.4
  BOTTOM w0.102: PQ4203.5 109.67,148.2 109.97,147.91 PR4218.1 109.15,147.69 PC4210.1 108.77,147.71 v2(108.23,147.16)
PQ4405_2: length 5.9
  TOP w0.102: PQ4410.2 140.79,141.8 140.51,142.08 140.04,142.08 138.98,143.14 v2(138.13,143.14) 138.13,142.84 PR4476.2 138.78,142.19 PR4475.2
PQ4405_3: length 2.6
  TOP w0.14: PR4466.1 142.85,139.75 v2(142.53,140.06) 141.47,141.13 PQ4410.3
PQ4405_5: length 4.5
  TOP w0.102: PQ4410.5 140.79,143.47 PC4434.1 141.83,145.37 PR4470.2 142.13,145.66 142.88,144.91 v2(142.88,144.72)
PQ4405_6: length 5.4
  TOP w0.102: PQ4410.6 139.59,143.01 138.81,143.79 v2(138.81,144.16) 138.81,144.34 138.99,144.52 PC4434.2 141.24,145.25 PR4473.1
PQ4406_D: length 35.7
  TOP w0.14: v1(141.69,138.83) 142.19,138.33 PR4465.2 ; PQ4414.D 115.37,146.23 v1(115.19,146.4)
  L3 w0.127: v1(115.19,146.4) 115.6,146.4 116.2,147.01 117.03,147.01 117.64,147.62 120.25,147.62 120.89,146.98 122.26,146.98 122.82,146.98 122.86,146.94 123.36,146.94 124.57,148.15 132.92,148.15 139.27,141.8 139.27,140 140.44,138.83 v1(141.69,138.83)
  BOTTOM w0.14: v1(141.69,138.83) v2(141.69,138.23)
PQ4406_G: length 3.4
  TOP w0.102: PQ4414.G 114.12,147.08 PR4474.1 PC4433.2 v2(111.87,146.12)
PQ4408_C: length 6.1
  TOP w0.102: v2(136.67,142.28) 136.68,142.28 136.68,141.67 136.97,141.38 PR4464.1 137.89,141.38 PR4475.1 138,141.27 PQ4409.C
PQ4408_E: length 4.3
  TOP w0.102: PR4469.2 134.88,137.7 v2(135.2,137.38) 135.56,137.38 135.76,137.58 PR4467.1 136.22,139.22 PQ4409.E
PR4601_1: length 1.9
  TOP w0.102: PR4901.2 103.77,20.26 PR4906.1 103.49,21.3 103.13,21.3 v2(102.93,21.5)
PR4605_2: length 2.7
  TOP w0.508: PR4905.2 PC4919.1 99.74,15.53 v2(99.96,15.74)
PROC_OPI_COMP: length 3.8
  BOTTOM w0.102: CPU1.AY15 110.15,70.96 110.15,70.46
  BOTTOM w0.508: R602.1 109.57,67.87 v2(109.57,68.6) 109.57,69.08 110.15,69.65 110.15,70.46
PROC_OPI_COMP3: length 3
  TOP w0.254: R606.1 v2(104.42,83.18) 104.68,82.91 v1(105.18,82.91)
  BOTTOM w0.203: CPU1.Y22 105.61,82.63 105.34,82.9 105.19,82.9 v1(105.18,82.91)
PROCHOT_EC: length 9
  TOP w0.14: Q2401.G 183.11,36.37 182.5,35.77 R2438.1 182.44,35.77 R2442.1 181.55,32.92 v2(181.37,32.74) 181.34,32.71 179.52,32.71 179.33,32.9 KBC24.24
PS_ID: length 6.8
  TOP w0.508: v1(116.15,143.98) 116.09,144.04 PR4205.1
  BOTTOM w0.508: v1(116.15,143.98) 114.1,143.98 v2(114.08,143.96) 113.7,143.59 113.16,143.59 PR4206.2 112.63,144.26 113.76,145.39 PQ4201.S
PS_ID_R: length 5.8
  TOP w0.102: DCIN1.4 104.95,149.7 AFTP3802.1 105.28,149.37 106.14,149.37 106.31,149.53 107.4,149.53 PR4217.1
PS_ID_R2: length 11.3
  L4 w0.635: v1(113.31,146.37) 111.79,146.37 109.22,148.94 109.22,150.44 v1(108.43,151.23)
  BOTTOM w0.508: PQ4201.D 111.73,145.88 111.73,145.14 111.75,145.13 PR4206.1
  BOTTOM w0.635: PQ4201.D v1(113.31,146.37)
  vias: v2(109.19,150.99)
PS_S3CNTRL: length 4.6
  TOP w0.127: R3607.2 114.11,12.77 113.67,12.34 v2(113.67,12.11) Q3601.5 113.67,10.29 113.51,10.13 113.11,10.13 113.02,10.22 Q3601.6
PSID_DISABLE#_R_C: length 7.7
  BOTTOM w0.508: PR4203.2 v2(120.97,147.63)
  BOTTOM w0.635: PQ4201.G 115.6,147.36 115.96,146.99 PQ4202.C 117.07,147.32 117.64,147.9 119.29,147.9 PR4203.2
PSID_EC: length 172.6
  TOP w0.102: v1(166.98,25.42) 166.98,25.42 166.54,25.42 164.49,23.37 KBC24.99 ; PD4203.3 113.38,143.76 PR4204.2 114.47,144.04 PR4205.2 114.47,144.26 115,144.79 115,145.79 114.55,146.24 v1(114.55,146.39) ; v1(148.81,56.57) 148.81,53.95 149.58,53.17 v2(149.59,53.17) 149.59,53.17 158.41,44.34 v1(158.41,42.97)
  L3 w0.102: v1(142.19,137.1) 141.38,137.1 138.68,139.79 138.68,141.59 133.23,147.05 128.51,147.05 128.46,147 125.65,147 124.71,146.07 123.77,146.07 123.77,146.07 123.31,146.07 122.99,146.38 122.63,146.38 122.59,146.42 122.03,146.42 120.67,146.42 120.5,146.25 116.24,146.25 115.75,145.76 114.98,145.76 114.55,146.18 v1(114.55,146.39)
  L4 w0.102: v1(158.41,42.97) 158.41,42.98 158.87,43.43 159.85,43.43 163.75,39.54 163.75,38.68 165.78,36.64 165.78,33.52 167.12,32.18 167.12,27.33 166.21,26.42 166.21,25.9 166.46,25.65 166.76,25.65 v1(166.98,25.42)
  BOTTOM w0.102: v1(148.81,56.57) 148.78,56.6 148.78,59.02 145.9,61.89 145.9,66.38 145.74,66.55 145.74,80.48 146.25,80.99 146.25,87.23 146.78,87.76 146.78,89.77 146.25,90.3 146.25,98.81 143.68,101.38 143.68,110.76 142.16,112.28 142.16,112.94 140.37,114.74 140.37,120.38 141.83,121.85 141.83,126.68 144.71,129.56 144.71,132.77 142.19,135.29 v1(142.19,137.1)
PSL_IN1#: length 3.9
  TOP w0.102: R2430.2 158.55,33.31 159.51,33.31 v2(159.58,33.39) 159.59,33.39 159.71,33.39 160.2,32.9 KBC24.73
PSL_IN2#: length 5.6
  TOP w0.102: v1(164.44,25.65) 164.44,25.4 163.94,24.9 KBC24.93
  BOTTOM w0.102: v1(164.44,25.65) 164.44,25.77 164.68,26.02 R2427.2 164.23,26.76 v2(163.8,26.76) 163.36,26.76 R2425.1
PSL_OUT#: length 17.9
  TOP w0.102: R2432.1 152.37,30.77 152.37,31.74 151.81,32.3 151.81,33.53 152.15,33.87 152.91,33.87 v2(153.39,34.36) 153.62,34.36 153.74,34.23 153.74,32.28 154.1,31.92 155.47,31.92 156.04,32.49 156.51,32.49 156.9,32.88 159.92,32.88 160.31,32.5 KBC24.74
PU4401_4: length 4.4
  TOP w0.254: PU4407.4 122.27,145.34 PR4410.2 PC4424.2 123.93,145.2 v2(124.31,144.81) 124.4,144.72 PR4454.2
PU4401_5: length 4.4
  TOP w0.254: PU4407.5 122.32,145.99 PR4410.1 PC4424.1 124.3,146.09 v2(124.35,146.03) 124.77,145.61 PR4448.2
PU4401_6: length 1.5
  TOP w0.127: PU4407.6 122.07,146.64 PR4446.2
PU5102_PG: length 1.5
  TOP w0.102: TP5101.1 v1(160.35,61.28)
  BOTTOM w0.102: v1(160.35,61.28) 160.26,61.19 PU5102.2
PURE_HW_SHUTDOWN#: length 154.7
  TOP w0.102: Q3602.C 151.66,16.35 v1(151.4,16.08) ; R2424.1 156.71,26.81 Q2404.B 154.7,24.79 R2439.2 155.35,23.72 C2610.1 154.82,23.52 v2(154.46,23.16) 153.7,22.4 D3602.3 154.06,21.97 154.95,21.07 Q2602.D 155.76,21.67 v1(155.6,21.84)
  L3 w0.102: v1(183.36,19.19) 183.16,18.99 178.94,18.99 178.81,19.12 172.88,19.12 172.37,19.63 169.63,19.63 169.4,19.85 164.98,19.85 164.82,20.01 159.37,20.01 158.94,20.44 157,20.44 v1(155.6,21.84) ; v1(185.02,34.25) 185.02,38.76 186.26,40 187.78,40 189.48,41.7 189.48,60.01 192.68,63.21 192.68,74.36 193.77,75.45 193.77,79.72 193.47,80.03 193.47,86.83 192.38,87.93 192.38,90.47 193.57,91.66 193.57,95.17 192.02,96.72 190.78,96.72 187.67,99.83 187.67,102.02 190.34,104.69 v1(190.5,104.69)
  L4 w0.102: v1(185.02,34.25) 184.36,33.59 184.36,33.25 184.36,32.89 184.36,32.89 184.36,32.5 184.79,32.07 184.79,31.27 184.35,30.83 184.35,24.64 183.94,24.23 183.94,21.17 183.36,20.59 v1(183.36,19.19)
  BOTTOM w0.102: v1(151.4,16.08) 152.2,16.89 152.2,18.44 v1(155.6,21.84) 162.75,21.84 R2612.1 ; R7653.2 C7610.1 190.12,105.07 v1(190.5,104.69)
PWR_1D05V_BOOT: length 4.4
  TOP w0.305: PU4806.10 130.33,126.2 v2(131.54,124.99)
  TOP w0.508: v2(131.54,124.99) 131.66,124.87 132.09,124.87 132.63,124.33 PR4820.1
PWR_1D05V_BOOT_R: length 2.3
  TOP w0.762: PC4822.2 130,123.58 v2(130.04,123.62) 130.08,123.58 PR4820.2
PWR_1D05V_CCM: length 2.7
  TOP w0.254: PU4806.5 127.4,129.3 126.85,128.74 PR4824.1 126.32,128.02 v2(126.13,127.83)
PWR_1D05V_EN: length 2.5
  TOP w0.305: PC4821.1 128.8,130.71 PU4806.3
  TOP w0.508: PR4819.2 PC4821.1
PWR_1D5V_EN: length 2.6
  BOTTOM w0.127: v2(120.31,107.66) 120.21,107.76 PR5110.2 119.68,108.58 119.61,108.52 PU5101.3
PWR_1D05V_FB: length 5.5
  TOP w0.305: PU4806.4 128.3,129.81 128.02,130.09 127.2,130.09 126.72,129.61 PR4823.1
  TOP w0.508: PR4823.1 126.34,129.62 PC4823.2 PR4822.2 v2(124.51,130.43)
PWR_1D05V_LGATE: length 8.2
  TOP w0.305: v3(127.15,126.23) 127.18,126.2 PU4806.6
  L4 w1.016: v3(127.15,126.23) 126.82,125.9 v3(126.82,119.7)
  BOTTOM w0.508: v3(127.15,126.23) v2(126.26,126.23)
PWR_1D05V_PHASE: length 17.8
  TOP w0.305: v3(128.8,124.96) PU4806.8 ; PU4808.3 132.86,113.97 v3(132.53,113.64)
  TOP w0.508: v3(128.8,124.96) 128.8,124.91 127.68,123.79 PC4822.1
  L4 w1.016: v3(128.8,124.96) 128.8,124.12 130.88,122.04 130.88,115.42 132.53,113.77 v3(132.53,113.64)
  vias: v2(128.52,112.59) v3(126.57,113.86) v3(126.57,112.84) v3(127.48,112.87) v3(128.62,113.89) v3(129.77,112.87) v3(130.91,113.89) v3(130.91,112.87)
PWR_1D05V_PWR: length 37.5
  TOP w0.254: PR4822.1 PC4823.1 126.81,131.79 v2(130.71,131.79) 132.09,131.79 133.6,130.28 v1(133.6,126.97)
  BOTTOM w0.254: PG4832.1 133.86,108.25 136.33,110.73 136.33,111.95 136.83,112.45 136.83,124.01 133.9,126.94 133.63,126.94 v1(133.6,126.97)
PWR_1D05V_PWRGD: length 2.6
  TOP w0.305: PR4821.1 131.63,129 131.43,128.8 v2(131.14,128.8) 130.63,129.3 PU4806.1
PWR_1D05V_SNUB:
  vias: v2(125.47,118.43)
PWR_1D05V_TRIP: length 3.5
  TOP w0.254: PU4806.2 129.3,129.84 129.53,130.07 131.12,130.07 v2(131.16,130.03) 131.43,130.03 131.61,129.85 PR4817.2
PWR_1D05V_UGATE: length 14.7
  TOP w0.305: PU4806.9 129.3,125.48 v3(129.94,124.83)
  L4 w1.016: v3(129.94,124.83) 132.03,122.75 132.03,115.89 v3(133.68,114.24)
  BOTTOM w0.508: v3(129.94,124.83) v2(129.94,125.72)
PWR_1D35V_DRVH: length 15.4
  TOP w0.203: v3(102.31,13.66) 102.8,14.15 PU4901.14
  L4 w1.016: v3(102.31,13.66) 95.75,13.66 94.36,12.26 v3(90.37,12.26)
  BOTTOM w0.508: v3(102.31,13.66) 102.31,12.36 v2(102.27,12.32)
PWR_1D35V_DRVL: length 10.4
  TOP w0.203: v3(103.58,16.07) 103.68,15.97 PU4901.11
  L4 w1.016: v3(103.58,16.07) 103.4,16.07 100.35,19.12 v3(95.96,19.12)
  BOTTOM w0.508: v3(103.58,16.07) 103.65,16.07 v2(104.14,15.58)
PWR_1D35V_EN: length 3.6
  TOP w0.127: PU4901.16 104.43,12.86 v2(103.35,11.78) 103.02,11.45 PC4906.1 PR4907.2
PWR_1D35V_MODE: length 2.8
  TOP w0.203: v2(106.32,11.9) 106.09,12.13 105.93,12.13 105.63,12.43 PU4901.19
  TOP w0.254: PR4908.2 107.08,11.15 v2(106.32,11.9)
PWR_1D35V_REFIN: length 5.4
  TOP w0.203: 105.23,17.78 PU4901.8
  TOP w0.254: v2(102.75,19.31) 102.75,19.31 PR4901.1 PC4902.1 104.53,19.25 PR4903.2 105.23,17.78
PWR_1D35V_SW: length 15.5
  TOP w0.203: PU4901.13 102.44,14.55 v3(102.05,14.93)
  TOP w0.508: v3(102.05,14.93) 101.67,14.55 PC4919.2
  L4 w1.016: v3(102.05,14.93) 94.76,14.93 93.39,13.56 v3(90.05,13.56)
  vias: v2(89.2,13.3) v3(89.1,17.72) v3(89.1,16.58) v3(89.1,15.44) v3(89.1,14.29) v3(90.12,18.23) v3(90.12,16.96) v3(90.06,15.82) v3(90.06,14.67)
PWR_1D35V_TRIP: length 3.6
  TOP w0.203: 105.38,12.11 105.23,12.26 PU4901.18
  TOP w0.254: 105.38,12.11 106.26,11.23 PR4902.1 106,10.6 v2(105.34,10.6)
PWR_1D35V_VBST: length 3.1
  TOP w0.203: 102.96,13.26 103.44,13.75 PU4901.15
  TOP w0.508: PR4905.1 101.78,13.15 102,12.92 v2(102.31,12.92) 102.61,12.92 102.96,13.26
PWR_1D35V_VDDQS: length 38.9
  TOP w0.203: v1(104.72,17.47) 104.83,17.36 PU4901.9
  L3 w0.254: v1(104.72,17.47) 104.72,20.29 103.35,21.66 90.37,21.66 88.64,19.93 85.21,19.93 83.34,18.05 77.2,18.05 v1(76.17,17.03)
  BOTTOM w0.254: PG4907.1 76.35,14.33 76.54,14.52 v2(76.54,15.51) 76.54,16.66 v1(76.17,17.03)
PWR_1D35V_VREF: length 3.7
  TOP w0.203: PU4901.6 106.03,16.62 106.25,16.83
  TOP w0.254: 106.25,16.83 106.25,17.52 v2(106.04,17.72) 105.42,18.34 PR4903.1 105.42,19.25 PC4903.1
PWR_1D35V_VTTREF: length 5.6
  TOP w0.203: 106.78,16.6 PU4901.5
  TOP w0.254: 106.78,16.6 106.94,16.77 PC4918.1 106.94,18.08 106.75,18.27 PR4911.1 107.43,18.84 107.97,19.38 v2(107.97,19.85)
PWR_3D3V_CS2: length 3.4
  TOP w0.203: PU4503.5 128.98,39.72
  TOP w0.254: 128.98,39.72 128.46,39.72 127.7,40.48 v2(127.35,40.48) 126.97,40.48 126.76,40.26 PR4517.1
PWR_3D3V_DRVH2: length 17.7
  TOP w0.203: v3(127.84,36.77) 127.84,36.9 128.31,37.37 PU4503.10
  L4 w0.762: v3(122.37,24.58) 122.37,32.16 126.99,36.77 v3(127.84,36.77)
  BOTTOM w0.508: v2(126.57,36.16) 127.18,36.77 v3(127.84,36.77)
PWR_3D3V_DRVL2: length 9.7
  TOP w0.203: PU4503.11 129.45,35.81 v3(129.23,35.59)
  L4 w1.016: v3(124.66,29.91) 124.66,31.02 v3(129.23,35.59)
  BOTTOM w0.508: v3(129.23,35.59) v2(129.23,34.61)
PWR_3D3V_EN2: length 2.6
  TOP w0.127: PR4506.2 127.23,39.44 v2(127.4,39.26) 127.7,38.97 PU4503.6
PWR_3D3V_FB2: length 4.9
  TOP w0.203: 129.61,40.45 129.85,40.22 PU4503.4
  TOP w0.254: PC4523.2 PR4512.2 128.85,42.3 PR4523.1 129.11,41.37 v2(129.13,41.34) 129.13,40.94 129.61,40.45
PWR_3D3V_FB2_R: length 2.4
  TOP w0.254: PC4523.1 126.6,42.55 126.39,42.77 v2(126.39,42.94) 126.39,43.12 126.64,43.38 PR4535.2
PWR_3D3V_LL2: length 19.3
  TOP w0.203: PU4503.8 127.33,38.17 127.07,37.91 v3(127.07,37.79)
  TOP w0.508: v3(127.07,37.79) 126.71,37.42 PC4535.2
  L4 w0.762: v3(121.36,24.58) 121.36,32.58 126.57,37.79 v3(127.07,37.79)
  vias: v2(124.48,23.26) v3(120.22,24.58) v3(120.22,23.44) v3(121.36,23.44) v3(122.63,23.44) v3(123.77,24.2) v3(124.79,24.2) v3(125.8,24.2) v3(126.82,24.2)
PWR_3D3V_SNUB: length 2.9
  TOP w0.508: PC4520.1 v2(128.85,26.79) 129.09,26.55 PR4533.2
PWR_3D3V_VBST2: length 3.7
  TOP w0.203: 126.77,36.57 127.96,37.77 PU4503.9
  TOP w0.508: 126.77,36.57 v2(126.76,36.57) 126.35,36.15 PR4528.2
PWR_3D3V_VBST2_1: length 3
  TOP w0.508: PC4535.1 123.58,37.42 123.26,37.11 v2(123.26,36.75) 123.26,36.42 123.53,36.15 PR4528.1
PWR_5V_CS1: length 3
  TOP w0.203: PU4503.1 131.05,39.98 v1(131.46,40.39)
  BOTTOM w0.254: PR4531.1 130.59,39.88 v2(130.61,39.87) 130.94,39.87 v1(131.46,40.39)
PWR_5V_DRVH1: length 17.9
  TOP w0.203: v3(132.66,36.9) 132.19,37.37 PU4503.16
  L4 w0.762: v3(132.66,36.9) 133.68,36.9 139.77,30.8 v3(139.77,24.58)
  BOTTOM w0.508: v3(132.66,36.9) v2(131.68,36.9)
PWR_5V_DRVL1: length 9.5
  TOP w0.203: v3(131.9,35.88) 131.39,35.88 131.05,36.22 PU4503.15
  L4 w1.016: v3(131.9,35.88) 132.28,35.5 v3(132.28,28.9)
  BOTTOM w0.508: v3(131.9,35.88) v2(131.9,34.9)
PWR_5V_EN1: length 5.4
  TOP w0.127: v2(134.16,43.01) 133.95,42.79 PR4504.2 133.25,41.31 132.73,40.79 132.73,40.14 131.8,39.21 PU4503.20
PWR_5V_EN1_R: length 11.3
  TOP w0.127: PR4504.1 132.37,44.56 125.97,44.56 v2(125.71,44.29) 125.46,44.05 PR4501.2 PR4530.1 125.46,41.24 PR4507.2
PWR_5V_FB1: length 5.9
  TOP w0.203: PU4503.2 130.65,40.25 130.86,40.46 130.86,40.7 v1(131.14,40.97)
  BOTTOM w0.254: PR4526.1 132.07,43.11 131.79,42.83 131.79,42.82 PR4527.2 130.81,42.56 130.58,42.33 v2(130.58,42.18) 130.58,41.9 130.81,41.67 PC4522.2 131.53,41.37 v1(131.14,40.97)
PWR_5V_FB1_R: length 2.3
  BOTTOM w0.254: PC4522.1 132.42,41 132.64,40.78 v2(132.81,40.78) 133.02,40.78 133.27,41.04 PR4525.2
PWR_5V_LL1: length 23.3
  TOP w0.203: v3(132.92,38.17) PU4503.18
  TOP w0.508: PC4516.2 134.18,38.3 133.05,38.3 v3(132.92,38.17)
  L4 w0.762: v3(132.92,38.17) 133.85,38.17 140.79,31.22 140.79,24.16 140.2,23.56 v3(138.5,23.56)
  vias: v2(135.25,23.41) v3(132.79,24.45) v3(133.68,24.45) v3(134.57,24.45) v3(135.46,24.45) v3(136.34,24.45) v3(137.23,24.45) v3(138.12,24.45)
PWR_5V_SNUB: length 2.9
  TOP w0.508: PR4529.2 130.88,25.44 130.88,26.87 v2(130.89,26.87) 130.88,26.88 PC4536.1
PWR_5V_VBST1: length 3.2
  TOP w0.203: v2(133.5,37.18) 133.14,37.53 132.53,37.53 132.3,37.77 PU4503.17
  TOP w0.508: PR4524.1 134.01,36.67 v2(133.5,37.18)
PWR_5V_VBST1_1: length 2.4
  TOP w0.508: PC4516.1 PR4524.2 v2(135.86,35.5)
PWR_5V_VCLK: length 5.4
  TOP w0.102: PC4514.1 PC4532.1 134.43,39.96 PC4521.1 133.63,39.03 v2(133.47,39.18) 133.04,39.18 132.43,38.57 PU4503.19
PWR_5V_VO1: length 88.6
  TOP w0.203: v1(130.76,35.76) 130.65,35.86 PU4503.14
  L3 w0.508: v1(137.92,13.1) 137.92,13.1 137.92,16.12 143.26,21.46 143.26,31.6 142.5,32.37 142.5,34.31 136.58,40.23 135.33,40.23 134.85,40.71 132.91,40.71 131.52,39.32 131.52,37.9 130.76,37.14 v1(130.76,35.76)
  BOTTOM w0.254: PR4527.1 133.26,42.56 PR4525.1 133.6,42.88 133.6,44.14 134.37,44.9 140.81,44.9 141.32,44.39 v2(141.32,39.93) 141.32,36.13 144.11,33.34 144.11,22.31 137.89,16.1 PG4532.2 137.89,13.12 v1(137.92,13.1)
PWR_CHG_ACDET: length 5.4
  TOP w0.254: v1(101.8,136.15) 102,135.96 PR4431.1 PC4412.1
  BOTTOM w0.254: PU4404.6 102.38,136.74 v1(101.8,136.15) 101.73,136.09 101.67,136.09 v2(101.24,135.65) 100.86,135.27 100.86,134.94 100.59,134.67 PR4407.2
PWR_CHG_ACN: length 22.3
  TOP w0.254: v2(106.45,131.64) PR4406.1 PC4402.2 105.55,133.51 PC4403.1 105.71,134.45 105.99,134.73 v1(105.99,135.07)
  L4 w0.254: v1(93.8,140.4) 93.96,140.57 94.57,140.57 94.94,140.2 95.36,140.2 97.95,137.61 98.17,137.61 101.81,133.96 105.42,133.96 105.86,134.41 105.86,134.94 v1(105.99,135.07)
  BOTTOM w0.254: v1(105.99,135.07) 105.99,135.58 105.85,135.72 PU4404.1 ; v1(93.8,140.4) 93.61,140.21 PG4403.2
PWR_CHG_ACOK: length 87.5
  TOP w0.102: PR4476.1 137.42,142.66 136.27,142.66 135.47,141.87 v2(135.24,141.87) 134.9,141.53 v1(134.9,141.16) ; v1(110.28,130.32) 110.06,130.32 109.39,130.99 PQ4408.3
  L3 w0.102: v1(93.16,146.27) 92.71,146.73 91.74,146.73 90.53,145.52 90.53,140.14 95.65,135.02 97.99,135.02 99.06,133.95 99.06,132.86 99.57,132.35 99.57,131.33 99.82,131.08 102.95,131.08 103.38,131.52 103.38,131.76 103.63,132.01 104,132.01 104.22,131.79 105.09,131.79 v1(105.87,131) ; v1(134.9,141.16) 135,141.05 136.15,141.05 140.15,137.05 140.15,134.36 137.95,132.15 135.41,132.15 134.24,133.32 133,133.32 132.57,133.75 125.05,133.75 120.18,128.88 116.3,128.88 116.13,128.88 113.08,131.93 111.9,131.93 v1(110.28,130.32)
  BOTTOM w0.102: PQ4402.2 92.73,146.7 v1(93.16,146.27) ; v1(110.28,130.32) 109.76,129.79 108.17,129.79 107.65,130.31 PR4436.1 107.38,130.31 PR4428.2 106.49,130.37 PR4419.2 105.55,130.68 v1(105.87,131)
PWR_CHG_ACP: length 22
  TOP w0.254: v1(105.36,135.07) 105.36,134.82 104.62,134.08 PC4404.1 104.66,133.63 PC4402.1 PR4406.2 104.66,131.21 v2(105.13,130.74)
  L4 w0.254: v1(93.8,141.17) 94.02,140.95 94.73,140.95 95.1,140.58 95.52,140.58 98.11,137.99 98.33,137.99 101.97,134.35 105.27,134.35 105.48,134.56 105.48,134.94 v1(105.36,135.07)
  BOTTOM w0.254: v1(93.8,141.17) 93.61,141.36 PG4402.2 ; v1(105.36,135.07) 105.36,135.32 105.35,135.33 PU4404.2
PWR_CHG_AD_OFF: length 176.4
  TOP w0.102: KBC24.11 176.83,27.7 176.55,27.98 176.55,28.47 176.14,28.87 175.11,28.87 174.68,28.44 v1(174.67,28.44)
  L3 w0.102: v1(174.67,28.44) 174.91,28.68 174.91,29.95 172.69,32.16 166.8,32.16 165.24,33.72 163.49,33.72 162.65,34.55 162.65,34.63 158.43,38.85 157.88,38.85 153.78,42.96 153.78,44.29 149.74,48.32 149.74,51.38 v1(149.06,52.07)
  L4 w0.102: v1(111.12,153.33) 111.35,153.33 114.33,150.35 123.26,150.35 125.44,148.18 126.41,148.18 126.77,148.53 127.61,148.53 127.97,148.18 130.09,148.18 133.51,144.76 133.51,142.26 134.36,141.41 134.36,140.13 134.45,140.04 134.45,137.05 134.81,136.69 134.81,132.09 134.98,131.93 134.98,128.85 138.63,125.19 138.63,125.19 138.63,118.36 138.63,118.36 138.63,117.99 139.9,116.72 139.9,116.54 139.96,116.48 139.96,110.7 139.42,110.16 139.42,108.41 143.18,104.65 143.18,102.42 144.83,100.77 144.83,99.93 145.16,99.6 145.16,95.37 146.34,94.19 146.34,87.73 144.84,86.23 144.84,61.97 150.14,56.67 150.14,53.15 v1(149.06,52.07)
  BOTTOM w0.102: v1(174.67,28.44) v2(174.67,29.04) ; v1(111.12,153.33) 111.1,153.36 PQ4206.5 109.32,153.36 109.14,153.18 109.14,152.53 108.28,151.66 108.26,151.66 107.85,151.26 PR4210.1
PWR_CHG_AD_OFF_R: length 12.4
  TOP w0.102: v2(107.36,141.44) 106.98,141.83 PQ4204.B 106.98,143.94 107.13,144.09 107.13,146.71 106.86,146.98 106.26,146.98 106.09,147.15 106.09,148.26 v1(106.87,149.04)
  BOTTOM w0.102: PR4210.2 107.64,149.98 107.54,149.88 PR4211.1 ; v1(106.87,149.04) 107.13,149.31 PR4211.1 ; PR4211.1 108.42,149.31 108.74,148.99 PQ4203.6
PWR_CHG_BAT_SCL: length 4.1
  BOTTOM w0.14: PU4404.9 101.83,138.24 101.83,138.24 v2(101.83,138.24) 101.82,138.24 101.03,138.24 101,138.21 100.05,137.25 99.74,137.25 PG4407.1
PWR_CHG_BAT_SDA: length 4.1
  BOTTOM w0.14: PU4404.8 103.05,137.72 101.24,137.72 100.6,137.07 ; PG4408.1 99.78,136.73 100.26,136.73 100.6,137.07 ; 100.6,137.07 v2(100.6,137.08)
PWR_CHG_BTST: length 4
  TOP w0.508: v2(108.28,139.92) 108,139.64 v1(107.52,139.64) 107.41,139.74 PR4409.1
  BOTTOM w0.305: v1(107.52,139.64) 107.52,138.63 107.12,138.24 PU4404.17
PWR_CHG_BTST_R: length 5.9
  TOP w0.254: PC4411.1 v2(106.31,137.33) 106.31,138.23 PR4409.2 106.96,138.88 108.28,138.88 v1(108.4,139.01)
  BOTTOM w0.254: PD4401.K 108.79,138.63 v1(108.4,139.01)
PWR_CHG_CMPIN: length 7.9
  TOP w0.254: v1(103.96,135.07) 104.64,135.07 105.13,135.56 v2(105.13,135.93) 105.04,136.02 PR4413.1
  BOTTOM w0.254: PU4404.4 104.35,135.46 v1(103.96,135.07) 103.96,134.62 PR4414.2 102.93,133.59 PR4411.2 PR4427.2 103.82,133.12 PR4429.1
PWR_CHG_CMPIN_R: length 7.6
  BOTTOM w0.254: PR4429.2 104.51,132.02 104.51,131.34 103.54,130.37 v2(102.31,130.37) 101.99,130.69 100.1,130.69 99.49,131.3 99.49,131.34 99.07,131.75 PQ4407.3
PWR_CHG_CMPIN_RR: length 10.9
  L3 w0.254: v1(103.81,131.58) 103.81,131.34 103.13,130.65 99.64,130.65 99.13,131.15 99.13,131.93 97.42,133.64 v1(97.25,133.64)
  BOTTOM w0.254: v2(103.35,131.01) 103.81,131.47 v1(103.81,131.58) 103.81,131.58 PR4427.1 ; PQ4407.6 97.05,133.06 97.05,133.34 97.25,133.54 v1(97.25,133.64)
PWR_CHG_CMPOUT: length 7.6
  BOTTOM w0.254: PR4432.1 105.29,133.67 105.29,133.66 105.61,133.35 PR4438.1 PR4430.2 106.5,133.6 106.86,133.96 v2(107.03,133.96) 107.23,133.96 107.45,133.74 PR4437.1 ; PR4432.1 105.04,134.6 104.85,134.79 PU4404.3 ; PR4432.1 PR4414.1
PWR_CHG_CSON_1: length 38.5
  TOP w0.254: v1(104.77,143.3) 104.32,142.84 104.03,142.84 103.58,142.39 PC4423.1
  L3 w0.254: v1(128.6,151.21) 128.39,151 125.4,151 125.14,150.74 119.68,150.74 118.59,149.65 116.8,149.65 116.62,149.47 113.74,149.47 112.8,148.54 112.77,148.54 111.85,147.62 110.06,147.62 109.51,147.07 109.51,146.78 108.63,145.9 108.22,145.9 106.83,144.52 105.96,144.52 104.77,143.33 v1(104.77,143.3)
  BOTTOM w0.254: 132.44,148.79 132.44,149.83 131.29,150.99 128.83,150.99 v1(128.6,151.21) ; 132.44,148.79 132.44,148.29 PG4410.1 ; 132.44,148.79 v2(132.53,148.79) ; PR4420.2 103.57,141.83 PC4421.2 103.57,142.97 103.91,143.32 104.76,143.32 v1(104.77,143.3)
PWR_CHG_CSOP_1: length 36.6
  TOP w0.254: PC4420.1 104.54,142.32 105.41,143.19 v1(105.41,143.25)
  L3 w0.254: v1(128.6,150.26) 128.25,150.62 125.56,150.62 125.3,150.36 119.84,150.36 118.75,149.27 116.95,149.27 116.78,149.09 113.89,149.09 112.96,148.16 112.93,148.16 112.01,147.23 110.22,147.23 109.89,146.91 109.89,146.63 108.79,145.52 108.37,145.52 106.99,144.14 106.12,144.14 105.41,143.43 v1(105.41,143.25)
  BOTTOM w0.254: PG4409.1 132.06,148.24 132.06,149.68 131.73,150.01 ; 131.73,150.01 131.13,150.61 128.95,150.61 v1(128.6,150.26) ; 131.73,150.01 v2(131.65,149.93) ; v1(105.41,143.25) 105.31,143.15 105.31,143.09 105.01,142.79 104.61,142.79 PC4421.1 104.46,141.83 PR4421.2
PWR_CHG_HIDRV: length 18.4
  TOP w0.356: v3(121.1,135.2) 121.1,135.2 v2(120.6,135.69)
  TOP w0.508: PC4413.2 108.57,138.27 108.27,137.97 v3(107.92,137.97)
  L4 w1.016: v3(107.92,137.97) 107.94,137.99 108.65,137.99 109.38,138.73 116.32,138.73 119.85,135.2 v3(121.1,135.2)
  BOTTOM w0.305: v3(107.92,137.97) 107.68,137.74 PU4404.18
PWR_CHG_IFAULT: length 5.1
  BOTTOM w0.254: PR4418.2 102.41,142.24 101.48,141.31 v2(101.48,140.86) 102.81,139.54 PU4404.11
PWR_CHG_ILIM: length 4
  BOTTOM w0.254: PR4417.2 100.38,138.94 PR4423.1 100.97,138.94 101.46,139.43 v2(101.55,139.43) 101.78,139.43 102.47,138.74 PU4404.10
PWR_CHG_IOUT: length 12.3
  TOP w0.254: v1(102.27,131.93) 102.27,133.61 v2(101.78,134.1) 101.27,134.61 101.27,136.68 v1(101.61,137.03) 101.79,137.03 PC4422.1 PR4424.1
  BOTTOM w0.254: PR4422.1 100.34,135.54 100.78,135.98 100.78,136.2 v1(101.61,137.03) 101.82,137.24 PU4404.7 ; v1(102.27,131.93) 102.56,132.22 PR4411.1
PWR_CHG_LODRV: length 12.1
  TOP w0.508: v3(115.77,142.05) v2(116.46,142.05)
  L4 w1.016: v3(115.77,142.05) 110.18,142.05 108.91,140.78 v3(106.25,140.78)
  BOTTOM w0.305: v3(106.25,140.78) 105.85,140.39 PU4404.15
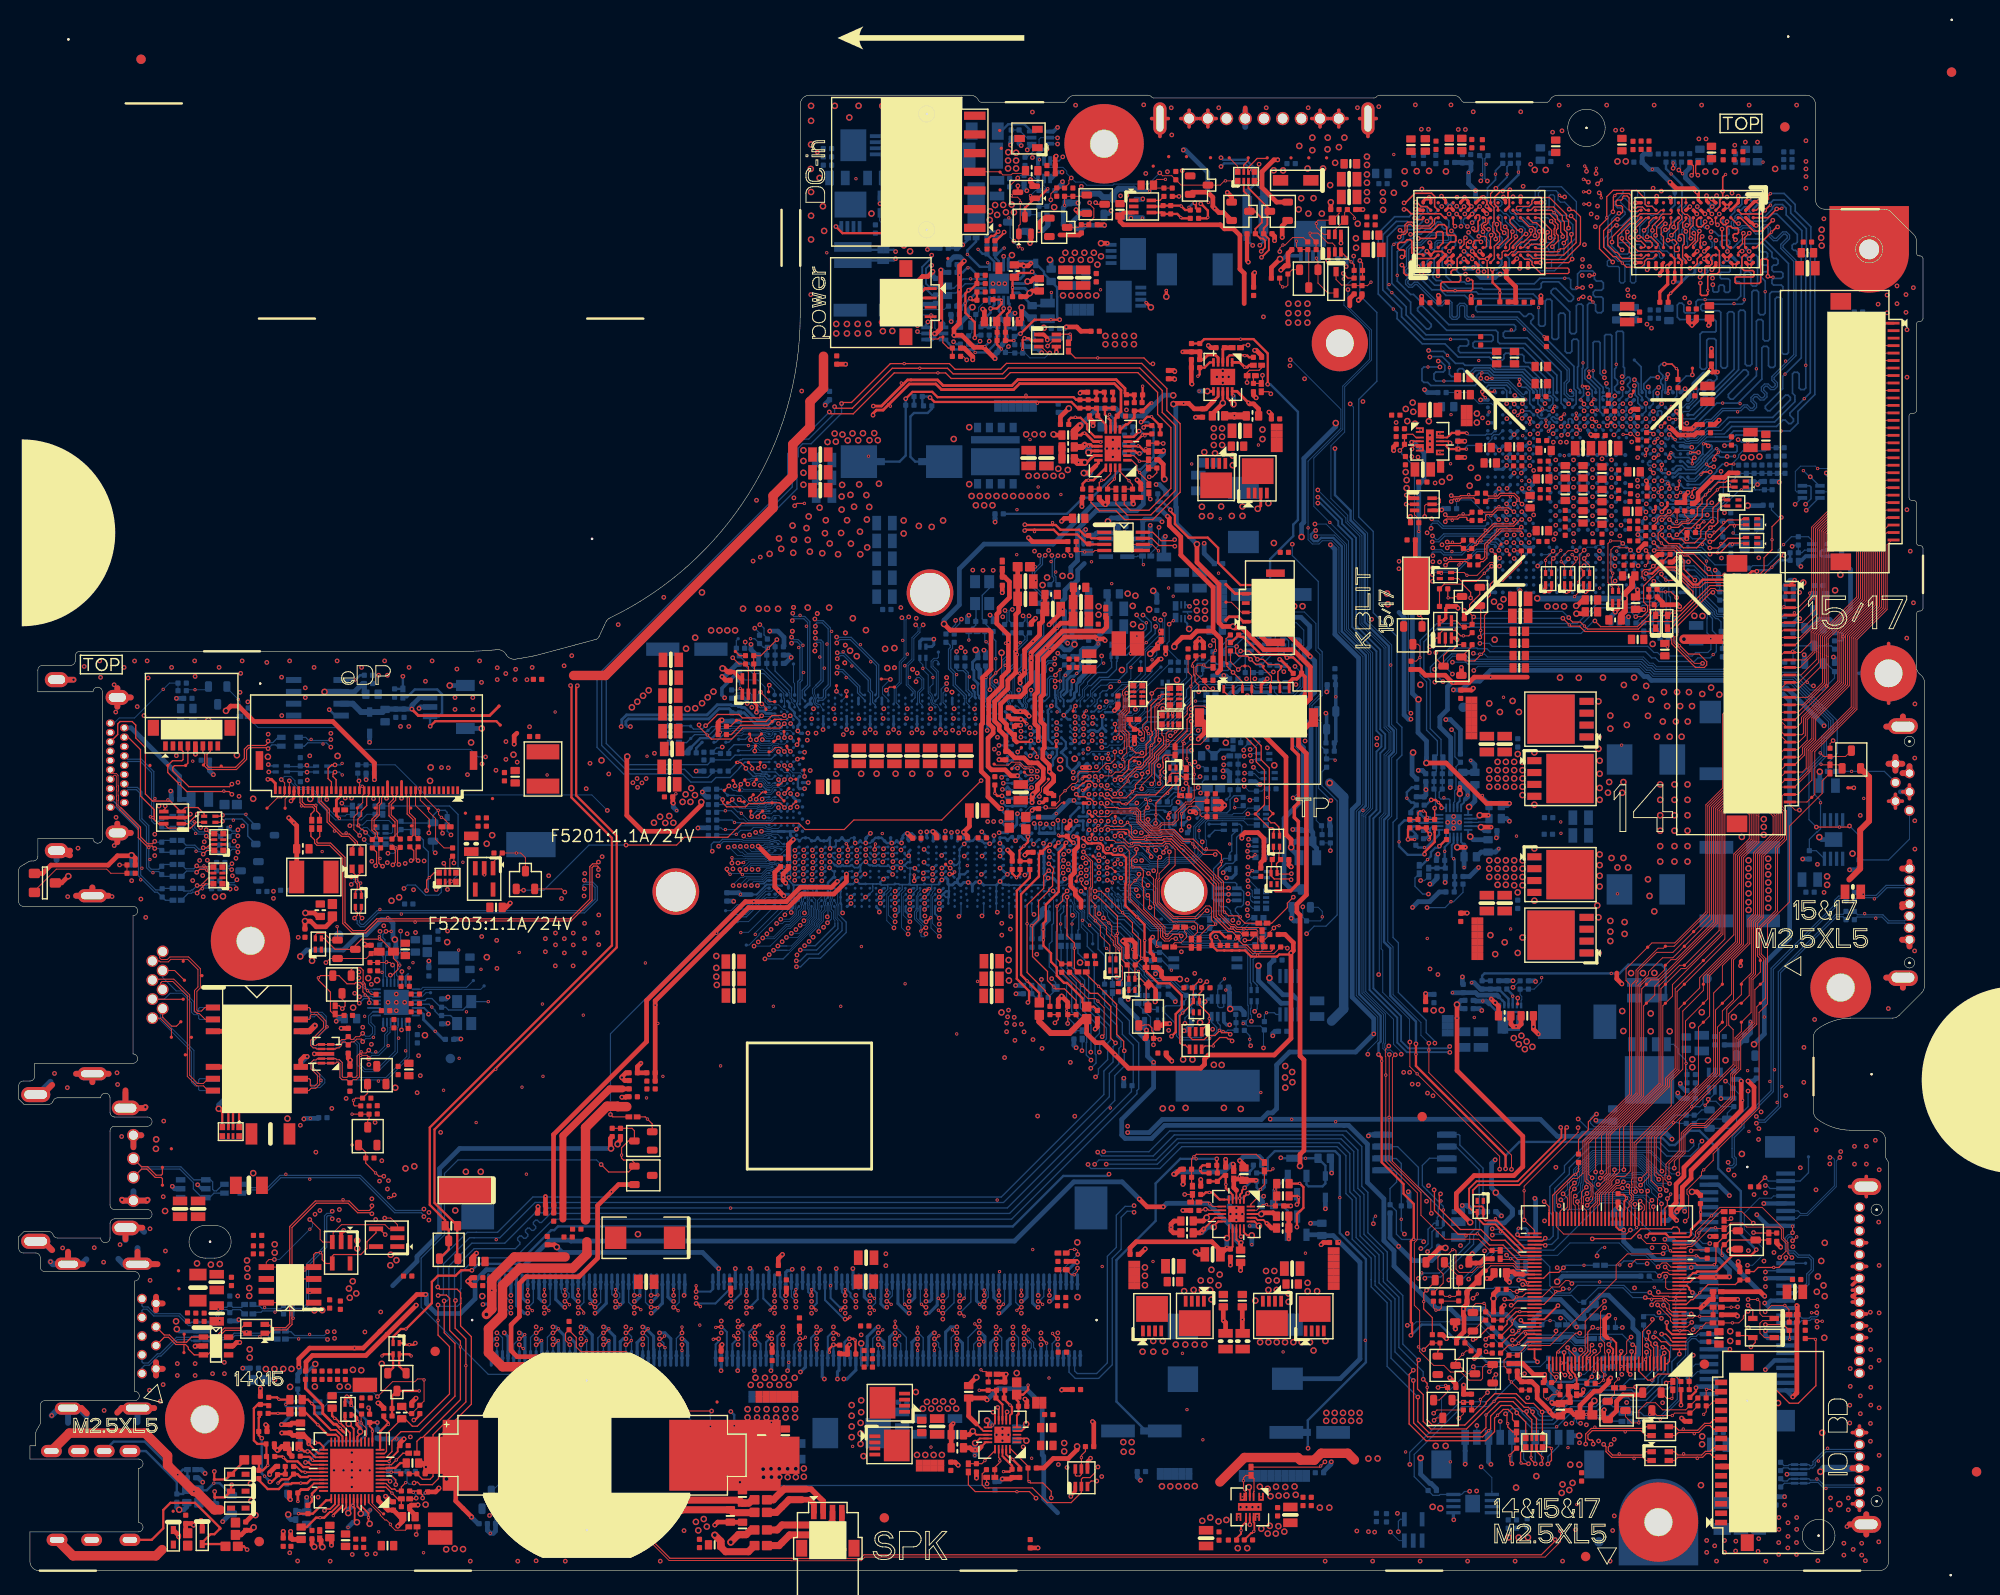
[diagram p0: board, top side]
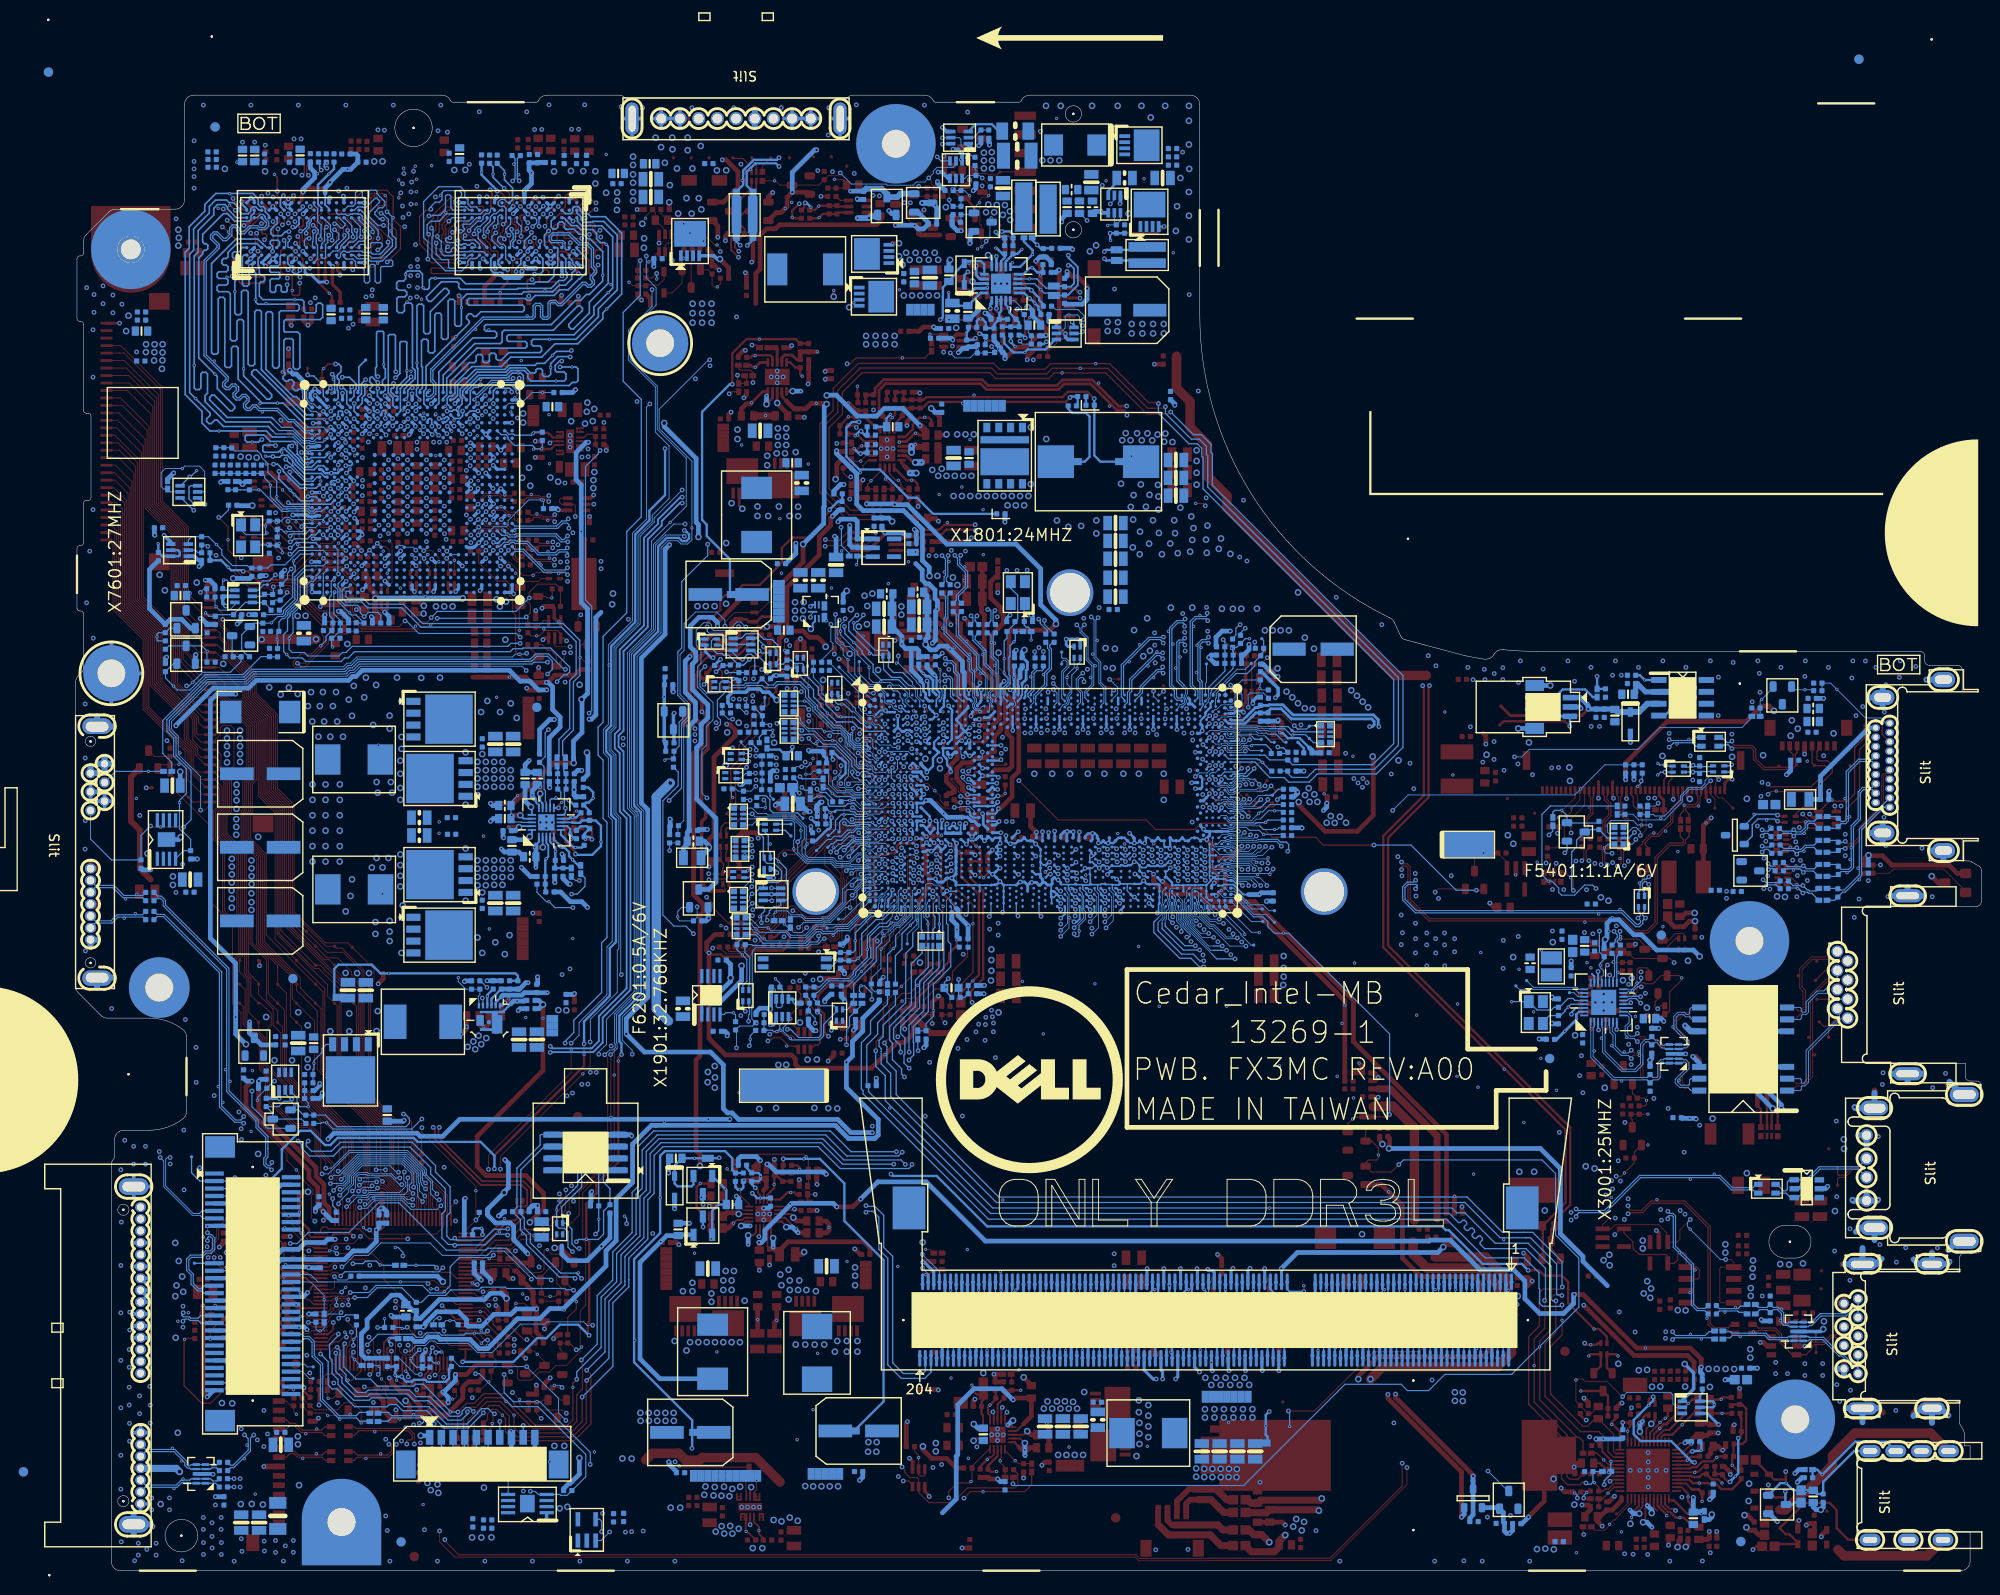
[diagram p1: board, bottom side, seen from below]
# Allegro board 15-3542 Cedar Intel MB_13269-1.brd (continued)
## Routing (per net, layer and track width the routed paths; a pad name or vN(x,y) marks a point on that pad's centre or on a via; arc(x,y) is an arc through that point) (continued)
PWR_CHG_PHASE: length 22.7
  TOP w0.356: v2(122.76,137) 122.76,137 v3(122.76,136.34)
  TOP w0.508: PC4411.2 107.77,136.34 v3(108.15,136.72) 108.38,136.95 PC4413.1
  L4 w1.016: v3(108.15,136.72) 109.17,136.72 109.91,137.46 115.75,137.46 119.29,133.93 121.63,133.93 122.76,135.05 v3(122.76,136.34)
  BOTTOM w0.305: v3(108.15,136.72) 107.64,137.24 PU4404.19
PWR_CHG_REGN: length 25.6
  TOP w0.254: v1(111.35,133.87) v2(110.41,133.87) 108.66,133.87 v1(107.16,132.38)
  L3 w0.254: v1(100,131.51) 100.43,131.51 101.57,132.65 106.89,132.65 v1(107.16,132.38)
  BOTTOM w0.254: PR4425.1 100.28,131.26 100.03,131.51 v1(100,131.51) ; PU4404.16 106.65,139.79 107.01,140.15 108.53,140.15 PD4401.A 109.67,139.01 109.67,138.79 110.44,138.02 PC4407.1 111.07,137.33 111.07,136.32 111.08,136.3 111.08,134.14 v1(111.35,133.87) ; PR4428.1 106.5,131.25 PR4430.1 106.67,132.08 106.96,132.38 v1(107.16,132.38)
PWR_CHG_SRN: length 2.9
  BOTTOM w0.254: PU4404.12 104.35,140.09 103.58,140.86 PR4420.1 103.11,140.92 v2(102.62,141.41)
PWR_CHG_SRP: length 2.8
  BOTTOM w0.254: v2(105.42,141.54) 105.33,141.54 104.71,140.92 PR4421.1 104.47,140.51 104.85,140.13 PU4404.13
PWR_CHG_VCC: length 5.4
  BOTTOM w0.254: PU4404.20 107.04,136.74 PC4010.1 109.32,135.37 109.6,135.65 PR4408.2 110.46,136.06 v2(110.46,136.79)
PWR_DCBATOUT_1D05V:
  vias: v2(132.61,120.46) v3(133.04,122.12) v3(133.04,121.1)
PWR_DCBATOUT_3D3V:
  vias: v2(121.33,33.09) v3(120.47,32.45) v3(120.47,31.56) v3(120.47,30.55)
PWR_DCBATOUT_5V:
  vias: v2(137.64,33.98) v3(137.87,30.8) v3(137.87,29.91) v3(138.88,29.91)
PWR_DCBATOUT_VCCCORE:
  vias: v2(108.18,121.05) v3(107.77,121.61) v3(108.66,121.61) v3(109.55,121.61)
PWR_DCBATOUT_VGA_CORE1:
  vias: v2(159.59,68.67) v3(157.43,68.01) v3(157.93,65.98) v3(158.95,67.25) v3(160.35,66.11) v3(160.86,67.76)
PWR_DCBATOUT_VGA_CORE2:
  vias: v2(158.82,93.46) v3(156.66,91.25) v3(157.3,92.81) v3(158.44,91.89) v3(159.8,93.07) v3(160.47,91.89)
PWR_DCBATOUT_VRAM_PWR:
  vias: v2(155.7,59.2)
PWR_DEBUG: length 13.7
  BOTTOM w0.089: CPU1.H59 82.51,89.92 81.47,89.92 81.39,89.99 80.69,89.99 80.52,89.82 80.01,89.82 79.95,89.88 79.53,89.88 79.37,90.03 77.52,90.03 77.41,89.93 76.34,89.93 76.26,89.85 75.19,89.85 75.06,89.72 v2(75.05,89.72)
  BOTTOM w0.254: v2(75.05,89.72) 74.97,89.64 74.72,89.64 74.18,89.1 72.91,89.1 71.87,88.06
  BOTTOM w0.508: 71.87,88.06 71.58,87.77 R9604.1 70.67,87.52 R705.2
PWR_LEVEL: length 14.1
  TOP w0.127: v1(175.72,106.66) 175.72,106.49 v2(176.2,106.01) 176.22,105.99 177.89,105.99 179.08,104.79 179.08,104.02 178.17,103.11 178.17,103.09 177.8,102.72 177,102.72 176.52,102.24 D7602.A D7601.A 175.1,103.21 R7605.2
  BOTTOM w0.127: v1(175.72,106.66) 175.79,106.73 175.79,109.23 GPU1.D7
PWR_VCC_ALERT#: length 3.5
  TOP w0.14: PU4601.19 117.29,116.91 v2(117.21,116.83) 116.47,116.09 PR4601.2 PR4618.1
PWR_VCC_BOOT: length 2.8
  TOP w0.305: v2(114.03,120.51) 114.67,120.51 114.84,120.33 PU4601.13
  TOP w0.635: v2(114.03,120.51) 113.77,120.26 PR4701.1
PWR_VCC_BOOT_RC: length 1.3
  TOP w0.762: PC4706.1 PR4701.2
PWR_VCC_COMP: length 4.1
  TOP w0.254: v1(119.84,121.95) 119.84,121.92 119.25,121.33 PU4601.6
  BOTTOM w0.254: v2(120.47,121.45) 119.97,121.95 v1(119.84,121.95) 119.84,121.93 119.43,121.53 PC4610.1 PR4613.1
PWR_VCC_COMP_RC: length 2.7
  BOTTOM w0.254: v2(116.69,123.74) 117.11,123.32 PC4611.1 PR4613.2
PWR_VCC_EN: length 3.8
  TOP w0.127: PR4621.1 120.89,116.46 119.91,117.44 v2(119.91,117.52) 119.61,117.81 119.61,118.28 119.06,118.83 PU4601.1
PWR_VCC_FB: length 5
  TOP w0.254: 118.86,122.92 118.62,122.68 118.43,122.68 117.88,122.13 PU4601.7
  TOP w0.305: v2(121.21,124.96) 121.05,124.96 120.21,124.12 PR4606.1 PR4603.1 119.33,123.39 118.86,122.92
PWR_VCC_FB_RC: length 1.8
  TOP w0.254: v2(120.22,126.76) PC4601.1 120.16,125.77 PR4606.2
PWR_VCC_IMON: length 3.9
  TOP w0.254: PU4601.3 119.4,119.83 119.61,119.62 119.82,119.62 v1(119.89,119.55)
  BOTTOM w0.254: PC4609.2 PR4610.2 119.82,119.62 v1(119.89,119.55) 119.95,119.62 120.11,119.62 v2(120.57,120.08)
PWR_VCC_ISUMN: length 3.4
  TOP w0.254: PR4706.2 PR4705.2 116.19,123.7 v2(116.5,123.4) 116.79,123.1 PU4601.9
PWR_VCC_ISUMP: length 23
  TOP w0.254: v2(108.96,124.93) 108.96,125.07 ; 108.96,125.07 112.6,125.07 113.27,124.41 PR4708.1 PC4707.1 PC4708.1 115.43,124.28 PR4707.1 115.43,123.52 116.29,122.66 PU4601.10 ; 108.96,125.07 97.95,125.07 v1(97.48,125.54)
  BOTTOM w0.254: v1(97.48,125.54) 97.37,125.65 PR4703.1 96.66,124.78 PR4702.2
PWR_VCC_LG: length 15.8
  TOP w0.305: PU4601.16 115.49,118.52 115.22,118.25
  TOP w0.508: v3(113.93,117.46) 114.44,117.46 115.22,118.25
  L4 w1.016: v3(113.93,117.46) 112.62,116.15 101.8,116.15 v3(101.67,116.27)
  BOTTOM w0.711: v3(113.93,117.46) v2(114.59,117.46)
PWR_VCC_NTC: length 3
  TOP w0.254: PR4615.2 120.32,121.65 v2(120.19,121.52) 119.5,120.83 PU4601.5
PWR_VCC_NTC_R: length 26.9
  TOP w0.254: v1(120.06,122.92) 120.16,122.92 120.72,123.49 v2(121.18,123.49) 121.18,123.46 PR4617.1 PR4615.1
  BOTTOM w0.254: PR4622.1 112.13,113.1 113.86,114.83 114.8,114.83 117.81,117.84 120.02,117.84 121.4,119.22 121.4,122.33 120.81,122.92 v1(120.06,122.92)
PWR_VCC_PHASE: length 18.7
  TOP w0.305: PU4601.15 115.01,119.33 114.95,119.26 114.92,119.26 114.26,118.6 v3(114.03,118.6)
  TOP w0.762: v3(114.03,118.6) 113.3,118.6 PC4706.2
  L4 w1.016: v3(100.02,121.11) 104.04,121.11 105.82,119.32 112.76,119.32 113.48,118.6 v3(114.03,118.6)
  BOTTOM w0.711: v3(114.03,118.6) v2(113.37,118.6)
PWR_VCC_POK: length 2.6
  TOP w0.127: PR4628.1 120.7,118.73 v2(119.87,118.73) 119.27,119.33 PU4601.2
PWR_VCC_PRGM1: length 3.8
  TOP w0.254: PR4614.2 113.81,116.32 114.19,116.7 v2(114.41,116.7) 114.96,116.7 PU4601.17
PWR_VCC_PRGM2: length 4.9
  TOP w0.254: PR4607.2 112.32,123.15 112.55,123.38 112.97,123.38 v2(113.03,123.43) 113.07,123.39 113.58,123.39 114.29,122.68 114.29,122.16 115.11,121.33 PU4601.11
PWR_VCC_SCLK: length 3.7
  TOP w0.14: PR4616.1 PR4620.1 119.14,116.23 118.77,116.6 v2(118.77,116.64) 117.79,117.62 PU4601.20
PWR_VCC_SDA: length 3.8
  TOP w0.14: PU4601.18 116.79,117.38 116.1,116.69 v2(115.83,116.69) 115.58,116.44 PR4630.1 PR4619.1
PWR_VCC_UG: length 15.7
  TOP w0.305: PU4601.14 114.71,119.83 114.56,119.68 v3(114.43,119.68)
  L4 w1.016: v3(101.67,122.37) 101.79,122.25 104.51,122.25 106.3,120.46 113.64,120.46 v3(114.43,119.68)
  BOTTOM w0.711: v3(114.43,119.68) v2(114.43,120.34)
PWR_VCC_VRHOT#: length 2.5
  TOP w0.254: PR4624.1 120.44,119.78 119.88,120.34 119.78,120.34 v2(119.75,120.38) 119.71,120.33 PU4601.4
PWR_VGA_CORE_BOOT1: length 3.4
  BOTTOM w0.203: 154.61,77.67 154.29,77.98 PU8201.1
  BOTTOM w0.508: v2(154.61,75.25) PR8210.1 154.61,77.67
PWR_VGA_CORE_BOOT1_1: length 2.7
  BOTTOM w0.508: v2(158.32,77.25) 157.97,76.9 PC8211.1 156.44,76.9 PR8210.2
PWR_VGA_CORE_BOOT2: length 3
  BOTTOM w0.203: 154.75,82.57 154.6,82.42 154.6,82.21 154.29,81.9 PU8201.15
  BOTTOM w0.508: 154.75,82.57 155,82.82 v2(155,83) 155,83.45 154.47,83.98 PR8211.1
PWR_VGA_CORE_BOOT2_1: length 2.8
  BOTTOM w0.508: v2(155.32,86.71) 155.76,86.26 PC8216.1 155.76,85.43 PR8211.2
PWR_VGA_CORE_EN: length 6.1
  BOTTOM w0.203: PU8201.3 153.49,77.86 153.29,77.65 153.29,76.4 v2(153.49,76.19)
  BOTTOM w0.254: v2(153.49,76.19) 153.6,76.08 PC8225.2 PR8260.2 153.6,72.68 PR8256.2
PWR_VGA_CORE_LGATE1: length 15.7
  TOP w0.508: v3(156.41,79.57) v2(157.5,79.57)
  L4 w1.016: v3(156.41,79.57) 156.66,79.32 160.09,79.32 v3(162.13,77.28) v3(162.13,71.7)
  BOTTOM w0.203: PU8201.19 156.3,79.68 v3(156.41,79.57)
  BOTTOM w0.508: v3(156.41,79.57) 156.79,79.19 PR8224.1
PWR_VGA_CORE_LGATE2: length 14.2
  TOP w0.508: v3(156.28,80.84) v2(157.2,80.84)
  L4 w1.016: v3(162.13,87.57) v3(162.13,81.98) 161.24,81.09 156.54,81.09 v3(156.28,80.84)
  BOTTOM w0.203: PU8201.17 155.92,80.48 v3(156.28,80.84)
PWR_VGA_CORE_PHASE1: length 22.8
  L4 w1.016: v3(155.27,78.55) 155.14,78.43 155.14,74.46 159.3,70.3 165.92,70.3 166.81,71.19 v3(168.86,71.19)
  BOTTOM w0.203: v3(155.27,78.55) 155.04,78.78 PU8201.20
  BOTTOM w0.508: PC8211.2 155.6,78.22 v3(155.27,78.55)
  vias: v2(171.02,72.43) v3(169.11,76.65) v3(169.11,75.51) v3(169.11,74.36) v3(169.11,73.22) v3(170.25,69.54) v3(170.25,68.39) v3(170.25,67.38) v3(170.38,76.27) v3(171.02,75.25) v3(171.65,76.27) v3(171.78,69.41) v3(171.78,68.14) v3(172.16,75.25)
PWR_VGA_CORE_PHASE2: length 23.1
  L4 w1.016: v3(155.14,81.73) 155.83,82.42 155.83,85.83 159.39,89.39 165.24,89.39 166.68,87.95 v3(168.98,87.95)
  BOTTOM w0.203: v3(155.14,81.73) 155.04,81.63 PU8201.16
  BOTTOM w0.508: PC8216.2 155.76,83.79 155.77,83.79 155.77,82.35 v3(155.14,81.73)
  vias: v2(171.46,88.35) v3(169.11,86.68) v3(169.11,85.29) v3(169.11,83.76) v3(169.11,82.49) v3(170,83.25) v3(170.13,84.4) v3(170.25,91.51) v3(170.25,90.11) v3(171.52,83.25) v3(171.65,84.4) v3(172.02,90.5)
PWR_VGA_CORE_PSI: length 5.4
  BOTTOM w0.203: 152.54,77.44 153.09,77.99 PU8201.4
  BOTTOM w0.254: 152.54,77.44 v2(152.54,76.98) PC8226.2 152.54,75.25 PR8259.1 PR8258.2 PR8257.2
PWR_VGA_CORE_REFADJ: length 3.7
  BOTTOM w0.203: PU8201.6 151.94,78.77
  BOTTOM w0.254: PR8222.1 149.69,77.39 v2(150.37,77.39) 150.55,77.39 151.94,78.77
PWR_VGA_CORE_REFIN: length 4.9
  TOP w0.254: PC8204.1 PR8209.1 150.57,79.2 v1(150.95,78.81) 150.95,78.33 v2(150.85,78.22)
  BOTTOM w0.203: 150.95,79.39 151.24,79.68 PU8201.7
  BOTTOM w0.254: 150.95,79.39 v1(150.95,78.81) 150.47,78.33 PR8208.1
PWR_VGA_CORE_RGND: length 11.3
  TOP w0.14: v1(151.46,81.6) PC8201.1 PR8209.2 150.57,81.12 150.39,81.3 v2(150.26,81.3) 149.86,81.3 149.68,81.12 PC8204.2 PC8223.2
  BOTTOM w0.14: PR8220.1 151.63,85.93 151.63,85.52 PR8213.1 PC8217.1 151.39,83.66 PC8219.2 151.55,83.48 151.55,81.7 v1(151.46,81.6) 151.46,81.11 151.69,80.88 PU8201.10
PWR_VGA_CORE_SS: length 3.1
  TOP w0.254: v1(152.19,81.63) 152.16,81.66 152.16,81.89 151.86,82.19 v2(151.86,82.21) 151.85,82.21 151.58,82.48 v1(151.09,82.48)
  BOTTOM w0.203: PU8201.11 v1(152.19,81.63)
  BOTTOM w0.254: PC8205.1 150.53,81.93 v1(151.09,82.48)
PWR_VGA_CORE_TON: length 2.4
  BOTTOM w0.203: PU8201.9 151.07,80.48
  BOTTOM w0.254: 151.07,80.48 150.94,80.61 v2(150.68,80.61) 150.29,80.61 PR8201.2
PWR_VGA_CORE_TON_1: length 4.3
  BOTTOM w0.254: PR8201.1 148.9,81.34 PC8202.2 149.23,82.2 148.95,82.2 v2(148.49,82.67) 148.49,83.3 149.01,83.82 PR8202.2
PWR_VGA_CORE_UGATE1: length 26.8
  TOP w0.508: v3(153.87,77.41) v2(154.76,77.41)
  L4 w1.016: v3(168.98,66.11) v3(168.98,69.92) 167.33,69.92 166.44,69.03 158.77,69.03 153.87,73.93 v3(153.87,77.41)
  BOTTOM w0.203: v3(153.87,77.41) 153.89,77.43 PU8201.2
PWR_VGA_CORE_UGATE2: length 26.3
  TOP w0.508: v2(154.15,83.84) v3(154.15,83.15)
  L4 w1.016: v3(168.98,93.03) v3(168.98,89.22) 167.21,89.22 165.77,90.66 158.86,90.66 154.56,86.35 154.56,83.56 154.15,83.15 v3(154.15,83.15)
  BOTTOM w0.203: PU8201.14 153.89,82.12 154.14,82.37 154.14,82.84 154.15,82.85 v3(154.15,83.15)
PWR_VGA_CORE_VID: length 5.6
  TOP w0.254: PC8203.2 152.66,78.24 v1(151.97,77.54)
  BOTTOM w0.203: v1(151.97,77.54) 152.69,78.26 PU8201.5
  BOTTOM w0.254: PR8207.2 150.08,75.48 v2(150.7,76.09) 151.06,76.46 151.06,76.9 151.52,77.35 151.78,77.35 v1(151.97,77.54)
PWR_VGA_CORE_VREF: length 13.2
  TOP w0.254: PC8201.2 151.46,79.03 151.46,79.02 151.46,77.98 150.38,76.9 v1(150.38,76.68)
  BOTTOM w0.203: PU8201.8 150.74,80.08
  BOTTOM w0.254: v1(150.38,76.68) 150.3,76.61 148.58,76.61 147.65,77.53 v2(147.65,78) 147.65,79.72 148.22,80.28 PR8206.1 149.64,80.28 149.89,80.04 150.69,80.04 150.74,80.08
PWR_VGA_CORE_VSNS: length 5.8
  BOTTOM w0.14: 152.45,82.59 152.11,82.59 151.95,82.75 151.95,83.32 PC8219.1 152.28,83.66 PC8222.1 PR8212.2 152.25,85.32 152.25,86.01 PR8221.1 ; 152.45,82.59 152.98,82.59 153.09,82.48 PU8201.12 ; 152.45,82.59 v2(152.45,82.72)
PWR_VGA_SNUB1:
  vias: v2(164.97,78.91)
PWR_VGA_SNUB2:
  vias: v2(164.95,80.13)
PWR_VRAM_PWR_EN: length 4.9
  BOTTOM w0.102: PU5102.1 160.71,61.03 160.78,61.1 160.78,61.46 160.6,61.64 PR5114.1 PR5104.1 162.1,62.23 162.91,63.04 v2(162.91,63.46)
PWR_VRAM_PWR_ILIM: length 2
  BOTTOM w0.254: PU5102.3 v2(159.81,61.48) 159.81,61.61 PR5111.1
Q402_1: length 4.6
  TOP w0.102: v2(34.06,68.93) 34.11,68.88 34.11,67.48 Q3003.B 33.42,67.48 32.7,68.2 31.91,68.2 31.73,68.02 RN3001.4
Q6203_S: length 8
  BOTTOM w0.381: C6204.2 R6209.2 140.89,88.75 Q6203.S v2(140.89,93.51) 140.89,94.78 R6212.2 140.85,95.57 R6213.2
Q6204_G: length 29.4
  TOP w0.254: v1(136.28,100.99) 136.28,101.44 134.88,102.84 134.88,103.9 134.39,104.39 133.57,104.39 132.48,105.48 130.68,105.48 128.3,107.86 128.3,109.44 127.19,110.55 125.14,110.55 123.67,112.03 123.67,112.91 123.1,113.49 123.15,113.53 v1(123.19,113.53)
  BOTTOM w0.127: Q6204.5 Q6204.2 134.18,99.13 134.4,99.35 134.4,99.97 134.72,100.28 136.03,100.28 136.28,100.53 136.28,100.99 v1(136.28,100.99)
  BOTTOM w0.254: R6216.2 121.84,114.44 R6217.2 122.31,114.42 v1(123.19,113.53)
Q7601_G: length 11.8
  BOTTOM w0.102: Q7601.5 193.71,115.45 R7624.1 194.42,115.75 194.68,116.02 194.68,117.52 194.26,117.95 v2(192.43,117.95) 192.17,118.2 190.6,118.2 190.04,117.64 190.04,115.6 190.19,115.45 Q7601.2
REFIN_VREF: length 5.8
  TOP w0.254: PC8223.1 148.61,79.33 v1(148.61,78.26) 148.62,78.25 v2(149.32,78.25)
  BOTTOM w0.254: PR8208.2 149.83,79.66 149.17,79.66 148.91,79.39 PR8206.2 149.45,78.84 PR8222.2 148.87,78.52 v1(148.61,78.26)
REGOUT:
  vias: v2(49.45,64.36)
RING2: length 36.9
  TOP w0.203: HDA27.17 36.23,14.35 36.52,14.64 v3(36.52,14.88)
  TOP w0.305: v3(36.52,14.88) 36.52,15.26 36.17,15.61 36.17,16.37 35.88,16.66 RN2901.4
  TOP w0.508: R2906.2 17.87,4.22 EC2905.1 18.53,5.05 v1(18.71,4.87)
  L3 w1.016: v3(36.52,14.88) 35.53,13.89 33.31,13.89 32.51,13.09 32.51,11.47 31.41,10.38 29.61,10.38 28.34,11.65 26.78,11.65 25.86,10.73 25.86,7.81 26.41,7.26 26.41,3.92 25.77,3.27 20.31,3.27 v1(18.71,4.87)
  BOTTOM w0.508: v2(36.24,15.97) 36.52,15.69 v3(36.52,14.88)
RING2_R: length 12.2
  TOP w1.016: 15.34,2.25 14.68,1.59 5.81,1.59 HPMIC1.3
ROM_CS#: length 3.2
  TOP w0.127: v1(176.55,113.35) 176.08,112.89 175.59,112.89 175.33,112.62 175.33,112.31 174.94,111.93 R7626.1
  BOTTOM w0.102: GPU1.D12 176.16,113.75 v1(176.55,113.35)
ROM_SCLK: length 11.9
  BOTTOM w0.127: R7608.2 187.55,115.67 R7614.1 186.24,115.67 186.23,115.66 185.76,115.66 185.75,115.67 185.27,115.67 R7616.1 v2(184.27,115.66) 184.09,115.66 181.78,113.36 181.09,113.36 181.05,113.4 179.05,113.4 178.82,113.17 178.31,113.17 178.1,113.38 177.5,113.38 177.12,113.75 GPU1.C12
ROM_SI: length 14
  BOTTOM w0.127: GPU1.B12 177.88,113.62 178.15,113.62 178.16,113.6 178.19,113.6 178.4,113.39 178.72,113.39 178.97,113.64 181.27,113.64 181.29,113.61 181.68,113.61 183.01,114.95 v2(183.01,116.15) 183.01,116.3 183.62,116.91 183.62,117.18 183.86,117.43 R7641.1 R7642.1 184.8,117.43 R7640.1 185.63,117.43 R7618.1 187.3,117.43 R7619.2 187.3,117.43 R7639.2 188.12,117.43 R7638.2
ROM_SO: length 14.8
  BOTTOM w0.127: R7611.2 R7651.1 187.17,120.17 R7620.1 186.83,119.83 184.41,119.83 183.97,119.39 183.97,119.34 183.97,119.33 183.97,119.15 183.28,118.46 183.28,117.54 182.34,116.6 v2(182.34,114.93) 182.34,114.63 181.57,113.87 178.87,113.87 178.76,113.75 GPU1.A12
RSET: length 4.7
  BOTTOM w0.203: LOM30.31 43.04,59.82 43.31,59.55
  BOTTOM w0.305: 43.31,59.55 43.31,58.97 v2(44.55,57.73) 45.42,56.86 R3032.2
RSMRST#_KBC: length 74.4
  TOP w0.127: KBC24.15 176.53,29.3 176.46,29.37 174.87,29.37 v1(174.47,29.77)
  L4 w0.127: v1(159.15,33.76) 158.89,34.03 158.89,36.27 156.92,38.24 154.23,38.24 153.46,39 149.83,39 148.98,39.86 148.27,39.86 147.67,40.45 146.95,40.45 144.92,42.49 144.43,42.49 141.74,45.17 140.33,45.17 135.18,50.33 134.33,50.33 134.05,50.61 134.05,53.59 133.22,54.42 133.22,54.88 132.34,55.75 132.34,56.74 131.14,57.94 v1(127.71,57.94)
  BOTTOM w0.127: v1(174.47,29.77) 172.47,29.77 171.71,30.53 166.73,30.53 165.92,29.72 164.56,29.72 v2(164.4,29.88) 163.78,30.5 163.78,32.52 162.8,33.5 159.68,33.5 159.67,33.51 159.4,33.51 v1(159.15,33.76) ; R1702.2 124.09,59.47 124.09,57.34 124.38,57.05 126.5,57.05 127.12,57.68 127.12,57.68 127.38,57.94 v1(127.71,57.94)
RSVDA51: length 1.3
  TOP w0.102: TP606.1 v1(87.48,94.11)
  BOTTOM w0.102: v1(87.48,94.11) 87.87,93.71 CPU1.A51
RSVDAU63: length 5.7
  BOTTOM w0.102: CPU1.AU63 79.97,73.04 78.19,71.26 76.83,71.26 76.2,70.63 TP602.1
RSVDAV63: length 5.9
  BOTTOM w0.102: TP601.1 76.44,70.21 77.79,70.21 79.96,72.38 CPU1.AV63
RSVDB51: length 1.8
  TOP w0.102: TP607.1 88.54,93.57 v1(88.54,94.11)
  BOTTOM w0.102: v1(88.54,94.11) 88.54,93.6 CPU1.B51
RSVDC62: length 5.6
  TOP w0.102: v1(79.35,94.02) 80.37,93 TP604.1
  BOTTOM w0.102: v1(79.35,94.02) 79.08,93.75 79.08,92.58 79.32,92.34 79.76,92.34 80.03,92.07 80.53,92.07 80.79,92.33 CPU1.C62
RSVDC63: length 1.7
  TOP w0.102: v1(79.49,92.75) 79.93,92.3 TP603.1
  BOTTOM w0.102: v1(79.49,92.75) 79.58,92.66 79.75,92.66 79.93,92.48 79.94,92.48 80.02,92.4 CPU1.C63
RSVDL60: length 2.6
  TOP w0.102: v1(81.9,87.66) 81.46,88.1 80.95,88.1 80.46,87.62 TP608.1
  BOTTOM w0.102: CPU1.L60 82.22,87.35 v1(81.9,87.66)
RSVDN59: length 1.2
  TOP w0.102: TP704.1 83.43,86.94 83.34,86.85 v1(83.3,86.85)
  BOTTOM w0.102: CPU1.N59 83.02,86.57 v1(83.3,86.85)
RSVDN61: length 1.2
  TOP w0.102: TP705.1 81.91,86.01 v1(81.91,86.15)
  BOTTOM w0.102: CPU1.N61 81.57,86.5 v1(81.91,86.15)
RSVDP60: length 2.9
  TOP w0.102: TP702.1 84.02,85.03 v1(84.06,84.99)
  BOTTOM w0.102: v1(84.06,84.99) 84,84.99 83.61,85.38 82.8,85.38 82.44,85.75 CPU1.P60
RSVDP61: length 2.3
  TOP w0.102: v1(82.57,84.66) 82.61,84.7 TP703.1
  BOTTOM w0.102: CPU1.P61 81.9,85.41 82.35,85.41 82.53,85.23 82.53,84.7 v1(82.57,84.66)
RT8812_PVCC: length 5.2
  BOTTOM w0.127: PU8201.18 156.15,80.08 156.18,80.12 156.91,80.12 PC8207.1 PR8223.2 157.27,82.26 v2(156.57,82.96)
RTC_AUX_S5: length 216.2
  TOP w0.305: 113.29,77.44 113.38,77.53 113.38,78.43 113.25,78.55 v1(112.84,78.55)
  TOP w0.508: v1(62.66,18.89) 62.66,18.89 62.66,18.53 54.35,10.23 v1(54.35,10.12) ; 113.29,77.44 112.93,77.08 112.93,74.68 112.53,74.28 112.53,73.27 113.02,72.78 113.02,72.32 113.63,71.71 113.63,70.97
  L3 w0.508: v1(62.66,18.89) 62.66,18.89 62.66,18.69 63.93,17.42 68.86,17.42 69.74,18.3 74,18.3 79.06,13.24 83.9,13.24 88.36,8.78 99.38,8.78 101.94,11.34 101.94,11.34 102.34,11.74 108.34,11.74 109.75,13.16 109.75,16.11 113.62,19.98 113.62,28.4 114.02,28.81 114.02,36.15 112.85,37.33 112.85,48.52 v1(112.96,48.63)
  L4 w0.508: v1(121.4,54.41) 121.41,54.4 121.41,53.37 118.79,50.75 115.07,50.75 v1(112.96,48.63)
  BOTTOM w0.254: CPU1.AG10 112.87,78.55 v1(112.84,78.55)
  BOTTOM w0.508: R1720.2 123.09,61.68 123.71,61.06 v1(123.71,60.89) ; v1(54.35,10.12) 54.38,10.09 54.38,9.62 54.36,9.61 D2501.3 54.36,5.98 54.71,5.63 C2503.1 ; R2428.2 167.88,24.83 167.58,24.53 166.61,24.53 166.13,25.01 165.13,25.01 164.88,24.76 161.68,24.76 160.68,23.77 159.77,23.77 156.56,26.97 154.19,26.97 153.12,28.05 151.66,28.05 147.11,32.6 147.11,34.23 146.03,35.31 146.03,39.79 144.27,41.55 144.27,45.64 142.26,47.66 141.76,47.66 141.76,47.65 122.59,47.65 121.18,46.25 118.36,46.25 117.99,46.62 117.99,48.28 121.4,51.7 v1(121.4,54.41) 120.75,55.06 120.75,56.64 119.64,57.75 119.64,59.11 117.88,60.87 R1903.1
  vias: v2(113.79,69.6)
RTC_DET#: length 204.4
  TOP w0.102: v1(127.99,76.65) 126.72,76.65 v2(125.6,77.77) 125.32,78.05 124.52,78.05 123.52,79.05 122.22,79.05 122.1,78.93 121.06,78.93 119.8,80.19 119.8,81.13 119.52,81.41 118.98,81.41 118.86,81.3 116.55,81.3 v1(116.44,81.19)
  L3 w0.102: v1(131.49,72.43) 131.89,72.03 131.89,69.36 134.22,67.03 134.22,66.91 135.7,65.43 135.7,60.23 135.7,60.23 135.7,59.53 135.33,59.15 135.33,59.04 132.7,56.41 132.7,51.05 136.32,47.43 136.32,43 136.75,42.57 138.84,42.57 141.85,39.57 141.85,38.21 144.55,35.5 144.55,33.22 145.32,32.46 145.32,29.45 145.32,23.4 148.1,20.62 148.1,7.98 145.04,4.92 v1(145.04,4.13)
  L4 w0.102: v1(131.49,72.43) 131.95,72.89 131.95,75.44 131.47,75.92 129.25,75.92 128.52,76.65 v1(127.99,76.65) ; v1(52.77,10.66) 52.86,10.75 55,10.75 55.32,10.43 71.23,10.43 78.02,3.64 105.84,3.64 106.2,4.01 109.53,4.01 110.65,2.88 128.98,2.88 129.8,3.7 129.9,3.7 129.93,3.74 132,3.74 132.82,2.92 143.84,2.92 v1(145.04,4.13)
  BOTTOM w0.102: v1(131.49,72.43) 131.74,72.18 131.74,71.8 131.93,71.62 131.93,71.62 132.01,71.54 RN2012.6 ; Q2505.D 50.64,8.53 v1(52.77,10.66) ; CPU1.AD5 116.26,81.01 v1(116.44,81.19)
RTC_PWR: length 6.3
  BOTTOM w0.508: R2502.1 50.14,4.31 v2(50.44,4.01) 50.77,4.01 51.01,4.24 R2504.1 51.13,5.18 51.13,6.23 Q2505.G 51.65,6.74 D2501.2
RTC_RST#: length 16.6
  TOP w0.127: v1(115.14,72.72) 115.78,72.72 v2(118.09,70.41) 118.09,70.38 119.14,69.33 119.14,68.35 120,67.49 120,65.48 120,65.47 120,65.39 C1901.1 119.4,64.79 RN1901.3 120,63.34 G1901.2 120.6,61.22 120.8,61.02 Q1901.D
  BOTTOM w0.089: v1(115.14,72.72) 115.13,72.72 115.05,72.72 CPU1.AU7
RTC_X1: length 11.3
  BOTTOM w0.089: CPU1.AW5 116.64,71.37 116.64,70.93 117.19,70.38
  BOTTOM w0.14: 117.19,70.38 117.52,70.04 118.72,70.04 119.31,69.45 119.31,69.4 120.44,68.26 v2(120.44,67.43) 120.44,66.41 120.69,66.16 R1915.1 C1903.2 122.29,66.16 122.97,65.48 X1901.1
RTC_X2: length 11.4
  BOTTOM w0.14: CPU1.AY5 116.34,71.06 116.34,70.84 117.49,69.68 118.24,69.68 119.75,68.17 119.75,65.92 v2(120.13,65.54) 120.4,65.27 R1915.2 121.61,65.27 121.69,65.35 C1904.2 122.28,65.35 123,64.62 X1901.4
RTCRST_ON: length 82.9
  TOP w0.127: v1(172.64,24.17) 172.78,24.17 172.96,23.99 172.96,23.28 172.89,23.2 KBC24.120 ; Q1901.G 120.33,58.35 120.4,58.41 120.88,58.41 121.21,58.09 121.21,57.78 121.4,57.59 R1902.1 121.94,56.96 v1(122.04,56.86)
  L4 w0.127: v1(159.79,25.66) 158.44,27 158.44,31.54 157.54,32.44 157.54,34.19 157,34.74 155.54,34.74 155.03,34.23 155.03,32.1 154.68,31.75 151.56,31.75 151.35,31.75 149.27,33.83 149.27,36.29 148.01,37.55 147.31,37.55 146.71,38.14 145.99,38.14 144.57,39.57 144.08,39.57 141.71,41.93 140.44,41.93 139.99,42.37 139.75,42.62 134.91,42.62 133.72,43.81 133.72,45.13 131.51,47.34 131.51,51.65 131.26,51.89 131.26,52.36 129.66,53.97 129.66,54.23 128.98,54.91 128.52,54.91 126.8,56.62 122.28,56.62 v1(122.04,56.86)
  BOTTOM w0.127: v1(159.79,25.66) 160.03,25.42 v2(161.18,25.42) 162.1,25.42 162.31,25.21 164.7,25.21 164.95,25.46 166.32,25.46 166.8,24.98 167.39,24.98 167.72,25.3 171.51,25.3 v1(172.64,24.17)
S5_ENABLE: length 35.8
  TOP w0.127: v1(173.99,29.23) 174.1,29.12 176.24,29.12 176.46,28.9 KBC24.14 ; Q2403.D 151.52,30.94 v1(150.59,30.01) 150.29,29.71 v2(150.29,28.8) 150.29,28.01 151.21,27.09 R3603.2
  BOTTOM w0.127: v1(173.99,29.23) 172.65,29.23 171.61,30.27 168.96,30.27 R2436.2 166.85,28.73 166.11,29.46 164.29,29.46 163.71,30.05 160.71,30.05 160.5,30.26 160.49,30.26 160.41,30.34 157.9,30.34 157.76,30.2 151.52,30.2 151.38,30.07 150.64,30.07 v1(150.59,30.01)
SA0_DIMA: length 5.5
  TOP w0.102: R1201.1 112.45,34.38 v2(112.93,34.38) 113.15,34.38 113.28,34.26 v1(113.28,33.85)
  BOTTOM w0.102: DM1.197 111.45,32.02 v1(113.28,33.85)
SA1_DIMA: length 3.6
  TOP w0.102: R1202.1 112.6,31.67 v2(112.9,31.67) 113.26,32.02 v1(113.26,32.38)
  BOTTOM w0.102: v1(113.26,32.38) 112.65,31.77 DM1.201
SATA3_PRX_HDDTX_N0: length 156
  L4 w0.114: v1(184.79,14.52) 185.14,14.87 185.14,16.59 185.9,17.34 185.9,33.47 186.52,34.09 186.52,38.19 183.78,40.93 182.34,40.93 179.53,43.75 163.37,43.75 161.78,45.34 148.36,45.34 140.51,53.19 140.51,55.62 138.56,57.57 138.56,74.33 137.7,75.2 137.7,87.03 138.8,88.13 138.8,90.61 138.26,91.15 138.26,92.32 137.7,92.88 137.7,97.27 136.47,98.49 131.98,98.49 131.09,97.6 129.19,97.6 128.34,96.75 126.6,96.75 124.31,94.45 120.51,94.45 120.19,94.13 120.19,93.59 118.93,92.32 118.93,91.23 117.51,89.81 117.2,89.81 116.43,89.04 116.07,89.04 v1(115.81,88.78)
  BOTTOM w0.127: CPU1.J5 116.1,88.49 v1(115.81,88.78) ; 185.87,12.08 186.91,11.03 187.25,11.03 C5616.1 ; 185.87,12.08 v2(185.78,11.99) ; 185.87,12.08 185.15,12.8 185.15,14.16 v1(184.79,14.52)
SATA3_PRX_HDDTX_P0: length 156
  L4 w0.114: v1(185.78,14.54) 185.37,14.95 185.37,16.49 186.13,17.25 186.13,33.38 186.75,33.99 186.75,38.29 183.88,41.16 182.44,41.16 179.62,43.97 163.47,43.97 161.87,45.57 148.46,45.57 140.74,53.29 140.74,55.71 138.79,57.66 138.79,74.43 137.92,75.29 137.92,86.93 139.03,88.04 139.03,90.7 138.49,91.24 138.49,92.42 137.93,92.98 137.93,97.36 136.57,98.72 131.89,98.72 131,97.83 129.09,97.83 128.24,96.98 126.51,96.98 124.21,94.68 120.42,94.68 119.96,94.23 119.96,93.68 118.7,92.42 118.7,91.32 117.42,90.04 117.11,90.04 116.34,89.27 116.01,89.27 v1(115.82,89.46)
  BOTTOM w0.127: v2(185.51,13.43) 185.39,13.43 ; 185.39,13.43 185.39,14.15 v1(185.78,14.54) ; 185.39,13.43 185.39,12.9 187.01,11.28 187.25,11.28 C5615.1 ; v1(115.82,89.46) 116.14,89.14 CPU1.H5
SATA3_PTX_HDDRX_N0: length 168.9
  TOP w0.127: v1(110.87,95.21) v2(111.43,95.21)
  L4 w0.114: v1(110.87,95.21) 111.09,95.43 111.64,95.43 113.27,95.96 115.96,95.96 117.99,97.18 121.19,97.18 122.12,98.12 122.12,98.35 123.28,99.5 124.03,99.5 124.48,99.05 126.57,99.05 129.34,101.82 134.48,101.82 134.64,101.66 137.25,101.66 140.1,98.81 140.1,97.97 140.38,97.69 140.38,93.46 141.05,92.79 141.05,60.4 141.65,59.79 141.65,57.65 142.09,57.22 142.9,56.41 142.9,54.06 149.2,47.75 163.5,47.75 164.55,46.7 184.12,46.7 189.07,41.75 190.27,36.52 190.27,17.51 187.69,10.78 187.69,9.81 187.38,9.5 187.24,9.5 v1(186.89,9.85)
  BOTTOM w0.127: v1(110.87,95.21) 110.6,95.47 110.42,95.47 110.27,95.32 110.27,93.56 109.78,93.07 CPU1.B15 ; C5603.2 v1(186.89,9.85)
SATA3_PTX_HDDRX_P0: length 169.2
  TOP w0.127: v1(110.9,95.84) 110.9,95.94 v2(111.4,96.44)
  L4 w0.114: v1(110.9,95.84) 111.08,95.66 111.6,95.66 113.23,96.19 115.9,96.19 117.93,97.41 121.09,97.41 121.89,98.21 121.89,98.44 123.18,99.73 124.12,99.73 124.57,99.28 126.47,99.28 129.24,102.05 134.57,102.05 134.73,101.89 137.34,101.89 140.33,98.91 140.33,98.06 140.61,97.78 140.61,93.56 141.28,92.89 141.28,60.49 141.88,59.89 141.88,57.75 142.31,57.32 142.31,57.32 143.12,56.51 143.12,54.15 149.29,47.98 163.6,47.98 164.64,46.93 184.21,46.93 189.28,41.86 190.5,36.54 190.5,17.47 187.91,10.74 187.91,9.71 187.47,9.27 187.2,9.27 v1(186.89,8.96)
  BOTTOM w0.127: CPU1.A15 110.03,93.79 110.03,95.42 110.32,95.71 110.77,95.71 v1(110.9,95.84) ; C5602.2 v1(186.89,8.96)
SATA_IREF: length 4.2
  BOTTOM w0.305: R1904.1 113.66,96.5 v2(113.18,96.02) 112.87,95.72 112.55,95.72 112.13,95.3 112.13,94.07 CPU1.A12
SATA_LED#: length 19.5
  TOP w0.102: v1(121.19,84.2) 121.49,84.5 121.49,86.3 121.94,86.76 121.94,87.22 123.06,88.33 123.06,88.51 124.57,90.02 124.57,91.26 124.99,91.67 124.99,91.72 124.99,91.72 124.99,92.35 125.4,92.76 v2(125.4,94.66) 125.47,94.73 125.47,95.78 125.09,96.16 R1905.2
  BOTTOM w0.089: CPU1.U3 117.84,83.96 119.1,83.96 119.54,84.4 120.06,84.4 120.07,84.4 120.98,84.4 v1(121.19,84.2)
SATA_ODD_DA#: length 104.8
  TOP w0.127: RN2002.7 122.39,93.29 121.53,92.43 121.53,90.04 121.66,89.91 121.66,89.24 121.51,89.09 121.51,88.67 v2(121.18,88.33) 121.01,88.16 121.01,87.16 120.32,86.47 120.32,86.28 120.02,85.99 119.52,85.99 118.19,84.66 117.93,84.66 v1(117.89,84.62)
  L3 w0.127: v1(132.84,93.26) 133.26,92.84 133.69,92.84 135.23,94.38 136.8,94.38 137.29,94.87 143.3,94.87 143.9,95.48 149.42,95.48 149.42,95.48 149.67,95.48 150.65,96.46 v1(151.46,96.46)
  L4 w0.127: v1(132.84,93.26) 131.88,94.23 129.54,94.23 129.11,93.79 128.62,93.79 128.24,93.41 128.24,93.01 125.39,90.16 124.99,90.16 122.71,87.87 122.45,87.87 120.47,85.89 119.62,85.89 118.35,84.62 v1(117.89,84.62)
  BOTTOM w0.127: v1(117.89,84.62) 117.59,84.92 CPU1.T3 ; v1(151.46,96.46) 151.61,96.46 153.26,98.11 154.64,98.11 155.22,97.54 173.68,97.54 174.35,96.87 174.73,96.87 175.13,96.47 185.01,96.47 185.84,95.63 189.88,95.63 194.52,90.98 194.52,87.45 193.56,86.49 R5602.2
SATA_ODD_DA#_C: length 6.8
  BOTTOM w0.127: ODD1.4 199.56,85.54 v2(196.06,85.54) R5602.1
SATA_ODD_PRSNT#: length 119.1
  TOP w0.127: RN1902.1 122.29,89.43 122.46,89.25 122.46,88.4 121.49,87.43 121.49,86.96 120.91,86.38 120.91,85.58 v1(120.78,85.45) ; v1(195.84,79.69) 195.72,79.58 v2(194.76,79.58) v1(192.29,79.58)
  L3 w0.127: v1(131.42,93.64) 131.77,94 133.9,94 134.76,94.86 135.68,94.86 136.37,95.56 143.01,95.56 143.62,96.17 149.39,96.17 150.7,97.48 153.1,97.48 v1(153.36,97.22)
  L4 w0.127: v1(120.78,85.45) 121.49,86.15 121.49,86.43 121.74,86.68 121.99,86.68 123.14,87.83 123.41,87.83 128.02,92.44 129.15,92.44 130.35,93.64 v1(131.42,93.64)
  BOTTOM w0.102: 202.25,78.29 ODD1.1
  BOTTOM w0.127: v1(153.36,97.22) 154.81,97.22 155,97.03 173.47,97.03 174.14,96.37 174.51,96.37 174.92,95.96 184.8,95.96 185.63,95.13 189.66,95.13 193.83,90.96 193.83,89.93 193.11,89.21 193.11,87.27 191.5,85.66 191.5,80.37 v1(192.29,79.58) ; v1(195.84,79.69) 196.85,78.68 R5604.1 200.02,76.06 202.25,78.29 ; v1(120.78,85.45) 120.78,85.12 120.47,84.8 120.19,84.8 119.98,84.6 119.25,84.6 CPU1.U1
SATA_ODD_PWRGT: length 115.8
  L3 w0.127: v1(153.36,95.95) 151.2,95.95 150.7,95.45 150.7,93.34 149.88,92.52 146.98,92.52 145.02,90.56 138.16,90.56 137.91,90.81 135.39,90.81 v1(135.33,90.75)
  L4 w0.127: v1(115.27,86.03) 115.69,86.44 116.84,86.44 117.05,86.65 117.87,86.65 118.82,87.59 118.82,89.04 120.61,90.83 123.42,90.83 123.89,91.29 123.89,92.24 124.52,92.88 126.12,92.88 127.27,94.03 127.27,94.57 127.55,94.84 128.06,94.84 128.37,94.53 131.34,94.53 131.79,94.98 131.79,95.71 132,95.93 132.51,95.93 132.71,95.72 132.71,95.14 134.69,93.16 134.69,91.83 135.33,91.19 v1(135.33,90.75)
  BOTTOM w0.127: v1(115.27,86.03) 115.27,86.09 CPU1.N6 ; v1(153.36,95.95) 152.85,96.46 152.85,97.34 153.37,97.86 154.53,97.86 155.11,97.28 173.58,97.28 174.24,96.62 174.62,96.62 175.03,96.21 184.9,96.21 185.74,95.38 189.77,95.38 194.08,91.07 194.08,89.82 193.36,89.1 193.36,87.16 192,85.8 192,83.16 192.74,82.42 v2(192.74,82.19) 192.74,79.39 192.38,79.04 192.32,79.04 191.54,78.26 R5607.2 192.29,77.05 U5601.4
SATA_PRX_ODDTX_N2: length 158.3
  L4 w0.114: v1(114.83,88.83) 115.29,89.29 115.29,89.59 116.83,91.13 117.44,91.13 118.01,91.7 118.01,92.47 119.35,93.81 119.35,94.41 120.47,95.53 122.77,95.53 124.74,97.5 128.03,97.5 129.97,99.45 137.34,99.45 138.6,98.19 138.6,94.92 138.45,94.76 138.45,93.25 139.04,92.65 139.04,91.42 139.55,90.92 139.55,87.82 138.44,86.72 138.44,75.51 139.55,74.4 139.55,59.78 139.93,59.4 139.93,57.26 141.28,55.9 141.28,53.49 148.65,46.13 162.11,46.13 163.61,44.63 163.61,44.63 163.74,44.5 180.54,44.5 181.92,43.12 182.67,43.12 v1(182.9,42.89)
  BOTTOM w0.127: v1(182.9,42.89) 183.11,43.11 183.38,43.11 183.72,43.45 183.72,44.15 183.52,44.35 183.52,46.37 184.55,47.41 184.55,48.13 187.69,51.27 187.69,53.61 ; 187.69,53.61 187.69,64.36 194.47,71.15 194.47,71.65 194.78,71.95 195.21,71.95 C5607.2 ; 187.69,53.61 v2(187.82,53.61) ; CPU1.J8 114.5,88.49 v1(114.83,88.83)
SATA_PRX_ODDTX_P2: length 158.4
  L4 w0.114: v1(182.85,43.7) 182.85,43.53 182.67,43.35 182.01,43.35 180.64,44.72 163.84,44.72 162.21,46.36 148.75,46.36 141.51,53.59 141.51,56 140.54,56.97 140.54,56.98 140.47,57.04 140.47,57.04 140.15,57.36 140.15,59.5 139.78,59.87 139.78,74.5 138.67,75.6 138.67,86.62 139.78,87.73 139.78,91.01 139.27,91.52 139.27,92.75 138.68,93.34 138.68,94.67 138.83,94.82 138.83,98.29 137.44,99.67 129.87,99.67 127.93,97.73 124.64,97.73 122.67,95.76 120.38,95.76 119.12,94.51 119.12,93.91 117.78,92.57 117.78,92.4 117.78,91.8 117.35,91.36 116.74,91.36 114.86,89.49 v1(114.85,89.49)
  BOTTOM w0.127: v1(114.85,89.49) 114.58,89.49 114.39,89.29 CPU1.H8 ; 187.45,52.36 187.45,64.46 194.23,71.25 194.23,71.75 194.68,72.19 195.07,72.19 C5608.2 ; 187.45,52.36 187.45,51.37 184.31,48.23 184.31,47.51 183.28,46.47 183.28,45.18 183.27,44.25 183.48,44.05 183.48,43.55 183.28,43.35 183.05,43.35 182.85,43.54 v1(182.85,43.7) ; 187.45,52.36 v2(187.32,52.36)
SATA_PTX_ODDRX_N2: length 158.3
  L4 w0.114: v1(110.82,97.64) 111.22,97.23 116.1,97.23 117.77,98.9 121.12,98.9 122.88,100.65 124.4,100.65 124.83,100.22 125.52,100.22 126.19,100.89 126.79,100.89 128.72,102.81 134.87,102.81 135.04,102.64 137.65,102.64 141.08,99.22 141.08,98.37 141.36,98.09 141.36,93.87 142.03,93.2 142.03,60.81 142.75,60.08 142.75,57.95 143.87,56.82 143.87,54.46 149.49,48.85 166,48.85 166.15,49.01 167.13,49.01 168.45,47.68 182.25,47.68 182.7,48.13 185.47,48.13 185.87,48.53 v1(185.87,48.61)
  BOTTOM w0.127: CPU1.A17 109.31,93.83 109.31,95.91 109.7,96.29 109.7,96.98 110.1,97.38 110.56,97.38 v1(110.82,97.64) ; C5611.2 195.14,70.23 194.35,70.23 188.22,64.1 188.22,50.11 ; 188.22,50.11 188.22,49.74 186.71,48.23 186.17,48.23 185.87,48.53 v1(185.87,48.61) ; 188.22,50.11 v2(188.1,50.11)
SATA_PTX_ODDRX_P2: length 158.3
  L4 w0.114: v1(110.82,97) 116.19,97 117.87,98.67 121.22,98.67 122.97,100.42 124.31,100.42 124.74,99.99 125.62,99.99 126.28,100.66 126.88,100.66 128.81,102.58 134.78,102.58 134.95,102.41 137.56,102.41 140.85,99.12 140.85,98.28 141.13,98 141.13,93.78 141.8,93.1 141.8,60.71 142.52,59.99 142.52,57.85 143.64,56.72 143.64,54.37 149.39,48.62 166.09,48.62 166.25,48.78 167.03,48.78 168.36,47.45 182.35,47.45 182.79,47.9 185.87,47.9 v1(185.87,47.88)
  BOTTOM w0.127: C5612.2 195.14,69.99 194.45,69.99 188.46,64 188.46,51.8 ; v1(185.87,47.88) 185.87,47.9 185.96,47.99 186.81,47.99 188.46,49.64 188.46,51.8 ; CPU1.B17 109.03,93.07 109.56,93.59 109.56,95.81 109.94,96.19 109.94,96.88 110.2,97.14 110.68,97.14 v1(110.82,97) ; 188.46,51.8 v2(188.59,51.8)
SATA_RCOMP: length 5.1
  BOTTOM w0.178: 111.48,94.02 111.45,93.99 111.45,93.59 111.49,93.55 111.49,93.49 111.78,93.2 CPU1.C12
  BOTTOM w0.254: v2(111.96,95.83) 111.75,95.62 111.75,94.29 111.48,94.02
  BOTTOM w0.508: R1906.1 112.77,96.64 v2(111.96,95.83)
SATA_RXN0_R: length 9.9
  BOTTOM w0.127: v2(192.51,11.74) 192.42,11.82 ; 192.42,11.82 193.33,12.73 196.4,12.73 HDD1.S5 ; 192.42,11.82 192.17,11.57 192.17,11.26 191.9,10.99 191.65,10.99 191.54,10.88 U5602.7 U5602.4 189.4,10.88 189.27,11 188.76,11 C5616.2
SATA_RXN2_R: length 6.8
  BOTTOM w0.127: ODD1.S5 201.76,73.09 199.84,73.09 198.77,72.02 198.5,72.02 ; v2(198.5,71.89) 198.5,72.02 ; 198.5,72.02 196.68,72.02 C5607.1
SATA_RXP0_R: length 9.9
  BOTTOM w0.127: 193.49,12.98 193.23,12.98 191.93,11.67 191.93,11.36 191.8,11.23 191.61,11.23 191.48,11.36 U5602.6 U5602.5 189.4,11.36 189.29,11.24 188.82,11.24 C5615.2 ; 193.49,12.98 v2(193.49,13.1) ; 193.49,12.98 196.37,12.98 HDD1.S6
SATA_RXP2_R: length 6.8
  BOTTOM w0.127: 197.3,72.26 196.68,72.26 C5608.1 ; 197.3,72.26 198.67,72.26 199.74,73.33 201.71,73.33 ODD1.S6 ; 197.3,72.26 v2(197.3,72.39)
SATA_TXN0_R: length 9.2
  BOTTOM w0.127: C5603.1 188.73,9.6 189.16,9.6 189.4,9.83 U5602.2 U5602.9 191.49,9.83 191.64,9.69 192.35,9.69 ; 192.35,9.69 192.56,9.69 193.09,9.17 196.37,9.17 HDD1.S3 ; 192.35,9.69 v2(192.35,9.81)
SATA_TXN2_R: length 6.7
  BOTTOM w0.127: ODD1.S3 201.73,69.54 200.05,69.54 199.4,70.19 197.46,70.19 ; 197.46,70.19 196.71,70.19 C5611.1 ; 197.46,70.19 v2(197.46,70.32)
SATA_TXP0_R: length 9.2
  BOTTOM w0.127: C5602.1 188.88,9.36 U5602.1 U5602.10 191.55,9.36 191.64,9.45 192.46,9.45 192.99,8.92 193.32,8.92 ; 193.32,8.92 196.4,8.92 HDD1.S2 ; 193.32,8.92 v2(193.32,8.8)
SATA_TXP2_R: length 6.6
  BOTTOM w0.127: ODD1.S2 201.74,69.3 199.95,69.3 199.3,69.95 198.65,69.95 ; 198.65,69.95 196.64,69.95 C5612.1 ; 198.65,69.95 v2(198.65,69.82)
SLEEVE: length 25.6
  TOP w0.203: v3(35.3,15.71) 35.83,15.18 HDA27.18
  TOP w0.305: v3(35.3,15.71) 34.9,16.12 RN2901.3
  TOP w0.508: v3(25.13,4.63) 24.82,4.32 EC2906.1 23.79,3.83 R2911.2
  L3 w1.016: v3(25.13,4.63) 23.85,5.92 23.85,10.52 27.15,13.82 28.89,13.82 30.3,15.23 34.81,15.23 v3(35.3,15.71)
  vias: v2(34.36,15.87)
SLEEVE_CTRL: length 4.9
  BOTTOM w0.254: R2915.2 29.85,18.99 30.09,18.75 U2901.6 28.73,18.13 28.57,17.98 v2(28.57,17.8) 28.57,17.62 28.71,17.48 U2901.5
SLEEVE_R: length 22.9
  TOP w1.016: 21.56,6.51 20.94,6.51 18.98,8.48 v2(18.74,8.48) 15.92,11.29 15.92,12.31 13.51,14.72 5.42,14.72 HPMIC1.4
SM_DRAMRST#: length 17
  BOTTOM w0.089: CPU1.AV15 110.24,72.22 110.69,71.76 110.69,70.42
  BOTTOM w0.127: 110.69,70.42 110.69,69.28 110.53,69.12 110.53,67.35 110.23,67.06 110.23,64.61 112.09,62.76 v2(112.09,59.94) 112.09,59.34 112.87,58.56 R410.2 R404.1
SM_INTRUDER#: length 11.5
  TOP w0.102: R1901.2 118.06,63.28 118.06,64.66 117.75,64.97 117.75,66.58 117.29,67.04 117.29,67.66 116.92,68.03 116.92,69.01 v2(116.62,69.32) 116.08,69.86 v1(116.02,69.86)
  BOTTOM w0.089: 115.95,70.57 115.8,70.71 115.8,72.22 115.84,72.26 115.84,72.75 CPU1.AU6
  BOTTOM w0.102: v1(116.02,69.86) 116.02,70.49 115.95,70.57
SM_RCOMP_0: length 2.8
  TOP w0.508: v1(82.04,73.59) 81.77,73.87 v2(81.77,74.22) 81.77,74.58 82.33,75.14 R407.2
  BOTTOM w0.305: v1(82.04,73.59) 82.33,73.31 CPU1.AU60
SM_RCOMP_1: length 4.4
  TOP w0.508: R408.2 80.88,74.73 80.88,73.19 v2(81.29,72.78) 81.3,72.76 81.3,72.75 v1(81.84,72.22)
  BOTTOM w0.305: CPU1.AV60 82,72.39 v1(81.84,72.22)
SM_RCOMP_2: length 6.4
  BOTTOM w0.203: CPU1.AU61 81.16,73.31 81.05,73.42 80.01,73.42 79.86,73.27 78.94,72.36 78.38,72.36
  BOTTOM w0.508: R409.2 77.05,72.55 v2(77.21,72.38) 77.24,72.36 78.38,72.36
SMB_CLK: length 21.3
  TOP w0.14: v1(131.49,74.55) 131.57,74.55 v2(131.95,74.92)
  L4 w0.127: v1(120.79,73.35) 120.91,73.47 121.84,73.47 123.46,75.09 124,75.09 124.44,75.53 126.21,75.53 127.73,74.01 127.73,72.46 128.5,71.7 v1(129.39,71.7) 129.51,71.7 130.15,72.33 130.15,73.21 v1(131.49,74.55)
  BOTTOM w0.089: 119.45,74.06 119.29,74.22 118.53,74.22 CPU1.AP2
  BOTTOM w0.14: RN1811.3 131.87,74.16 v1(131.49,74.55) ; v1(129.39,71.7) 129.42,71.73 Q1801.3 ; v1(120.79,73.35) 120.21,73.93 119.58,73.93 119.45,74.06
SMB_DATA: length 26.3
  TOP w0.14: v1(122.45,76.86) 122.45,77.05 122.81,77.41 v2(122.81,77.44)
  L4 w0.127: v1(122.45,76.86) 121.99,76.86 121.81,76.68 121.46,76.68 121.32,76.83 120.97,76.83 120.72,76.58 120.72,76.29 120.75,76.27 120.75,75.35 120.37,74.97 120.37,74.24 120.6,74.01 121.66,74.01 123.25,75.59 123.79,75.59 124.23,76.04 126.42,76.04 128.24,74.22 128.24,73.25 128.43,73.06 v1(129.41,73.06) 129.62,73.26 129.62,73.39 131.47,75.25 v1(131.47,75.31)
  BOTTOM w0.14: CPU1.AH1 118.92,78.23 120.17,78.23 120.17,78.23 120.77,78.23 121.42,77.58 121.77,77.58 122.06,77.3 122.08,77.3 122.45,76.92 v1(122.45,76.86) ; v1(129.41,73.06) 129.39,73.03 Q1801.6 ; v1(131.47,75.31) 131.96,74.82 RN1811.4
SMBC_THERM_NV: length 22.6
  TOP w0.14: 179.97,109.94 179.49,109.46 178.06,109.46 177.62,109.91 176.49,109.91 175.78,110.62 v1(175.78,110.84) ; 179.97,109.94 v2(180.09,109.81) ; 179.97,109.94 180.45,110.42 180.45,111.1 v1(180.97,111.62) 181.12,111.77 181.36,111.77 181.75,112.16 181.75,113.49 182.2,113.94 RN7601.2
  L4 w0.127: v1(180.97,111.62) 181.46,111.62 182,112.16 183.15,112.16 183.9,112.9 188.02,112.9 189.24,114.11 v1(190.02,114.11)
  BOTTOM w0.14: Q7601.1 190.7,114.8 v1(190.02,114.11) ; GPU1.D9 175.79,110.91 175.79,110.85 v1(175.78,110.84)
SMBD_THERM_NV: length 25.2
  TOP w0.14: v1(176.55,110.82) 176.6,110.82 176.99,110.43 177.83,110.43 178.28,109.98 179.28,109.98 179.93,110.64 179.93,111.32 180.9,112.29 v1(181.14,112.29) 181.23,112.38 181.23,113.71 182.11,114.59 RN7601.1
  L4 w0.127: v1(191.64,117.06) 189.57,114.99 189.4,114.99 187.81,113.4 183.68,113.4 182.94,112.66 181.44,112.66 181.14,112.37 181.14,112.3 v1(181.14,112.29)
  BOTTOM w0.14: v1(176.55,110.82) 176.53,110.82 176.15,110.45 GPU1.D8 ; Q7601.4 192.61,116.1 v1(191.64,117.06) 191.56,117.06 v2(190.9,117.72)
SML0_CLK: length 15.7
  TOP w0.14: v2(132.26,76.62) 131.99,76.36 v1(131.52,76.36)
  L4 w0.127: v1(121.41,74.91) 121.41,74.95 121.82,75.36 122.43,75.36 123.04,75.98 123.63,75.98 124.22,76.57 127.14,76.57 127.73,77.16 128.54,77.16 129.3,76.39 131.49,76.39 v1(131.52,76.36)
  BOTTOM w0.127: 119.62,75.16 119.1,75.16 119.01,75.25 CPU1.AN1
  BOTTOM w0.14: v1(131.52,76.36) 131.87,76.36 131.89,76.34 RN1807.5 ; 119.62,75.16 120.56,75.16 120.65,75.07 121.24,75.07 v1(121.41,74.91)
SML0_DATA: length 16.1
  TOP w0.14: v1(121.14,76.41) 121.14,76.64 v2(120.75,77.03)
  L4 w0.127: v1(131.44,76.99) 131.35,76.9 129.51,76.9 128.75,77.67 127.52,77.67 126.93,77.08 124.01,77.08 123.42,76.48 122.83,76.48 122.22,75.87 121.68,75.87 v1(121.14,76.41)
  BOTTOM w0.127: v1(121.14,76.41) 119.92,77.63 119.36,77.63 119.23,77.5 CPU1.AK1
  BOTTOM w0.14: v1(131.44,76.99) 131.44,76.99 RN1807.6
SML1_CLK: length 201.7
  TOP w0.14: Q2601.3 125.25,57.14 125.55,56.83 126.81,56.83 127.25,57.28 127.96,57.28 128.42,57.74 v2(128.42,57.83) 128.67,57.57 129.42,57.57 v1(129.6,57.4) ; v1(163.29,35.58) 163.24,35.54 163.24,35.53 163.01,35.3 KBC24.67
  L3 w0.127: v1(178.97,45.97) 183.21,50.22 183.21,56.07 185.25,58.11 185.25,61.4 187.83,63.97 187.83,85.03 188.2,85.4 188.2,95 185.61,97.59 185.61,101.71 186.16,102.25 186.16,103.44 187.81,105.09 187.81,109.15 191.28,112.62 191.28,113.41 v1(191.21,113.48) ; v1(129.6,57.4) 129.72,57.4 129.78,57.34 130.25,57.34 130.65,57.74 130.65,61.81 131.35,62.51 131.35,66.13 130.99,66.49 130.32,66.49 128.37,68.44 128.37,70.43 128.9,70.96 129.48,70.96 130.38,71.86 130.38,77.29 131.23,78.14 131.42,78.14 v1(131.55,78.27)
  L4 w0.127: v1(157.62,36.58) 157.49,36.58 157.41,36.51 156.98,36.51 156.91,36.58 154.17,36.58 152.95,37.8 150.49,37.8 148.81,39.48 148.11,39.48 147.51,40.07 146.79,40.07 145.06,41.8 144.57,41.8 141.59,44.79 140.17,44.79 135.02,49.95 134.13,49.95 133.67,50.4 133.67,53.43 130.95,56.15 130.95,56.68 130.22,57.4 v1(129.6,57.4) ; v1(131.55,78.27) 131.39,78.27 131.07,77.95 130.53,77.95 128.98,79.49 126.75,79.49 125.22,77.96 121.77,77.96 121.12,77.32 120.51,76.7 120.51,76.2 120.53,76.18 120.53,75.83 119.72,75.02 119.5,75.02 119.02,74.54 119.02,72.76 119.58,72.21 v1(119.76,72.21)
  BOTTOM w0.089: CPU1.AU3 117.88,72.77 118.57,72.77 118.62,72.72 119.08,72.72 119.24,72.56
  BOTTOM w0.127: 119.55,72.26 119.24,72.56
  BOTTOM w0.14: v1(178.97,45.97) 179.18,45.76 179.18,45.47 178.6,44.89 176.49,44.89 175.52,45.86 167.86,45.86 165.35,43.35 165.35,42.66 163.78,41.1 163.78,38.32 164.14,37.97 164.14,35.81 163.76,35.43 163.44,35.43 v1(163.29,35.58) 163.09,35.38 160.25,35.38 159.1,36.53 157.67,36.53 v1(157.62,36.58) ; v1(191.21,113.48) 191.34,113.61 191.36,113.61 192.55,114.8 Q7601.6 ; v1(119.76,72.21) 119.6,72.21 119.55,72.26 ; RN1807.8 131.68,78.14 v1(131.55,78.27)
SML1_DATA: length 197
  TOP w0.14: Q2601.6 126.91,56.15 v2(127.79,56.15) 127.79,56.37 128.47,57.05 129.21,57.05 129.38,56.88 129.59,56.88 v1(129.79,56.69) ; v1(163.29,34.82) 163.21,34.9 KBC24.68
  L3 w0.127: v1(191.14,114.13) 191.35,114.13 191.79,113.69 191.79,112.41 188.31,108.94 188.31,104.88 186.66,103.23 186.66,102.04 186.12,101.5 186.12,97.8 188.71,95.21 188.71,85.19 188.34,84.82 188.34,63.76 185.76,61.19 185.76,57.9 183.72,55.86 183.72,50.01 179.98,46.26 179.98,46.05 v1(180.05,45.97) ; v1(129.79,56.69) 129.93,56.83 130.46,56.83 131.16,57.53 131.16,61.6 131.86,62.3 131.86,66.34 131.2,67 130.53,67 128.88,68.65 128.88,70.22 129.11,70.45 129.69,70.45 130.88,71.65 130.88,77.08 131.44,77.63 v1(131.53,77.63)
  L4 w0.127: v1(129.79,56.69) 129.82,56.65 130.25,56.65 130.44,56.47 130.44,55.94 133.16,53.22 133.16,50.19 133.92,49.44 134.81,49.44 139.96,44.28 141.37,44.28 144.36,41.3 144.85,41.3 146.58,39.57 147.3,39.57 147.9,38.97 148.6,38.97 150.28,37.29 152.74,37.29 153.96,36.07 156.7,36.07 156.77,36 157.42,36 157.5,35.92 v1(157.63,35.92) ; v1(121.64,77.1) 121.99,77.46 125.43,77.46 126.96,78.99 128.77,78.99 130.32,77.44 131.34,77.44 v1(131.53,77.63)
  BOTTOM w0.089: 120.27,78 119.2,78 119.16,77.97 118.02,77.97 117.77,78.21 CPU1.AH3
  BOTTOM w0.14: Q7601.3 191.59,116.1 191.72,115.97 191.72,114.7 v1(191.14,114.13) ; v1(121.64,77.1) 121.63,77.1 121.58,77.1 120.68,78 120.27,78 ; v1(131.53,77.63) 131.67,77.49 RN1807.7 ; v1(157.63,35.92) 157.73,36.01 158.88,36.01 160.03,34.86 163.22,34.86 163.27,34.82 v1(163.29,34.82) 163.39,34.91 163.98,34.91 164.66,35.6 164.66,38.18 164.3,38.54 164.3,40.88 165.87,42.44 165.87,43.13 168.07,45.34 175.31,45.34 176.28,44.37 178.82,44.37 179.7,45.25 179.7,45.62 v1(180.05,45.97)
SP_PLLVDD: length 1.2
  BOTTOM w0.356: v1(169.11,108.32) 169.1,108.32 GPU1.N6 ; v1(169.08,109.14) GPU1.M6
  vias: v2(169.11,105.15)
SPI_CLK_R: length 101.2
  TOP w0.14: v1(156.94,23.44) 157.1,23.28 R2420.1
  L3 w0.127: v1(124.55,83.64) 125.18,83.64 125.8,84.27 126.54,84.27 127.36,83.45 127.36,81.2 128.78,79.78 132,79.78 132.81,78.97 133.25,78.53 133.25,71.51 137.68,67.08 137.68,49.55 145.7,41.53 145.7,39.48 148.68,36.5 148.68,34.07 149.72,33.03 v1(149.72,31.27) 150.15,30.84 151,30.84 153.71,28.14 153.71,27.65 156.37,24.98 156.37,24.01 v1(156.94,23.44)
  BOTTOM w0.14: 150.2,31.75 v1(149.72,31.27) ; 150.2,31.75 150.3,31.85 151.94,31.85 155.2,35.11 155.2,36 155.85,36.65 155.85,37.75 156.22,38.13 EC2503.1 156.22,42.9 153.74,45.38 SKT25.6 ; 150.2,31.75 v2(150.07,31.87) ; v1(124.55,83.64) 124.2,83.29 123.59,83.29 122.87,82.57 R1806.1
SPI_CS0#_R: length 100.4
  TOP w0.14: R1807.1 123.7,88.58 124.97,89.86 124.97,91.09 v1(125.42,91.54) ; R2419.1 157.01,24.17 v1(156.94,24.1)
  L3 w0.127: v1(156.94,24.1) 157.36,24.53 157.36,25.24 155.11,27.49 155.11,28.05 154.68,28.49 154.46,28.49 151.14,31.8 151.14,34.34 v1(150.28,35.21) 150.2,35.29 150.2,37.13 147.23,40.11 147.23,42.31 139.3,50.24 139.3,68.41 134.78,72.93 134.78,79.16 132.12,81.82 130.74,81.82 130.58,81.65 129.89,81.65 128.88,82.66 128.88,84.17 128.26,84.79 128.26,87.31 128.44,87.48 128.44,89.98 126.88,91.54 125.42,91.54 125.42,91.54 v1(125.42,91.54)
  BOTTOM w0.14: SKT25.1 147.11,42.84 147.39,42.55 147.39,41.59 146.69,40.89 R2501.1 147.37,38.49 147.37,36.01 147.93,35.45 v2(149.22,35.45) 150.04,35.45 v1(150.28,35.21)
SPI_HOLD#: length 81.7
  TOP w0.14: v1(124.86,84.27) 125.17,83.96 R1812.1
  L3 w0.127: v1(150.7,34.14) 150.51,33.95 149.88,33.95 149.44,34.39 149.44,36.82 146.46,39.79 146.46,42 138.44,50.02 138.44,68.17 134.01,72.6 134.01,78.85 132.32,80.55 131.68,80.55 131.68,80.55 129.09,80.55 128.12,81.52 128.12,83.85 126.55,85.42 126.17,85.42 125.02,84.27 v1(124.86,84.27)
  BOTTOM w0.14: v1(150.7,34.14) 151.17,34.62 151.17,36.27 151.56,36.65 152.16,36.65 152.39,36.88 RN2501.2 v2(152.39,38.6) 152.39,38.98 150.62,40.75 150.36,41.01 150.36,41.02 150.14,41.23 150.14,43.37 150.91,44.14 SPI25.7
SPI_SI_R: length 100.3
  TOP w0.14: R2422.1 157.22,25.06 v1(156.92,24.76)
  L3 w0.127: v1(156.92,24.76) 156.92,24.97 154.09,27.8 154.09,28.3 151.1,31.28 v1(150.42,31.28) 150.1,31.6 150.1,33.19 149.06,34.23 149.06,36.66 146.08,39.63 146.08,41.74 138.06,49.76 138.06,67.24 133.63,71.66 133.63,78.69 132.97,79.35 132.16,80.17 131.84,80.17 128.93,80.17 127.74,81.36 127.74,83.61 v1(126.37,84.98)
  BOTTOM w0.14: v1(126.37,84.98) 126.13,84.74 R1808.1 ; SPI25.5 154.04,46.68 154.16,46.56 154.16,45.55 156.64,43.07 156.64,38.89 EC2501.1 156.27,37.58 156.27,36.48 155.94,36.15 ; v1(150.42,31.28) 150.56,31.43 152.12,31.43 155.62,34.93 155.62,35.83 155.94,36.15 ; 155.94,36.15 v2(156.04,36.05)
SPI_SO_R: length 87.5
  TOP w0.14: v1(155.57,24.73) 155.9,24.73 157.13,25.96 R2423.1
  L3 w0.127: v1(155.57,24.73) 155.57,25.24 153.32,27.49 153.32,27.98 150.85,30.46 149.89,30.46 149.12,31.23 149.12,33.09 148.23,33.98 v1(148.23,36.02) 148.22,36.03 148.22,36.42 145.32,39.32 145.32,41.37 137.3,49.39 137.3,66.92 132.87,71.35 132.87,78.37 131.85,79.4 128.63,79.4 126.98,81.04 126.98,83.29 126.44,83.82 v1(126.17,83.82)
  BOTTOM w0.14: R1809.1 125.86,83.51 v1(126.17,83.82) ; SKT25.2 147.36,44.11 147.89,43.57 EC2502.1 v2(147.89,37.61) 147.89,36.37 148.23,36.03 v1(148.23,36.02)
SPI_WP#: length 90.8
  TOP w0.14: R1811.1 124.53,86.19 v2(124.53,88.71) 124.53,88.82 125.41,89.7 125.41,90.88 v1(125.42,90.89)
  L3 w0.127: v1(125.42,90.89) 126.99,90.89 128.06,89.82 128.06,87.64 127.88,87.47 127.88,84.63 128.5,84.01 128.5,81.68 128.91,81.27 131.06,81.27 131.22,81.44 131.97,81.44 134.4,79.01 134.4,72.78 138.92,68.25 138.92,50.08 146.84,42.16 146.84,39.95 149.82,36.97 149.82,34.64 v1(149.98,34.48)
  BOTTOM w0.14: SKT25.3 147.5,45.38 149.72,43.16 149.72,41.05 150.45,40.33 150.45,40.33 151.84,38.93 151.84,37.91 151.74,37.81 RN2501.1 151.4,37.19 150.75,36.54 150.75,34.97 150.26,34.48 v1(149.98,34.48)
SRTC_RST#: length 11
  TOP w0.127: v1(115.14,72.08) 115.5,72.08 117.53,70.05 v2(117.53,68.19) 117.53,67.14 117.99,66.68 117.99,65.41 C1902.1 118.75,64.66 RN1901.4
  BOTTOM w0.089: CPU1.AV6 115.25,72.08 v1(115.14,72.08)
STRAP0: length 6.6
  BOTTOM w0.127: v2(176.36,98.85) 176.45,98.95 R7646.2 176.36,99.78 R7625.2 175.53,101.43 R7621.1 175.53,101.7 176.22,102.39 176.22,104.62 GPU1.D1
STRAP1: length 6.5
  BOTTOM w0.127: R7635.2 173.8,101.41 R7622.1 173.84,102.27 174.32,102.27 v2(174.55,102.5) 175.79,103.75 175.79,104.98 176.15,105.33 GPU1.D2
STRAP2: length 5.3
  TOP w0.127: v2(173.94,106.11) 173.64,106.41 173.64,106.88 173.89,107.13 174.46,107.13 v1(174.84,107.5) 174.92,107.5 175.35,107.94 R7606.2 175.82,107.94 R7637.1
  BOTTOM w0.102: v1(174.84,107.5) 174.85,107.49 174.9,107.49 GPU1.E4
STRAP3: length 37.2
  TOP w0.127: v1(172.97,102.1) 173.66,102.1 174.24,102.67 174.24,103.25 173.81,103.68 173.81,105.39 174.74,106.31 174.78,106.31 175.55,107.08 177.14,107.08 178.98,105.24 179.89,105.24 180.39,105.74 182.9,105.74 183.06,105.58 185.18,105.58 186.69,107.09 186.69,108.41 187.55,109.26 v2(187.55,110.33) 187.55,111.72 v1(188.54,112.72)
  BOTTOM w0.102: 175.71,105.69 175.3,106.1 GPU1.E3
  BOTTOM w0.127: v1(188.54,112.72) 188.29,112.72 187.48,113.52 R7615.2 ; 175.71,105.69 175.78,105.62 175.78,105.29 175.57,105.07 175.57,103.84 175.04,103.32 173.7,103.32 173.4,103.02 173.4,102.53 v1(172.97,102.1) 172.51,102.56 171.52,102.56 171.21,102.24 R7609.1
STRAP4: length 8.2
  BOTTOM w0.127: GPU1.D3 176.34,106.1 176.34,106.03 176.51,105.87 176.51,104.34 176.67,104.18 176.67,102.17 176.33,101.83 R7632.1 176.33,100.73 R7634.2 176.45,100.6 177.06,99.99 177.06,99.54 v2(177.63,98.98)
STRAP_REF0_GND_N9: length 2.4
  TOP w0.127: v2(173.99,107.54) 174.28,107.83 R7607.2 174.28,108.96 v1(174.06,109.18)
  BOTTOM w0.102: GPU1.F6 v1(174.06,109.18)
SUS_CLK: length 85.5
  L3 w0.127: v1(174.19,32.86) 174.19,33.25 173.07,34.36 171.87,34.36 169.45,36.78 165.04,36.78 163.32,38.51 162.72,38.51 161.72,39.51 161.72,43.31 151.07,53.96 151.07,54.28 150.04,55.31 150.04,56.43 149.45,57.02 148.33,57.02 143.64,61.7 143.64,71.46 138.95,76.15 138.95,81.46 136.57,83.85 134.49,83.85 132.52,85.81 132.52,86.16 132.35,86.33 132.35,87.92 131.9,88.36 131.53,88.36 131.04,87.87 v1(131.04,87.81)
  BOTTOM w0.14: v1(174.19,32.86) 173.1,32.86 172.82,33.14 172.56,33.14 171.7,33.14 v2(171.27,32.71) 171.24,32.68 R2441.2 ; v1(131.04,87.81) 131.04,88.04 R1710.2
SUS_CLK_PCH: length 21.5
  L4 w0.127: v1(115.8,80.23) 116.24,80.66 117.4,80.66 119.33,82.6 120.22,82.6 120.31,82.69 122.28,82.69 124.95,85.36 125.92,85.36 125.98,85.42 126.58,85.42 128.58,87.43 128.58,88.85 129.09,89.36 v1(129.28,89.36)
  BOTTOM w0.14: R1710.1 130.72,89.2 EC1701.2 129.98,89.93 v2(129.28,89.93) v1(129.28,89.36) ; v1(115.8,80.23) 115.8,79.95 CPU1.AE6
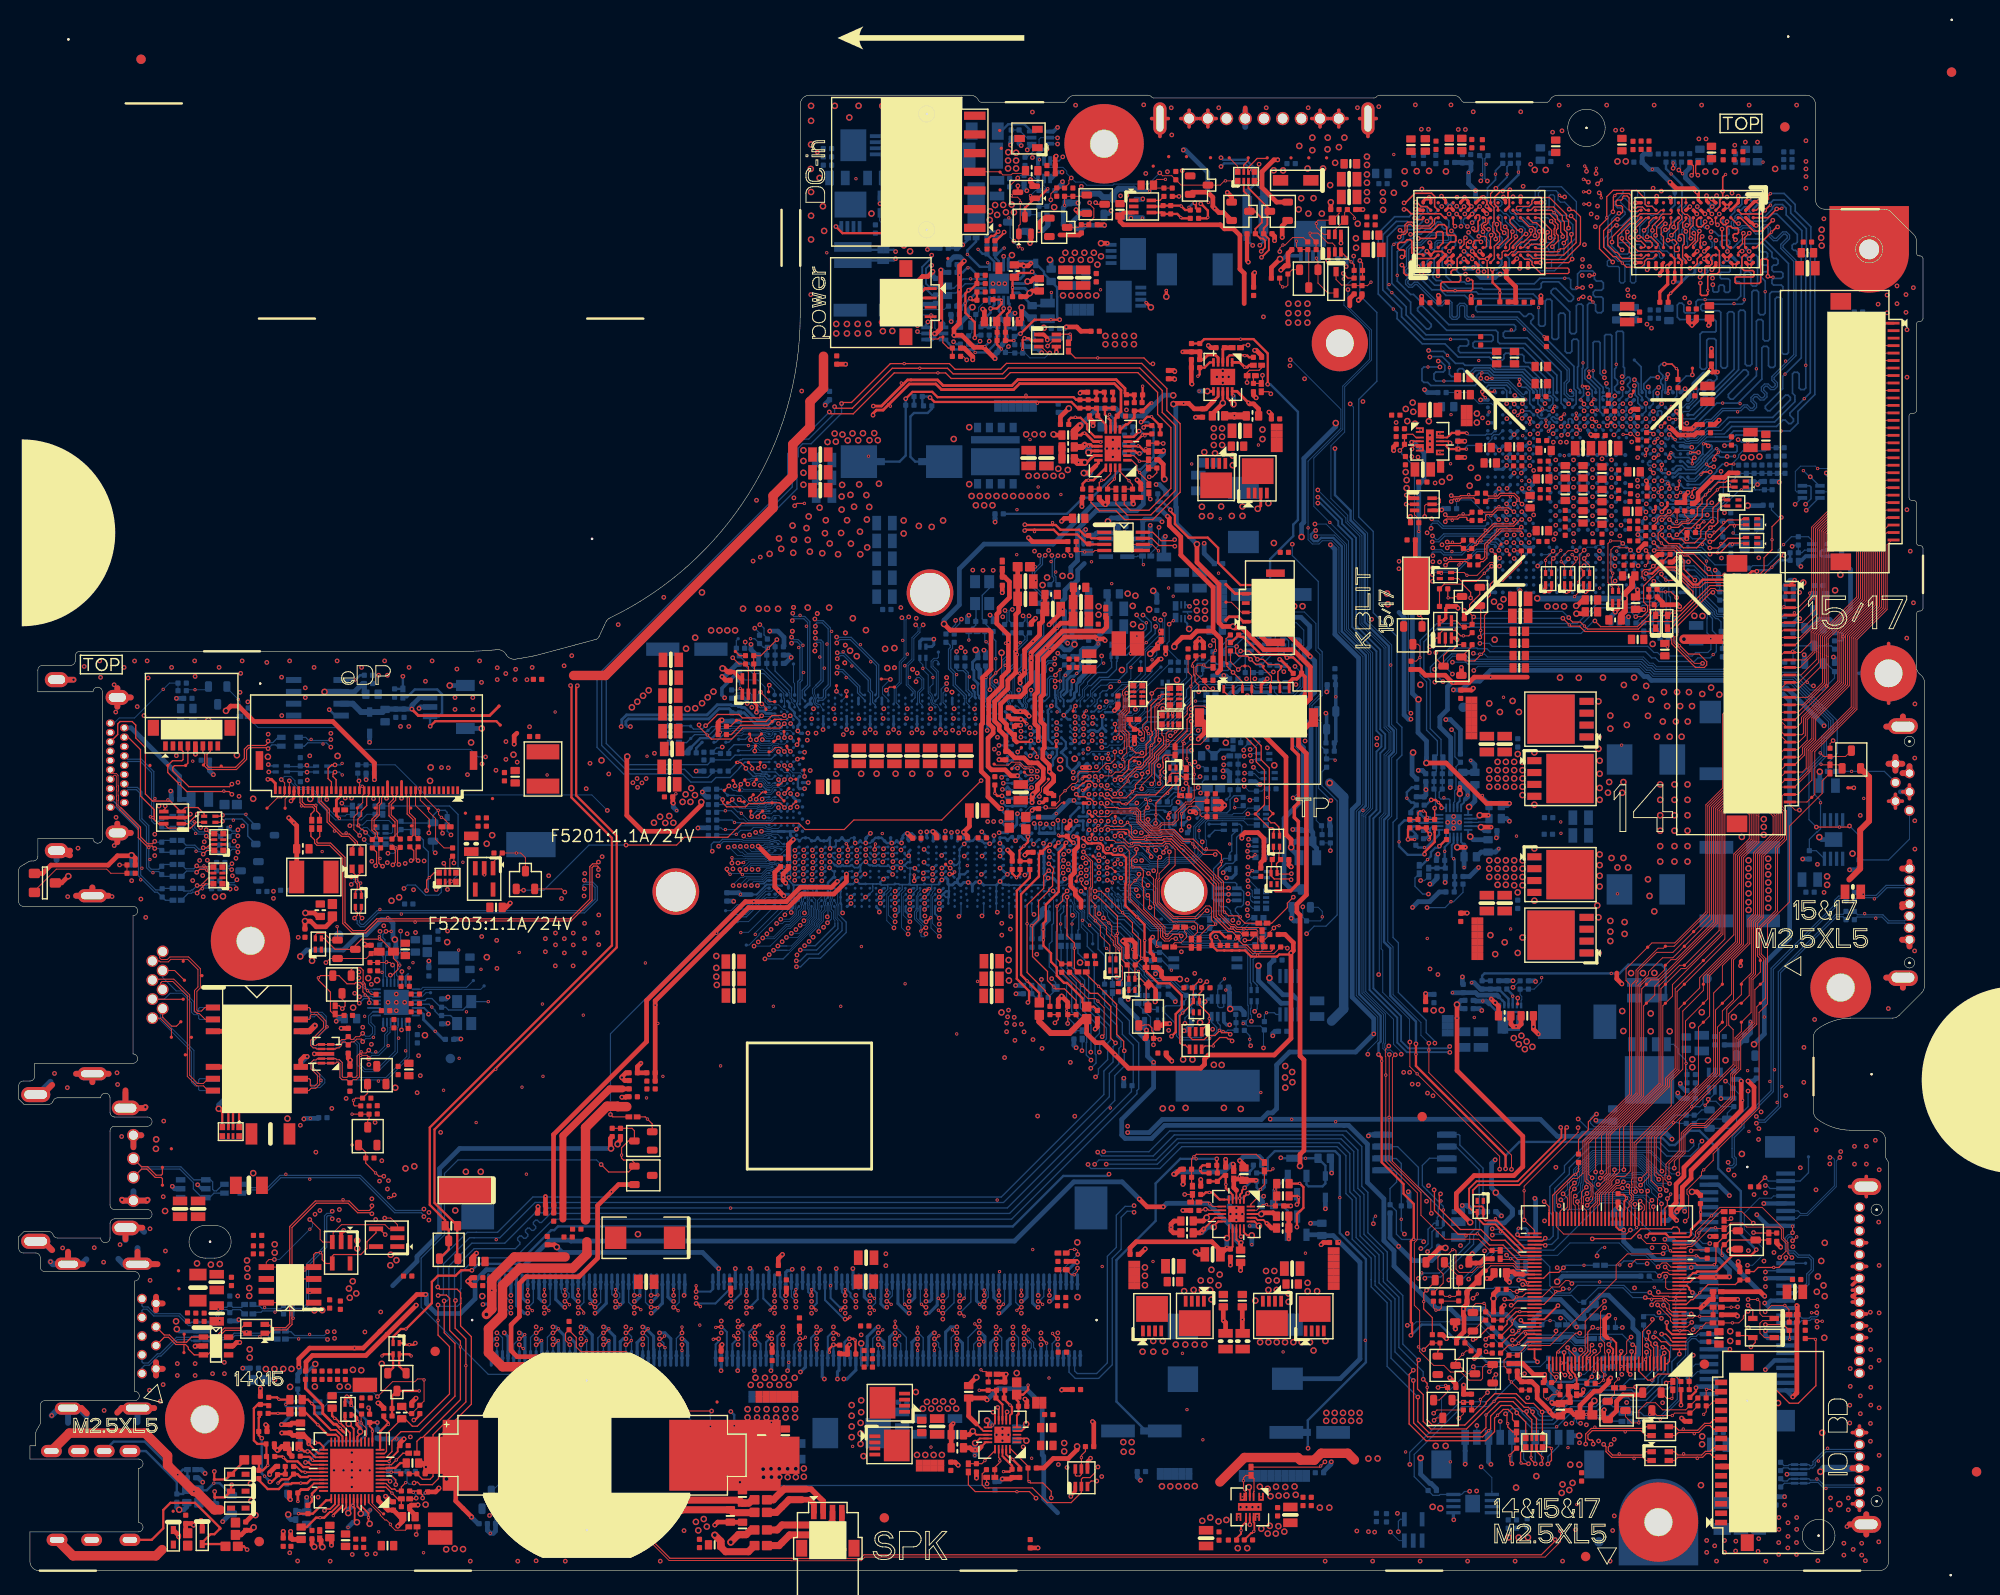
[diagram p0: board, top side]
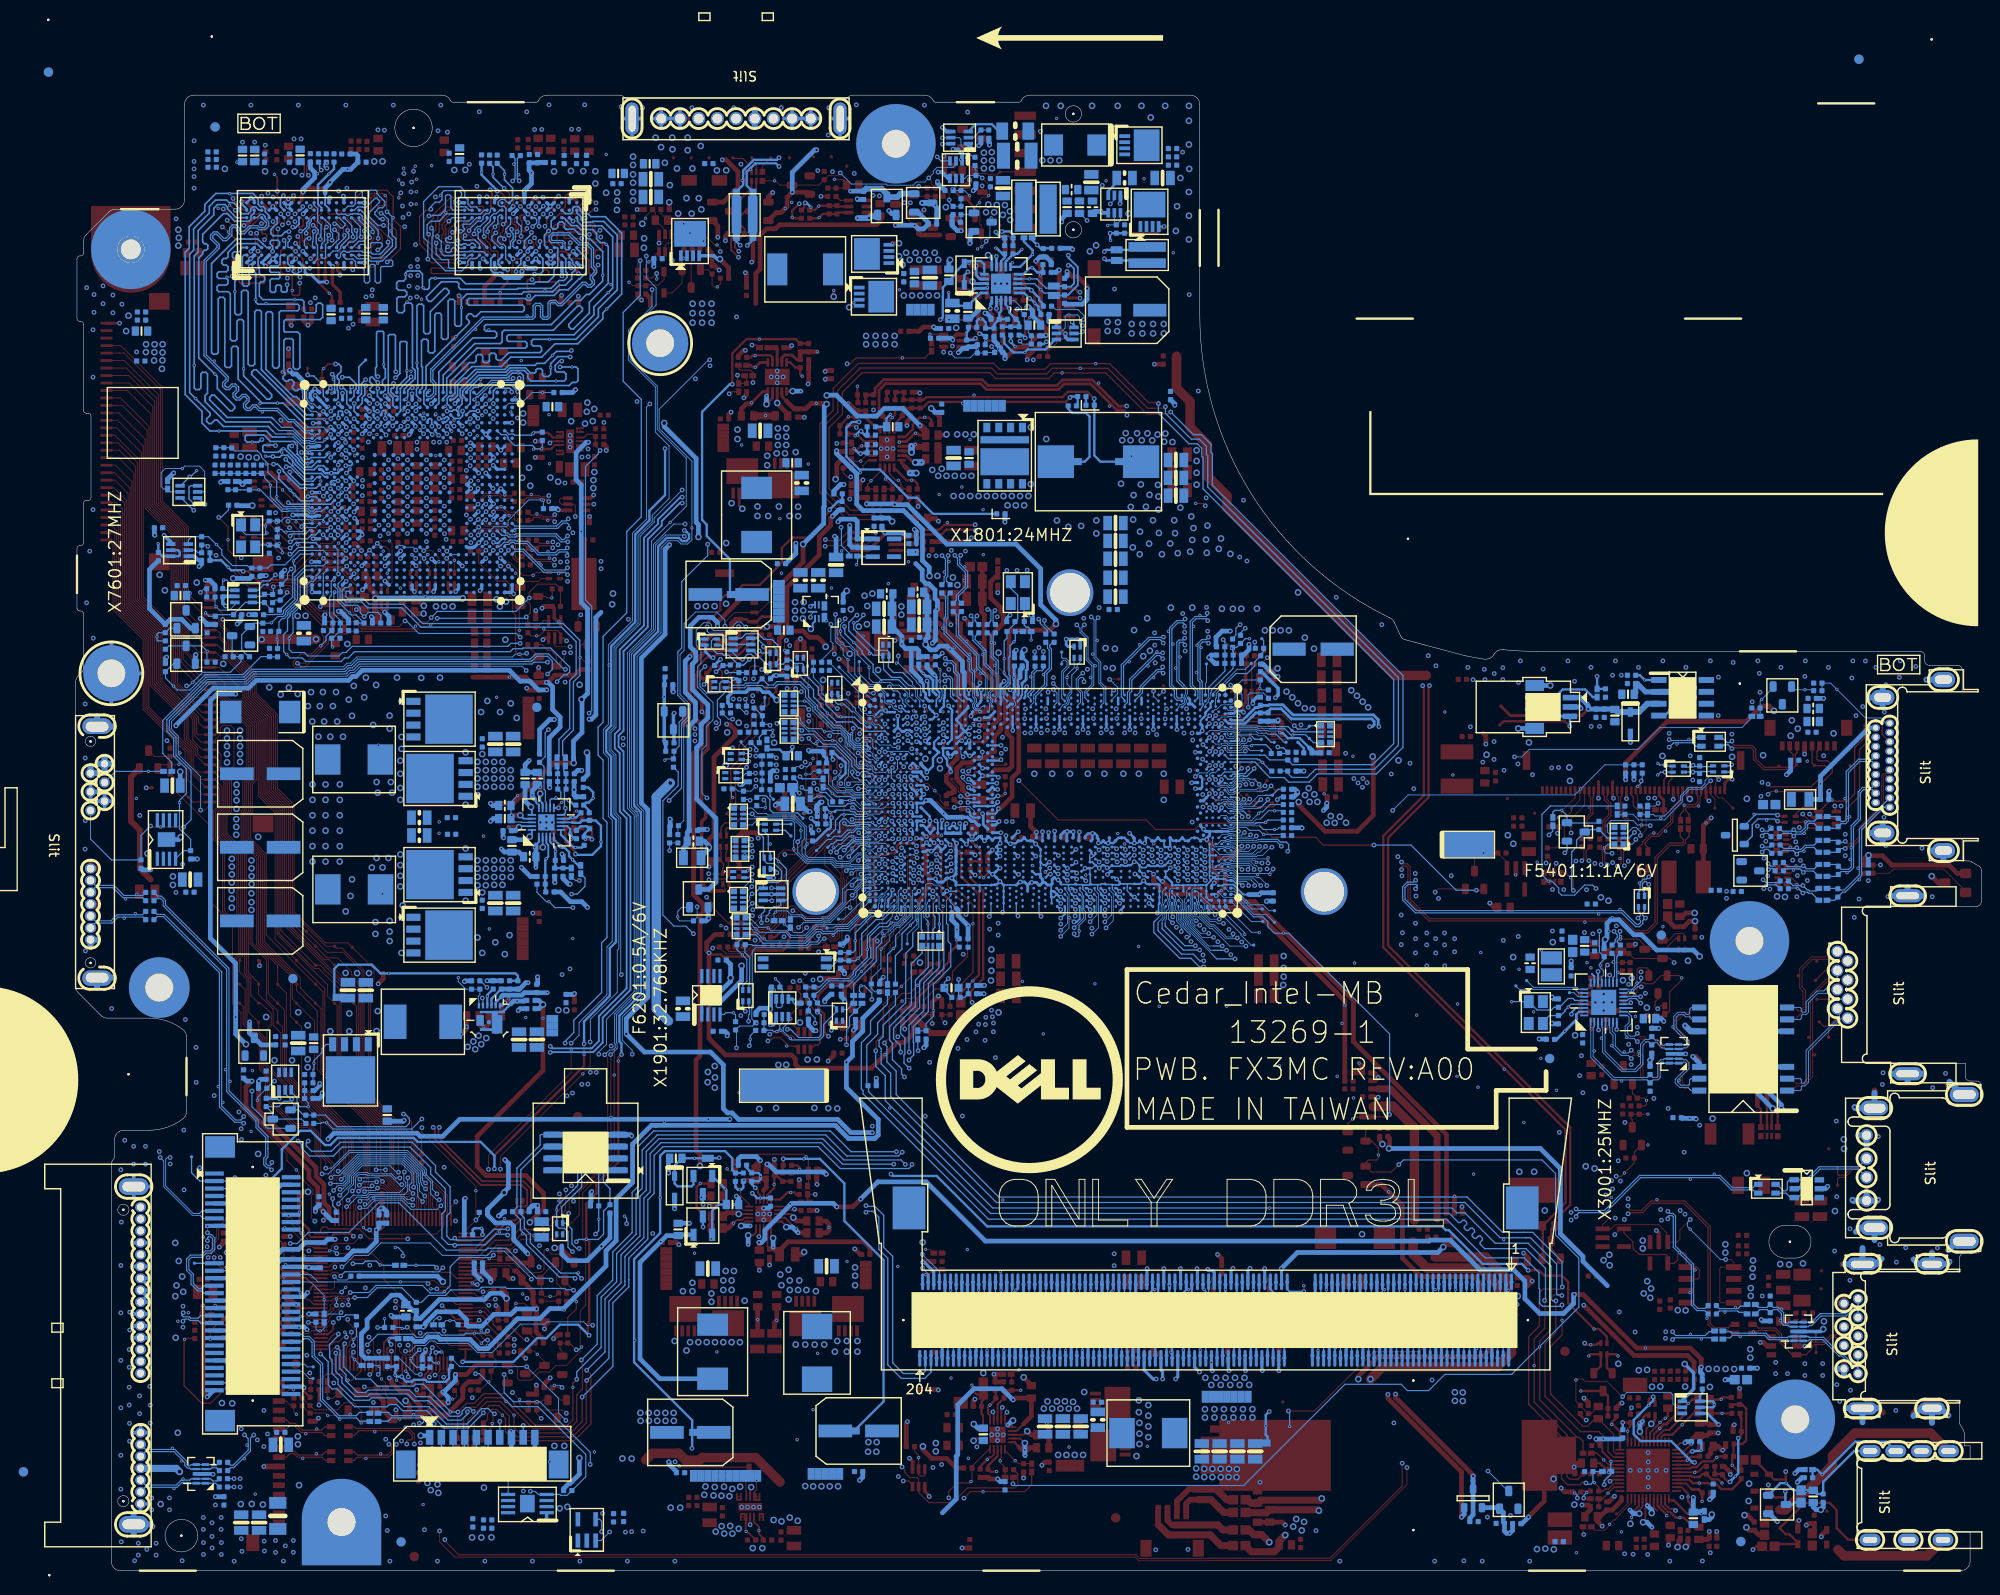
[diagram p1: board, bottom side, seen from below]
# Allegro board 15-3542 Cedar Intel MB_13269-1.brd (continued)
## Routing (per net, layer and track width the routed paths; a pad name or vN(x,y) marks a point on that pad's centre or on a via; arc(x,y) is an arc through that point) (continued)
SUSCLK_KBC: length 7.2
  TOP w0.14: KBC24.77 163.11,31.3 163.74,31.92 164.74,31.92 v1(165.24,32.42)
  BOTTOM w0.14: R2441.1 v2(167.43,32.68) 165.5,32.68 v1(165.24,32.42)
SYS_PEX_RST_MON#: length 48.5
  TOP w0.127: U7301.4 153.78,101.65 154.45,100.99 R7306.1 155.18,100.99 R7304.2 155.47,101.89 v1(155.64,102.06) 155.2,102.5 155.2,103.4 156.29,104.49 D7301.2 ; v1(181.23,104.7) 181.02,104.7 177.45,101.13 177.45,100.13 177.3,99.98 177.3,99.4 178.61,98.09 179.76,98.09 180.56,97.28 180.56,96.91 180.3,96.65 179.36,96.65 176.82,99.2 176.82,99.69 176.47,100.04 175.58,100.04 175.35,100.27 174.74,100.27 174.5,100.51 167.52,100.51 166.96,101.07 166.02,101.07 165.89,101.21 v2(165.86,101.21) 165.86,101.24 v1(165.17,101.92)
  BOTTOM w0.127: v1(181.23,104.7) 181.23,104.6 R7629.2 182.5,103.86 R7313.1 ; v1(155.64,102.06) 155.78,101.92 v1(165.17,101.92)
SYS_PEX_RST_MON_GPU#: length 11.7
  TOP w0.127: v1(180.78,107.2) 179.16,108.82 178.21,108.82 177.36,109.67 176.01,109.67 v2(175.71,109.97) 175.36,110.33 175.36,111.01 175.76,111.41 v1(175.76,111.65)
  BOTTOM w0.127: R7629.1 181.96,105.42 R7643.1 181.17,106.21 181.17,106.74 181.04,106.87 181.04,106.94 v1(180.78,107.2) ; v1(175.76,111.65) 175.38,111.27 GPU1.E9
SYS_PWROK: length 100.9
  TOP w0.127: v1(165.21,30.16) 164.95,29.91 164.57,29.91 163.15,28.5 KBC24.84
  L3 w0.127: v1(129.56,90.47) 129.74,90.29 129.74,87.13 129.98,86.89 129.98,85.71 v1(131.06,84.62) 131.53,84.15 131.53,83.99 132.96,82.56 134.11,82.56 137.47,79.21 137.47,75.33 142.16,70.64 142.16,53.84 152.27,43.73 152.27,41.99 156.57,37.69 156.57,36.35 157.45,35.47 159.11,35.47 162.09,32.49 163.21,32.49 164.17,31.53 164.78,31.53 165.21,31.1 v1(165.21,30.16)
  L4 w0.127: v1(120.08,78.97) 120.08,79.47 120.56,79.95 120.98,79.95 122.13,81.09 122.53,81.09 122.7,81.26 123.7,81.26 124.79,82.35 126.29,82.35 127.31,83.38 129.1,83.38 130.35,84.62 v1(131.06,84.62)
  BOTTOM w0.089: CPU1.AG2 118.39,79 118.68,78.71 119.12,78.71 119.22,78.61 119.72,78.61 v1(120.08,78.97)
  BOTTOM w0.127: v1(165.21,30.16) 165.21,30.16 v2(165.84,30.16) ; R9605.1 131.21,92.32 R1717.1 EC1702.1 129.68,90.58 v1(129.56,90.47)
T_CRIT#: length 4
  TOP w0.102: THM26.4 115.11,109.18 114.95,109.02 v2(114.02,109.02) 114.01,109.02 113.97,109.06 113.32,109.06 R2601.1 R2604.2
TD_IREF: length 4.3
  BOTTOM w0.102: CPU1.B12 111.25,93.25 111.25,93.45 111.17,93.53 111.17,94.21 111.37,94.41 111.37,96.43 111.88,96.94 R603.2
TESTMODE: length 8.2
  BOTTOM w0.102: R7302.1 153.81,114.4 v2(154,114.59) 155.37,114.59 157.58,112.37 157.58,111.92 157.8,111.7 159.12,111.7 GPU1.AD9
THERM_SYS_SHDN#: length 141
  TOP w0.102: v1(112.57,108.62) 112.23,108.96 R2601.2 ; v1(157.3,21.3) 157.67,21.66 Q2602.S 156.89,22.06 156.59,21.76 156.59,20.57 156.4,20.39 155.14,20.39 154.27,21.26 153.15,21.26 152.44,21.97 151.35,21.97 149.86,23.46 149.86,27.83 149.29,28.4 149.29,35.1 149.6,35.42 149.6,40.43 146.23,43.81 146.23,53.04 v2(146.23,53.04) 146.23,55.01 146.19,55.05 146.19,55.78 v1(146.56,56.15)
  L3 w0.102: v1(166.98,21.01) 166.51,21.48 161.66,21.48 161.36,21.77 157.78,21.77 v1(157.3,21.3)
  L4 w0.102: v1(146.56,56.15) 146.56,58.55 144.92,60.19 144.92,60.74 144.03,61.63 144.03,94.03 143.36,94.7 143.36,98.92 143.08,99.2 143.08,100.05 141.42,101.7 141.42,103.92 138.19,107.15 124.62,107.15 123.15,108.62 v1(112.57,108.62)
  BOTTOM w0.102: v1(166.98,21.01) 167.5,21.01 169.23,22.74 R2602.1
THM_SML1_CLK: length 93.5
  TOP w0.14: Q2601.4 124.79,56.25 124.44,56.25 124.21,56.48 124.21,59.38 v2(124.51,59.68) 125.65,60.82 RN2602.4 125.65,62.26 C2608.1 126.29,63.14 v1(126.39,63.14) ; v1(123.65,110.34) 123.54,110.23 122.2,110.23 121.3,111.13 THM26.8
  L3 w0.127: v1(137.6,89.48) 137.73,89.35 143.92,89.35 144.3,88.97 145.17,88.97 v1(145.28,89.09)
  L4 w0.127: v1(126.39,63.14) 126.48,63.14 126.89,63.55 128,63.55 128.08,63.62 132.48,63.62 133.55,64.69 133.55,67.38 135.05,68.88 135.05,82.87 135.74,83.56 135.74,87.82 137.4,89.48 v1(137.6,89.48) ; v1(145.28,89.09) 145.03,89.09 144.9,89.22 144.9,94.39 144.23,95.06 144.23,99.28 143.95,99.56 143.95,100.41 142.3,102.06 142.3,104.29 138.56,108.03 124.98,108.03 124.18,108.83 124.18,109.84 123.68,110.34 v1(123.65,110.34)
THM_SML1_DATA: length 89.9
  TOP w0.14: THM26.7 121.21,110.48 121.98,109.71 123.59,109.71 v1(123.67,109.63) ; Q2601.1 126.55,57.85 127.35,58.65 v2(127.35,59.07) 127.35,59.5 126.3,60.56 RN2602.3 126.3,61.21 126.27,61.25 126.27,61.72 126.55,62 C2609.1 126.55,62.56 126.97,62.98 127.05,62.98 v1(127.1,63.04)
  L3 w0.127: v1(137.6,88.79) 137.65,88.84 143.71,88.84 144.09,88.46 145.19,88.46 v1(145.28,88.38)
  L4 w0.127: v1(127.1,63.04) 128.21,63.04 128.29,63.11 132.69,63.11 134.06,64.48 134.06,67.17 135.56,68.67 135.56,82.66 136.25,83.35 136.25,87.61 137.44,88.79 v1(137.6,88.79) ; v1(145.28,88.38) 145.02,88.38 144.39,89 144.39,94.18 143.72,94.85 143.72,99.07 143.44,99.35 143.44,100.2 141.79,101.85 141.79,104.08 138.35,107.52 124.77,107.52 123.67,108.62 v1(123.67,109.63)
TOUCH_PANEL_INTR#: length 281.9
  TOP w0.127: v1(61.95,11.5) 61.95,9.05 69.67,1.33 82.69,1.33 82.71,1.31 90.02,1.31 90.41,1.7 162.86,1.7 164.35,3.19 v1(164.35,3.33) ; v1(185.29,23.94) 185.75,24.41 185.75,24.69 D2401.A 185.28,25.16 184.09,25.16 R2443.1
  L3 w0.127: v1(185.29,23.94) 185.29,25.65 185.46,25.82 185.46,26.22 185.06,26.61 179.69,26.61 179.27,27.03 175.74,27.03 v1(175.72,27.01) ; v1(61.95,11.5) 57.86,11.5 50.52,18.84 50.52,19.4 43.23,26.69 42.84,26.69 38.7,26.69 37.84,27.56 37.84,34.91 36.61,36.14 35.46,36.14 35.05,35.73 30.29,35.73 29.04,36.97 29.04,42.04 v1(31.79,44.79)
  L4 w0.127: v1(31.79,44.79) 33.11,46.11 33.11,47.25 36.23,50.37 36.23,59 35.18,60.05 35.18,60.62 34.06,61.74 34.06,70.86 35.11,71.91 38.16,71.91 39.01,71.05 40.64,71.05 41.35,71.76 41.35,72.87 v1(41.21,73) ; v1(164.35,3.33) 164.59,3.09 176.27,3.09 178.36,5.18 178.36,5.19 182.95,9.79 182.95,13.57 183.76,14.38 183.76,15.82 183.26,16.33 183.26,18 185.29,20.03 v1(185.29,23.94)
  BOTTOM w0.127: v1(41.21,73) 41.58,73.37 42.44,73.37 43.2,72.61 43.2,72.6 43.51,72.29 44.9,72.29 45.21,72.59 45.21,73.06 45.94,73.78 v2(46.3,73.78) 47,74.48 47,80.93 46.1,81.83 R5205.2 ; v1(175.72,27.01) 175.54,27.19 175.14,27.19 174.95,27.37 174,27.37 R2411.1
TOUCH_PANEL_INTR_KBC#: length 4.5
  TOP w0.127: v1(174.14,24.11) 174.14,24 174.57,23.58 174.57,23 174.49,22.93 KBC24.124
  BOTTOM w0.127: R2411.2 173.81,25.06 v2(174.1,24.76) 174.14,24.72 v1(174.14,24.11)
TP_CL_CLK: length 5.5
  BOTTOM w0.14: CPU1.AF2 118.35,79.75 118.69,80.1 120.14,80.1 120.14,80.09 120.46,80.09 120.59,79.97 120.98,79.97 121.49,80.48 121.73,80.48 122.12,80.1 122.12,79.13 TP1801.1
TP_CL_DATA: length 6.8
  BOTTOM w0.089: 119.41,80.71 119.19,80.71 119.11,80.78 118.53,80.78 CPU1.AD2
  BOTTOM w0.14: TP1802.1 123.23,78.68 122.77,79.14 122.77,79.14 122.56,79.36 122.56,80.3 121.91,80.95 120.65,80.95 120.41,80.71 119.41,80.71
TP_CL_RST#: length 7.6
  BOTTOM w0.089: CPU1.AF4 117.27,79.38 117.85,79.38 117.94,79.29 119.12,79.29 119.32,79.49 119.66,79.49 119.74,79.4
  BOTTOM w0.14: 119.74,79.4 120.26,79.4 120.65,79.01 121.08,79.01 121.93,78.16 122.43,78.16 122.78,77.81 122.99,77.81 TP1803.1
TP_DC_TEST_A4: length 5.3
  BOTTOM w0.102: CPU1.A4 117,93.8 118.01,94.82 118.85,94.82 120.03,95.99 TP2202.1
TP_DC_TEST_A60: length 5.6
  BOTTOM w0.102: TP2203.1 78.72,96.46 79.59,96.46 82.17,93.89 CPU1.A60
TP_DC_TEST_A62: length 2
  TOP w0.102: TP2205.1 80.21,94.69 v1(80.29,94.77)
  BOTTOM w0.102: v1(80.29,94.77) 80.86,94.2 CPU1.A62
TP_DC_TEST_AV1: length 4.5
  BOTTOM w0.102: TP2206.1 121.66,69.73 119,72.4 CPU1.AV1
TP_DC_TEST_AW1: length 6
  BOTTOM w0.102: TP2207.1 122.81,68.78 122.66,68.93 121.26,68.93 120.86,69.33 120.84,69.33 119.63,70.54 119.63,70.93 CPU1.AW1
TP_DC_TEST_AW63: length 4.3
  BOTTOM w0.102: TP2208.1 78.07,69.46 CPU1.AW63
TP_DC_TEST_AY60: length 6.1
  BOTTOM w0.102: CPU1.AY60 81.85,70.79 81.84,70.79 79.2,68.14 79.2,68.02 78.12,66.95 TP2201.1
TP_DC_TEST_B2: length 5.2
  BOTTOM w0.102: CPU1.B2 118.69,93.21 TP2204.1
TP_HDA_DOCK_EN#: length 5.3
  BOTTOM w0.089: CPU1.AW10 113.56,71.45 113.56,70.83
  BOTTOM w0.102: 113.56,70.83 113.84,70.55 113.84,69.14 114.89,68.09 114.89,67.08 TP1902.1
TP_LID_CLOSE#: length 126.2
  TOP w0.127: v1(178.89,34.23) 178.99,34.33 R2450.1 ; D2402.A 185.49,27.88 v1(184.99,28.39) ; R6215.1 129.14,99.74 129.14,97.17 AFTP6242.1 129.25,96.78 v1(129.89,96.13) 130.9,95.12 TPAD1.3
  L3 w0.127: v1(178.89,34.23) 179.61,33.51 184.73,33.51 185.43,32.81 185.43,28.83 v1(184.99,28.39)
  L4 w0.127: v1(129.89,96.13) 130.07,95.95 130.73,95.95 131.24,96.46 133.12,96.46 133.31,96.65 135.64,96.65 135.84,96.45 135.84,94.43 136.36,93.91 136.36,93.05 137.49,91.91 137.49,90.84 138.04,90.28 138.04,88.44 136.91,87.31 136.91,74.81 137.39,74.34 137.39,71.84 136.91,71.37 136.91,69.09 135.07,67.25 135.07,64.99 137.74,62.32 137.74,57.28 139.73,55.29 139.73,52.87 148.08,44.52 161.1,44.52 163.58,42.04 167.31,42.04 168.22,41.13 168.22,40.81 169.04,40 170.95,40 172.54,38.41 176.59,38.41 177.08,38.9 178.38,38.9 178.89,38.4 v1(178.89,34.23)
TP_LID_CLOSE#_KBC: length 3.1
  TOP w0.127: KBC24.26 v2(179.44,33.7) 179.6,33.7 179.85,33.44 R2450.2
TP_M_A_DIMA_ODT0: length 1.2
  TOP w0.102: TP501.1 99.57,75.19 v1(99.64,75.19)
  BOTTOM w0.102: v1(99.64,75.19) 99.98,74.85 CPU1.AP32
TP_ON#: length 83.4
  TOP w0.127: KBC24.33 176.09,38.8 176.35,39.06 v1(176.35,39.82) 176.71,40.17 v2(176.71,40.3)
  L4 w0.127: v1(176.35,39.82) 176.26,39.73 175.24,39.73 174.88,40.09 171.26,40.09 171.09,40.25 169.4,40.25 168.52,41.13 168.52,41.2 167.42,42.3 163.69,42.3 161.21,44.77 148.19,44.77 139.98,52.98 139.98,55.4 137.99,57.39 137.99,67.93 v1(137.76,68.16)
  BOTTOM w0.127: v1(137.76,68.16) 138.57,68.97 139.83,68.97 141.03,70.17 141.03,82.38 139.39,84.02 139.39,85.48 R6214.1 ; R2452.1 175.97,38.69 176.35,39.07 v1(176.35,39.82)
TP_ON#_GATE: length 6.5
  BOTTOM w0.127: Q6203.G 138.92,91.17 139.29,90.8 139.29,88.25 C6204.1 139.84,86.94 R6214.2 139.91,86.86 140.69,86.86 v2(140.82,86.73)
TP_RESET: length 15.1
  TOP w0.102: v1(28.09,84.67) 28.45,84.3 LCD1.38 28.45,83.05 28.11,82.7 27.67,82.7 AFTP5214.1
  BOTTOM w0.102: v1(28.09,84.67) 28.42,85 29.1,85 29.55,84.55 29.55,84.22 29.94,83.83 31.28,83.83 32.18,82.93 32.18,82.46 33.87,80.77 34.92,80.77 35.09,80.93 R5212.1 35.7,80.94 C5214.1
TP_RS: length 15.4
  TOP w0.102: AFTP5209.1 28.5,82.58 28.95,83.03 LCD1.37 v1(28.95,84.53)
  BOTTOM w0.102: R5205.1 38.12,80.94 C5208.1 37.26,80.95 36.65,80.34 33.9,80.34 31.97,82.26 31.97,82.84 31.19,83.62 29.85,83.62 v1(28.95,84.53)
TP_V1.05S_APLLOPI: length 4.9
  TOP w0.102: TP2105.1 111.56,82.17 110.99,81.6 109.94,81.6 v1(109.85,81.7)
  BOTTOM w0.102: CPU1.AC20 107.71,81.29 108.2,81.77 109.22,81.77 109.3,81.7 v1(109.85,81.7)
TP_V1.05S_AXCK_DCB: length 2.3
  TOP w0.102: TP2104.1 107.25,88.02 v1(106.86,87.62)
  BOTTOM w0.102: v1(106.86,87.62) 106.86,87.55 106.86,87.55 106.86,86.96 107.06,86.76 107.65,86.76 CPU1.M20
TP_V1.05S_SSCF100: length 2.1
  TOP w0.102: TP2103.1 108.9,87.52 108.9,87.09 v1(108.91,87.08)
  BOTTOM w0.102: v1(108.91,87.08) 108.91,87.1 109.15,87.34 CPU1.K18
TP_V1.05S_SSCFF: length 3.9
  TOP w0.102: TP2101.1 107.89,85.14 108.74,85.14 v1(108.94,84.93)
  BOTTOM w0.102: v1(108.94,84.93) 108.94,84.7 108.49,84.25 108.19,84.25 107.79,83.85 CPU1.V21
TP_VCCAPLLOPI_VAL: length 3.8
  TOP w0.102: TP2102.1 110.15,84.55 109.4,83.81 109.4,83.37 109.18,83.14 v1(109.18,82.85)
  BOTTOM w0.102: v1(109.18,82.85) 108.93,82.85 108.71,82.63 CPU1.Y20
TP_VCCIO_OUT: length 3.4
  BOTTOM w0.102: TP701.1 82.88,95.06 82.99,94.95 CPU1.A59
TP_VDD: length 49
  TOP w0.254: R6203.2 129.68,99.32 R6215.2 130.7,99.93 130.97,99.93 132.87,98.04 135.33,98.04 v1(135.66,97.71) 135.68,97.73 136.32,97.73 137.22,96.83 R6211.1
  TOP w0.305: 135.9,95.06 TPAD1.8
  TOP w0.381: 135.9,95.06 136.27,95.43 136.71,95.43 137.22,95.95 R6211.1 137.59,95.66 137.59,93.77 136.85,93.03 v1(136.85,91.91) 136.22,91.28 136.22,87.95 136.89,87.28 136.89,82.15 AFTP6239.1 136.45,80.61 136.88,80.18 136.88,73.58 136.06,72.75 134.46,72.75
  L3 w0.381: v1(139.82,91.76) 138.4,91.76 138.24,91.91 v1(136.85,91.91)
  BOTTOM w0.305: v1(135.66,97.71) 135.84,97.71 136.46,98.33 RN6204.2 136.96,99.06 137.13,99.23 137.13,99.53 136.96,99.71 RN6204.1
  BOTTOM w0.381: R6209.1 139.84,89.98 Q6203.D 139.9,91.69 v1(139.82,91.76)
TPAN_VDD: length 13.4
  TOP w0.305: LCD1.40 27.45,84.27 27.03,84.69 v1(26.65,84.69)
  TOP w0.508: F5203.2 29.74,74.24 R5232.1 29.74,79.72 v2(29.44,80.02) v1(28.89,80.57)
  L3 w0.508: v1(26.65,84.69) 27.81,83.52 27.81,82.08 28.89,81 v1(28.89,80.57)
TPAN_VDD_F:
  vias: v2(32.46,76.95)
TPCLK: length 61
  TOP w0.14: RN6202.1 134.22,76.91 134.28,76.84 134.28,76.29 EC6201.1 134.02,76.03 134.02,75.29 133.95,75.23 RN6201.4 133.95,74.37 134.3,74.03 136.02,74.03 v1(136.1,73.94) ; KBC24.72 160.33,33.3 158.78,34.85 157.32,34.85 156.17,35.99 154.81,35.99 ; v1(151.4,40.75) 151.44,40.72 151.44,38.55 153.99,35.99 154.81,35.99 ; 154.81,35.99 v2(154.81,35.83)
  L3 w0.127: v1(151.4,40.75) 151.4,41.37 150.95,41.83 150.95,43.79 141.27,53.47 141.27,69.88 137.48,73.67 136.38,73.67 v1(136.1,73.94)
TPCLK_C: length 19
  TOP w0.14: TPAD1.1 128.9,94.13 129.68,93.35 129.68,92.77 131.04,91.4 131.04,89.4 132.38,88.06 132.38,86.55 133.25,85.68 133.25,81.97 AFTP6238.1 133.74,79.51 134.13,79.51 134.28,79.36 134.28,79.16 134.22,79.1 RN6202.4
TPDATA: length 60.3
  TOP w0.14: v2(152.14,39.57) 151.96,39.57 ; 151.96,39.57 151.96,38.76 154.21,36.52 156.39,36.52 157.54,35.37 159,35.37 160.66,33.7 KBC24.71 ; 151.96,39.57 151.96,40.19 v1(152.09,40.33) ; v1(136.13,74.59) 136.09,74.55 134.72,74.55 RN6201.3 134.6,75.23 134.54,75.29 134.54,75.66 EC6202.1 134.8,76.27 134.8,76.84 134.87,76.91 RN6202.2
  L3 w0.127: v1(152.09,40.33) 152.09,41.41 151.46,42.04 151.46,44 141.78,53.68 141.78,70.09 137.69,74.18 136.59,74.18 136.31,74.45 136.27,74.45 v1(136.13,74.59)
TPDATA_C: length 18.4
  TOP w0.14: RN6202.3 134.87,79.12 134.8,79.18 134.8,79.57 134.34,80.03 133.95,80.03 133.68,80.31 133.68,80.51 AFTP6236.1 133.77,81.42 133.77,85.9 132.9,86.77 132.9,88.27 131.57,89.61 131.57,91.62 130.2,92.98 130.2,93.56 129.9,93.86 TPAD1.2
USB3_PRX_CTX_N0: length 126.2
  L4 w0.114: v1(33.03,24.74) 32.85,24.93 32.4,24.93 32.11,25.21 32.11,26.37 33.15,27.41 33.15,35.74 35.64,38.23 35.64,41.72 40.24,46.32 41.02,46.32 53.71,59.01 53.71,69.08 58.51,73.88 58.51,74.68 64.54,80.72 67.53,80.72 71.84,85.02 72.78,85.02 73.17,85.41 82.62,85.41 83.55,86.35 84.16,86.35 87.42,89.61 87.42,89.84 90.87,93.29 104.88,93.29 106.46,91.7 106.46,89.98 106.6,89.84 v1(107.21,89.84)
  BOTTOM w0.127: v1(33.03,24.74) 32.85,24.92 29.94,24.92 ; 29.94,24.92 28.67,24.92 R3411.2 ; 29.94,24.92 v2(29.94,24.79) ; v1(107.21,89.84) 107.25,89.8 CPU1.G20
USB3_PRX_CTX_N0_C: length 16.9
  BOTTOM w0.127: USB1.5 13.19,21.7 13.47,21.98 13.94,21.98 14.93,22.96 15.21,22.96 16.98,24.73 18.37,24.73 18.51,24.6 U3402.1 U3402.10 20.6,24.6 20.72,24.71 22.69,24.71 23.15,25.17 25.8,25.17 ; 25.8,25.17 v2(25.8,25.05) ; 25.8,25.17 26.62,25.17 26.87,24.92 27.5,24.92 27.64,24.79 R3411.1
USB3_PRX_CTX_P0: length 126.2
  L4 w0.114: v1(33.03,25.57) 33.03,25.31 32.88,25.16 32.49,25.16 32.34,25.31 32.34,26.28 33.38,27.31 33.38,35.65 35.87,38.14 35.87,41.63 40.33,46.09 41.11,46.09 53.94,58.92 53.94,68.98 58.74,73.78 58.74,74.59 64.64,80.49 67.63,80.49 71.93,84.79 72.87,84.79 73.27,85.18 82.71,85.18 83.65,86.12 84.25,86.12 87.65,89.52 87.65,89.74 90.97,93.06 104.78,93.06 106.24,91.6 106.24,89.88 106.51,89.61 106.81,89.61 107.2,89.23 v1(107.2,89.2)
  BOTTOM w0.127: v1(107.2,89.2) 107.66,89.2 CPU1.H20 ; v1(33.03,25.57) 33.03,25.5 32.69,25.16 31.12,25.16 ; R3410.2 28.61,25.57 29.11,25.57 29.52,25.16 31.12,25.16 ; 31.12,25.16 v2(31.12,25.29)
USB3_PRX_CTX_P0_C: length 16.9
  BOTTOM w0.127: R3410.1 27.58,25.65 27.5,25.57 26.79,25.57 26.63,25.41 24.38,25.41 ; USB1.6 13.19,22.35 13.32,22.22 13.84,22.22 14.83,23.21 15.11,23.21 16.88,24.97 18.41,24.97 18.51,25.07 U3402.2 U3402.9 20.6,25.07 20.72,24.96 22.59,24.96 23.05,25.41 24.38,25.41 ; v2(24.38,25.54) 24.38,25.41
USB3_PTX_CRX_N0: length 115.5
  L4 w0.114: v1(99.26,94.3) 99.04,94.52 97.92,94.52 97.62,94.23 93.43,94.23 92.99,94.67 91.27,94.67 89.27,92.67 86.92,92.67 86.73,92.48 86.73,89.74 85.1,88.1 83.93,88.1 82.77,86.95 77.3,86.95 76.44,86.08 72.14,86.08 67.42,81.37 64.27,81.37 57.98,75.07 57.98,74.18 53.19,69.39 53.19,59.23 40.82,46.86 40.03,46.86 35.12,41.94 35.12,38.49 34.59,37.97 33.77,37.97 33.54,37.74 v1(33.54,37.66)
  BOTTOM w0.102: CPU1.C33 99.17,92.62 98.87,92.91 98.87,93.91 v1(99.26,94.3)
  BOTTOM w0.127: 31.01,29.76 31.01,32.69 32.95,34.63 32.95,37.88 33.07,37.99 33.39,37.99 33.54,37.84 v1(33.54,37.66) ; 31.01,29.76 v2(31.16,29.76) ; 31.01,29.76 31.01,28.43 30.41,27.83 29.58,27.83 C3403.1
USB3_PTX_CRX_N0_C: length 14.5
  BOTTOM w0.127: R3409.1 23.71,27.93 22.9,27.93 C3402.1 22.25,27.94 21.82,27.94 21.38,27.5 21.38,26.76 ; 21.38,26.76 v2(21.51,26.76) ; 21.38,26.76 21.38,26.52 21.11,26.26 20.68,26.26 20.54,26.12 U3402.7 U3402.4 18.51,26.12 18.39,26.23 18.16,26.23 17.14,27.26 14.45,27.26 13.73,27.98 13.32,27.98 13.19,27.85 USB1.8
USB3_PTX_CRX_N0_R: length 3.7
  BOTTOM w0.127: C3403.2 28.01,27.8 27.42,27.8 ; 27.42,27.8 26.07,27.8 25.92,27.66 25.2,27.66 25.05,27.51 R3409.2 ; 27.42,27.8 v2(27.42,27.67)
USB3_PTX_CRX_P0: length 115.6
  L4 w0.114: v1(99.26,94.94) 99.08,94.75 97.83,94.75 97.53,94.45 93.53,94.45 93.09,94.89 91.17,94.89 89.17,92.89 86.82,92.89 86.5,92.57 86.5,89.83 85,88.33 83.83,88.33 82.68,87.18 77.21,87.18 76.34,86.31 72.05,86.31 67.33,81.6 64.18,81.6 57.75,75.17 57.75,74.27 52.96,69.48 52.96,59.32 40.72,47.09 39.94,47.09 34.89,42.04 34.89,38.59 34.49,38.19 33.81,38.19 v1(33.54,38.46)
  BOTTOM w0.102: v1(99.26,94.94) 98.67,94.35 98.67,92.81 CPU1.B34
  BOTTOM w0.127: C3404.1 29.51,28.07 30.31,28.07 30.77,28.53 30.77,32.18 ; v1(33.54,38.46) 33.31,38.23 32.97,38.23 32.71,37.98 32.71,34.73 30.77,32.79 30.77,32.18 ; 30.77,32.18 v2(30.61,32.18)
USB3_PTX_CRX_P0_C: length 14.4
  BOTTOM w0.127: R3408.1 23.85,28.17 22.91,28.17 C3401.1 22.25,28.18 21.72,28.18 21.45,27.91 ; 21.45,27.91 v2(21.36,28) ; 21.45,27.91 21.14,27.6 21.14,26.63 21.01,26.5 20.7,26.5 20.6,26.6 U3402.6 U3402.5 18.51,26.6 18.39,26.48 18.26,26.48 17.24,27.5 14.55,27.5 13.83,28.22 13.32,28.22 13.19,28.35 USB1.9
USB3_PTX_CRX_P0_R: length 3.7
  BOTTOM w0.127: 26.3,28.04 28.01,28.04 C3404.2 ; 26.3,28.04 v2(26.3,28.17) ; 26.3,28.04 26.04,28.04 25.77,28.31 25.2,28.31 25.05,28.45 R3408.2
USB20_VCCA: length 5.1
  TOP w0.635: 13.1,46.6 USB2.1 12.27,45.31
  BOTTOM w0.508: U3401.5 16.69,40.87 v1(16.43,41.13)
  BOTTOM w0.635: 12.27,45.48 USB2.1 13.13,46.6
  vias: v3(14.71,46.16) v3(14.68,45.14) v3(24.42,33.2) v3(24.46,32.34) v3(24.46,31.46) v3(39.79,33.81) v3(39.76,32.68) v3(40.41,33.23)
USB20_VCCB:
  vias: v2(166.67,7.08) v2(184.63,8.2) v3(183.81,7.08) v3(185.01,7.14) v3(186.18,7.13)
USB30_VCCC: length 8.9
  TOP w0.508: v1(23.65,24.43) 23.31,24.43 22.93,24.05 U3403.5
  TOP w0.635: USB1.1 15.4,28.6 ; USB1.1 14.69,29.31 ; USB1.1 14.69,27.89
  L3 w0.508: v1(23.65,24.43) 24.66,25.44 v3(24.66,29.41)
  vias: v3(24.66,30.24) v3(36.21,35.33) v3(36.21,34.48)
USB_CAMERA: length 12.5
  TOP w0.127: v1(26.68,88.78) 26.68,88.61 26.39,88.31 24.53,88.31 24.14,87.92 24.14,86.92 23.2,85.98 21.79,85.98 AFTP5226.1 21.54,85.98 20.35,85.98 20.14,86.19 20.14,87.34 20.5,87.7 CCD1.7
  BOTTOM w0.127: v1(26.68,88.78) 26.85,88.61 27.18,88.61 27.74,89.18 TR5208.2
USB_CAMERA#: length 12.5
  TOP w0.127: CCD1.6 19.7,87.55 19.9,87.36 19.9,86.36 AFTP5225.1 20.25,85.74 23.3,85.74 24.38,86.82 24.38,87.82 24.63,88.07 26.58,88.07 v1(26.68,87.97)
  BOTTOM w0.127: TR5208.3 27.65,88.23 27.51,88.37 27.08,88.37 v1(26.68,87.97)
USB_CAMERA_EDP: length 9
  TOP w0.127: 33.86,79.24 v2(33.77,79.15) ; 33.86,79.24 34.52,78.59 35.28,78.59 35.99,77.88 35.99,77.72 35.66,77.39 TR5209.2 ; 33.86,79.24 32.98,80.12 32.98,81.39 32.12,82.26 32.12,82.79 31.95,82.95 LCD1.31
USB_CAMERA_EDP#: length 8.9
  TOP w0.127: LCD1.30 32.45,82.96 32.36,82.87 32.36,82.36 33.23,81.49 33.23,80.22 34.62,78.83 35.02,78.83 ; v2(35.02,78.95) 35.02,78.83 ; 35.02,78.83 35.38,78.83 36.23,77.98 36.23,77.8 36.61,77.42 TR5209.3
USB_COMP: length 3.1
  TOP w0.305: v1(112.83,77.91) 112.73,77.91 112.16,78.48 R1602.1 111.32,78.6 v2(111.21,78.71)
  BOTTOM w0.254: CPU1.AJ10 113.24,77.59 113.15,77.59 112.83,77.91 v1(112.83,77.91) 112.82,77.89 112.52,77.59 112.43,77.59 CPU1.AJ11
USB_OC#0_1: length 266.8
  TOP w0.102: U3502.8 27.81,28.68 27.97,28.84 27.97,32.35 27.83,32.49 U3502.5 26.48,33.01 26.77,33.3 v1(27.35,33.3) ; v1(39.15,37.74) 39.8,37.74 40.51,37.02 U3503.3 39.62,36.58 39.18,37.02 34.52,37.02 33.64,36.14 33.64,35.26 U3504.3 32.54,35.16 32.24,35.46 32.24,36.47 v1(31.13,37.58)
  L3 w0.102: v1(143.14,4.25) 147.61,8.73 147.61,20.42 144.84,23.2 144.84,29.65 144.84,32.25 144.07,33.02 144.07,35.3 141.36,38.01 141.36,39.37 138.64,42.09 136.55,42.09 135.84,42.8 135.84,47.22 132.22,50.85 132.22,56.72 135.22,59.73 135.22,60.03 135.22,60.03 135.22,65.23 133.74,66.71 133.74,66.83 131.03,69.55 131.03,70.35 v1(131.41,70.73)
  L4 w0.102: v1(143.14,4.25) 138.55,4.25 137.44,5.35 132.87,5.35 131.99,4.47 129.63,4.47 129.59,4.44 129.49,4.44 128.68,3.62 110.96,3.62 109.84,4.74 105.9,4.74 105.53,4.38 78.32,4.38 70.58,12.12 66.06,12.12 63.86,14.32 50.87,14.32 37.76,27.44 37.76,35.61 39.15,37 v1(39.15,37.74) ; v1(131.48,80.99) 132.67,79.81 132.67,71.64 131.75,70.73 v1(131.41,70.73)
  BOTTOM w0.089: 119.84,76.6 119.25,76.6 119.12,76.47 117.84,76.47 CPU1.AL3
  BOTTOM w0.102: v1(27.35,33.3) 27.9,33.3 v2(31.15,36.55) 31.42,36.82 31.42,37.29 v1(31.13,37.58) ; RN1809.7 131.51,80.96 v1(131.48,80.99) 131.16,80.67 127,80.67 125.9,79.56 125.9,78.31 126.15,78.05 126.15,76.72 125.56,76.13 122.89,76.13 122.45,75.68 121.4,75.68 121.39,75.69 121.01,75.69 120.11,76.6 119.84,76.6
USB_OC#2_3: length 149.2
  TOP w0.102: v1(121.02,70.97) 121.02,71.02 120.97,71.07 120.97,72.09 v1(120.77,72.28)
  L3 w0.102: v1(121.02,70.97) 121.02,70.38 119.79,69.15 119.79,64.07 119.86,64.01 119.86,61.68 122.45,59.09 122.45,57.07 122.48,57.04 122.48,56.68 122.45,56.65 122.45,52.72 122.45,52.26 118,47.81 118,42.83 116.26,41.1 116.26,21.29 110.98,16.01 110.98,12.62 111.59,12.01 113.82,12.01 115.75,10.08 v1(115.85,10.08) ; v1(156.43,11.11) 156.43,10.41 154.73,8.71 154.73,8.37 152.36,6 148.57,6 v1(146.72,4.15)
  L4 w0.102: v1(115.85,10.08) 116.09,10.32 119.21,10.32 121,12.11 137.64,12.11 138.93,10.82 141.07,10.82 141.56,11.31 146.77,11.31 147.26,11.8 149.07,11.8 150.01,10.87 156.19,10.87 v1(156.43,11.11)
  BOTTOM w0.102: U3505.3 147.65,3.22 v1(146.72,4.15) ; v1(156.43,11.11) 157.58,9.97 157.58,8.45 157.58,8.45 U3501.5 ; CPU1.AT1 119.22,73.72 119.41,73.53 119.73,73.53 120.48,72.78 120.48,72.57 v1(120.77,72.28) ; RN1601.8 131.84,69.87 131.64,69.66 131.54,69.66 130.73,68.85 129.84,68.85 v2(129.77,68.79) 129.47,68.48 127.81,68.48 127.8,68.47 127.33,68 125.84,68 124.66,69.18 123.86,69.18 123.7,69.34 123.14,69.34 121.51,70.97 v1(121.02,70.97)
USB_OC#4_5: length 25.6
  TOP w0.102: v1(127.12,70.63) 126.94,70.63 126.11,69.8 126.09,69.8 126.08,69.79 123.48,69.79 121.79,71.48 121.79,73.86 121.99,74.07 121.99,74.59 123.06,75.66 123.06,76.9 v1(123.09,76.93)
  L4 w0.102: v1(127.12,70.63) 127.56,71.06 129.75,71.06 131.01,72.32 131.01,72.7 v1(131.52,73.2)
  BOTTOM w0.089: CPU1.AH2 118.53,78.54 119.04,78.54 119.15,78.43 120.08,78.43 120.09,78.44 120.4,78.44 120.56,78.59 v2(120.78,78.59)
  BOTTOM w0.102: v2(120.78,78.59) 121.13,78.59 121.98,77.74 122.21,77.74 122.68,77.26 122.75,77.26 v1(123.09,76.93) ; v1(131.52,73.2) 131.95,72.77 131.95,72.17 132.08,72.04 RN2012.7
USB_OC#6_7: length 17.6
  BOTTOM w0.089: CPU1.AV3 117.65,72.41 117.97,72.08 118.62,72.08 118.63,72.07 119.06,72.07 119.82,71.31 119.82,70.62
  BOTTOM w0.102: 119.82,70.62 120.92,69.52 120.96,69.52 121.34,69.14 123.61,69.14 123.77,68.97 124.58,68.97 125.81,67.74 127.36,67.74 127.9,68.28 130.67,68.28 v2(131.06,68.67) 131.6,69.22 RN1601.7
USB_PN0: length 139.5
  TOP w0.127: 34.7,39.56 35.34,39.56 36.36,38.55 37.5,38.55 37.79,38.83 v1(37.79,39.05) ; 34.7,39.56 v2(34.7,39.71) ; 34.7,39.56 31.73,39.56 28.99,36.83 28.99,26.45 28.55,26.01 27.07,26.01 26.72,26.36 TR3404.4
  L3 w0.114: v1(114.2,74.99) 114.2,75.15 114.42,75.37 114.63,75.37 114.79,75.2 114.79,73.39 114.15,72.74 114.15,72.3 113.4,71.56 111.14,71.56 110.35,72.34 105.52,72.34 103.83,74.03 103.83,74.83 101.36,77.29 100.3,77.29 98.67,78.92 98.67,79.31 97.61,80.37 85.44,80.37 84.74,79.67 83.81,79.67 83.46,80.02 81.42,80.02 80.08,81.35 78.08,81.35 77.71,80.98 71.91,80.98 70.4,79.48 63.44,79.48 61.13,77.16 61.13,63.2 47.06,49.13 47.06,45.06 40.53,38.52 38.07,38.52 37.79,38.81 v1(37.79,39.05)
  BOTTOM w0.127: CPU1.AN8 114.52,75.31 v1(114.2,74.99)
USB_PN0_C: length 13.5
  TOP w0.127: 17.68,24.45 17.95,24.45 18.5,25 U3403.1 20.59,25 20.7,24.89 20.7,24.38 20.85,24.23 20.98,24.23 21.36,24.6 21.36,25.32 22,25.96 23.8,25.96 24.19,26.36 TR3404.3 ; 17.68,24.45 17.7,24.47 AFTP6211.1 ; 17.68,24.45 16.9,24.45 16.13,25.22 15.57,25.22 USB1.2
USB_PN1: length 132.4
  L3 w0.114: v1(43.34,38.7) 43.14,38.5 42.91,38.5 42.8,38.61 42.8,39.25 48.14,44.59 48.14,48.81 63.13,63.8 63.13,76.89 64.73,78.49 70.87,78.49 72.37,79.99 78.12,79.99 78.37,79.73 79.61,79.73 80.66,78.68 89.65,78.68 90.33,79.36 93.57,79.36 94.92,78.01 98.13,78.01 102.05,74.09 102.05,73.42 104.4,71.08 110.03,71.08 110.53,70.58 114.71,70.58 116.01,71.88 116.01,74.21 v1(115.55,74.67)
  BOTTOM w0.127: v1(43.34,38.7) 43.19,38.55 40.31,38.55 36.56,42.3 28.58,42.3 ; TR3401.1 24.08,41.35 24.44,40.99 26.62,40.99 27.93,42.3 28.58,42.3 ; CPU1.AR7 115.48,74.67 v1(115.55,74.67) ; 28.58,42.3 v2(28.58,42.43)
USB_PN1_R: length 16.5
  TOP w0.127: USB2.2 13.15,43.22 13.81,43.22 14.7,42.33 15.25,42.33 15.38,42.45 AFTP6204.1
  BOTTOM w0.127: TR3401.2 21.86,41.35 21.15,40.64 20.91,40.64 20.75,40.8 20.75,41.6 20.52,41.83 U3401.1 18.74,41.83 17.34,43.22 13.15,43.22 USB2.2
USB_PN2: length 103.6
  TOP w0.127: 172.79,12.13 173.71,12.13 174.05,11.79 TR6301.4 ; 172.79,12.13 v2(172.79,12.01) ; 172.79,12.13 170.4,12.13 169.79,12.74 169.79,13.27 v1(169.54,13.52)
  L4 w0.114: v1(169.54,13.52) 169.81,13.8 169.81,15.65 166.76,18.7 165.55,18.7 163.74,20.51 163.74,32.09 162.34,33.49 162.34,37.97 156.85,43.46 148.07,43.46 138.81,52.72 138.81,55.13 136.91,57.04 136.91,57.23 136.91,58.94 133.49,62.36 128.6,62.36 128.38,62.13 121.98,62.13 120.86,63.25 120.86,66 115.73,71.13 115.73,72.84 114.71,73.86 114.47,73.86 v1(114.22,73.61)
  BOTTOM w0.127: CPU1.AR8 114.22,73.64 v1(114.22,73.61)
USB_PN2_IOBD1: length 6.2
  TOP w0.127: TR6301.3 177.12,11.79 177.47,12.14 179.55,12.14 ; CON1.8 181.3,12.15 180.92,12.53 180.51,12.53 180.12,12.14 179.55,12.14 ; 179.55,12.14 v2(179.55,12.01)
USB_PN3: length 1.6
  TOP w0.127: TP1601.1 113.2,73.88 113.2,74.24 v1(113.63,74.67)
  BOTTOM w0.127: CPU1.AR10 113.3,74.34 v1(113.63,74.67)
USB_PN4: length 89
  TOP w0.127: RN5206.4 36.65,70.63 36.46,70.44 36.46,70.11 v1(36.73,69.84)
  L4 w0.114: v1(110.26,76.36) 110.2,76.36 109.76,76.79 108.39,76.79 108,77.18 106.36,77.18 105.36,78.18 105.36,79.14 105.06,79.45 103.31,79.45 103.02,79.74 89.02,79.74 88.59,79.32 83.84,79.32 83.37,79.79 73.95,79.79 72.15,77.99 67.83,77.99 63.27,73.43 60.49,73.43 60.38,73.32 60.38,73.1 v1(60.51,72.97)
  BOTTOM w0.127: RN5205.3 36.68,70.53 36.47,70.32 36.47,70.09 v1(36.73,69.84) 36.45,69.57 36.45,69.36 36.65,69.16 36.88,69.16 38.35,70.64 38.64,70.64 ; v2(38.64,70.76) 38.64,70.64 ; 38.64,70.64 60.42,70.64 61.65,71.87 61.65,73.1 61.31,73.44 60.45,73.44 60.36,73.36 60.36,73.11 v1(60.51,72.97) ; CPU1.AM15 110.36,76.36 v1(110.26,76.36)
USB_PN4_CAM#: length 25.5
  L3 w0.114: v1(35.57,74.25) 35.32,74 33.1,74 32.26,74.83 32.26,83.66 31.89,84.03 31.89,87.66 32.75,88.52 33.22,88.52 33.39,88.35 v1(33.39,88.13)
  BOTTOM w0.127: RN5205.2 36.68,72.61 36.5,72.79 36.5,73.65 36.14,74 35.82,74 v1(35.57,74.25) ; 32.55,88.6 30.92,88.6 30.55,88.23 TR5208.4 ; 32.55,88.6 32.93,88.6 v1(33.39,88.13) ; 32.55,88.6 v2(32.55,88.47)
USB_PN4_EDP: length 3.3
  TOP w0.127: 36.45,73.58 v2(36.58,73.58) ; 36.45,73.58 36.45,72.92 36.65,72.71 RN5206.1 ; 36.45,73.58 36.27,73.76 36.27,74.41 36.61,74.74 TR5209.4
USB_PN5: length 106.1
  L4 w0.114: v1(111.78,76.66) 111.01,76.66 110.78,76.43 110.78,76.03 110.65,75.9 110.65,73.88 109.92,73.15 109.92,71.82 112.47,69.27 113.67,69.27 118.99,63.95 118.99,62.51 121.33,60.16 128.56,60.16 129.23,60.83 132.12,60.83 135.28,57.67 135.28,56.25 137.32,54.22 137.32,51.52 144.04,44.79 144.53,44.79 147.48,41.85 155.42,41.85 160.84,36.43 160.84,32.67 161.7,31.81 161.7,19.28 164.45,16.53 165.99,16.53 166.32,16.2 166.32,15.97 v1(166.14,15.79)
  BOTTOM w0.127: v2(167.69,16.72) 167.69,16.59 ; 167.69,16.59 166.73,16.59 166.39,16.25 166.39,16.04 v1(166.14,15.79) ; 167.69,16.59 170.05,16.59 170.4,16.95 171.4,16.95 R5802.2 ; v1(111.78,76.66) 111.69,76.66 CPU1.AM13
USB_PN5_R: length 15.5
  BOTTOM w0.127: WLAN1.36 179.66,25.3 179.43,25.07 178.86,25.07 178.31,24.53 178.31,23.04 177.42,22.14 177.42,18.35 175.65,16.58 174.47,16.58 ; 174.47,16.58 v2(174.47,16.73) ; 174.47,16.58 173.84,16.58 173.47,16.95 172.47,16.95 R5802.1
USB_PN6: length 105.4
  TOP w0.127: 39.48,69.76 58.99,69.76 61.09,71.87 61.09,75.34 61.39,75.65 61.83,75.65 v1(62.02,75.83) ; 39.48,69.76 v2(39.48,69.89) ; 39.48,69.76 38.3,69.76 37.03,68.49 35.77,68.49 34.9,69.36 34.9,76.33 33.36,77.86 32.01,77.86 31.89,77.98 31.89,78.25 32.21,78.56 32.21,79.39 R5203.2
  L4 w0.114: v1(112.28,74.99) 112.58,75.29 112.68,75.29 113.21,75.83 113.21,76.93 113.47,77.18 113.47,77.76 113.48,77.78 113.48,78.98 113.21,79.26 106.73,79.26 106.11,79.88 106.11,80.46 105.65,80.92 80.58,80.92 79.95,81.54 78.2,81.54 77.5,80.84 72.99,80.84 72.83,80.69 71.67,80.69 70.13,79.15 67.51,79.15 64.02,75.65 62.2,75.65 v1(62.02,75.83)
  BOTTOM w0.127: CPU1.AP11 112.61,74.66 v1(112.28,74.99)
USB_PN6_TPNL: length 4.7
  TOP w0.127: LCD1.34 30.45,83.03 30.33,82.92 30.33,82.28 30.63,81.98 31.54,81.98 31.7,81.82 ; R5203.1 32.21,80.34 32.21,80.97 31.86,81.31 31.86,81.66 31.7,81.82 ; 31.7,81.82 v2(31.79,81.91)
USB_PN7: length 108.7
  TOP w0.127: v2(171.84,14.86) 171.84,14.99 ; 171.84,14.99 168.32,14.99 167.86,14.52 167.86,14.12 167.99,13.99 168.3,13.99 168.42,13.87 v1(168.42,13.55) ; 171.84,14.99 173.52,14.99 174.05,14.45 TR6302.4
  L4 w0.114: v1(111.73,74.66) 111.42,74.36 111.42,72.05 112.18,71.29 113.07,71.29 120.34,64.02 120.34,63.04 121.77,61.61 128.59,61.61 128.79,61.81 132.52,61.81 136.29,58.04 136.29,56.63 138.29,54.62 138.29,51.93 144.45,45.77 144.94,45.77 147.77,42.93 156.63,42.93 161.82,37.75 161.82,33.15 163.22,31.75 163.22,21.67 162.79,21.24 162.79,20.46 165.54,17.71 166.79,17.71 168.54,15.96 168.54,15.19 167.84,14.5 167.84,14.11 167.93,14.03 168.4,14.03 168.49,13.95 168.49,13.61 v1(168.42,13.55)
  BOTTOM w0.127: CPU1.AR13 111.64,74.66 v1(111.73,74.66)
USB_PN7_IOBD1: length 6.3
  TOP w0.127: 179.23,14.79 177.53,14.79 177.2,14.45 TR6302.3 ; 179.23,14.79 v2(179.23,14.66) ; 179.23,14.79 179.7,14.79 180.44,15.53 180.92,15.53 181.3,15.15 CON1.11
USB_PP0: length 139.5
  TOP w0.127: 29.23,27.02 v2(29.36,27.02) ; 29.23,27.02 29.23,36.73 31.83,39.32 35.24,39.32 36.26,38.3 37.67,38.3 v1(37.78,38.2) ; 29.23,27.02 29.23,26.35 28.65,25.76 27.12,25.76 26.76,25.41 TR3404.1
  L3 w0.114: v1(114.14,75.72) 114.27,75.6 114.72,75.6 115.02,75.3 115.02,73.29 114.37,72.64 114.37,72.21 113.5,71.33 111.05,71.33 110.26,72.12 105.42,72.12 103.6,73.94 103.6,74.73 101.27,77.07 100.2,77.07 98.44,78.83 98.44,79.22 97.51,80.14 85.53,80.14 84.83,79.44 83.72,79.44 83.37,79.79 81.33,79.79 79.99,81.13 78.18,81.13 77.81,80.75 72,80.75 70.5,79.25 63.54,79.25 61.35,77.07 61.35,63.1 47.29,49.04 47.29,44.97 40.62,38.29 37.88,38.29 v1(37.78,38.2)
  BOTTOM w0.127: v1(114.14,75.72) 114.15,75.72 114.39,75.96 CPU1.AM8
USB_PP0_C: length 13.5
  TOP w0.127: 17.68,24.21 17.84,24.21 18.14,23.9 18.14,23.71 18.77,23.09 U3403.3 20.19,23.09 21.6,24.5 21.6,25.22 22.1,25.72 23.8,25.72 24.11,25.41 TR3404.2 ; 17.68,24.21 17.68,24.21 AFTP6212.1 ; 17.68,24.21 16.8,24.21 16.03,24.98 15.57,24.98 USB1.3
USB_PP1: length 132.4
  L3 w0.114: v1(115.55,74.02) 115.78,73.78 115.78,71.97 114.61,70.81 110.63,70.81 110.13,71.31 104.49,71.31 102.28,73.52 102.28,74.19 98.23,78.24 95.02,78.24 93.66,79.59 90.24,79.59 89.56,78.91 80.75,78.91 79.7,79.96 78.47,79.96 78.21,80.22 72.28,80.22 70.78,78.72 64.64,78.72 62.9,76.98 62.9,63.9 47.91,48.91 47.91,44.68 42.58,39.35 42.58,38.51 42.82,38.27 43.16,38.27 43.34,38.08 v1(43.34,37.89)
  BOTTOM w0.127: 31.13,42.06 36.46,42.06 40.21,38.3 43.07,38.3 43.34,38.03 v1(43.34,37.89) ; 31.13,42.06 28.03,42.06 26.72,40.75 24.43,40.75 24.08,40.4 TR3401.4 ; 31.13,42.06 v2(31.13,41.9) ; CPU1.AT7 115.48,74.02 v1(115.55,74.02)
USB_PP1_R: length 16.6
  TOP w0.127: AFTP6209.1 15.38,41.96 15.25,42.09 14.6,42.09 13.71,42.98 13.15,42.98 USB2.3
  BOTTOM w0.127: TR3401.3 20.89,40.4 20.41,39.92 U3401.3 19.62,39.92 18.68,40.86 18.68,41.54 17.24,42.98 13.15,42.98 USB2.3
USB_PP2: length 103.7
  TOP w0.127: TR6301.1 174.05,12.73 173.7,12.37 171.21,12.37 ; v1(170.33,13.52) 170.03,13.23 170.03,12.84 170.5,12.37 171.21,12.37 ; 171.21,12.37 v2(171.21,12.5)
  L4 w0.114: v1(170.33,13.52) 170.04,13.82 170.04,15.75 166.86,18.92 165.65,18.92 163.97,20.6 163.97,32.19 162.57,33.59 162.57,38.06 156.94,43.69 148.16,43.69 139.04,52.81 139.04,55.22 137.14,57.13 137.14,59.04 133.59,62.58 128.51,62.58 128.28,62.36 122.08,62.36 121.09,63.35 121.09,66.1 115.96,71.23 115.96,72.93 114.8,74.09 114.43,74.09 v1(114.18,74.35)
  BOTTOM w0.127: CPU1.AP8 114.28,74.35 114.18,74.35 v1(114.18,74.35)
USB_PP2_IOBD1: length 6.2
  TOP w0.127: CON1.9 181.3,13.15 180.92,12.77 180.41,12.77 180.02,12.38 178.09,12.38 ; v2(178.09,12.51) 178.09,12.38 ; 178.09,12.38 177.47,12.38 177.12,12.73 TR6301.2
USB_PP3: length 1.7
  TOP w0.127: TP1602.1 113.67,73.46 v1(113.67,73.95)
  BOTTOM w0.127: v1(113.67,73.95) 113.41,73.69 CPU1.AT10
USB_PP4: length 89
  TOP w0.127: RN5206.3 36,70.65 36.22,70.43 36.22,70.14 v1(35.92,69.84)
  L4 w0.114: v1(110.23,77.02) 108.49,77.02 108.09,77.41 106.45,77.41 105.59,78.28 105.59,79.24 105.15,79.68 103.4,79.68 103.11,79.97 88.92,79.97 88.5,79.54 83.93,79.54 83.46,80.02 73.86,80.02 72.05,78.22 67.73,78.22 63.18,73.66 60.73,73.66 v1(60.51,73.89)
  BOTTOM w0.127: RN5205.4 36.03,70.53 36.23,70.32 36.23,70.15 v1(35.92,69.84) 36.21,69.55 36.21,69.26 36.55,68.92 36.98,68.92 38.45,70.39 40.92,70.39 ; v2(40.92,70.27) 40.92,70.39 ; 40.92,70.39 60.52,70.39 61.89,71.77 61.89,73.2 61.41,73.68 60.71,73.68 v1(60.51,73.89) ; v1(110.23,77.02) 110.35,77.02 CPU1.AL15
USB_PP4_CAM: length 25.6
  L3 w0.114: v1(35.57,73.44) 35.25,73.77 33,73.77 32.03,74.74 32.03,83.56 31.66,83.93 31.66,87.75 32.66,88.74 33.19,88.74 v1(33.39,88.94)
  BOTTOM w0.127: 31.28,88.84 33.28,88.84 v1(33.39,88.94) ; 31.28,88.84 v2(31.28,88.96) ; 31.28,88.84 31.04,88.84 30.7,89.18 TR5208.1 ; RN5205.1 36.03,72.59 36.26,72.81 36.26,73.55 36.04,73.76 35.89,73.76 v1(35.57,73.44)
USB_PP4_EDP: length 3.2
  TOP w0.127: RN5206.2 36,72.71 36.21,72.92 36.21,73.48 36.02,73.67 36.02,74.44 35.66,74.8 TR5209.1
USB_PP5: length 106.1
  L4 w0.114: v1(111.76,76.02) 111.76,76.06 111.39,76.43 111.11,76.43 111.01,76.33 111.01,75.93 110.88,75.8 110.88,73.79 110.15,73.06 110.15,71.92 112.57,69.5 113.76,69.5 119.22,64.04 119.22,62.6 121.42,60.39 128.46,60.39 129.13,61.06 132.21,61.06 135.51,57.76 135.51,56.35 137.54,54.31 137.54,51.61 144.14,45.02 144.63,45.02 147.57,42.08 155.52,42.08 161.07,36.53 161.07,32.77 161.93,31.91 161.93,19.37 164.54,16.76 166.09,16.76 166.55,16.29 166.55,15.93 166.7,15.77 v1(167.07,15.77)
  BOTTOM w0.127: v2(169.16,16.23) 169.16,16.35 ; 169.16,16.35 170.05,16.35 170.4,16 171.46,16 R5803.2 ; 169.16,16.35 166.83,16.35 166.63,16.15 166.63,15.9 166.75,15.77 v1(167.07,15.77) ; CPU1.AN13 111.7,76.02 v1(111.76,76.02)
USB_PP5_R: length 15.5
  BOTTOM w0.127: v2(175.59,16.2) 175.59,16.34 ; 175.59,16.34 175.75,16.34 177.66,18.25 177.66,22.04 178.55,22.93 178.55,24.43 178.96,24.83 179.39,24.83 179.72,24.5 WLAN1.38 ; 175.59,16.34 173.81,16.34 173.47,16 172.41,16 R5803.1
USB_PP6: length 105.5
  TOP w0.127: v1(62.02,75.03) 62.02,75.29 61.9,75.4 61.49,75.4 61.33,75.24 61.33,71.77 59.09,69.52 42.41,69.52 ; v2(42.41,69.4) 42.41,69.52 ; 42.41,69.52 38.4,69.52 37.13,68.25 35.67,68.25 34.66,69.26 34.66,76.23 33.26,77.62 31.91,77.62 31.65,77.88 31.65,78.2 31.26,78.59 31.26,79.34 R5204.2
  L4 w0.114: v1(62.02,75.03) 62.02,75.27 62.16,75.42 64.11,75.42 67.61,78.92 70.23,78.92 71.77,80.46 72.93,80.46 73.09,80.61 77.6,80.61 78.29,81.31 79.86,81.31 80.48,80.69 105.56,80.69 105.88,80.37 105.88,79.79 106.64,79.03 113.11,79.03 113.26,78.89 113.26,77.87 113.24,77.85 113.24,77.28 112.98,77.02 112.98,75.92 112.58,75.52 112.4,75.52 v1(112.28,75.64)
  BOTTOM w0.127: v1(112.28,75.64) 112.61,75.31 CPU1.AN11
USB_PP6_TPNL: length 4.7
  TOP w0.127: v2(30.25,81.84) 30.34,81.93 ; 30.34,81.93 30.53,81.73 31.44,81.73 31.62,81.56 31.62,81.32 31.26,80.97 31.26,80.39 R5204.1 ; 30.34,81.93 30.09,82.18 30.09,82.87 29.95,83.01 LCD1.35
USB_PP7: length 108.7
  TOP w0.127: v1(167.62,13.55) 167.62,14.62 168.22,15.23 168.6,15.23 ; 168.6,15.23 173.88,15.23 174.05,15.4 TR6302.1 ; 168.6,15.23 v2(168.6,15.35)
  L4 w0.114: v1(111.73,75.32) 111.2,74.79 111.2,71.95 112.09,71.06 112.98,71.06 120.12,63.92 120.12,62.94 121.67,61.38 128.69,61.38 128.89,61.58 132.43,61.58 136.06,57.95 136.06,56.53 138.06,54.53 138.06,51.84 144.36,45.54 144.84,45.54 147.68,42.71 156.54,42.71 161.59,37.65 161.59,33.05 162.99,31.65 162.99,21.76 162.56,21.33 162.56,20.37 165.45,17.48 166.7,17.48 168.31,15.87 168.31,15.29 167.62,14.59 v1(167.62,13.55)
  BOTTOM w0.127: v1(111.73,75.32) 111.65,75.32 CPU1.AP13
USB_PP7_IOBD1: length 6.3
  TOP w0.127: v2(178.05,15.16) 178.05,15.03 ; 178.05,15.03 179.6,15.03 180.34,15.77 180.92,15.77 181.3,16.15 CON1.12 ; 178.05,15.03 177.57,15.03 177.2,15.4 TR6302.2
USB_PWR_EN#: length 193
  TOP w0.127: v1(159.64,28.41) 159.86,28.41 160.35,28.9 KBC24.83 ; v1(39.2,35.96) 38.58,36.58 U3503.4 38.22,36.16 37.26,35.2 37.26,34.49 36.6,33.83 33.71,33.83 33.54,33.67 U3504.4 32.86,32.88 32.46,33.28 32.46,33.86 v2(32.28,34.04) 31.77,34.04 31.56,33.83 U3502.4 30.44,32.49 30.16,32.21 30.16,31.37 30.31,31.22 U3502.3
  L3 w0.127: v1(155.2,8.5) 152.46,5.76 149.17,5.76 v1(147.58,4.17)
  L4 w0.127: v1(39.2,35.96) 38,34.76 38,29.15 39.41,27.74 39.41,26.42 51.06,14.77 64.04,14.77 66.25,12.56 70.77,12.56 78.51,4.82 105.35,4.82 105.82,5.29 110.31,5.29 111.45,4.16 128.58,4.16 129.31,4.88 129.41,4.88 129.54,5.01 130.4,5.01 131.19,5.8 137.92,5.8 138.41,5.31 146.44,5.31 v1(147.58,4.17) ; v1(159.64,28.41) 159.64,26.68 160.4,25.93 160.4,21.75 v1(161.07,21.08)
  BOTTOM w0.127: U3505.4 147.79,5.5 147.58,5.29 v1(147.58,4.17) ; v1(161.07,21.08) 160.66,21.08 157.13,17.56 154.39,17.56 149.27,12.44 149.27,10.06 R2412.1 151.27,8.07 151.96,8.07 152.05,8.16 U3501.4 154.34,8.16 154.66,8.47 155.18,8.47 v1(155.2,8.5)
VD1_EN#: length 4.2
  TOP w0.203: KBC24.66 160.56,35.7 160.32,35.93 v1(160.32,35.96)
  BOTTOM w0.254: v1(160.32,35.96) 160.32,36.54 v2(160.42,36.64) 161.21,36.64 161.38,36.48 R2449.2
VD_IN1: length 88.3
  TOP w0.14: v1(165.69,23.88) 165.69,23.76 166.49,22.95 KBC24.104
  L3 w0.127: v1(165.69,23.88) 165.34,24.22 161.99,24.22 160.96,25.26 159.99,26.22 158.83,26.22 156.41,28.63 156.41,29.48 155.9,30 155.11,30 154.54,30.57 154.54,32.26 v1(154.28,32.52)
  L4 w0.127: v1(109.4,63.27) 110.48,62.19 113.86,62.19 117.03,59.02 124.93,59.02 125.19,58.76 125.19,57.81 125.73,57.27 127.07,57.27 128.79,55.56 129.25,55.56 130.31,54.5 130.31,54.24 132.34,52.2 132.34,47.42 134.36,45.4 134.36,44.09 134.94,43.51 135.93,43.51 136.67,44.25 137.45,44.25 138.19,43.51 141.05,43.51 144.35,40.21 144.84,40.21 146.26,38.79 146.98,38.79 147.58,38.19 148.28,38.19 149.96,36.52 150.29,36.52 151.83,36.52 154.28,34.07 v1(154.28,32.52)
  BOTTOM w0.14: v2(165.04,22.23) 165.5,22.23 C2613.1 165.94,23.16 165.81,23.29 165.81,23.75 v1(165.69,23.88) ; R2608.2 R2609.2 108.75,61.36 C2612.1 109.4,61.52 R2610.1 v1(109.4,63.27)
VD_IN1_C: length 83.8
  L3 w0.127: v1(167.08,23.64) 166.1,24.62 162.16,24.62 160.16,26.61 158.99,26.61 156.81,28.8 156.81,29.64 155.54,30.91 155.54,31.88 154.23,33.2 v1(154.23,34.79)
  L4 w0.127: v1(154.23,34.79) 154.12,34.79 151.99,36.91 150.12,36.91 148.45,38.59 147.74,38.59 147.14,39.18 146.42,39.18 145,40.61 144.51,40.61 141.22,43.9 139.32,43.9 134.31,48.91 133.35,48.91 132.75,49.51 132.75,52.35 130.7,54.4 130.7,54.66 129.41,55.95 128.95,55.95 127.24,57.67 125.9,57.67 125.59,57.97 125.59,58.92 125.1,59.41 117.19,59.41 114.02,62.58 111.27,62.58 v1(110.5,63.36)
  BOTTOM w0.14: C2613.2 R2611.1 167.39,21.77 167.95,22.33 v2(167.95,22.69) 167.95,22.77 v1(167.08,23.64) ; v1(110.5,63.36) 110.92,62.94 R2610.2 110.92,62.16 C2612.2
VD_OUT1#: length 11.1
  TOP w0.203: KBC24.110 168.89,20.83 v1(168.96,20.77)
  BOTTOM w0.254: R2607.2 R2602.2 169.54,21.44 169.68,21.3 v2(169.68,20.94) 169.51,20.77 v1(168.96,20.77) 168.96,20.71 168.48,20.24 167.87,20.24 167.67,20.43 166.44,20.43 166.22,20.21 164.27,20.21 163.9,20.57 163.9,21.59 R2612.2
VGA_CORE: length 25.1
  TOP w0.508: v1(173.82,102.85) 172.98,102.85 C7719.1 ; PR8317.1 149.86,96.44 150.47,95.83 152.58,95.83 153.34,95.06 v1(153.49,95.06) 153.68,95.06 153.69,95.05 155.12,95.05 155.7,95.62 v2(157.45,95.62) 161.37,95.62
  BOTTOM w0.508: v1(153.49,95.06) 153.31,95.06 152.83,94.59 152.83,92.16 152.02,91.34 152.02,90.29 153.18,89.13 153.18,85.29 PR8212.1
  vias: v1(164.41,117.85) v1(164.41,115.94) v1(164.41,113.91) v1(164.41,111.88) v1(164.4,110.98) v1(166.32,117.85) v1(166.32,115.94) v1(166.32,113.91) v1(166.32,111.88) v1(168.35,117.85) v1(168.35,115.94) v1(168.35,113.91) v1(168.35,112.01) v1(169.36,118.99) v1(170.38,117.85) v1(170.38,115.94) v1(170.38,113.91) v1(170.38,111.88) v1(171.27,110.74) v3(163.52,103.19) v3(164.41,103.19) v3(164.87,95.57) v3(165.3,103.19) v3(166.88,95.55) v3(169.47,95.57) v3(171.7,94.78) v3(172.79,95.57) v3(172.97,93.46) v3(174.09,94.68) v3(174.28,91.48) v3(174.28,73.98) v3(174.44,72.2) v3(174.62,93.21) v3(174.95,70.55) v3(175.25,89.25) v3(175.59,84.14) v3(175.59,82.49) v3(175.59,80.84) v3(175.59,79.19) v3(175.59,77.54) v3(175.59,75.89) v3(175.87,90.87) v3(175.99,94.02) v3(176.32,92.52) v3(176.6,89.25) v3(177.11,84.14) v3(177.11,82.49) v3(177.11,80.84) v3(177.11,79.19) v3(177.11,77.54) v3(177.11,75.89) v3(177.26,90.87) v3(177.39,94.02) v3(177.72,92.52) v3(177.87,89.25) v3(178.53,90.87) v3(178.51,84.14) v3(178.51,82.49) v3(178.51,80.84) v3(178.51,79.19) v3(178.51,77.54) v3(178.51,75.89) v3(178.66,94.02) v3(178.99,92.52) v3(180.08,93.82) v3(181.03,94.51) v3(181.91,93.76) v3(183.13,94.53)
VGA_CORE_DISCHG: length 3.2
  TOP w0.102: PR8317.2 149.48,97.33 v2(149.88,97.73) 149.88,98.92 149.66,99.14 PQ8307.D
VGA_CORE_PSI: length 66.5
  L3 w0.127: v1(149.96,73.86) 149.53,73.86 148.04,75.34 148.04,82.09 151.94,85.99 151.94,89.44 156.3,93.8 v1(156.3,99.24)
  BOTTOM w0.127: v1(156.3,99.24) 156.66,99.24 156.67,99.24 157.31,99.24 157.62,98.92 174.26,98.92 174.92,98.26 175.3,98.26 175.67,97.89 179,97.89 179.38,98.26 180.68,98.26 181.01,98.59 181.01,99.72 v2(181,99.74) 181,99.96 180.59,100.37 180.59,101.92 180.63,101.95 180.63,102.38 179.11,103.9 179.11,105.47 178.71,105.87 178.43,105.87 178.13,106.17 178.13,106.45 177.75,106.83 GPU1.B4 ; PR8257.1 150.38,73.86 v1(149.96,73.86)
VGA_CORE_VID: length 82.8
  TOP w0.14: v1(174.94,109.18) 174.97,109.21 177.07,109.21 178.14,108.14 178.14,107.18 v1(179.3,106.01)
  L3 w0.127: v1(152.35,95.14) 152.22,95.01 152.22,93.01 149.93,90.73 149.93,89.35 145.29,84.71 145.29,75.7 148.59,72.41 v1(150.8,72.41)
  BOTTOM w0.14: PR8207.1 149.36,74.13 149.36,73.24 150.19,72.41 v1(150.8,72.41) ; v1(152.35,95.14) 151.61,95.88 151.31,95.88 151,96.18 151,96.7 153.04,98.74 155.98,98.74 156.06,98.66 157.05,98.66 157.37,98.34 174.02,98.34 174.68,97.68 175.06,97.68 175.44,97.3 179.23,97.3 179.62,97.68 180.92,97.68 181.25,98.02 v2(181.25,98.04) 181.27,98.04 181.59,98.35 181.59,100.18 181.18,100.6 181.18,101.9 180.9,102.18 180.9,102.38 180.9,102.44 179.4,103.94 179.4,105.91 v1(179.3,106.01) ; GPU1.E7 175.35,109.59 v1(174.94,109.18)
VGACORE_GND_SENSE_1: length 41.7
  BOTTOM w0.14: PR8220.2 151.75,87.29 151.75,88.8 150.6,89.95 150.6,95.11 149.91,95.79 149.91,99.57 151.7,101.36 152.14,101.36 ; 152.14,101.36 166.72,101.36 168.8,103.43 172.45,103.43 173.08,104.06 174.76,104.06 174.94,104.24 174.94,104.74 174.86,104.82 174.58,104.82 GPU1.F1 ; 152.14,101.36 v2(152.14,101.54)
VGACORE_VDD_SENSE_1: length 42.3
  BOTTOM w0.14: 153.77,100.97 v2(153.77,100.78) ; 153.77,100.97 166.89,100.97 168.96,103.04 172.62,103.04 173.25,103.67 174.92,103.67 175.33,104.08 175.33,104.9 175.02,105.21 174.73,105.21 GPU1.F2 ; 153.77,100.97 151.86,100.97 150.31,99.41 150.31,95.96 150.99,95.28 150.99,90.11 152.14,88.96 152.14,87.2 PR8221.2
VIDEO_CLK_XTAL_SS: length 2.9
  TOP w0.14: v2(180.27,112.24) 180.15,112.24 179.67,111.76 v1(179.67,111.73) 179.64,111.73 179.35,111.44 R7601.1
  BOTTOM w0.14: v1(179.67,111.73) 179.67,111.86 179.46,112.07 GPU1.A10
VIDEO_THERM_OVERT#: length 1.8
  BOTTOM w0.127: Q7602.6 184.33,104.92 183.74,105.5 TP7606.1
VR_SVID_ALERT#: length 119.9
  TOP w0.14: v1(87.27,124.56) 87.43,124.4 89.17,124.4 93.44,128.68 v2(96.39,128.68) 99.35,128.68 99.95,128.08 105.24,128.08 105.87,128.71 119.92,128.71 122.32,126.3 122.32,123.96 123.74,122.54 123.74,115.61 121.11,112.98 118.57,112.98 117.36,114.19 PR4618.2
  BOTTOM w0.14: v1(87.27,124.56) 87.27,123.86 84.5,121.09 83.65,121.09 82.89,120.33 82.89,119.48 82.75,119.34 82.75,115.97 62.36,95.59 62.36,88.31 64.91,85.76 71.23,85.76 72.1,84.89 73.73,84.89 74.18,85.35 R703.2 74.19,85.57 R701.1
VRAM_PWR_BS: length 2.8
  TOP w0.508: v2(157.5,61.18) 157.91,60.77 v1(157.93,60.77) 158.29,60.42 PR5102.1
  BOTTOM w0.254: v1(157.93,60.77) 158.23,60.47 PU5102.6
VRAM_PWR_BS_R: length 3.1
  TOP w0.508: PC5110.1 160.7,58.49 160.42,58.21 v2(160.17,58.21) 159.89,58.21 159.61,58.49 PR5102.2
VRAM_PWR_BYP: length 3.4
  BOTTOM w0.254: PU5102.7 158.16,59.79 157.3,60.65
  BOTTOM w0.508: 157.3,60.65 156.99,60.96 v2(156.61,60.96) 155.84,60.96 155.76,61.03 PR5112.2
VRAM_PWR_FB: length 5.4
  BOTTOM w0.254: PR5103.1 159.36,61.19 PU5102.4
  BOTTOM w0.508: v2(155.43,62.92) 155.68,62.92 156.36,62.24 PR5113.2 PC5111.2 PR5103.1
VRAM_PWR_FBH: length 24.8
  BOTTOM w0.254: PG5104.1 176.17,61.49 176.17,64.4 175.73,64.85 172.17,64.85 171.23,63.92 v2(170.36,63.92) 156.79,63.92 156.54,63.66 PR5113.1 PC5111.1
VRAM_PWR_LDO: length 6.3
  BOTTOM w0.254: 158.32,61.41 158.69,61.03 158.91,60.82 PU5102.5
  BOTTOM w0.508: v2(153.38,61.85) 154.51,61.85 PC5112.1 155.83,61.86 156.1,61.59 158.13,61.59 158.32,61.41
VRAM_PWR_PH: length 2.2
  TOP w0.508: PC5110.2 v1(162.02,58.21) 162.02,57.95 v2(162.56,57.42)
VTT_CT_3VC_1: length 3
  TOP w0.203: 152.85,120.18 152.57,120.46 U8301.10
  TOP w0.254: v2(154.87,120.03) 154.86,120.03 C8305.1 153.01,120.03 152.85,120.18
VTT_CT_105VC_2: length 3
  TOP w0.203: U8301.12 152.8,121.26 152.98,121.45
  TOP w0.254: 152.98,121.45 153.29,121.76 C8316.1 154.86,121.76 v2(154.86,121.76)
WHITE_LED_BAT: length 11.2
  TOP w0.102: R6101.2 178.79,17.66 EC6103.1 178.32,17.21 175.84,17.21 175.08,17.98 174.14,17.98 173.3,17.14 v2(173.3,15.82) 172.54,15.82 171.87,16.48 Q6103.C
WIFI_RF_EN: length 19.9
  TOP w0.102: v1(166.14,30.72) 165.82,31.04 165.47,31.04 164.79,30.36 164.02,30.36 162.96,29.3 KBC24.82
  BOTTOM w0.102: WLAN1.20 178.71,31.7 177.92,30.9 v2(169.11,30.9) 166.32,30.9 v1(166.14,30.72)
WLAN_ACT: length 8.1
  TOP w0.14: v1(186.8,42.06) 186.13,41.39 C5807.1
  BOTTOM w0.14: TP5801.1 191.45,42.58 190.56,41.7 WLAN1.3 187.16,41.7 v1(186.8,42.06)
WLAN_PLT_RST#: length 20.3
  TOP w0.102: v1(116.46,73.89) 116.7,73.89 v2(116.99,73.6)
  L4 w0.102: v1(131.46,71.42) 131.39,71.42 130.55,70.58 128.78,70.58 127.51,69.31 127.24,69.31 127.24,69.31 120.79,69.31 117,73.1 117,73.35 v1(116.46,73.89)
  BOTTOM w0.102: v1(131.46,71.42) 131.99,70.89 RN2012.5 ; CPU1.AT5 116.25,73.69 v1(116.46,73.89)
XCLK_BIASREF: length 5
  BOTTOM w0.102: CPU1.C26 103.62,92.3 103.3,92.62 103.3,92.87 103.45,93.02 103.45,93.39
  BOTTOM w0.305: R1803.1 103.45,96.78 103.45,95.59 v2(103.47,95.58) 103.47,94.58 103.38,94.49 103.38,94.07 103.47,93.97 103.47,93.42 103.45,93.39
XDP_BPM0: length 5.1
  TOP w0.14: v1(78.27,88.92) 78.27,89.45 TP9612.1
  BOTTOM w0.089: v1(78.27,88.92) 78.67,88.52 79.15,88.52 79.35,88.32 80.49,88.32 80.67,88.5 81.26,88.5 81.3,88.46 81.93,88.46 CPU1.J60
XDP_BPM1: length 1.2
  TOP w0.14: TP9613.1 81.86,89.19 v1(81.91,89.15)
  BOTTOM w0.114: v1(81.91,89.15) 81.91,89.26 CPU1.H60
XDP_BPM2: length 6.9
  BOTTOM w0.089: CPU1.H61 81.32,89.82 80.78,89.82 80.6,89.64 80.6,89.45 80.4,89.25 80.06,89.25 79.78,89.52 77.51,89.52 77.33,89.34 76.65,89.34 76.55,89.24
  BOTTOM w0.14: 76.55,89.24 75.96,88.65 TP9614.1
XDP_BPM3: length 4.5
  BOTTOM w0.089: CPU1.H62 80.86,89.48 80.86,89.27 80.66,89.07 79.98,89.07 79.71,89.34 78.09,89.34 77.98,89.23
  BOTTOM w0.14: 77.98,89.23 77.73,88.97 TP9615.1
XDP_BPM4: length 1.2
  TOP w0.14: TP9616.1 83.43,88.57 v1(83.26,88.4)
  BOTTOM w0.114: CPU1.K59 82.93,88.07 v1(83.26,88.4)
XDP_BPM5: length 6.5
  BOTTOM w0.089: 76.04,89.52 76.34,89.52 76.46,89.64 77.37,89.64 77.59,89.86 79.24,89.86 79.4,89.7 79.87,89.7 79.93,89.64 80.16,89.64 CPU1.H63
  BOTTOM w0.14: 76.04,89.52 75.43,89.52 74.56,88.65 TP9617.1
XDP_BPM6: length 1.3
  TOP w0.14: v1(82.55,87.67) 82.16,88.06 TP9618.1
  BOTTOM w0.114: v1(82.55,87.67) 82.54,87.67 82.22,87.99 CPU1.K60
XDP_BPM7: length 1.2
  TOP w0.14: TP9619.1 80.85,88.75 v1(81.26,89.15)
  BOTTOM w0.114: CPU1.J61 81.57,88.85 v1(81.26,89.15)
XDP_DBRESET#: length 8.3
  BOTTOM w0.089: 119.15,81 119.12,80.96 118.02,80.96 118.02,80.96 117.84,80.96 CPU1.AC3
  BOTTOM w0.14: 119.15,81 119.39,81 119.45,80.94 120.29,80.94 120.59,81.24 120.92,81.24 121.08,81.39 122.48,81.39 TP9653.1 122.67,81.2 123.16,81.2 123.51,81.55 C9602.1 123.68,80.78 EC1706.1 123.6,80.7 R1701.2
XDP_PRDY#: length 3.1
  TOP w0.14: v1(78.91,88.92) 78.91,89 TP9602.1
  BOTTOM w0.089: v1(78.91,88.92) 79,88.92 79.42,88.5 80.41,88.5 80.7,88.78 CPU1.J62
XDP_PREQ#: length 3.1
  TOP w0.14: v1(78.73,87.71) 78.73,88.19 TP9601.1
  BOTTOM w0.089: CPU1.K62 80.92,87.87 80.61,87.57 78.88,87.57 v1(78.73,87.71)
XDP_PWR_DEBUG: length 1.4
  BOTTOM w0.254: TP9647.1 72.47,88.03 R9604.2
XDP_RST: length 1.2
  BOTTOM w0.14: TP9654.1 129.58,82.91 R9602.1
